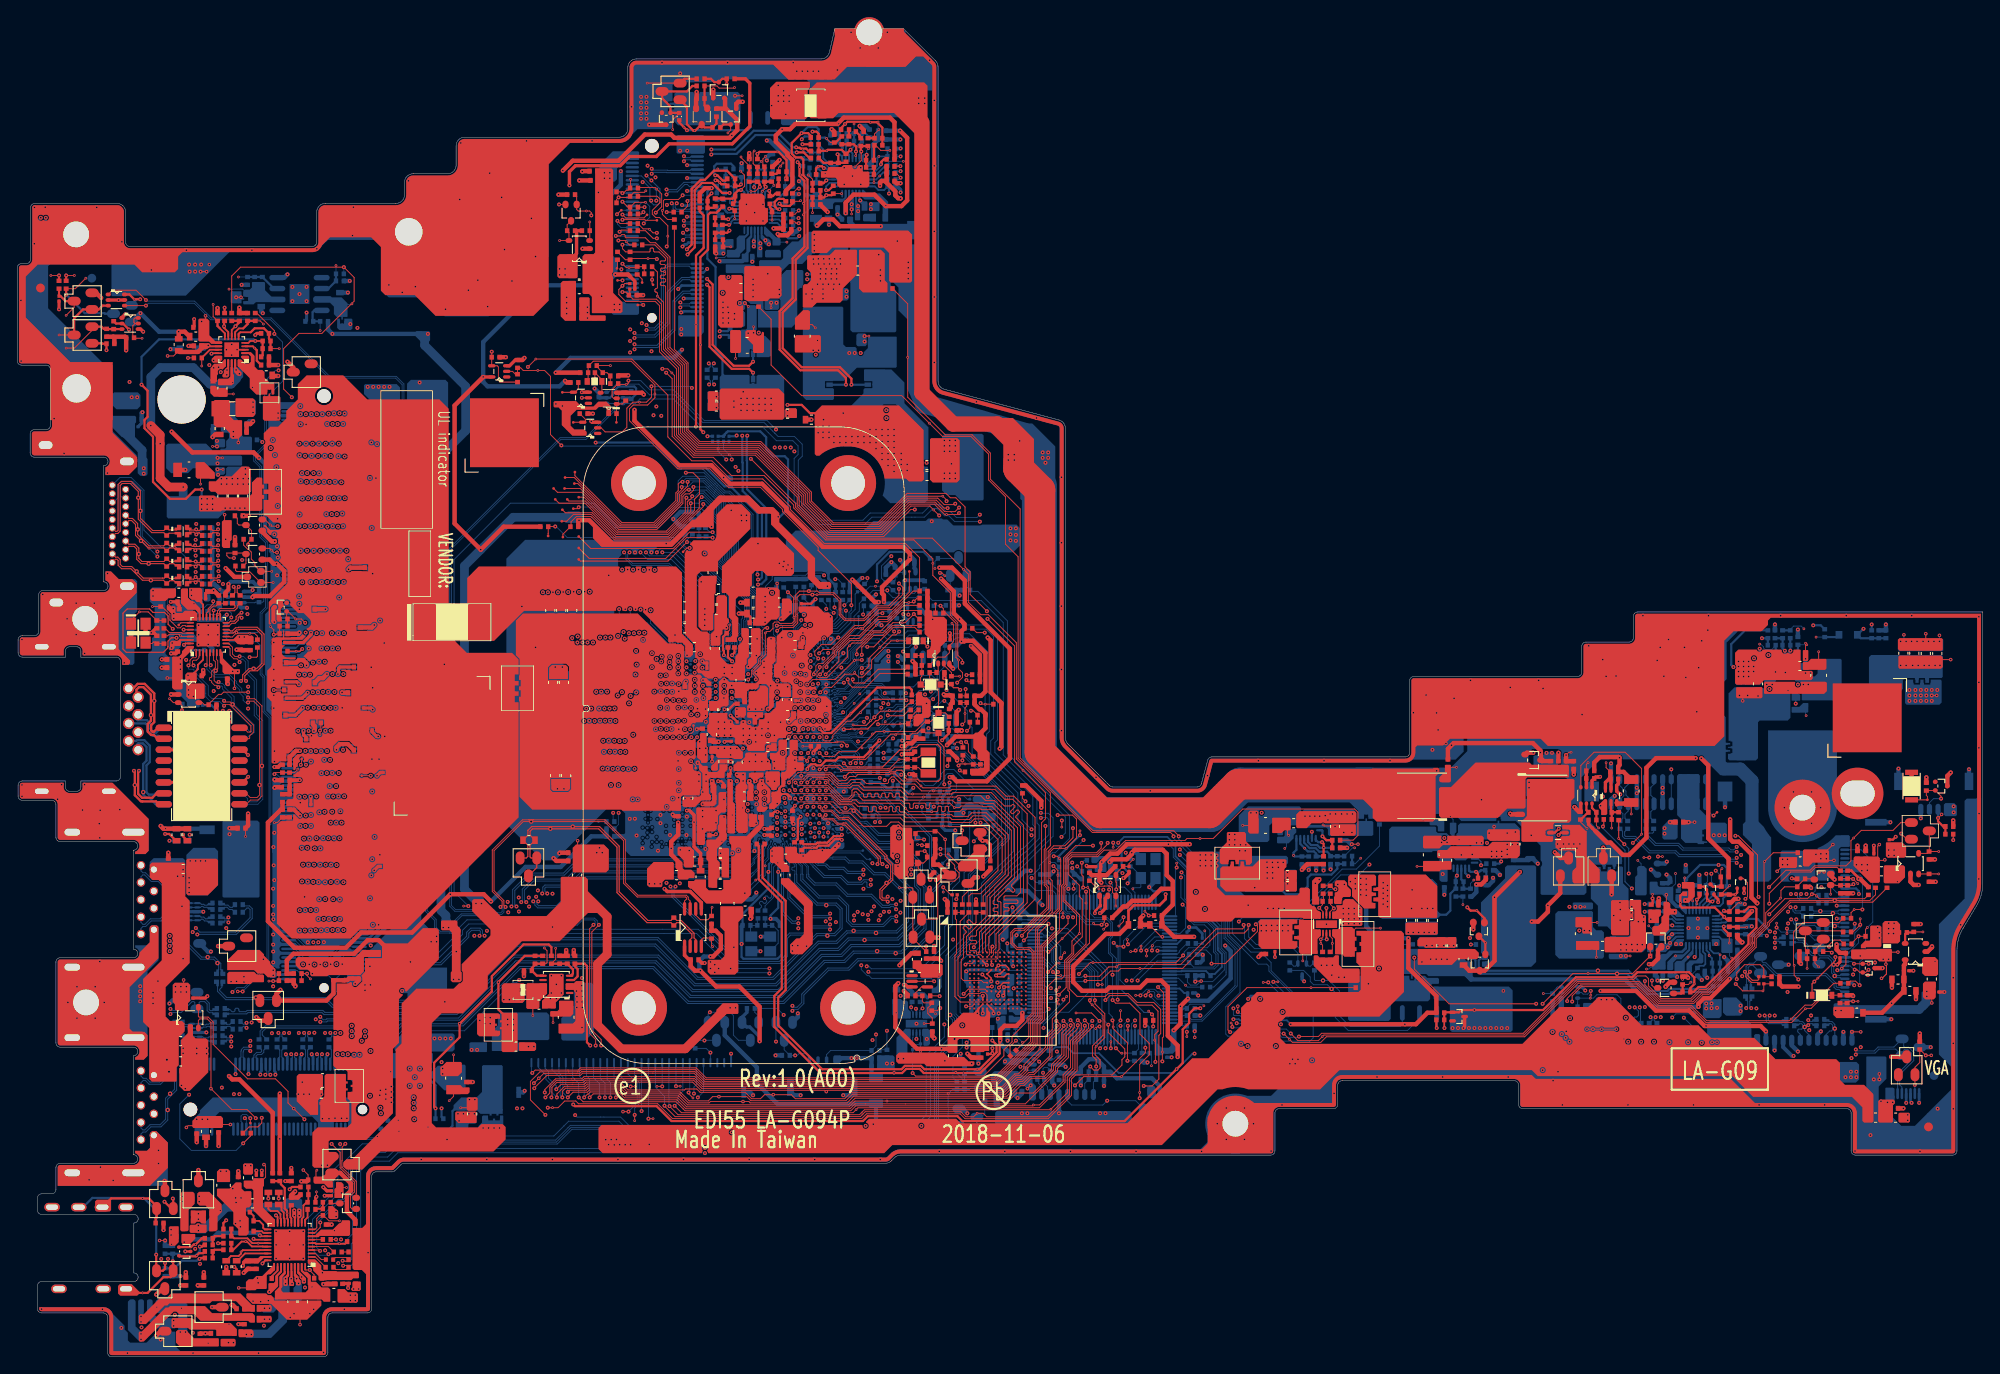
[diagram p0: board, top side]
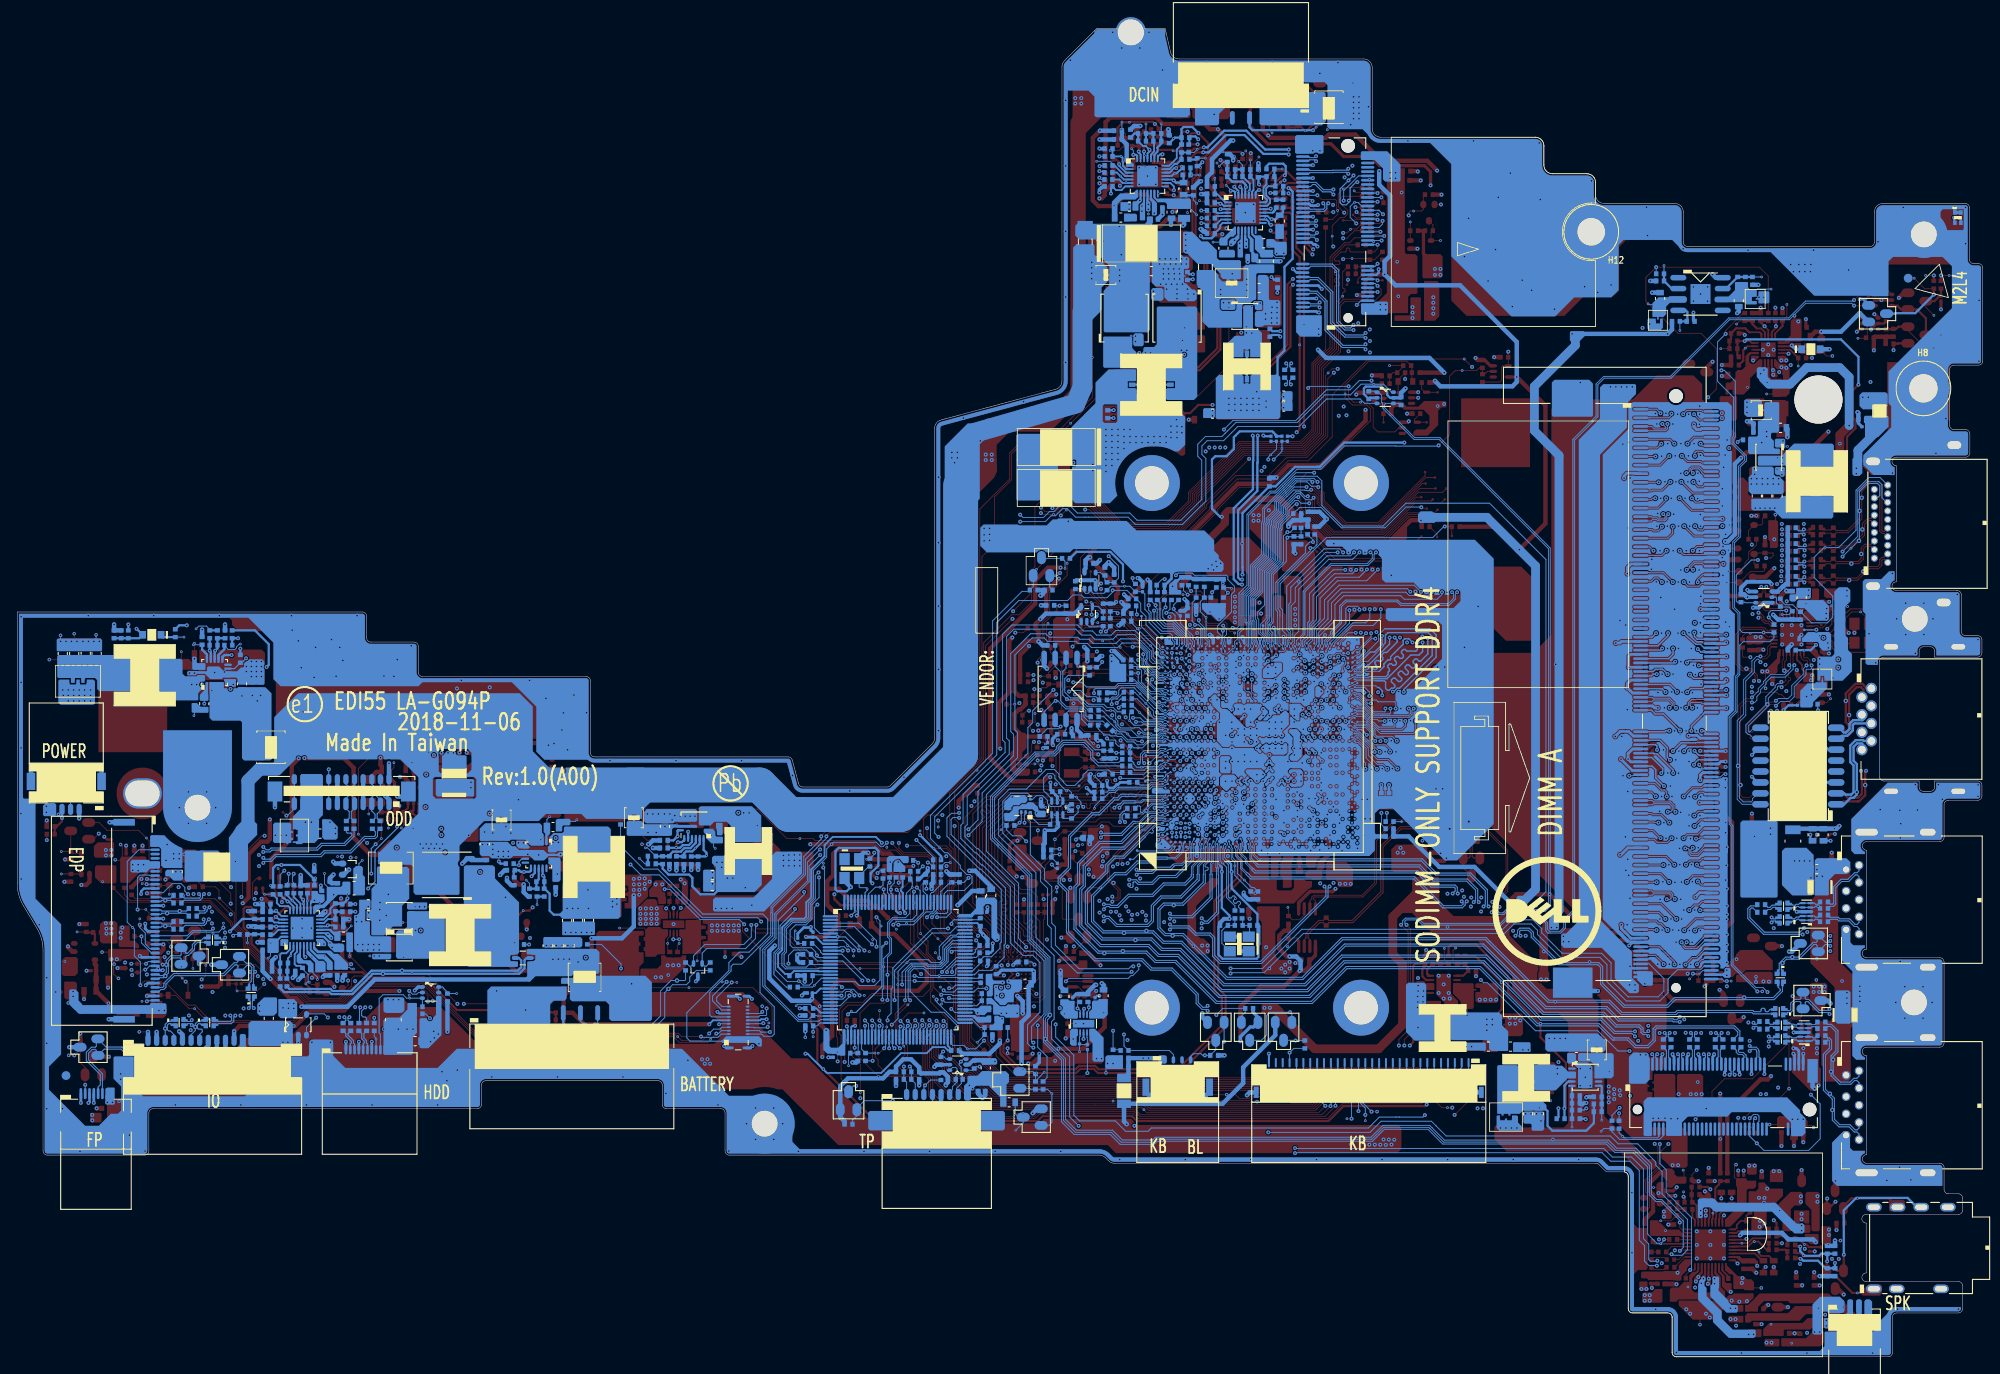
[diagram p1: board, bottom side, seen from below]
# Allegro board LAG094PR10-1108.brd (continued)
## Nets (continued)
+1.8VS: QA2.3 RA35.1 RA36.1 RA65.1
+1.24VALW: CC39.2 CC40.2 CC41.2 PJP1202.2 RC125.1 UC1.AC18 UC1.AC20
+1.24VALW_PG: PR1201.2 PU1201.4 RE8.1
+1.24VALWP: PC1201.1 PC1202.1 PC1203.1 PC1206.1 PJP1202.1 PL1201.2 PR1204.1
+2.5V_MEM: CD1.1 CD2.1 CD3.1 CD4.1 DD2.2 JDIMM1.257 JDIMM1.259 PJP2502.2
+2.5VP: PC2502.1 PC2505.1 PJP2502.1 PR2502.1 PU2501.6
+3.3V_WLAN: CW6.1 CW7.1 CW8.1 CW9.1 JWLAN1.2 JWLAN1.4 JWLAN1.72 JWLAN1.74 RW1.2 RW2.1 RW27.2 RW28.2 UW1.1
+3V_DVDD: CA44.1 CA48.1 CA483.1 CA485.1 RA8.1 RA33.2 RA40.2 UA1.1
+3V_EMMC: CM1.1 CM2.1 CM7.1 CM9.1 RM1.2 RM29.2 RM32.1 UM1.E6 UM1.F5 UM1.J10 UM1.K9 UM2.5
+3VALW: C235.1 CC5.1 CL9.1 JDB1.11 JP11.2 JPWR1.4 PJP302.2 PJP1201.1 PJP1801.1 PJP2501.1 PL1211.1 PL1811.1 PR5.2 PR33.1 PR41.2 PR1201.1 PR1803.1 PRB42.1 PRG34.2 PRH03.1 PRH05.1 PRM06.1 PRZ34.2 Q17.2 Q17.5 R35.1 RA41.2 RC55.2 RC120.2 RC122.1 RC138.2 RC165.1 RC166.1 RC167.1 RC168.1 RC169.1 RC170.1 RC175.1 RC176.1 RC213.2 RE4.2 RE30.1 RL7.1 RM1.1 RM30.1 RW1.1 RW5.1 RW6.1 U11.6 U11.7 UC3.5 UL2.5 UM3.1 UM3.2 UW1.5
+3VALW_1.8V: PC1801.1 PJP1801.2 PL1811.2 PU1801.8 PU1801.9 PU1801.10
+3VALW_1.24V: PC1204.1 PJP1201.2 PL1211.2 PU1201.8 PU1201.9 PU1201.10
+3VALW_2.5V: PC2501.1 PJP2501.2 PU2501.3
+3VALW_EC: CE10.1 CE11.1 CE12.1 CE13.1 LE1.1 PR9.1 RE1.2 RE4.1 RE12.1 RE14.2 RE25.2 RE28.2 RE32.2 RE34.2 RE36.1 RE37.1 RE41.2 RE43.1 UE1.9 UE1.22 UE1.33 UE1.96 YE1.4
+3VALW_SOC: CC81.2 CC82.2 CC83.2 CC84.2 CC85.2 CC86.1 RC43.2 RC45.2 RC46.2 RC89.2 RC90.2 RC122.2 RC142.1 RC145.1 UC1.AG21 UC1.AJ21 UC1.T18 UC1.T20 UC1.U17 UC1.V18 UC1.V20 UC1.Y18 UC1.Y20 UC5.5 UC6.5 UC7.5
+3VALWP: PC310.1 PC311.1 PC312.1 PC313.1 PC314.1 PC316.1 PJP302.1 PL301.2 PR304.1 PR306.2 PR307.1 PR504.1 PU301.14
+3VLP: CE35.2 DC1.2 PC308.1 PU301.16 PU301.17 RE40.1 RE43.2 RE53.1 RE54.2 RE55.2 U15.5
+3VS: C17.1 C21.1 C232.1 C233.1 CC4.1 CD9.1 CD10.1 CS114.1 CS115.1 CW4.1 CW5.1 CW10.1 F5.1 JDIMM1.255 JIOB1.12 JP10.2 JP33.2 Q6.2 Q10.2 Q10.5 Q11.2 Q11.5 Q57.2 Q58.2 QA2.2 QC2.2 QC2.5 QG1.5 R5.1 R7.1 R24.1 R28.1 R29.1 R33.1 R34.1 R36.1 R48.1 R49.1 R57.1 R79.1 R80.1 R86.1 R87.1 R100.1 R5216.1 R5220.1 R5221.1 RA33.1 RC2.2 RC3.2 RC4.2 RC83.1 RC84.1 RC117.1 RC119.2 RC121.2 RC203.1 RC1146.1 RC1148.1 RC1151.2 RD1.1 RD2.1 RD3.1 RE38.1 RE39.1 RG47.1 RL3.1 RM29.1 RS62.1 RT31.2 RW2.2 U1.5 U2.1 UC2.5 US2.2 US2.3 US2.9 US2.10
+3VS_CAM: C14.1 C15.1 C49.1 F5.2 JEDP1.29 R83.1
+3VS_OUT: C981.1 JP33.1 U11.8 U11.9
+3VS_SSD: CS38.1 CS39.1 CS40.1 CS41.1 CS42.1 CS43.1 CS44.1 JP10.1 JSSD1.2 JSSD1.4 JSSD1.12 JSSD1.14 JSSD1.16 JSSD1.18 JSSD1.70 JSSD1.72 JSSD1.74
+5V_AVDD: CA45.1 CA49.1 CA475.1 CA481.1 RA34.2 UA1.20
+5V_HDD: CS12.1 CS13.1 CS14.1 JHDD1.10 JHDD1.11 JHDD1.12 RB9.2 RS32.2 RS63.1
+5V_HDMI: CG46.1 CG47.1 DI1.1 FI1.1 JHDMI1.18
+5V_KB_BL: C34.1 EC3002.1 F3.1 JKBBL1.1
+5V_PVDD: CA2.1 CA3.1 CA43.1 CA47.1 CA474.1 CA494.1 RA1.2 UA1.34 UA1.39
+5VALW: C234.1 CU21.1 CU31.1 PCG01.1 PCZ14.1 PD2.3 PD3.3 PJP502.2 PR4.1 PR2504.1 PRG33.2 PRH11.1 PRM04.1 PRM05.2 PRZ33.2 PUG1.12 PUZ1.12 Q19.3 Q5029.3 U11.1 U11.2 U11.4 UM3.4 UU2.5 UU3.5
+5VALW_VDD: PC2504.1 PR2504.2 PU2501.4
+5VALWP: PC510.1 PC511.1 PC512.1 PC513.1 PC514.1 PC518.1 PC519.1 PC520.1 PJP502.1 PL501.2 PR509.2 PR510.1 PU501.14
+5VS: C225.1 C231.1 F3.2 FI1.2 JP5.1 JP50.2 Q7.3 R4.1 R5222.1 RA1.1 RA34.1 RB8.2 RS32.1
+5VS_ODD: CS26.1 CS109.1 CS112.1 JODD1.17 JODD1.18 JODD1.19 JODD1.20 JODD1.21 JODD1.22 JP5.2
+5VS_OUT: C982.1 JP50.1 U11.13 U11.14
+17.4V_BATT: PCB28.2 PD14.2 PLB01.2 PQB13.1 PQB13.2 PQB13.3 PRB01.1 RB6.1
+17.4V_BATT+: PC11.1 PCB30.1 PCB31.1 PCB32.1 PCB33.1 PCB34.1 PCB35.1 PJP3.1 PL4.1 PQB28.3 PRB01.4 PRB35.1 PRB41.1 RB5.1
+17.4V_BATT++: PBATT1.8 PBATT1.9 PBATT1.10 PC12.1 PJP3.2 PL4.2
+19V_ADPIN: PC1.1 PC2.1 PC15.1 PJP1.1 PJPDC1.5 PJPDC1.6 PL1.1
+19V_VIN: PC3.1 PC4.1 PDB01.2 PJP1.2 PL1.2 PQB11.5 PR32.1 PR34.1 PR36.1 PRB09.1
+19VB: F1.1 PD14.3 PDB13.2 PJP301.1 PJP501.1 PJPB01.1 PJPG1.1 PJPH01.1 PJPM01.1 PJPZ1.1 PL311.1 PL511.1 PLB02.1 PLG11.1 PLH11.1 PLM11.1 PLZ11.1 PQB13.5 PR302.2 PRB02.4 PRG46.1 PRG46.2 PRM12.1 PRM12.2 PRZ45.1 PRZ45.2 RB12.2
+19VB_1.2V: PCM01.1 PCM02.1 PCM03.1 PCM04.1 PCM22.1 PCM23.1 PJPM01.2 PLM11.2 PQM01.2 PQM01.3 PQM01.4 PQM01.10 PRM07.1 PRM12.3 PRM12.4 RB10.2
+19VB_1.05V: PCH01.1 PCH02.1 PCH03.1 PCH04.1 PCH15.1 PCH16.1 PJPH01.2 PLH11.2 PUH01.5
+19VB_3V: PC301.1 PC302.1 PC303.1 PC304.1 PC305.1 PC306.1 PJP301.2 PL311.2 PU301.2 PU301.3 PU301.4 PU301.5
+19VB_5V: PC501.1 PC502.1 PC503.1 PC504.1 PC505.1 PC506.1 PJP501.2 PL511.2 PU501.2 PU501.3 PU501.4 PU501.5
+19VB_CHG: PCB20.1 PCB21.1 PCB22.1 PCB23.1 PCB24.1 PCB25.1 PCB26.1 PCB27.1 PDB13.3 PJPB01.2 PLB02.2 PQB26.5
+19VB_DB: JDB1.1 JDB1.2 JDB1.15 JDB1.16 RB12.1
+19VB_VCCGI: PCG15.1 PCG16.1 PCG18.1 PCG19.1 PCG20.1 PCG124.1 PCG125.1 PJPG1.2 PLG11.2 PQG1.5 PRG31.1 PRG46.3 PRG46.4 RB4.1
+19VB_VNN: PCG126.1 PCG127.1 PCZ01.1 PCZ02.1 PCZ06.1 PCZ07.1 PJPZ1.2 PLZ11.2 PQZ1.2 PQZ1.3 PQZ1.4 PQZ1.10 PRZ25.1 PRZ45.3 PRZ45.4 RB7.2
+VCC0: CE36.1 RE40.2 U15.1 UE1.111
+VCC_IO2: RE12.2 RE13.2 UE1.124
+VCC_SPI: CC91.1 RC34.2 UC11.8
+VCC_VCCGI: PCG06.1 PRG33.1 PUG1.1
+VCC_VCGI: PCG100.1 PCG101.1 PCG102.1 PCG103.1 PCG104.1 PCG105.1 PCG106.1 PCG107.1 PCG108.1 PCG109.1 PCG110.1 PCG111.1 PCG112.1 PCG113.1 PCG114.1 PCG115.1 PCG116.1 PCG117.1 PCG118.1 PCG119.1 PCG120.1 PCG121.1 PCG122.1 PCG123.1 PLG1.4 PRG19.2 UC1.AA28 UC1.AA29 UC1.AA31 UC1.AA33 UC1.AC28 UC1.AC31 UC1.AE28 UC1.AE29 UC1.AE31 UC1.AF31 UC1.AF33 UC1.AG31 UC1.AG33 UC1.AJ31 UC1.AJ33 UC1.AJ35 UC1.AL31 UC1.AL33 UC1.AL35 UC1.AM33 UC1.AM35 UC1.AM36 UC1.D31 UC1.D33 UC1.D37 UC1.D39 UC1.P39 UC1.P41 UC1.T28 UC1.T29 UC1.T31 UC1.T33 UC1.T35 UC1.T36 UC1.V28 UC1.V29 UC1.V31 UC1.V33 UC1.V35 UC1.V36 UC1.Y28 UC1.Y29 UC1.Y33 UC1.Y35
+VCCIOA: CC29.2 CC30.2 CC31.2 CC32.2 CC33.2 CC34.1 RC124.2 RC133.2 UC1.AP25 UC1.AP31 UC1.AT25 UC1.AT27 UC1.AT28 UC1.AT29 UC1.AT31
+VDD10: CL5.1 CL6.1 CL16.1 CL18.1 CL28.1 CL30.1 CL31.1 RL21.2 UL1.3 UL1.8 UL1.22 UL1.30
GND: C2.2 C3.2 C4.2 C5.2 C12.2 C14.2 C15.2 C16.2 C17.2 C19.2 C21.2 C26.2 C27.2 C34.2 C35.2 C37.2 C39.2 C41.2 C49.2 C225.2 C231.2 C232.2 C233.2 C234.2 C235.2 C967.1 C976.1 C979.1 C980.1 C981.2 C982.2 C983.1 CA2.2 CA3.2 CA25.2 CA27.2 CA28.2 CA43.2 CA44.2 CA45.2 CA46.2 CA47.2 CA48.2 CA49.2 CA50.2 CA51.2 CA52.2 CA53.2 CA474.2 CA476.2 CA477.2 CA480.2 CA483.2 CA484.1 CA485.2 CA486.2 CA487.1 CA490.2 CA491.2 CA492.2 CA493.1 CA494.2 CC1.1 CC2.2 CC3.2 CC4.2 CC5.2 CC6.2 CC7.2 CC8.2 CC9.2 CC10.2 CC11.1 CC12.1 CC13.2 CC14.2 CC15.2 CC16.1 CC17.1 CC22.2 CC23.1 CC24.1 CC25.1 CC26.1 CC27.1 CC28.1 CC29.1 CC30.1 CC31.1 CC32.1 CC33.1 CC34.2 CC35.1 CC36.1 CC37.1 CC38.2 CC39.1 CC40.1 CC41.1 CC42.1 CC43.1 CC44.1 CC45.1 CC46.2 CC47.1 CC48.1 CC49.1 CC50.2 CC51.2 CC52.2 CC53.1 CC54.1 CC55.1 CC56.1 CC57.1 CC58.2 CC59.1 CC60.1 CC61.1 CC62.1 CC63.1 CC64.1 CC65.1 CC66.1 CC67.1 CC68.1 CC69.1 CC70.1 CC71.1 CC73.1 CC74.1 CC75.1 CC76.1 CC77.1 CC78.1 CC79.1 CC80.1 CC81.1 CC82.1 CC83.1 CC84.1 CC85.1 CC86.2 CC88.2 CC89.1 CC90.1 CC91.2 CC92.1 CC93.1 CC95.2 CC96.1 CC272.1 CD1.2 CD2.2 CD3.2 CD4.2 CD5.2 CD6.2 CD7.2 CD8.2 CD9.2 CD10.2 CD11.2 CD12.2 CD13.2 CD14.2 CD15.2 CD16.2 CD17.2 CD18.2 CD19.2 CD20.2 CD21.2 CD22.2 CD23.2 CD24.2 CD25.2 CD26.2 CD27.2 CD28.2 CD29.2 CD31.2 CD32.2 CD33.2 CE1.2 CE2.2 CE3.2 CE4.2 CE5.2 CE6.2 CE7.2 CE8.2 CE9.2 CE10.2 CE11.2 CE12.2 CE13.2 CE18.2 CE19.2 CE20.1 CE21.1 CE23.1 CE35.1 CE36.2 CE37.1 CG46.2 CG47.2 CL5.2 CL6.2 CL7.2 CL8.2 CL9.2 CL10.1 CL11.1 CL12.2 CL13.2 CL16.2 CL18.2 CL24.2 CL25.2 CL28.2 CL29.2 CL30.2 CL31.2 CL32.2 CLRP1.1 CLRP2.1 CM1.2 CM2.2 CM3.2 CM4.2 CM5.2 CM6.2 CM7.2 CM8.1 CM9.2 CM10.2 CM11.2 CM17.2 CM26.2 CM27.2 CM28.2 CM29.2 CM30.2 CS12.2 CS13.2 CS14.2 CS26.2 CS38.2 CS39.2 CS40.2 CS41.2 CS42.2 CS43.2 CS44.2 CS109.2 CS112.2 CS114.2 CS115.2 CT14.2 CU17.2 CU18.2 CU19.2 CU20.2 CU21.2 CU22.2 CU25.2 CU26.2 CU28.2 CU31.2 CU32.2 CW1.2 CW4.2 CW5.2 CW6.2 CW7.2 CW8.2 CW9.2 CW10.2 D11.1 D12.1 D14.1 DA1.1 DA2.1 DA5.1 DA6.1 DA8.1 DA9.1 DC6.1 DD1.1 DD2.1 DE1.1 EC2901.2 EC2902.2 EC3001.2 EC3002.2 ED2901.1 EU2605.3 EU2606.3 EU2607.1 EU2608.1 EU2701.1 EU4012.1 H1.1(TP-1) H2.1(TP-1) H4.1(TP-1) H5.1(TP-1) H6.1(TP-1) H7.1(TP-1) H8.1(TP-1) H12.1(TP-1) H13.1(TP-1) HCPU1.1(TP-1) HCPU2.1(TP-1) HCPU3.1(TP-1) HCPU4.1(TP-1) JDB1.12 JDB1.21 JDB1.22 JDB1.23 JDB1.24 JDIMM1.1 JDIMM1.2 JDIMM1.5 JDIMM1.6 JDIMM1.9 JDIMM1.10 JDIMM1.14 JDIMM1.15 JDIMM1.18 JDIMM1.19 JDIMM1.22 JDIMM1.23 JDIMM1.26 JDIMM1.27 JDIMM1.30 JDIMM1.31 JDIMM1.35 JDIMM1.36 JDIMM1.39 JDIMM1.40 JDIMM1.43 JDIMM1.44 JDIMM1.47 JDIMM1.48 JDIMM1.51 JDIMM1.52 JDIMM1.56 JDIMM1.57 JDIMM1.60 JDIMM1.61 JDIMM1.64 JDIMM1.65 JDIMM1.68 JDIMM1.69 JDIMM1.72 JDIMM1.73 JDIMM1.77 JDIMM1.78 JDIMM1.81 JDIMM1.82 JDIMM1.85 JDIMM1.86 JDIMM1.89 JDIMM1.90 JDIMM1.93 JDIMM1.94 JDIMM1.98 JDIMM1.99 JDIMM1.102 JDIMM1.103 JDIMM1.106 JDIMM1.107 JDIMM1.167 JDIMM1.168 JDIMM1.171 JDIMM1.172 JDIMM1.175 JDIMM1.176 JDIMM1.180 JDIMM1.181 JDIMM1.184 JDIMM1.185 JDIMM1.188 JDIMM1.189 JDIMM1.192 JDIMM1.193 JDIMM1.196 JDIMM1.197 JDIMM1.201 JDIMM1.202 JDIMM1.205 JDIMM1.206 JDIMM1.209 JDIMM1.210 JDIMM1.213 JDIMM1.214 JDIMM1.217 JDIMM1.218 JDIMM1.222 JDIMM1.223 JDIMM1.226 JDIMM1.227 JDIMM1.230 JDIMM1.231 JDIMM1.234 JDIMM1.235 JDIMM1.238 JDIMM1.239 JDIMM1.243 JDIMM1.244 JDIMM1.247 JDIMM1.248 JDIMM1.251 JDIMM1.252 JDIMM1.261 JDIMM1.262 JEDP1.13 JEDP1.17 JEDP1.20 JEDP1.23 JEDP1.32 JEDP1.35 JEDP1.38 JEDP1.41 JEDP1.42 JFP1.1 JFP1.3 JFP1.4 JFP1.9 JFP1.10 JHDD1.1 JHDD1.4 JHDD1.7 JHDD1.13 JHDD1.14 JHDMI1.2 JHDMI1.5 JHDMI1.8 JHDMI1.11 JHDMI1.17 JHDMI1.20 JHDMI1.21 JHDMI1.22 JHDMI1.23 JIOB1.1 JIOB1.2 JIOB1.5 JIOB1.8 JIOB1.9 JIOB1.10 JIOB1.17 JIOB1.18 JKB1.30 JKB1.31 JKB1.32 JKBBL1.5 JKBBL1.6 JODD1.1 JODD1.2 JODD1.7 JODD1.8 JODD1.13 JODD1.14 JODD1.25 JODD1.26 JPWR1.1 JPWR1.5 JPWR1.6 JRJ45.9 JRJ45.10 JRJ45.11 JRJ45.12 JSPK1.5 JSPK1.6 JSSD1.1 JSSD1.3 JSSD1.9 JSSD1.15 JSSD1.21 JSSD1.27 JSSD1.33 JSSD1.39 JSSD1.45 JSSD1.51 JSSD1.57 JSSD1.71 JSSD1.73 JSSD1.75 JSSD1.76 JSSD1.77 JTP1.5 JTP1.9 JTP1.10 JUSB1.4 JUSB1.7 JUSB1.10 JUSB1.11 JUSB1.12 JUSB1.13 JUSB2.4 JUSB2.7 JUSB2.10 JUSB2.11 JUSB2.12 JUSB2.13 JWLAN1.1 JWLAN1.7 JWLAN1.13 JWLAN1.18 JWLAN1.19 JWLAN1.33 JWLAN1.39 JWLAN1.45 JWLAN1.51 JWLAN1.57 JWLAN1.63 JWLAN1.69 JWLAN1.75 JWLAN1.76 JWLAN1.77 LE2.2 LED1.1 LED1.3 PBATT1.1 PBATT1.2 PBATT1.3 PBATT1.4 PBATT1.11 PBATT1.12 PC1.2 PC2.2 PC3.2 PC4.2 PC11.2 PC12.2 PC15.2 PC301.2 PC302.2 PC303.2 PC304.2 PC305.2 PC306.2 PC308.2 PC309.2 PC310.2 PC311.2 PC312.2 PC313.2 PC314.2 PC316.2 PC317.2 PC501.2 PC502.2 PC503.2 PC504.2 PC505.2 PC506.2 PC508.2 PC509.2 PC510.2 PC511.2 PC512.2 PC513.2 PC514.2 PC515.2 PC516.1 PC518.2 PC519.2 PC520.2 PC1201.2 PC1202.2 PC1203.2 PC1204.2 PC1205.2 PC1207.2 PC1801.2 PC1802.2 PC1803.2 PC1804.2 PC1805.2 PC1806.2 PC2501.2 PC2502.2 PC2503.2 PC2504.2 PCB02.2 PCB04.2 PCB05.2 PCB07.1 PCB08.1 PCB09.2 PCB10.2 PCB11.2 PCB12.2 PCB13.2 PCB14.2 PCB16.2 PCB17.2 PCB19.2 PCB20.2 PCB21.2 PCB22.2 PCB23.2 PCB24.2 PCB25.2 PCB26.2 PCB27.2 PCB29.2 PCB30.2 PCB31.2 PCB32.2 PCB33.2 PCB34.2 PCB35.2 PCB36.2 PCB37.1 PCB70.2 PCG01.2 PCG02.1 PCG03.2 PCG05.2 PCG06.2 PCG07.1 PCG08.2 PCG09.2 PCG10.1 PCG15.2 PCG16.2 PCG17.2 PCG18.2 PCG19.2 PCG20.2 PCG100.2 PCG101.2 PCG102.2 PCG103.2 PCG104.2 PCG105.2 PCG106.2 PCG107.2 PCG108.2 PCG109.2 PCG110.2 PCG111.2 PCG112.2 PCG113.2 PCG114.2 PCG115.2 PCG116.2 PCG117.2 PCG118.2 PCG119.2 PCG120.2 PCG121.2 PCG122.2 PCG123.2 PCG124.2 PCG125.2 PCG126.2 PCG127.2 PCH01.2 PCH02.2 PCH03.2 PCH04.2 PCH05.2 PCH06.2 PCH07.2 PCH08.2 PCH09.2 PCH10.2 PCH11.2 PCH13.2 PCH15.2 PCH16.2 PCM01.2 PCM02.2 PCM03.2 PCM04.2 PCM05.2 PCM06.2 PCM07.2 PCM08.2 PCM09.2 PCM10.2 PCM11.2 PCM13.2 PCM14.2 PCM15.2 PCM16.2 PCM18.2 PCM19.2 PCM20.2 PCM22.2 PCM23.2 PCZ01.2 PCZ02.2 PCZ03.2 PCZ06.2 PCZ07.2 PCZ08.1 PCZ10.1 PCZ12.2 PCZ13.1 PCZ14.2 PCZ15.2 PCZ16.2 PCZ17.2 PCZ19.2 PCZ100.2 PCZ101.2 PCZ102.2 PCZ103.2 PCZ104.2 PCZ105.2 PCZ106.2 PCZ107.2 PCZ108.2 PCZ109.2 PCZ110.2 PCZ111.2 PCZ112.2 PCZ113.2 PCZ114.2 PCZ115.2 PCZ116.2 PCZ117.2 PCZ118.2 PCZ119.2 PD1.1 PD2.2 PD3.2 PD5.1 PD6.1 PD14.1 PD502.2 PDB13.1 PJP2.2 PJPDC1.7 PJPDC1.8 PL2.2 PQ2.3 PQ11.3 PQ12.1 PQ12.4 PQ13.1 PQ13.4 PQB25.1 PQB25.2 PQB25.3 PQB29.3 PQB31.3 PQB32.3 PQB33.3 PQG2.1 PQG2.2 PQG2.3 PQM01.5 PQM01.6 PQM01.7 PQZ1.5 PQZ1.6 PQZ1.7 PR6.2 PR38.2 PR40.2 PR43.2 PR44.1 PR45.2 PR303.2 PR308.2 PR508.2 PR511.2 PR1202.2 PR1206.2 PR1802.2 PR1805.2 PR2503.2 PRB04.2 PRB10.2 PRB13.1 PRB16.2 PRB17.1 PRB23.2 PRB26.2 PRB28.1 PRB38.2 PRB45.2 PRG16.2 PRG32.2 PRG35.2 PRG36.2 PRG37.2 PRG38.2 PRH02.2 PRH04.2 PRH09.2 PRM11.2 PRZ18.2 PRZ32.2 PRZ35.2 PRZ36.2 PRZ37.2 PRZ38.2 PU301.7 PU301.8 PU301.18 PU301.21 PU501.7 PU501.8 PU501.18 PU501.21 PU1201.11 PU1801.11 PU2501.8 PU2501.9 PUB01.33 PUG1.29 PUH01.4 PUH01.8 PUM01.1 PUM01.3 PUM01.14 PUM01.21 PUZ1.29 Q8.3 Q13.3 Q25.1 Q25.4 Q5027.3 QC1.3 QC9.3 QC10.3 QG1.1 QG1.4 QS1.1 QS1.4 R10.2 R27.2 R40.2 R72.2 R5217.1 R5218.1 RA32.1 RA38.2 RA39.2 RA48.2 RA63.2 RC10.2 RC11.2 RC12.2 RC17.1 RC18.1 RC25.2 RC33.1 RC38.1 RC39.2 RC50.2 RC51.2 RC56.1 RC57.2 RC58.2 RC62.2 RC64.2 RC75.2 RC76.2 RC77.2 RC78.1 RC82.2 RC85.2 RC86.2 RC91.1 RC92.2 RC94.2 RC96.2 RC98.2 RC100.2 RC102.2 RC103.2 RC105.2 RC107.1 RC108.1 RC115.2 RC116.2 RC158.1 RC159.1 RC160.1 RC172.2 RC174.2 RC1152.2 RD4.2 RD5.2 RD6.2 RD11.2 RD12.2 RD36.2 RE15.1 RE27.1 RE29.2 RE35.2 RG56.2 RL2.1 RL4.2 RL6.1 RM12.1 RM13.1 RT29.2 RW11.2 RW26.2 SW1.2 U1.2 U2.5 U11.11 U11.15 U14.2 U15.2 UA1.41 UC1.A3 UC1.A6 UC1.A12 UC1.A16 UC1.A20 UC1.A24 UC1.A28 UC1.A32 UC1.A36 UC1.A40 UC1.A44 UC1.A48 UC1.A51 UC1.AA12 UC1.AA13 UC1.AA15 UC1.AA17 UC1.AA21 UC1.AA23 UC1.AA25 UC1.AA27 UC1.AA35 UC1.AA43 UC1.AA48 UC1.AB1 UC1.AB3 UC1.AB55 UC1.AC8 UC1.AC13 UC1.AC23 UC1.AC25 UC1.AC27 UC1.AC29 UC1.AE18 UC1.AE23 UC1.AE25 UC1.AE27 UC1.AE43 UC1.AE48 UC1.AF1 UC1.AF3 UC1.AF4 UC1.AF6 UC1.AF8 UC1.AF9 UC1.AF11 UC1.AF12 UC1.AF14 UC1.AF16 UC1.AF18 UC1.AF23 UC1.AF25 UC1.AF29 UC1.AF40 UC1.AF42 UC1.AF44 UC1.AF45 UC1.AF47 UC1.AF48 UC1.AF50 UC1.AF52 UC1.AF53 UC1.AF55 UC1.AG20 UC1.AG25 UC1.AG29 UC1.AG35 UC1.AG38 UC1.AJ8 UC1.AJ13 UC1.AJ18 UC1.AJ25 UC1.AJ29 UC1.AJ36 UC1.AJ38 UC1.AJ39 UC1.AJ44 UC1.AK1 UC1.AK3 UC1.AK55 UC1.AL3 UC1.AL7 UC1.AL8 UC1.AL10 UC1.AL12 UC1.AL13 UC1.AL15 UC1.AL17 UC1.AL20 UC1.AL21 UC1.AL23 UC1.AL25 UC1.AL29 UC1.AL39 UC1.AL41 UC1.AL43 UC1.AL44 UC1.AL46 UC1.AL51 UC1.AM1 UC1.AM21 UC1.AM23 UC1.AM25 UC1.AM29 UC1.AM31 UC1.AM38 UC1.AM55 UC1.AN3 UC1.AN8 UC1.AN10 UC1.AN46 UC1.AN48 UC1.AN49 UC1.AN51 UC1.AN53 UC1.AP23 UC1.AP27 UC1.AP28 UC1.AP29 UC1.AP33 UC1.AP35 UC1.AR2 UC1.AR7 UC1.AR10 UC1.AR12 UC1.AR17 UC1.AR39 UC1.AR44 UC1.AR46 UC1.AR49 UC1.AR54 UC1.AT23 UC1.AT33 UC1.AU3 UC1.AU10 UC1.AU28 UC1.AU46 UC1.AU53 UC1.AV15 UC1.AV17 UC1.AV23 UC1.AV25 UC1.AV31 UC1.AV33 UC1.AV39 UC1.AV41 UC1.AW2 UC1.AW5 UC1.AW10 UC1.AW28 UC1.AW46 UC1.AW51 UC1.AW54 UC1.AY13 UC1.AY15 UC1.AY28 UC1.AY41 UC1.AY43 UC1.B2 UC1.B55 UC1.BA27 UC1.BA29 UC1.BB1 UC1.BB28 UC1.BB55 UC1.BC5 UC1.BC11 UC1.BC17 UC1.BC19 UC1.BC21 UC1.BC23 UC1.BC25 UC1.BC31 UC1.BC33 UC1.BC35 UC1.BC37 UC1.BC39 UC1.BC41 UC1.BC45 UC1.BC51 UC1.BD9 UC1.BD15 UC1.BD19 UC1.BD21 UC1.BD28 UC1.BD35 UC1.BD37 UC1.BD47 UC1.BE3 UC1.BE28 UC1.BE53 UC1.BF9 UC1.BF19 UC1.BF37 UC1.BF47 UC1.BG1 UC1.BG6 UC1.BG28 UC1.BG50 UC1.BG55 UC1.BH11 UC1.BH13 UC1.BH17 UC1.BH19 UC1.BH23 UC1.BH25 UC1.BH28 UC1.BH31 UC1.BH33 UC1.BH37 UC1.BH39 UC1.BH41 UC1.BH45 UC1.BJ2 UC1.BJ15 UC1.BJ19 UC1.BJ25 UC1.BJ28 UC1.BJ31 UC1.BJ37 UC1.BJ41 UC1.BJ54 UC1.BK1 UC1.BK17 UC1.BK21 UC1.BK35 UC1.BK39 UC1.BK55 UC1.BL5 UC1.BL8 UC1.BL10 UC1.BL14 UC1.BL24 UC1.BL28 UC1.BL32 UC1.BL42 UC1.BL46 UC1.BL48 UC1.BL51 UC1.C1 UC1.C12 UC1.C16 UC1.C28 UC1.C36 UC1.D6 UC1.D9 UC1.D21 UC1.D28 UC1.D41 UC1.D45 UC1.D55 UC1.E28 UC1.E50 UC1.E55 UC1.F1 UC1.F4 UC1.F21 UC1.F31 UC1.G28 UC1.H13 UC1.H15 UC1.H21 UC1.H23 UC1.H28 UC1.H33 UC1.H39 UC1.J8 UC1.J27 UC1.J33 UC1.J41 UC1.J45 UC1.J51 UC1.K1 UC1.K3 UC1.K28 UC1.K55 UC1.L5 UC1.L7 UC1.L8 UC1.L19 UC1.L33 UC1.M15 UC1.M25 UC1.M28 UC1.M35 UC1.M41 UC1.N12 UC1.N28 UC1.N46 UC1.N51 UC1.P21 UC1.P55 UC1.R8 UC1.R28 UC1.T3 UC1.T27 UC1.T38 UC1.U3 UC1.U13 UC1.V27 UC1.V38 UC1.V55 UC1.W2 UC1.W3 UC1.W5 UC1.W7 UC1.W8 UC1.W10 UC1.W39 UC1.W41 UC1.W43 UC1.W44 UC1.W46 UC1.W48 UC1.W49 UC1.W51 UC1.Y21 UC1.Y23 UC1.Y25 UC1.Y27 UC1.Y31 UC2.3 UC3.3 UC5.3 UC6.3 UC7.3 UC8.3 UC11.4 UC12.3 UE1.11 UE1.24 UE1.35 UE1.94 UE1.113 UL1.33 UL2.2 UM1.A6 UM1.C4 UM1.E7 UM1.E9 UM1.E10 UM1.F10 UM1.G5 UM1.H10 UM1.J5 UM1.K8 UM1.N2 UM1.N5 UM1.P4 UM1.P6 UM2.3 UM3.11 UM3.15 US2.5 US2.6 US2.7 US2.8 UU2.2 UU3.2 UW1.2 YC1.2 YC1.4 YE1.2 YL2.2 YL2.4
GNDA: CA26.2 CA51.1 CA52.1 CA53.1 CA475.2 CA479.1 CA481.2 CA482.1 CA488.2 CA489.2 CA495.1 CA497.2 CA498.2 CA499.2 CA501.2 CA502.2 CA504.2 JHP1.7 RA38.1 RA39.1 RA47.1 RA54.2 RA57.2 RA62.1 RA63.1 UA1.19 UA1.31
V3D3_STB: RA37.1 RA41.1 UA1.16
VBAT: PCB14.1 PRB35.2 PUB01.31
VCC_RTC_EXTPAD: CC88.1 UC1.J23
VCC_VCGI_SENSE_N: PRG42.1 UC1.AG39
VCC_VCGI_SENSE_P: PRG43.2 UC1.AG41
VCC_VGATE: CE7.1 PRG34.1 PUG1.7 UE1.17
VCCGI_EN: PRG41.2 UE1.68
VCCGI_N01: PRG15.2 PRG36.1
VCCGI_N02: PRG13.2 PRG37.1
VCCGI_N03: PRG14.2 PRG38.1
VCCGI_N04: PRG28.2 PRG39.1
VCCGI_N05: PHG1.2 PRG40.1
VCCGI_N06: PRG30.2 PRG35.1
VCCGI_N07: PCG10.2 PRG41.1 PUG1.2
VCCGI_N08: PRG01.2 PRG06.1
VCCGI_N09: PRG03.2 PRG08.1
VCCGI_N12: PHG1.1 PRG22.2 PRG23.1
VCCGI_N13: PRG02.2 PRG07.1
VCCGI_N14: PHZ2.2 PRG26.2 PRG27.2 PRG30.1
VCCGI_N16: PRG24.2 PRG26.1
VCCGI_N17: PLG1.2 PRG21.1
VCCGI_N18: PCG02.2 PRG31.2 PUG1.13
VCCGI_N19: PCG07.2 PRG29.1
VDD_1.2V: PCM14.1 PRM03.2 PRM04.2 PUM01.11
VDD_CHG: PCB08.2 PRB18.2 PRB25.1 PRB27.1 PRB39.2 PRB44.1 PUB01.18
VDDP_1.2V: PCM13.1 PD502.1 PRM05.1 PUM01.12
VDDP_CHG: PCB19.1 PRB39.1 PUB01.8
VDDREG: CL8.1 RL5.2 UL1.23
+DCBAT_LCD: C4.1 C5.1 JEDP1.1 JEDP1.2 JEDP1.3 R301.2 RB1.1
+EC_VCCA: CE16.1 LE1.2 UE1.67
+EMMC_VDDI: CM5.1 UM1.C2
+FP_VCC: C37.1 JFP1.7 JFP1.8 R4.2 R7.2
+LAN_VDD33: CL7.1 CL24.1 CL25.1 CL29.1 JP11.1 RL5.1 RL17.2 UL1.11 UL1.32 UL2.1
+LCDVDD: R3.2 RB2.1 U1.1
+LCDVDD_LCD: C2.1 C3.1 C12.1 JEDP1.7 JEDP1.8 R3.1 RB3.1
+LINE1_VREFO_L: DA10.1 UA1.24
+MIC2-VREFO: RA56.1 RA60.1 UA1.23
+MIC_VCC: C39.1 JEDP1.26 R83.2
+RTC_CELL: CC10.1 DC1.1 RA37.2 RC65.1 RC66.1 RC73.1 UC1.P15
+RTC_VCC: JIOB1.11 RC63.2
+TP_VDD: C19.1 JTP1.8 Q9.2 Q12.1 R31.1 R32.1 R36.2 R37.2 R39.1 R40.1 R41.1 R46.1 R47.1
+TPAN_VDD: C35.1 JEDP1.40 R13.2 R74.2
+TPAN_VDD_OUT: R74.1 U14.1
+TS_VDD_IN: C983.2 R13.1 R5221.2 R5222.2 U14.5
+V_DDR_REFA: CD28.1 JDIMM1.164 RD9.2 RD10.2 RD12.1
+V_DDR_REFA_R: CC95.1 CD30.1 RC157.2 RD9.1
+VNN: CC80.2 PCZ100.1 PCZ101.1 PCZ102.1 PCZ103.1 PCZ104.1 PCZ105.1 PCZ106.1 PCZ107.1 PCZ108.1 PCZ109.1 PCZ110.1 PCZ111.1 PCZ112.1 PCZ113.1 PCZ114.1 PCZ115.1 PCZ116.1 PCZ117.1 PCZ118.1 PCZ119.1 PLZ1.4 PRZ12.2 RC124.1 UC1.AF35 UC1.AG27 UC1.AG28 UC1.AG36 UC1.AG46 UC1.AG48 UC1.AJ27 UC1.AJ28 UC1.AJ46 UC1.AJ48 UC1.AL27 UC1.AL28 UC1.AL48 UC1.AL49 UC1.AM27 UC1.AM28
AC_OFF#: PQB31.2 PRB45.1 UE1.27
ACIN_CHG: PCB02.1 PQB31.1 PRB09.2 PRB10.1 PUB01.16
ACLIN: PRB16.1 PRB18.1 PUB01.20
ACOK_CHG: PRB22.1 PUB01.24
AD_BID: RE14.1 RE15.2 UE1.66
ADJ_2.5V: PC2505.2 PR2502.2 PR2503.1 PU2501.7
ADP_I: PRB32.2 UE1.65
AISP1: PCG14.1 PRG22.1 PRG45.2 PUG1.20
AISP2: PCZ11.1 PRZ26.1 PRZ44.2 PUZ1.20
ALERT#: R28.2 U2.6
ALERT#_VCCGI: PRG11.1 PUG1.5
ALERT#_VNN: PRZ13.1 PUZ1.5
ALW_PWRGD_3V_5V_R: RC53.2 UC3.2
AMBER_LED_BAT: Q5029.1 R68.2
ASGATE: PRB07.2 PUB01.7
AUD_HP1_JACK_L: RA58.1 RA59.2 UA1.25
AUD_HP1_JACK_L1: LA2.1 RA52.2 RA58.2
AUD_HP1_JACK_R: RA55.2 RA61.1 UA1.26
AUD_HP1_JACK_R1: LA3.1 RA53.2 RA61.2
AUD_PC_BEEP: CA478.2 UA1.11
AUD_PC_BEEP_C: DA7.1 RA31.1
AUD_SENSE_A: CA488.1 RA40.1 RA51.2 UA1.12
AUD_SPK_L+: RA42.1 UA1.35
AUD_SPK_L+_C: CA28.1 DA1.2 JSPK1.3 RA42.2
AUD_SPK_L-: RA45.1 UA1.36
AUD_SPK_L-_C: CA27.1 DA1.3 JSPK1.4 RA45.2
AUD_SPK_R+: RA43.1 UA1.38
AUD_SPK_R+_C: CA476.1 DA2.2 JSPK1.1 RA43.2
AUD_SPK_R-: RA49.1 UA1.37
AUD_SPK_R-_C: CA480.1 DA2.3 JSPK1.2 RA49.2
AUD_VREF: CA489.1 UA1.22
AVCORE1: PCG03.1 PCG14.2 PLG1.3 PRG23.2 PRG40.2 PUG1.21
AVCORE2: PCZ11.2 PCZ16.1 PLZ1.3 PRZ27.2 PRZ39.2 PUZ1.21
AVCORE2_NTC: PHZ1.1 PRZ26.2 PRZ27.1
BA: PDB01.3 PQB28.1 PRB41.2
BATGONE: PCB09.1 PRB23.1 PRB24.1 PUB01.25
BATT_CHG_LED#: Q17.4 UE1.21
BATT_I: PCB10.1 PRB29.1 UE1.75
BATT_LOW_LED#: Q17.1 UE1.93
BATT_WHITE_LED_R#: Q17.3 Q19.2 Q22.1
BEEP#: DA7.3 UE1.23
BGATE: PCB28.1 PQB13.4 PUB01.32
BKLT_CTRL: D3.1 R9.1 R303.2 R5217.2
BKOFF#: R302.2 UE1.105
BLON_OUT_C: JEDP1.28 R302.1 R5218.2
BMON: PRB29.2 PUB01.27
BST_1.2V: PRM02.1 PUM01.18
BST_1.2V_R: PCM12.1 PRM02.2
BST_1.05V: PRH06.1 PUH01.1
BST_1.05V_R: PCH12.1 PRH06.2
BST_3V: PR301.1 PU301.1
BST_3V_R: PC307.1 PR301.2
BST_5V: PR501.1 PU501.1
BST_5V_R: PC507.1 PR501.2
BST_CHG: PCB06.1 PRB14.2
BST_CHG_R: PRB14.1 PUB01.12
BST_VCCGI: PRG10.1 PUG1.8
BST_VCCGI_R: PCG13.1 PRG10.2
BST_VNN: PRZ19.1 PUZ1.8
BST_VNN_R: PCZ09.1 PRZ19.2
BT_RADIO_DIS#: RW4.2 UC1.H37
BT_RADIO_DIS#_R: JWLAN1.54 RW4.1 RW28.1
CAM_DET#: R131.2 RC1148.2 UC1.M27
CAM_DET#_R: JEDP1.4 R131.1
CAP_LED: JKB1.27 R25.2
CAP_LED_Q: Q7.1 R25.1
CAPS_LED#: Q6.3 R24.2 UE1.91
CAPS_LED#_R: Q6.1 Q7.2
CBN: CA496.2 UA1.28
CBP: CA496.1 UA1.30
CCLIM: PRB27.2 PRB28.2 PUB01.26
CHG_AMBER_LED_R#: Q17.6 Q5029.2
CLK_PCIE_N0: JSSD1.53 UC1.R10
CLK_PCIE_N1: JWLAN1.49 UC1.N5
CLK_PCIE_N2: UC1.R5 UL1.16
CLK_PCIE_P0: JSSD1.55 UC1.R12
CLK_PCIE_P1: JWLAN1.47 UC1.N7
CLK_PCIE_P2: UC1.R7 UL1.15
CLK_SMB: PBATT1.7 PR42.1
CLKREQ_CNV#: JWLAN1.14 RC86.1 RW22.1 UC1.F19
CLKREQ_PCIE#0: JSSD1.52 RC167.2 UC1.A46
CLKREQ_PCIE#1: RC166.2 RW25.1 UC1.C45
CLKREQ_PCIE#2: RC165.2 RL13.1 UC1.B45
CLKREQ_PCIE#2_R: RL13.2 UL1.12
CLKREQ_PCIE#3: RC176.2 UC1.C44
CLKREQ_PCIE#15_R: JWLAN1.53 RW25.2
CLKRUN#: RE5.1 UC1.C33
CMSRC: PRB08.2 PUB01.5
CNV_BRI_PRX_DTX: RW8.1 RW19.1 UC1.J17
CNV_BRI_PRX_R_DTX: JWLAN1.22 RW10.1 RW18.1 RW19.2
CNV_BRI_PTX_DRX: RC87.2 RW15.1 UC1.H17
CNV_BRI_PTX_R_DRX: JWLAN1.36 RW15.2
CNV_RF_RESET#: JWLAN1.10 RW11.1 RW23.1 UC1.F17
CNV_RGI_PRX_DTX: RC88.2 RW16.1 UC1.D17
CNV_RGI_PRX_R_DTX: JWLAN1.34 RW16.2
CNV_RGI_PTX_DRX: RW17.1 UC1.D19
CNV_RGI_PTX_R_DRX: JWLAN1.32 RW7.1 RW9.1 RW17.2
CNVI_EN#: QW1.2 RW26.1 UC1.L41
CNVI_WGR_CLK_DN: JWLAN1.21 UC1.H31
CNVI_WGR_CLK_DP: JWLAN1.23 UC1.H29
CNVI_WGR_DATA0_DN: JWLAN1.15 UC1.P31
CNVI_WGR_DATA0_DP: JWLAN1.17 UC1.M31
CNVI_WGR_DATA1_DN: JWLAN1.9 UC1.F29
CNVI_WGR_DATA1_DP: JWLAN1.11 UC1.D29
CNVI_WT_CLK_DN: JWLAN1.71 UC1.D35
CNVI_WT_CLK_DP: JWLAN1.73 UC1.F35
CNVI_WT_DATA0_DN: JWLAN1.65 UC1.H35
CNVI_WT_DATA0_DP: JWLAN1.67 UC1.J35
CNVI_WT_DATA1_DN: JWLAN1.59 UC1.J31
CNVI_WT_DATA1_DP: JWLAN1.61 UC1.L31
CNVI_WT_RCOMP: RC82.1 UC1.F33
COMP: PCB12.1 PRB30.1 PUB01.28
COMP_VCCGI: PCG12.1 PRG17.1 PUG1.23
COMP_VNN: PCZ04.1 PRZ09.1 PUZ1.23
CPVEE: CA25.1 UA1.27
CS_1.2V: PRM03.1 PUM01.13
CSIN_CHG: PCB03.2 PCB05.1 PRB12.2 PUB01.14
CSIP_CHG: PCB03.1 PCB04.1 PRB11.2 PUB01.15
CSON: PCB15.2 PCB16.1 PRB37.1 PUB01.1
CSON_R: PRB01.3 PRB37.2
CSOP: PCB15.1 PCB17.1 PRB36.1 PUB01.2
CSOP_R: PRB01.2 PRB36.2
DAT_SMB: PBATT1.6 PR37.1
DBC_EN: R6.2 UE1.89
DBC_PANEL_EN_R: JEDP1.11 R5.2 R6.1
DBG_PTI_CLK_0: T55.1(TP-1) UC1.AG53
DBG_PTI_DATA_0: T56.1(TP-1) UC1.AG54
DBG_PTI_DATA_1: T57.1(TP-1) UC1.AE54
DBG_PTI_DATA_2: T58.1(TP-1) UC1.AE53
DBG_PTI_DATA_3: T59.1(TP-1) UC1.AD55
DBG_PTI_DATA_4: T60.1(TP-1) UC1.AD53
DBG_PTI_DATA_5: T61.1(TP-1) UC1.AC54
DBG_PTI_DATA_6: T62.1(TP-1) UC1.AC53
DBG_PTI_DATA_7: T63.1(TP-1) UC1.AB53
DCIN_CHG: PCB07.2 PCB37.2 PRB15.2 PUB01.17
DDR_M0_ACT#: JDIMM1.114 UC1.BF41
DDR_M0_ALERT#: JDIMM1.116 RD37.2
DDR_M0_BA0: JDIMM1.150 UC1.BD43
DDR_M0_BA1: JDIMM1.145 UC1.BH51
DDR_M0_BG0: JDIMM1.115 UC1.BL50
DDR_M0_BG1: JDIMM1.113 UC1.BF43
DDR_M0_CKE0: JDIMM1.109 UC1.BF55
DDR_M0_CKE1: JDIMM1.110 UC1.BF54
DDR_M0_CLK0: JDIMM1.137 UC1.BE49
DDR_M0_CLK1: JDIMM1.138 UC1.BC49
DDR_M0_CLK#0: JDIMM1.139 UC1.BE51
DDR_M0_CLK#1: JDIMM1.140 UC1.BC48
DDR_M0_CS#0: JDIMM1.149 UC1.BJ43
DDR_M0_CS#1: JDIMM1.157 UC1.BK43
DDR_M0_D0: JDIMM1.7 UC1.AR53
DDR_M0_D1: JDIMM1.3 UC1.AP55
DDR_M0_D2: JDIMM1.8 UC1.AP53
DDR_M0_D3: JDIMM1.4 UC1.AN54
DDR_M0_D4: JDIMM1.16 UC1.AU54
DDR_M0_D5: JDIMM1.20 UC1.AV53
DDR_M0_D6: JDIMM1.21 UC1.AV55
DDR_M0_D7: JDIMM1.17 UC1.AW53
DDR_M0_D8: JDIMM1.70 UC1.AU51
DDR_M0_D9: JDIMM1.67 UC1.AU48
DDR_M0_D10: JDIMM1.71 UC1.AU49
DDR_M0_D11: JDIMM1.79 UC1.BA46
DDR_M0_D12: JDIMM1.83 UC1.BA48
DDR_M0_D13: JDIMM1.84 UC1.BA49
DDR_M0_D14: JDIMM1.80 UC1.BA51
DDR_M0_D15: JDIMM1.66 UC1.AR51
DDR_M0_D16: JDIMM1.50 UC1.AY55
DDR_M0_D17: JDIMM1.45 UC1.BA54
DDR_M0_D18: JDIMM1.49 UC1.BA53
DDR_M0_D19: JDIMM1.46 UC1.AY53
DDR_M0_D20: JDIMM1.63 UC1.BC53
DDR_M0_D21: JDIMM1.58 UC1.BD55
DDR_M0_D22: JDIMM1.59 UC1.BE54
DDR_M0_D23: JDIMM1.62 UC1.BD53
DDR_M0_D24: JDIMM1.28 UC1.AN43
DDR_M0_D25: JDIMM1.25 UC1.AN44
DDR_M0_D26: JDIMM1.42 UC1.AR48
DDR_M0_D27: JDIMM1.38 UC1.AU41
DDR_M0_D28: JDIMM1.41 UC1.AU43
DDR_M0_D29: JDIMM1.29 UC1.AN41
DDR_M0_D30: JDIMM1.24 UC1.AN39
DDR_M0_D31: JDIMM1.37 UC1.AU44
DDR_M0_D32: JDIMM1.228 UC1.BA35
DDR_M0_D33: JDIMM1.225 UC1.AY33
DDR_M0_D34: JDIMM1.229 UC1.BA33
DDR_M0_D35: JDIMM1.224 UC1.AY35
DDR_M0_D36: JDIMM1.212 UC1.BA37
DDR_M0_D37: JDIMM1.216 UC1.AY37
DDR_M0_D38: JDIMM1.215 UC1.AY39
DDR_M0_D39: JDIMM1.211 UC1.BA39
DDR_M0_D40: JDIMM1.207 UC1.BJ36
DDR_M0_D41: JDIMM1.203 UC1.BK37
DDR_M0_D42: JDIMM1.204 UC1.BJ35
DDR_M0_D43: JDIMM1.208 UC1.BL36
DDR_M0_D44: JDIMM1.195 UC1.BJ39
DDR_M0_D45: JDIMM1.191 UC1.BL40
DDR_M0_D46: JDIMM1.190 UC1.BJ40
DDR_M0_D47: JDIMM1.194 UC1.BK41
DDR_M0_D48: JDIMM1.246 UC1.BD29
DDR_M0_D49: JDIMM1.245 UC1.BF29
DDR_M0_D50: JDIMM1.249 UC1.BH29
DDR_M0_D51: JDIMM1.233 UC1.BF33
DDR_M0_D52: JDIMM1.250 UC1.BC29
DDR_M0_D53: JDIMM1.237 UC1.BD33
DDR_M0_D54: JDIMM1.236 UC1.BF35
DDR_M0_D55: JDIMM1.232 UC1.BH35
DDR_M0_D56: JDIMM1.173 UC1.BL34
DDR_M0_D57: JDIMM1.183 UC1.BL30
DDR_M0_D58: JDIMM1.182 UC1.BJ29
DDR_M0_D59: JDIMM1.186 UC1.BK29
DDR_M0_D60: JDIMM1.174 UC1.BJ33
DDR_M0_D61: JDIMM1.170 UC1.BK33
DDR_M0_D62: JDIMM1.169 UC1.BJ34
DDR_M0_D63: JDIMM1.187 UC1.BJ30
DDR_M0_DQS0: JDIMM1.13 UC1.AT53
DDR_M0_DQS1: JDIMM1.76 UC1.AW49
DDR_M0_DQS2: JDIMM1.55 UC1.BC54
DDR_M0_DQS3: JDIMM1.34 UC1.AR41
DDR_M0_DQS4: JDIMM1.221 UC1.AV37
DDR_M0_DQS5: JDIMM1.200 UC1.BL38
DDR_M0_DQS6: JDIMM1.242 UC1.BF31
DDR_M0_DQS7: JDIMM1.179 UC1.BJ32
DDR_M0_DQS#0: JDIMM1.11 UC1.AT55
DDR_M0_DQS#1: JDIMM1.74 UC1.AW48
DDR_M0_DQS#2: JDIMM1.53 UC1.BB53
DDR_M0_DQS#3: JDIMM1.32 UC1.AR43
DDR_M0_DQS#4: JDIMM1.219 UC1.AV35
DDR_M0_DQS#5: JDIMM1.198 UC1.BJ38
DDR_M0_DQS#6: JDIMM1.240 UC1.BD31
DDR_M0_DQS#7: JDIMM1.177 UC1.BK31
DDR_M0_DRAMRST#: D14.2 RC41.2 RC42.1 UC1.BC43
DDR_M0_DRAMRST#_R: CD29.1 JDIMM1.108 RC42.2
DDR_M0_MA0: JDIMM1.144 UC1.BD45
DDR_M0_MA1: JDIMM1.133 UC1.BH50
DDR_M0_MA2: JDIMM1.132 UC1.BH47
DDR_M0_MA3: JDIMM1.131 UC1.BG52
DDR_M0_MA4: JDIMM1.128 UC1.BK45
DDR_M0_MA5: JDIMM1.126 UC1.BJ46
DDR_M0_MA6: JDIMM1.127 UC1.BJ44
DDR_M0_MA7: JDIMM1.122 UC1.BJ47
DDR_M0_MA8: JDIMM1.125 UC1.BJ45
DDR_M0_MA9: JDIMM1.121 UC1.BK47
DDR_M0_MA10: JDIMM1.146 UC1.BF45
DDR_M0_MA11: JDIMM1.120 UC1.BJ51
DDR_M0_MA12: JDIMM1.119 UC1.BJ52
DDR_M0_MA13: JDIMM1.158 UC1.BH43
DDR_M0_MA14_WE#: JDIMM1.151 UC1.BJ48
DDR_M0_MA15_CAS#: JDIMM1.156 UC1.BJ50
DDR_M0_MA16_RAS#: JDIMM1.152 UC1.BD41
DDR_M0_ODT0: JDIMM1.155 UC1.BD39
DDR_M0_ODT1: JDIMM1.161 UC1.BF39
DDR_M0_PAR: JDIMM1.143 RD36.1
DDR_M0_RCOMP: RC38.2 UC1.AY29
DDR_M1_RCOMP: RC39.1 UC1.AY27
DEVSLP0_HDD: RS61.1 UC1.J43
DIMM_CHA_SA0: JDIMM1.256 RD1.2 RD4.1
DIMM_CHA_SA1: JDIMM1.260 RD2.2 RD5.1
DIMM_CHA_SA2: JDIMM1.166 RD3.2 RD6.1
DMIC_CLK: L5.2 UA1.3
DMIC_CLK_EDP: CA486.1 D12.3 JEDP1.31 L5.1
DMIC_DATA: RA46.2 UA1.2
DMIC_DATA_EDP: CA491.1 D12.2 JEDP1.30 RA46.1
EC_CLR_CMOS: QC1.2 QC10.2 RC64.1 UE1.74
EC_ENVDD: D4.3 UE1.71
EC_GPIO65: RE41.1 UE1.102
EC_MUTE#: RA8.2 UA1.40 UE1.83
EC_ON: PQB29.2 PR506.1 UE1.112
EC_RSMRST#: CC89.2 CE19.1 RC52.1 RE35.1 UC3.1 UE1.100
EC_RST#: CE1.1 RE1.1 UE1.37
EC_RX: RW13.1 UE1.31
EC_RX_R: JWLAN1.40 RW13.2
EC_SCI#: RC1143.2 UE1.20
EC_SCI#_SOC: RC121.1 RC1143.1 UC1.H45
EC_SMB_CK1: PD5.3 PR42.2 PRB20.1 RE36.2 UE1.77
EC_SMB_CK2: Q11.3 RE38.2 UE1.79
EC_SMB_DA1: PD5.2 PR37.2 PRB19.1 RE37.2 UE1.78
EC_SMB_DA2: Q11.6 RE39.2 UE1.80
EC_TP_INT#: DC4.1 Q9.1 RE32.1 UE1.106
EC_TX: RE29.1 RW14.1 UE1.30
EC_TX_R: JWLAN1.38 RW14.2
ECAGND: CE16.2 CE17.1 LE2.1 PH1.2 UE1.69
EDP_AUXN: C10.1 UC1.W15
EDP_AUXN_C: C10.2 JEDP1.16
EDP_AUXP: C11.1 UC1.W17
EDP_AUXP_C: C11.2 JEDP1.15
EDP_BKLT_CTRL: D3.2 R8.2 R9.2
EDP_HPD: CT14.1 JEDP1.12 Q5027.2 RT29.1
EDP_HPD#: Q5027.1 RT28.1 RT31.1 UC1.B39
EDP_RCOMP_N: RC1.2 UC1.AA7
EDP_RCOMP_P: RC1.1 UC1.AA5
EDP_TXN0: C6.1 UC1.AE13
EDP_TXN0_C: C6.2 JEDP1.18
EDP_TXN1: C8.1 UC1.AC17
EDP_TXN1_C: C8.2 JEDP1.21
EDP_TXP0: C7.1 UC1.AE12
EDP_TXP0_C: C7.2 JEDP1.19
EDP_TXP1: C9.1 UC1.AC15
EDP_TXP1_C: C9.2 JEDP1.22
EDP_VDD_EN: D4.2 RC158.2 UC1.C41
EMMC_0_CLK: RM14.1 UC1.J13
EMMC_0_CLK_R: CM8.2 RM13.2 RM14.2 UM1.M6
EMMC_0_CMD: RM15.1 UC1.M13
EMMC_0_CMD_R: RM15.2 UM1.M5
EMMC_0_DATA0: UC1.M19 UM1.A3
EMMC_0_DATA1: UC1.H19 UM1.A4
EMMC_0_DATA2: UC1.J19 UM1.A5
EMMC_0_DATA3: UC1.P17 UM1.B2
EMMC_0_DATA4: UC1.P19 UM1.B3
EMMC_0_DATA5: UC1.J15 UM1.B4
EMMC_0_DATA6: UC1.L17 UM1.B5
EMMC_0_DATA7: UC1.M17 UM1.B6
EMMC_0_RCLK: RM24.1 UC1.L15
EMMC_0_RCLK_R: RM12.2 RM24.2 UM1.H5
EMMC_0_RST: CM6.1 RM25.1 RM27.2 RM28.2 UM2.4
EMMC_0_RST_R: RM25.2 UM1.K5
EMMC_DET: RC171.2 RC172.1 UC1.U41
EN_0.6VSP: PCM16.1 PRM09.2 PUM01.7
EN_1.2V: PCM15.1 PRM08.2 PUM01.8
EN_1.05V: PCH09.1 PRH01.2 PRH02.1 PUH01.6
EN_1.05VS: PRH01.1 UE1.73
EN_1.8V: PC1805.1 PR1801.2 PR1802.1 PR1808.2 PU1801.5
EN_1.24V: PC1205.1 PR1205.2 PR1206.1 PU1201.5
EN_2.5V: PC2503.1 PR2501.2 PU2501.2
EN_3V: PR502.1 PU301.12
EN_5V: PR503.1 PU501.12
ENBKL: RC160.2 UC1.C40 UE1.97
ENLDO_3V5V: PC317.1 PR302.1 PR303.1 PU301.11 PU501.11
FB_1.2V: PCM17.1 PRM10.1 PRM11.1 PUM01.6
FB_1.05V: PRH08.1 PRH09.1 PRH12.2 PUH01.10
FB_1.8V: PC1807.2 PR1805.1 PR1807.2 PU1801.6
FB_1.24V: PC1206.2 PR1202.1 PR1204.2 PU1201.6
FB_3V: PC315.1 PR307.2 PR308.1 PU301.13
FB_3V_R: PC315.2 PR306.1
FB_5V: PC517.1 PR510.2 PR511.1 PU501.13
FB_5V_R: PC517.2 PR509.1
FB_VCCGI: PCG11.1 PCG12.2 PRG17.2 PRG18.1 PUG1.24
FB_VNN: PCZ04.2 PCZ05.1 PRZ09.2 PRZ10.1 PUZ1.24
FFS_INT1: UC1.L46 US2.12
FFS_INT2: QS1.2 RS64.2 UC1.M43 US2.11
FFS_INT2_Q: JHDD1.9 QS1.3 RS63.2
FPR_SCAN#: EU4012.3 JFP1.2 RC213.1 UE1.76
FSET: PRB38.1 PUB01.3
GPIO_27: RC97.1 RC98.1 UC1.AE39
GPIO_28: RC99.1 RC100.1 UC1.AE46
GPIO_172: RC8.1 UC1.C20
GPIO_174: RC110.2 UC1.C18
GPIO_175: RC9.1 RC12.1 UC1.A18
H_PROCHOT#: CC15.1 PQ11.1 PQ12.3 PQB32.1 PRB21.1 RC69.1 RE19.2 RE20.2 UC1.J54
H_THERMTRIP#: RC70.1 RE11.2 UC1.J53
HDA_BIT_CLK: RC13.2 UC1.A22
HDA_BIT_CLK_R: CC1.2 RA50.2 RC13.1 UA1.5
HDA_CODEC_SDIN0: RA30.2 UA1.7
HDA_RST#: T2.1(TP-1) UC1.C21
HDA_SDIN0: RA30.1 RC7.2 RC11.1 RC16.2 RC17.2 UC1.B21
HDA_SDOUT: RC14.2 UC1.C22
HDA_SDOUT_R: RC14.1 UA1.4
HDA_SYNC: RC15.2 RC16.1 UC1.C23
HDA_SYNC_R: RC15.1 UA1.9
HDMI_CLKN: CG34.2 LI1.2 RG59.1 RG105.1
HDMI_CLKP: CG33.2 LI1.3 RG60.1 RG104.1
HDMI_DETECT: QG1.2 RG48.1 RG56.1
HDMI_L_CLKN: JHDMI1.12 LI1.1 RG59.2 RG67.2
HDMI_L_CLKP: JHDMI1.10 LI1.4 RG60.2 RG67.1
HDMI_L_TX_N0: JHDMI1.9 LI2.1 RG63.2 RG68.1
HDMI_L_TX_N1: JHDMI1.6 LI3.1 RG65.2 RG69.1
HDMI_L_TX_N2: JHDMI1.3 LI4.1 RG70.2 RG71.1
HDMI_L_TX_P0: JHDMI1.7 LI2.4 RG61.2 RG68.2
HDMI_L_TX_P1: JHDMI1.4 LI3.4 RG64.2 RG69.2
HDMI_L_TX_P2: JHDMI1.1 LI4.4 RG66.2 RG71.2
HDMI_SCLK: CM26.1 JHDMI1.15 Q57.1 RI13.1
HDMI_SDATA: CM27.1 JHDMI1.16 Q58.1 RI14.1
HDMI_TX_N0: CG32.2 LI2.2 RG63.1 RG109.1
HDMI_TX_N1: CG30.2 LI3.2 RG65.1 RG103.1
HDMI_TX_N2: CG28.2 LI4.2 RG70.1 RG107.1
HDMI_TX_P0: CG31.2 LI2.3 RG61.1 RG108.1
HDMI_TX_P1: CG29.2 LI3.3 RG64.1 RG102.1
HDMI_TX_P2: CG27.2 LI4.3 RG66.1 RG106.1
HP_DETECT: CM17.1 JHDMI1.19 RG48.2
HPOUT_L: CA498.1 DA8.2 JHP1.1 LA2.2 RA54.1
HPOUT_R: CA504.1 DA8.3 JHP1.2 LA3.2 RA57.1
HW_ACAV_IN: PR31.1 PRB22.2 PRB25.2 PRB26.1 RE21.2
I2C_5_SCL: JDB1.10 Q10.1 R34.2 UC1.C50
I2C_5_SDA: JDB1.9 Q10.4 R33.2 UC1.A50
I2C_6_SCL: R85.1 R87.2 UC1.C48
I2C_6_SDA: R84.1 R86.2 UC1.C47
I2C_SCL_TP: JTP1.6 Q10.6 R46.2
I2C_SDA_TP: JTP1.7 Q10.3 R47.2
ILMT_1.05V: PRH03.2 PRH04.1 PUH01.12
IMON_VCCGI: PRG39.2 PUG1.18
IMON_VNN: PRZ24.2 PUZ1.18
INT_TP#: JTP1.4 Q9.3 R39.2
INTRUDE: RC73.2 UC1.H25
ISOLATE#: RL3.2 RL4.1 UL1.20
JACK_PLUG: DA9.3 JHP1.5 RA51.1
JACK_PLUG_DET: DA9.2 JHP1.6 RA62.2
JHDD_P10: JHDD1.8 RS61.2
KB_BL_CTRL#: EC3001.1 JKBBL1.4 Q8.1
KB_DET#: JKB1.1 UC1.H47
KB_LED_BL_DET: R26.1 R27.1 UC1.M29
KB_LED_DET_C: JKBBL1.2 R26.2
KB_LED_PWM: Q8.2 UE1.25
KSI0: JKB1.9 UE1.55
KSI1: JKB1.7 UE1.56
KSI2: JKB1.5 UE1.57
KSI3: JKB1.8 UE1.58
KSI4: JKB1.4 UE1.59
KSI5: JKB1.6 UE1.60
KSI6: JKB1.3 UE1.61
KSI7: JKB1.2 UE1.62
KSO0: JKB1.18 UE1.39
KSO1: JKB1.16 UE1.40
KSO2: JKB1.17 UE1.41
KSO3: JKB1.15 UE1.42
KSO4: JKB1.11 UE1.43
KSO5: JKB1.10 UE1.44
KSO6: JKB1.13 UE1.45
KSO7: JKB1.12 UE1.46
KSO8: JKB1.14 UE1.47
KSO9: JKB1.24 UE1.48
KSO10: JKB1.26 UE1.49
KSO11: JKB1.25 UE1.50
KSO12: JKB1.19 UE1.51
KSO13: JKB1.22 UE1.52
KSO14: JKB1.23 UE1.53
KSO15: JKB1.21 UE1.54
KSO16: JKB1.20 UE1.81
L_BKLT_CTRL: R8.1 RC4.1 RC5.1 UC8.4
LAN_MDIN0: TL1.15 UL1.2
LAN_MDIN1: TL1.9 UL1.5
LAN_MDIN2: TL2.10 UL1.7
LAN_MDIN3: TL2.16 UL1.10
LAN_MDIP0: TL1.16 UL1.1
LAN_MDIP1: TL1.10 UL1.4
LAN_MDIP2: TL2.9 UL1.6
LAN_MDIP3: TL2.15 UL1.9
LANXIN: RL8.2 UL1.28
LANXIN_R: CL10.2 RL8.1 YL2.1
LANXOUT: RL9.2 UL1.29
LANXOUT_R: CL11.2 RL9.1 YL2.3
LCD_BRIGHTNESS: JEDP1.27 R303.1
LCD_CBL_DET#: JEDP1.14 R100.2 RC1149.2
LCD_CBL_DET#_R: RC1149.1 UC1.P27
LCD_TEST: D3.3 R304.2 UE1.72
LCD_TST_C: JEDP1.10 R304.1
LCDVDD_EN: D4.1 R10.1 U1.4
LDO1_CAP: CA479.2 RA47.2 UA1.21
LDO2_CAP: CA482.2 UA1.32
LDO3_CAP: CA493.2 UA1.6
LED0: T18.1(TP-1) UL1.27
LED1: T19.1(TP-1) UL1.25
LG_1.2V: PQM01.8 PUM01.15
LG_CHG: PQB25.4 PUB01.9
LG_VCCGI: PQG2.4 PUG1.11
LG_VNN: PQZ1.8 PUZ1.11
LID_CLOSE#: EC2902.1 JPWR1.3 R22.2
LID_SW#: D5.1 R22.1 RE34.1 UE1.115
LINE1-L_C: CA500.2 RA59.1
LINE1-L_R: CA503.2 RA55.1
LINE1_L: CA500.1 UA1.18
LINE1_R: CA503.1 UA1.17
LOM_TCT: CL12.1 TL1.11 TL1.14 TL2.11 TL2.14
LPC_AD0: RC23.2 UE1.10
LPC_AD0_R: RC23.1 UC1.A34
LPC_AD1: RC22.2 UE1.8
LPC_AD1_R: RC22.1 UC1.C34
LPC_AD2: RC21.2 UE1.7
LPC_AD2_R: RC21.1 UC1.B35
LPC_AD3: RC20.2 UE1.5
LPC_AD3_R: RC20.1 UC1.C35
LPC_CLK0: RC24.1 UC1.C37
LPC_CLK_EC: CC2.1 RC24.2 RE26.2 UE1.12
LPC_FRAME#: RC19.2 UE1.4
LPC_FRAME#_R: RC19.1 UC1.B33
LX_1.2V: PCM12.2 PLM01.2 PQM01.9 PRM01.1 PUM01.16
LX_1.05V: PCH12.2 PLH01.1 PRH07.1 PUH01.2 PUH01.3
LX_1.8V: PL1801.1 PR1804.1 PU1801.2 PU1801.3
LX_1.24V: PL1201.1 PR1203.1 PU1201.2 PU1201.3
LX_3V: PC307.2 PL301.1 PR305.1 PU301.6 PU301.19 PU301.20
LX_5V: PC507.2 PL501.1 PR505.1 PU501.6 PU501.19 PU501.20
LX_CHG: PCB06.2 PLB01.1 PQB25.5 PQB26.1 PQB26.2 PQB26.3 PRB40.1 PUB01.10
LX_VCCGI: PCG13.2 PLG1.1 PQG1.1 PQG1.2 PQG1.3 PQG2.5 PRG20.1 PUG1.10
LX_VNN: PCZ09.2 PLZ1.1 PQZ1.9 PRZ23.1 PUZ1.10
MASK_SATA_LED#: Q22.2 R5216.2 UE1.108
MCT: CL13.1 RL19.1 RL20.1 RL22.1 RL23.1
MCT0: RL19.2 TL1.3
MCT1: RL20.2 TL1.6
MCT2: RL22.2 TL2.6
MCT3: RL23.2 TL2.3
MDSI_C_TE_GPIO_43: T54.1(TP-1) UC1.T53
ME_EN: QC3.2 RC92.1 UE1.99
ME_FWP_SOC_Q: QC3.3 RC94.1 UC1.T55
MIC_CAP: CA26.1 UA1.15
NCT7718_DXN: C22.2 C23.2 Q14.3 U2.3
NCT7718_DXP: C22.1 C23.1 Q14.1 Q14.2 U2.2
NTC_CHG: PRB13.2 PUB01.13
ODD_DA#: JODD1.23 JODD1.24 T28.1(TP-1)
ON/OFF#: EC2901.1 ED2901.3 JPWR1.2 RE55.1 SW1.1 T29.1(TP-1) UE1.114
OSCIN: RC71.1 UC1.U2
OSCOUT: RC72.1 UC1.T1
PBTN_OUT#: CE5.1 RC143.1 UC5.2 UE1.15
PBTN_OUT#_R: DC5.1 RC139.2 UC5.4
PBTN_OUT#_SOC: DC5.2 RC144.2 RC145.2 UC1.E54
PCH_PLTRST#: RM28.1 UC1.U44
PCH_RSMRST#_AND: CC6.1 DC2.1 DC3.2 RC47.1 RC52.2 RC54.2 RC55.1 RC56.2 UC1.F27
PCH_SMB_CLK: JDIMM1.253 QC2.1 RC84.2 US2.1
PCH_SMB_DATA: JDIMM1.254 QC2.4 RC83.2 US2.4
PCIE_CRX_C_DTX_N5: CL27.2 UL1.18
PCIE_CRX_C_DTX_P5: CL26.2 UL1.17
PCIE_CRX_DTX_N0: JSSD1.5 UC1.H6
PCIE_CRX_DTX_N1: JSSD1.17 UC1.E5
PCIE_CRX_DTX_N2: JSSD1.29 UC1.F6
PCIE_CRX_DTX_N3: JSSD1.41 UC1.F9
PCIE_CRX_DTX_N4: JWLAN1.43 UC1.F11
PCIE_CRX_DTX_N5: CL27.1 UC1.D13
PCIE_CRX_DTX_P0: JSSD1.7 UC1.G7
PCIE_CRX_DTX_P1: JSSD1.19 UC1.D4
PCIE_CRX_DTX_P2: JSSD1.31 UC1.E7
PCIE_CRX_DTX_P3: JSSD1.43 UC1.H9
PCIE_CRX_DTX_P4: JWLAN1.41 UC1.D11
PCIE_CRX_DTX_P5: CL26.1 UC1.F13
PCIE_CTX_C_DRX_N0: CS16.2 JSSD1.11
PCIE_CTX_C_DRX_N1: CS31.2 JSSD1.23
PCIE_CTX_C_DRX_N2: CS33.2 JSSD1.35
PCIE_CTX_C_DRX_N3: CS36.2 JSSD1.47
PCIE_CTX_C_DRX_N4: CC20.1 JWLAN1.37
PCIE_CTX_C_DRX_N5: CC18.1 UL1.14
PCIE_CTX_C_DRX_P0: CS30.2 JSSD1.13
PCIE_CTX_C_DRX_P1: CS32.2 JSSD1.25
PCIE_CTX_C_DRX_P2: CS34.2 JSSD1.37
PCIE_CTX_C_DRX_P3: CS35.2 JSSD1.49
PCIE_CTX_C_DRX_P4: CC21.1 JWLAN1.35
PCIE_CTX_C_DRX_P5: CC19.1 UL1.13
PCIE_CTX_DRX_N0: CS16.1 UC1.F2
PCIE_CTX_DRX_N1: CS31.1 UC1.C7
PCIE_CTX_DRX_N2: CS33.1 UC1.B9
PCIE_CTX_DRX_N3: CS36.1 UC1.A10
PCIE_CTX_DRX_N4: CC20.2 UC1.B11
PCIE_CTX_DRX_N5: CC18.2 UC1.C13
PCIE_CTX_DRX_P0: CS30.1 UC1.E2
PCIE_CTX_DRX_P1: CS32.1 UC1.A7
PCIE_CTX_DRX_P2: CS34.1 UC1.C9
PCIE_CTX_DRX_P3: CS35.1 UC1.C10
PCIE_CTX_DRX_P4: CC21.2 UC1.C11
PCIE_CTX_DRX_P5: CC19.2 UC1.B13
PCIE_RCOMPN: RC81.2 UC1.C5
PCIE_RCOMPP: RC81.1 UC1.C6
PCIE_REF_CLK_RCOMP: RC78.2 UC1.L10
PCIE_RST#: RC1150.2 RC1152.1 UC1.AE41 UC12.2
PCIE_RST_B#: R182.2 RC1150.1 RC1151.1 RL24.2 RW30.2 UC12.4
PCIE_WAKE0#: RC170.2 UC1.F47
PCIE_WAKE1#: RC169.2 UC1.D47
PCIE_WAKE2#: RC168.2 RE42.2 UC1.F45 UL1.21
PCIE_WAKE3#: RC175.2 RW29.1 UC1.D50
PCIE_WAKE#_R: JWLAN1.55 RW29.2
PG_1V24ALW: RE8.2 UE1.29
PLT_RST#: CC90.2 JSSD1.50 R182.1 RC49.2 RC51.1 RL24.1 RW20.1 UC2.4 UE1.13 UL1.19 UM2.2
PLT_RST#_WLAN: JWLAN1.52 RW20.2 RW30.1
PM_BATLOW#: RC45.1 UC1.J48
PM_RST_BTN#: CC7.1 RC43.1 UC1.C51
PM_SLP_S3#: UC1.D51 UE1.6
PM_SLP_S4#: CE6.1 UC1.J49 UE1.18
PMC_SUSPWRDNACK_R: RE7.2 UE1.19
POK: CE9.1 DC3.1 PR35.1 PR304.2 PR504.2 PR1801.1 PU301.9 PU501.9 RC53.1 UE1.34
PRIM_PWRGD: PR1205.1 PR1803.2 PU1801.4
PROG: PRB17.2 PUB01.19
PROH: PQB33.2 PRB21.2 PRB44.2 PUB01.23
PROJECT_ID: RC173.2 RC174.1 UC1.U39
PS_ID: PD2.1 PR1.2 PR5.1 UE1.16
PSID: PJPDC1.3 PL3.1
PSID-1: PQ2.2 PR3.2 PR6.1
PSID-2: PD1.2 PL3.2 PQ1.1 PR3.1
PSID-3: PQ1.3 PR1.1
PSID-4: PQ1.2 PQ2.1 PR4.2 PR7.1
PSID-5: PD3.1 PR7.2
PSYS_VCCGI: PRG16.1 PUG1.19
PSYS_VNN: PRZ18.1 PUZ1.19
PTP_DIS#: JTP1.3 R41.2 UE1.36
QPCN_CHG: PCB18.2 PUB01.6
QPCP_CHG: PCB18.1 PUB01.4
REFCLK_CNV: CW1.1 RC85.1 RW12.2 UC1.J29
REFCLK_CNV_R: JWLAN1.64 RW12.1
REGOUT: CL32.1 RL21.1 UL1.24
RGND_VCCGI: PCG04.2 PCG05.1 PRG32.1 PRG42.2 PUG1.22
RGND_VNN: PCZ18.2 PCZ19.1 PRZ01.2 PRZ32.1 PUZ1.22
RING2: LA1.1 RA60.2 UA1.13
RING2_R: CA497.1 CA501.1 DA5.3 JHP1.4 LA1.2
RJ45_MDIN0: JRJ45.2 TL1.2
RJ45_MDIN1: JRJ45.6 TL1.8
RJ45_MDIN2: JRJ45.5 TL2.7
RJ45_MDIN3: JRJ45.8 TL2.1
RJ45_MDIP0: JRJ45.1 TL1.1
RJ45_MDIP1: JRJ45.3 TL1.7
RJ45_MDIP2: JRJ45.4 TL2.8
RJ45_MDIP3: JRJ45.7 TL2.2
RSET: RL2.2 UL1.31
RTC_DET#: QC9.1 RC138.1 UC1.L43
RTC_PWR: DC1.3 QC9.2 RC62.1 RC63.1
SATA_CRX_C_DTX_N0: CS6.2 JHDD1.5
SATA_CRX_C_DTX_N1: CS110.2 JODD1.9 JODD1.10
SATA_CRX_C_DTX_P0: CS5.2 JHDD1.6
SATA_CRX_C_DTX_P1: CS111.2 JODD1.11 JODD1.12
SATA_CRX_DTX_N0: CS6.1 UC1.J5
SATA_CRX_DTX_N1: CS110.1 UC1.G5
SATA_CRX_DTX_P0: CS5.1 UC1.J7
SATA_CRX_DTX_P1: CS111.1 UC1.H4
SATA_CTX_C_DRX_N0: CS4.2 JHDD1.3
SATA_CTX_C_DRX_N1: CS113.2 JODD1.5 JODD1.6
SATA_CTX_C_DRX_P0: CS3.2 JHDD1.2
SATA_CTX_C_DRX_P1: CS18.2 JODD1.3 JODD1.4
SATA_CTX_DRX_N0: CS4.1 UC1.J2
SATA_CTX_DRX_N1: CS113.1 UC1.H2
SATA_CTX_DRX_P0: CS3.1 UC1.J3
SATA_CTX_DRX_P1: CS18.1 UC1.H1
SATA_LED#: Q25.2 R77.2 R78.1 RC119.1 UC1.F43
SATA_LED#_R: Q22.3 Q25.3 R78.2 R80.2
SATA_ODD_PRSNT: JODD1.15 JODD1.16 RC120.1 UC1.P29 UE1.101
SCL_CHG: PRB20.2 PUB01.22
SDA_CHG: PRB19.2 PUB01.21
SDIO_VCCGI: PRG12.1 PUG1.4
SDIO_VNN: PRZ14.1 PUZ1.4
SERIRQ: UC1.B37 UE1.3
SET1_VCCGI: PRG06.2 PRG13.1 PUG1.28
SET1_VNN: PRZ15.1 PRZ41.2 PUZ1.28
SET2_VCCGI: PRG07.2 PRG14.1 PUG1.27
SET2_VNN: PRZ07.2 PRZ16.1 PUZ1.27
SET3_VCCGI: PRG08.2 PRG15.1 PUG1.26
SET3_VNN: PRZ08.2 PRZ17.1 PUZ1.26
SLEEVE: LA13.1 RA56.2 UA1.14
SLEEVE_R: CA499.1 CA502.1 DA5.2 JHP1.3 LA13.2
SMB_1.8V_3.3V: RC6.2 RC10.1 UC1.J21
SN_1.2V: PCM11.1 PRM01.2
SN_1.05V: PCH13.1 PRH07.2
SN_1.8V: PC1806.1 PR1804.2
SN_1.24V: PC1207.1 PR1203.2
SN_3V: PC309.1 PR305.2
SN_5V: PC509.1 PR505.2
SN_CHG: PCB29.1 PRB40.2
SN_VCCGI: PCG17.1 PRG20.2
SN_VNN: PCZ12.1 PRZ23.2
SOC_BKLTCTL: RC5.2 RC159.2 UC1.B41 UC8.2
SOC_DP1_CTRL_CLK: Q57.3 RC3.1 UC1.C42
SOC_DP1_CTRL_DATA: Q58.3 RC2.1 UC1.A42
SOC_DP1_HPD#: QG1.6 RG47.2 UC1.C38
SOC_DP1_N0: CG28.1 UC1.AA3
SOC_DP1_N1: CG30.1 UC1.Y1
SOC_DP1_N2: CG32.1 UC1.AD3
SOC_DP1_N3: CG34.1 UC1.AC3
SOC_DP1_P0: CG27.1 UC1.AA2
SOC_DP1_P1: CG29.1 UC1.Y3
SOC_DP1_P2: CG31.1 UC1.AD1
SOC_DP1_P3: CG33.1 UC1.AC2
SOC_EMMC_PWR_EN#: RM31.1 UC1.G51
SOC_EMMC_PWR_EN#_R: RM30.2 RM31.2 UM3.3 UM3.5
SOC_PLTRST#: CC8.1 RC48.1 RC49.1 RC50.1 UC1.D54 UC2.1 UC2.2
SOC_PWROK: CC9.1 CE2.1 DC2.2 RC57.1 UC1.D25 UE1.32
SOC_RTCTEST#: CC11.2 CLRP2.2 QC10.1 RC65.2 UC1.F25
SOC_RTCX1: CC13.1 RC67.1 UC1.D23 YC2.1
SOC_RTCX2: CC14.1 RC67.2 UC1.F23 YC2.2
SOC_SMBALERT#: T8.1(TP-1) UC1.A26
SOC_SMBCLK: QC2.6 RC89.1 UC1.B27
SOC_SMBDATA: QC2.3 RC90.1 UC1.C27
SOC_SPI_CLK: RC36.1 UC1.B29
SOC_SPI_CLK_R: RC36.2 RC37.1 UC11.6
SOC_SPI_CS#0: RC35.1 UC1.C31
SOC_SPI_CS#0_R: RC30.1 RC35.2 UC11.1
SOC_SPI_IO2: RC163.1 UC1.A30
SOC_SPI_IO2_0_R: RC32.1 RC163.2 UC11.3
SOC_SPI_IO3: RC161.1 UC1.C29
SOC_SPI_IO3_0_R: RC31.1 RC161.2 UC11.7
SOC_SPI_SI: RC162.1 UC1.B31
SOC_SPI_SI_0_R: RC162.2 UC11.5
SOC_SPI_SO: RC164.1 UC1.C30
SOC_SPI_SO_0_R: RC164.2 UC11.2
SOC_SPKR: DA7.2 UC1.AA54
SOC_SRTCRST#: CC12.2 CLRP1.2 QC1.1 RC66.2 UC1.D27
SOC_SVID_ALERT#: RC60.1 UC1.G54
SOC_SVID_ALERT#_R: PRG11.2 PRZ13.2 RC60.2 RC61.2
SOC_SVID_CLK: PRG04.2 PRG09.2 PRZ05.2 PRZ11.2 UC1.F55
SOC_SVID_DAT: PRG05.2 PRG12.2 PRZ06.2 PRZ14.2 RC59.2 UC1.G53
SOC_THERMTRIP#: RE11.1 UE1.121
SOC_XTAL19_IN: CC16.2 RC68.1 RC71.2 YC1.1
SOC_XTAL19_OUT: CC17.2 RC68.2 RC72.2 YC1.3
SPI_0_FS0_GPIO_80: RC107.2 UC1.L37
SPI_0_FS1_GPIO_81: RC101.1 RC102.1 RC151.2 UC1.J39
SPI_0_FS1_GPIO_81_R: RC151.1 T52.1(TP-1)
SPI_0_TX_GPIO_83: RC105.1 RC106.1 UC1.J37
SPI_2_CLK_GPIO_84: RC103.1 RC104.1 UC1.M37
SSD_SCP#: R300.2 RS64.1 UE1.107
SUS_STAT#: T5.1(TP-1) UC1.E52
SUSCLK: JWLAN1.50 RC58.1 RE31.1 UC1.G49
SUSP#: DE1.2 PRM09.1 R926.1 R927.2 UE1.14
SUSPWRDNACK#: RC46.1 RE7.1 UC1.F54
SWTRAP: RE27.2 RE28.1 UE1.70
SYSON: CE18.1 PR2501.1 PRM08.1 UE1.95
T_CRIT#: R29.2 U2.4
THM_SML1_CLK: Q11.4 R49.2 U2.8
THM_SML1_DATA: Q11.1 R48.2 U2.7
TON_1.2V: PRM07.2 PUM01.9
TOUCH_PANEL_PD#: RC1146.2 RC1147.1 UC1.L27
TOUCH_SCREEN_INT#: JEDP1.24 RC203.2 UC1.H41
TOUCH_SCREEN_PD#: D5.2 R19.2 RC1147.2
TOUCH_SCREEN_RST: JEDP1.25 RC117.2 UC1.F39
TP_CLK: C27.1 JTP1.1 R32.2 UE1.87
TP_DAT: C26.1 JTP1.2 R31.2 UE1.88
TP_EN#: R38.1 UE1.82
TS_EN: C16.1 JEDP1.39 R19.1
TSEN_VCCGI: PHZ2.1 PRG27.1 PUG1.16
TSEN_VNN: PHG2.1 PRZ30.1 PUZ1.16
UART_1_CTXD_GPIO_61: RC95.1 RC96.1 UC1.N54
UART_2_CRTS#_GPIO_66: RC91.2 UC1.K53
UART_2_CRXD_GPIO_64: RW10.2 T41.1(TP-1) UC1.M53
UART_2_CTXD_GPIO_65: RC108.2 RC109.2 RC148.2 RW9.2 UC1.L54
UART_2_CTXD_GPIO_65_R: RC148.1 T40.1(TP-1)
UG_1.2V: PQM01.1 PUM01.17
UG_CHG: PQB26.4 PUB01.11
UG_VCCGI: PRG44.1 PUG1.9
UG_VCCGI_R: PQG1.4 PRG44.2
UG_VNN: PQZ1.1 PUZ1.9
USB2_ID: RC76.1 UC1.V1
USB2_RCOMP: RC77.1 UC1.U12
USB2_VBUSSENSE: RC75.1 UC1.V3
USB3_CRX_DTX_N0: LU12.2 RU14.2 UC1.D15
USB3_CRX_DTX_N1: LU8.2 RU23.2 UC1.H11
USB3_CRX_DTX_P0: LU12.3 RU22.2 UC1.F15
USB3_CRX_DTX_P1: LU8.3 RU16.2 UC1.J11
USB3_CRX_L_DTX_N0: EU2605.1 EU2605.9 LU12.1 RU14.1 RU33.2
USB3_CRX_L_DTX_N0_R: JUSB1.5 RU33.1
USB3_CRX_L_DTX_N1: EU2606.1 EU2606.9 LU8.1 RU23.1 RU29.2
USB3_CRX_L_DTX_N1_R: JUSB2.5 RU29.1
USB3_CRX_L_DTX_P0: EU2605.2 EU2605.8 LU12.4 RU22.1 RU34.2
USB3_CRX_L_DTX_P0_R: JUSB1.6 RU34.1
USB3_CRX_L_DTX_P1: EU2606.2 EU2606.8 LU8.4 RU16.1 RU30.2
USB3_CRX_L_DTX_P1_R: JUSB2.6 RU30.1
USB3_CTX_C_DRX_N0: CU24.2 LU7.2 RU15.2
USB3_CTX_C_DRX_N1: CU16.2 LU11.2 RU13.2
USB3_CTX_C_DRX_P0: CU30.2 LU7.3 RU17.2
USB3_CTX_C_DRX_P1: CU29.2 LU11.3 RU20.2
USB3_CTX_DRX_N0: CU24.1 UC1.C15
USB3_CTX_DRX_N1: CU16.1 UC1.A14
USB3_CTX_DRX_P0: CU30.1 UC1.B15
USB3_CTX_DRX_P1: CU29.1 UC1.C14
USB3_CTX_L_DRX_N0: EU2605.4 EU2605.7 LU7.1 RU15.1 RU36.2
USB3_CTX_L_DRX_N0_R: JUSB1.8 RU36.1
USB3_CTX_L_DRX_N1: EU2606.4 EU2606.7 LU11.1 RU13.1 RU31.2
USB3_CTX_L_DRX_N1_R: JUSB2.8 RU31.1
USB3_CTX_L_DRX_P0: EU2605.5 EU2605.6 LU7.4 RU17.1 RU35.2
USB3_CTX_L_DRX_P0_R: JUSB1.9 RU35.1
USB3_CTX_L_DRX_P1: EU2606.5 EU2606.6 LU11.4 RU20.1 RU32.2
USB3_CTX_L_DRX_P1_R: JUSB2.9 RU32.1
USB20_N0: LU9.3 RU18.1 UC1.U5
USB20_N0_R: EU2608.3 JUSB1.2 LU9.4 RU18.2
USB20_N1: LU10.2 RU19.1 UC1.N3
USB20_N1_R: EU2607.3 JUSB2.2 LU10.1 RU19.2
USB20_N2: LU14.3 RU28.1 UC1.L3
USB20_N2_R: JIOB1.7 LU14.4 RU28.2
USB20_N3: JWLAN1.5 UC1.R15
USB20_N4: L3.4 R18.2 UC1.M3
USB20_N4_R: D11.2 JEDP1.33 L3.3 R18.1
USB20_N5: L4.4 R21.2 UC1.R3
USB20_N5_R: DA6.3 JEDP1.36 L4.3 R21.1 R84.2
USB20_N6: LU13.3 RU25.1 UC1.P3
USB20_N6_R: JIOB1.4 LU13.4 RU25.2
USB20_N7: EU2701.2 JFP1.6 UC1.U10
USB20_P0: LU9.2 RU21.1 UC1.U7
USB20_P0_R: EU2608.2 JUSB1.3 LU9.1 RU21.2
USB20_P1: LU10.3 RU24.1 UC1.N2
USB20_P1_R: EU2607.2 JUSB2.3 LU10.4 RU24.2
USB20_P2: LU14.2 RU27.1 UC1.L2
USB20_P2_R: JIOB1.6 LU14.1 RU27.2
USB20_P3: JWLAN1.3 UC1.R13
USB20_P4: L3.1 R17.2 UC1.M1
USB20_P4_R: D11.3 JEDP1.34 L3.2 R17.1
USB20_P5: L4.1 R20.2 UC1.R2
USB20_P5_R: DA6.2 JEDP1.37 L4.2 R20.1 R85.2
USB20_P6: LU13.2 RU26.1 UC1.P1
USB20_P6_R: JIOB1.3 LU13.1 RU26.2
USB20_P7: EU2701.3 JFP1.5 UC1.U8
USB20_VCC: CU32.1 JIOB1.13 JIOB1.14 JIOB1.15 JIOB1.16 UU3.1
USB30_VCCA: CU17.1 CU18.1 CU19.1 CU20.1 CU22.1 CU25.1 CU26.1 CU28.1 JUSB1.1 JUSB2.1 UU2.1
USB_EN#: RE30.2 UE1.84 UU2.4 UU3.4
USB_OC0#: RC80.2 UC1.U54 UU2.3
USB_OC1#: RC79.2 UC1.U53 UU3.3
VCIN0_PH1: PH1.1 PR9.2 UE1.109
VCIN1_AC_IN: CE20.2 RE21.1 UE1.110
VCIN1_BATT_TEMP: CE17.2 PC14.1 PD6.2 PR39.2 PR41.1 PRB24.2 UE1.63
VCIN1_BATT_TEMP_R: PBATT1.5 PR39.1
VCLK_VCCGI: PRG09.1 PUG1.6
VCLK_VNN: PRZ11.1 PUZ1.6
VCOUT0_MAIN_PWR_ON: CE4.1 PR507.1 UE1.104
VCOUT1_PROCHOT#: CE3.1 CE21.2 RE19.1 UE1.103
VL: PC515.1 PU501.15
VLP_DIS: CE37.2 RE54.1 U15.4 UE1.116
VNN_EN: PRZ40.2 UE1.86
VNN_N01: PRZ16.2 PRZ35.1
VNN_N02: PLZ1.2 PRZ42.1
VNN_N03: PRZ15.2 PRZ36.1
VNN_N04: PRZ17.2 PRZ37.1
VNN_N05: PRZ03.2 PRZ07.1
VNN_N06: PRZ31.2 PRZ38.1
VNN_N07: PHZ1.2 PRZ39.1
VNN_N08: PRZ21.2 PRZ24.1
VNN_N09: PCZ08.2 PRZ40.1 PUZ1.2
VNN_N10: PRZ04.2 PRZ08.1
VNN_N11: PRZ02.2 PRZ41.1
VNN_N13: PHG2.2 PRZ29.2 PRZ30.2 PRZ31.1
VNN_N14: PRZ28.2 PRZ29.1
VNN_N15: PCZ13.2 PRZ25.2 PUZ1.13
VNN_N16: PCZ10.2 PRZ22.1
VNN_SENSE: PRZ43.2 UC1.AJ41
VNN_SENSE_N: PRZ01.1 UC1.AJ43
VNN_VGATE: CE8.1 PRZ34.1 PUZ1.7 UE1.85
VR_HOT#: PRG25.2 PRZ20.2 PUG1.3 PUZ1.3 RE20.1
VREF_VCCGI: PRG01.1 PRG02.1 PRG03.1 PRG24.1 PRG28.1 PRG29.2 PUG1.17
VREF_VNN: PRZ02.1 PRZ03.1 PRZ04.1 PRZ21.1 PRZ22.2 PRZ28.1 PUZ1.17
VSEN_VCCGI: PCG04.1 PCG08.1 PCG11.2 PRG18.2 PRG19.1 PRG43.1 PUG1.25
VSEN_VNN: PCZ05.2 PCZ17.1 PCZ18.1 PRZ10.2 PRZ12.1 PRZ43.1 PUZ1.25
VTTREF_1.2V: PCM19.1 PUM01.4
WHITE_LED_BAT: C41.1 Q19.1 R69.2
WLAN_PWR_EN: QW1.3 UE1.1
WLAN_RADIO_DIS#: RW3.2 UC1.H43
WLAN_RADIO_DIS#_R: JWLAN1.56 RW3.1 RW27.1
WOL_EN: RL6.2 UE1.98 UL2.4
XCLKI: RE31.2 UE1.122 YE1.3
XDP_PBTN_OUT#: CC92.2 RC142.2 T53.1(TP-1) UC5.1
XDP_PLTRST#_B_R: RC48.2 UC6.2
XDP_PLTRST#_R: RC140.2 T38.1(TP-1) UC6.4
XDP_PRDY#: RC155.1 T46.1(TP-1) UC1.AH55
XDP_PREQ#: RC114.2 T51.1(TP-1) UC1.AJ53
XDP_RSMRST#_B_R: RC47.2 UC7.2
XDP_RSMRST#_R: RC141.2 T36.1(TP-1) UC7.4
XDP_TCK0: RC115.1 T42.1(TP-1) UC1.AM53
XDP_TDI: RC111.1 T43.1(TP-1) UC1.AJ54
XDP_TDO: RC156.2 T48.1(TP-1) UC1.AL53
XDP_TMS: RC112.1 T47.1(TP-1) UC1.AL54
XDP_TRST#: CC22.1 RC113.1 RC116.1 T45.1(TP-1) UC1.AK53
N72123: PCZ15.1 PRZ33.1 PUZ1.1
N17003752: JDIMM1.134 RD23.2
N17389450: PC516.2 PD501.2 PR502.2 PR503.2 PR506.2 PR508.1
N17415515: PJP2.1 PJPDC1.1 PJPDC1.2 PL2.1
N18009640: QG1.3 RG102.2 RG103.2 RG104.2 RG105.2 RG106.2 RG107.2 RG108.2 RG109.2
N18855880: R57.2 U1.3
N21380741: PC508.1 PU501.16 PU501.17
N21599913: RL7.2 UL2.3
N22038366: C967.2 U11.12
N22038385: C976.2 U11.10
N23005873: RL17.1 UL1.26
N23133643: PDB01.1 PRB15.1
N28483977: PQ13.2 PR31.2 PR35.2 PR45.1
N28484391: PC13.1 PQ12.6 PR33.2
N28484416: PQ12.2 PR36.2 PR44.2
N28484439: PC14.2 PQ11.2 PR43.1
N28484451: PQ13.5 PQ13.6 PR34.2 PR38.1
N28484500: PC13.2 PQ12.5 PR40.1
N28866422: PRB02.3 PRB12.1
N28866508: PCB13.1 PRB31.1 PRB32.1
N28866577: PCB11.1 PRB30.2
N28866613: PRB02.2 PRB11.1
N29056076: PQB28.2 PQB29.1
N29179188: PCB01.1 PQB03.3 PQB11.1 PQB11.2 PQB11.3 PQB12.1 PQB12.2 PQB12.3 PRB03.1 PRB08.1
N29179461: PCB70.1 PQB12.5 PRB02.1
N29179506: PQB11.4 PRB06.1
N29179534: PCB01.2 PQB03.1 PQB12.4 PRB06.2 PRB07.1
N35174703: PQB33.1 PRB42.2 PRB43.1
N35174707: PCB36.1 PQB32.2 PRB43.2
N36068621: QC3.1 RC93.2
N36974075: T9.1(TP-1) UC1.AH53
N36975833: T32.1(TP-1) UC1.C52
N37347070: T6.1(TP-1) UC1.D1
N37347073: T7.1(TP-1) UC1.D2
N37348861: RC54.1 UC3.4
N37471844: RC25.1 UC1.J25
N37471848: RC18.2 UC1.L13
N38547614: DI1.3 RI13.2
N38547616: DI1.2 RI14.2
N38557843: JWLAN1.6 T12.1(TP-1)
N38557881: JWLAN1.16 T13.1(TP-1)
N38557883: JWLAN1.44 T15.1(TP-1)
N38557885: JWLAN1.46 T16.1(TP-1)
N38557887: JWLAN1.48 T17.1(TP-1)
N38557915: RW18.2 T14.1(TP-1)
N38572293: RW6.2 UW1.3
N38572305: QW1.1 RW5.2 UW1.4
N38577962: JSSD1.54 T34.1(TP-1)
N38577990: JSSD1.10 R77.1
N38604520: RA32.2 UA1.10
N38605656: CA487.2 RA50.1
N38607202: CA478.1 RA31.2 RA48.1
N38607812: DA10.2 RA52.1
N38607828: DA10.3 RA53.1
N38612980: QS1.5 QS1.6 RS62.2
N38638766: LED1.4 R68.1
N38638768: LED1.2 R69.1
N38639135: Q25.5 Q25.6 R79.2
N38653708: PRH05.2 PUH01.7
N38657718: C18.1 Q12.3 R35.2
N38657720: C18.2 Q12.2 Q13.2 R38.2
N38657736: Q13.1 R37.1
N38658993: DC4.2 UC1.F41
N38736705: RC33.2 UC1.AL5
N38858837: RC40.2 T30.1(TP-1)
N38886483: RE5.2 UE1.38
N38915222: RE25.1 UE1.125
N38916474: CE23.2 RE26.1
N38916969: CC3.1 RC37.2
N38993155: PRG21.2 PRG45.1
N38993903: PRZ42.2 PRZ44.1
N39173777: PCH10.1 PUH01.9
N39173785: PCH11.1 PRH11.2 PUH01.11
N39200796: PRM06.2 PUM01.10
N39291721: PQ13.3 PR32.2
N39387882: JSSD1.8 R300.1
N39393826: PQB03.2 PRB03.2 PRB04.1
N39399976: F1.2 R301.1
N39406703: PRB31.2 PUB01.29
N39614986: RC157.1 UC1.AV29
N39655859: PD501.1 PR507.2
N39906676: JDB1.3 RB1.2
N39906689: JDB1.5 RB2.2
N39906706: JDB1.7 RB3.2
N39906735: JDB1.17 RB5.2
N39906737: JDB1.13 RB4.2
N39906754: JDB1.19 RB6.2
N39906812: JDB1.4 RB7.1
N39906827: JDB1.6 RB8.1
N39906848: JDB1.8 RB9.1
N39906878: JDB1.14 RB10.1
N39956795: CC93.2 RC139.1 RC143.2 RC144.1
N40664383: JDIMM1.165 T10.1(TP-1)
N40775614: CM28.1 RM32.2 UM3.13 UM3.14
N40775618: CM29.1 UM3.12
N40775624: CM11.1 RM33.1 UM3.8 UM3.9
N40775687: CM30.1 UM3.10
N40892116: RE42.1 UE1.64
N40978125: RE53.2 U15.3
N41027888: RC40.1 UC1.AV27
N41527020: JDIMM1.162 T11.1(TP-1)
N48572179: PCH14.2 PRH12.1
N124752685: CD30.2 RD11.1
N392641980: T1.1(TP-1) UC1.C32
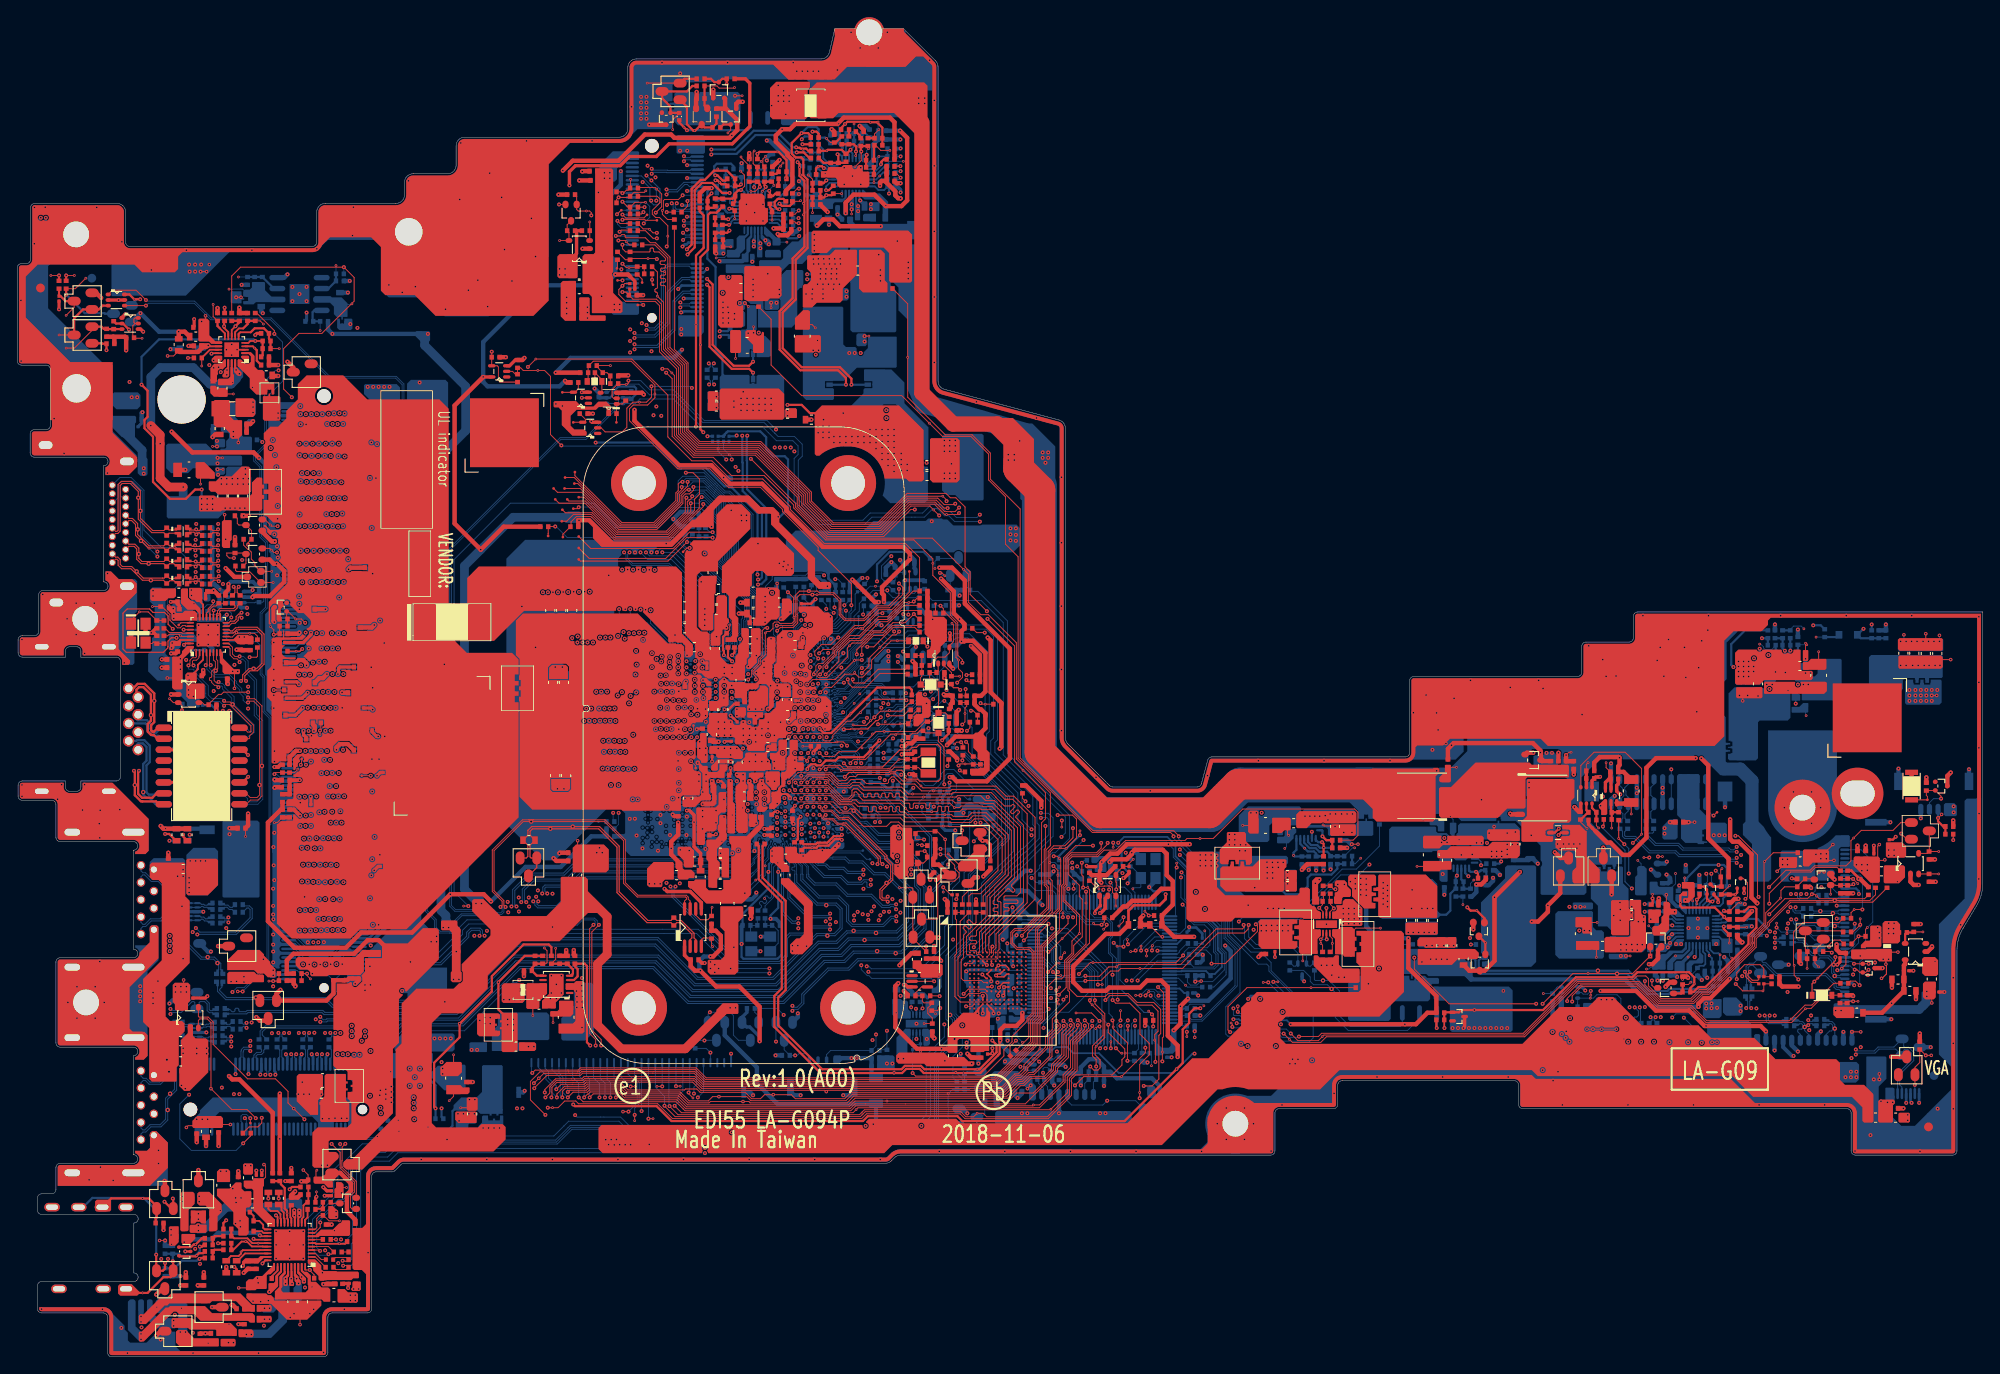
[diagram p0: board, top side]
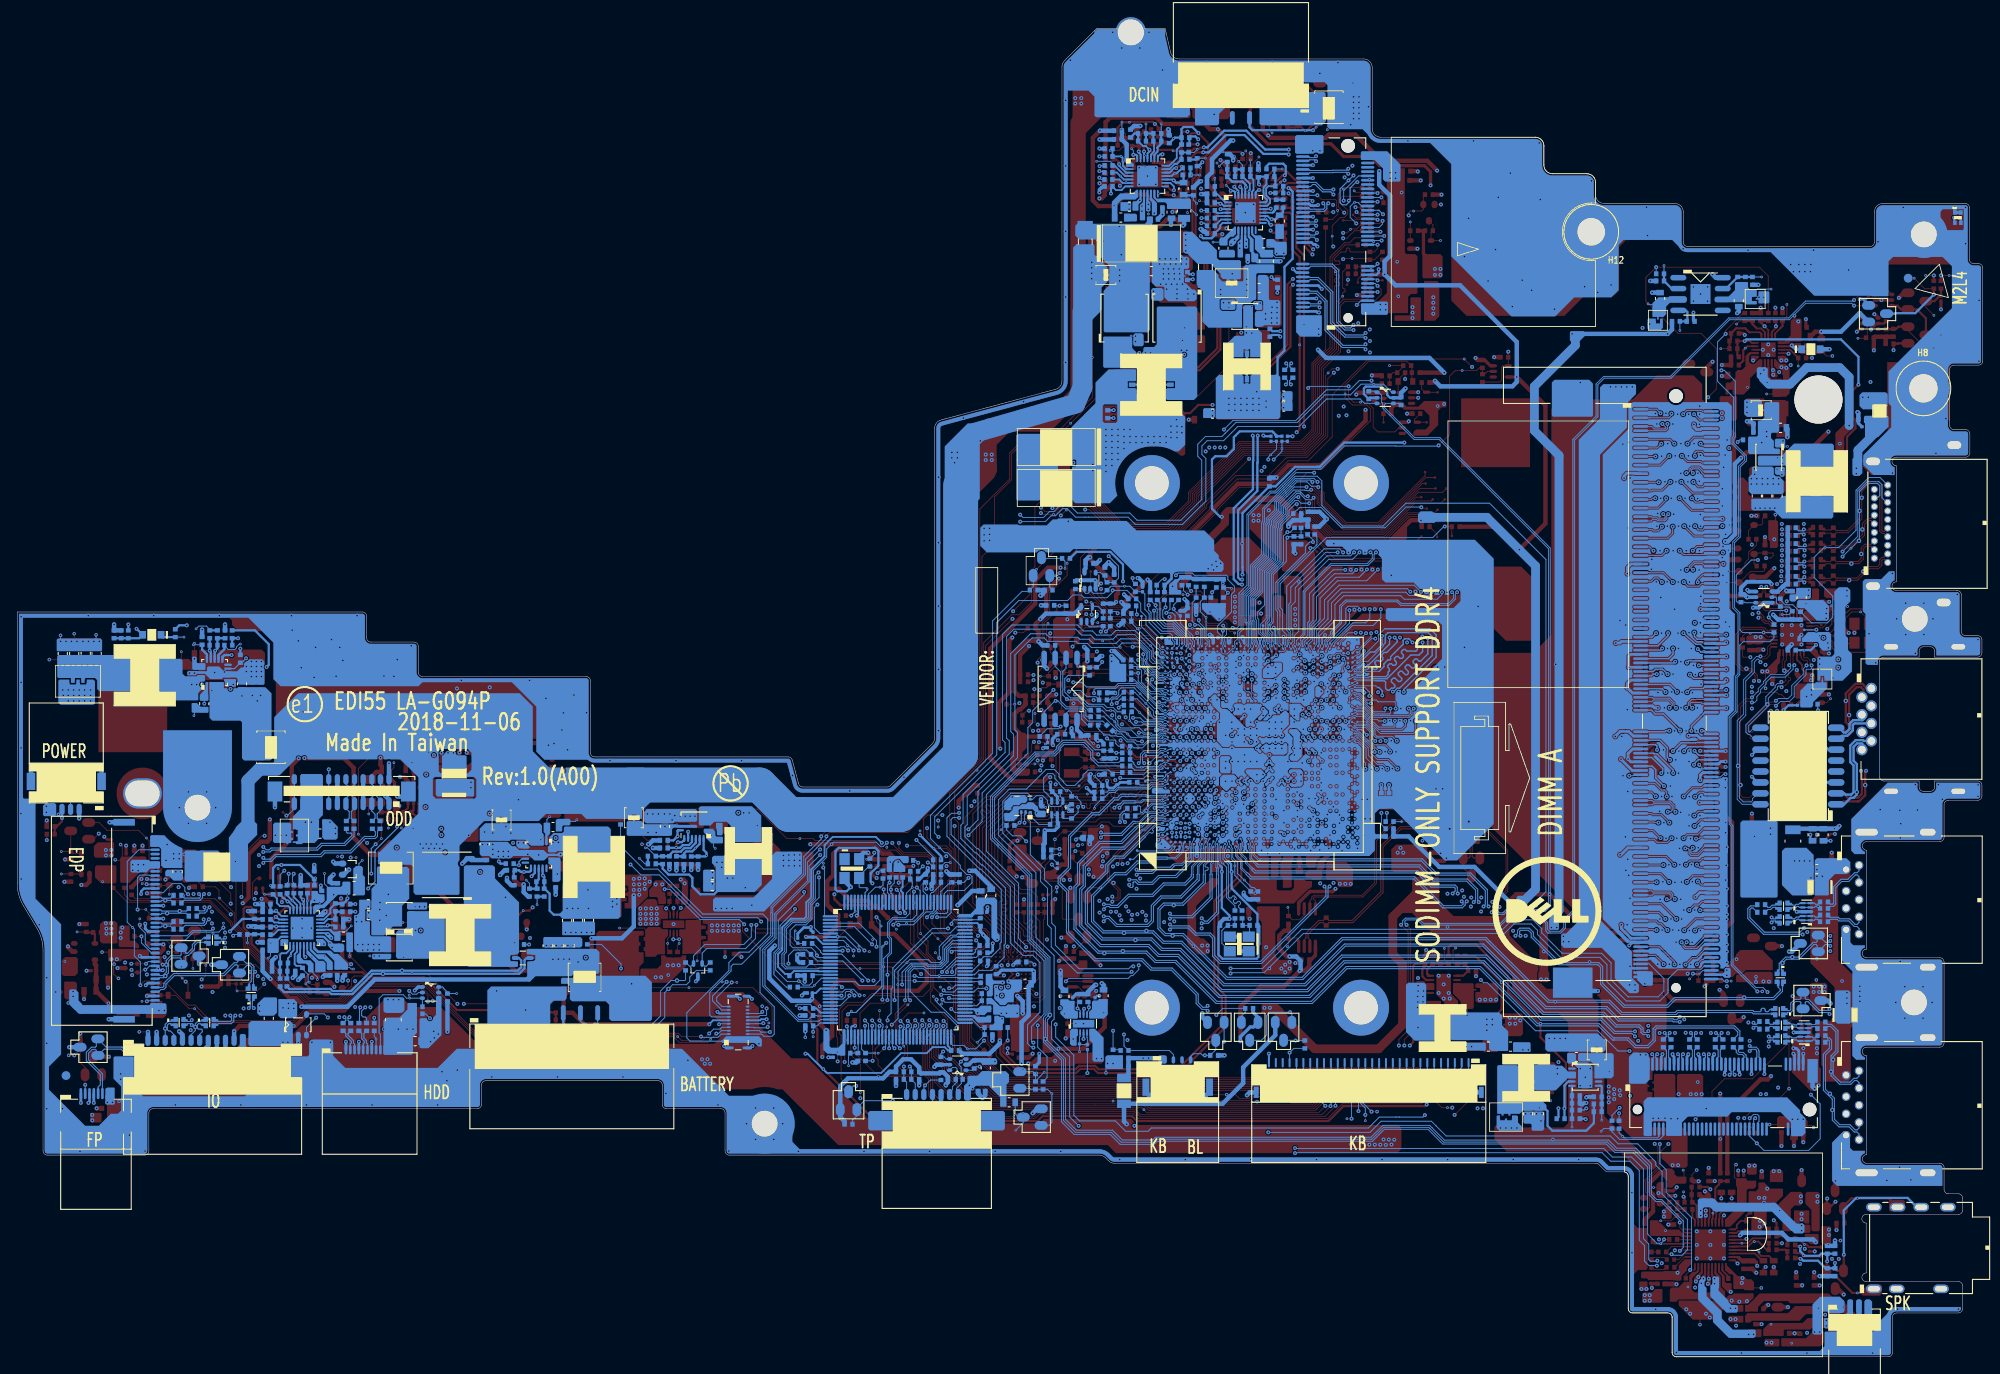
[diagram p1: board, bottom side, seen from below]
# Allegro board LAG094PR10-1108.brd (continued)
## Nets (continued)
Pads without a net: D14 3; DC6 3; DD1 3; DD2 3; ED2901 2; EU4012 2; FD1 1; FD2 1; FD3 1; FD4 1; JDB1 18 20; JDIMM1 87 88 91 92 95 97 100 101 104 105; JEDP1 5 6 9; JHDMI1 13 14; JKB1 28 29; JKBBL1 3; JSSD1 6 20 22 24 26 28 30 32 34 36 38 40 42 44 46 48 56 58 67 68 69; JWLAN1 8 12 20 42 58 60 62 66 68 70; PD1 3; PD6 3; PJPDC1 4; PU301 10 15; PU501 10; PU1201 1 7; PU1801 1 7; PU2501 1 5; PUB01 30; PUG1 14 15; PUZ1 14 15; TL1 4 5 12 13; TL2 4 5 12 13; U14 3; UC1 A4 A38 A53 A54 AA8 AA10 AA39 AA41 AA44 AA46 AA49 AA51 AA53 AC5 AC7 AC10 AC12 AC39 AC41 AC43 AC44 AC46 AC48 AC49 AC51 AE2 AE3 AE5 AE7 AE8 AE10 AE15 AE17 AE44 AE49 AE51 AG2 AG3 AG5 AG7 AG8 AG10 AG12 AG13 AG15 AG17 AG43 AG44 AH1 AH3 AJ2 AJ3 AJ5 AJ7 AJ10 AJ12 AJ15 AJ17 AJ49 AL2 AM3 AN2 AN5 AN7 AN12 AN13 AN15 AN17 AP1 AP3 AR3 AR5 AR8 AR13 AR15 AT1 AT3 AU2 AU5 AU7 AU8 AU12 AU13 AU15 AV1 AV3 AV19 AV21 AW3 AW7 AW8 AW44 AY1 AY3 AY17 AY19 AY21 AY23 B17 B19 B23 B25 B43 B47 BA2 BA3 BA5 BA7 BA8 BA10 BA17 BA19 BA21 BA23 BB3 BC2 BC3 BC7 BC8 BC13 BC15 BC27 BD1 BD3 BD11 BD13 BD17 BD23 BD25 BD27 BE2 BE5 BE7 BF1 BF2 BF11 BF13 BF15 BF17 BF21 BF23 BF25 BF27 BG2 BG4 BG54 BH1 BH2 BH5 BH6 BH9 BH15 BH21 BH27 BH54 BH55 BJ4 BJ5 BJ6 BJ8 BJ9 BJ10 BJ11 BJ12 BJ13 BJ14 BJ16 BJ17 BJ18 BJ20 BJ21 BJ22 BJ23 BJ24 BJ26 BJ27 BJ42 BK9 BK11 BK13 BK15 BK19 BK23 BK25 BK27 BL2 BL3 BL6 BL12 BL16 BL18 BL20 BL22 BL26 BL44 BL53 BL54 C2 C3 C17 C19 C24 C25 C26 C39 C43 C46 C54 D43 F37 H27 H53 H55 L21 L23 L25 L29 L35 L39 L48 L49 L51 L53 M21 M23 M33 M39 M55 N8 N10 N44 N48 N49 N53 P23 P25 P33 P35 P37 P53 R41 R43 R44 R46 R48 R49 R51 R53 R54 U15 U43 U46 U48 U49 U51 V53 W12 W13 W53 W54 Y53 Y55; UC6 1; UC7 1; UC8 1; UC12 1; UE1 2 26 28 92 117 118 119 120 123 126 127 128; UM1 A1 A2 A7 A8 A9 A10 A11 A12 A13 A14 B1 B7 B8 B9 B10 B11 B12 B13 B14 C1 C3 C5 C7 C8 C9 C10 C11 C12 C13 C14 D1 D2 D3 D4 D12 D13 D14 E1 E2 E3 E5 E8 E12 E13 E14 F1 F2 F3 F12 F13 F14 G1 G2 G3 G10 G12 G13 G14 H1 H2 H3 H12 H13 H14 J1 J2 J3 J12 J13 J14 K1 K2 K3 K6 K7 K10 K12 K13 K14 L1 L2 L3 L12 L13 L14 M1 M2 M3 M7 M8 M9 M10 M11 M12 M13 M14 N1 N3 N6 N7 N8 N9 N10 N11 N12 N13 N14 P1 P2 P7 P8 P9 P10 P11 P12 P13 P14; UM2 1; YE1 1

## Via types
v1: diameter 0.305, hole 0.152, TOP to BOTTOM, 457 vias
v2: diameter 0.457, hole 0.203, TOP to BOTTOM, 3545 vias
v3: diameter 0.406, hole 0.203, TOP to BOTTOM, 156 vias
v4: diameter 0.508, hole 0.254, TOP to BOTTOM, 50 vias

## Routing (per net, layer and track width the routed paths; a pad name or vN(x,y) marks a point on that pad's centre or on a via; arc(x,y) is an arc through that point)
1.8V_PRIM_EN: length 112.2
  TOP w0.102: v2(61.65,28.96) v1(62.2,28.96) 62.85,28.96 63.62,29.74 64.91,29.74 65.22,29.42 74.41,29.42 76.14,27.69 98.12,27.69 98.68,28.25 109.56,28.25 110.13,27.68 119.8,27.68 122.5,30.38 122.5,32.29 122.99,32.77 127.22,32.77 128.37,33.92 128.37,34.54 128.7,34.87 128.7,35.79 126.78,37.7 v2(126.78,38.61)
  IN1 w0.127: v2(61.65,28.96) 60.73,28.96 59.84,28.08 53.9,28.08 53.15,28.82 50.9,28.82 50.15,28.08 48.18,28.08 47.72,27.62 v2(46.14,27.62)
  BOTTOM w0.102: v2(126.78,38.61) 126.04,39.35 126.04,44.82 124.69,46.17 122.52,46.17 122.19,45.84 121.19,45.84 120.84,46.2 120.84,47.68 119.7,48.82 UE1.90
  BOTTOM w0.254: v2(46.14,27.62) 46.2,27.68 PR1808.1
3.3V_TS_EN: length 3.3
  TOP w0.102: R72.1 v1(221.45,49.4)
  TOP w0.254: U14.4 219.38,49.13 R5220.2 220.32,49.33 R72.1
3VS_ON: length 2.9
  TOP w0.102: R927.1 151.79,53.81 151.79,53.16 151.68,53.06 C980.2 151.68,52.59 v2(151.29,52.19) 151.73,51.75 U11.5
5VS_ON: length 3
  TOP w0.102: U11.3 152.53,51.72 152.94,52.13 v2(152.99,52.13) 152.99,52.21 152.61,52.59 C979.2 152.61,53.02 152.47,53.16 152.47,53.74 R926.2
+0.6V_DDR_VTT: length 64.2
  IN1 w0.762: 30.82,108.33 31.27,107.88 31.27,88.13 28.93,85.79 28.93,62.17 28.67,61.92 28.67,45.33
  vias: v2(29.74,44.95) v2(29.74,44.36) v2(30.32,109.72) v2(30.32,109.15) v3(28.61,46.22)
+0.6V_M0_VREFDQ: length 2.5
  TOP w0.089: v2(77.64,72.04) 78.05,72.45 78.32,72.45 78.56,72.7 78.56,73.38 T3.1
  BOTTOM w0.254: UC1.AY31 77.95,72.35 v2(77.64,72.04)
+0.6V_M1_VREFDQ: length 1.6
  TOP w0.089: T4.1 78.84,68.71 v2(78.3,69.25)
  BOTTOM w0.089: UC1.AY25 v2(78.3,69.25)
+0.6VSP:
  vias: v1(27.34,112.71)
+1.2V_DDR: length 59.9
  TOP w0.508: CD14.1 v2(29.82,83.05)
  BOTTOM w0.305: JDIMM1.141 38.37,75.68 38.14,75.45 v2(37.76,75.45) ; JDIMM1.123 v2(41.14,80.18) 41.14,80.18 41.14,81.46 40.93,81.68 JDIMM1.117 ; JDIMM1.54 v2(30.26,97.43) ; v2(34.19,72.21) 34.14,72.26 33.2,72.26 32.87,71.93 JDIMM1.148 ; v2(29.82,76.93) JDIMM1.136 ; JDIMM1.154 v2(29.89,70.43) ; v2(33.39,53.47) 32.89,53.97 32.16,53.97 32.11,53.93 JDIMM1.220 ; JDIMM1.111 41.98,83.18 42.16,82.99 v2(42.64,82.99) ; JDIMM1.178 v2(32.89,64.43) ; JDIMM1.129 40.9,78.68 41.31,78.27 v2(41.31,77.78) 40.97,77.44 40.95,77.44 40.69,77.18 JDIMM1.135 ; JDIMM1.147 40.61,72.18 41.14,72.71 42.13,72.71 v2(42.71,72.13) ; JDIMM1.160 30.74,68.93 30.67,68.99 30.65,68.99 30.43,69.21 30.13,69.21 30.13,69.21 v2(29.89,69.21) ; JDIMM1.124 v2(29.82,79.93) ; v2(29.82,83.05) 29.94,82.93 JDIMM1.112 ; JDIMM1.159 40.9,69.18 v2(41.22,69.5) 41.22,70.13 40.67,70.68 JDIMM1.153 ; v2(42.14,58.36) 42.05,58.36 41.24,59.18 JDIMM1.199 ; v2(42.04,69.49) 40.73,68.18 JDIMM1.163 ; JDIMM1.33 40.25,102.68 40.31,102.74 41.36,102.74 41.68,102.42 v2(41.68,102.17) ; JDIMM1.75 40.89,92.18 41.3,91.76 v2(41.3,91.05) ; JDIMM1.241 40.9,48.68 42,49.78 v2(42,50.22) ; JDIMM1.142 v2(29.82,75.43) ; JDIMM1.130 30.06,78.43 v2(29.82,78.67) ; JDIMM1.118 v2(29.82,81.43) ; JDIMM1.96 v2(32.79,86.93) ; JDIMM1.12 32.68,107.93 32.79,107.82 33.26,107.82 33.56,108.12 v2(33.56,108.4)
  vias: v3(49.63,80.51)
+1.2V_DDR_SOC: length 2.5
  BOTTOM w0.254: v2(76.79,69.28) UC1.BA25 ; v2(76.86,65.01) UC1.BA15 ; UC1.BA31 v2(76.88,72.97)
  BOTTOM w0.305: v2(76.86,65.01) 76.86,64.8 UC1.BA13
  vias: v2(76.88,77.38) v2(79.05,75.35) v2(79.22,67.69) v2(79.22,66.92) v2(80,75.31) v2(80,74.55) v3(60.23,82.48)
+1.2V_DSI: length 8.4
  TOP w0.381: v2(77.81,63.51) 78.13,63.51 78.65,62.99 v3(78.65,62.16) 78.65,59.3 79.41,58.54 CC28.2 RC131.2
  BOTTOM w0.254: UC1.AW12 v2(77.81,63.51)
+1.2V_GLML: length 13.7
  TOP w0.254: v2(82.19,75.28) 82.68,75.28 83.33,75.93 CC44.2
  TOP w0.508: 76.87,57.53 75.99,58.41 v3(75.99,59.11) 75.99,59.89 76.81,60.7 v2(76.81,62.1)
  IN2 w0.508: v2(76.81,62.1) 78.27,62.1 78.77,62.61 78.77,63.94 79.09,64.26 v2(79.66,64.26)
  BOTTOM w0.254: UC1.AL38 v2(82.19,75.28) UC1.AL36 ; UC1.AP20 v2(80.73,66.93) UC1.AM20
+1.2V_MPHY:
  vias: v1(84.3,63.81) v2(83.63,67.7) v2(84.35,67.68) v2(84.35,66.95)
+1.2V_PLL: length 6.6
  TOP w0.254: v2(81.45,66.93) 81.82,66.93 82.08,66.67 CC48.2
  IN1 w0.508: v2(82.14,62.77) 82.14,63.68 81.45,64.37 v2(81.45,66.93)
  BOTTOM w0.254: UC1.AM18 v2(81.45,66.93) UC1.AL18
  vias: v1(81.89,59.94)
+1.2V_SOC:
  vias: v3(84.55,53.91)
+1.2V_USB2: length 1.1
  BOTTOM w0.254: UC1.AJ20 v2(82.9,66.93) 83.08,66.74 83.27,66.55 UC1.AG18
  vias: v1(83.09,62.99)
+1.2V_VNNAON: length 1
  BOTTOM w0.229: UC1.AA20 v2(86.52,66.93) 86.29,66.69 86.16,66.56 UC1.AA18
  vias: v1(86.58,66.42)
+1.2VP: length 71.6
  TOP w0.203: v2(25.43,114.74) 25.33,114.85 PUM01.19 ; PRM10.2 v2(27.66,118.11) 27.09,118.11 26.87,117.89 PUM01.5
  TOP w0.254: v2(14.45,113.03) 15.15,112.33 15.15,109.28 14.79,108.92 14.79,107.96 15.78,106.97 15.78,101.72 17.75,99.75 19.59,99.75 20.67,100.83 v2(21.43,100.83) ; PCM18.1 28.52,116.44 PCM17.2 PRM10.2
  TOP w1.016: v2(19.29,101.13) 17.62,101.13 16.61,102.14 v3(16.61,106.17) 16.61,107.19 v2(15.53,108.27)
  BOTTOM w0.254: v2(14.45,113.03) 14.45,116.26 16.48,118.3 27.47,118.3 v2(27.66,118.11) ; v2(21.43,99.75) v2(21.43,100.83)
  BOTTOM w1.016: 25.5,113.72 24.86,113.09 22.39,113.09 20.46,115.01 16.63,115.01 15.53,113.92 v2(15.53,108.27) ; v2(19.29,101.13) 19.29,98.78 PLM01.1
  vias: v2(21.43,99.12) v2(21.43,98.55) v2(22.07,99.75) v2(22.07,99.12) v2(22.07,98.55) v2(22.7,99.75) v2(22.7,99.12) v2(22.7,98.55) v2(24.16,98.67) v2(24.74,98.67) v2(25.31,98.67) v2(25.82,114.3) v2(25.88,98.67) v2(26.45,98.67)
+1.05VS: length 134.5
  TOP w0.508: v2(102.65,134.68) 102.62,134.7 102.37,134.7 102.04,135.03 102.04,135.5 101.02,136.51 PCG09.1 ; PCG09.1 101,136.71 100.44,136.71 100.26,136.53 v2(100.26,136.15) ; PCG09.1 PRG04.1 PRG05.1 ; PRZ06.1 PRZ05.1 PCZ03.1 88.91,131.2 v2(87.89,131.2)
  IN1 w0.508: v2(87.89,131.2) 87.71,131.38 87.71,134.63 88.62,135.53 88.62,137.69 87.94,138.36 87.94,140.76 93.29,146.11 99.04,146.11 100.97,144.18 100.97,138.26 100.26,137.55 v2(100.26,136.15) ; v2(106.27,97.15) 106.4,97.28 106.4,107.9 102.65,111.65 v2(102.65,134.68)
  IN2 w3.048: 119.1,95.31 119.1,70.52 119.49,70.13 119.49,70.03 126.02,63.5 140.54,63.5
  BOTTOM w0.305: RC59.1 95.09,89.34 95.08,89.35 RC61.1 95.03,89.72 94.27,90.48 94.27,91.07 94.14,91.2 94.14,91.24
  vias: v2(88.55,92.26) v2(89,91.88) v2(89.1,92.48) v2(89.39,91.48) v2(89.57,92.07) v2(90.01,91.63) v2(115.41,96.32) v2(115.41,95.63) v2(115.41,94.93) v2(116.05,96.32) v2(116.05,95.56) v2(116.05,94.86) v2(140.84,59.52) v2(140.85,60.74) v2(140.85,60.1) v2(141.49,60.74) v2(141.49,60.1) v2(141.47,59.52) v2(142.13,59.52) v2(142.06,58.83) v2(142.69,58.83) v2(142.77,59.52) v3(86.08,94.55)
+1.05VS_SOC_FHV0: length 1.5
  TOP w0.254: v2(83.07,81.58) 83.35,81.85 RC134.2
  BOTTOM w0.254: UC1.AG51 v2(83.07,81.58)
+1.05VS_SOC_FHV1: length 2.6
  TOP w0.254: RC136.2 82.59,82.59 82.59,81.34 v2(83.07,80.87)
  BOTTOM w0.254: v2(83.07,80.87) UC1.AG49
+1.05VS_SOC_FUSE: length 4.5
  TOP w0.102: v1(82.8,85.09) 82.8,84.53 82.44,84.17 RC135.2
  TOP w0.254: RC135.2 82.01,83.7 82.01,82.16 82.12,82.06 v2(82.12,81.58)
  BOTTOM w0.254: UC1.AJ51 v2(82.12,81.58)
+1.05VS_SOC_SRAM: length 1.6
  TOP w0.102: 88.3,89.34 v3(88.3,89.91)
  BOTTOM w0.305: UC1.AF27 84.35,70.71 v2(84.35,70.74) 84.35,70.76 UC1.AF28
  vias: v2(85.07,75.31) v2(85.07,73.79) v2(85.79,75.31) v2(86.52,75.31) v2(86.9,88.39) v2(86.9,87.79) v2(86.9,87.18) v2(86.9,86.58) v2(86.9,85.97) v2(86.9,85.4)
+1.05VSP: length 9.8
  BOTTOM w0.254: PCH14.1 154.17,57.3 153.41,57.3 PRH08.2 153.4,56.75 152.71,56.07 150.33,56.07 149.94,55.68 149.94,54.69 149.03,53.78 147.42,53.78 146.97,54.22
  vias: v2(145.22,57.51) v2(145.25,56.9) v2(145.25,56.27) v2(145.25,55.66) v2(145.86,57.49) v2(145.88,56.9) v2(145.88,56.27) v2(145.88,55.66) v2(146.49,57.49) v2(146.54,56.9) v2(147.1,57.49) v3(143.8,54.54)
+1.8V_AVDD: length 27.4
  TOP w0.102: RA35.2 33.8,21.15 v3(33.24,21.71)
  TOP w0.508: v2(33.01,20.4) 33.64,20.4 RA35.2
  IN2 w0.508: v2(33.01,20.4) 33.01,18.47 32.5,17.97 31.78,17.97 31.15,17.33 31.15,16.06 30.77,15.68 28.36,15.68 26.2,13.52 24.61,13.52 22.96,11.87 22.96,9.14 23.78,8.31 27.21,8.31 27.58,7.95 28.9,7.95 v2(29.29,7.55)
+1.8V_CPVDD: length 17.6
  TOP w0.102: 37.75,19.68 v1(38.26,19.68)
  IN2 w0.508: v2(26.22,10.57) 26.22,10.82 27.53,12.12 34.14,12.12 37.69,15.67 v2(37.69,19.05)
+1.8V_DVDDIO:
  vias: v1(36.86,14.66)
+1.8V_EMMC: length 21.9
  TOP w0.152: UM1.C6 113.2,45.64 v2(113.28,45.56) ; UM1.M4 v2(112.2,41.97) ; UM1.P3 UM1.N4
  TOP w0.508: RM2.2 108.62,35.81 v3(107.41,35.81) 104.56,35.81 102.04,38.32 102.04,43.1 v2(102.37,43.43)
  IN2 w0.508: v2(112.2,41.97) 112.2,43.64 112.94,44.38 112.94,44.4 113.28,44.75 v2(113.28,45.56)
  BOTTOM w0.508: RM33.2 102.17,43.23 v2(102.37,43.43) ; v2(111.57,39.94) 111.57,41.33 v2(112.2,41.97)
+1.8V_PRIM: length 516.7
  TOP w0.254: 67.87,94.41 67.94,94.48
  TOP w0.305: v2(206.21,55.63) 206.27,55.57 RT28.2 ; RE13.1 129.13,51.87 129.76,52.51 132.75,52.51 133.45,53.21 v2(133.45,53.78)
  TOP w0.381: RW23.2 RW22.2 71.76,125.05 71.22,125.6 ; v2(54.15,113.93) UC12.5
  TOP w0.457: RC140.1 v2(66.9,109.66)
  TOP w0.508: v2(106.57,37.02) 106.57,37.05 106.33,37.28 RM27.1 ; v2(54.15,113.93) 50.83,110.6 50.83,96.88 v2(53.86,93.85) 56.53,96.52 RC156.1 ; v2(108.04,71.12) 109.03,72.11 111.53,72.11 112.51,73.08 RW7.2 112.51,74.77 112,75.27 111.82,75.27 111.25,75.84 RC104.2 RC106.2 112,76.84 112.51,77.35 112.51,81.83 111.08,83.25 110.12,83.25 110.04,83.18 v2(109.72,83.18) 109.72,84.36 RW8.2 110.07,85.21 v2(109.51,85.77) 108.83,86.44 108.83,88.99 v2(107.35,90.47) ; v2(65.28,97.25) 65.2,97.16 RC155.2 ; RC141.1 63.85,113.28 v2(63.66,113.47) ; RC6.1 109.17,74.98 v2(109.41,75.22) ; 67.94,94.48 75.98,94.48 78.27,96.77 ; 71.22,125.6 70.98,125.84 v2(69.5,125.84) ; PRG25.1 101.94,143.54 101.41,144.08 96.05,144.08 95.31,143.34 90.41,143.34 89.8,142.73 v2(88.88,142.73) 88.15,142 88.15,141.28 89.52,139.91 89.52,139.7 90.08,139.14 90.08,136.34 89.32,135.57 PRZ20.1 ; RE13.1 128.08,49.17 126.49,49.17 122.7,45.39 122.7,43.58 123.73,42.55 126.51,42.55 126.89,42.93 130.47,42.93 131.29,43.75 132.94,43.75 133.7,42.98 133.7,37.33 134.84,36.19 v2(134.84,34.86)
  TOP w0.762: 80.48,98.53 81.7,99.75 84.87,99.75 86.2,98.42 87.66,98.42
  TOP w1.016: 65.88,53.84 68.55,51.18 68.55,46.79 67.43,45.68 67.43,38.58 70.2,35.81 77.63,35.81 82,40.18
  IN1 w0.305: v2(133.45,53.78) 133.77,54.1 134.78,54.1 135.49,54.1 136.05,54.1 136.75,53.4 147.91,53.4 151.52,49.79 152.67,49.79 153.51,48.95 159.04,48.95 160.82,50.73 165.17,50.73 168.48,54.03 171.38,54.03 173.16,55.81 177.88,55.81 178.03,55.96 178.13,56.07 181.27,56.07 181.71,56.07 183.26,57.62 187.71,57.62 189.44,55.89 190.53,55.89 191.3,56.65 192.06,56.65 192.69,57.28 194.22,58.81 198.04,58.81 199.28,60.05 201.22,60.05 205.63,55.63 v2(206.21,55.63)
  IN1 w0.508: v2(109.72,83.18) 109.65,83.26 105.59,83.26 105.08,82.75 105.08,82.29 104.57,81.78 103.6,81.78 103.22,81.4 103.2,81.4 103.19,81.4 102.69,81.4 102.68,81.4 102.41,81.4 v2(102.33,81.48) ; v2(104.12,66.15) 103.49,66.15 102.84,66.8 101.93,66.8 v2(101.75,66.98) 101.75,68.05 102.08,68.38 102.08,71.24 102.48,71.65 v2(102.84,71.65) 103.07,71.65 103.16,71.56 106.74,71.56 107.22,71.08 108,71.08 v2(108.04,71.12) ; v2(107.35,90.47) 106.89,90.47 106.47,90.9 102.2,90.9 101.66,90.36 100.1,90.36 v2(99.91,90.17) 98.89,89.15 98.84,89.15 98.78,89.09 94.65,89.09 v2(94.14,89.59) ; v2(66.9,109.66) 64.8,109.66 63.66,110.8 v2(63.66,113.47)
  IN2 w0.508: v2(110.91,34.09) 110.91,33.52 111.41,33.02 117.7,33.02 118.31,33.63 120.14,33.63 120.75,33.02 133.32,33.02 134.84,34.54 v2(134.84,34.86) ; v2(88.88,142.73) 87.28,144.33 77.19,144.33 74.96,142.11 73.19,142.11 70.14,139.06 v2(70.14,137.85) ; v2(106.57,37.02) 106.57,35.64 v2(107.79,34.41) ; v2(108.04,71.12) 108.09,71.16 108.09,71.85 108.79,72.56 108.79,74.57 108.81,74.59 108.81,74.62 v2(109.41,75.22)
  BOTTOM w0.254: v2(99.91,90.17) 99.91,92.12 101.38,93.59 105.3,93.59 RC93.1 ; RC173.1 RC171.1 82.2,107.16 82.2,107.25 82.43,107.48 82.43,107.48 82.56,107.6 86.34,107.6 86.88,107.07 87.03,106.91 87.03,105.53 87.85,104.71 89.19,104.71 89.57,104.33 89.57,98.61 88.62,97.66 v2(88.43,97.66)
  BOTTOM w0.305: v2(104.12,66.15) 103.63,65.65 RC9.2 RC110.1 ; v2(101.75,66.98) 101.75,66.34 101.53,66.12 101.04,66.12 100.63,66.53 100.49,66.53 100.22,66.8 RC8.2
  BOTTOM w0.381: RC7.1 102.19,71.26 102.19,71.41 102.43,71.65 v2(102.84,71.65) ; v2(108.04,71.12) 108.1,71.18 108.1,71.72 108.1,71.72 108.1,71.84 RC31.2
  BOTTOM w0.508: v2(63.66,113.47) 63.03,112.83 54.66,112.83 54.15,113.34 v2(54.15,113.93) 54.15,117.99 60.74,124.58 68.23,124.58 69.49,125.84 v2(69.5,125.84) 69.5,127.38 68.87,128.01 68.87,135 70.14,136.27 v2(70.14,137.85) ; RC34.1 103.02,71.83 v2(102.84,71.65) ; RC32.2 109.27,82.72 v2(109.72,83.18) ; RC30.2 102.89,81.1 102.51,81.48 v2(102.33,81.48) ; RC114.1 79.21,97.91 79.22,97.9 RC113.2 ; v2(109.51,85.77) 108.87,86.41 RC101.2 105.52,86.41 104.76,87.17 UC8.5 ; RC113.2 79.24,97.27 79.96,97.27 RC111.2 79.99,97.28 80.15,97.28 80.64,96.79 80.64,96.74 80.68,96.7 v2(80.68,96.52) ; RC113.2 78.89,97.29 78.85,97.33 CC96.2 78.39,97.26 78.46,97.2 RC112.2
  BOTTOM w1.016: 63.85,97.61 57.62,97.61 v2(53.86,93.85) 51.97,91.95 51.97,54.36 53.37,52.95
  vias: v2(53.31,52.7) v2(53.95,52.7) v2(54.14,26.6) v2(54.77,26.6) v2(55.41,26.6) v2(56.04,26.6) v2(82.84,40.57) v2(83.47,40.57) v2(102.4,34.67) v2(102.98,34.67) v3(49.69,41.27) v3(49.95,25.27) v3(62.2,49.97)
+1.8VALW_SOC: length 1.6
  TOP w0.102: 65.12,59.43 v3(65.12,60)
  BOTTOM w0.254: UC1.AJ23 82.54,68.85 v2(82.91,69.22) 83.27,68.86 UC1.AG23
  vias: v2(67.34,58.61) v2(67.66,59.18) v2(67.98,58.61) v2(87.96,69.22) v2(88.01,68.46)
+1.8VALWP: length 12.4
  TOP w0.102: PC1804.1 v1(51.53,28.95)
  BOTTOM w0.254: PC1802.1 50.96,28.95 50.58,28.57 50.58,26.86 50.01,26.28 46.07,26.28 45.2,27.16 PC1807.1 PR1807.1
  vias: v2(52.55,29.9) v2(53.18,29.9)
+1.8VS: length 9.1
  TOP w0.102: RA35.1 34.72,21.6 v1(34.82,21.7)
  TOP w0.508: RA65.1 39.29,15.92 38.31,16.9 38.31,18.86 38.79,19.34 38.79,20.13 37.54,21.38 QA2.3
+1.24VALW: length 23.3
  IN1 w0.508: v2(85.79,66.93) 85.79,66.72 82.84,63.76 82.84,60.96 81,59.11 81,58.03 82.84,56.19 82.84,48.06 v2(83.28,47.62)
  BOTTOM w0.229: UC1.AC20 v2(85.79,66.93) 85.79,66.92 85.59,66.7 UC1.AC18
  vias: v2(53.76,39.11) v2(54.33,39.43) v2(54.33,38.73) v2(54.96,39.43) v2(54.96,38.73) v2(80.55,45.91) v2(80.55,45.14) v2(81.06,45.59) v2(81.06,44.7) v2(81.5,45.14) v3(82.9,45.14)
+1.24VALW_PG: length 104.4
  TOP w0.254: v2(64.61,29.33) 64.8,29.14 74.3,29.14 76.03,27.41 98.28,27.41 98.84,27.97 109.25,27.97 109.83,27.4 128.67,27.4 v3(134.72,33.45) 135.43,34.16 135.43,38.07 136.18,38.82 136.18,39.89 136.81,40.52 v2(137.47,40.52) ; PU1201.4 64.69,43.8 65.12,44.23 65.12,45.08 64.8,45.4 PR1201.2 65.95,45.7 66.2,45.45 66.2,36.57 v2(66.58,36.19)
  IN1 w0.254: v2(66.58,36.19) 66.58,32.52 64.61,30.55 v2(64.61,29.33)
  BOTTOM w0.254: RE8.1 137.46,40.51 v2(137.47,40.52)
+1.24VALWP: length 10.4
  TOP w0.254: PC1206.1 PR1204.1 58.97,46.62 v3(55.91,43.56) 55.91,40.38 56.49,39.81
  vias: v2(56.99,39.24) v2(56.99,38.6) v2(57.63,39.24) v2(57.63,38.6) v2(57.63,37.97)
+2.5V_MEM: length 105
  TOP w0.102: v2(25.43,123.19) v3(26.01,123.19)
  TOP w0.508: v2(39.27,43.36) 39.71,43.81 CD4.1 CD3.1 38.56,43.99 38.38,43.81 38.03,43.81 CD2.1 CD1.1 36.75,42.25 35.93,41.42 DD2.2 30.13,42.21 v2(30.58,42.67)
  IN1 w0.508: v2(29.46,105.66) 29.34,105.53 29.34,101.82 29.18,101.66 29.18,90.86 30.01,90.04 30.01,88.2 28.16,86.36 28.16,62.67 27.71,62.22 27.71,43.81 29.17,42.35 30.26,42.35 v2(30.58,42.67)
  IN2 w0.508: v2(25.43,123.19) 28.86,123.19 32.17,119.88 32.17,114.42 29.09,111.35 29.09,106.03 v2(29.46,105.66)
+2.5VP: length 2
  BOTTOM w0.102: v1(24.61,124.14) 26.2,124.14 26.39,123.95 26.58,123.95
+3.3V_WLAN:
  vias: v2(68.23,137.66) v2(68.23,137.03) v2(68.87,137.66) v2(68.87,137.03) v2(69.38,122.36) v2(69.38,121.72) v2(70.01,122.36) v2(70.01,121.72) v3(67.53,135.38) v3(67.92,123.31) v3(68.04,127.31)
+3V_DVDD: length 10.4
  TOP w0.102: v2(34.77,18.6) v1(34.77,19.17)
  TOP w0.305: RA40.2 34.65,18.49 v2(34.77,18.6)
  IN1 w0.305: v2(35.47,9.77) 34.69,10.55 34.69,18.52 v2(34.77,18.6)
+3V_EMMC: length 12.1
  TOP w0.152: UM1.J10 114.68,43 v2(114.66,42.98) ; v2(114.57,42) 114.7,42.13 UM1.K9 ; v2(113.17,43.67) 113.17,44.03 UM1.F5 UM1.E6
  IN1 w0.508: v2(113.17,43.67) 112.6,43.67 112.35,43.42 108.51,43.42 107.16,44.76 v2(107.16,44.89)
  BOTTOM w0.508: v2(107.16,44.89) 107.16,43.05 RM32.1
  vias: v1(107.1,44.25)
+3VALW: length 342.1
  TOP w0.381: 183.42,61.08 183.36,61.15 183.35,61.15 183.03,61.47 183.03,61.48 182.58,61.92 PR33.1 ; Q17.2 v2(11.78,122.87) Q17.5 ; UW1.5 64.61,127.89 64.99,128.27 64.99,130.75 RW5.1 RW6.1 ; PR5.2 84.62,148.59 85.12,148.08 85.12,143.06 83.09,141.03 75.74,141.03 74.27,139.56 71.14,139.56 70.07,138.49 64.87,138.49 64.17,137.79 v2(64.17,136.2)
  TOP w0.508: PRB42.1 198.87,57.92 196.5,60.28 196.5,68.77 v2(195.69,69.58) ; v2(64.68,47.29) 64.68,46.74 PR1201.1 ; RA41.2 29.69,28.38 25.82,32.25 24.99,32.25 v2(24.61,32.63) ; RC213.2 v2(221.08,37.59) ; v2(114.17,70.71) 114.35,70.89 RC120.2 114.35,76.04 113.11,77.27 113.11,83.28 v2(112.77,83.62) ; v2(119,63.85) 119,64.63 117.2,66.43 RC138.2 ; v2(149.28,56.62) 149.46,56.8 149.46,56.85 149.82,57.21 149.87,57.21 149.94,57.29 PRH05.1 ; v2(195.03,69.6) 190.43,69.6 189.31,68.49 189.31,60.37 187.29,58.35 186.57,58.35 185.14,59.79 184.72,59.79 183.42,61.08 ; RM1.1 103.92,46.92 v2(102.52,45.52) ; RC168.1 RC175.1 RC169.1 RC170.1 ; v2(161.65,48.66) 161.65,45.19 164.91,41.94 PR41.2 163.86,40 162.53,38.67 v3(161.25,38.67) v2(147.99,38.67) ; PRM06.1 v2(23.28,121.94)
  TOP w1.016: 91.92,48.67 91.92,52.64 90.06,54.5
  IN1 w0.508: v2(11.78,122.87) 13.24,124.33 22.39,124.33 23.28,123.44 v2(23.28,121.94) 23.28,121.22 23.78,120.71 38.07,120.71 v2(38.71,120.07) ; v2(48.48,37.02) 45.37,37.02 44.23,35.87 44.23,28.95 44.94,28.24 46.88,28.24 48.24,29.6 48.76,29.6 49.31,29.05 v2(49.31,28.89) ; v2(225.01,63.3) 225.65,62.67 225.65,51.94 223.11,49.4 223.11,39.62 v2(221.08,37.59) ; v2(112.77,83.62) 112.72,83.62 112.68,83.59 112.18,83.59 112.14,83.62 111.08,83.62 109.93,84.77 109.65,84.77 108.67,85.75 v2(106.37,85.75) 105.22,85.75 101.53,82.06 v2(101.23,82.06)
  IN1 w1.016: 196.53,69.83 221.4,69.83 224.9,66.33 224.9,64.93
  IN2 w1.016: 194.06,69.58 189.8,69.58 188.51,68.3 185.72,68.3 185.56,68.13 184.84,68.13 184.68,68.3 183.46,68.3 181.52,66.35 177.77,66.35 176.4,64.98 158.12,64.98 156.27,63.13 156.27,59.72
  BOTTOM w0.203: v2(147.99,38.67) 147.53,39.12 145.71,39.12 JDB1.11
  BOTTOM w0.254: v2(49.31,28.89) 49.31,27.88 PR1803.1 ; 115.05,47.24 115.31,46.97 RE30.1
  BOTTOM w0.305: 115.05,47.24 v2(115.05,48.06)
  BOTTOM w0.381: v2(102.65,135.38) 102.65,135.69 102.44,135.9 102.4,135.9 102.22,136.08 PRG34.2 ; R35.1 109.64,34.23 v2(109.64,35.24)
  BOTTOM w0.508: RC176.1 100.91,82.06 v2(101.23,82.06) ; v2(119.14,52.52) 119.09,52.52 117.45,54.16 RE4.2 ; v2(149.28,56.62) PRH03.1 ; v2(161.65,48.66) 158.14,48.66 156.75,50.05 v2(156.75,53.65) ; PRZ34.2 90.38,130.84 90.57,130.84 90.79,131.07 90.79,131.07 90.84,131.12 v2(90.89,131.12)
  vias: v2(19.91,77.53) v2(19.91,76.96) v2(20.48,76.77) v2(23.91,75.12) v2(23.91,74.48) v2(23.91,73.85) v2(24.63,75.1) v2(24.63,74.47) v2(24.63,73.83) v2(49.12,37.02) v2(49.75,37.02) v2(50.39,37.02) v2(56.55,41.52) v2(57.18,41.52) v2(57.82,41.52) v2(58.45,41.52) v2(63.03,126.49) v2(63.03,125.79) v2(63.66,126.49) v2(63.66,125.79) v2(90.08,47.81) v2(90.08,47.18) v2(90.71,47.81) v2(105.7,36.95) v2(137.46,58.35) v2(137.46,57.72) v2(137.46,57.08) v2(138.1,58.35) v2(138.1,57.72) v2(138.1,57.08) v2(138.73,58.35) v2(138.73,57.72) v2(138.73,57.08) v2(139.37,58.29) v2(139.37,57.72) v2(139.37,57.08) v2(145.32,52.13) v2(145.96,52.13) v2(146.59,52.13) v2(147.23,52.13) v2(154.91,55.24) v2(155.48,55.62) v2(155.48,54.99) v2(155.48,54.41) v2(156.12,55.62) v2(156.12,54.92) v2(156.12,54.29) v2(156.12,53.72) v2(156.75,55.56) v2(156.75,54.92) v2(156.75,54.29) v2(225.01,64) v3(91.73,47.75) v3(143.04,52.51)
+3VALW_1.8V:
  vias: v1(43.4,33.14)
+3VALW_1.24V: length 1.3
  TOP w0.102: PC1204.1 v1(59.91,39.68)
+3VALW_2.5V: length 1.4
  BOTTOM w0.102: v1(38.9,122.42) 38.81,122.33 PC2501.1
+3VALW_EC: length 88.1
  TOP w0.508: v2(136.75,48.83) 134.43,48.83 133.02,50.24 ; 133.02,50.24 RE12.1 ; 133.02,50.24 RE25.2 134.27,52.56 134.27,54.41 ; 134.27,54.41 134.27,55.3 133.57,56 133.57,58.48 133.13,58.92 133.12,58.92 133.09,58.94 129.87,58.94 129.85,58.92 129.83,58.92 v2(129.51,58.61) 129.51,58.44 128.91,57.84 127.26,57.84 v2(126.95,57.53) ; 134.27,54.41 132.94,54.41 131.54,53.02 129.55,53.02 128.89,52.36 128.55,52.36 RE41.2 ; v2(134.4,37.97) 135.16,38.73 v3(135.16,40.75) v2(136.04,41.63)
  IN1 w0.508: v2(113.91,43.51) 113.91,43.51 114.72,44.31 114.72,46.99 114.31,47.39 114.31,48.29 v2(114.52,48.51) ; v2(136.75,48.83) 139.35,48.83 v2(140.37,47.81)
  IN2 w0.381: 115.22,40.83 115.22,43.3 114.84,43.68 114.08,43.68 113.91,43.51 v2(113.91,43.51)
  IN2 w0.508: v2(134.4,37.97) 133.19,39.17 131.51,39.17 130.93,39.75 119.03,39.75 117.95,40.83 115.22,40.83 115.22,39.78 114.74,39.3 v2(113.95,39.3)
  BOTTOM w0.203: UE1.9 134.8,48.02 135.57,48.79 CE13.1 ; CE11.1 135.59,42.3 135.08,42.82 UE1.22
  BOTTOM w0.305: v2(136.75,48.83) 136.71,48.79 CE13.1
  BOTTOM w0.381: v2(136.04,41.63) 136,41.67 CE11.1
  BOTTOM w0.457: v2(129.51,58.61) 130.08,58.61 130.57,58.12 YE1.4
  BOTTOM w0.508: v2(140.37,47.81) 141,47.18 141,44 138.4,41.4 136.28,41.4 v2(136.04,41.63)
+3VALW_SOC: length 157.5
  TOP w0.254: CC84.2 82.9,67.8 v2(82.9,68.45)
  TOP w0.508: v2(107.16,91.75) 108.62,91.75 110.12,90.25 110.12,87.57 115.35,82.33 115.35,69.59 112.67,66.91 109.16,66.91 108.68,67.39 v2(108.37,67.39) ; v2(97.05,90.36) 99.65,87.75 v2(100.1,87.75) ; RC145.1 v2(62.58,114.42)
  IN1 w0.508: v2(77.25,117.09) 78.52,115.82 78.52,114.1 79.03,113.6 79.03,111.32 82.36,107.98 86.67,107.98 87.73,106.93 89.11,106.93 89.36,107.18 90.42,107.18 91.79,105.82 91.79,105.67 91.79,105.67 91.79,105.3 91.79,104.88 91.79,104.81 91.18,104.2 91.18,99.21 93.01,97.38 93.01,94.5 97.05,90.46 v2(97.05,90.36) 97.94,91.24 101.29,91.24 101.84,91.79 106.8,91.79 106.83,91.75 v2(107.16,91.75) ; v2(62.58,114.42) 62.6,114.41 v2(62.6,110.79) ; v2(108.37,67.39) 107.69,67.39 107.03,66.73 107.03,64.49 v2(106.51,63.97) 105.2,65.27 103.16,65.27 102.33,66.1 100.43,66.1 99.6,66.92 99.6,70.42 99.09,70.92 97.47,70.92 97.41,70.99 97.38,70.99 96.49,71.88 95.35,71.88 94.59,71.12 88.8,71.12 88.36,70.67 88.36,69.85 88.87,69.34 88.87,68.51
  IN2 w0.508: v2(87.24,66.93) 87.24,66.69 86.84,66.29 82.65,66.29 82.23,66.7 82.23,67.78 82.9,68.44 v2(82.9,68.45)
  BOTTOM w0.254: UC1.AG21 83.27,68.08 v2(82.9,68.45) UC1.AJ21
  BOTTOM w0.305: RC90.2 106.04,63.51 106.3,63.76 106.31,63.76 v2(106.51,63.97) 106.32,63.97 106.27,64.02 106.26,64.02 106.02,64.26 105.9,64.26 RC89.2
  BOTTOM w0.457: RC46.2 96.74,90.05 v2(97.05,90.36)
  BOTTOM w0.508: v2(100.1,87.75) 99.66,87.31 RC45.2 99.86,86.75 RC43.2 ; v2(77.25,117.09) 76.3,116.14 64.3,116.14 v2(62.58,114.42)
  vias: v2(87.71,58.81) v2(87.71,58.22) v2(87.99,66.91) v3(63.34,110.55)
+3VALWP: length 64.3
  IN2 w0.254: v2(167.29,55.94) 167.84,55.39 168.83,55.39 168.86,55.43 168.88,55.43 169.2,55.75 169.2,56.02 169.03,56.18 169.03,57.31 169.74,58.02 170.72,58.02 171.15,57.59 v2(172.44,57.59) 173.06,57.59 175,59.54 175,60.41 179.04,64.45 183.69,64.45 183.79,64.55 184.64,64.55 184.79,64.7 185.11,64.7 185.74,64.7 185.74,64.7 188.06,64.7 190.47,67.11 195.05,67.11 198.18,70.25 198.18,81.42 199.09,82.33 v2(202.47,82.33)
  BOTTOM w0.254: PC316.1 164.53,51.4 166.05,51.4 166.53,51.87 166.53,53.84 167.12,54.43 PR306.2 167.15,54.44 PR307.1 167.15,55.8 v2(167.29,55.94) 167.35,56 PU301.14 ; PR504.1 v2(202.47,82.33) ; PR304.1 172.24,57.34 172.44,57.53 v2(172.44,57.59)
  vias: v2(158.72,55.11) v2(158.72,54.48) v2(158.72,53.91) v2(158.72,53.27) v2(158.72,52.64) v2(159.23,54.8) v2(159.23,54.22) v2(159.23,53.59) v2(159.23,52.95) v2(159.23,52.32) v2(162.02,52.13) v2(163.23,52.13) v2(163.86,52.13) v2(164.5,52.13) v3(162.09,54.29)
+3VLP: length 78.5
  TOP w0.381: v2(126.03,57.53) 125.89,57.39 CE35.2 125.89,56.64 125.77,56.51 U15.5
  TOP w0.508: v2(111.63,55.75) 111.24,55.75 110.59,55.1 110.55,55.1 DC1.2 ; v2(126.03,57.53) 127.01,58.5 127.85,58.5 128.94,59.6 v3(133.77,59.6) v2(136.24,59.6) ; RE53.1 124.87,56 U15.5 ; v2(125.97,55.13) 125.77,55.33 U15.5 ; RE54.2 126.57,56 U15.5
  IN1 w0.508: v2(165.64,56.13) 166.44,55.33 166.44,53.11 164.85,51.52 160.5,51.52 158.72,49.74 153.83,49.74 153.39,50.19 153.39,50.34 152.3,51.43 151.1,51.43 148.15,54.38 139.07,54.38 136.05,57.4 136.05,59.41 v2(136.24,59.6)
  IN2 w0.508: v2(125.97,55.13) 124.87,55.13 124.83,55.17 121.04,55.17 120.53,55.68 118.94,55.68 118.12,56.51 v2(117.76,56.51) 116.59,56.51 116.45,56.65 112.17,56.65 111.66,56.14 111.66,55.78 v2(111.63,55.75)
  BOTTOM w0.508: RE43.2 115.22,54.64 117.09,56.51 v2(117.76,56.51)
+3VS: length 394.1
  TOP w0.305: v2(213.97,55.56) 213.97,55.68 213.13,56.52 R5.1
  TOP w0.406: C21.1 78.08,46.16 77.54,46.69 U2.1
  TOP w0.457: v2(29.89,68.58) 30.32,68.58 30.58,68.84 RD3.1 ; RL3.1 24.19,88.86 24.55,89.21 v2(24.55,89.85)
  TOP w0.508: R5216.1 11.29,118.47 11.16,118.6 ; R80.1 11.16,118.6 ; 11.16,118.6 12.54,118.6 R79.1 v2(12.66,117.03) ; v2(100.71,87.76) 100.71,88.55 100.49,88.77 100.49,89.49 103.73,92.73 v2(103.73,92.96) 103.73,93.4 102.97,94.17 93.61,94.17 89.38,98.4 89.38,98.67 86.55,101.51 82.81,101.51 v2(82.09,102.23) 80.66,103.65 76.91,103.65 71.73,108.83 v2(71.73,110.1) ; RC1151.2 v2(56.78,116.23) ; v2(110.83,82.64) 111.87,81.6 RC203.1 RC117.1 ; v2(29.93,94.8) 29.94,94.8 29.94,94.81 29.57,94.81 28.48,95.9 Q57.2 ; RC3.2 RC2.2 104.38,80.55 v2(104.05,80.88) ; C21.1 78.25,45.4 78.76,44.89 v2(79.38,44.89) 81.22,43.05 83.92,43.05 86.27,40.7 v2(86.27,36.7) ; R100.1 215.1,54.62 214.16,55.56 v2(213.97,55.56) ; v2(208.44,54.52) 208.31,54.64 RT31.2 ; R28.1 R29.1 81.17,49.54 81.76,48.95 81.76,47.43 80.87,46.54 v2(80.55,46.54) ; v2(206.98,43.05) 205.09,43.05 R86.1 R87.1 ; v2(27.34,88.32) 27.47,88.45 29.37,88.45 31.02,90.1 31.02,91.37 30.2,92.2 v2(30.13,92.2) 29.82,92.2 29.32,92.69 Q58.2 ; R57.1 v2(222.92,55.23) ; R5221.1 v2(217.84,42.92) ; 42.71,47.75 42.01,48.45 40.73,48.45 39.14,46.86 32.09,46.86 31.33,46.09 RD2.1 RD1.1 ; v2(28.1,104.52) 27.47,105.15 20.35,105.15 v2(17.94,107.56)
  IN1 w0.305: v2(40.41,42.6) 39.36,41.55 34.86,41.55 30.77,45.64 30.77,67.93 30.64,68.07 30.13,68.58 v2(29.89,68.58)
  IN1 w0.508: v2(110.83,82.64) 110.83,82.98 109.67,84.13 109.39,84.13 108.78,84.74 105.36,84.74 104.43,83.82 v2(104.43,82.54) ; v2(110.27,44.81) 110.02,44.81 109.51,45.32 109.51,46.54 109.76,46.79 109.76,59.18 109,59.94 v2(109,61.21) 109,61.27 109.96,62.23 v2(109.96,63.24) 109.38,63.24 108.34,64.28 v2(108.34,66.76) ; v2(213.08,33.14) 211.93,34.29 180.69,34.29 178.41,36.57 v2(178.41,37.78) ; v2(121.83,33.71) 121.74,33.63 117.98,33.63 117.26,34.35 v2(114.78,34.35) ; v2(217.84,42.92) 217.51,42.59 209.07,42.59 208.61,43.05 v2(206.98,43.05) ; v2(28.1,104.52) 27.47,105.15 27.47,106.61 29.37,108.52 29.37,110.92 29.56,111.11 29.56,111.12 32.23,113.79 39.71,113.79 v2(40.73,112.77)
  IN2 w0.457: v2(30.13,92.2) 30.62,92.2 31.08,92.65 31.08,94.36 30.62,94.81 29.94,94.81 29.94,94.8 v2(29.93,94.8)
  IN2 w0.508: v2(17.94,107.56) 15.15,110.36 15.15,114.54 v2(12.66,117.03) ; v2(115.73,45.41) 114.79,46.35 111.82,46.35 110.28,44.81 v2(110.27,44.81) ; v2(104.43,82.54) 104.43,83.82 105.13,84.51 105.13,91.56 v2(103.73,92.96)
  IN2 w1.016: 39.34,8.69 39.34,19.11 36.8,21.65
  BOTTOM w0.254: v2(40.98,45.4) 40.76,45.18 JDIMM1.255 ; Q11.5 68.87,111.5 69.22,111.85 69.22,112.17 69.86,112.81 71.7,112.81 71.92,112.6 71.92,111.93 R48.1
  BOTTOM w0.305: v2(108.34,66.76) 108.32,66.76 108.32,65.92 RC83.1 107.74,65.34 107.74,65.32 107.58,65.16 107.56,65.16 107.54,65.13 QC2.5 ; R48.1 71.2,111.5 Q11.2
  BOTTOM w0.356: QC2.2 107.54,62.24 107.46,62.16 RC84.1
  BOTTOM w0.381: v2(109,61.21) 107.84,61.21 107.46,61.59 RC84.1 ; RE38.1 114.47,44.5 114.02,44.95 112.35,44.95 112.31,45 110.45,45 v2(110.27,44.81) ; RE39.1 115.59,45.55 v2(115.73,45.41) ; Q11.5 67.67,111.5 R49.1 ; R24.1 84.79,40.05 84.22,39.48 Q6.2 84.76,38.35 85.12,38.35 86.27,37.21 v2(86.27,36.7) ; v2(100.71,87.76) 100.72,87.75 100.75,87.75 100.92,87.57 RC121.2 RC4.2 ; R33.1 121.05,33.97 Q10.5
  BOTTOM w0.432: v2(27.34,88.32) QG1.5
  BOTTOM w0.457: UC2.5 104.38,91.55 104.25,91.68 CC4.1 ; v2(24.55,89.85) 24.81,90.11 27.39,90.11 28.1,89.4
  BOTTOM w0.508: v2(111.69,34.09) 111.69,38.9 110.88,39.71 110.88,43.07 RM29.1 110.27,43.68 v2(110.27,44.81) ; RC119.2 82.79,102.23 v2(82.09,102.23) ; v2(121.83,33.71) 121.59,33.96 R33.1 ; v2(79.38,44.89) 79.27,45 79.27,46.03 79.78,46.54 v2(80.55,46.54) ; v2(29.93,94.8) 29.93,94.8 29.91,94.81 29.61,94.81 28.8,95.63 28.8,103.82 v2(28.1,104.52) ; 28.1,89.4 RG47.1 27.73,88.65 27.4,88.32 v2(27.34,88.32) ; v2(103.73,92.96) 103.92,92.96 104.25,92.63 CC4.1 ; v2(109,61.21) 109,60.63 109,60.62 109,59.71 109.15,59.56 RC1148.1 RC1146.1 ; v2(104.43,82.54) 104.05,82.16 v2(104.05,80.88) ; R49.1 67.6,112.07 v2(67.09,112.58) ; RS62.1 v2(178.41,37.78)
  vias: v2(35.4,22.27) v2(36.04,22.27) v2(39.09,7.88) v2(39.67,7.88) v2(40.41,43.24) v2(41.05,43.24) v2(41.36,112.77) v2(42,112.77) v2(42.13,30.41) v2(42.2,30.98) v2(42.63,112.77) v2(42.83,31.11) v2(42.83,30.54) v2(42.83,29.97) v2(43.27,112.77) v2(43.47,31.43) v2(43.47,30.79) v2(43.47,30.16) v2(43.47,29.59) v2(48.1,48.25) v2(48.73,48.89) v2(48.73,48.25) v2(63.85,123.19) v2(63.85,122.55) v2(63.85,121.92) v2(63.85,121.28) v2(144.56,50.16) v2(144.56,49.53) v2(145.13,50.16) v2(145.13,49.53) v2(145.77,50.16) v2(145.77,49.53) v2(146.4,50.16) v2(146.4,49.53) v2(147.04,50.16) v2(147.04,49.53) v2(147.67,50.16) v2(147.67,49.53) v2(212.44,32.51) v2(213.08,32.51) v2(213.71,33.14) v2(213.71,32.51) v2(217.46,58.92) v2(217.46,58.29) v2(217.47,50.41) v2(217.46,49.78) v2(217.46,49.21) v2(218.03,49.78) v2(218.03,49.21) v2(218.09,58.92) v2(218.09,58.29) v2(218.09,50.41) v2(219.68,28.13) v2(219.68,27.49) v3(45.69,45.91)
+3VS_CAM: length 5.5
  TOP w0.102: F5.2 217.34,47.05 v3(218.54,47.05)
  TOP w0.127: 217.14,46.1 v3(217.14,45.65) 217.2,45.59 217.2,44.51 216.7,44 v3(216.63,44)
  BOTTOM w0.305: JEDP1.29 213.94,46.45 214.09,46.6 v2(214.16,46.6)
  vias: v2(216.82,46.22) v2(217.46,46.22)
+3VS_OUT: length 1.1
  TOP w0.102: 149.39,47.18 v1(149.39,46.03)
+3VS_SSD: length 2.7
  TOP w0.102: CS42.1 v3(24.77,27.01) ; v3(19.66,26.67) 19.86,26.87 CS44.1
  vias: v2(20.86,27.62) v2(21.5,27.62) v2(22.13,27.62) v2(35.47,27.68) v2(36.23,27.68) v2(37.68,27.73) v2(38.31,27.73) v3(36.93,27.74)
+5V_AVDD: length 2.1
  TOP w0.102: v3(28.67,22.35) 28.86,22.16 28.86,20.89 28.51,20.53 CA49.1
+5V_HDD: length 3.4
  TOP w0.102: v3(182.41,38.1) v2(183.1,38.1) v3(184.12,38.1) v3(185.84,38.1)
+5V_HDMI: length 39.7
  TOP w0.102: 24.1,97.09 v3(24.1,97.91)
  TOP w0.508: DI1.1 25.24,90.67 v2(24.23,91.69)
  IN1 w0.508: v2(14.7,102.67) 14.77,102.61 14.77,97.28 19.53,92.51 19.53,87.94 20.25,87.22 20.97,87.22 22.19,88.45 25.94,88.45 26.45,88.96 26.45,90.1 25.94,90.61 25.31,90.61 v2(24.23,91.69) v2(24.23,95.05)
  BOTTOM w1.016: 14.51,104.2 14.51,105.41 12.61,107.31
  vias: v2(14.7,103.31)
+5V_KB_BL: length 6.9
  TOP w0.127: v2(96.94,34.73) v3(97.57,34.73)
  BOTTOM w0.508: 95.54,34.73 v2(96.94,34.73) EC3002.1 C34.1 99.27,32.94 F3.1
+5V_PVDD:
  vias: v1(34.26,8.12)
+5VALW: length 290.7
  TOP w0.102: 19.34,43.37 v3(19.34,43.81) ; v2(222.47,76.89) v3(223.05,76.89)
  TOP w0.203: U11.4 v2(152.13,52.18)
  TOP w0.508: v2(63.41,137.92) 64.55,139.06 69.87,139.06 72.92,142.11 75.98,142.11 76.36,141.73 82.77,141.73 83.04,141.99 v2(83.04,142.01) 83.66,142.63 83.66,143.82 82.36,145.13 PD3.3 ; v2(9.75,123.12) 9.17,123.71 Q19.3 ; PD2.3 82.25,146.28 PD3.3 ; v2(96.27,132.98) 96.27,134.21 97.19,135.12 99.6,135.12 100.94,133.79 102.75,133.79 103.41,134.45 103.41,141.73 v2(102.59,142.55) ; PD3.3 81.27,145.13 PR4.1 ; PRM05.2 v2(18.77,119.18) 19.47,119.18 PRM04.1
  TOP w1.016: 50.58,49.97 51.02,49.53 v3(51.02,47.11) 51.02,44.76
  IN1 w0.508: v2(47.72,118.93) 47.72,122.23 v2(63.41,137.92) ; v2(18.77,119.18) 26.01,119.18 26.77,119.95 35.61,119.95 v2(36.62,118.93) ; v2(104.49,36.95) 104.36,36.83 v2(99.39,36.83) ; v2(151.8,56.55) 151.9,56.45 151.9,52.41 v2(152.13,52.18) 152.72,52.77 153.44,52.77 v2(154.09,52.13) ; v2(83.04,142.01) 85.44,142.01 86.03,141.42 v2(87.1,141.42) 88.07,142.38 88.07,142.93 91.96,146.82 99.46,146.82 102.59,143.69 v2(102.59,142.55)
  IN1 w1.016: 50.95,42.92 50.95,39.18 53.18,36.95 55.72,36.95 58.01,34.67 58.01,29.78
  IN2 w0.508: v2(81.61,127.39) 80.48,127.39 80.3,127.57 79.79,128.07 79.79,137.78 83.04,141.03 v2(83.04,142.01) ; v2(98.59,26.86) 98.59,27.55 99.39,28.35 v2(99.39,36.83) ; v2(9.75,123.12) 10.64,122.23 13.43,122.23 v2(14.32,121.34)
  BOTTOM w0.203: UM3.4 v2(104.49,36.95)
  BOTTOM w0.508: v2(81.61,127.39) 81.77,127.39 81.77,127.39 84.26,127.39 ; v2(87.1,141.42) 87.4,141.42 89.57,139.25 89.57,137.73 90.15,137.14 PRZ33.2 ; PR2504.1 36.11,119.44 v2(36.62,118.93) 47.02,118.93 ; v2(18.77,119.18) 16.48,119.18 v2(14.32,121.34) 14.3,121.34 Q5029.3 ; PRH11.1 v2(151.8,56.55) ; v2(102.59,142.55) PRG33.2
  BOTTOM w1.016: 49.82,50.8 49.82,51.3 49.24,51.88 49.24,104.81 52.1,107.67 52.1,112.83 47.34,117.6 47.34,118.23
  vias: v2(18.39,43.05) v2(18.39,42.41) v2(19.02,43.05) v2(19.02,42.41) v2(19.66,43.05) v2(19.66,42.41) v2(49.5,49.91) v2(50.14,49.91) v2(50.7,43.87) v2(51.33,43.87) v2(58.07,28.89) v2(58.71,28.89) v2(154.09,51.49) v2(154.09,50.92) v2(154.09,50.35) v2(154.72,52.13) v2(154.72,51.49) v2(154.72,50.92) v2(154.72,50.35) v2(155.36,52.13) v2(155.36,51.49) v2(155.36,50.92) v2(155.36,50.35) v2(155.99,52.13) v2(155.99,51.49) v2(155.99,50.92) v2(155.99,50.35) v2(196.26,41.08) v2(196.26,40.51) v2(196.88,41.09) v2(196.88,40.53) v2(197.52,40.57) v2(219.87,77.53) v2(219.87,76.89) v2(219.87,76.26) v2(220.57,77.53) v2(220.57,76.89) v2(220.57,76.26) v2(221.2,77.53) v2(221.2,76.89) v2(221.2,76.26) v2(221.84,77.53) v2(221.84,76.89) v2(221.84,76.26) v2(222.47,77.53) v2(222.47,76.26) v2(223.11,77.53)
+5VALW_VDD: length 4.1
  BOTTOM w0.102: v1(35.2,119.32) PR2504.2
  BOTTOM w0.254: PR2504.2 PC2504.1 34.32,120.47 34.32,121.47 34.51,121.66 PU2501.4
+5VALWP: length 27.8
  TOP w0.102: PC512.1 v3(224.67,81.06)
  IN2 w0.254: v2(223.43,80.39) 223.44,80.4 224.06,80.4 224.32,80.65 224.32,83.62 223.88,84.06 210.09,84.06 209.2,83.17 206.27,83.17 206.04,82.94 v2(206.04,82.1)
  BOTTOM w0.254: PR509.2 206.03,82.75 PR510.1 v2(206.04,82.1) 205.91,81.97 PU501.14
  vias: v2(218.86,80.39) v2(219.49,80.39) v2(220.25,80.39) v2(220.89,80.39) v2(221.59,80.39) v2(222.16,80.39) v2(222.86,80.39)
+5VS: length 131.8
  TOP w0.508: R5222.1 v2(220.63,41.59)
  IN1 w0.508: v2(205.71,42.41) 207.68,42.41 210.57,39.52 214.7,39.52 216.76,41.59 v2(220.63,41.59)
  IN1 w1.016: 21.31,74.42 24.48,71.24 24.48,63.62 23.02,62.16 23.02,55.05 19.08,51.11 19.08,46.35 16.8,44.06 16.8,40.64 16.84,40.59 16.84,33.99 17.75,33.08 17.75,27.58 19.11,26.22 23.28,26.22 25.62,23.87
  IN2 w1.016: 16.67,86.91 16.67,88.9 18.7,90.93 18.7,99.18 15.72,102.16 15.72,106.23 13.69,108.26 13.69,110.74
  BOTTOM w0.508: Q7.3 82.22,37.38 85.95,33.65 85.95,31.81 88.34,29.42 F3.2 99.79,27.36 v2(99.48,27.05)
  vias: v2(13.31,111.56) v2(13.94,111.56) v2(21.12,74.73) v2(21.12,74.1) v2(26.51,22.22) v2(27.15,22.22) v2(38.71,7.17) v2(38.71,6.54) v2(39.28,7.17) v2(39.29,6.52) v2(68.39,25.24) v2(68.72,24.67) v2(69.02,25.26) v2(69.38,24.63) v2(69.63,25.27) v2(70.01,24.66) v2(70.65,24.66) v2(71.28,24.66) v2(147.89,34.07) v2(148.19,34.6) v2(148.5,34.07) v2(148.83,34.58) v2(184.06,41.52) v2(184.69,41.52) v2(185.33,41.52) v2(197.14,60.64) v2(197.77,60.64) v2(198.41,60.64) v3(73.44,24.7)
+5VS_ODD: length 1.3
  TOP w0.102: v2(194.22,62.16) v3(194.92,62.16)
  TOP w0.508: CS109.1 v2(194.22,62.16)
+5VS_OUT: length 3.4
  TOP w0.102: 155.1,49.65 155.36,49.65 155.55,49.84 v1(158.4,49.84)
+17.4V_BATT: length 7.1
  TOP w0.508: v2(175.99,50.6) 176.73,50.6 177.87,51.74 v3(177.87,52.48) 179.29,53.91 179.29,55.9 PD14.2
+17.4V_BATT+: length 37.6
  TOP w0.508: v2(198.98,43.94) 196.73,41.7 196,41.7 195.36,41.06 v2(195.36,40.7)
  BOTTOM w0.508: v2(198.98,43.94) 199.88,44.85 PRB35.1 ; 168.28,44.51 168.92,43.87 186.85,43.87 190.03,40.7 v2(195.36,40.7)
  vias: v2(164.25,46.24) v2(164.88,46.24) v2(165.52,46.24) v2(166.15,46.21) v3(163.23,45.91)
+17.4V_BATT++:
  vias: v3(157.01,43.37)
+19V_ADPIN:
  vias: v2(88.43,146.62) v2(88.43,145.98) v2(89.06,147.19) v2(89.06,146.62) v2(89.06,145.98) v2(89.7,146.62) v2(89.7,145.98) v3(87.66,145.47) v3(88.43,147.82) v3(89.32,144.46)
+19V_VIN: length 220.7
  TOP w0.508: PR32.1 186.66,68 PR34.1 186.04,68.65 186.19,68.8 v2(186.19,69.65) 186.11,69.73 183.89,69.73 183.24,69.08 PR36.1 ; v2(190.76,53.3) 190.76,52.99 190.71,52.94 PRB09.1
  TOP w1.778: 105.13,143.51 105.13,112.07 108.75,108.45 113.89,108.45 114.84,107.5
  TOP w3.556: 157.87,66.58 142.03,66.58 142,66.54 141.83,66.54 138.53,63.24 125.89,63.24 118.84,70.29 118.84,100.77 116.37,103.25 116.37,104.07
  IN1 w0.508: v2(186.19,69.65) 192.19,69.65 193.46,68.38 193.46,59.87 191.68,58.1 v2(191.68,57.56)
  IN2 w0.508: v2(186.19,69.65) 185.68,70.16 183.24,70.16 181.63,68.55 180.67,68.55 180.25,68.13 v2(164.94,68.13) ; v2(190.76,53.3) 190.76,56.55 191.68,57.47 v2(191.68,57.56)
  IN2 w1.778: 114.98,108.29 106.31,110.57 104.91,111.97 104.91,144.51
  BOTTOM w0.508: v2(191.68,57.56) 191.47,57.35 PDB01.2
  vias: v2(104.76,146.35) v2(104.76,145.72) v2(105.46,146.35) v2(105.46,145.72) v2(115.16,104.9) v2(115.16,104.26) v2(115.86,104.9) v2(115.86,104.26) v3(116.49,106.48)
+19VB: length 252.1
  IN1 w0.508: v2(178.98,59.62) 178.93,59.57 178.39,59.57 177.3,58.48 174.41,58.48 172.75,56.83 172.06,56.83 171.49,56.26 v2(171.49,55.68)
  IN1 w1.524: 75.09,142.74 76.87,144.52 84.66,144.52 85.76,145.62 85.76,147.68 86.65,148.57 89.62,148.57 90.08,148.12 99.96,148.12 104.99,143.09 104.99,128.3 105.06,128.23 ; 69.06,139.82 61.12,139.82 48.29,127 43.53,127 41.06,124.52 41.06,118.61 39.47,117.03 29.71,117.03 28.36,115.67 28.36,113.66 27.66,112.96
  IN1 w2.286: 104.62,123.9 104.75,123.77 104.75,112.01 106.5,110.25 107.07,110.25 118.84,106.8
  BOTTOM w0.508: v2(171.49,55.68) 171.49,55.34 170.98,54.83 PR302.2
  BOTTOM w1.524: 201.58,61.63 201.58,66.96 200.21,68.33 198.33,68.33
  BOTTOM w2.286: 104.62,121.53 104.62,112.71 105.44,110.8 117.13,107.44
  BOTTOM w4.064: 118.78,101.28 118.78,70.05 125.78,63.05 137.48,63.05 137.49,63.05 138.72,63.05 142.15,66.48 157.2,66.48
  vias: v2(27.4,110.99) v2(27.4,110.42) v2(27.4,109.79) v2(92.62,130.49) v2(92.62,129.85) v2(92.62,129.22) v2(92.62,128.58) v2(103.54,127.25) v2(103.54,126.61) v2(103.54,125.98) v2(103.54,125.34) v2(119.16,105.15) v2(119.16,104.52) v2(119.48,103.94) v2(119.8,105.15) v2(119.8,104.52) v2(179.29,59.11) v2(179.68,59.62) v2(179.93,59.11) v2(180.31,59.62) v2(180.56,59.11) v2(180.88,59.62) v2(181.24,59.14) v2(181.58,59.62) v3(102.27,129.73)
+19VB_1.2V: length 23.7
  TOP w0.102: 25.69,106.99 v3(25.69,106.29)
  TOP w0.254: PRM07.1 v2(24.1,121.98)
  IN2 w0.254: v2(24.1,121.98) 25.22,120.86 28.71,120.86 30.45,119.12 30.45,116.2 28.04,113.79 28.04,108.58 27.02,107.56 v2(25.12,107.56)
  vias: v2(25.12,106.99)
+19VB_1.05V: length 1.1
  TOP w0.102: v1(151.74,61.84) 151.86,61.72 152.75,61.72
  vias: v2(153.13,61.65) v2(154.15,60.96) v2(155.1,60.96)
+19VB_3V: length 0.4
  TOP w0.102: 171.61,61.21 v3(171.61,61.65)
  vias: v2(171.04,60.89) v2(173.14,60.89) v2(174.09,61.02)
+19VB_5V: length 0.4
  TOP w0.102: 200.5,76.7 v3(200.5,76.26)
  vias: v2(200.12,76.89) v2(201.08,76.89) v2(202.28,76.83)
+19VB_CHG: length 2.2
  TOP w0.508: PDB13.3 v2(185.27,53.76)
  vias: v2(186.24,52.81) v2(186.28,52) v2(186.27,50.76) v2(187.55,51.62) v2(187.55,50.99) v3(185.52,51.3)
+19VB_DB: length 61
  TOP w0.102: v2(141.83,40.1) v3(141.83,40.76)
  IN2 w0.127: v2(147.04,40.1) v2(141.83,40.1) 141.82,40.09 141.54,40.09 140.31,38.86 140.31,37.46 141.39,36.38 142.08,36.38 142.08,36.39 v2(142.21,36.39)
  BOTTOM w0.102: RB12.1 158.29,59.38 155.61,56.7 153.96,56.7 148.73,51.47 141.75,51.47 141.19,50.92 141.19,49.21 143.35,47.05 144.5,47.05 145.7,45.84 145.7,44.89 150.59,40 150.59,37.08 150.21,36.7 146.15,36.7 ; JDB1.16 142.01,39.92 v2(141.83,40.1)
  BOTTOM w0.203: JDB1.15 146.86,39.92 v2(147.04,40.1)
+19VB_VCCGI: length 8.9
  TOP w0.508: v2(92.92,131.53) 92.97,131.53 93.68,132.24 94.8,132.24 95.59,131.45 v2(100.34,131.45)
  BOTTOM w0.508: PRG31.1 92.81,131.64 v2(92.92,131.53)
  vias: v2(100.3,126.36) v2(100.3,125.73) v2(100.3,125.09) v3(100.11,128.14)
+19VB_VNN:
  vias: v2(85.51,125.28) v2(85.51,124.65) v2(85.51,124.01) v2(85.51,123.25) v2(88.55,124.09) v2(88.57,123.52) v3(87.22,125.92)
+VCC0: length 6.7
  TOP w0.254: U15.1 125.85,53.51 CE36.1 125.23,51.82 v2(125.23,51.58)
  BOTTOM w0.203: v2(125.23,51.58) 125.23,51.71 125.48,51.97 UE1.111 125.48,53.94 125.7,54.16 v1(125.7,54.4) 125.7,54.41 125.51,54.6 RE40.2
+VCC_IO2: length 6
  TOP w0.102: v3(133.07,48.83) 132.94,48.83 131.61,50.16 RE12.2
  TOP w0.508: RE12.2 RE13.2 130.53,50.99 v2(130.84,51.3)
  BOTTOM w0.203: v2(130.84,51.3) 130.68,51.47 UE1.124
+VCC_SPI: length 4.2
  BOTTOM w0.102: RC34.2 103.93,71.83 103.41,71.31 v1(103.33,71.31)
  BOTTOM w0.457: RC34.2 104.25,72.26 104.31,72.2 CC91.1 104.81,72.45 105.25,72.9 UC11.8
+VCC_VCCGI: length 4.7
  BOTTOM w0.102: PRG33.1 v1(100.03,143.57)
  BOTTOM w0.508: 99.48,139.12 99.48,140.97 PCG06.1 100.03,141.55 PRG33.1
+VCC_VCGI: length 39.4
  TOP w0.254: v2(89.51,110.68) 91.16,110.68 92.11,109.72 93.13,109.72 ; PRG19.2 v2(91.25,140.98)
  IN1 w0.254: v2(91.25,140.98) 90.84,140.98 90.71,141.11 90.31,141.11 89.98,140.77 89.98,114.77 89.51,114.3 v2(89.51,110.68)
  BOTTOM w0.229: v2(94.08,75.63) 94.08,75.68 93.85,75.91 UC1.D39
  BOTTOM w0.254: UC1.D37 93.68,75.03 94.08,75.43 94.08,75.62 v2(94.08,75.63) ; UC1.D31 93.86,72.79 v2(93.86,73) 93.59,73.28 UC1.D33
  vias: v2(81.46,73.81) v2(81.48,73.02) v2(81.46,72.26) v2(82.2,73.79) v2(82.19,73.03) v2(82.19,72.28) v2(82.91,73.8) v2(82.92,73.03) v2(82.91,72.28) v2(84.35,73.79) v2(84.35,73.03) v2(84.37,72.26) v2(84.37,71.5) v2(85.09,73.02) v2(85.09,72.26) v2(85.8,72.99) v2(85.79,72.27) v2(85.82,71.49) v2(86.54,73.03) v2(86.53,72.25) v2(87.25,73.03) v2(87.24,71.49) v2(87.27,73.79) v2(87.98,72.26) v2(88.7,73.78) v2(88.85,83.62) v2(88.98,76.38) v2(89.17,80.21) v2(89.69,76.38) v2(91.3,84.16) v2(93.06,108.14) v2(93.06,107.44) v2(93.63,108.2) v2(93.63,107.5) v2(93.63,106.87) v2(93.7,108.96) v2(94.33,108.2) v2(94.33,107.5) v2(94.33,106.87) v2(94.5,86.04) v2(94.9,106.99) v2(94.9,106.29) v2(95.6,106.99) v2(95.6,106.29) v2(96.3,106.99) v2(96.3,106.29) v2(97,106.99) v2(97,106.29) v2(97.7,106.99) v2(97.7,106.29) v2(98.4,106.99) v2(98.4,106.29) v2(99.09,107.82) v2(99.09,106.99) v2(99.09,106.29) v2(99.79,107.82) v2(99.79,106.99) v2(99.79,106.29) v2(99.79,105.6) v2(100.49,107.82) v2(100.49,107.12) v2(100.49,106.42) v2(100.49,105.72) v2(100.49,105.02) v2(100.49,104.33) v2(101.19,107.82) v2(101.19,107.12) v2(101.19,106.42) v2(101.19,105.72) v2(101.19,105.02) v2(101.19,104.33) v2(101.19,103.63) v2(101.89,107.82) v2(101.89,107.12) v2(101.89,106.42) v2(101.89,105.72) v2(101.89,105.02) v2(101.89,104.33) v2(101.89,103.63) v2(101.89,102.93) v2(102.71,105.02) v2(102.71,104.33) v2(102.71,103.75) v2(102.71,103.06) v2(103.41,103.75) v2(103.41,103.06) v3(95.98,109.72)
+VCCIOA:
  vias: v2(79.31,71.51) v2(79.31,70.73) v2(79.9,86.96) v2(79.9,86.32) v2(79.89,85.69) v2(79.89,85.05) v2(80.02,70.76) v2(80,69.98) v3(79.47,90.1)
+VDD10: length 8.9
  TOP w0.102: 25.24,79.5 v3(25.24,77.72)
  TOP w0.203: CL31.1 20.53,79.48 20.99,79.94 20.99,80.44 21.6,81.05 UL1.3 ; 21.17,88.07 21.17,87.89 21.6,87.46 UL1.22 ; CL6.1 18.64,83.07 18.92,83.34 UL1.30
  vias: v2(17.94,82.42) v2(18,82.99) v2(19.85,79.24) v2(19.97,78.67) v2(20.23,89.15) v2(20.25,88.51) v2(25.04,79.7) v2(25.62,79.69)
GND: length 1672.2
  TOP w0.089: UM1.N2 110.95,40.75 v2(110.26,40.75)
  TOP w0.102: v2(136.89,43.62) 136.95,43.68 v3(137.58,43.68) ; v3(32.86,3.74) 32.86,4.5 ; v3(214.22,37.78) v2(213.2,37.78) ; v2(21.31,126.17) v3(22.01,126.17) ; v3(155.8,59.6) v2(155.08,59.6) ; v3(221.78,84.07) 221.78,83.5 v2(222.09,83.18) ; v3(216.38,32.89) v2(216.38,32.25)
  TOP w0.127: v2(100.35,74.36) 100.35,74.31 100,73.97 99.8,73.97 98.83,73 96.85,73 96.81,72.96 v2(96.05,72.96) ; v2(96.17,67.43) 96.68,67.94 101.33,67.94 101.39,68 102.02,68 102.21,68.19 102.76,68.19 103.12,67.84 103.12,67.41 103.36,67.17 104.63,67.17 104.87,66.92 107.03,66.92 107.29,67.18 107.29,70.86 106.97,71.18 104.81,71.18 104.49,70.86 104,70.86 103.69,70.54 102.52,70.54 100.55,68.58 96.49,68.58 v2(96.06,69.01) ; v2(18.07,84.63) 17.53,85.17 17.53,86.13 17.12,86.55 15.78,86.55 15.38,86.95 12.78,86.95 12.29,86.46 12.29,82.29 12.67,81.91 16.99,81.91 17.5,82.42 17.5,82.56 17.52,82.59 17.52,83.21 17.92,83.6 v2(18.51,83.6)
  TOP w0.152: UM1.E9 114.23,44.52 113.91,44.52 v2(113.74,44.34) 113.9,44.18 114.66,44.18 114.98,44.5 UM1.F10 ; UM1.E10 115.2,45.16 114.87,45.5 v2(114.02,45.5) 113.7,45.19 UM1.E7 ; v2(113.99,42) 113.99,42.28 UM1.K8 ; UM1.G5 112.6,44 v2(112.14,44.45) ; v2(113.26,43.05) 113.2,43 UM1.J5 ; v2(113.45,39.94) 113.45,40.25 UM1.P6 UM1.N5 ; UM1.P4 v2(112.2,39.94) ; v2(113.32,47.7) 113.2,47.58 UM1.A6 ; UM1.C4 112.65,45.55 v2(112.67,45.55) ; v2(114.08,42.92) 114.08,42.98 114.59,43.5 UM1.H10
  TOP w0.203: v2(152.17,48.54) 152.13,48.58 U11.11 ; PUM01.14 22.63,116.69 v2(22.58,116.63) ; PUM01.3 v2(25.55,117.09)
  TOP w0.254: CM10.2 113.09,35.2 113.32,35.43 v2(113.32,35.87) ; PCG115.2 82.25,71.56 v2(82.19,71.49) ; CC33.1 79.03,73.03 v2(78.97,72.97) ; v2(218.28,60.46) 217.95,60.13 C17.2 ; PCG118.2 83.22,74.26 83.19,74.26 v2(82.9,74.55) ; PCM14.2 20.56,119.78 ; CC79.1 85.19,86.04 85.19,85.42 CC76.1 ; v2(91.03,76.32) 90.99,76.28 PCG122.2 ; v2(92.77,88.09) 92.24,87.56 PCG121.2 ; C232.2 v2(146.15,46.48) ; v2(80.74,69.2) 80.74,69.21 PCZ106.2
  TOP w0.305: PCZ107.2 PCZ109.2 79.81,80.67 v2(79.61,80.87) ; v2(197.65,52.87) 197.65,53.2 197.16,53.68 PQB33.3 ; PQB32.3 v2(200.66,53.92)
  TOP w0.356: CU21.2 21.88,41.71 v2(22.09,41.93) ; v2(211.49,45.59) 211.81,45.91 C39.2 ; CD16.2 34.13,65.1 v2(34.1,65.13) ; CA45.2 v2(27.78,21.65) ; CA48.2 38.45,8.4 v2(38.45,8) ; v2(108.36,84.13) 108.4,84.09 CC5.2 ; C35.2 v2(223.94,42.41) ; v2(27.66,118.8) 27.85,118.99 PRM11.2 ; CL18.2 21.89,88.77 CL16.2 ; 20.56,119.78 v2(20.56,120.65) ; UM2.3 103.46,43.01 103.22,43.25 v2(103.03,43.25) ; C41.2 v2(4.86,121.79) ; C983.1 v2(220.34,44.89) ; C3.2 v2(215.74,59.43) ; CA49.2 v2(28.42,21.65)
  TOP w0.381: v2(37.26,79.38) 37.34,79.45 37.34,80.03 37.5,80.19 CD25.2 ; UC6.3 66.81,108.66 v2(66.7,108.77) ; v2(34.14,84.19) 34.14,83.95 33.24,83.05 CD14.2 ; v2(41.31,75.24) 41.12,75.43 CD12.2 ; CA483.2 37.87,8.53 CA48.2 ; RC1152.2 57.88,115.9 57.21,115.23 UC12.3 ; CD18.2 41.94,57.02 v2(41.48,56.56) ; CD23.2 32.33,74.61 v2(33.17,75.45) ; v2(92.52,70.2) 92.52,70.32 93.14,70.94 RC25.2 ; CD17.2 32.47,78.48 v2(32.74,78.21) ; CA46.2 35.98,19.3 v2(35.56,19.71) ; 88.33,64.89 88.33,64.34 v2(88.31,64.32) ; CE35.1 124.35,56.99 v2(124.27,57.08) ; CA50.2 v2(35.72,18.73) ; v2(77.7,78.52) 77.58,78.4 CC272.1 ; v2(125.81,51.59) 125.89,51.59 126.44,52.14 CE36.2 126.44,53.32 U15.2 ; v2(33.27,72.78) 33.27,72.31 33.58,72 CD20.2 ; v2(41.81,67.56) 42.19,67.94 CD13.2 ; CD15.2 33.11,76.58 v2(33.74,77.21) ; Q25.4 14.34,119.49 v2(14.64,119.18) ; CL11.1 15.91,84.15 15.81,84.15 15.79,84.17 v2(15.58,84.17) 16.1,84.69 CL10.1 ; RC62.2 113.08,59.55 112.62,60 v2(112.18,60) ; CL32.2 18.83,87.31 18.63,87.51 CL8.2 18.6,87.78 18.6,87.78 v2(17.85,87.78) ; v2(186.28,65.4) 186.23,65.4 185.85,65.78 PQ13.4 185.85,66.43 186.04,66.62 PR38.2 ; PR40.2 181.69,63.43 PQ12.4 ; UC7.3 v2(65.61,112.15) ; CD11.2 41.24,72.66 41.77,72.13 v2(41.94,72.13) ; Q25.1 12.17,120.84 12.55,121.22 v2(12.61,121.22) ; v2(128.53,55.67) 128.63,55.67 129.19,56.23 CE37.1 ; v2(168.06,38.22) 168.18,38.35 PD6.1 ; RC18.1 90.08,62.1 v2(90.21,61.97) ; v2(183.93,67.43) 183.71,67.43 183.68,67.41 183.41,67.41 PR44.1 182.99,66.99 PQ12.1
  TOP w0.406: C21.2 79.55,45.78 v2(79.88,45.78) ; v2(75.22,54.41) 75.54,54.1 78.2,54.1 79.49,52.81 U2.5
  TOP w0.457: UC3.3 108.32,80.43 v2(108.75,80) ; v2(29.88,85.43) 29.76,85.54 29.76,87.02 D14.1 ; CC60.1 76.36,62.85 v2(76.17,63.04) ; CA27.2 v2(25.7,3.79) ; CC13.2 104.15,67.75 v2(103.67,67.75) ; RM12.1 v2(111.41,53.18) ; v2(131.03,38.48) 131.09,38.53 CE9.2 ; v2(102.78,70.04) 102.84,70.1 104.02,70.1 CC14.2 ; v2(17.88,81.78) 18.42,81.78 CL6.2 ; v2(31.85,21.97) CA52.2 ; RD11.2 32.14,63.63 v2(32.86,62.91) ; RC105.2 RC103.2 ; CA476.2 21.29,2.73 v2(21.87,2.73) CA480.2 ; CL25.2 v2(16.8,81.08) ; RM13.1 CM8.1 ; CC62.1 79.97,78.67 v2(79.69,78.67)
  TOP w0.508: U14.2 221.99,47.11 222.5,47.62 v2(222.5,47.72) ; v2(107.67,77.02) 107.78,76.91 108.42,76.91 108.48,76.84 RC105.2 ; v2(213.33,53.89) CT14.2 RT29.2 ; v2(32.32,43.07) 32.32,43.15 32.13,43.34 RD4.2 RD5.2 ; v2(169.55,54.92) 170.13,54.92 170.66,55.46 PC317.2 ; CM26.2 v2(26.89,97.79) ; v2(58.94,116.14) 58.7,115.9 RC1152.2 ; v2(213.33,41.95) 213.24,42.05 C16.2 ; v2(200,53.25) 199.58,53.25 199.16,52.83 PCB36.2 ; CD24.2 32.43,80.7 32.73,81 33.23,81 33.59,80.64 33.59,80.42 v2(33.62,80.39) ; v2(107.79,53.22) 108.1,52.9 RM13.1 ; v2(27.4,108.77) 27.09,108.45 PCM23.2 PCM22.2 ; v2(70.99,114.1) 69.9,114.1 CC93.1 ; v2(191.55,43.01) 191.55,43.06 192.06,43.57 192.42,43.57 192.45,43.55 PQ11.3 ; PD2.2 v2(80.88,147.33) ; EC2902.2 v2(224.96,62.37) ; v2(24.48,78.23) 24.42,78.29 CL5.2 ; v2(194.15,44.06) 194.01,44.2 PR43.2 ; SW1.2 v2(220.13,67.24) ; CA25.2 v2(24.29,10.45) ; PRZ37.2 v2(85.06,139.95) ; v2(78.95,147.06) PR6.2 78.89,146.23 PQ2.3 ; CW6.2 v2(65.31,136.77) ; DD2.1 28.91,39.09 28.19,39.09 v2(27.78,39.49) ; v2(109.75,72.8) 109.72,72.83 109.71,72.83 109.71,72.83 RC10.2 ; v2(107.07,48.74) 106.1,48.74 QC1.3 ; v2(16.16,7.23) 16.84,7.91 17.1,7.91 17.12,7.92 DA8.1 ; PCM13.2 v2(19.91,117.53) ; v2(73.44,143.25) PD1.1 ; v2(30.32,114.04) 29.69,114.04 PCM20.2 ; RW26.2 v2(62.9,135.12) ; PCZ03.2 89.95,130.84 89.51,130.4 88.51,130.4 v2(88.38,130.54) ; PDB13.1 v2(184.3,59.2) ; v2(32.84,70.45) 32.4,70.45 CD32.2 31.66,68.85 RD6.2 ; PR1206.2 PC1205.2 63.79,46.74 v2(63.79,47.29) ; RL6.1 23.16,75.69 23.15,75.67 v2(23.15,75.18) ; EU4012.1 v2(217.75,34.88) ; UL2.2 17.89,77.01 v2(17.88,77.02) ; v2(37.1,70.57) 37.1,70.85 37.49,71.24 38.42,71.24 CD21.2 ; RC57.2 104.58,71.86 CC9.2 104.44,71.83 103.94,71.33 103.44,71.33 103.09,70.99 v2(102.79,70.99) ; CS44.2 v2(20.86,24.95) ; RC56.1 108.48,75.5 108.48,75.87 RC103.2 ; CD29.2 32.67,84.07 v2(32.79,84.2) ; v2(169.2,49.69) PQB29.3 ; PRG35.2 93.33,133.94 v2(94.17,133.1) ; CW8.2 65.7,137.85 v2(65.66,137.82) ; CC79.1 v2(83.85,86.42) ; v2(103.03,42.54) 103.46,42.11 CM6.2 ; CD19.2 v2(35.81,86.93) ; YL2.4 v2(14.92,84.17) ; CM27.2 v2(25.31,95.31) ; CC78.1 v2(84.04,87.69) ; v2(23.4,24.51) CS42.2 ; CM3.2 CM4.2 110.87,34.78 v2(110.41,35.24) ; v2(200.47,48.19) 200.39,48.19 199.88,48.7 PCB11.2 ; v2(207.27,45.69) 207.09,45.87 R5217.1 ; PR40.2 181.47,63.38 180.96,63.89 v2(180.96,63.91) ; CS40.2 v2(21.94,24.51) ; v2(81.5,71.5) 80.87,71.5 PCG101.2 ; CA28.2 25.04,6.03 v2(24.93,6.03) ; v2(20.99,8.31) 21,8.3 RA38.2 ; v2(88.58,139.15) 87.79,138.36 PRZ35.2 ; R72.2 v2(221.18,50.31) ; RC86.2 108.4,70.37 109.22,69.55 v2(109.22,69.34) ; RD12.2 29.97,66.22 v2(29.9,66.16) ; v2(35.99,79.38) 35.53,78.91 35.1,78.91 34.6,78.4 CD26.2 ; PCG107.2 v2(92.27,108.96) ; v2(89.69,73.84) 90.2,74.36 PCG103.2 ; PRH02.2 v2(154.53,59.18) ; v2(25.82,121.98) PCM15.2 PCM16.2 ; PRZ38.2 81.1,128.42 v2(81.21,128.3) ; RD36.2 34.37,73.53 34.57,73.32 34.57,72.87 v2(34.48,72.77) ; v2(106.02,54.53) 106.02,54.35 106,54.33 QC10.3 ; PRG36.2 94.94,142.44 v2(94.65,142.73) ; v2(62.33,57.97) 62.64,57.65 CC59.1 ; v2(63,58.54) 63.07,58.61 CC58.2 ; PD14.1 179.33,58 v2(178.67,58.66) ; v2(22.7,106.93) 23.01,107.24 PCM04.2 ; v2(26.32,9.77) 26.77,10.22 CA484.1 CA492.2 ; CC10.2 106.08,55.88 v2(106.08,55.47) ; v2(41.49,85.08) 41.2,84.79 CD22.2 ; CA490.2 v2(36.53,15.38) ; v2(29.9,67.1) 29.96,67.05 CD28.2 ; v2(38.51,91.56) 38.7,91.75 CD31.2 ; v2(107.73,78.93) 107.74,78.94 CC89.1 ; DA2.1 16.67,2.98 v2(16.16,2.47) ; v2(224.67,67.93) 224.28,67.54 ED2901.1 ; C37.2 v2(219.17,28.89) ; CD33.2 37.78,77.21 v2(37.75,77.24) ; RC64.2 v2(106.54,47.76) ; CL29.2 v2(16.8,80.13) ; U1.2 220,55.24 220.38,54.86 v2(220.95,54.86) ; CL31.2 21.61,79.34 v2(21.61,79.84) ; C2.2 v2(213.84,59.43) ; v2(25.5,82.22) 26.08,82.22 CL7.2 CL24.2 ; R10.2 v2(222.84,57.83) ; DC6.1 32.08,115.02 v2(31.4,115.69) ; CA53.2 v2(18.96,8.3) ; UC5.3 70.33,112.09 CC92.1 72.6,112.09 v2(72.81,111.88) ; PRB28.1 200.62,50.86 v2(201.58,51.82) ; PRB04.2 v2(180.87,67.7) ; QC9.3 111.88,60.3 v2(112.18,60) ; RL4.2 23.4,88.53 22.86,89.07 v2(22.82,89.07) 22.71,88.96 CL18.2 ; v2(17.12,20.44) 17.17,20.39 DA9.1 ; PD3.2 83.55,145.68 83.79,145.92 v2(84.3,145.92) ; DA1.1 v2(22.64,5.77) ; UW1.2 v2(65.69,128.84) ; v2(211.17,55.49) 210.72,55.94 Q5027.3 ; CM7.2 CM2.2 107.08,46.3 v2(107.35,46.03) ; v2(58.89,44.25) PR1202.2 ; v2(97.9,143.11) 98.37,142.64 PRG38.2 ; v2(30.32,115.31) PCM19.2 PCM18.2 ; CS109.2 v2(192.06,62.16) ; C233.2 144.58,46.83 v2(144.24,46.49) ; DA5.1 v2(21.05,21.71) ; D12.1 v2(216.75,45.19) ; CU25.2 v2(17.56,58.61) ; PC1806.2 v2(52.93,31.95) ; v2(24.67,61.46) CL12.2 ; PCG09.2 102.18,136.45 v2(102.64,136.45) ; v2(189.61,45.65) 190.03,45.65 190.66,46.29 PRB45.2 190.66,47.28 PQB31.3 ; YL2.2 v2(13.22,84.07) ; CC41.1 85.29,51.02 v2(85.19,50.92) ; EC2901.2 v2(221.84,67.37) ; v2(23.34,47.75) DD1.1 ; PCG100.2 91.28,82.95 v2(91.28,83.56) ; CA51.2 v2(25.69,21.59) ; C12.2 v2(214.79,59.43) ; v2(72.73,123.44) RW11.2
  VCC w0.203: H5.1 9.4,39.8 ; H5.1 6.09,41.2 ; H5.1 6.6,42.6 ; H5.1 9.91,41.2 ; H5.1 9.4,42.6 ; H5.1 6.6,39.8 ; H5.1 8,39.29 ; H5.1 8,43.11 ; 5.05,20.55 JUSB2.11 ; JUSB2.11 7.75,21.4 ; JUSB2.11 7.75,20.55 ; JUSB2.11 6.4,20.55 ; JUSB2.11 5.05,21.4 ; JRJ45.12 10.65,66.4 ; JRJ45.12 9.49,65.1 ; JRJ45.12 11.81,65.1 ; JRJ45.12 10.65,65.1 ; JRJ45.12 11.81,65.75 ; JRJ45.12 9.49,65.75 ; JRJ45.12 9.49,66.4 ; JHDMI1.20 12.75,105 ; JHDMI1.20 11.49,105 ; JHDMI1.20 14.01,104.1 ; JHDMI1.20 11.49,103.2 ; JHDMI1.20 14.01,105 ; JHDMI1.20 12.75,103.2 ; JHDMI1.20 14.01,103.2 ; JHDMI1.20 11.49,104.1 ; JHDMI1.23 12.75,90.5 ; JHDMI1.23 11.49,90.5 ; JHDMI1.23 12.75,88.7 ; JHDMI1.23 14.01,88.7 ; JHDMI1.23 11.49,88.7 ; JHDMI1.23 11.49,89.6 ; JHDMI1.23 14.01,90.5 ; JHDMI1.23 14.01,89.6 ; 5.05,61.85 JUSB1.13 ; JUSB1.13 7.75,61.85 ; JUSB1.13 5.05,61 ; JUSB1.13 7.75,61 ; JUSB1.13 6.4,61.85 ; 5.05,37.95 JUSB2.13 ; JUSB2.13 6.4,37.95 ; JUSB2.13 7.75,37.95 ; JUSB2.13 7.75,37.1 ; JUSB2.13 5.05,37.1 ; 2.04,106 JHDMI1.21 ; JHDMI1.21 2.04,105.1 ; JHDMI1.21 2.04,106.9 ; JHDMI1.21 4.56,106.9 ; JHDMI1.21 3.3,105.1 ; JHDMI1.21 4.56,106 ; JHDMI1.21 3.3,106.9 ; JHDMI1.21 4.56,105.1 ; 10.6,97.8 JHDMI1.11 ; JHDMI1.11 11.5,96.9 ; JHDMI1.11 11.61,97.35 ; JHDMI1.11 11.5,97.8 ; JHDMI1.11 10.6,96.9 ; JHDMI1.11 10.49,97.35 ; JUSB2.10 15.25,20.55 ; JUSB2.10 15.25,22.25 ; JUSB2.10 11.75,20.55 ; JUSB2.10 13.5,20.55 ; JUSB2.10 11.75,21.4 ; JUSB2.10 15.25,21.4 ; JUSB2.4 16.39,25.24 ; JUSB2.4 15.88,26.4 ; JUSB2.4 16.53,25.75 ; JUSB2.4 15.88,25.1 ; JUSB2.4 15.37,26.26 ; JUSB2.4 16.39,26.26 ; JUSB2.4 15.23,25.75 ; JUSB2.4 15.37,25.24 ; 10.6,93.9 JHDMI1.5 ; JHDMI1.5 11.5,93.9 ; JHDMI1.5 11.61,94.35 ; JHDMI1.5 10.6,94.8 ; JHDMI1.5 11.5,94.8 ; JHDMI1.5 10.49,94.35 ; JUSB1.4 16.39,50.16 ; JUSB1.4 15.37,50.16 ; JUSB1.4 15.88,50.3 ; JUSB1.4 15.37,49.14 ; JUSB1.4 15.23,49.65 ; JUSB1.4 16.39,49.14 ; JUSB1.4 16.53,49.65 ; JUSB1.4 15.88,49 ; 9.49,82.55 JRJ45.9 ; JRJ45.9 11.81,82.55 ; JRJ45.9 10.65,81.9 ; JRJ45.9 11.81,81.9 ; JRJ45.9 11.81,83.2 ; JRJ45.9 9.49,83.2 ; JRJ45.9 9.49,81.9 ; JRJ45.9 10.65,83.2 ; 6.5,87.2 H4.1 ; H4.1 9.81,85.8 ; H4.1 9.3,84.4 ; H4.1 6.5,84.4 ; H4.1 7.9,83.89 ; H4.1 9.3,87.2 ; H4.1 7.9,87.71 ; H4.1 5.99,85.8 ; JHDMI1.2 13.05,93.3 ; JHDMI1.2 13.05,92.4 ; JHDMI1.2 12.15,92.4 ; JHDMI1.2 12.6,92.29 ; JHDMI1.2 12.04,92.85 ; JHDMI1.2 13.16,92.85 ; JHDMI1.2 12.15,93.3 ; JHDMI1.22 5.81,87.7 ; JHDMI1.22 3.29,87.7 ; JHDMI1.22 4.55,88.6 ; JHDMI1.22 5.81,86.8 ; JHDMI1.22 4.55,86.8 ; JHDMI1.22 5.81,88.6 ; JHDMI1.22 3.29,86.8 ; JHDMI1.22 3.29,88.6 ; 13.87,52.64 JUSB1.7 ; JUSB1.7 14.38,53.8 ; JUSB1.7 15.03,53.15 ; JUSB1.7 14.89,52.64 ; JUSB1.7 14.38,52.5 ; JUSB1.7 13.87,53.66 ; JUSB1.7 14.89,53.66 ; 11.75,37.1 JUSB2.12 ; JUSB2.12 13.5,37.95 ; JUSB2.12 15.25,36.25 ; JUSB2.12 11.75,37.95 ; JUSB2.12 15.25,37.95 ; JUSB2.12 15.25,37.1 ; 5.05,44.45 JUSB1.11 ; JUSB1.11 5.05,45.3 ; JUSB1.11 7.75,44.45 ; JUSB1.11 6.4,44.45 ; JUSB1.11 7.75,45.3 ; JUSB2.7 14.89,29.76 ; JUSB2.7 13.87,28.74 ; JUSB2.7 14.38,28.6 ; JUSB2.7 14.38,29.9 ; JUSB2.7 14.89,28.74 ; JUSB2.7 15.03,29.25 ; JUSB2.7 13.87,29.76 ; 10.6,99.9 JHDMI1.17 ; JHDMI1.17 11.5,100.8 ; JHDMI1.17 10.49,100.35 ; JHDMI1.17 10.6,100.8 ; JHDMI1.17 11.61,100.35 ; JHDMI1.17 11.5,99.9 ; 2.85,65.1 JRJ45.11 ; JRJ45.11 1.69,65.1 ; JRJ45.11 4.01,65.75 ; JRJ45.11 4.01,65.1 ; JRJ45.11 2.85,66.4 ; JRJ45.11 4.01,66.4 ; JRJ45.11 1.69,65.75 ; JRJ45.11 1.69,66.4 ; 1.69,82.55 JRJ45.10 ; JRJ45.10 1.69,83.2 ; JRJ45.10 2.85,83.2 ; JRJ45.10 1.69,81.9 ; JRJ45.10 4.01,82.55 ; JRJ45.10 2.85,81.9 ; JRJ45.10 4.01,81.9 ; JRJ45.10 4.01,83.2 ; 12.15,95.4 JHDMI1.8 ; JHDMI1.8 13.05,95.4 ; JHDMI1.8 12.15,96.3 ; JHDMI1.8 12.04,95.85 ; JHDMI1.8 13.05,96.3 ; JHDMI1.8 13.16,95.85 ; 45.5,128.79 H12.1 ; H12.1 47.51,130.8 ; H12.1 45.5,132.81 ; H12.1 46.97,132.27 ; H12.1 44.03,129.33 ; H12.1 43.49,130.8 ; H12.1 44.03,132.27 ; H12.1 46.97,129.33 ; H8.1 8.41,114.11 ; H8.1 5.39,111.09 ; H8.1 5.39,114.11 ; H8.1 8.96,112.6 ; H8.1 6.9,114.66 ; H8.1 6.9,110.54 ; H8.1 4.84,112.6 ; H8.1 8.41,111.09 ; JUSB1.12 13.5,61.85 ; JUSB1.12 15.25,60.15 ; JUSB1.12 15.25,61.85 ; JUSB1.12 15.25,61 ; JUSB1.12 11.75,61 ; JUSB1.12 11.75,61.85 ; 13.5,44.45 JUSB1.10 ; JUSB1.10 15.25,46.15 ; JUSB1.10 15.25,45.3 ; JUSB1.10 11.75,45.3 ; JUSB1.10 11.75,44.45 ; JUSB1.10 15.25,44.45 ; H1.1 6.85,132.41 ; H1.1 8.25,131.9 ; H1.1 8.76,130.5 ; H1.1 4.94,130.5 ; H1.1 8.25,129.1 ; H1.1 5.45,129.1 ; H1.1 6.85,128.59 ; H1.1 5.45,131.9
  IN2 w0.127: v2(75.5,133.93) 74.47,133.93 73.78,133.24 73.78,131.44 73.57,131.23 73.57,126.11 73.31,125.85 73.31,124.85 73.94,124.23 73.94,123.2 75.26,121.87 75.26,121.45 75.44,121.27 75.44,117.69 73,115.25 73,112.07 v2(72.81,111.88) 72.81,110.99 73.38,110.42 74.2,110.42 v2(74.27,110.49) 75.07,110.49 75.76,109.79 75.76,107.78 75.78,107.77 75.78,107.41 79.74,103.45 79.74,103.18 82.23,100.69 83.29,99.63 89.04,99.63 94.49,94.18 95.24,94.18 95.88,94.18 98.16,94.18 98.41,93.94 100.02,93.94 v2(101.57,92.39) 101.57,92.13 102.27,91.44 103.33,91.44 103.83,90.93 103.83,88.7 103.35,88.22 103.35,87.1 102.97,86.72 v2(102.97,86.36) 102.97,85.66 103.98,84.64 103.98,81.74 103.6,81.35 103.6,79.62 102.29,78.31 102.29,75.07 101.38,74.16 100.55,74.16 v2(100.35,74.36) 100.35,74.44 101.02,75.12 101.25,75.12 101.78,75.64 101.78,76.77 101.78,76.98 101.78,78.56 103.09,79.88 103.09,81.57 103.41,81.88 103.41,84.35 102.17,85.59 102.17,86.99 102.59,87.41 102.59,88.51 103.16,89.09 v2(103.16,90.29) 103.16,90.8 103.03,90.93 102.04,90.93 99.53,93.43 98.2,93.43 97.95,93.67 95.67,93.67 95.03,93.67 94.28,93.67 88.83,99.12 83.08,99.12 81.73,100.48 79.23,102.97 79.23,103.24 75.27,107.2 75.27,107.45 75.26,107.46 75.26,109.58 75.01,109.83 74.62,109.83 74.27,109.47 v2(73.94,109.47) 73.5,109.47 72.07,110.9 72.07,112.17 72.49,112.58 72.49,113.26 72.49,115.46 73.71,116.68 v2(73.71,116.91) 73.94,116.91 74.9,117.88 74.9,120.85 74.9,120.85 74.9,120.95 74.74,121.33 74.65,121.47 74.65,121.77 73.57,122.85 73.57,122.85 73.43,122.99 73.43,124.02 72.8,124.64 72.8,124.85 72.8,125.06 72.81,125.64 72.8,125.85 72.8,126.06 73.06,126.32 73.06,131.17 73.06,131.17 73.06,131.44 73.27,131.66 73.27,133.45 73.67,133.85 v2(73.67,134.42)
  IN2 w0.203: v2(41.09,47.82) 40.93,47.67 33.16,47.67 32.24,48.58 32.24,61.06 v2(32.89,61.72) 32.89,62.88 v2(32.86,62.91) 32.86,63.21 32.42,63.66 32.42,64.74 v2(32.79,65.11) ; v2(32.83,85.34) 32.83,86.14 32.23,86.74 32.23,87.9 v2(32.76,88.43)
  GND w0.203: JHDMI1.8 13.05,95.4 ; JHDMI1.8 13.16,95.85 ; JHDMI1.8 12.04,95.85 ; JHDMI1.8 12.15,95.4 ; JHDMI1.8 12.15,96.3 ; JHDMI1.8 13.05,96.3 ; 2.04,106.9 JHDMI1.21 ; JHDMI1.21 4.56,106.9 ; JHDMI1.21 2.04,105.1 ; JHDMI1.21 3.3,106.9 ; JHDMI1.21 2.04,106 ; JHDMI1.21 4.56,106 ; JHDMI1.21 4.56,105.1 ; JHDMI1.21 3.3,105.1 ; 13.87,28.74 JUSB2.7 ; JUSB2.7 14.38,28.6 ; JUSB2.7 14.89,29.76 ; JUSB2.7 13.87,29.76 ; JUSB2.7 14.38,29.9 ; JUSB2.7 15.03,29.25 ; JUSB2.7 14.89,28.74 ; 15.88,49 JUSB1.4 ; JUSB1.4 15.37,50.16 ; JUSB1.4 15.23,49.65 ; JUSB1.4 15.88,50.3 ; JUSB1.4 16.39,50.16 ; JUSB1.4 15.37,49.14 ; JUSB1.4 16.39,49.14 ; JUSB1.4 16.53,49.65 ; 1.69,83.2 JRJ45.10 ; JRJ45.10 4.01,83.2 ; JRJ45.10 4.01,82.55 ; JRJ45.10 1.69,82.55 ; JRJ45.10 2.85,83.2 ; JRJ45.10 2.85,81.9 ; JRJ45.10 4.01,81.9 ; JRJ45.10 1.69,81.9 ; JHDMI1.17 11.61,100.35 ; JHDMI1.17 11.5,100.8 ; JHDMI1.17 10.6,100.8 ; JHDMI1.17 11.5,99.9 ; JHDMI1.17 10.6,99.9 ; JHDMI1.17 10.49,100.35 ; 11.49,89.6 JHDMI1.23 ; JHDMI1.23 11.49,90.5 ; JHDMI1.23 12.75,90.5 ; JHDMI1.23 14.01,90.5 ; JHDMI1.23 11.49,88.7 ; JHDMI1.23 12.75,88.7 ; JHDMI1.23 14.01,88.7 ; JHDMI1.23 14.01,89.6 ; H1.1 8.25,129.1 ; H1.1 8.76,130.5 ; H1.1 6.85,132.41 ; H1.1 8.25,131.9 ; H1.1 5.45,131.9 ; H1.1 6.85,128.59 ; H1.1 5.45,129.1 ; H1.1 4.94,130.5 ; JUSB1.12 15.25,60.15 ; JUSB1.12 11.75,61 ; JUSB1.12 15.25,61.85 ; JUSB1.12 15.25,61 ; JUSB1.12 11.75,61.85 ; JUSB1.12 13.5,61.85 ; HCPU1.1 74.61,101.59 ; HCPU1.1 72.25,103.95 ; HCPU1.1 70.53,103.31 ; HCPU1.1 72.25,99.23 ; HCPU1.1 73.97,103.31 ; HCPU1.1 69.89,101.59 ; HCPU1.1 70.53,99.87 ; HCPU1.1 73.97,99.87 ; 13.5,20.55 JUSB2.10 ; JUSB2.10 15.25,21.4 ; JUSB2.10 15.25,20.55 ; JUSB2.10 11.75,20.55 ; JUSB2.10 11.75,21.4 ; JUSB2.10 15.25,22.25 ; 5.05,45.3 JUSB1.11 ; JUSB1.11 6.4,44.45 ; JUSB1.11 7.75,45.3 ; JUSB1.11 5.05,44.45 ; JUSB1.11 7.75,44.45 ; 12.75,103.2 JHDMI1.20 ; JHDMI1.20 14.01,104.1 ; JHDMI1.20 14.01,103.2 ; JHDMI1.20 11.49,104.1 ; JHDMI1.20 11.49,105 ; JHDMI1.20 11.49,103.2 ; JHDMI1.20 14.01,105 ; JHDMI1.20 12.75,105 ; 4.55,86.8 JHDMI1.22 ; JHDMI1.22 5.81,87.7 ; JHDMI1.22 3.29,86.8 ; JHDMI1.22 3.29,88.6 ; JHDMI1.22 3.29,87.7 ; JHDMI1.22 4.55,88.6 ; JHDMI1.22 5.81,88.6 ; JHDMI1.22 5.81,86.8 ; JRJ45.12 11.81,65.75 ; JRJ45.12 10.65,65.1 ; JRJ45.12 11.81,65.1 ; JRJ45.12 10.65,66.4 ; JRJ45.12 9.49,66.4 ; JRJ45.12 9.49,65.1 ; JRJ45.12 9.49,65.75 ; H8.1 8.41,111.09 ; H8.1 4.84,112.6 ; H8.1 8.41,114.11 ; H8.1 8.96,112.6 ; H8.1 6.9,114.66 ; H8.1 5.39,114.11 ; H8.1 5.39,111.09 ; H8.1 6.9,110.54 ; 11.75,37.95 JUSB2.12 ; JUSB2.12 13.5,37.95 ; JUSB2.12 11.75,37.1 ; JUSB2.12 15.25,37.95 ; JUSB2.12 15.25,37.1 ; JUSB2.12 15.25,36.25 ; HCPU2.1 96.55,103.95 ; HCPU2.1 98.91,101.59 ; HCPU2.1 98.27,99.87 ; HCPU2.1 94.19,101.59 ; HCPU2.1 96.55,99.23 ; HCPU2.1 94.83,99.87 ; HCPU2.1 98.27,103.31 ; HCPU2.1 94.83,103.31 ; JHDMI1.5 11.5,94.8 ; JHDMI1.5 10.6,94.8 ; JHDMI1.5 10.49,94.35 ; JHDMI1.5 11.61,94.35 ; JHDMI1.5 10.6,93.9 ; JHDMI1.5 11.5,93.9 ; HCPU3.1 72.25,42.95 ; HCPU3.1 73.97,38.87 ; HCPU3.1 74.61,40.59 ; HCPU3.1 73.97,42.31 ; HCPU3.1 72.25,38.23 ; HCPU3.1 69.89,40.59 ; HCPU3.1 70.53,42.31 ; HCPU3.1 70.53,38.87 ; 6.5,84.4 H4.1 ; H4.1 5.99,85.8 ; H4.1 9.81,85.8 ; H4.1 9.3,84.4 ; H4.1 7.9,87.71 ; H4.1 6.5,87.2 ; H4.1 7.9,83.89 ; H4.1 9.3,87.2 ; 9.49,82.55 JRJ45.9 ; JRJ45.9 11.81,82.55 ; JRJ45.9 10.65,83.2 ; JRJ45.9 11.81,81.9 ; JRJ45.9 10.65,81.9 ; JRJ45.9 9.49,81.9 ; JRJ45.9 11.81,83.2 ; JRJ45.9 9.49,83.2 ; JUSB1.7 14.89,52.64 ; JUSB1.7 13.87,52.64 ; JUSB1.7 13.87,53.66 ; JUSB1.7 14.38,52.5 ; JUSB1.7 15.03,53.15 ; JUSB1.7 14.38,53.8 ; JUSB1.7 14.89,53.66 ; 141.55,25.19 H7.1 ; H7.1 139.64,27.1 ; H7.1 142.95,25.7 ; H7.1 142.95,28.5 ; H7.1 141.55,29.01 ; H7.1 140.15,28.5 ; H7.1 143.46,27.1 ; H7.1 140.15,25.7 ; 11.75,45.3 JUSB1.10 ; JUSB1.10 15.25,44.45 ; JUSB1.10 11.75,44.45 ; JUSB1.10 15.25,45.3 ; JUSB1.10 15.25,46.15 ; JUSB1.10 13.5,44.45 ; JRJ45.11 4.01,65.1 ; JRJ45.11 1.69,65.1 ; JRJ45.11 2.85,66.4 ; JRJ45.11 4.01,65.75 ; JRJ45.11 1.69,65.75 ; JRJ45.11 1.69,66.4 ; JRJ45.11 4.01,66.4 ; JRJ45.11 2.85,65.1 ; HCPU4.1 98.27,38.87 ; HCPU4.1 94.83,38.87 ; HCPU4.1 94.83,42.31 ; HCPU4.1 98.91,40.59 ; HCPU4.1 98.27,42.31 ; HCPU4.1 96.55,42.95 ; HCPU4.1 96.55,38.23 ; HCPU4.1 94.19,40.59 ; 5.05,61.85 JUSB1.13 ; JUSB1.13 7.75,61 ; JUSB1.13 6.4,61.85 ; JUSB1.13 5.05,61 ; JUSB1.13 7.75,61.85 ; 15.37,25.24 JUSB2.4 ; JUSB2.4 16.39,26.26 ; JUSB2.4 16.39,25.24 ; JUSB2.4 15.23,25.75 ; JUSB2.4 15.37,26.26 ; JUSB2.4 16.53,25.75 ; JUSB2.4 15.88,26.4 ; JUSB2.4 15.88,25.1 ; JHDMI1.11 11.5,97.8 ; JHDMI1.11 10.49,97.35 ; JHDMI1.11 10.6,97.8 ; JHDMI1.11 11.61,97.35 ; JHDMI1.11 11.5,96.9 ; JHDMI1.11 10.6,96.9 ; H13.1 216.25,65.5 ; H13.1 211.45,63.59 ; H13.1 211.45,67.41 ; H13.1 213.85,63.59 ; H13.1 216.25,63.59 ; H13.1 211.45,65.5 ; H13.1 216.25,67.41 ; H13.1 213.85,67.41 ; H6.1 208.85,62.45 ; H6.1 206.05,62.45 ; H6.1 209.36,63.85 ; H6.1 206.05,65.25 ; H6.1 207.45,65.76 ; H6.1 207.45,61.94 ; H6.1 208.85,65.25 ; H6.1 205.54,63.85 ; H5.1 9.4,42.6 ; H5.1 6.6,42.6 ; H5.1 6.09,41.2 ; H5.1 9.91,41.2 ; H5.1 8,39.29 ; H5.1 8,43.11 ; H5.1 9.4,39.8 ; H5.1 6.6,39.8 ; H12.1 46.97,129.33 ; H12.1 46.97,132.27 ; H12.1 44.03,132.27 ; H12.1 44.03,129.33 ; H12.1 45.5,128.79 ; H12.1 47.51,130.8 ; H12.1 43.49,130.8 ; H12.1 45.5,132.81 ; JHDMI1.2 13.16,92.85 ; JHDMI1.2 12.15,93.3 ; JHDMI1.2 12.15,92.4 ; JHDMI1.2 13.05,93.3 ; JHDMI1.2 12.04,92.85 ; JHDMI1.2 13.05,92.4 ; JHDMI1.2 12.6,92.29 ; 5.05,20.55 JUSB2.11 ; JUSB2.11 5.05,21.4 ; JUSB2.11 6.4,20.55 ; JUSB2.11 7.75,21.4 ; JUSB2.11 7.75,20.55 ; JUSB2.13 6.4,37.95 ; JUSB2.13 5.05,37.95 ; JUSB2.13 7.75,37.95 ; JUSB2.13 5.05,37.1 ; JUSB2.13 7.75,37.1
  BOTTOM w0.089: UC1.A36 UC1.C36 ; UC1.AR54 79.75,82.37 79.75,82.19 79.66,82.1 79.66,81.91 79.67,81.9 79.67,81.89 79.85,81.72 ; UC1.A48 v2(95.76,80.14) ; UC1.AW54 77.82,81.97 ; 87.76,57.69 88.1,58.02 88.1,59.01 87.99,59.11 87.99,59.29 87.77,59.52 87.77,59.72 87.92,59.88 87.92,59.98 ; UC1.AF55 UC1.AF53 ; 74.02,73.38 73.67,73.73 73.67,73.85 73.28,74.24 73.21,74.28 UC1.BK35 ; UC1.BK39 73.24,76.08 73.66,75.66 ; 73.62,77.53 73.39,77.71 73.23,77.71 72.71,77.42 UC1.BL42 ; v2(77.83,81.57) 77.25,81.59 76.87,81.97 ; 88.64,57.12 88.76,57.24 88.76,59.41 UC1.T3
  BOTTOM w0.102: v2(26.89,97.79) v3(26.32,97.79) ; UC1.A40 95.22,76.45 94.98,76.45 94.8,76.26 94.57,76.26 94.39,76.44 ; v3(26.35,44.19) v2(26.35,43.57) ; v2(136.83,37.85) v3(136.83,37.14) ; v3(219.24,83.94) 219.24,83.43 v2(219.49,83.18) ; v2(113.32,35.87) v3(113.32,35.3) ; v2(101.7,34.09) 101.89,33.9 v3(101.89,33.02) ; v3(151.48,48.54) v2(152.17,48.54) ; UC1.A12 UC1.C12 ; v3(223.36,83.88) v2(223.36,83.18) ; 87.76,57.69 87.73,57.65
  BOTTOM w0.127: v2(73.12,137.35) v2(73.69,136.77) 74.68,135.78 74.68,134.2 74.43,133.94 73.95,133.94 73.67,134.22 v2(73.67,134.42) 73.52,134.58 73.52,135.9 72.83,136.58 v2(72.68,136.58)
  BOTTOM w0.152: UC1.BL32 72.18,72.92 v2(71.58,72.32) ; v2(76.43,83.92) 76.78,83.57 UC1.BB55
  BOTTOM w0.203: CE18.2 116.83,50.42 UE1.94 ; v2(72.11,64.81) UC1.BL14 ; UC1.AM55 81.28,83.7 v2(81.26,83.73) ; v2(125.81,51.59) 126.05,51.59 126.28,51.82 UE1.113 ; UC1.A24 95.75,69.32 v2(96.06,69.01) ; UC1.AK55 82.2,82.95 82.2,84.44 82.39,84.63 v2(82.39,84.77) ; v2(96.24,63.81) 96.19,63.81 96.1,63.91 UC1.A12 ; v2(132.5,47.22) UE1.11 ; JDB1.12 143.53,39.12 142.07,39.12 141.95,39.25 v2(141.32,39.25) ; UC1.BC25 v2(76.88,70.23) ; UE1.35 131.48,38.35 131.35,38.48 v2(131.03,38.48) ; v2(95.97,74.94) 95.76,74.73 UC1.A36 ; UC1.W2 UC1.W3 ; UC1.F4 v2(93.19,60.96) ; UM3.11 104.49,40.4 v2(104.43,40.46) ; UC1.K55 91.2,83.48 v2(91.28,83.56) ; v2(132.62,41.99) 132.62,42.02 UE1.24 ; v2(96.06,78.38) 96.02,78.33 UC1.A44 ; UC1.BL51 72.49,81.31 71.91,81.89 v2(71.91,82.06) ; v2(93.56,58.86) 93.33,59.09 UC1.F1 ; UC1.A20 96.09,67.51 v2(96.17,67.43)
  BOTTOM w0.229: UC1.BB28 UC1.BD28 UC1.BE28 UC1.BG28 UC1.BH28 UC1.BJ28 UC1.BL28 ; UC1.BB28 UC1.AY28 UC1.AW28 UC1.AU28 ; UC1.BB28 UC1.BA27 ; v2(85.07,71.5) 85.44,71.87 UC1.AC29 ; UC1.Y31 v2(87.24,72.26) ; v2(71.97,80.48) 72.13,80.48 72.31,80.3 72.48,80.14 UC1.BL48 ; v2(83.99,83.45) UC1.AF55 ; JKB1.30 v2(82.95,35.24)
  BOTTOM w0.254: v2(80.17,126.49) 79.73,126.05 JWLAN1.19 ; JDIMM1.103 41.4,85.18 v2(41.49,85.08) ; UC1.AN8 v2(81.2,62.09) UC1.AL8 ; UC1.E55 93.64,83.43 v2(93.76,83.55) ; UC1.AR12 v2(79.64,63.51) ; v2(37.22,35.19) 37.22,35.03 37.38,34.88 JSSD1.9 ; UC1.BG6 v2(74.74,62.05) UC1.BF9 ; CM11.2 102.94,41.97 v2(102.65,41.97) ; UC1.BC19 v2(76.88,66.73) ; UC1.AR7 v2(79.64,61.37) ; v2(93.68,81.18) 93.59,81.09 UC1.E50 ; v2(23.15,75.18) 22.58,75.75 CL9.2 ; v2(80.2,107.02) 80.21,107.02 80.21,107.03 RC174.2 ; v2(129.03,55.05) 129.23,55.25 129.23,56.2 128.33,57.1 128.33,58.82 128.69,59.18 132.94,59.18 133.32,58.8 133.32,54.35 133.1,54.13 132.02,54.13 v2(131.54,54.61) ; RC172.2 83.51,107.03 v2(83.6,107.12) ; v2(41.25,57.86) 41.07,57.68 JDIMM1.205 ; UC1.AY15 v2(77.59,64.9) ; UC1.AV15 v2(78.3,64.9) UC1.AY13 ; UC1.BD9 v2(76.17,63.04) UC1.BC11 ; UC1.AR39 v2(79.74,76.58) ; v2(214,53.81) 214,54.12 213.68,54.45 JEDP1.13 ; CC16.1 84.29,51.47 87.28,54.47 v2(87.28,56.38) 87.35,56.45 87.35,57.27 87.73,57.65 ; UC1.AU10 v2(79.64,62.8) UC1.AR10 ; v2(87.54,50.92) 87.54,51.3 88.43,52.19 v2(88.43,56.38) 88.43,56.9 88.64,57.12 ; UC1.AW10 v2(77.81,62.8) ; UC1.AN10 v2(81.2,63.51) UC1.AL10 ; CC17.1 88.81,49.98 88.81,46.73 88.36,46.29 84.36,46.29 84.17,46.48 v2(84.17,48) ; UC1.BC17 v2(76.88,65.86) ; JWLAN1.18 70.44,125.8 70.2,126.04 v2(70.2,126.45) ; UC1.AV23 v2(79.08,69.04) ; UC1.AA35 v2(85.79,74.55) ; UC1.BD15 v2(76.17,64.9) ; PUH01.8 v2(150.44,61.04)
  BOTTOM w0.305: v2(37.77,98.05) 38.25,98.05 38.38,98.18 JDIMM1.51 ; JSSD1.71 21.87,35.11 v2(22.01,35.24) ; 41.3,60.68 JDIMM1.193 ; v2(36.05,35.18) 36.05,35.03 35.87,34.86 JSSD1.15 ; JDIMM1.226 v2(29.74,52.43) ; JWLAN1.33 78,129.55 77.79,129.34 77.57,129.34 v2(77.31,129.09) ; v2(22.01,35.87) 21.68,35.87 21.38,35.57 JSSD1.73 ; JSSD1.33 31.38,34.88 31.22,35.03 v2(31.22,35.18) ; JDIMM1.102 v2(29.88,85.43) ; JDIMM1.218 v2(29.74,54.43) ; v2(32.89,61.72) 32.68,61.93 JDIMM1.188 ; 30.35,65.92 30.11,66.16 v2(29.9,66.16) ; JDIMM1.52 v2(32.82,97.93) ; v2(41.15,55.98) 40.85,55.68 JDIMM1.213 ; JDIMM1.90 v2(32.76,88.43) ; JSSD1.45 28.38,33.25 28.25,33.12 v2(28.25,32.81) ; JDIMM1.223 v2(37.49,53.18) ; v2(29.74,47.12) 30.22,47.12 30.41,46.92 ; JWLAN1.7 v2(77.44,123.05) ; v2(32.89,110.53) 32.78,110.43 JDIMM1.2 ; JHDD1.7 v2(187.2,36.63) ; JDB1.24 143.34,41.93 143.03,41.63 v2(143.03,41.61) ; JDIMM1.234 30.21,50.43 v2(29.77,50.87) ; JWLAN1.13 77.2,124.55 v2(76.81,124.15) ; JDIMM1.5 v2(38.04,109.68) ; JDIMM1.197 40.76,59.68 v2(41.53,60.45) 41.53,60.48 41.32,60.69 ; v2(32.93,108.43) JDIMM1.10 ; JDIMM1.23 40.88,105.18 v2(41.82,106.11) ; 37.3,110.68 36.82,110.2 v2(36.82,109.7) ; JDIMM1.57 40.89,96.68 v2(41.2,96.36) ; 38.48,100.18 JDIMM1.43 ; JDIMM1.206 30.09,57.43 v2(29.81,57.14) ; v2(32.91,109.6) 32.74,109.43 JDIMM1.6 ; JHDD1.4 v2(188.7,36.63) ; v2(142.97,36.13) 143.19,35.91 JDB1.22 ; JSSD1.57 v2(25.38,32.88) ; JDIMM1.181 38.28,63.68 ; v2(32.97,91.48) 32.92,91.43 JDIMM1.78 ; 38.07,101.12 37.41,101.12 36.93,101.59 v2(36.93,101.73) 36.93,102.49 37.61,103.17 ; v2(32.79,65.11) 32.6,64.93 JDIMM1.176 ; JDIMM1.93 38.02,87.68 v2(37.41,88.28) 37.81,88.68 JDIMM1.89 ; v2(30,32.8) 30,33.11 29.87,33.24 JSSD1.39 ; JDIMM1.18 29.87,106.43 v2(29.7,106.59) 29.7,107.12 30.01,107.43 ; v2(32.79,87.55) 32.66,87.43 JDIMM1.94 ; JDIMM1.184 32.85,62.93 v2(32.86,62.91) ; 29.77,59.27 v2(29.77,59.27) 29.77,58.73 30.07,58.42 ; JEDP1.17 v2(211.43,52.45) ; JFP1.1 v2(221,29.52) ; v2(29.74,45.86) 30.23,45.86 30.29,45.93 JDIMM1.252 ; CL28.2 21.34,83.68 v2(21.08,83.94) ; CE13.2 136.11,49.56 136.18,49.56 v2(136.18,49.97) 136.24,49.91 137,49.91 137.7,49.21 CE23.1 ; 40.47,84.18 JDIMM1.107 ; 38.28,63.68 38.03,63.43 v2(37.55,63.43) ; JFP1.3 220,29.65 v2(220.13,29.52) ; v2(213.52,50.35) 213.52,49.78 213.19,49.45 JEDP1.23 ; v2(38.51,91.56) 38.62,91.68 JDIMM1.77 ; JDIMM1.243 40.73,48.18 v2(41.09,47.82) ; JSSD1.51 v2(26.87,32.88) ; JHDD1.1 v2(190.2,36.63) ; v2(37.52,50.9) 37.79,51.18 JDIMM1.231 ; 30.42,46.93 JDIMM1.248 ; v2(29.74,51.43) JDIMM1.230 ; v2(29.74,49.09) 30.08,49.43 JDIMM1.238 ; JDIMM1.35 v2(40.98,102.18) ; 40.82,107.18 41.15,106.84 v2(41.15,106.31) 41.01,106.18 JDIMM1.19 ; JDIMM1.56 32.44,96.93 v2(32.79,96.57) ; v2(77.83,132.55) JWLAN1.45 ; JDIMM1.172 30.36,65.93 ; v2(37.95,90.1) 38.37,89.68 JDIMM1.85 ; v2(33.05,35.18) 33.05,35.03 32.87,34.86 JSSD1.27 ; JDIMM1.40 v2(30.27,100.93) ; JFP1.4 v2(219.5,29.52) ; JDIMM1.192 v2(29.87,60.93) ; v2(29.87,55.43) JDIMM1.214 ; JDIMM1.26 30.37,104.43 v2(29.95,104.85) 30.53,105.43 JDIMM1.22 ; JSSD1.21 34.38,34.88 34.22,35.03 v2(34.22,35.18) ; JEDP1.38 v2(213.33,41.95) ; 38.53,99.18 JDIMM1.47 ; v2(42.16,85.6) 41.59,86.18 JDIMM1.99 ; v2(144.43,41.62) 144.43,41.63 144.74,41.93 JDB1.23 ; JWLAN1.51 78.27,134.05 78.08,133.85 77.31,133.85 v2(77.25,133.92) ; JDIMM1.14 30.01,107.43 ; JWLAN1.69 v2(77.84,138.55) ; JEDP1.20 v2(211.43,50.95) ; JDB1.21 146.04,35.91 v2(146.25,36.13) ; JEDP1.32 v2(211.49,44.95) ; JSSD1.75 20.87,35.22 v2(20.86,35.24) ; 40.72,56.68 JDIMM1.209 ; JWLAN1.63 v2(77.84,137.05) ; JDIMM1.44 32.99,99.93 v2(33.14,99.78) ; JDIMM1.36 32.83,101.93 v2(32.95,101.81) ; v2(77.84,135.55) JWLAN1.57 ; JWLAN1.39 v2(77.83,131.05) ; JDIMM1.1 37.3,110.68 ; JDIMM1.72 v2(30.28,92.93) ; JDIMM1.30 v2(30.11,103.43) ; JEDP1.35 213.21,43.45 v2(213.46,43.2) ; JDIMM1.48 v2(30.27,98.93) ; 37.61,103.18 JDIMM1.31 ; JDIMM1.68 30.49,93.93 v2(30.19,94.23) ; 41.33,49.75 v2(41.33,50.23) ; JDIMM1.244 v2(29.74,47.93) ; JDIMM1.15 40.81,107.18 ; JWLAN1.1 77.44,121.55 77.32,121.43 v2(77.14,121.43) ; 30.08,58.43 JDIMM1.202
  BOTTOM w0.356: v2(33.63,121.41) 33.63,120.53 PC2504.2 ; CG47.2 14.46,108.56 CG46.2 ; CC3.2 109.13,70.82 v2(109.2,70.75)
  BOTTOM w0.381: UC8.3 103.48,85.5 103.48,85.59 102.97,86.1 v2(102.97,86.36) ; PCB08.1 193.12,54.29 v2(193.12,54.8) ; PD5.1 149.31,43.89 v2(149.54,43.66) ; CM29.2 105.34,42.17 CM28.2 ; CE12.2 v2(134.15,34.82) ; v2(137.23,42.01) 137.23,42 136.93,42.3 CE11.2 ; v2(116.11,49.02) 116.2,49.11 116.2,49.18 116.49,49.47 CE18.2 ; CE10.2 115.65,51.79 v2(115.65,52.26) ; v2(3.25,133.66) LED1.1 LED1.3 ; v2(112.67,45.55) 112.32,45.91 CM5.2 ; PJPDC1.8 94.92,149.22 v2(95.31,149.61) ; PCG10.1 102.61,140.46 v2(102.65,140.5) ; EU2606.3 v2(21.98,37.71) ; v2(182.21,42.59) 182.21,42.6 181.81,43 QS1.1 ; EU2605.3 v2(21.62,51.75) ; PJPDC1.7 v2(77.03,149.22) ; CE4.2 123.01,56.08 123.53,55.56 CE20.1
  BOTTOM w0.432: v2(27.36,89.15) 27.18,88.97 QG1.4 ; QG1.1 25.45,87.67 26.01,87.12 26.06,87.12 26.06,87.12 26.67,87.12 v2(26.7,87.08)
  BOTTOM w0.457: v2(100.81,77.16) 100.86,77.21 101.74,77.21 CC2.2 ; v2(46.07,30.16) 46.01,30.22 PR1805.2 ; CC16.1 84.17,50.05 v2(84.17,48) ; CC1.1 102.22,67.75 102.29,67.67 v2(102.73,67.67) ; CE5.2 137.51,45.84 137.77,46.1 v2(137.77,46.73) 137.7,46.79 DE1.1 ; CC17.1 88.63,50.47 88.17,50.92 v2(87.54,50.92) ; v2(116.11,49.02) 115.65,48.56 CE8.2 ; CC8.2 97.63,90.09 98.09,90.55 v2(98.21,90.55) ; RC12.2 103.78,66.96 103.78,67.64 v2(103.67,67.75) ; CE7.2 CE6.2 v2(136.89,43.62) ; UC2.3 103.08,90.21 v2(103.16,90.29) 105.33,90.29 RC50.2 ; PC1805.2 PR1802.2 46.69,29.36 46.49,29.36 46.33,29.52 v2(46.07,29.52) ; v2(99.79,88.64) 99.3,88.15 RC58.2 ; v2(85.89,53.97) 85.89,53.72 85.37,53.2 RC76.2 ; YC1.4 v2(86.37,47.15) ; CE4.2 122.84,56.19 122.6,56.43 v2(122.6,56.83) ; CC22.2 RC116.2 ; CC15.2 92.76,86.74 RC91.1 92.43,87.75 v2(92.77,88.09) ; v2(105.89,73.08) 105.89,72.5 105.72,72.33 CC91.2 ; v2(206.41,34.98) 206.22,34.98 205.2,36 JIOB1.9 ; YC1.2 v2(86.39,48.85) ; v2(100.68,69.59) 101.29,69.59 RC17.1 RC11.2
  BOTTOM w0.508: CC7.2 100.33,85.06 v2(100.43,85.06) ; CC4.2 102.97,92.26 v2(102.59,92.64) ; PCM03.2 22.7,107.89 v2(22.7,106.93) ; Q13.3 109.88,28.84 v2(110.4,28.32) ; v2(155.08,59.6) 154.97,59.6 154.53,60.04 PCH09.2 ; JHDD1.14 v2(178.47,32.1) ; v2(189.82,50.88) PCB05.2 190.52,49.98 PRB13.1 ; PCZ08.1 PCZ15.2 v2(90.84,135.19) ; PCG02.1 94.33,132.32 v2(94.33,131.62) ; CG47.2 14.46,109.74 14.54,109.82 v2(14.55,109.82) ; CC95.2 70.96,60.51 ; JODD1.1 185.2,64.78 v2(185.63,65.21) ; JPWR1.6 v2(226.8,68.31) ; RC92.2 RC94.2 109.01,89.01 109.2,88.82 109.2,88.72 109.41,88.51 v2(109.51,88.51) ; PR508.2 PC516.1 v2(217.14,85.15) ; PCH11.2 v2(150.94,56.55) ; PCB10.2 v2(201.58,51.82) ; PCZ17.2 87.49,139.84 87.11,139.45 v2(87.11,139.1) ; PC2502.2 28.36,121.53 v2(28.55,121.34) ; D11.1 v2(207.27,45.69) ; PCG01.2 95.32,133.59 v2(95.32,132.81) 95.84,132.29 PCG19.2 ; v2(120.43,56.45) 120.06,56.08 CE19.2 RE35.2 ; JODD1.7 v2(188.2,65.53) v2(188.2,66.16) JODD1.8 ; v2(17.69,41.08) 18.04,41.42 EU2607.1 ; RL2.1 22.65,82.37 v2(22.2,82.82) ; DA6.1 v2(205.84,45.59) ; R40.2 115.92,30.41 v2(116.24,30.09) 116.75,30.6 C19.2 ; CC90.1 102.02,91.94 v2(101.57,92.39) 100.94,91.75 RC51.2 ; v2(109.44,64.83) 109.44,64.14 CS114.2 ; v2(103.03,43.25) 103.15,43.25 103.98,42.41 CM30.2 CM29.2 ; PCB19.2 190.56,44.15 190.56,43.8 v2(190.61,43.75) ; v2(154.53,59.18) 154.5,59.15 PCH10.2 ; v2(31.4,125.85) 31.02,125.47 PU2501.8 ; v2(206.92,35.49) 206.2,36.21 JIOB1.8 ; JKBBL1.5 97.25,30.79 96.87,30.41 v2(95.98,30.41) ; PC515.2 v2(206.92,84.55) ; v2(85.51,30.41) 85.17,30.75 JKB1.32 ; CL30.2 22.78,89.04 v2(22.82,89.07) ; v2(122.14,54.41) 122.14,55 CE3.2 CE21.1 ; v2(22.51,47.11) 22.16,47.11 EU2608.1 ; EU2701.1 v2(222.35,36) ; PRH09.2 v2(152.61,56.68) ; JSPK1.6 v2(16.67,2) ; PR511.2 v2(204.25,85.15) ; PCB14.2 v2(200.47,48.19) ; PC308.2 v2(165.83,53.72) ; JODD1.26 183.53,65.15 v2(184.25,65.15) ; RC108.1 v2(91.41,86.27) ; v2(195.46,56.02) PRB16.2 PRB17.1 ; RC115.2 77.11,96.53 v2(76.23,97.4) 77.07,98.24 CC96.1 ; JODD1.14 v2(191.2,66.16) v2(191.2,65.53) JODD1.13 ; PD502.2 v2(17.81,117.15) ; JEDP1.42 v2(217.66,62.15) ; CM17.2 22.07,85.71 RG56.2 22.18,85.72 23.8,85.72 v2(24.35,86.28) ; PRH04.2 v2(150.07,56.6) ; JHDD1.13 v2(192,36.57) ; v2(137.47,39.68) RE29.2 ; PR2503.2 v2(26.08,124.63) ; JIOB1.5 209.2,37.46 v2(209.58,37.84) ; JODD1.2 v2(185.2,68.99) ; PCG08.2 98.61,143.11 v2(97.9,143.11) ; v2(103.78,59.61) 103.78,60.17 CLRP1.1 ; PCG03.2 94.59,142.08 94.59,142.67 v2(94.65,142.73) ; PCB37.1 191.87,55.06 PCB07.1 192.06,55.66 v2(191.65,56.07) ; PRB38.2 195.26,44.31 v2(195.75,43.81) ; Q8.3 90.71,39.51 v2(90.71,39.94) ; v2(27.4,108.77) 26.97,108.77 PCM23.2 PCM22.2 ; v2(131.34,34.22) 130.89,34.22 CE1.2 ; EC3001.2 v2(88.12,35.05) ; v2(102.62,141.54) PCG06.2 ; v2(172.29,56.02) 172.29,56.04 171.76,56.57 PR303.2 ; v2(79.88,93.41) 80.04,93.57 CC22.2 ; RE15.1 v2(115.08,36.76) ; PR308.2 169.04,53.51 169.55,54.02 v2(169.55,54.92) ; JKB1.31 58.79,30.75 v2(58.96,30.92) ; JEDP1.41 v2(217.76,39.25) ; JPWR1.1 v2(221.2,62.61) ; PCB12.2 200.74,49.97 PCB13.2 v2(201.56,50.05) ; PCB16.2 198.79,46.03 v2(198.34,46.48) ; UU3.2 v2(195.74,36.51) ; CE2.2 v2(136.83,37.85) ; PCG07.1 91,136.69 v2(90.84,136.69) ; PCZ16.2 v2(84.17,138.78) ; YE1.2 132.27,55.33 v2(131.54,54.61) ; v2(85.42,127.33) PCZ14.2 ; C27.2 v2(126.28,31.49) ; v2(91.03,30.41) 90.27,30.41 89.85,30.83 JKBBL1.6 ; JDIMM1.261 46.69,42.54 v2(44.73,42.54) ; PCB09.2 PRB23.2 v2(200.74,52.64) ; v2(196.38,44.06) 196.1,44.34 PCB17.2 ; JSSD1.76 19.78,31.42 v2(19.53,31.17) ; JTP1.5 v2(121.05,28.32) ; C26.2 v2(123.59,31.55) ; JFP1.10 v2(223.15,28.85) ; v2(215.35,25.78) JFP1.9 ; PRB26.2 v2(193.89,57.18) ; JODD1.25 v2(198.45,63.9) ; JIOB1.2 v2(212.2,37.78) ; JPWR1.5 v2(218.6,68.39) ; JIOB1.1 v2(213.2,37.78) ; v2(108.75,80) 109.06,80.32 UC11.4 ; v2(109.44,87.37) RC102.2 ; JSPK1.5 v2(12.1,3.36) ; PC2503.2 v2(38.64,125.09) ; PC2501.2 v2(38.43,123.73) ; v2(204.2,35.62) JIOB1.10 ; RC76.2 RC75.2
  vias: v2(0.43,122.83) v2(0.45,115.77) v2(0.55,83.4) v2(0.55,66.49) v2(0.55,65.16) v2(2,133.64) v2(1.99,129.41) v2(2.83,5.55) v2(2.97,88.64) v2(4.29,109.09) v2(4.69,64.83) v2(5.16,66.52) v2(5.44,105.04) v2(5.79,85.8) v2(5.89,41.2) v2(6.85,87.63) v2(6.85,83.97) v2(6.95,43.03) v2(6.95,39.37) v2(7.59,63.57) v2(7.83,81.78) v2(7.83,66.52) v2(8.35,20.57) v2(8.95,87.63) v2(8.95,83.97) v2(9.05,43.03) v2(9.05,39.37) v2(9.24,133.64) v2(9.53,61.98) v2(9.64,63.55) v2(9.6,60.33) v2(9.6,45.96) v2(9.67,22.06) v2(9.9,5.53) v2(10.01,85.8) v2(10.11,41.2) v2(10.49,102.75) v2(10.5,91.08) v2(11.15,20.51) v2(11.92,63.62) v2(12.17,129.64) v2(12.43,80.68) v2(12.81,0.43) v2(13.05,113.34) v2(14.28,43.09) v2(14.28,42.5) v2(14.28,41.92) v2(14.28,41.33) v2(14.45,3.42) v2(16.42,24) v2(16.42,22.47) v2(17.72,48.94) v2(17.72,47.18) v2(18.32,4.88) v2(19.08,31.55) v2(19.27,35.87) v2(19.27,35.29) v2(19.63,81.02) v2(19.66,128.67) v2(19.97,127) v2(20.04,126.17) v2(19.97,55.68) v2(19.97,55.11) v2(19.97,54.54) v2(19.97,53.97) v2(20.1,57.65) v2(20.39,49.39) v2(20.42,2.79) v2(20.43,0.43) v2(20.67,127) v2(20.67,126.17) v2(20.74,94.99) v2(20.74,93.15) v2(20.74,91.24) v2(20.74,57.65) v2(20.8,96.83) v2(20.86,35.87) v2(21.08,85.06) v2(21.08,82.82) v2(21.31,57.65) v2(21.37,127) v2(21.88,57.65) v2(22.2,85.06) v2(22.2,83.94) v2(22.32,115.31) v2(22.83,77.4) v2(23.33,93.18) v2(23.31,85.06) v2(23.31,83.94) v2(23.31,82.82) v2(23.35,96.83) v2(23.35,94.97) v2(23.39,91.35) v2(23.66,114.49) v2(23.72,102.1) v2(23.72,101.47) v2(23.66,21.59) v2(23.91,89.85) v2(24.3,117.09) v2(24.29,49.84) v2(24.29,21.59) v2(24.35,102.1) v2(24.35,101.47) v2(24.67,60.76) v2(24.85,43.62) v2(24.93,117.71) v2(24.93,116.47) v2(24.88,36.08) v2(24.99,102.1) v2(24.99,101.47) v2(25.24,80.45) v2(25.48,43.65) v2(25.62,102.1) v2(25.62,101.47) v2(26.26,102.1) v2(26.26,101.47) v2(26.51,103.25) v2(26.51,102.61) v2(26.69,115.84) v2(26.75,86.36) v2(26.83,77.91) v2(26.83,75.37) v2(26.89,102.1) v2(26.89,101.47) v2(27.09,36.74) v2(27.24,38.87) v2(27.28,128.67) v2(27.4,6.47) v2(28.05,0.43) v2(28.29,6.41) v2(28.67,3.61) v2(29.18,6.54) v2(29.6,37.63) v2(29.74,43.07) v2(29.88,95.63) v2(30.08,14.59) v2(30.08,13.01) v2(30.08,11.44) v2(30.2,90.86) v2(31.59,37.65) v2(31.66,14.59) v2(31.66,13.01) v2(31.66,11.44) v2(31.72,4.57) v2(31.97,124.39) v2(31.97,122.74) v2(32.17,5.01) v2(32.72,37.65) v2(32.67,30.54) v2(32.8,123.57) v2(32.81,104.81) v2(32.82,49.56) v2(32.93,93.72) v2(33.1,102.74) v2(33.07,59.18) v2(33.23,14.59) v2(33.23,13.01) v2(33.23,11.44) v2(33.31,30.54) v2(33.4,79.31) v2(33.44,8.06) v2(33.47,51.94) v2(33.63,124.39) v2(33.63,122.74) v2(33.55,106.17) v2(33.75,55.25) v2(33.77,48.2) v2(33.87,82.35) v2(33.86,57.22) v2(33.93,45.62) v2(33.94,30.54) v2(33.95,60.25) v2(34.01,5.01) v2(34.06,96.57) v2(34.08,90.08) v2(34.12,70.43) v2(34.13,69.21) v2(34.13,63) v2(34.13,61.72) v2(34.09,49.56) v2(34.18,109.6) v2(34.21,104.75) v2(34.26,101.73) v2(34.29,44.55) v2(34.46,93.72) v2(34.53,37.68) v2(34.45,5.52) v2(34.59,99.83) v2(34.74,51.94) v2(34.69,39.24) v2(34.82,128.82) v2(34.95,77.27) v2(35.01,55.2) v2(35,50.9) v2(35.08,106.17) v2(35.09,102.72) v2(35.08,91.48) v2(35.08,80.82) v2(35.07,75.46) v2(35.1,63.31) v2(35.1,53.2) v2(35.23,59.12) v2(35.2,57.21) v2(35.2,45.62) v2(35.31,70.42) v2(35.32,49.59) v2(35.34,30.54) v2(35.35,96.59) v2(35.38,90.08) v2(35.42,84.14) v2(35.36,82.36) v2(35.35,67.86) v2(35.45,109.6) v2(35.55,60.29) v2(35.64,48.21) v2(35.59,8.44) v2(35.59,0.5) v2(35.74,104.75) v2(35.66,101.73) v2(35.68,69.41) v2(35.8,72.78) v2(35.77,55.17) v2(35.77,37.65) v2(35.78,12.38) v2(35.92,97.97) v2(36.01,108.46) v2(35.98,93.72) v2(36.01,49.62) v2(36.14,77.3) v2(36.12,65.15) v2(36.2,99.82) v2(36.23,50.91) v2(36.31,66.36) v2(36.43,45.65) v2(36.47,57.21) v2(36.6,106.17) v2(36.63,82.36) v2(36.6,67.88) v2(36.66,96.57) v2(36.68,90.1) v2(36.81,60.28) v2(37,75.45) v2(37.06,62.1) v2(37.05,16.89) v2(37.05,16.3) v2(37.17,55.23) v2(37.32,104.71) v2(37.33,84.14) v2(37.33,65.15) v2(37.25,49.62) v2(37.3,10.88) v2(37.41,99.83) v2(37.5,93.72) v2(37.55,37.65) v2(37.63,13.65) v2(37.77,45.66) v2(37.87,108.46) v2(37.87,96.57) v2(38.01,5.53) v2(38.46,92.73) v2(38.87,38.49) v2(39.07,133.67) v2(39.15,35.11) v2(39.79,35.11) v2(40.04,36.74) v2(40.77,19.08) v2(40.77,12.1) v2(41,53.31) v2(41.25,65.73) v2(43.19,124.62) v2(44.74,123.76) v2(45.46,136.72) v2(45.61,33.51) v2(45.61,31.5) v2(46.2,32.51) v2(46.26,124.42) v2(46.76,113.28) v2(46.78,33.51) v2(46.78,31.5) v2(46.95,22.93) v2(49.31,34.26) v2(49.77,121.8) v2(51.22,28.25) v2(51.42,134.55) v2(51.55,141.13) v2(51.85,28.25) v2(52.49,28.25) v2(52.8,35.68) v2(53.12,48.95) v2(53.12,28.25) v2(53.44,35.68) v2(53.53,125.18) v2(54.58,49.53) v2(54.57,22.93) v2(54.67,122.11) v2(54.9,137.63) v2(56.63,128.74) v2(56.99,52.89) v2(57.06,51.68) v2(57.49,125.08) v2(58.28,53.4) v2(58.3,51.77) v2(59.18,141.37) v2(59.44,53.4) v2(59.41,36.06) v2(59.48,52.34) v2(59.75,132.37) v2(60.04,36.06) v2(60.23,127.92) v2(60.3,53.49) v2(60.5,54.22) v2(61.95,41.65) v2(62.06,44.31) v2(62.06,42.3) v2(62.2,53.84) v2(62.19,22.93) v2(62.25,88.9) v2(62.52,80.2) v2(62.65,43.3) v2(62.65,41.65) v2(62.77,66.04) v2(63.23,44.31) v2(63.23,42.3) v2(63.34,80.2) v2(63.44,88.92) v2(63.53,66.04) v2(64.67,88.95) v2(65.12,83.75) v2(65.63,44.04) v2(65.93,88.96) v2(66.26,122.04) v2(66.26,121.41) v2(66.26,120.77) v2(66.48,73.95) v2(66.8,141.37) v2(66.9,83.05) v2(67.62,75.37) v2(67.73,83.62) v2(67.73,73.95) v2(67.87,77.34) v2(68.18,70.33) v2(68.6,68.38) v2(68.74,71.62) v2(68.9,73.95) v2(69.45,70.35) v2(69.78,68.38) v2(69.81,22.93) v2(70,71.59) v2(70.27,77.27) v2(70.46,84.26) v2(70.65,86.93) v2(70.93,91.53) v2(71.03,68.32) v2(71.23,119.45) v2(71.22,118.11) v2(71.22,116.77) v2(71.18,62.54) v2(71.38,145.33) v2(71.52,64.81) v2(71.79,93.53) v2(71.85,79.32) v2(71.78,62.56) v2(71.85,86.93) v2(71.92,77.25) v2(71.97,60.61) v2(72.2,91.53) v2(72.27,84.2) v2(72.49,146.49) v2(72.49,145.85) v2(72.49,145.22) v2(72.49,144.58) v2(72.49,143.95) v2(72.58,120.18) v2(72.72,83.35) v2(72.65,59.11) v2(73.02,86.86) v2(73.12,146.49) v2(73.12,145.85) v2(73.12,145.22) v2(73.12,144.58) v2(73.12,143.95) v2(73.25,138.49) v2(73.44,91.5) v2(73.44,54.99) v2(73.69,93.53) v2(74.08,54.99) v2(74.16,137.13) v2(74.2,72.96) v2(74.46,58.84) v2(74.74,63) v2(74.71,54.99) v2(74.78,77.38) v2(74.93,150.47) v2(75.45,55.1) v2(75.54,75.43) v2(75.47,63.94) v2(75.86,60.66) v2(76.11,78.29) v2(76.12,77.31) v2(76.05,73) v2(76.82,80.87) v2(76.87,68.33) v2(77.02,140.22) v2(77.05,58.94) v2(77,55.05) v2(77.16,119.5) v2(77.16,118.87) v2(77.43,22.93) v2(77.57,75.5) v2(77.77,60.66) v2(77.85,140.22) v2(78.09,58.86) v2(78.92,76.37) v2(79.67,65.67) v2(80.02,73.82) v2(80.04,67.69) v2(80.04,66.92) v2(79.97,59.04) v2(81.25,111.63) v2(81.25,110.99) v2(81.25,110.36) v2(81.45,75.31) v2(81.72,58.54) v2(82.01,122.61) v2(82.01,121.98) v2(82.01,121.41) v2(82.01,120.77) v2(82.01,120.2) v2(82.05,128.28) v2(82.12,76.6) v2(82.13,64.8) v2(82.16,78.73) v2(82.55,150.47) v2(82.58,122.04) v2(82.65,121.41) v2(82.65,120.77) v2(82.65,120.2) v2(83.03,78.04) v2(83.09,58.54) v2(83.35,121.28) v2(83.35,120.65) v2(83.62,66.93) v2(83.8,58.89) v2(84.35,69.22) v2(84.73,133.99) v2(84.73,132.06) v2(84.95,80.24) v2(85.05,22.93) v2(85.08,69.22) v2(85.07,66.93) v2(85.7,133.03) v2(85.66,58.81) v2(85.79,69.98) v2(85.79,69.22) v2(85.89,81.53) v2(85.89,79.56) v2(85.88,64.24) v2(85.86,62.03) v2(85.97,83.47) v2(86.17,119.08) v2(86.53,69.2) v2(86.66,133.99) v2(86.66,132.06) v2(86.78,80.87) v2(86.78,80.15) v2(86.78,79.44) v2(86.84,64.26) v2(87.24,75.31) v2(87.25,70.74) v2(87.22,69.21) v2(87.54,78.02) v2(87.6,83.48) v2(88.02,105.72) v2(88.3,78.03) v2(88.74,85.78) v2(89.17,79.5) v2(89.26,62.2) v2(89.51,110.04) v2(89.51,109.41) v2(89.52,77.91) v2(89.8,86.6) v2(89.82,83.94) v2(89.8,64.96) v2(90.14,81.53) v2(90.17,150.47) v2(90.31,105.27) v2(90.33,79.43) v2(90.36,69.37) v2(90.39,68.38) v2(90.59,149.47) v2(90.76,49.82) v2(91.03,73.91) v2(91.1,67.55) v2(91.22,149.47) v2(91.16,62.01) v2(91.32,58.22) v2(91.6,79.31) v2(91.81,64.9) v2(91.86,149.47) v2(91.9,77.26) v2(92.43,124.14) v2(92.36,123.58) v2(92.36,122.99) v2(92.49,149.47) v2(92.5,127.63) v2(92.48,76.34) v2(92.52,72.99) v2(92.52,68.44) v2(92.52,64.9) v2(92.55,127.06) v2(92.67,22.93) v2(92.79,116.52) v2(93,124.71) v2(93.13,149.47) v2(93.09,127.66) v2(93.13,127.06) v2(93.32,125.92) v2(93.32,125.32) v2(93.38,126.49) v2(93.63,124.71) v2(93.63,124.14) v2(93.63,123.58) v2(93.63,123.02) v2(93.72,127.66) v2(93.76,127.06) v2(93.95,77.26) v2(94.01,126.49) v2(93.95,125.92) v2(93.95,125.32) v2(94.01,78.18) v2(93.98,74.65) v2(93.95,50.63) v2(94.22,62.03) v2(94.27,124.71) v2(94.36,127.66) v2(94.4,127.06) v2(94.55,83.47) v2(94.65,126.49) v2(94.59,125.92) v2(94.59,125.32) v2(94.84,124.14) v2(94.9,124.71) v2(94.99,127.66) v2(95.03,127.06) v2(95.03,59.22) v2(95.13,50.54) v2(95.22,126.49) v2(95.22,125.92) v2(95.22,125.32) v2(95.54,124.71) v2(95.46,59.62) v2(95.63,127.66) v2(95.67,127.06) v2(95.79,71.05) v2(95.79,61.4) v2(96,81.82) v2(96.05,65.72) v2(96.1,138.25) v2(96.1,136.32) v2(96.89,154) v2(97.06,137.28) v2(97.24,50.73) v2(97.95,152.17) v2(97.91,55.61) v2(98.03,138.25) v2(98.03,136.32) v2(98.01,116.71) v2(98.24,51.46) v2(98.33,54.41) v2(98.9,50.8) v2(99.37,57.39) v2(99.55,52.36) v2(100.05,152.17) v2(100.11,50.76) v2(100.29,22.93) v2(100.81,67.05) v2(101.11,154) v2(101.08,57.01) v2(101.06,34.09) v2(101.23,81.45) v2(101.23,80.86) v2(101.32,51.75) v2(101.7,53.21) v2(101.76,58.56) v2(102.35,57.03) v2(102.36,61.67) v2(102.65,53.02) v2(102.62,51.65) v2(103.34,55.81) v2(104.49,38.73) v2(105.67,75.97) v2(106.03,150.76) v2(106.56,146.08) v2(106.56,138.46) v2(106.56,130.84) v2(106.56,123.22) v2(106.56,115.6) v2(107.15,23.88) v2(107.73,106.55) v2(107.73,105.91) v2(107.73,105.28) v2(107.73,102.74) v2(107.73,102.1) v2(108.37,106.55) v2(108.37,105.91) v2(108.37,105.28) v2(108.37,102.74) v2(108.37,102.1) v2(109,106.55) v2(109,105.91) v2(109,105.28) v2(109,102.74) v2(109,102.1) v2(111.46,111.03) v2(112.79,65.09) v2(114.05,39.94) v2(114.77,23.88) v2(116.75,28.32) v2(117.38,28.32) v2(118.45,109.15) v2(121.34,102.27) v2(121.34,94.65) v2(121.34,87.28) v2(121.34,79.92) v2(121.34,72.8) v2(122.39,23.88) v2(125.36,67.38) v2(125.83,28.32) v2(126.46,28.32) v2(128.9,43.75) v2(130.01,23.88) v2(131.66,65.79) v2(137.63,23.88) v2(138.31,67.57) v2(139.44,27.1) v2(140.5,28.93) v2(140.5,25.27) v2(142.6,28.93) v2(142.6,25.27) v2(143.67,49.65) v2(143.66,27.1) v2(144.23,69.3) v2(144.6,63.26) v2(145.7,23.92) v2(146.97,29.28) v2(147.61,56.32) v2(147.61,55.68) v2(147.61,54.99) v2(149.64,62.86) v2(150.21,62.86) v2(150.47,34.48) v2(150.78,62.86) v2(150.85,55.05) v2(151.29,55.49) v2(151.35,62.86) v2(151.55,45.52) v2(151.85,69.3) v2(151.99,62.92) v2(152.13,50.3) v2(152.18,45.52) v2(152.31,62.42) v2(152.56,63.11) v2(152.82,45.52) v2(153.02,30.63) v2(153.2,63.11) v2(153.45,54.92) v2(153.58,44.13) v2(153.89,63.11) v2(154.21,54.92) v2(154.21,44.13) v2(154.53,63.11) v2(155.16,63.11) v2(158.01,32.53) v2(159.52,69.3) v2(161.64,49.33) v2(162.24,74.89) v2(162.21,49.33) v2(162.85,49.33) v2(163.48,49.33) v2(163.71,76.94) v2(163.78,47.81) v2(164.05,49.33) v2(164.45,70.57) v2(164.41,47.81) v2(164.69,49.33) v2(164.93,74.86) v2(165.11,72.88) v2(165.07,47.82) v2(165.26,58.42) v2(165.63,32.53) v2(165.83,60.32) v2(165.77,47.81) v2(166.34,47.81) v2(166.79,38.22) v2(166.91,47.81) v2(166.96,76.56) v2(167.42,38.22) v2(167.8,58.35) v2(168.69,38.22) v2(168.87,78.65) v2(169.33,38.22) v2(169.96,38.22) v2(170.6,38.22) v2(170.79,59.75) v2(171.23,38.22) v2(171.33,58.76) v2(171.33,58.17) v2(171.92,58.76) v2(171.92,58.17) v2(171.87,38.22) v2(172.5,58.76) v2(172.5,58.17) v2(172.5,38.22) v2(173.14,59.58) v2(173.14,59) v2(173.14,58.42) v2(173.14,38.22) v2(173.25,32.53) v2(173.49,77.83) v2(173.72,59.57) v2(174.35,59.57) v2(176.79,78.65) v2(177.3,77.71) v2(177.26,33.33) v2(177.71,70.21) v2(178.34,70.21) v2(179.49,37.52) v2(179.55,29.28) v2(179.93,37.08) v2(180.37,52.32) v2(180.37,36.63) v2(181.52,49.56) v2(182.61,82.66) v2(183.99,64.07) v2(184.23,81.06) v2(185.78,79.15) v2(186.34,47.94) v2(186.34,47.3) v2(186.98,47.94) v2(186.98,47.3) v2(187.17,29.28) v2(187.36,40.64) v2(187.61,52.32) v2(187.61,47.94) v2(187.66,47.3) v2(188.25,47.94) v2(188.25,47.28) v2(188.38,50.59) v2(188.83,47.91) v2(188.91,86.16) v2(189.01,51.14) v2(188.98,50.58) v2(189.14,40.67) v2(190.56,80.96) v2(190.98,39.49) v2(191.35,79.13) v2(191.42,61.46) v2(191.42,60.83) v2(191.88,83.4) v2(193.73,82.48) v2(194.2,49.84) v2(194.15,36.57) v2(194.79,29.28) v2(195.3,50.94) v2(195.3,49.84) v2(195.3,48.75) v2(195.39,80.12) v2(196.39,49.84) v2(196.53,86.16) v2(196.45,84.49) v2(200.02,80.84) v2(200.02,80.26) v2(200.02,79.68) v2(200.02,79.09) v2(200.25,40.83) v2(200.25,40.19) v2(200.31,58.35) v2(200.3,57.06) v2(200.44,44.25) v2(200.61,80.84) v2(200.61,80.26) v2(200.61,79.68) v2(200.61,79.09) v2(201.19,80.84) v2(201.19,80.26) v2(201.19,79.68) v2(201.19,79.09) v2(201.77,80.26) v2(201.77,79.68) v2(202.09,40.51) v2(202.41,29.28) v2(202.47,39.68) v2(203.62,77.66) v2(204.25,49.33) v2(204.25,47.56) v2(204.22,39.68) v2(204.91,86.16) v2(205.34,63.85) v2(205.46,79.56) v2(205.77,51.75) v2(205.77,50.39) v2(206.1,53.81) v2(206.4,65.68) v2(206.4,62.02) v2(206.92,78.16) v2(207.81,79.5) v2(207.91,53.81) v2(208.24,37.98) v2(208.38,79.5) v2(208.44,39.68) v2(208.5,65.68) v2(208.5,62.02) v2(209.37,56.4) v2(209.56,63.85) v2(209.97,56.4) v2(210.03,29.28) v2(212.53,86.16) v2(213.14,34.73) v2(213.33,44.45) v2(213.55,23.92) v2(214.22,36) v2(215.05,44.38) v2(215.74,32.25) v2(215.87,45.84) v2(216.19,49.91) v2(216.38,49.33) v2(216.38,48.7) v2(218.86,83.18) v2(220.13,83.18) v2(220.15,86.16) v2(220.76,83.18) v2(221.1,23.88) v2(221.46,83.18) v2(222.73,83.18) v2(224.96,44.07) v2(224.96,36.45) v2(224.96,28.83) v2(225.84,50.22) v2(227.95,86.04) v2(227.95,78.42) v2(227.95,70.8) v2(227.94,55.56) v2(227.97,63.17) v3(15.59,126.36) v3(22.32,127) v3(33.12,31.94) v3(38.96,130.36) v3(51.34,27.43) v3(52.42,124.01) v3(56.3,134.81) v3(58.64,87.24) v3(68.74,90.86) v3(75.41,94.55) v3(91.66,123.57) v3(108.56,103.82) v3(152.75,44.38) v3(166.02,71.31) v3(169.07,58.42) v3(172.69,42.54) v3(179.04,33.14) v3(179.99,37.84) v3(181.83,74.67) v3(184.63,79.12) v3(190.92,82.48) v3(193.9,78.99) v3(195.17,74.99) v3(195.74,83.24) v3(204.31,79.62)
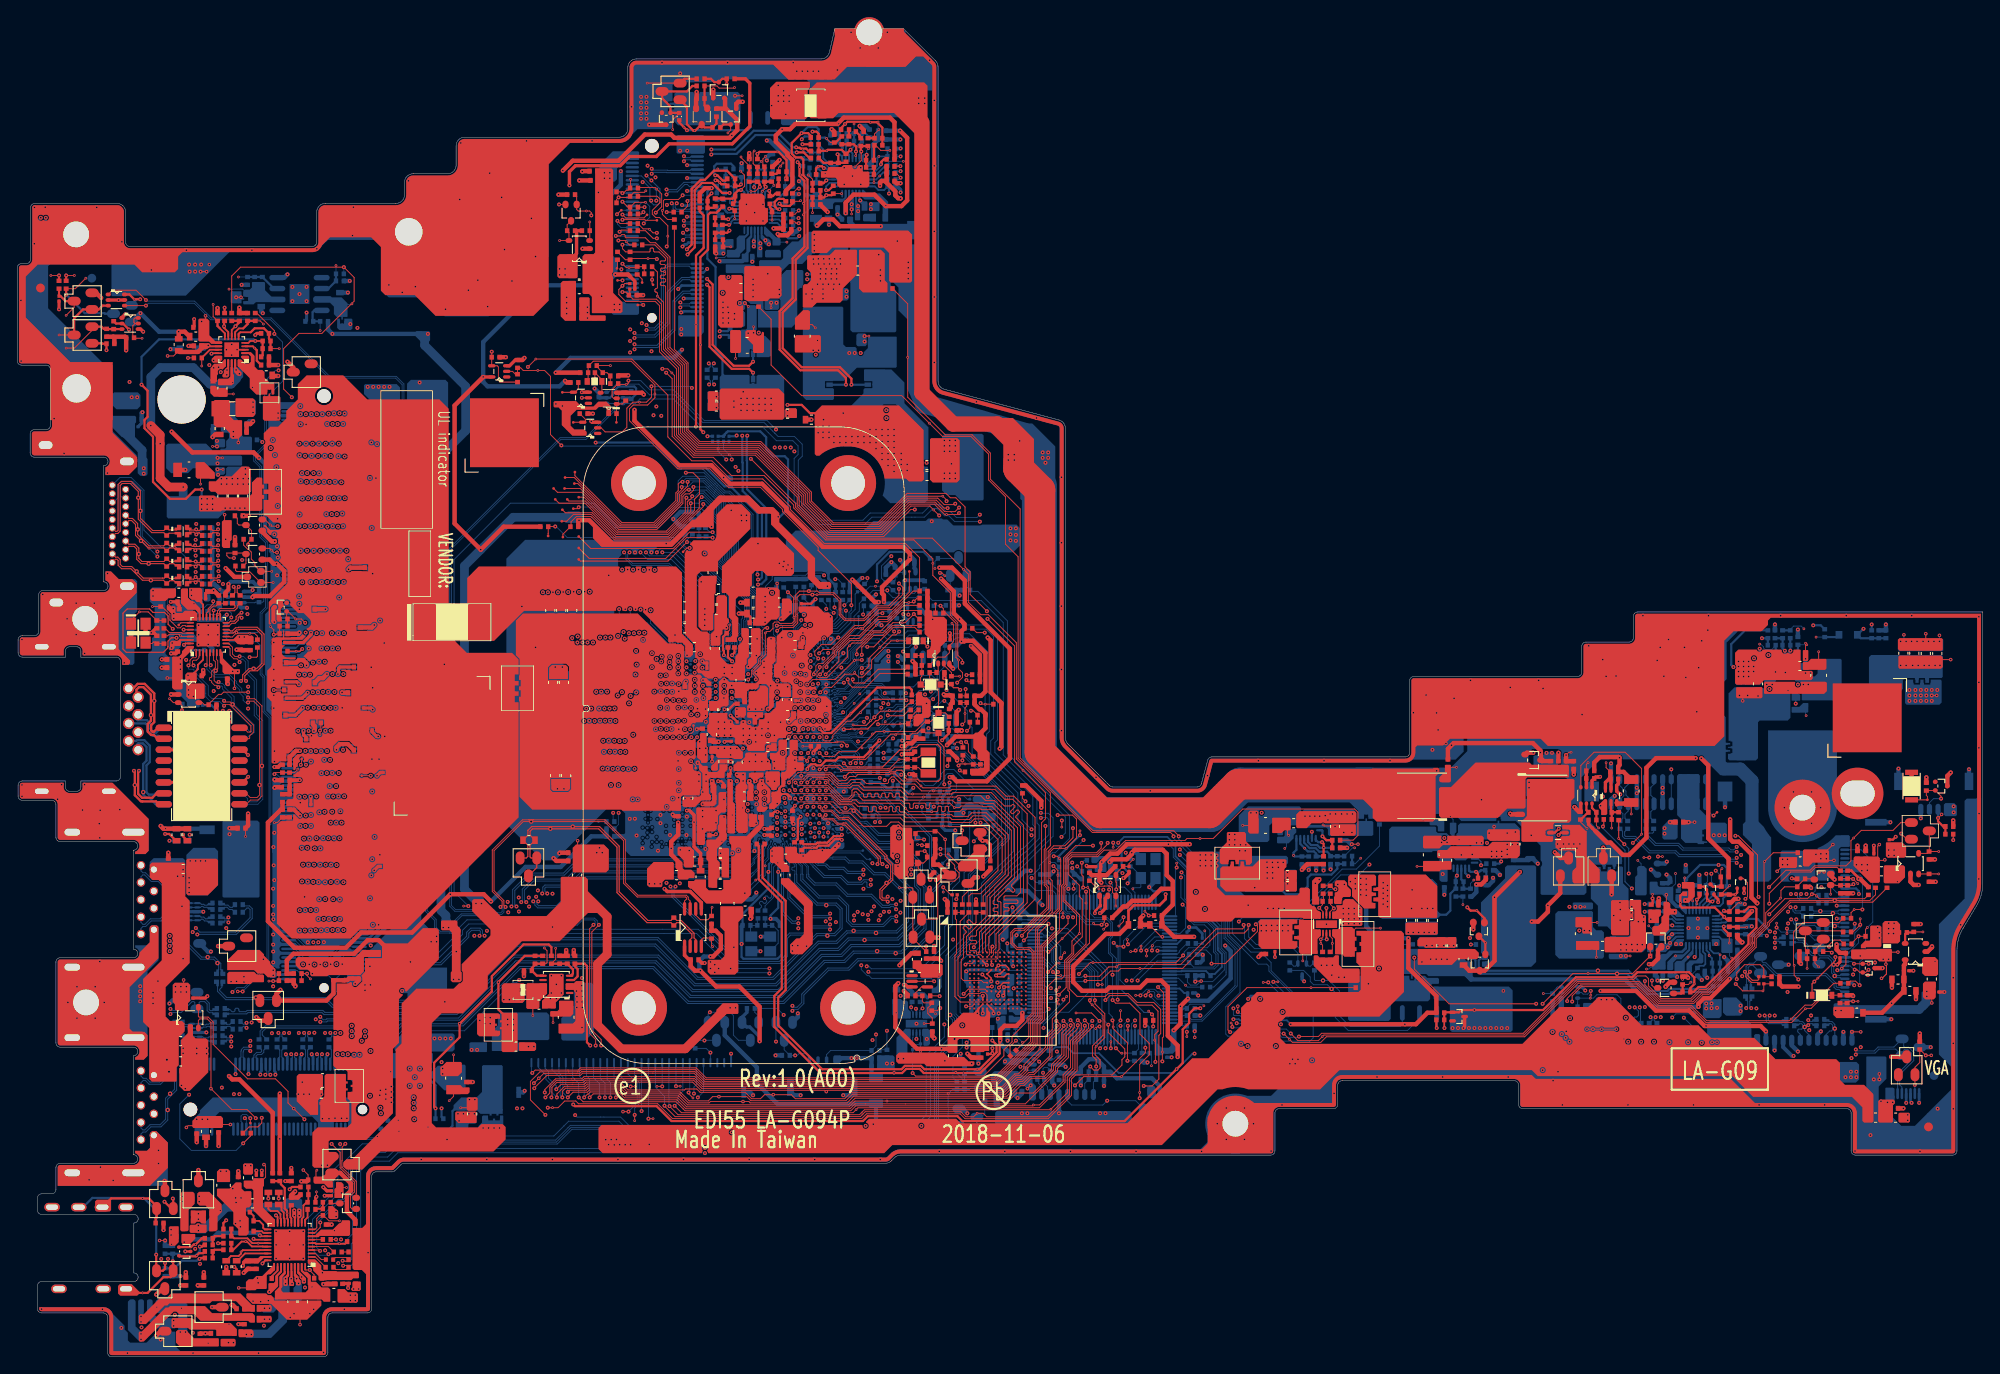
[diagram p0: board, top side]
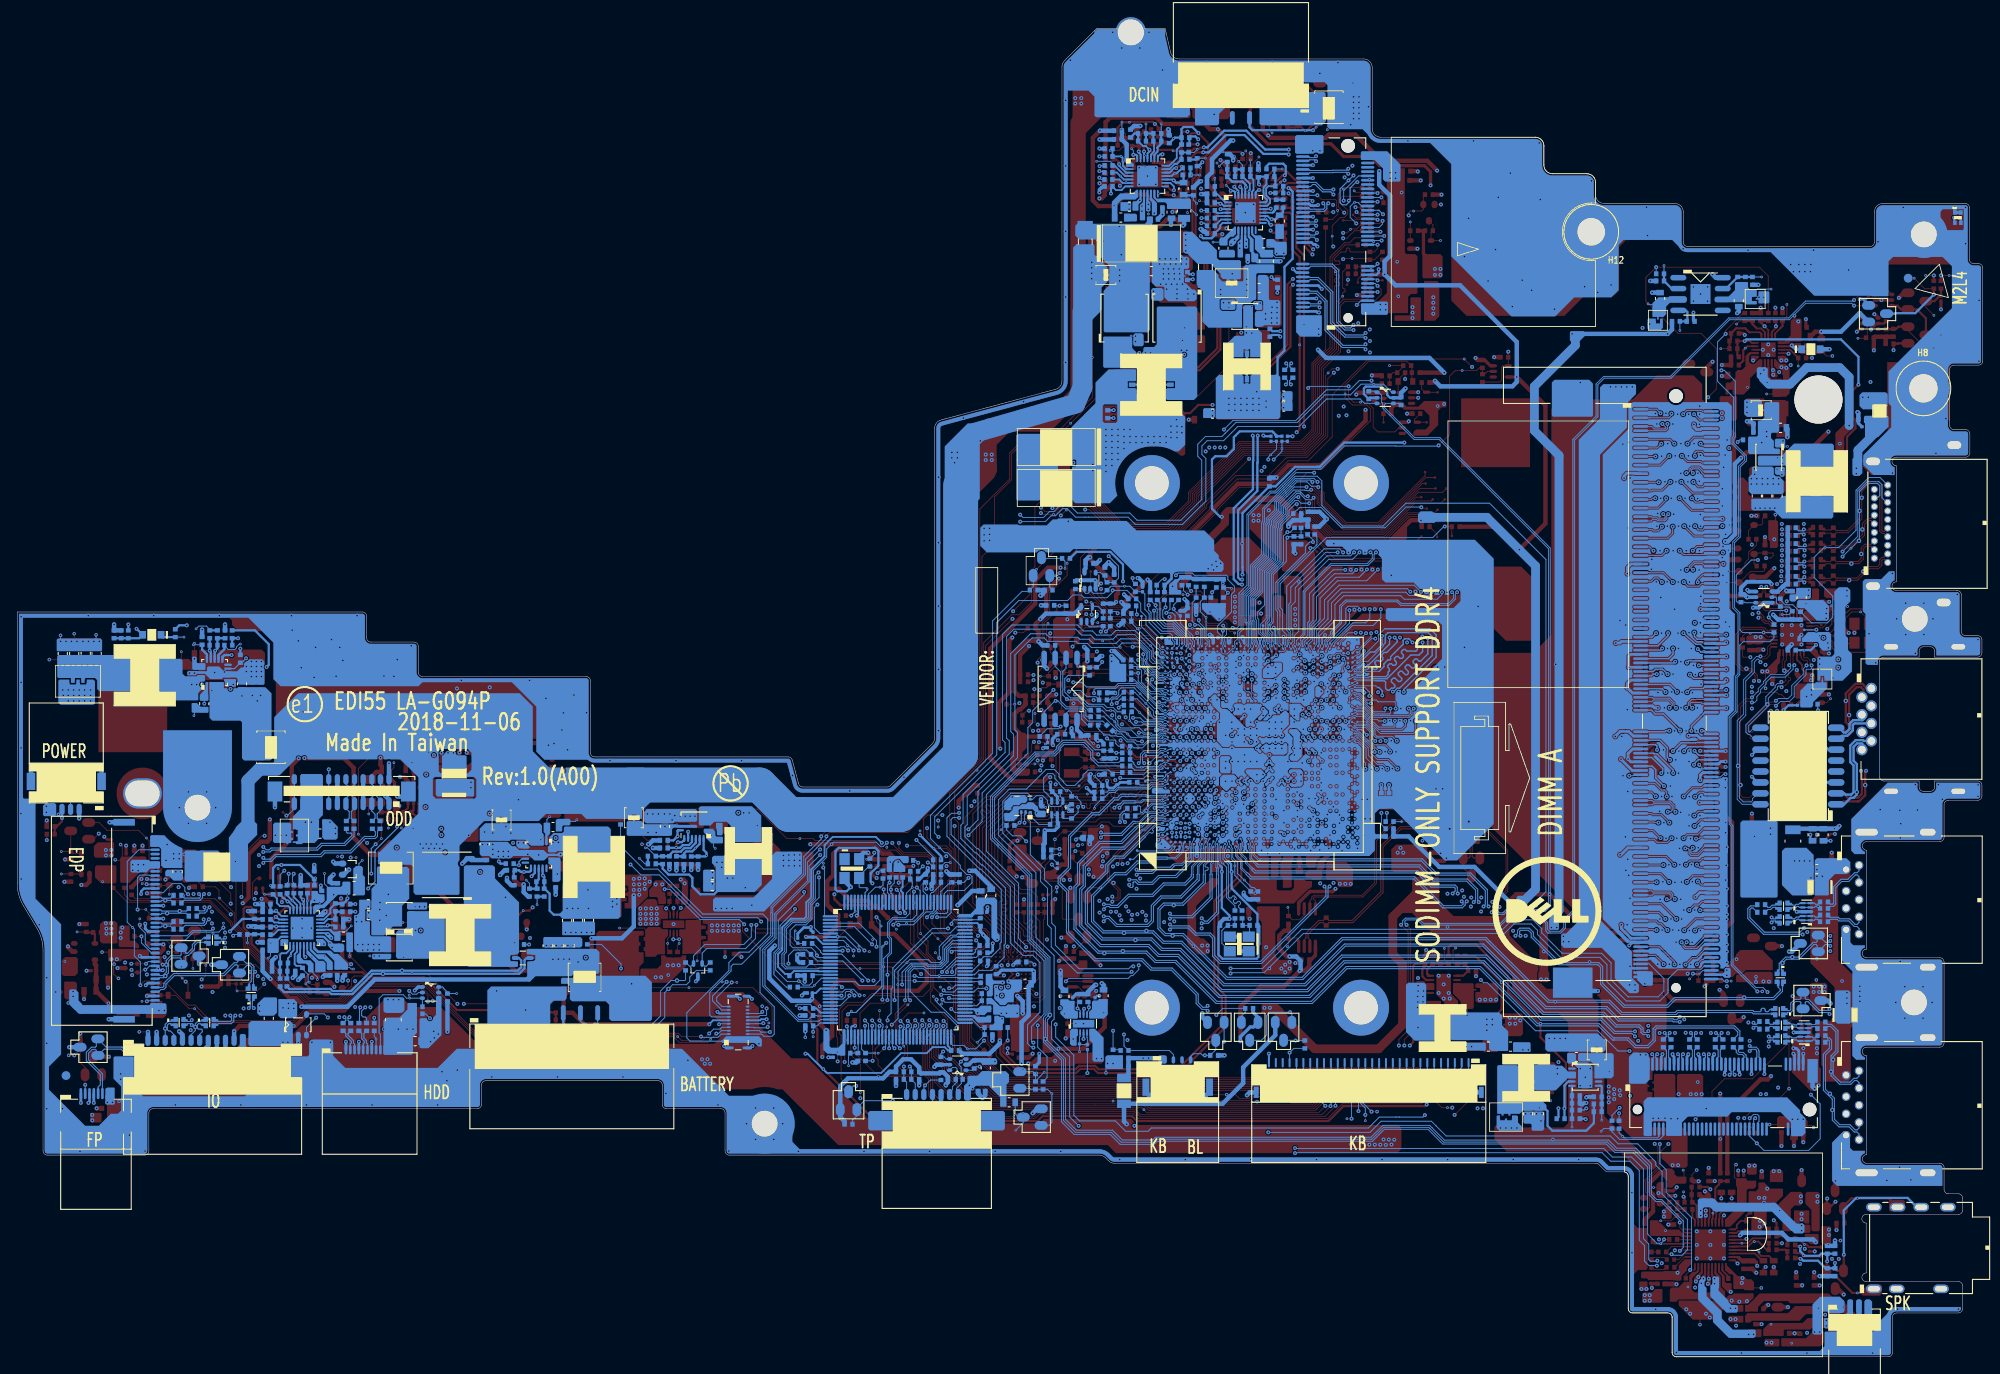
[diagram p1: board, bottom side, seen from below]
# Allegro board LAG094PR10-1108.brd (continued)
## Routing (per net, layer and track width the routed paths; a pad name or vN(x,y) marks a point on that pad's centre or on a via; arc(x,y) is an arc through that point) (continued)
GNDA: length 21.4
  TOP w0.102: RA39.1 v3(25.74,8.01) ; v2(17.18,13.52) v3(16.54,13.52)
  TOP w0.203: v2(30.07,16.44) 30.26,16.25 UA1.19
  TOP w0.457: CA52.1 v2(31.15,20.43) ; RA62.1 v2(17,14.73)
  TOP w0.508: CA53.1 v2(19.59,9.84) ; CA488.2 32.58,18.52 CA26.2 31.85,18.79 v2(32.29,19.24) ; RA38.1 v2(21.69,9.84)
  VCC w0.203: 8.95,7.25 JHP1.7 ; JHP1.7 10,7.25 ; JHP1.7 8.95,7.9 ; JHP1.7 11.06,7.9 ; JHP1.7 11.06,7.25
  GND w0.203: JHP1.7 11.06,7.9 ; JHP1.7 11.06,7.25 ; JHP1.7 8.95,7.9 ; JHP1.7 10,7.25 ; JHP1.7 8.95,7.25
  BOTTOM w0.508: CA498.2 RA54.2 v2(17.18,13.52) ; CA504.2 RA57.2 v2(18.97,9.38)
  vias: v2(16.73,11.37) v2(17.52,11.38) v2(20.68,12.55) v2(21.05,16.63) v2(21.05,16) v2(21.24,10.8) v2(25.05,19.55) v2(25.37,18.47) v2(25.37,15.49) v2(25.89,15.81) v2(25.94,15.11) v2(26.01,18.47) v2(27.92,9.15) v2(28,8.59) v3(25.43,17.94)
V3D3_STB: length 6.1
  TOP w0.203: UA1.16 31.46,15.98 31.38,16.06 31.38,16.44 31.35,16.47
  TOP w0.254: 31.35,16.47 v1(31.35,16.7) 31.35,16.98 31.09,17.24 31.09,19.62 30.64,20.06 30.64,20.3 RA37.1 RA41.1
VBAT: length 1.1
  BOTTOM w0.102: PRB35.2 198.97,46.62 v1(199.23,46.35)
VCC_RTC_EXTPAD: length 2
  TOP w0.089: v2(91.79,69.27) 91.79,69.48 v1(92.02,69.7)
  TOP w0.102: v2(91.79,69.27) 91.49,69.58 CC88.1
  BOTTOM w0.102: v2(91.79,69.27) 91.8,69.26 91.8,69.12 UC1.J23
VCC_VCGI_SENSE_N: length 86.6
  TOP w0.254: PRG42.1 92.05,139.38 91.39,140.04 v2(90.59,140.04)
  IN2 w0.254: v2(80.65,139.78) 80.6,139.84 79.77,139.84 79.03,139.09 79.03,124.83 80.4,123.46 80.4,118.76 82.39,116.77 82.39,110.12 84.81,107.71 84.81,107.12 v2(84.83,107.1)
  IN2 w0.381: v2(86.08,89.78) 86.03,89.73 83.74,89.73 83.16,89.15 83.16,85.68 83.64,85.19 83.64,84.11 83.41,83.88 83.41,82.91 84.36,81.95 84.36,77.65 83.31,76.6 v2(83.03,76.6)
  BOTTOM w0.203: UC1.AG39 v2(83.03,76.6)
  BOTTOM w0.254: v2(90.59,140.04) 89.96,140.04 87.95,142.05 85.79,142.05 83.6,139.86 80.73,139.86 v2(80.65,139.78) ; v2(86.08,89.78) 86.15,89.85 86.48,89.85 87.04,90.41 87.04,98.64 84.81,100.88 84.81,104.16 84.77,104.2 84.77,107.03 v2(84.83,107.1)
VCC_VCGI_SENSE_P: length 86.3
  TOP w0.254: v2(90.51,140.62) 90.56,140.57 90.93,140.57 91.03,140.47 91.68,140.47 91.96,140.19 PRG43.2
  IN2 w0.254: v2(84.25,107.1) 84.3,107.15 84.3,107.5 81.89,109.91 81.89,116.56 79.9,118.55 79.9,123.25 78.52,124.62 78.52,139.3 79.56,140.34 80.63,140.34 v2(80.65,140.37)
  IN2 w0.381: v2(83.03,77.31) 83.13,77.31 83.73,77.91 83.73,81.69 82.77,82.64 82.77,84.14 83.01,84.38 83.01,84.92 82.52,85.41 82.52,89.41 83.48,90.37 v2(86.08,90.37)
  BOTTOM w0.203: UC1.AG41 v2(83.03,77.31)
  BOTTOM w0.254: v2(90.51,140.62) 90.09,140.62 88.16,142.56 85.58,142.56 83.39,140.37 v2(80.65,140.37) ; v2(86.08,90.37) 86.09,90.36 86.27,90.36 86.53,90.62 86.53,98.43 84.3,100.67 84.3,103.95 84.26,103.99 84.26,107.08 v2(84.25,107.1)
VCC_VGATE: length 126.5
  IN1 w0.254: v2(105.67,103.94) 105.63,103.94 105,104.58 105,108.58 102.14,111.44 102.14,134.49 101.38,135.25 v2(101.3,135.25)
  IN2 w0.127: v2(127.94,59.76) 127.93,59.76 127.18,59.01 124.39,59.01 122.26,61.14 122.26,62.64 115.86,69.04 115.86,91.05 113.19,93.72 113.19,100.1 110.05,103.25 106.37,103.25 v2(105.67,103.94)
  BOTTOM w0.203: PUG1.7 99.65,136.08 100.08,135.65 100.73,135.65 101.13,136.05 PRG34.1 ; UE1.17 135.28,44.82 135.31,44.85 138.13,44.85 CE7.1 138.86,44.51 139.16,44.51 139.99,45.33 139.99,46.82 139.51,47.3 139.51,47.51 139.51,49.93 138.5,50.94 136.97,50.94 136.71,51.2 136.71,52.85 136.13,53.43 136.13,56.65 134.59,58.19 134.59,59.49 133.64,60.45 128.62,60.45 v2(127.94,59.76)
  BOTTOM w0.254: v2(101.3,135.25) 101.3,135.9 PRG34.1
VCCGI_EN: length 122
  TOP w0.102: v2(126.72,59.75) 126.72,59.62 125.45,58.35 122.49,58.35 121.98,57.84 121.98,54.82 121.74,54.57 121.74,53.08 123.43,51.39 v1(123.43,49.21) 122.56,48.34 122.56,46.93 121.69,46.05 121.69,44.28 121.34,43.94 120.62,43.94 119.59,42.91 119.59,40.71 v2(119.86,40.44)
  IN2 w0.127: v2(126.72,59.75) 126.3,59.33 125.74,59.33 124.88,60.19 124.88,61.1 116.81,69.17 116.81,91.56 114.21,94.17 114.21,100.43 110.69,103.94 110.6,103.94 110.54,104.01 106.99,104.01 103.6,107.39 103.6,108.8 103.08,109.32 103.08,122.1 102.48,122.7 102.48,128.45 103.16,129.12 103.16,139.06 v2(102.65,139.57)
  BOTTOM w0.102: v2(102.65,139.57) PRG41.2 ; v2(119.86,40.44) 119.43,40.02 UE1.68
VCCGI_N01: length 2.3
  TOP w0.102: v1(94.04,141.66) 94.52,141.18 PRG36.1
  TOP w0.254: PRG36.1 95.11,141.18 PRG15.2
VCCGI_N02: length 1.8
  TOP w0.102: v1(99.55,136.53) PRG37.1
  TOP w0.254: PRG37.1 PRG13.2
VCCGI_N03: length 1
  TOP w0.254: PRG38.1 97.87,142.03 97.87,141.84 PRG14.2
VCCGI_N04: length 1.9
  BOTTOM w0.102: PRG28.2 v1(91.03,137.41)
  BOTTOM w0.254: PRG39.1 PRG28.2
VCCGI_N05: length 42.6
  TOP w0.254: v2(92.41,142.45) 92.87,142.45 93.13,142.2 PRG40.1
  IN1 w0.254: v2(92.41,142.45) 92.82,142.04 98.54,142.04 99.65,140.93 99.65,135.87 101.25,134.27 101.25,110.66 101.47,110.44 101.47,109.85 101,109.38 v2(101,109.14)
  BOTTOM w0.254: PHG1.2 v2(101,109.14)
VCCGI_N06: length 1.8
  TOP w0.102: v1(92.41,133.03) PRG35.1
  TOP w0.254: PRG35.1 PRG30.2
VCCGI_N07: length 4
  BOTTOM w0.203: PCG10.2 PRG41.1 v1(100.12,139.57) 99.96,139.4 99.96,138.93 99.91,138.88 99.91,138.47 99.52,138.08 PUG1.2
VCCGI_N08: length 3.8
  TOP w0.102: v1(101.41,140.27) 100.34,140.27 99.74,140.86 PRG01.2
  TOP w0.254: PRG06.1 99.55,140.8 PRG01.2
VCCGI_N09: length 0.8
  TOP w0.254: PRG08.1 96.64,142.67 PRG03.2
VCCGI_N12: length 42.6
  IN1 w0.254: v2(100.99,110.06) 101,110.06 100.87,110.19 100.87,134.11 99.27,135.71 99.27,140.77 98.48,141.56 v2(91.17,141.56)
  BOTTOM w0.254: v2(91.17,141.56) 91.5,141.89 92.06,141.89 PRG23.1 92.2,141.02 PRG22.2 ; PHG1.1 101,110.05 101,110.06 101,110.06 v2(100.99,110.06)
VCCGI_N13: length 2
  TOP w0.102: v1(100.12,142.68) 99.61,142.17 PRG02.2
  TOP w0.254: PRG07.1 PRG02.2
VCCGI_N14: length 14.6
  TOP w0.102: v1(95.79,135.24) PRG27.2
  TOP w0.254: PRG27.2 94.65,135.06 v2(94.01,135.06) 93.75,134.79 PRG30.1 PRG26.2
  IN1 w0.254: v2(91.79,125.87) 91.5,126.16 91.5,128.37 91.93,128.8 91.93,131.63 93.51,133.2 93.51,134.62 93.94,135.06 v2(94.01,135.06)
  BOTTOM w0.254: PHZ2.2 92.17,125.87 v2(91.79,125.87)
VCCGI_N16: length 2
  TOP w0.102: PRG24.2 92.41,136.91 v1(91.92,137.41)
  TOP w0.254: PRG24.2 PRG26.1
VCCGI_N17: length 35.9
  TOP w0.254: v2(96.3,113.03) 96.3,113.79 95.39,114.7 91,114.7 88.59,117.11 88.59,121.57 88.8,121.78 90.1,123.08 90.1,127.69 91.47,129.07 91.47,136.73 90.9,137.3 v1(90.9,138.3) 90.9,138.68 v2(90.69,138.9)
  BOTTOM w0.254: v2(96.3,113.03) PLG1.2 ; PRG21.1 91.14,138.44 v2(90.69,138.9)
VCCGI_N18: length 2
  BOTTOM w0.102: v1(91.35,132.77) 92.64,134.07 PRG31.2
VCCGI_N19: length 2.3
  BOTTOM w0.102: v1(91.35,134.11) 91.73,134.49 PCG07.2
  BOTTOM w0.254: PRG29.1 92.79,135.05 PCG07.2
VDD_1.2V: length 6
  TOP w0.102: 21.88,120.65 v3(21.88,121.03) ; v2(19.85,116.14) PRM03.2
  IN2 w0.508: v2(21.43,120.38) 21.43,117.72 v2(19.85,116.14)
VDD_CHG: length 23.1
  TOP w0.102: PRB27.1 v1(193.76,55.68)
  IN1 w0.127: v2(191.22,43.72) 191.22,44.12 192.88,45.78 198.92,45.78 199.12,45.98 199.12,52.37 197.84,53.65 194.45,53.65 v2(193.86,53.07)
  BOTTOM w0.508: PRB39.2 v2(191.22,43.72)
VDDP_1.2V: length 6
  TOP w0.102: v3(17.47,116.37) 18.17,116.37 PRM05.1
  TOP w0.508: PRM05.1 18.89,116.84 21,116.84 21.45,117.28 PCM13.1
  BOTTOM w0.356: PD502.1 21.75,117.15 v2(22.2,117.6)
VDDP_CHG: length 1.1
  BOTTOM w0.102: v1(189.33,45.08) 189.58,45.08 189.78,45.28 PCB19.1
VDDREG:
  vias: v1(20.54,87.56)
+DCBAT_LCD: length 1.7
  TOP w0.102: v3(210.98,59.56) 210.35,58.92 210.35,58.86 ; 210.41,57.72 v3(211.11,57.72)
  vias: v2(209.58,58.48) v2(209.58,57.91) v2(210.22,58.48) v2(210.22,57.91) v3(209.01,58.42)
+EMMC_VDDI: length 2.3
  TOP w0.089: UM1.C2 110.95,45.75 110.52,45.75
  TOP w0.102: v2(110.19,45.6) 110.34,45.75 110.52,45.75
  BOTTOM w0.102: v2(110.19,45.6) 110.5,45.91 CM5.1
+FP_VCC:
  vias: v2(217.33,29.59) v2(217.94,29.59) v3(216.57,29.71)
+LAN_VDD33: length 7.1
  TOP w0.102: 18.13,78.93 v3(17.43,78.93)
  IN2 w1.016: 19.27,81.89 19.99,81.89 20.09,81.78 23.59,81.78 25.05,83.24
  vias: v2(15.78,89.09) v2(15.78,88.45) v2(18.96,81.15) v2(18.96,80.54) v2(18.96,79.94) v2(25.82,83.69) v2(26.39,83.69)
+LCDVDD:
  vias: v1(218.47,55.24)
+LCDVDD_LCD: length 2.3
  TOP w0.102: v3(216.38,59.56) 216.19,59.37 216.19,57.97 ; v3(217.01,57.78) 216.95,57.72 216.38,57.72
  vias: v2(213.71,57.21) v2(214.35,57.21) v2(214.98,57.21) v2(214.98,56.57) v3(214.35,56.51)
+LINE1_VREFO_L: length 11.2
  TOP w0.203: v2(27.47,13.71) 27.56,13.61 UA1.24
  TOP w0.254: DA10.1 v2(19.53,12.25)
  IN1 w0.254: v2(19.53,12.25) 19.91,11.87 23.34,11.87 25.18,13.71 v2(27.47,13.71)
+MIC2-VREFO: length 10.3
  TOP w0.203: UA1.23 28.32,14.01 v2(28.2,14.13)
  BOTTOM w0.508: v2(19.4,13.33) 19.72,13.65 22.58,13.65 23.34,14.41 27.92,14.41 v2(28.2,14.13)
+MIC_VCC: length 4.8
  TOP w0.102: v3(212.01,45.14) 212.49,45.62 R83.2
  TOP w0.508: R83.2 212.45,46.96 C39.1 211.41,47.35 v2(211.41,47.95)
  BOTTOM w0.254: JEDP1.26 v2(211.41,47.95)
+RTC_CELL: length 133.4
  TOP w0.508: v2(30.51,30.6) v3(30.51,25.33) RA37.2 ; RC66.1 106.66,60.17 RC73.1 106.66,59.01 106.67,59 106.67,58.49 106.66,58.48 106.66,58.38 106.65,58.36 RC65.1 106.46,57.92 106.46,57.27 CC10.1 107.08,57.22 107.92,56.38 108.02,56.38 DC1.1 108.21,55.81 107.17,55.81 v2(106.79,55.43)
  IN1 w0.508: v2(30.51,30.6) 31.47,31.55 39.7,31.55 42.26,34.11 42.26,39.14 48.84,45.72 52.68,45.72 56.43,49.47 79.71,49.47 79.85,49.33 79.85,49.33 85.6,43.59 85.8,43.59 93.54,43.59 94.08,44.13 102.78,44.13 104.11,45.46 104.11,47.75 106.67,50.31 106.67,55.31 v2(106.79,55.43) 106.79,56.25 106.28,56.75 104.85,56.75 102.44,59.16 99.87,59.16 94.78,64.26 94.78,65.78
  BOTTOM w0.254: UC1.P15 v2(89.06,65.87)
+RTC_VCC: length 105.4
  TOP w0.508: v2(112.27,55.85) 113.08,56.66 RC63.2 ; v2(183.99,42.54) 188.12,42.54 190.41,40.25 194.28,40.25 196.07,38.46 v3(196.25,38.46) 202.58,38.46 v2(203.2,37.84)
  IN1 w0.508: v2(112.27,55.85) 112.24,55.82 112.24,52.07 113.13,51.18 115.67,51.18 116.98,51.18 119.46,48.69 121.65,48.69 124.35,45.99 125.45,45.99 126.24,45.21 131.23,45.21 131.92,45.91 137.7,45.91 139.94,43.66 142.51,43.66 142.96,43.21 144.11,43.21 145.32,42.01 173.3,42.01 174.47,43.18 180.12,43.18 181.8,41.49 182.95,41.49 v2(183.99,42.54)
  BOTTOM w0.508: JIOB1.11 v2(203.2,37.84)
+TP_VDD: length 24.4
  TOP w0.102: v2(117.76,31.55) v3(117.38,31.17)
  IN1 w0.508: v2(120.49,31.55) v2(117.76,31.55)
  BOTTOM w0.508: v2(120.49,31.55) 120.49,31.68 120.25,31.92 R46.1 120.25,32.55 120.79,33.09 R41.1 121.2,32.95 123.4,32.95 R31.1 123.59,33.65 124.54,34.6 125.45,34.6 126.28,33.76 R32.1 127.03,33.14 127.8,32.38 131.86,32.38 132.76,31.48 Q9.2 132.76,27.88 132.25,27.38 R39.1
+TPAN_VDD: length 9.7
  TOP w0.102: 222.47,41.59 v3(222.47,41.14)
  BOTTOM w1.016: 212.63,40.51 212.76,40.38 221.01,40.38 221.59,40.95
  vias: v2(211.3,40.25) v2(211.93,40.25) v2(221.9,42.48) v2(221.9,41.91)
+TPAN_VDD_OUT:
  vias: v1(222.86,45.97)
+TS_VDD_IN: length 9.5
  TOP w0.508: R13.1 216.7,40 v3(217.81,41.11) R5222.2 R5221.2 C983.2 219.24,45.51 219.38,45.65 U14.5
+V_DDR_REFA: length 5.6
  TOP w0.457: RD12.1 CD28.1 v2(32.83,67.05)
  TOP w0.508: RD12.1 31.65,66.21 RD10.2 RD9.2
  BOTTOM w0.305: JDIMM1.164 32.52,67.93 32.83,67.62 v2(32.83,67.05)
+V_DDR_REFA_R: length 62.2
  TOP w0.508: v2(55.05,52.94) 54.21,53.78 v3(50.33,53.78) 45.88,49.33 39.98,49.33 38.2,47.56 32.22,47.56 29.13,50.64 29.13,62.12 30.65,63.63 CD30.1 RD9.1
  BOTTOM w0.508: RC157.2 CC95.1 66.71,60.51 63.15,56.95 59.06,56.95 v2(55.05,52.94)
+VNN: length 27.5
  TOP w0.508: v2(80.68,135.88) 79.93,135.88 79.31,135.26 PRZ12.2
  BOTTOM w0.254: 81.95,111.82 81.95,116.2 81.15,117 81.15,126.72 80.2,127.67 80.2,135.47 80.61,135.88 v2(80.68,135.88)
  vias: v2(81.45,70.74) v2(82.16,80.15) v2(82.16,79.44) v2(82.19,70.75) v2(82.89,70.73) v2(82.9,69.98) v2(82.97,98.42) v2(83.07,80.15) v2(83.07,79.44) v2(83.28,111.12) v2(83.28,110.42) v2(83.47,103.46) v2(83.63,75.3) v2(83.63,74.55) v2(83.62,70.74) v2(83.8,103.01) v2(84.11,111.44) v2(84.11,110.74) v2(84.11,110.04) v2(84.13,97.85) v2(84.17,97.21) v2(84.74,97.85) v2(84.74,97.21) v2(84.81,111.44) v2(84.81,110.74) v2(84.81,110.04) v2(85.51,111.44) v2(85.51,110.74) v2(85.51,110.04) v2(86.2,111.44) v2(86.2,110.74) v2(86.2,110.04) v2(86.9,111.44) v2(86.9,110.74) v2(86.9,110.04) v2(87.6,111.44) v2(87.6,110.74) v2(87.6,110.04) v3(84.36,112.2)
AC_OFF#: length 66.4
  TOP w0.102: v2(177.25,41.04) 180.78,44.57 v1(182.53,44.57) 187.73,44.57 PRB45.1 189.76,46.6 PQB31.2
  IN1 w0.127: v2(177.25,41.04) 176.34,40.13 163.09,40.13 162.31,39.34 143.18,39.34 141.37,41.16 138.9,41.16 137.53,42.52 132.22,42.52 v2(131.7,42)
  BOTTOM w0.102: v2(131.7,42) 131.7,41.87 132.76,40.82 UE1.27
ACIN_CHG: length 1.2
  TOP w0.102: PRB09.2 v3(191.63,53.72)
  vias: v2(192.59,51.75)
ACLIN: length 3.4
  TOP w0.102: v2(195.18,53.14) v1(195.18,52.66)
  TOP w0.254: v2(195.18,53.14) 195.49,53.45 PRB18.1
  BOTTOM w0.203: PRB16.1 195.46,53.42 v2(195.18,53.14) 195.18,53.02 195.1,52.93 PUB01.20
ACOK_CHG: length 4.3
  BOTTOM w0.102: v1(199.68,53.78) PRB22.1
  BOTTOM w0.203: PRB22.1 198.66,53.74 198.22,53.3 198.22,52.76 197.87,52.41 196.9,52.41 196.7,52.21 PUB01.24
AD_BID: length 4.7
  BOTTOM w0.102: v1(116.81,36.57) 116.81,36.57 116,37.39 RE15.2 RE14.1 116.49,38.29 117.42,39.22 UE1.66
ADJ_2.5V: length 5.1
  BOTTOM w0.102: PR2503.1 v1(25.7,125.55)
  BOTTOM w0.254: PR2503.1 PR2502.2 PC2505.2 29.83,124.2 PU2501.7
ADP_I: length 99.7
  TOP w0.102: v1(121.95,41.91) 121.57,41.53 v2(121.57,41.53)
  IN1 w0.127: v2(203.31,48.95) 203.31,43.63 201.56,41.88 199.78,41.88 195.57,37.67 181.01,37.67 179.38,39.3 163.55,39.3 161.01,36.76 147.13,36.76 146.56,37.33 138.74,37.33 135.06,41.02 128.85,41.02 128.22,40.38 122.72,40.38 v2(121.57,41.53)
  BOTTOM w0.102: PRB32.2 203.16,49.11 v2(203.31,48.95) ; v2(121.57,41.53) 121.57,41.27 119.12,38.82 UE1.65
AISP1: length 5.2
  BOTTOM w0.102: PRG22.1 91.65,140.03 v1(91.28,140.39)
  BOTTOM w0.203: PRG22.1 PCG14.1 93.11,140.01 PRG45.2 93.63,138.69 93.9,138.69 94.51,138.08 PUG1.20
AISP2: length 7
  BOTTOM w0.102: PRZ26.1 v1(81.4,138.11)
  BOTTOM w0.203: PUZ1.20 83.16,133.83 82.81,134.17 82.81,134.6 83.27,135.06 83.27,135.85 83.02,136.1 PRZ44.2
  BOTTOM w0.254: PRZ44.2 82.2,137.1 PCZ11.1 PRZ26.1
ALERT#: length 4
  TOP w0.102: v1(80.74,52.26) 80.68,52.19 R28.2 80.25,50.82 79.38,50.82 78.84,51.36 U2.6
ALERT#_VCCGI: length 2.4
  BOTTOM w0.203: PRG11.1 100.63,137.7 v1(100.22,137.3) 99.81,136.88 PUG1.5
ALERT#_VNN: length 1.6
  BOTTOM w0.203: PRZ13.1 89,132.63 PUZ1.5
ALW_PWRGD_3V_5V_R: length 2.8
  TOP w0.102: UC3.2 107.67,80.43 108.56,79.55 RC53.2 v1(109.51,79.13)
AMBER_LED_BAT: length 9.9
  TOP w0.102: v1(7.97,125.41) 6.75,124.19 R68.2
  TOP w0.254: R68.2 v2(5.69,123.5)
  BOTTOM w0.254: Q5029.1 10.19,121.28 10.13,121.34 7.84,121.34 v2(5.69,123.5)
ASGATE:
  vias: v1(192.69,46.6)
AUD_HP1_JACK_L: length 5.4
  TOP w0.203: UA1.25 v1(28,13.21) 27.32,13.21 26.76,13.77 25.21,13.77 24.95,14.03 RA58.1
  TOP w0.254: RA58.1 RA59.2
AUD_HP1_JACK_L1: length 2.1
  TOP w0.254: RA58.2 22.97,14.03 RA52.2 LA2.1
AUD_HP1_JACK_R: length 5.6
  TOP w0.203: UA1.26 28.56,12.81 28.54,12.83 27.27,12.83 26.71,13.39 v1(26.55,13.39) 26.07,13.39 25.12,12.44 RA61.1
  TOP w0.254: RA55.2 RA61.1
AUD_HP1_JACK_R1: length 2.1
  TOP w0.254: LA3.1 RA53.2 22.91,12.44 RA61.2
AUD_PC_BEEP: length 1.7
  TOP w0.203: CA478.2 33.74,16.21 33.46,15.93 UA1.11
AUD_PC_BEEP_C: length 1.1
  TOP w0.102: DA7.1 36.56,17.84 RA31.1
AUD_SENSE_A: length 4.6
  TOP w0.203: RA51.2 CA488.1 33.83,18.05 RA40.1 33.63,17.97 33.26,17.6 33.26,16.24 33.06,16.04 UA1.12
AUD_SPK_L+:
  vias: v2(28.74,5.65) v2(29.32,5.65) v2(31.17,9.08) v2(31.17,8.49)
AUD_SPK_L+_C:
  vias: v1(16.23,5.77) v2(14.39,4.69) v2(14.39,4.06)
AUD_SPK_L-:
  vias: v2(28.74,4.38) v2(29.32,4.38) v2(31.83,9.08) v2(31.94,8.49)
AUD_SPK_L-_C:
  vias: v1(19.08,5.65) v2(14.39,2.66) v2(14.39,2.03)
AUD_SPK_R+:
  vias: v2(24.55,1.65) v2(25.13,1.65) v2(33.05,9.28) v2(33.33,8.77)
AUD_SPK_R+_C:
  vias: v1(22.2,1.58) v2(18.94,2.88) v2(19.55,2.88)
AUD_SPK_R-:
  vias: v2(26.63,2.6) v2(27.21,2.6) v2(32.47,9.08) v2(32.7,8.54)
AUD_SPK_R-_C:
  vias: v1(24.61,3.79) v2(18.18,4.22) v2(18.18,3.59)
AUD_VREF: length 1.7
  TOP w0.203: CA489.1 28.42,14.6 28.61,14.41 UA1.22
AVCORE1: length 50.6
  TOP w0.254: v2(96.94,113.03) 96.94,113.72 95.6,115.06 91.15,115.06 88.95,117.26 88.95,121.42 90.46,122.93 90.46,127.55 91.83,128.92 91.83,136.88 91.35,137.36 91.35,139.2 91.09,139.45 90.45,139.45 90,139.9 90,141.13 v2(91.14,142.27) 91.91,142.27 92.21,141.97 PRG40.2
  BOTTOM w0.203: PCG14.2 93.66,140.38 93.66,139.36 94.54,138.48 PUG1.21
  BOTTOM w0.254: v2(96.94,113.03) PLG1.3 ; PRG23.2 93.87,141.75 PCG03.1 ; PRG23.2 93.11,142.74 92.87,142.98 91.86,142.98 v2(91.14,142.27) ; PRG23.2 93.1,141.74 PCG14.2
AVCORE2: length 40.4
  TOP w0.254: v2(80.16,124.65) 80.45,124.35 80.45,117.45 83.03,114.87 85.06,114.87 v2(85.51,114.42) ; v2(77.81,128.77) 78.37,129.32 78.37,135.79 79.42,136.84 79.89,136.84 80.96,137.9 82.48,137.9 PRZ27.2 PRZ39.2 83.92,136.14 v2(84.1,136.32)
  IN1 w0.254: v2(77.81,128.77) 77.41,128.37 77.41,127.85 79.6,125.67 79.6,125.2 v2(80.16,124.65)
  BOTTOM w0.203: PCZ11.2 83.23,136.32 83.57,135.97 83.57,134.93 83.2,134.55 83.2,134.37 83.34,134.23 PUZ1.21
  BOTTOM w0.254: v2(84.1,136.32) 84.17,136.39 PCZ16.1 84.1,137.22 PCZ11.2 ; PLZ1.3 v2(85.51,114.42)
AVCORE2_NTC: length 26.8
  TOP w0.254: v2(81.11,137.37) 81.36,137.37 81.97,136.76 82.3,136.76 PRZ27.1
  IN1 w0.254: v2(81.11,137.37) 81.04,137.37 80.2,136.53 80.2,127.27 80.73,126.74 80.73,119.39 81.5,118.61 v2(81.63,118.61)
  BOTTOM w0.254: PHZ1.1 82.63,118.8 81.82,118.8 v2(81.63,118.61) ; v2(81.11,137.37) 81,137.49 81,138.43 81.29,138.72 82.94,138.72 83.23,138.43 PRZ26.2
BA: length 33.5
  TOP w0.508: PRB41.2 168.73,44.89 PQB28.1 170.52,44.89 171.66,46.03 v3(171.66,53.42) v2(174.61,56.37)
  IN1 w0.508: v2(189.84,56.64) 189.48,56.64 187.97,58.15 183.04,58.15 181.49,56.6 177.83,56.6 177.61,56.37 v2(174.61,56.37)
  BOTTOM w0.508: v2(189.84,56.64) 189.9,56.64 190.49,56.05 PDB01.3
BATGONE: length 5.2
  TOP w0.102: PRB24.1 199.97,52.78 v1(200.26,52.78)
  TOP w0.254: v2(198.32,51.86) 198.41,51.77 PRB24.1
  BOTTOM w0.203: PCB09.1 198.43,51.75 v2(198.32,51.86) 197.7,51.24 PUB01.25
  BOTTOM w0.254: PCB09.1 PRB23.1
BATT_CHG_LED#: length 229
  TOP w0.102: v2(133.07,34.35) v1(133.07,35.43) 133.07,37.08 133.19,37.21 133.19,42.35 v2(132.56,42.98) ; Q17.4 v2(14.96,122.22) ; v2(67.22,36.19) 67.22,36.89 66.52,37.59 66.52,49.78 v2(66.96,50.22)
  IN1 w0.127: v2(67.22,36.19) 67.22,30.89 66.96,30.64 66.96,29.27 68.82,27.41 71.7,27.41 72.71,26.4 80.04,26.4 81.16,26.4 82.07,27.31 82.28,27.31 82.28,27.31 96.67,27.31 97.71,28.35 108.33,28.35 108.75,28.35 110.48,26.63 127.65,26.63 129.64,28.61 129.64,32.8 129.7,32.87 129.7,32.89 130.21,33.4 130.23,33.4 132.18,33.4 133.07,34.29 v2(133.07,34.35)
  BOTTOM w0.102: v2(14.96,122.22) 15.23,122.49 20.57,122.49 22.48,120.58 29.43,120.58 36.22,113.79 43.97,113.79 44.73,113.02 44.73,109.28 47.43,106.58 47.43,51.81 48.48,50.75 48.48,49.84 49.06,49.27 50.27,49.27 50.54,49.27 50.77,49.5 50.77,50.38 51.68,51.29 54.88,51.29 55.98,50.19 65.09,50.19 65.69,50.8 67.01,50.8 67.15,50.65 67.15,50.41 v2(66.96,50.22) ; v2(132.56,42.98) 132.79,43.22 UE1.21
BATT_I: length 101.4
  TOP w0.102: v2(120.75,42.6) v1(121.13,42.98)
  IN1 w0.127: v2(120.75,42.6) 121.28,42.6 123.18,40.7 123.22,40.7 123.29,40.64 128.11,40.64 128.69,41.21 128.69,41.21 128.75,41.27 135.16,41.27 135.48,40.95 137.7,40.95 138.97,39.68 142.02,39.68 142.62,39.09 162.41,39.09 163.2,39.87 185.52,39.87 186.85,38.54 196.08,38.54 199.67,42.13 201.45,42.13 202.79,43.47 202.79,49.33 202.92,49.46 v2(203.68,49.46)
  BOTTOM w0.102: UE1.75 119.14,42.82 119.54,42.41 120.56,42.41 v2(120.75,42.6)
  BOTTOM w0.254: v2(203.68,49.46) 202.23,50.91 PCB10.1 199.93,50.91 PRB29.1
BATT_LOW_LED#: length 247.4
  TOP w0.102: v2(67.6,50.22) 66.77,49.4 66.77,37.97 67.85,36.89 v2(67.85,36.19) ; v2(14.96,122.87) 13.81,124.01 11.07,124.01 Q17.1 ; v2(132.25,34.29) 132.25,36.75 v1(132.18,36.83) 132.18,37.46 132.56,37.84 132.56,40.19 131.86,40.89 130.16,40.89 129.06,41.99 126.97,41.99 v2(126.45,41.47)
  IN1 w0.127: v2(132.25,34.29) 131.68,33.71 130.17,33.71 129.38,32.93 129.38,28.72 127.55,26.88 110.59,26.88 108.86,28.61 108.23,28.61 97.61,28.61 96.67,27.67 81.8,27.67 80.78,26.65 80.15,26.65 72.82,26.65 71.8,27.67 71.59,27.67 71.59,27.67 68.94,27.67 67.22,29.4 67.22,30.54 67.53,30.85 67.53,30.86 67.85,31.17 v2(67.85,36.19)
  BOTTOM w0.102: v2(14.96,122.87) 15.08,122.74 20.61,122.74 22.57,120.78 29.51,120.78 36.31,113.99 44.05,113.99 44.93,113.11 44.93,109.36 47.63,106.66 47.63,51.89 48.69,50.84 48.69,49.93 49.14,49.47 50.35,49.47 50.57,49.69 50.57,50.47 51.59,51.49 54.8,51.49 54.96,51.49 56.06,50.39 65,50.39 65.61,51 67.1,51 67.4,50.69 67.4,50.42 v2(67.6,50.22) ; v2(126.45,41.47) 126.45,44.9 122.08,49.27 119.99,49.27 119.24,50.02 UE1.93
BATT_WHITE_LED_R#: length 8.3
  TOP w0.102: v1(4.86,118.8) Q22.1
  TOP w0.254: Q17.3 9.93,122.22 9.48,121.78 Q19.2 7.64,121.78 6.61,120.75 Q22.1
BEEP#: length 132.9
  TOP w0.102: v2(130.52,42.02) v1(129.97,42.02) ; DA7.3 39.39,19 39.4,19.01 39.4,20.38 37.73,22.06 37.73,22.78 37.75,22.8 37.75,24.39 v2(38.12,24.76)
  IN1 w0.127: v2(130.52,42.02) 130.38,42.16 122.8,42.16 121.09,43.87 119.41,43.87 118.72,43.18 118.72,39.75 116.43,37.46 109.13,37.46 107.03,35.36 97.99,35.36 97.57,35.78 88.2,35.78 87.66,36.32 87.66,40.13 79.27,48.52 57.26,48.52 53.5,44.76 49.29,44.76 43.21,38.68 43.21,33.52 39.09,29.4 39.09,27 38.12,26.03 v2(38.12,24.76)
  BOTTOM w0.102: v2(130.52,42.02) 131.23,42.73 132.18,42.73 132.49,42.42 UE1.23
BGATE: length 36.4
  TOP w0.102: v2(189.65,58.05) v1(189.02,58.05)
  IN1 w0.508: v2(176.69,57.34) 176.75,57.34 176.91,57.49 177.54,57.49 177.91,57.49 178.28,57.49 180.93,57.49 183.8,60.36 188.31,60.36 189.69,58.98 189.69,58.09 v2(189.65,58.05)
  IN2 w0.508: v2(197.42,47.99) 197.42,49.1 197.7,49.38 197.7,51.05 197.6,51.15 196.56,52.18 196.55,52.18 196.1,52.64 196.1,54.06 194.78,55.38 194.78,57.34 193.15,58.96 190.56,58.96 v2(189.65,58.05)
  BOTTOM w0.508: v2(176.69,57.34) 176.09,57.93 PQB13.4 175.63,57.76 PCB28.1
BKLT_CTRL: length 8.9
  TOP w0.102: v1(207.98,45.16) R9.1 208.01,46.31 R5217.2 207.78,47.34 D3.1 212.05,49.53 R303.2
BKOFF#: length 106
  TOP w0.102: R302.2 212.24,48.03 211.82,48.45 211.11,48.45 210.54,47.87 v2(210.54,47.68) ; v1(126.24,49.72) 126.59,50.07 v2(126.59,50.24)
  IN1 w0.127: v2(126.59,50.24) 127.69,50.24 127.89,50.03 132.2,50.03 133.28,51.11 137.13,51.11 137.73,50.52 141.22,50.52 143.39,48.34 147.91,48.34 149.03,47.23 152.59,47.23 152.69,47.13 161.43,47.13 162.62,48.32 165.31,48.32 168.16,51.17 168.72,51.17 170.23,52.68 171.95,52.68 173.72,54.45 176.87,54.45 178,54.45 178.44,54.45 178.59,54.61 178.7,54.71 180.71,54.71 180.71,54.71 181.83,54.71 182.28,54.71 183.34,55.77 187.97,55.77 188.96,54.78 192.04,54.78 192.88,55.62 194,55.62 195.98,57.6 197.99,57.6 199.66,55.94 202.92,55.94 205.84,53.02 209.23,53.02 210.54,51.71 v2(210.54,47.68)
  BOTTOM w0.102: UE1.105 123.08,51.7 124.14,50.64 126.19,50.64 v2(126.59,50.24)
BLON_OUT_C: length 6
  TOP w0.102: v1(214.98,49.91) 214.78,49.7 R5218.2 v2(213.97,48.89) 213.15,48.08 R302.1
  BOTTOM w0.102: v2(213.97,48.89) 213.97,48.13 212.79,46.95 JEDP1.28
BMON: length 1.8
  BOTTOM w0.203: PUB01.27 197.96,50.44 198.02,50.5 198.52,50.5 198.88,50.86 PRB29.2
BST_1.2V:
  vias: v1(25.05,113.28)
BST_1.2V_R: length 1.3
  TOP w0.102: PRM02.2 v1(25.12,111.95)
BST_1.05V: length 0.9
  BOTTOM w0.102: 147.48,59.94 147.48,59.3 v1(147.29,59.11)
BST_3V: length 1.3
  BOTTOM w0.102: PR301.1 166.85,62.48 v1(166.53,62.8)
BST_3V_R: length 1.2
  BOTTOM w0.102: PC307.1 163.57,62.24 v1(163.37,62.44)
BST_5V: length 0.7
  BOTTOM w0.102: PR501.1 v2(206.66,75.94)
BST_5V_R: length 1.2
  BOTTOM w0.102: PC507.1 207.81,74.61 v1(207.87,74.54)
BST_CHG: length 1
  BOTTOM w0.102: PCB06.1 v1(189.76,46.55)
BST_CHG_R: length 2.4
  BOTTOM w0.102: v1(189.59,50.1) 190.23,49.46 191.05,49.46 191.21,49.31 PRB14.1
BST_VCCGI:
  vias: v1(100.94,133.85)
BST_VNN: length 1.2
  BOTTOM w0.102: PRZ19.1 v1(89.44,129.6)
BT_RADIO_DIS#: length 78
  TOP w0.102: RW4.2 74.37,134.93 74.68,134.62 74.68,134.18 73.8,133.29 73.8,132.86 74.19,132.47 74.63,132.47 75.6,131.5 v1(75.6,130.3) 75.6,129.22 v2(75.47,129.09)
  IN1 w0.127: v2(92.13,85.1) 92.13,86.69 91.39,87.44 91.39,92.31 90.54,93.16 90.54,96.36 88.38,98.51 88.38,104.02 88.38,104.39 86.41,106.36 86.2,106.36 84.78,106.36 84.78,106.36 82.94,106.36 77.95,111.35 77.95,115.69 76.17,117.47 76.17,125.41 76.08,125.5 76.08,125.5 75.79,125.79 75.79,128.77 v2(75.47,129.09)
  IN2 w0.127: v2(92.49,75.43) 92.05,75.88 91.73,75.88 91.47,76.13 91.47,77.53 91.66,77.72 94.2,77.72 94.62,78.14 94.62,80.39 94.31,80.7 92.87,80.7 92.62,80.96 92.62,82.65 92.13,83.13 v2(92.13,85.1)
  BOTTOM w0.089: v2(92.49,75.43) 92.49,75.35 UC1.H37
BT_RADIO_DIS#_R: length 5.8
  TOP w0.102: v1(73.05,135.57) 72.87,135.39 71.67,135.39 RW4.1 71.09,134.81 v2(69.88,134.81) 69.64,134.56 RW28.1
  BOTTOM w0.102: v2(69.88,134.81) 70.2,134.81 70.21,134.8 JWLAN1.54
CAM_DET#: length 164
  TOP w0.102: v2(180.1,41.36) 180.1,41.67 181.67,43.24 188.29,43.24 190.66,40.86 194.53,40.86 196.32,39.07 205.93,39.07 v1(206.12,39.27) 207.74,40.89 208.55,40.89 211.09,43.43 R131.2
  IN1 w0.127: v2(180.1,41.36) 179.9,41.36 178.79,42.48 175.87,42.48 174.53,41.14 145.64,41.14 144.92,40.42 143.62,40.42 141.7,42.35 140.27,42.35 137.48,45.14 132.15,45.14 131.45,44.45 128.65,44.45 127.95,43.75 126.48,43.75 126.03,44.2 125.54,44.2 124.78,44.97 124.03,44.97 121.66,47.34 120.39,47.34 119.99,47.74 119.07,47.74 116.58,50.22 112.75,50.22 111.86,49.33 111.86,45.11 110.86,44.11 108.89,44.11 108.3,44.7 108.3,53.78 109.06,54.54 109.06,58.29 108.3,59.05 v2(107.29,59.05) 107.73,58.61 107.73,58.1 107.6,57.97 105.32,57.97 104.2,59.09 104.2,60.83 102.62,62.41 101.56,62.41 100.91,61.75 99.5,61.75 98.27,62.99 98.27,63.86 97.06,65.07 97.06,65.7 96.82,65.94 96.77,65.94 94.79,67.91 91.7,67.91 90.84,68.78 90.84,69.73 v2(90.38,70.19)
  BOTTOM w0.089: v2(90.38,70.19) 90.03,70.54 UC1.M27
  BOTTOM w0.102: RC1148.2 108.11,59.05 v2(107.29,59.05)
CAM_DET#_R: length 20.5
  TOP w0.102: R131.1 213.03,43.68 213.61,43.68 v2(214.09,43.2)
  BOTTOM w0.102: JEDP1.4 214.26,58.95 215.62,57.59 215.62,50.54 214.79,49.72 214.79,46.6 214.09,45.91 v2(214.09,43.2)
CAP_LED: length 3.1
  BOTTOM w0.102: R25.2 80.05,35.86 v2(80.55,35.36) JKB1.27
CAP_LED_Q: length 2.5
  BOTTOM w0.102: R25.1 v2(79.85,36.77) 79.88,36.8 Q7.1
CAPS_LED#: length 52.1
  TOP w0.102: v2(121.25,46.36) 121.48,46.59 121.48,46.76 v1(121.71,46.99)
  IN1 w0.127: v2(121.25,46.36) 120.41,46.36 120.13,46.08 118.77,46.08 116.8,44.1 116.8,42.08 115.41,40.7 111.16,40.7 110.33,39.87 108.36,39.87 107.31,38.82 107.31,37.17 106.52,36.38 98.42,36.38 97.93,36.86 90.36,36.86 89.06,38.16 v2(89.06,39.75)
  BOTTOM w0.102: Q6.3 86.15,39.61 85.71,40.05 R24.2 88.3,40.51 v2(89.06,39.75) ; v2(121.25,46.36) 121.25,47.7 119.93,49.02 119.28,49.02 119.09,49.22 UE1.91
CAPS_LED#_R: length 8.7
  BOTTOM w0.102: Q7.2 80.29,39.86 v2(80.49,40.06) 82.84,40.06 83.22,39.68 83.22,37.4 83.82,36.8 Q6.1
CBN: length 4
  TOP w0.203: UA1.28 26.47,12.01 25.63,11.17 CA496.2
CBP: length 5.3
  TOP w0.203: UA1.30 28.84,11.21 28.61,10.98 28.61,10.96 v2(28.5,10.85)
  TOP w0.254: CA496.1 25.5,10.18 v2(25.23,10.45)
  IN1 w0.203: v2(28.5,10.85) 28.32,11.03 25.51,11.03 25.23,10.75 v2(25.23,10.45)
CCLIM: length 9.3
  TOP w0.254: PRB28.2 198.64,50.86 198.38,51.11 198.38,51.14 v2(198.36,51.14) 197.27,52.23 193.46,52.23 193.25,52.43 v1(193.25,52.83) 193.25,53.6 193.48,53.83 PRB27.2
  BOTTOM w0.203: PUB01.26 197.99,50.84 198.28,51.14 v2(198.36,51.14)
CHG_AMBER_LED_R#: length 3.5
  TOP w0.254: Q17.6 13.04,123.52 v1(13.59,122.96) v2(14.29,122.96)
  BOTTOM w0.254: Q5029.2 13.27,122.3 13.96,122.99 14.32,122.99 14.32,122.96 v2(14.29,122.96)
CLK_PCIE_N0: length 82.4
  IN2 w0.089: v2(89.25,62.8) 89.25,62.97 89.34,63.06 89.65,63.06 89.74,62.97 89.74,62.39 89.63,62.29 89.63,60.45 88.91,59.72 88.8,59.72 88.76,59.77 88.73,59.77
  IN2 w0.127: 88.73,59.77 83.25,59.77 82.38,58.9 82.38,57.42 77.03,52.07 64.11,52.07 64,51.95 63.99,51.95 56.66,44.61 53.89,44.61 51.78,42.5 46.1,42.5 43.93,40.33 34.52,40.33 33.82,39.62 28.87,39.62 26.34,37.09 26.34,36.02 26.62,35.74 26.9,35.74 v2(27.09,35.56)
  BOTTOM w0.089: UC1.R10 v2(89.25,62.8)
  BOTTOM w0.114: v2(27.09,35.56) 26.89,35.75 26.42,35.75 26.3,35.63 26.3,35.49 26.25,35.44 26.25,34.82 26.38,34.69 JSSD1.53
CLK_PCIE_N1: length 115.7
  IN2 w0.089: v2(90.21,60.66) 90.21,60.79 90.36,60.94 90.58,60.94 90.78,61.14 90.78,62.16 90.39,62.54 90.39,63.29 89.68,64 88.87,64 88.81,63.94 88.17,63.94 87.95,64.17 87.95,64.47 88.17,64.69 88.17,66.25 88.58,66.66 88.58,67.09 89.76,68.27 89.76,68.43 90.07,68.75 90.54,68.75 90.58,68.72 92.28,68.72 92.37,68.8 92.67,68.8 92.75,68.72 94.32,68.72 94.83,69.23 94.89,69.23 94.9,69.24
  IN2 w0.127: v2(76.64,134.12) 76.48,133.96 76.48,132.41 75.14,131.07 75.14,129.36 75.05,129.26 75.05,128.92 75.14,128.83 75.14,123.88 76.42,122.61 76.42,121.93 76.59,121.75 76.59,117.9 76.59,117.15 74.39,114.95 74.39,113.2 76.92,110.68 76.92,109.31 76.92,108.91 76.93,108.89 76.93,108.35 84.49,100.79 89.61,100.79 94.51,95.89 94.64,95.89 94.64,95.89 94.94,95.89 102.34,95.89 106.22,92.01 106.22,87.36 107.06,86.52 107.06,81.59 104.03,78.56 104.03,75.09 101.01,72.08 101,72.08 100.5,72.08 100.01,72.08 99.77,71.84 99.69,71.76 99.69,71.58 98.32,70.22 97.59,70.22 96.96,69.58 95.24,69.58 94.9,69.24
  BOTTOM w0.089: UC1.N5 v2(90.21,60.66)
  BOTTOM w0.114: v2(76.64,134.12) 76.46,133.94 76.46,133.59 76.63,133.42 78.15,133.42 78.28,133.55 JWLAN1.49
CLK_PCIE_N2: length 121.2
  TOP w0.114: v2(26.06,86.52) 26.04,86.52 25.88,86.36 25.73,86.36 25.44,86.06 25.44,85.75 25.21,85.53 24.8,85.53 24.8,85.53 24.77,85.53 24.59,85.34 UL1.16
  IN2 w0.089: 86.01,60.38 86.27,60.38 86.59,60.07 88.66,60.07 v2(89.25,60.66)
  IN2 w0.127: 86.01,60.38 83.15,60.38 81.95,59.18 81.31,59.18 81.19,59.06 81.19,56.94 76.94,52.69 64.02,52.69 56.46,45.13 51.33,45.13 50.13,43.93 45.42,43.93 42.36,40.87 29.46,40.87 27.88,42.45 27.88,84.43 27.04,85.27 25.64,85.27 25.36,85.55 25.36,86.13 25.59,86.36 25.91,86.36 v2(26.06,86.52)
  BOTTOM w0.089: UC1.R5 v2(89.25,60.66)
CLK_PCIE_P0: length 82.4
  IN2 w0.089: v2(89.25,63.43) 89.25,63.33 89.34,63.24 89.72,63.24 89.91,63.05 89.91,62.32 89.81,62.22 89.81,60.37 88.98,59.55 88.8,59.55 88.76,59.5 88.73,59.5
  IN2 w0.127: 88.73,59.5 83.36,59.5 82.65,58.79 82.65,57.31 77.14,51.8 64.22,51.8 64.11,51.68 64.1,51.68 56.77,44.35 54,44.35 51.89,42.23 46.21,42.23 44.04,40.06 34.63,40.06 33.93,39.36 28.98,39.36 26.6,36.98 26.6,36.13 26.73,36.01 26.95,36.01 v2(27.09,36.14)
  BOTTOM w0.089: v2(89.25,63.43) 88.79,63.78 UC1.R12
  BOTTOM w0.114: JSSD1.55 25.87,34.71 26,34.84 26,35.54 26.05,35.59 26.05,35.73 26.32,35.99 26.94,35.99 v2(27.09,36.14)
CLK_PCIE_P1: length 115.8
  IN2 w0.089: v2(90.21,61.37) 90.21,61.27 90.36,61.12 90.51,61.12 90.6,61.21 90.6,62.09 90.22,62.47 90.22,63.22 89.61,63.83 88.95,63.83 88.88,63.76 88.1,63.76 87.77,64.09 87.77,64.54 87.99,64.77 87.99,66.33 88.4,66.73 88.4,67.17 89.58,68.35 89.58,68.51 90,68.92 90.62,68.92 90.65,68.89 92.21,68.89 92.29,68.98 92.74,68.98 92.82,68.89 94.24,68.89 94.7,69.35 94.7,69.41 94.72,69.43
  IN2 w0.127: 94.72,69.43 95.13,69.85 96.85,69.85 97.48,70.48 98.21,70.48 99.42,71.69 99.42,71.87 99.9,72.35 100.12,72.35 100.12,72.34 100.89,72.34 100.9,72.35 103.76,75.2 103.76,78.67 106.79,81.7 106.79,86.41 105.95,87.25 105.95,91.9 102.23,95.63 95.05,95.63 94.4,95.63 89.5,100.53 84.38,100.53 76.67,108.24 76.67,108.78 76.65,108.8 76.65,109.42 76.65,110.16 76.65,110.57 74.13,113.09 74.13,115.06 74.28,115.21 74.28,115.21 76.33,117.26 76.33,117.37 76.33,121.64 76.15,121.82 76.15,122.5 74.88,123.78 74.88,128.72 74.79,128.81 74.79,129.37 74.88,129.47 74.88,131.18 75.03,131.34 76.22,132.52 76.22,133.96 v2(76.06,134.12)
  BOTTOM w0.089: UC1.N7 v2(90.21,61.37)
  BOTTOM w0.114: JWLAN1.47 78.31,133.05 78.18,133.18 76.52,133.18 76.22,133.48 76.22,133.96 v2(76.06,134.12)
CLK_PCIE_P2: length 121.3
  TOP w0.114: UL1.15 24.59,84.94 24.93,85.28 25.31,85.28 25.68,85.65 25.68,85.96 25.83,86.11 25.92,86.11 26.07,85.96 26.07,85.93 v2(26.07,85.93)
  IN2 w0.089: 86.01,60.65 86.04,60.65 86.12,60.56 86.34,60.56 86.66,60.24 88.58,60.24 88.89,60.55 88.89,60.81 89.1,61.03 89.29,61.03 89.38,61.11 89.38,61.45 v2(89.25,61.58)
  IN2 w0.127: v2(26.07,85.93) 26.07,85.97 25.95,86.1 25.7,86.1 25.62,86.02 25.62,85.66 25.75,85.53 27.15,85.53 28.14,84.54 28.14,42.56 29.57,41.13 42.25,41.13 45.31,44.19 50.02,44.19 51.22,45.4 56.35,45.4 63.91,52.95 76.83,52.95 80.92,57.05 80.92,59.16 81.2,59.45 81.84,59.45 83.04,60.65 86.01,60.65
  BOTTOM w0.089: UC1.R7 v2(89.25,61.58)
CLK_SMB: length 16.7
  BOTTOM w0.102: PR42.1 150.73,43.85 150.83,43.75 v4(151.74,43.75) 152.43,43.75 153.64,42.54 153.64,39.64 154.87,38.41 160.75,38.41 160.95,38.61 PBATT1.7
CLKREQ_CNV#: length 113.8
  TOP w0.102: v2(107.13,97.82) v1(106.5,98.46) 106.04,98.92 103.84,98.92 100.54,95.61 94.21,95.61 90.86,98.96 90.86,100.05 85.85,105.06 78.74,105.06 76.6,107.2 76.6,107.22 76.6,114.88 74.63,116.85 74.63,122.21 74.13,122.72 70.7,122.72 69.91,123.5 69.91,124.1 v2(70.33,124.52) 70.58,124.77 RW22.1 ; v2(108.1,68.69) 108.24,68.83 RC86.1
  IN2 w0.089: 97.13,67.37 96.74,67.37 96.43,67.05 95.37,67.05 95.08,67.34 93.81,67.34 v2(93.24,66.77)
  IN2 w0.127: 97.13,67.37 99.17,67.37 100.18,68.37 101.43,68.37 103.24,66.57 106.68,66.57 108.1,67.99 v2(108.1,68.69) 108.1,69.77 108.53,70.2 108.53,71.67 109.24,72.39 109.24,72.62 109.24,72.63 109.24,72.98 109.24,72.99 109.24,74.22 110.71,75.69 110.71,77.06 111.48,77.83 111.48,82.82 110.97,83.33 110.97,89.23 109.06,91.14 109.06,92.59 107.13,94.52 v2(107.13,97.82)
  BOTTOM w0.089: UC1.F19 v2(93.24,66.77)
  BOTTOM w0.102: JWLAN1.14 70.61,124.8 v2(70.33,124.52)
CLKREQ_PCIE#0: length 177.9
  TOP w0.102: v2(60.08,31.23) 60.08,31.23 60.08,31.25 61.55,32.72 64.26,32.72 64.93,32.72 65.44,32.72 65.69,32.98 73.86,32.98 78.64,32.98 79.8,31.82 113.8,31.82 118.39,36.41 118.39,38.81 118.96,39.39 118.96,47.79 120.7,49.53 120.7,51.56 121.13,51.99 121.13,54.83 121.26,54.95 121.26,57.78 v1(121.13,57.91) 120.84,58.2 v2(120.44,58.2) ; v2(98.78,82.55) 99.54,82.55 100.11,83.12 100.11,83.13 101.8,84.82 104.28,84.82 104.84,84.26 RC167.2
  IN1 w0.127: v2(120.44,58.2) 120.44,59.95 117.94,62.45 117.94,64.76 115.86,66.84 115.86,76.79 110.95,81.69 107.64,81.69 107.33,81.38 105.18,81.38 103.92,80.12 100.5,80.12 99.41,81.2 99.41,81.91 v2(98.78,82.55)
  IN2 w0.127: v2(26.45,27.74) 26.45,27.81 27.72,29.08 38.07,29.08 38.58,29.08 39.15,29.65 42.13,29.65 42.94,28.85 43.98,28.85 45.73,30.6 48.7,30.6 50.09,29.21 56.74,29.21 57.63,30.09 58.95,30.09 60.08,31.23 v2(60.08,31.23)
  BOTTOM w0.089: UC1.A46 95.66,79.24 96.13,79.71 96.45,79.71 97.32,80.58 97.32,81.15 97.2,81.27 97.2,81.83 97.92,82.55 98.53,82.55
  BOTTOM w0.102: 98.53,82.55 v2(98.78,82.55) ; JSSD1.52 26.63,27.57 v2(26.45,27.74)
CLKREQ_PCIE#1: length 86.5
  TOP w0.102: RW25.1 v2(75.47,133.09) ; v2(97.56,81.68) 97.56,82.22 99.53,84.18 100.59,84.18 101.76,85.35 v1(102.84,85.35) 103.18,85.35 104.18,86.35 v2(104.18,86.36) 104.75,85.78 RC166.2
  IN2 w0.127: v2(104.18,86.36) 104.59,86.77 104.59,90.53 103.43,91.69 102.71,91.69 102.14,92.26 102.14,93.47 101.17,94.44 95.98,94.44 95.34,94.44 94.59,94.44 89.15,99.88 83.4,99.88 83.39,99.89 80,103.28 80,103.56 76.03,107.52 76.03,108.15 76.02,108.16 76.02,109.69 76.02,110.31 74.91,111.41 74.02,111.41 73.27,112.16 73.27,115.17 75.7,117.59 75.7,121.37 75.52,121.55 75.52,122 74.19,123.33 74.19,125.39 73.82,125.76 73.82,131.12 74.62,131.92 74.62,132.74 74.97,133.09 v2(75.47,133.09)
  BOTTOM w0.089: v2(97.56,81.68) 97.56,81.67 97.51,81.62 97.51,80.46 96.58,79.54 96.21,79.54 95.65,78.98 95.41,78.98 95.41,78.98 95.2,78.98 95.19,78.98 95.18,78.98 95.11,79.05 94.9,79.05 94.78,78.97 UC1.C45
CLKREQ_PCIE#2: length 168.2
  TOP w0.102: v2(98.14,81.62) 98.14,82.51 99.5,83.87 100.56,83.87 101.72,85.02 RC165.2 ; RL13.1 27.91,81.44 27.81,81.34 v2(27.01,81.34) ; v2(109.83,80.7) 109.83,81.04 109.29,81.58 109.29,85.36 108.43,86.23 108.43,88.82 106.4,90.85 v1(106.4,92.26) 106.4,92.77 104.19,94.98 93.95,94.98 90.23,98.7 90.23,99.03 86.79,102.47 82.99,102.47 80.88,104.58 78.55,104.58 76.11,107.03 76.11,113.72 v2(75.41,114.42)
  IN1 w0.127: v2(75.41,114.42) 74.27,114.42 73.31,115.37 62.14,115.37 61.12,114.36 58.98,114.36 58.29,115.06 46.5,115.06 45.49,114.04 40.22,114.04 39.97,114.3 32.06,114.3 28.93,111.16 28.93,108.77 27.02,106.87 27.02,104.45 28.23,103.25 28.23,90.47 29.05,89.64 29.05,88.59 27.17,86.71 27.17,81.49 27.02,81.34 v2(27.01,81.34) ; v2(109.83,80.7) 109.6,80.93 107.96,80.93 107.65,80.62 105.49,80.62 104.23,79.35 100.18,79.35 98.56,80.97 98.56,81.2 98.14,81.61 v2(98.14,81.62)
  BOTTOM w0.089: v2(98.14,81.62) 97.7,81.17 97.7,80.4 96.65,79.36 96.28,79.36 95.72,78.8 95.01,78.8 UC1.B45
CLKREQ_PCIE#2_R: length 4.4
  TOP w0.102: RL13.2 27.91,83.79 27.58,84.12 v1(27.02,84.12) 25.42,84.12 24.99,83.69 24.74,83.69 24.68,83.74 UL1.12
CLKREQ_PCIE#3: length 5.5
  BOTTOM w0.089: 98.53,80.71 98.26,80.44 97.99,80.44 97.32,79.77 v1(97.32,79.56) 96.94,79.18 96.35,79.18 95.79,78.62 95.21,78.62 94.92,78.33 UC1.C44
  BOTTOM w0.102: RC176.2 98.84,81.02 98.53,80.71
CLKREQ_PCIE#15_R: length 2.8
  TOP w0.102: RW25.2 77.89,133.78 v2(77.89,134.38)
  BOTTOM w0.102: JWLAN1.53 78.05,134.55 v2(77.89,134.38)
CLKRUN#: length 63.6
  TOP w0.102: v2(127.27,39.11) 127.35,39.03 v1(127.35,38.35) 127.35,38.16 129,36.51 v2(129,34.41)
  IN1 w0.127: v2(120.24,49.81) 119.78,49.81 113.64,55.95 113.64,61.49 110.33,64.79 110.33,70.21 108.16,72.39 103.54,72.39 103.22,72.71 100.78,72.71 100.65,72.58 99.45,72.58 98.4,73.63 v2(98.4,73.82)
  BOTTOM w0.089: v2(98.4,73.82) 97.74,73.82 97.59,73.67 95.58,73.67 95.45,73.55 95.21,73.55 95.09,73.64 94.89,73.64 94.62,73.37 UC1.C33
  BOTTOM w0.102: RE5.1 129.82,34.41 v2(129,34.41) ; v2(120.24,49.81) 122.05,49.81 126.65,45.21 126.65,42.95 126.86,42.74 126.86,39.92 127.27,39.51 v2(127.27,39.11)
CMSRC: length 40.4
  TOP w0.102: v2(190.66,58.16) v1(191.17,58.16)
  TOP w0.508: PRB08.2 v2(179.09,70.23)
  IN1 w0.508: v2(190.66,58.16) 190.66,58.89 190.55,58.99 190.55,60.81 188.13,63.23 188.08,63.23 188,63.3 183.72,63.3 182.56,64.47 182.56,67.28 181.38,68.46 179.96,68.46 179.09,69.32 v2(179.09,70.23)
  IN2 w0.508: v2(194.92,46.48) 194.92,47.5 197.06,49.65 197.06,50.78 196.96,50.88 196.3,51.54 194.52,51.54 192.51,53.56 192.51,57.82 192,58.33 190.82,58.33 v2(190.66,58.16)
  BOTTOM w0.203: v2(194.92,46.48) 195.1,46.66 PUB01.5
CNV_BRI_PRX_DTX: length 118.8
  TOP w0.102: v2(112.43,84.2) 111.49,84.2 RW8.1 ; v2(109.44,98.74) 108.97,98.27 107.76,98.27 106.79,99.24 106.66,99.37 103.65,99.37 100.35,96.07 94.44,96.07 91.4,99.11 91.4,100.16 86.04,105.52 78.95,105.52 77.06,107.41 77.06,115.18 75.09,117.15 75.09,122.61 v1(74.39,123.32) 74.39,123.68 74.28,123.79 74.2,123.79 74.1,123.89 74.1,124.09 74.2,124.19 74.28,124.19 74.39,124.29 74.39,126.13 RW19.1
  IN2 w0.089: v2(91.81,65.86) 92.36,65.31 94.12,65.31 94.37,65.06 96.71,65.06 97.17,65.52
  IN2 w0.127: 97.17,65.52 97.24,65.59 98.4,65.59 98.53,65.72 101.21,65.72 102.46,64.47 108.45,64.47 110.08,66.1 110.08,66.72 111.99,68.62 111.99,71.24 113.2,72.45 113.2,83.94 112.94,84.2 v2(112.43,84.2) 112.24,84.39 112.24,89.82 110.34,91.72 110.34,93.12 109.89,93.56 109.89,98.29 v2(109.44,98.74)
  BOTTOM w0.089: UC1.J17 v2(91.81,65.86)
CNV_BRI_PRX_R_DTX: length 4.9
  TOP w0.102: v2(70.33,127.08) 70.79,126.63 v1(71.09,126.63) 71.87,126.63 71.99,126.75 RW18.1 72.06,126.74 RW19.2 RW10.1
  BOTTOM w0.102: JWLAN1.22 70.61,126.8 v2(70.33,127.08)
CNV_BRI_PTX_DRX: length 23.8
  TOP w0.102: RC87.2 RW15.1 111.04,68.93 v1(110.14,68.93) 109.56,68.93 v2(109.39,68.75)
  IN2 w0.089: 97.13,66.73 97.02,66.73 96.93,66.73 96.65,66.45 94.29,66.45 94.12,66.28 92.94,66.28 v2(92.52,65.86)
  IN2 w0.127: 97.13,66.73 97.23,66.73 97.41,66.56 101.45,66.56 102.77,65.24 107.94,65.24 109.11,66.4 109.11,68.49 109.38,68.77 109.38,68.75 v2(109.39,68.75)
  BOTTOM w0.089: UC1.H17 v2(92.52,65.86)
CNV_BRI_PTX_R_DRX: length 100
  TOP w0.102: RW15.2 110.52,70.37 110.52,71.23 v2(110.26,71.5) ; v2(107.99,99.49) 107.98,99.49 107.98,99.63 v1(107.55,100.06) 103.37,100.06 100.07,96.76 94.76,96.76 92.1,99.42 92.1,100.43 86.32,106.21 79.24,106.21 77.75,107.7 77.75,115.47 75.85,117.36 75.85,127.85 74.17,129.54 73.57,129.54 73,130.11 70.75,130.11 70.65,130.21 70.65,130.39 70.54,130.49 70.25,130.49 70.09,130.32 v2(69.55,130.32)
  IN2 w0.127: v2(107.99,99.49) 107.98,99.49 108.75,98.73 108.75,93.63 109.57,92.8 109.57,91.4 111.48,89.5 111.48,83.54 111.98,83.03 111.98,77.61 111.26,76.89 111.26,75.4 111.41,75.24 111.41,72.65 v2(110.26,71.5)
  BOTTOM w0.102: v2(69.55,130.32) 69.58,130.3 JWLAN1.36
CNV_RF_RESET#: length 116
  TOP w0.102: RW11.1 70.72,123.8 v2(70.33,123.8) ; RW11.1 71.55,122.97 74.28,122.97 74.86,122.39 74.86,117 76.83,115.03 76.83,107.32 78.86,105.29 85.94,105.29 91.17,100.07 91.17,98.98 94.31,95.84 100.45,95.84 103.75,99.14 106.56,99.14 107.77,97.94 v1(107.98,97.94) 109.28,97.94 v2(109.44,98.1) ; RW11.1 71.18,123.54 RW23.1
  IN2 w0.089: v2(93.25,65.85) 93.61,65.48 94.2,65.48 94.45,65.24 96.5,65.24 97.13,65.86
  IN2 w0.127: v2(109.44,98.1) 109.44,93.65 110.08,93.01 110.08,91.61 111.98,89.71 111.98,83.82 112.49,83.31 112.49,72.11 111.67,71.28 111.67,68.66 109.83,66.82 109.83,66.21 108.35,64.73 102.56,64.73 101.32,65.97 97.24,65.97 97.13,65.86
  BOTTOM w0.089: v2(93.25,65.85) 93.25,65.85 UC1.F17
  BOTTOM w0.102: JWLAN1.10 v2(70.33,123.8)
CNV_RGI_PRX_DTX: length 116.9
  TOP w0.102: v2(109,99.18) 108.9,99.08 107.72,99.08 106.97,99.83 103.46,99.83 100.16,96.53 94.63,96.53 91.86,99.3 91.86,100.35 86.23,105.98 79.14,105.98 77.52,107.6 77.52,115.37 75.6,117.29 75.6,127.78 74.1,129.28 RW16.1 ; RC88.2 109.69,68 109.51,68.18 v2(109.53,68.18)
  IN2 w0.089: v2(93.96,65.85) 94.38,66.27 96.76,66.27 97,66.5 97.02,66.48 97.13,66.48
  IN2 w0.127: 97.13,66.48 97.32,66.29 101.36,66.29 102.67,64.98 108.24,64.98 109.51,66.25 109.51,68.18 v2(109.53,68.18) 109.53,68.21 111.41,70.1 111.41,72.07 111.73,72.39 111.73,75.28 111.51,75.5 111.51,76.78 112.24,77.51 112.24,83.14 111.73,83.64 111.73,89.61 109.83,91.51 109.83,92.9 109,93.73 v2(109,99.18)
  BOTTOM w0.089: UC1.D17 93.96,65.85 v2(93.96,65.85)
CNV_RGI_PRX_R_DTX: length 3.7
  TOP w0.102: RW16.2 71.14,129.28 v1(70.77,129.66) 70.63,129.79 v2(69.86,129.79)
  BOTTOM w0.102: v2(69.86,129.79) 69.88,129.79 69.89,129.8 JWLAN1.34
CNV_RGI_PTX_DRX: length 26.6
  TOP w0.102: v2(110.36,72.78) 110.7,73.12 RW17.1
  IN2 w0.089: 97.13,67.11 97.02,67.11 96.94,67.19 96.82,67.19 96.5,66.87 95.3,66.87 95.1,67.07 94.25,67.07 v2(93.95,66.77)
  IN2 w0.127: v2(110.36,72.78) 109.71,72.13 109.35,72.13 108.78,71.57 108.78,66.45 107.82,65.49 102.88,65.49 102.21,66.16 102.21,67.24 101.33,68.12 100.28,68.12 99.28,67.11 97.13,67.11
  BOTTOM w0.089: UC1.D19 v2(93.95,66.77)
CNV_RGI_PTX_R_DRX: length 97.8
  TOP w0.102: RW17.2 111.59,73.81 RW7.1 111.08,75.12 v2(110.83,75.12) ; v2(70.33,129.3) 70.33,128.84 70.7,128.47 RW9.1 71.23,128.46 73.44,128.46 73.54,128.56 73.54,128.81 73.65,128.91 73.85,128.91 73.95,128.81 73.95,128.56 74.05,128.46 74.58,128.46 75.35,127.69 75.35,127.52 75.24,127.41 74.81,127.41 74.71,127.31 74.71,127.11 74.81,127.01 75.22,127.01 75.35,126.88 75.35,126.68 75.24,126.58 74.86,126.58 74.76,126.47 74.76,126.27 74.86,126.17 v1(75.24,126.17) 75.35,126.07 75.35,125.87 75.24,125.76 74.84,125.76 74.74,125.66 74.74,125.46 74.84,125.36 75.24,125.36 75.35,125.26 75.35,125.05 75.24,124.95 74.84,124.95 74.74,124.85 74.74,124.65 74.84,124.54 75.24,124.54 75.35,124.44 75.35,117.22 77.29,115.28 77.29,107.51 79.05,105.75 86.13,105.75 91.63,100.25 91.63,99.21 94.54,96.3 100.26,96.3 103.56,99.6 106.79,99.6 107.72,98.67 v2(108.11,98.67)
  IN2 w0.127: v2(108.11,98.67) 108.11,93.9 109.32,92.7 109.32,91.25 111.22,89.34 111.22,83.43 111.73,82.93 111.73,77.72 111.01,77 111.01,75.3 v2(110.83,75.12)
  BOTTOM w0.102: JWLAN1.32 v2(70.33,129.3)
CNVI_EN#: length 73
  TOP w0.102: v2(66.71,132.71) 66.71,133.03 66.52,133.22 v1(66.14,133.22) 65.19,133.22 65.01,133.39 QW1.2 65.01,134.93 RW26.1
  IN1 w0.127: v2(90.97,77.29) 90.97,77.29 90.97,77.27 90.39,77.27 90.01,77.66 90.01,78.01 89.59,78.44 89.59,80.76 89.34,81.02 89.34,81.91 90.33,82.9 90.33,84.32 89.19,85.47 89.19,85.93 88.9,86.22 88.9,90.17 87.85,91.21 87.85,96.52 86.81,97.56 86.81,98.05 86.81,104.17 85.89,105.09 84.65,105.09 84.44,105.09 83.43,105.09 82.73,105.09 76.68,111.14 76.68,115.14 74.77,117.05 74.77,122.17 71.22,125.73 71.22,127.31 66.71,131.82 v2(66.71,132.71)
  BOTTOM w0.089: UC1.L41 90.73,76.94 90.97,77.27 90.97,77.29 v2(90.97,77.29)
CNVI_WGR_CLK_DN: length 91.3
  IN2 w0.127: v2(91.79,72.07) 91.97,71.89 91.97,71.65 92.65,70.96 94.74,70.96 95.39,71.61 95.39,71.87 95.8,72.27 96.44,72.27 96.89,72.73 96.89,72.95 96.89,73.04 100.27,76.43 101.06,76.43 101.53,76.89 101.53,77.09 101.53,78.73 101.53,78.94 101.91,79.33 101.91,83.59 101.28,84.22 101.28,87.36 101.44,87.53 101.44,88.06 101.29,88.22 101.29,88.22 100.9,88.6 100.89,88.6 100.59,88.9 100.59,90.58 99.01,92.16 97.67,92.16 97.43,92.4 93.86,92.4 93.75,92.4 89.93,96.22 83.74,96.22 81.27,98.7 77.99,98.7 76.5,100.19 76.5,103.67 73.7,106.46 73.7,107.2 71.31,109.6 71.31,112.41 71.31,112.42 71.31,112.48 71.73,112.9 71.73,112.94 71.73,113.34 71.73,113.34 71.73,113.77 71.73,113.77 71.73,115.89 71.74,115.91 71.74,115.99 72.55,116.8 72.55,119.33 72.68,119.46 73.03,119.46 v2(73.12,119.38)
  BOTTOM w0.102: UC1.H31 v2(91.79,72.07)
  BOTTOM w0.114: v2(73.12,119.38) 74.14,119.38 75.09,120.33 75.09,126.23 75.66,126.8 78.08,126.8 78.33,126.55 JWLAN1.21
CNVI_WGR_CLK_DP: length 91.3
  IN2 w0.127: v2(92.53,72.07) 92.29,72.07 92.19,71.97 92.19,71.74 92.74,71.18 94.65,71.18 95.17,71.7 95.17,71.96 95.18,71.96 95.18,71.99 95.73,72.54 96.33,72.54 96.62,72.84 96.62,73.15 100.01,76.53 100.01,76.54 100.16,76.69 100.95,76.69 101.26,77 101.26,77.2 101.26,78.84 101.26,79.05 101.65,79.44 101.65,83.48 101.01,84.11 101.01,87.47 101.18,87.64 101.18,87.95 100.79,88.34 100.78,88.34 100.33,88.79 100.33,90.47 98.9,91.9 97.56,91.9 97.32,92.14 93.97,92.14 93.86,92.14 93.64,92.14 89.82,95.96 83.64,95.96 81.16,98.43 77.88,98.43 76.23,100.08 76.23,100.3 76.23,103.5 73.44,106.29 73.44,107.09 71.04,109.49 71.04,112.52 71.05,112.53 71.05,112.59 71.46,113.01 71.46,113.24 71.46,113.24 71.46,113.88 71.46,113.88 71.46,116 71.47,116.01 71.47,116.1 72.29,116.91 72.29,119.44 72.57,119.73 72.89,119.73 v2(73.12,119.96)
  BOTTOM w0.102: UC1.H29 92.17,71.77 92.46,72.07 v2(92.53,72.07)
  BOTTOM w0.114: JWLAN1.23 75.56,127.05 74.84,126.34 74.84,120.43 74.04,119.62 73.46,119.62 v2(73.12,119.96)
CNVI_WGR_DATA0_DN: length 92.2
  IN2 w0.089: 94.28,72.48 94.27,72.47 94.25,72.47 94.21,72.43 94.05,72.43 94.03,72.45 90.04,72.45 89.85,72.64 89.85,72.82 v2(89.68,72.99)
  IN2 w0.127: 94.28,72.48 95.81,74.01 95.98,74.01 96.05,74.08 96.12,74.08 100.18,78.14 100.18,83.36 97.87,85.67 97.87,86.49 98.28,86.89 98.28,88.18 97.25,89.21 95.49,89.21 94.58,90.12 94.42,90.28 93.64,90.28 91.94,91.98 91.94,92.42 91.78,92.58 89.47,94.89 83.32,94.89 80.86,97.35 77.37,97.35 76.42,98.29 70.38,98.29 68.73,99.95 68.73,103.2 69.88,104.36 69.88,117.37 71.05,118.54 71.65,118.54 v2(71.73,118.46)
  BOTTOM w0.089: UC1.P31 v2(89.68,72.99)
  BOTTOM w0.114: JWLAN1.15 78.34,125.05 78.15,125.24 77.31,125.24 75.77,123.7 75.77,120.17 74.16,118.56 71.83,118.56 v2(71.73,118.46)
CNVI_WGR_DATA0_DP: length 92.1
  IN2 w0.089: 94.13,72.63 90.12,72.63 90.03,72.72 90.03,72.88 90.15,73.01 v2(90.29,73.01)
  IN2 w0.127: v2(71.73,119.04) 71.39,119.04 71.34,118.99 71.34,118.87 71.28,118.8 70.94,118.8 69.62,117.47 69.62,104.47 68.46,103.31 68.46,99.84 70.28,98.03 76.32,98.03 77.26,97.09 80.75,97.09 83.21,94.63 89.36,94.63 91.67,92.31 91.67,91.87 93.53,90.01 94.32,90.01 95.38,88.95 97.14,88.95 98.02,88.07 98.02,87 97.61,86.6 97.61,85.56 99.92,83.25 99.92,78.25 95.89,74.22 95.73,74.22 94.13,72.63
  BOTTOM w0.089: v2(90.29,73.01) 90.02,72.64 UC1.M31
  BOTTOM w0.114: v2(71.73,119.04) 71.96,118.81 74.06,118.81 75.52,120.27 75.52,123.8 77.21,125.49 78.15,125.49 78.21,125.55 JWLAN1.17
CNVI_WGR_DATA1_DN: length 90.3
  IN2 w0.127: v2(93.25,72.04) 93.34,71.95 93.34,71.72 93.63,71.43 94.36,71.43 94.78,71.84 94.78,72.26 95.63,73.11 95.63,73.13 95.88,73.39 96.32,73.39 100.81,77.88 100.81,83.69 99.04,85.46 99.04,85.93 99.49,86.37 99.49,88.04 99.25,88.28 99.25,88.73 99.6,89.09 99.6,89.39 99.6,89.72 99.27,90.05 99.06,90.05 98.09,90.05 97.79,90.36 97.79,90.9 97.05,91.64 96.95,91.64 96.56,91.64 96.3,91.37 96.3,91.09 96.17,90.96 95.84,90.96 95.71,91.09 95.71,91.35 95.43,91.64 93.64,91.64 89.77,95.51 83.58,95.51 81.04,98.05 77.62,98.05 75.85,99.82 75.85,103.38 74.08,105.15 71.41,105.15 71.28,105.28 71.28,105.93 71.41,106.06 72.52,106.06 72.81,106.34 72.81,106.81 72.52,107.09 71.41,107.09 71.28,107.22 71.28,108.52 70.57,109.22 70.57,116.89 71.03,117.34 71.52,117.34 v2(71.73,117.14)
  BOTTOM w0.114: v2(71.73,117.14) 71.94,117.35 74.43,117.35 76.44,119.36 76.44,122.64 77.45,123.65 78.24,123.65 78.34,123.55 JWLAN1.9 ; UC1.F29 v2(93.25,72.04)
CNVI_WGR_DATA1_DP: length 90.4
  IN2 w0.127: v2(94.05,72.04) 93.99,72.11 93.81,72.11 93.61,71.91 93.61,71.77 93.74,71.64 94.27,71.64 94.56,71.93 94.56,72.35 95.41,73.2 95.41,73.22 95.84,73.65 96.21,73.65 100.54,77.99 100.54,83.58 98.78,85.35 98.78,86.04 99.22,86.48 99.22,87.93 98.98,88.17 98.98,88.84 99.34,89.2 99.34,89.5 99.34,89.61 99.16,89.78 97.98,89.78 97.52,90.25 97.52,90.79 96.94,91.37 96.67,91.37 96.56,91.26 96.56,91.1 96.56,90.98 96.28,90.7 95.73,90.7 95.58,90.85 95.45,90.98 95.45,91.02 95.45,91.24 95.32,91.37 93.53,91.37 89.66,95.25 83.47,95.25 80.93,97.79 77.51,97.79 75.59,99.71 75.59,103.27 73.97,104.89 71.3,104.89 71.02,105.17 71.02,106.04 71.3,106.32 72.41,106.32 72.54,106.45 72.54,106.7 72.41,106.83 71.3,106.83 71.02,107.11 71.02,108.41 70.31,109.11 70.31,117 70.92,117.61 71.61,117.61 v2(71.73,117.72)
  BOTTOM w0.114: JWLAN1.11 78.31,124.05 78.16,123.9 77.35,123.9 76.2,122.75 76.2,119.46 74.33,117.6 71.85,117.6 v2(71.73,117.72) ; UC1.D29 v2(94.05,72.04)
CNVI_WT_CLK_DN: length 99.1
  IN2 w0.089: 94.55,75.13 94.43,75.01 93.81,75.01 93.43,74.63 93.43,74.3 93.79,73.95 v2(93.95,73.95)
  IN2 w0.127: 94.55,75.13 95.28,75.86 95.28,76.65 95.72,77.09 97.31,77.09 98.82,78.6 98.82,81.9 98.08,82.65 98.08,83.11 95.65,85.54 95.65,87.44 95.26,87.83 94.15,87.83 90.7,91.29 90.7,91.91 89.88,92.72 89.06,93.55 80.99,93.55 79.1,95.44 76.92,95.44 76.08,96.27 75.01,96.27 74.38,96.9 69.85,96.9 67.15,99.59 67.15,103.63 68.64,105.12 68.64,112.66 68.64,118.44 69.01,118.81 71.34,121.14 71.34,133.8 73.64,136.09 74.09,136.09 76.87,138.87 76.87,138.87 77.17,139.17 77.31,139.17 v2(77.47,139.01)
  BOTTOM w0.089: UC1.D35 v2(93.95,73.95)
  BOTTOM w0.114: JWLAN1.71 78.34,139.05 78.21,139.18 77.64,139.18 v2(77.47,139.01)
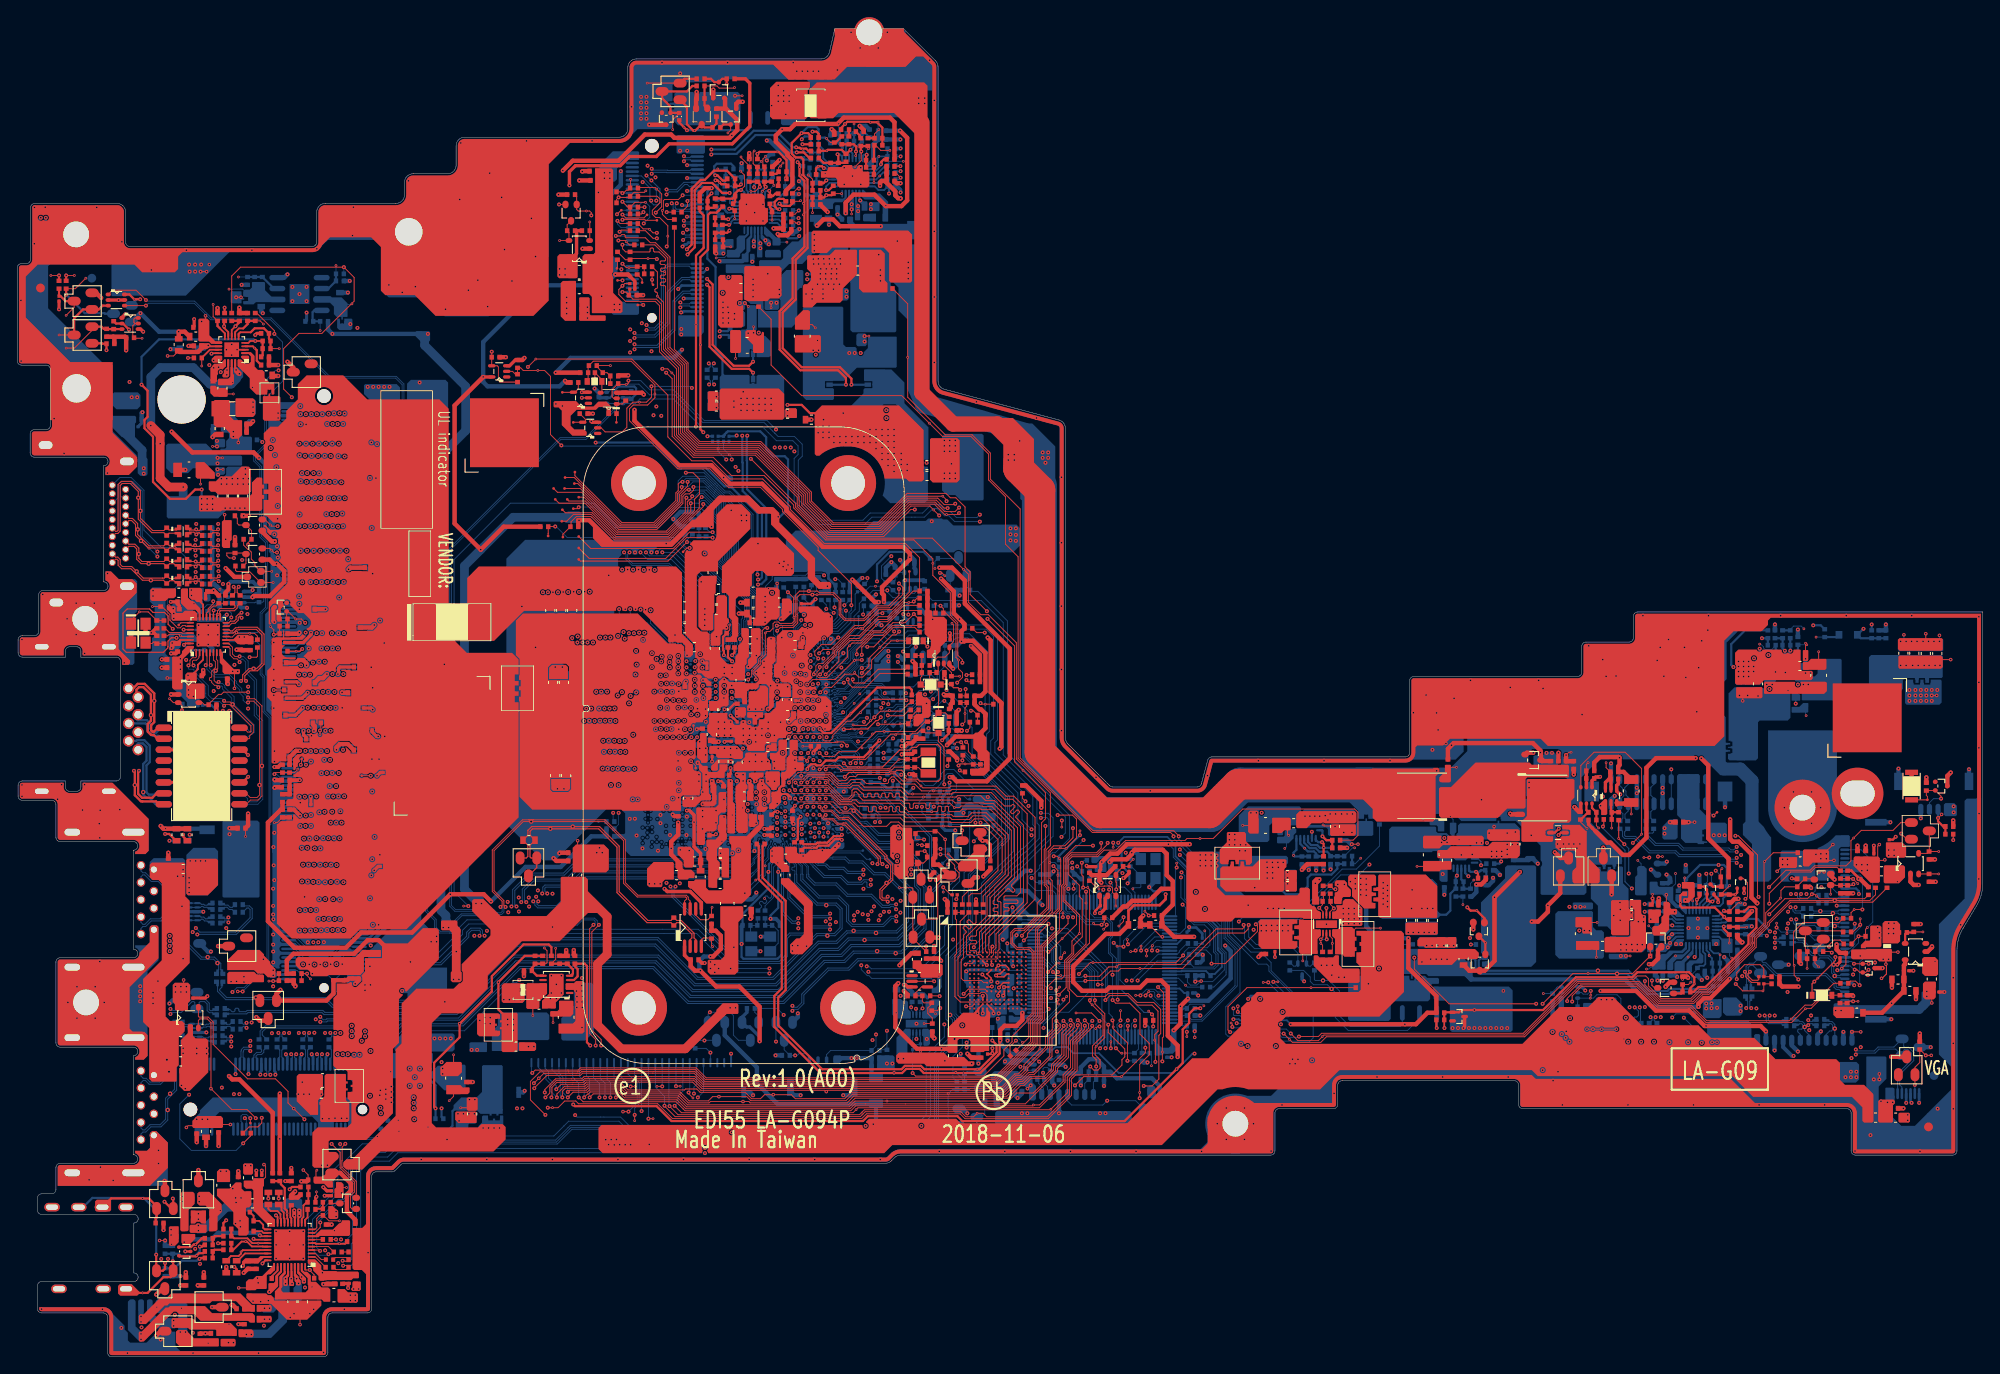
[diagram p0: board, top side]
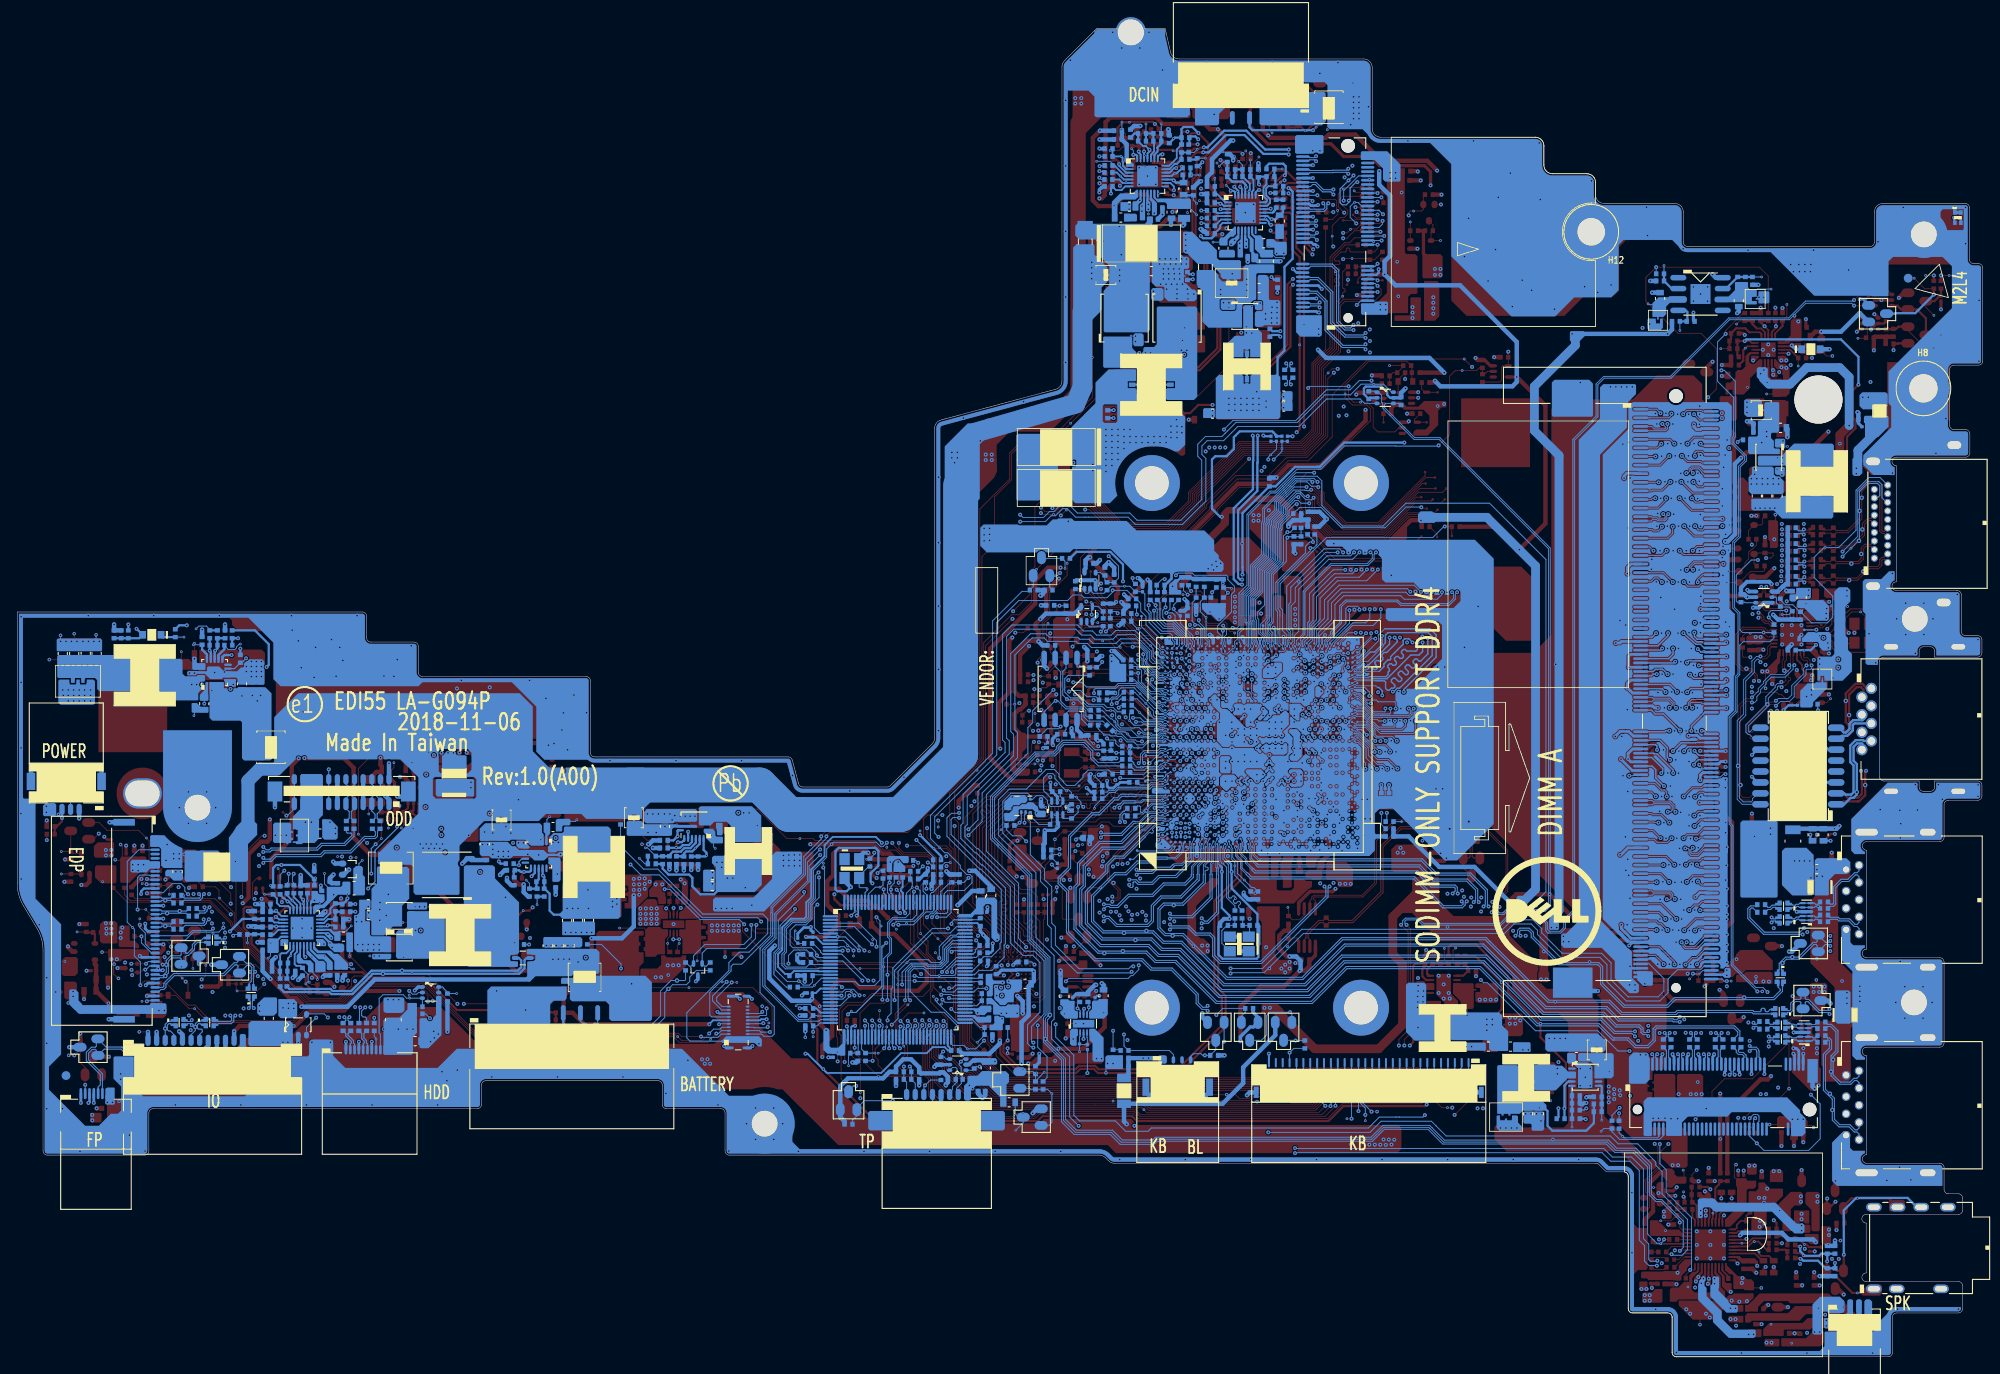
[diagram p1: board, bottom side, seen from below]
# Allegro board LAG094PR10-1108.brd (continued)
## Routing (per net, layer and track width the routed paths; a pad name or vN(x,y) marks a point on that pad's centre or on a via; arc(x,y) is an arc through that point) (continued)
CNVI_WT_CLK_DP: length 99.1
  IN2 w0.089: 94.36,75.32 94.23,75.19 93.73,75.19 93.25,74.71 93.25,73.96 v2(93.24,73.95)
  IN2 w0.127: 94.36,75.32 95.02,75.97 95.02,76.76 95.61,77.35 97.2,77.35 98.56,78.71 98.56,81.79 97.81,82.54 97.81,83 95.39,85.43 95.39,87.33 95.15,87.57 94.04,87.57 92.38,89.23 90.43,91.18 90.43,91.8 89.76,92.47 89.76,92.47 88.95,93.28 80.88,93.28 78.99,95.17 76.81,95.17 75.97,96.01 74.9,96.01 74.28,96.63 69.74,96.63 66.89,99.48 66.89,103.74 68.38,105.23 68.38,112.55 68.38,118.55 68.9,119.07 71.08,121.25 71.08,133.91 73.53,136.36 73.98,136.36 76.6,138.98 76.6,138.98 77.06,139.43 77.31,139.43 v2(77.47,139.59)
  BOTTOM w0.089: v2(93.24,73.95) UC1.F35
  BOTTOM w0.114: v2(77.47,139.59) 77.64,139.42 78.18,139.42 78.31,139.55 JWLAN1.73
CNVI_WT_DATA0_DN: length 100.4
  IN2 w0.089: 94.66,76.87 94.66,76.86 94.65,76.84 94.65,76.76 93.68,75.79 93.68,75.64 93.35,75.32 93.35,75.08 93.18,74.91 93.11,74.91 93,74.8 92.39,74.8 91.99,74.4 91.99,74.28 92.1,74.17 92.3,74.17 v2(92.52,73.95)
  IN2 w0.127: v2(73.73,137.55) 73.56,137.71 73.55,137.71 73.5,137.77 71.89,137.77 68.81,134.69 68.81,119.9 67.92,119 67.92,105.47 66.52,104.07 66.52,99.31 69.69,96.13 74.2,96.13 74.76,95.57 75.61,95.57 78.26,92.93 87.23,92.93 89.33,90.83 90.21,90.83 91.52,89.51 91.52,88.74 94.05,86.21 94.05,85.43 94.18,85.31 94.93,85.31 97.14,83.09 97.14,81.48 97.75,80.88 97.75,79.33 97.94,79.14 97.94,78.66 97,77.72 95.48,77.72 94.66,76.91 94.66,76.87
  BOTTOM w0.089: v2(92.52,73.95) UC1.H35
  BOTTOM w0.114: JWLAN1.65 78.34,137.55 78.21,137.68 75.5,137.68 75.46,137.72 73.9,137.72 v2(73.73,137.55)
CNVI_WT_DATA0_DP: length 100.4
  IN2 w0.089: 94.4,76.87 94.4,76.83 93.52,75.95 93.45,75.88 93.45,75.74 93.13,75.41 93.13,75.17 92.93,74.98 92.32,74.98 91.81,74.47 v2(91.81,73.95)
  IN2 w0.127: 94.4,76.87 94.4,77.02 95.37,77.98 96.89,77.98 97.67,78.77 97.67,79.03 97.48,79.22 97.48,80.77 96.88,81.37 96.88,82.98 94.82,85.04 94.07,85.04 93.79,85.33 93.79,86.11 91.26,88.63 91.26,89.4 90.1,90.56 89.22,90.56 87.12,92.66 78.15,92.66 75.5,95.31 74.65,95.31 74.09,95.87 69.58,95.87 66.25,99.2 66.25,104.18 67.65,105.58 67.65,119.11 68.55,120.01 68.55,134.58 68.55,134.8 71.78,138.03 73.61,138.03 73.61,138.03 73.62,138.03 v2(73.73,138.13)
  BOTTOM w0.089: UC1.J35 v2(91.81,73.95)
  BOTTOM w0.114: JWLAN1.67 78.31,138.05 78.18,137.92 75.6,137.92 75.56,137.96 73.9,137.96 v2(73.73,138.13)
CNVI_WT_DATA1_DN: length 100.9
  IN2 w0.089: 95.04,74.15 95.03,74.14 94.97,74.14 94.22,73.39 93.71,73.39 93.7,73.4 91.79,73.4 91.68,73.29 91.68,73.13 91.82,72.99 v2(91.92,72.99)
  IN2 w0.127: v2(75.45,135.14) 75.21,135.38 74.01,135.38 72.04,133.42 72.04,126.38 72.04,126.38 72.04,126.17 72.04,124.5 72.04,124.5 72.04,120.97 69.26,118.19 69.26,104.72 67.79,103.25 67.79,100.01 70.21,97.59 74.58,97.59 75.28,96.89 76.6,96.89 77.29,96.2 79.22,96.2 81.25,94.17 89.31,94.17 91.32,92.17 91.32,91.59 94.4,88.51 96.94,88.51 97.61,87.84 97.61,87.1 97.11,86.6 97.11,85.35 99.48,82.99 99.48,78.37 96.5,75.4 95.84,75.4 95.8,75.36 95.8,75.36 95.55,75.11 95.55,75.11 95.35,74.91 95.35,74.46 95.04,74.15
  BOTTOM w0.089: UC1.J31 91.62,72.52 91.92,72.82 v2(91.92,72.99)
  BOTTOM w0.114: JWLAN1.59 78.13,136.05 77.87,136.3 77.57,136.3 76.72,135.45 75.77,135.45 v2(75.45,135.14)
CNVI_WT_DATA1_DP: length 100.9
  IN2 w0.089: v2(91.34,72.99) 91.5,73.16 91.5,73.36 91.72,73.58 93.78,73.58 93.79,73.57 94.14,73.57 94.84,74.26 94.84,74.32 94.85,74.34
  IN2 w0.127: v2(75.45,135.72) 75.38,135.64 73.9,135.64 71.78,133.53 71.78,126.49 71.78,126.28 71.78,124.39 71.78,124.39 71.78,121.07 69.15,118.45 69,118.3 69,104.83 67.52,103.36 67.52,99.9 70.1,97.33 74.47,97.33 75.17,96.63 76.49,96.63 77.18,95.93 79.11,95.93 81.14,93.9 89.21,93.9 91.05,92.06 91.05,91.76 91.05,91.48 94.29,88.25 96.83,88.25 97.35,87.73 97.35,87.21 96.85,86.71 96.85,85.24 99.21,82.88 99.21,78.48 96.39,75.66 95.73,75.66 95.69,75.62 95.69,75.62 95.29,75.22 95.29,75.22 95.09,75.02 95.09,74.57 94.85,74.34
  BOTTOM w0.089: v2(91.34,72.99) UC1.L31
  BOTTOM w0.114: v2(75.45,135.72) 75.48,135.69 76.62,135.69 77.47,136.55 JWLAN1.61
CNVI_WT_RCOMP: length 14.4
  TOP w0.254: RC82.1 103.95,77.55 103.69,77.81 99.92,77.81 v1(96.87,74.76) 96.83,74.76 94.6,72.53 93.71,72.53 93.24,72.99 v2(93.24,72.99)
  BOTTOM w0.203: UC1.F33 v2(93.24,72.99)
COMP: length 3.9
  TOP w0.102: PRB30.1 v1(198.94,48.1)
  TOP w0.254: PRB30.1 198.94,49.1 198.31,49.74 v2(198.31,50.02)
  BOTTOM w0.203: v2(198.31,50.02) 198.33,50.02 ; 198.33,50.02 198.31,50.04 PUB01.28 ; 198.33,50.02 198.35,50.04 198.7,50.04 198.78,49.97 PCB12.1
COMP_VCCGI: length 4.4
  BOTTOM w0.102: PRG17.1 v1(95.46,143.37)
  BOTTOM w0.203: PUG1.23 96.26,139.74 95.89,140.11 95.89,140.52 95.94,140.56
  BOTTOM w0.254: 95.94,140.56 95.46,141.04 PCG12.1 PRG17.1
COMP_VNN: length 4.3
  BOTTOM w0.102: PRZ09.1 v1(85.11,139.16)
  BOTTOM w0.203: PUZ1.23 84.9,135.49 84.74,135.64 84.74,136.85 PCZ04.1
  BOTTOM w0.254: PCZ04.1 PRZ09.1
CPVEE: length 5.4
  TOP w0.203: UA1.27 28.2,12.41 28.18,12.39 26.21,12.39 v1(26.01,12.19) 26.01,12 25.73,11.72 24.84,11.72 CA25.1
CS_1.2V: length 3.3
  TOP w0.102: PRM03.1 v1(21.45,115.2)
  TOP w0.203: PRM03.1 21.45,116.15 22.39,117.09 PUM01.13
CSIN_CHG: length 3.7
  BOTTOM w0.203: PCB05.1 192.3,50.88 192.74,50.44 PUB01.14
  BOTTOM w0.254: PCB05.1 191.42,50.9 PCB03.2 191.37,51.75 PRB12.2
CSIP_CHG: length 6
  TOP w0.102: v2(190.03,53.3) v1(190.03,53.78)
  TOP w0.254: v2(190.03,53.3) 190.03,52.73 PCB04.1
  BOTTOM w0.203: PCB03.1 192.01,52.13 192.01,51.61 192.77,50.84 PUB01.15
  BOTTOM w0.254: v2(190.03,53.3) 190.03,53.2 190.2,53.02 190.2,52.97 190.53,52.64 PRB11.2 190.66,52.69 191.02,52.69 191.04,52.71 PCB03.1
CSON: length 4.7
  BOTTOM w0.203: PCB15.2 197.85,46.71 v1(197.88,46.73) 197.68,46.92 197.14,46.92 196.7,47.36 PUB01.1
  BOTTOM w0.254: PRB37.1 197.87,44 PCB16.1 197.87,45.75 PCB15.2
CSON_R: length 31.8
  BOTTOM w0.254: PRB37.2 197.85,42.87 197.39,42.41 192.14,42.41 191.9,42.17 189.44,42.17 187.08,44.53 v4(185.9,44.53) 170.09,44.53 169.45,45.17 169.45,46.11 169.2,46.36 PRB01.3
CSOP: length 4.1
  BOTTOM w0.203: PUB01.2 196.3,47.26 196.6,46.95 v1(196.6,46.67) 196.93,46.34 PCB15.1
  BOTTOM w0.254: PRB36.1 197.01,44.03 PCB17.1 197.01,45.7 PCB15.1
CSOP_R: length 30.2
  BOTTOM w0.254: PRB01.2 170.1,46.36 169.83,46.1 169.83,45.29 170.23,44.89 v4(183.68,44.89) 187.23,44.89 189.59,42.53 191.75,42.53 191.99,42.77 196.77,42.77 PRB36.2
DAT_SMB: length 21.4
  BOTTOM w0.102: PBATT1.6 162.95,39.02 162.72,38.79 162.4,38.79 161.54,37.93 154.67,37.93 153.16,39.44 153.16,42.34 v4(152.73,42.77) 152.23,43.26 150.63,43.26 150.25,43.65 150.25,44.15 149.47,44.93 PR37.1
DBC_EN: length 114.9
  TOP w0.102: v2(203.59,52.68) 203.59,53.88 206.08,56.37 208.43,56.37 208.94,56.88 211.5,56.88 211.86,56.52 R6.2 ; v2(125.57,43.28) v1(126.08,43.28)
  IN1 w0.127: v2(125.57,43.28) 125.87,42.98 131.54,42.98 132.3,43.75 133.38,43.75 133.96,43.18 138.1,43.18 139.43,41.84 141.49,41.84 143.41,39.91 145.13,39.91 145.85,40.64 174.74,40.64 176.08,41.97 178.46,41.97 179.74,40.69 186.6,40.69 188.24,39.05 191.23,39.05 194.47,42.29 198.94,42.29 199.29,42.64 200.48,42.64 202.03,44.19 202.03,49.29 204.12,51.39 204.12,52.15 v2(203.59,52.68)
  BOTTOM w0.102: v2(125.57,43.28) 125.57,44.72 124.53,45.77 122.69,45.77 122.49,45.56 121.18,45.56 120.64,46.11 120.64,47.42 119.64,48.42 UE1.89
DBC_PANEL_EN_R: length 3.3
  TOP w0.102: R6.1 R5.2 213.28,55.61 v2(213.33,55.56) 213.33,55.56 v1(213.88,55.02)
  BOTTOM w0.102: JEDP1.11 213.22,55.45 v2(213.33,55.56)
DBG_PTI_CLK_0: length 40.8
  TOP w0.102: T55.1 63.85,97.15 64.63,97.93 66.73,97.93 69.48,95.18 75.76,95.18 79.26,98.68 79.26,99.68 v2(79.54,99.96)
  BOTTOM w0.089: UC1.AG53 83.73,82.42 83.81,82.53 83.81,82.71 83.73,82.83 83.72,82.84 83.72,83.2 83.6,83.32 83.6,83.6 84.13,84.13 84.13,85.75 84.26,85.87 84.26,86.16
  BOTTOM w0.102: v2(79.54,99.96) 79.84,99.96 81.05,98.75 81.05,97.98 82.04,96.98 82.04,96.47 82.16,96.35 82.16,92.65 83.47,91.35 83.47,87.37 84.26,86.59 84.26,86.16
DBG_PTI_DATA_0: length 40.2
  TOP w0.102: T56.1 62.96,99.25 65.99,99.25 69.64,95.59 75.59,95.59 78.27,98.26 78.27,99.24 v2(78.27,99.24)
  BOTTOM w0.089: UC1.AG54 83.54,83.12 83.42,83.24 83.42,83.7 83.96,84.23 83.96,85.15 83.27,85.83 83.27,86.16
  BOTTOM w0.102: v2(78.27,99.24) 78.27,99.24 78.27,99.25 79.22,99.25 79.52,99.55 79.93,99.55 80.84,98.64 80.84,97.89 81.84,96.9 81.84,96.38 81.96,96.26 81.96,92.57 83.27,91.26 83.27,86.16
DBG_PTI_DATA_1: length 40.5
  TOP w0.102: v2(78.43,100.06) 78.43,100.06 78.43,99.91 78.17,99.65 78.1,99.65 77.93,99.47 77.86,99.41 77.86,99.07 77.93,99.01 77.93,98.21 75.51,95.79 69.73,95.79 66.02,99.5 64.11,99.5 T57.1
  BOTTOM w0.089: UC1.AE54 84.44,83.1 84.58,83.24 84.58,85.49 84.72,85.63 84.72,86.16
  BOTTOM w0.102: v2(78.43,100.06) 78.76,100.06 79.21,100.5 79.22,100.5 79.28,100.57 79.84,100.57 81.45,98.95 81.45,98.15 82.45,97.15 82.45,96.64 82.57,96.51 82.57,92.82 83.88,91.52 83.88,88.96 84.72,88.12 84.72,86.16
DBG_PTI_DATA_2: length 39.6
  TOP w0.102: v2(77.76,99.88) 77.76,99.75 77.63,99.63 77.63,98.2 75.42,95.99 69.81,95.99 65.86,99.94 T58.1
  BOTTOM w0.089: 84.51,86.16 84.51,85.75 84.4,85.63 84.4,83.31 84.26,83.18 84.26,82.85 84.17,82.72 84.17,82.53 84.25,82.42 84.34,82.32 UC1.AE53
  BOTTOM w0.102: 84.51,86.16 84.51,88.03 83.68,88.87 83.68,91.43 82.37,92.74 82.37,96.43 82.25,96.55 82.25,97.07 81.25,98.06 81.25,98.83 79.72,100.36 79.37,100.36 79.3,100.3 79.29,100.3 78.64,99.65 77.99,99.65 v2(77.76,99.88)
DBG_PTI_DATA_3: length 42.8
  TOP w0.102: T59.1 62.77,100.52 65.58,100.52 69.9,96.2 74.32,96.2 77.35,99.23 77.35,100.05 77.63,100.33 78.13,100.33 78.26,100.46 78.28,100.46 78.58,100.77 78.58,101.13 v2(78.58,101.13)
  BOTTOM w0.089: 85.12,86.16 85.12,85.53 84.98,85.39 84.98,83.02 UC1.AD55
  BOTTOM w0.102: 85.12,86.16 85.12,88.29 84.29,89.13 84.29,91.68 82.99,92.98 82.99,96.67 82.86,96.8 82.86,97.32 81.86,98.32 81.86,99.29 80.92,100.23 80.91,100.23 80.01,101.13 v2(78.58,101.13)
DBG_PTI_DATA_4: length 41.4
  TOP w0.102: T60.1 65.42,100.96 69.98,96.4 74.23,96.4 77.15,99.32 77.15,100.16 77.8,100.81 v2(78.05,100.81)
  BOTTOM w0.089: UC1.AD53 84.73,82.56 84.73,82.69 84.62,82.85 84.62,83.03 84.8,83.21 84.8,85.46 84.88,85.54 84.92,85.58 84.92,86.16
  BOTTOM w0.102: v2(78.05,100.81) 78.09,100.77 78.14,100.72 78.75,100.72 78.8,100.77 80.09,100.77 80.83,100.03 80.84,100.03 81.66,99.21 81.66,98.23 82.65,97.24 82.65,96.72 82.79,96.59 82.79,92.89 84.08,91.6 84.08,89.04 84.92,88.2 84.92,86.16
DBG_PTI_DATA_5: length 41.9
  TOP w0.102: T61.1 65.14,101.53 70.07,96.6 74.15,96.6 76.95,99.4 76.95,100.27 77.65,100.97 77.65,100.98 77.89,101.22 77.89,101.72 v2(77.9,101.72)
  BOTTOM w0.089: UC1.AC54 85.34,82.71 85.33,82.72 85.33,82.97 85.33,82.97 85.33,85.24 85.36,85.27 85.49,85.4 85.53,85.44 85.53,86.16
  BOTTOM w0.102: v2(77.9,101.72) 77.89,101.72 78.09,101.93 79.8,101.93 80.49,101.24 80.49,101.23 81.08,100.64 81.09,100.64 82.27,99.46 82.27,98.48 83.26,97.49 83.26,96.97 83.4,96.84 83.4,93.15 84.69,91.85 84.69,89.29 85.53,88.46 85.53,86.16
DBG_PTI_DATA_6: length 43.3
  TOP w0.102: v2(77.22,101.12) 77.22,100.83 76.74,100.36 76.74,99.49 74.06,96.81 70.15,96.81 64.73,102.23 T62.1
  BOTTOM w0.089: UC1.AC53 85.24,82.33 85.15,82.42 85.05,82.56 85.05,82.69 85.15,82.83 85.15,85.31 85.29,85.45 85.33,85.49 85.33,86.16
  BOTTOM w0.102: v2(77.22,101.12) 77.31,101.22 78.01,101.22 78.53,101.73 79.71,101.73 80.29,101.16 80.29,101.15 81,100.43 81.01,100.43 82.06,99.38 82.06,98.4 83.06,97.4 83.06,96.89 83.19,96.75 83.19,93.06 84.49,91.77 84.49,89.21 85.33,88.37 85.33,86.16
DBG_PTI_DATA_7: length 43.3
  TOP w0.102: T63.1 64.8,102.44 70.23,97.01 73.98,97.01 76.54,99.57 76.54,100.44 76.81,100.71 76.81,101.49 77.1,101.73 v2(77.31,101.73)
  BOTTOM w0.089: UC1.AB53 85.79,82.55 85.62,82.72 85.62,82.73 85.51,82.84 85.51,85.17 85.56,85.22 85.73,85.39 85.73,86.16
  BOTTOM w0.102: 85.73,86.16 85.73,88.54 84.9,89.38 84.9,91.94 83.6,93.23 83.6,96.92 83.47,97.06 83.47,98.55 81.18,100.84 81.17,100.84 80.69,101.32 80.69,101.33 79.88,102.13 77.72,102.13 77.31,101.73 v2(77.31,101.73)
DCIN_CHG: length 2.1
  BOTTOM w0.102: v1(192.69,56.19) 192.69,54.99 192.06,54.35 PCB07.2
DDR_M0_ACT#: length 59.8
  IN1 w0.089: v2(75.48,77.31) 76.28,77.91 76.49,78.11 76.49,78.42 77.2,79.29 77.2,81.72 77.1,81.82
  IN1 w0.193: v2(34.79,84.14) 34.79,84.14 35.11,84.47 40.64,89.37 41.07,89.65 41.39,89.78 42.6,89.78 42.74,89.92 58.33,89.92 58.84,90.42 67.71,90.42 70.02,88.11 73.78,88.11 75.93,85.96 75.93,82.99 77.1,81.82
  BOTTOM w0.089: UC1.BF41 v2(75.48,77.31)
  BOTTOM w0.15: JDIMM1.114 32.39,82.43 32.8,82.83 33.33,82.83 v2(34.79,84.14)
DDR_M0_ALERT#: length 3.5
  TOP w0.15: RD37.2 v1(32.42,82.04) 32.86,82.04 v2(33.12,82.3)
  BOTTOM w0.15: v2(33.12,82.3) 32.75,81.93 JDIMM1.116
DDR_M0_BA0: length 59.4
  IN1 w0.089: 70.72,77.73 71,77.73 71.15,77.89 75.05,77.89 v2(75.46,78.29)
  IN1 w0.193: v2(36.01,70.42) 36.36,70.07 38.06,70.07 38.68,70.68 43.02,70.68 44.17,69.53 45.33,69.53 45.71,69.15 46.1,69.15 46.48,69.53 49.47,69.53 49.66,69.33 49.66,68.01 49.86,67.81 50.24,67.81 50.44,68.01 50.44,69.33 50.63,69.53 51.02,69.53 51.21,69.33 51.21,68.01 51.4,67.81 51.79,67.81 51.98,68.01 51.98,69.33 52.17,69.53 52.56,69.53 52.75,69.33 52.75,68.01 52.95,67.81 53.33,67.81 53.52,68.01 53.52,69.33 53.72,69.53 54.83,69.53 55.09,69.27 55.5,69.27 62.54,76.32 68.82,76.32 69.15,76.65 69.15,77.43 69.42,77.7 70.05,77.7 70.08,77.73 70.72,77.73
  BOTTOM w0.089: UC1.BD43 75.81,77.93 v2(75.46,78.29)
  BOTTOM w0.15: v2(36.01,70.42) 35.04,71.39 33.38,71.39 33.34,71.43 JDIMM1.150
DDR_M0_BA1: length 56.2
  IN1 w0.089: v2(75.87,81.35) 76.24,80.97 76.24,79.6 75.52,78.88 75.26,78.88 75,78.61 74.67,78.61 74.24,78.19 71.01,78.19 70.97,78.22 70.72,78.22
  IN1 w0.193: v2(36.42,72.79) 36.42,72.52 36.23,72.33 35.63,72.33 35.44,72.14 35.44,71.71 35.63,71.52 36.44,71.52 37.1,72.18 41.29,72.18 41.75,72.64 43.53,72.64 44,72.18 51.14,72.18 51.33,72.37 51.33,72.45 51.52,72.64 51.91,72.64 52.1,72.45 52.1,72.37 52.3,72.18 52.59,72.18 52.78,72.37 52.78,72.45 52.98,72.64 53.36,72.64 53.56,72.45 53.56,72.37 53.75,72.18 54.14,72.18 54.33,72.37 54.33,72.45 54.52,72.64 54.91,72.64 55.1,72.45 55.1,72.37 55.29,72.18 55.68,72.18 55.87,72.37 55.87,72.45 56.07,72.64 56.75,72.64 62.04,77.93 66,77.93 66.27,78.2 66.78,78.2 67.05,77.93 67.55,77.93 67.82,78.2 68.32,78.2 68.59,77.93 68.95,77.93 69.22,78.2 69.84,78.2 69.87,78.22 70.72,78.22
  BOTTOM w0.089: v2(75.87,81.35) 75.71,81.51 75.35,81.51 75.08,81.78 74.68,81.78 74.41,81.51 74.06,81.51 UC1.BH51
  BOTTOM w0.15: JDIMM1.145 36.94,72.68 36.82,72.79 v2(36.42,72.79)
DDR_M0_BG0: length 55
  IN1 w0.193: v2(69.82,83.81) 69.52,84.11 69.52,84.34 66.46,87.39 65.63,87.39 65.63,87.4 52.32,87.4 52.32,87.39 52.3,87.39 51.08,86.17 51.08,86.15 50.57,85.65 50.55,85.65 50.24,85.34 49.82,85.34 49.71,85.45 49.71,86.03 49.52,86.23 49.13,86.23 48.94,86.03 48.94,85.07 48.81,84.94 48.19,84.94 48.12,85 48.12,86.03 47.93,86.23 47.54,86.23 47.35,86.03 47.35,85 47.28,84.94 46.64,84.94 46.58,85 46.58,86.03 46.39,86.23 46,86.23 45.81,86.03 45.81,85 45.74,84.94 45.1,84.94 45.03,85 45.03,86.03 44.84,86.23 44.45,86.23 44.26,86.03 44.26,85 44.2,84.94 43.56,84.94 43.49,85 43.49,86.03 43.3,86.23 42.91,86.23 42.72,86.03 42.72,85 42.65,84.94 42.07,84.94 41.55,84.41 41.27,84.41 41.15,84.54 40.88,84.54 40.6,84.26 40.6,83.99 40.73,83.86 40.73,83.59 40.35,83.21 39.3,83.21 38.59,82.51 37.41,82.51 v2(37.26,82.36)
  BOTTOM w0.089: 72.07,81.04 72.17,81.04 72.51,80.71 UC1.BL50
  BOTTOM w0.142: 72.07,81.04 71.16,81.95
  BOTTOM w0.15: v2(69.82,83.81) 69.82,82.93 69.82,82.93 69.82,82.78 70.65,81.95 71.16,81.95 ; JDIMM1.115 37.41,82.18 37.26,82.33 v2(37.26,82.36)
DDR_M0_BG1: length 59.3
  IN1 w0.089: 76.23,81.8 76.42,81.61 76.42,79.53 75.6,78.7 75.45,78.7 75.45,78.7 75.34,78.7 74.88,78.25 v2(74.82,78.25)
  IN1 w0.193: 76.23,81.8 75.37,82.66 75.37,85.67 73.42,87.62 69.5,87.62 67.21,89.91 59.4,89.91 58.92,89.42 42.94,89.42 42.67,89.15 41.3,89.15 41.1,88.96 41.1,88.68 41.52,88.27 41.52,88 41.24,87.72 40.97,87.72 40.56,88.14 40.23,88.14 40.04,87.94 40.04,87.67 40.4,87.31 40.4,87.04 40.13,86.76 39.86,86.76 39.49,87.13 39.09,87.13 36.57,84.6 v2(36.57,84.14)
  BOTTOM w0.089: UC1.BF43 75.1,77.97 v2(74.82,78.25)
  BOTTOM w0.15: JDIMM1.113 37.74,82.68 36.57,83.85 v2(36.57,84.14)
DDR_M0_CKE0: length 46.7
  IN1 w0.193: v2(72.87,84.18) 73.6,84.18 73.8,84.38 73.8,85.63 73.49,85.94 72.32,85.94 71.87,86.39 71.32,86.39 71.03,86.1 70.02,86.1 66.71,89.41 59.61,89.41 59.12,88.92 43.15,88.92 39.82,85.59 39.32,85.59 37.96,84.24 v2(37.96,84.14)
  BOTTOM w0.089: v2(72.87,84.18) 73.74,84.18 74.93,82.99 UC1.BF55
  BOTTOM w0.15: JDIMM1.109 38.43,83.68 v2(37.96,84.14)
DDR_M0_CKE1: length 49.4
  IN1 w0.193: v2(71.66,84.13) 71.66,84.77 71.04,85.39 70.02,85.39 66.99,88.43 43.36,88.43 41.78,86.85 40.02,85.09 39.61,85.09 38.03,83.5 34.13,83.5 33.52,84.11 v2(33.52,84.2)
  BOTTOM w0.089: v2(71.66,84.13) 72.03,83.77 73.91,83.77 74.62,83.05 74.62,82.84 74.87,82.6 UC1.BF54
  BOTTOM w0.15: v2(33.52,84.2) 33.52,83.76 33.18,83.43 JDIMM1.110
DDR_M0_CLK0: length 49.1
  IN1 w0.089: 71.52,81.07 72.22,81.07 73.49,79.79 73.94,79.79 74.3,80.16 74.74,80.16 75.26,80.68 75.26,80.81 75.17,80.89 74.9,80.89 v2(74.84,80.84)
  IN1 w0.127: v2(35.65,75.45) 35.88,75.68 35.88,75.91 36.17,76.19 56.6,76.19 61.3,80.89 70.72,80.89 71.34,80.89 71.52,81.07
  BOTTOM w0.089: UC1.BE49 75.17,80.51 v2(74.84,80.83)
  BOTTOM w0.102: JDIMM1.137 38.42,76.68 38.32,76.58 36.41,76.58 35.88,76.05 35.88,75.68 v2(35.65,75.45)
DDR_M0_CLK1: length 51.3
  IN1 w0.089: v2(75.8,80.77) 75.73,80.68 75.73,80.61 74.92,79.8 74.52,79.8 74.47,79.75 74.47,79.75 73.97,79.25 72.97,79.25 72.2,80.02 70.84,80.02 70.82,80.04 70.75,80.04 70.73,80.06 70.72,80.06
  IN1 w0.127: v2(34.46,75.46) 34.24,75.24 34.24,74.93 34.49,74.68 39.5,74.68 39.63,74.8 39.63,75.08 39.91,75.36 40.51,75.36 40.79,75.08 40.79,74.8 40.92,74.68 41.65,74.68 41.78,74.8 41.78,74.92 42.06,75.2 42.66,75.2 42.94,74.92 42.94,74.8 43.07,74.68 43.83,74.68 43.96,74.8 43.96,75.11 44.24,75.4 56.93,75.4 61.28,79.75 63.53,79.75 63.84,80.06 70.72,80.06
  BOTTOM w0.089: UC1.BC49 76.06,80.51 v2(75.8,80.77)
  BOTTOM w0.102: v2(34.46,75.46) 34.21,75.71 34.21,76.04 33.82,76.43 JDIMM1.138
DDR_M0_CLK#0: length 49
  IN1 w0.089: 70.72,80.63 71.39,80.63 71.6,80.84 72.12,80.84 73.4,79.56 74.03,79.56 74.45,79.98 74.85,79.98 75.44,80.57 75.44,80.88 74.9,81.42 v2(74.89,81.42)
  IN1 w0.127: v2(36.39,75.46) 36.15,75.7 36.15,75.8 36.27,75.93 56.71,75.93 61.41,80.63 70.72,80.63
  BOTTOM w0.089: UC1.BE51 75.09,81.22 v2(74.89,81.42)
  BOTTOM w0.102: JDIMM1.139 38.46,76.18 38.27,76.37 36.5,76.37 36.09,75.96 36.09,75.76 v2(36.39,75.46)
DDR_M0_CLK#1: length 51.3
  IN1 w0.089: 70.72,79.8 72.11,79.8 72.88,79.03 74,79.03 74.59,79.62 74.99,79.62 75.61,80.24 75.74,80.24 v2(75.83,80.16)
  IN1 w0.127: v2(33.75,75.46) 33.98,75.24 33.98,74.82 34.38,74.41 39.61,74.41 39.9,74.69 39.9,74.97 40.02,75.1 40.4,75.1 40.53,74.97 40.53,74.69 40.81,74.41 41.76,74.41 42.04,74.69 42.04,74.81 42.17,74.94 42.55,74.94 42.68,74.81 42.68,74.69 42.96,74.41 43.94,74.41 44.22,74.69 44.22,75.01 44.35,75.13 57.04,75.13 61.39,79.49 63.64,79.49 63.95,79.8 70.72,79.8
  BOTTOM w0.089: v2(75.83,80.16) 76.18,79.8 UC1.BC48
  BOTTOM w0.102: v2(33.75,75.46) 34.01,75.72 34.01,75.95 33.89,76.07 32.72,76.07 32.58,75.93 JDIMM1.140
DDR_M0_CS#0: length 52.8
  IN1 w0.193: v2(69.78,76.89) 69.65,76.77 69.65,76.18 69.29,75.82 62.75,75.82 54.14,67.21 49.1,67.21 48.97,67.34 48.97,68.13 48.78,68.32 48.39,68.32 48.2,68.13 48.2,67.34 48.07,67.21 47.56,67.21 47.43,67.34 47.43,68.13 47.24,68.32 46.85,68.32 46.66,68.13 46.66,67.34 46.53,67.21 45.79,67.21 42.81,70.18 39.1,70.18 38.32,69.41 36.36,69.41 v2(36.35,69.4)
  BOTTOM w0.089: 70.34,77.82 70.53,78.01 72.69,78.01 72.92,78.17 73.05,78.17 73.22,78.05 73.61,77.89 UC1.BJ43
  BOTTOM w0.15: JDIMM1.149 37.5,71.68 36.67,70.84 36.67,69.72 v2(36.35,69.4) ; v2(69.78,76.89) 69.78,77.42 70.18,77.82 70.34,77.82
DDR_M0_CS#1: length 49.7
  IN1 w0.193: v2(71.28,76.83) 71.22,76.83 70.65,76.26 70.65,75.22 69.84,74.42 65.69,74.42 64.26,72.98 61.32,72.98 54.04,65.7 53.29,65.7 52.77,66.21 52.35,66.21 51.83,65.7 51.08,65.7 50.89,65.89 50.89,66.02 50.69,66.21 50.23,66.21 50.04,66.02 50.04,65.89 49.85,65.7 49.33,65.7 49.14,65.89 49.14,66.02 48.95,66.21 45.38,66.21 45.07,66.52 44.8,66.52 44.53,66.25 44.18,66.25 43.99,66.44 43.99,66.72 44.25,66.98 44.25,67.34 44.01,67.58 43.69,67.58 43.37,67.26 43.09,67.26 42.9,67.46 42.9,68.35 42.71,68.54 40.32,68.54 39.67,67.89 37.37,67.89 v2(37.36,67.88)
  BOTTOM w0.089: UC1.BK43 72.94,77.83 71.81,77.83 71.28,77.31 v2(71.28,76.83)
  BOTTOM w0.15: JDIMM1.157 38.47,69.68 37.19,68.4 37.19,68.04 v2(37.36,67.88)
DDR_M0_D0: length 65
  IN1 w0.127: v2(36.18,109.66) 36.78,109.06 38.34,109.06 38.52,108.87 38.52,108.58 38.65,108.45 38.91,108.45 39.03,108.58 39.03,108.87 39.16,109 39.39,109 39.52,108.87 39.52,108.58 39.64,108.45 39.9,108.45 40.02,108.58 40.02,108.87 40.15,109 42.6,109 53.82,97.78 53.82,97.54 54.94,96.42 55.18,96.42 55.35,96.26 58.97,96.26 60.23,94.99 60.24,94.99 60.41,94.83 71.13,94.83 v2(72.42,93.53)
  BOTTOM w0.089: 79.6,84.25 79.99,83.85 79.99,82.94 80.19,82.74 80.19,82.52 80.17,82.49 80.17,82.49 80.11,82.4 80.11,82.4 79.95,82.16 79.93,82.15 UC1.AR53
  BOTTOM w0.102: v2(72.42,93.53) 73.24,92.72 76.01,92.72 79.49,89.24 79.49,84.36 79.6,84.25 ; JDIMM1.7 38.72,109.18 36.48,109.18 36.18,109.47 v2(36.18,109.66)
DDR_M0_D1: length 65
  IN1 w0.127: v2(73.06,93.53) 71.47,95.12 71.36,95.12 71.28,95.19 60.56,95.19 58.3,97.45 57.96,97.45 57.84,97.33 57.84,96.96 57.67,96.79 57.1,96.79 56.97,96.92 56.97,97.28 56.85,97.4 56.59,97.4 56.46,97.28 56.46,96.92 56.34,96.79 56.08,96.79 55.96,96.92 55.96,97.28 55.83,97.4 55.58,97.4 55.45,97.28 55.45,96.92 55.32,96.79 55.09,96.79 54.19,97.7 54.19,98.34 43.1,109.43 39.92,109.43 39.86,109.37 39.61,109.37 39.48,109.5 39.48,109.97 39.35,110.09 39.1,110.09 38.97,109.97 38.97,109.5 38.84,109.37 38.59,109.37 38.46,109.5 38.46,109.97 38.34,110.09 37.84,110.09 v2(37.45,109.7)
  BOTTOM w0.089: UC1.AP55 80.17,83.15 80.17,84.59 80.37,84.79
  BOTTOM w0.102: v2(37.45,109.7) 37.93,110.18 JDIMM1.3 ; 80.37,84.79 80.37,87.31 79.89,87.79 79.89,89.42 76.18,93.12 73.47,93.12 v2(73.06,93.53)
DDR_M0_D2: length 66.1
  IN1 w0.127: v2(33.55,109.6) 34.42,110.47 36.23,110.47 36.63,110.87 42.71,110.87 54.88,98.7 58.1,98.7 60.8,95.99 72.5,95.99 v2(74.96,93.53)
  BOTTOM w0.089: UC1.AP53 80.54,82.47 80.54,82.69 80.64,82.83 80.64,83.04 80.62,83.07 80.62,83.24 80.43,83.43 80.43,84.32 80.63,84.53 80.63,84.75
  BOTTOM w0.102: 80.63,84.75 80.63,87.51 80.41,87.73 80.41,89.48 76.36,93.53 v2(74.96,93.53) ; v2(33.55,109.6) 32.88,108.93 JDIMM1.8
DDR_M0_D3: length 66.1
  IN1 w0.127: v2(74.33,93.53) 72.25,95.61 60.66,95.61 57.95,98.33 54.72,98.33 42.57,110.48 36.77,110.48 36.37,110.09 35.31,110.09 v2(34.82,109.6)
  BOTTOM w0.089: 80.88,84.46 80.62,84.19 80.62,83.5 80.83,83.28 UC1.AN54
  BOTTOM w0.102: v2(34.82,109.6) 34.37,110.04 32.68,110.04 32.56,109.93 JDIMM1.4 ; 80.88,84.46 80.88,89.59 76.54,93.94 74.74,93.94 v2(74.33,93.53)
DDR_M0_D4: length 64.6
  IN1 w0.127: v2(74.08,91.5) 74.08,92.01 73.31,92.77 69.69,92.77 69.52,92.94 68.99,92.94 68.86,93.07 68.86,93.37 68.73,93.5 68.48,93.5 68.35,93.37 68.35,93.07 68.22,92.94 67.97,92.94 67.84,93.07 67.84,93.37 67.72,93.5 67.46,93.5 67.33,93.37 67.33,93.07 67.21,92.94 66.95,92.94 66.83,93.07 66.83,93.37 66.7,93.5 66.45,93.5 66.32,93.37 66.32,93.07 66.19,92.94 65.94,92.94 65.81,93.07 65.81,93.37 65.68,93.5 59.77,93.5 58.34,94.93 53.27,94.93 43.02,105.17 43.02,105.72 41.69,107.06 35.21,107.06 v2(34.32,106.17)
  BOTTOM w0.089: 79.04,83.29 79.04,82.99 79.04,82.68 79.04,82.63 UC1.AU54
  BOTTOM w0.102: v2(34.32,106.17) 33.56,106.93 JDIMM1.16 ; v2(74.08,91.5) 75.47,91.5 78.23,88.74 78.23,85.57 78.43,85.36 78.43,83.89 79.04,83.29
DDR_M0_D5: length 65.8
  IN1 w0.127: v2(72.81,91.5) 72.81,91.4 72.09,90.69 69.81,90.69 68.89,91.6 58.35,91.6 56.97,92.98 53.61,92.98 47.5,99.09 45.76,99.09 45.6,98.94 45.42,98.94 45.24,99.12 45.24,99.3 45.4,99.45 45.4,99.63 45.23,99.79 45.05,99.79 44.78,99.52 44.6,99.52 44.42,99.69 44.42,99.87 44.7,100.15 44.7,100.33 44.52,100.51 44.34,100.51 44.06,100.23 43.88,100.23 43.7,100.41 43.7,100.59 43.98,100.87 43.98,101.05 43.8,101.23 43.62,101.23 43.34,100.95 43.16,100.95 42.98,101.13 42.98,101.31 43.26,101.59 43.26,101.77 43.08,101.95 42.9,101.95 42.62,101.67 42.44,101.67 42.26,101.85 42.26,102.03 42.54,102.31 42.54,102.49 39.62,105.4 33.55,105.4 v2(32.79,106.17)
  BOTTOM w0.089: 78.85,83.12 78.85,82.85 78.74,82.69 UC1.AV53
  BOTTOM w0.102: v2(32.79,106.17) 32.55,105.93 JDIMM1.20 ; 78.85,83.12 78.24,83.72 78.24,85.17 77.82,85.59 77.82,88.57 75.35,91.04 73.26,91.04 v2(72.81,91.5)
DDR_M0_D6: length 65.7
  IN1 w0.127: v2(37.36,106.17) 39.57,106.17 40.44,105.3 41.83,105.3 42.1,105.04 42.1,104.83 41.83,104.57 41.83,104.39 42.01,104.21 42.19,104.21 42.46,104.48 42.64,104.48 42.82,104.3 42.82,104.12 42.31,103.61 42.31,103.43 42.49,103.25 42.67,103.25 43.18,103.76 43.36,103.76 43.54,103.58 43.54,103.4 43.03,102.89 43.03,102.71 43.21,102.53 43.39,102.53 43.9,103.04 44.08,103.04 44.26,102.86 44.26,102.68 43.75,102.17 43.75,101.99 43.93,101.81 44.11,101.81 44.62,102.32 44.8,102.32 44.98,102.14 44.98,101.96 44.6,101.58 44.6,101.4 44.78,101.23 44.96,101.23 45.34,101.6 45.52,101.6 45.77,101.34 45.77,101.16 45.43,100.82 45.43,100.64 45.66,100.41 45.84,100.41 46.18,100.76 46.36,100.76 46.52,100.59 46.52,100.42 46.24,100.14 46.24,99.91 46.37,99.78 46.6,99.78 46.88,100.06 47.06,100.06 53.75,93.36 57.11,93.36 58.51,91.97 69.16,91.97 70.06,91.07 71.1,91.07 v2(71.57,91.53)
  BOTTOM w0.089: UC1.AV55 78.57,82.94
  BOTTOM w0.102: JDIMM1.21 37.86,105.68 v2(37.36,106.17) ; v2(71.57,91.53) 72.46,90.64 75.17,90.64 77.42,88.39 77.42,85.68 78.05,85.04 78.05,83.46 78.57,82.94
DDR_M0_D7: length 67
  IN1 w0.127: v2(70.3,91.53) 69.49,92.34 64.7,92.34 64.58,92.46 64.58,92.83 64.45,92.96 64.2,92.96 64.07,92.83 64.07,92.46 63.94,92.34 63.71,92.34 63.62,92.43 63.62,92.84 63.49,92.97 63.24,92.97 63.11,92.84 63.11,92.43 63.02,92.34 62.72,92.34 62.63,92.43 62.63,92.84 62.5,92.97 62.25,92.97 62.12,92.84 62.12,92.43 62.03,92.34 61.71,92.34 61.61,92.43 61.61,92.84 61.49,92.97 61.23,92.97 61.1,92.84 61.1,92.43 61.01,92.34 60.72,92.34 60.62,92.43 60.62,92.84 60.49,92.97 60.24,92.97 60.11,92.84 60.11,92.43 60.02,92.34 58.66,92.34 58.5,92.5 58.5,92.68 58.81,92.99 58.81,93.17 58.63,93.35 58.45,93.35 58.14,93.04 57.96,93.04 57.26,93.73 56.65,93.73 56.52,93.86 56.52,94.15 56.39,94.28 56.17,94.28 56.04,94.15 56.04,93.86 55.91,93.73 55.66,93.73 55.53,93.86 55.53,94.15 55.4,94.28 53.4,94.28 42,105.67 40.59,105.67 39.61,106.65 36.32,106.65 v2(35.84,106.17)
  BOTTOM w0.089: 77.86,83.29 78.3,82.86 78.39,82.71 78.39,82.52 78.32,82.42 UC1.AW53
  BOTTOM w0.102: JDIMM1.17 36.35,106.68 v2(35.84,106.17) ; v2(70.3,91.53) 71.6,90.23 74.99,90.23 77.01,88.21 77.01,85.71 77.86,84.85 77.86,83.29
DDR_M0_D8: length 56.1
  IN2 w0.089: v2(78.79,80.89) 78.79,82.08 76.53,84.35
  IN2 w0.127: 76.53,84.35 76.19,84.35 75.51,85.03 74.62,85.03 74.51,84.93 73.58,84.93 73.36,85.15 62.66,85.15 61.08,83.57 51.6,83.57 40.65,94.53 36.03,94.53 v2(35.22,93.72)
  BOTTOM w0.089: UC1.AU51 v2(78.79,80.89)
  BOTTOM w0.102: v2(35.22,93.72) 34.77,93.28 32.22,93.28 32.07,93.43 JDIMM1.70
DDR_M0_D9: length 57.6
  IN2 w0.089: 75.16,83.77 75.63,83.77 76.18,83.22 76.75,83.22 78.2,81.77 78.2,80.05 v2(78.72,79.54)
  IN2 w0.127: 75.16,83.77 72.55,83.77 72.5,83.71 71.62,83.71 70.53,82.62 61.41,82.62 60.75,81.96 60.45,81.96 60.38,82.02 60.38,82.55 60.25,82.67 60,82.67 59.87,82.55 59.87,82.02 59.8,81.96 59.45,81.96 59.39,82.02 59.39,82.55 59.26,82.67 59.01,82.67 58.88,82.55 58.88,82.02 58.81,81.96 58.46,81.96 58.4,82.02 58.4,82.55 58.27,82.67 58.02,82.67 57.89,82.55 57.89,82.02 57.82,81.96 57.45,81.96 57.38,82.02 57.38,82.55 57.25,82.67 57,82.67 56.87,82.55 56.87,82.02 56.81,81.96 56.43,81.96 56.37,82.02 56.37,82.55 56.24,82.67 55.98,82.67 55.86,82.55 55.86,82.02 55.79,81.96 55.56,81.96 55.44,82.08 55.44,82.23 55.31,82.35 55.05,82.35 54.93,82.23 54.93,82.08 54.8,81.96 52.18,81.96 40.42,93.72 v2(38.27,93.72)
  BOTTOM w0.089: v2(78.72,79.54) 78.98,79.8 UC1.AU48
  BOTTOM w0.102: JDIMM1.67 38.72,94.18 v2(38.27,93.72)
DDR_M0_D10: length 58.2
  IN2 w0.089: 75.16,84.56 75.22,84.56 76.28,83.5 76.44,83.5 76.47,83.47 76.88,83.47 78.39,81.96 78.39,80.51 78.73,80.18 v2(78.73,80.17)
  IN2 w0.127: v2(36.74,93.72) 37.17,94.15 40.51,94.15 51.55,83.1 52.56,83.1 52.68,82.98 52.68,82.69 52.81,82.57 53.07,82.57 53.19,82.69 53.19,82.98 53.32,83.1 53.57,83.1 53.7,82.98 53.7,82.69 53.83,82.57 54.08,82.57 54.21,82.69 54.21,82.98 54.44,83.21 61.4,83.21 62.92,84.73 64.44,84.73 64.66,84.51 64.99,84.51 65.21,84.73 65.44,84.73 65.56,84.6 65.56,84.3 65.69,84.17 65.94,84.17 66.07,84.3 66.07,84.6 66.2,84.73 66.45,84.73 66.58,84.6 66.58,84.3 66.71,84.17 66.96,84.17 67.09,84.3 67.09,84.6 67.21,84.73 67.47,84.73 67.59,84.6 67.59,84.3 67.72,84.17 67.98,84.17 68.1,84.3 68.1,84.6 68.23,84.73 73.21,84.73 73.38,84.56 75.16,84.56
  BOTTOM w0.089: v2(78.73,80.17) 79.07,80.51 UC1.AU49
  BOTTOM w0.102: JDIMM1.71 37.29,93.18 v2(36.74,93.72)
DDR_M0_D11: length 57.4
  IN2 w0.127: v2(77.77,79.44) 77.62,79.44 76.88,78.71 74.32,78.71 74.2,78.6 71.29,78.6 71.15,78.74 58.82,78.74 58.09,78.01 57.84,78.01 57.71,78.14 57.71,78.52 57.59,78.65 57.33,78.65 57.2,78.52 57.2,78.14 57.08,78.01 56.85,78.01 56.18,78.68 55.32,78.68 55.2,78.55 55.2,78.02 55.07,77.9 54.82,77.9 54.69,78.02 54.69,78.52 54.54,78.68 54.31,78.68 54.18,78.55 54.18,78.14 54.05,78.01 53.8,78.01 53.67,78.14 53.67,78.55 53.55,78.68 53.29,78.68 53.17,78.55 53.17,78.14 53.04,78.01 52.78,78.01 52.66,78.14 52.66,78.55 52.53,78.68 52.28,78.68 52.15,78.55 52.15,78.14 52.02,78.01 51.39,78.01 40.57,88.83 37.27,88.83 v2(36.02,90.08)
  BOTTOM w0.089: v2(77.77,79.44) 77.41,79.09 UC1.BA46
  BOTTOM w0.102: v2(36.02,90.08) 37.09,91.15 38.68,91.15 38.7,91.18 JDIMM1.79
DDR_M0_D12: length 58.9
  IN2 w0.127: v2(37.29,90.08) 38.09,89.28 38.58,89.28 38.71,89.4 38.71,90.01 38.84,90.14 39.27,90.14 39.4,90.01 39.4,89.4 39.52,89.28 40.64,89.28 50.88,79.04 51.64,79.04 51.77,79.17 51.77,79.67 51.89,79.8 52.25,79.8 52.38,79.67 52.38,79.17 52.5,79.04 52.76,79.04 52.89,79.17 52.89,79.67 53.01,79.8 53.27,79.8 53.39,79.67 53.39,79.17 53.52,79.04 53.77,79.04 53.9,79.17 53.9,79.67 54.03,79.8 54.33,79.8 54.46,79.67 54.46,79.17 54.59,79.04 54.97,79.04 55.1,79.17 55.1,79.71 55.22,79.84 55.49,79.84 55.61,79.71 55.61,79.17 55.74,79.04 56,79.04 56.12,79.17 56.12,79.71 56.25,79.84 56.5,79.84 56.63,79.71 56.63,79.17 56.76,79.04 57.01,79.04 57.14,79.17 57.14,79.71 57.27,79.84 57.52,79.84 57.65,79.71 57.65,79.17 57.77,79.04 58.03,79.04 58.15,79.17 58.15,79.71 58.28,79.84 58.57,79.84 58.7,79.71 58.7,79.42 58.83,79.29 59.08,79.29 59.21,79.42 59.21,79.56 59.34,79.69 59.52,79.69 59.64,79.56 59.64,79.42 59.77,79.29 60.02,79.29 60.15,79.42 60.15,79.56 60.28,79.69 60.53,79.69 60.66,79.56 60.66,79.42 60.79,79.29 61.04,79.29 61.17,79.42 61.17,79.56 61.29,79.69 71.38,79.69 71.44,79.74 72.94,79.74 72.95,79.74 75.52,79.74 75.82,79.44 v2(76.82,79.44)
  BOTTOM w0.102: JDIMM1.83 38.5,90.18 38.12,90.55 37.77,90.55 v2(37.29,90.08)
  BOTTOM w0.127: v2(76.82,79.44) 77.17,79.8 UC1.BA48
DDR_M0_D13: length 57.1
  IN2 w0.127: v2(76.82,80.15) 76.68,80.15 76.34,80.5 76.34,81.47 75.93,81.88 74.42,81.88 73.45,80.91 71.51,80.91 70.87,80.27 70.21,80.27 70.09,80.4 70.09,80.63 69.96,80.75 69.65,80.75 69.52,80.63 69.52,80.37 69.39,80.25 69.14,80.25 69.01,80.37 69.01,80.63 68.89,80.75 68.55,80.75 68.45,80.65 68.45,80.35 68.32,80.22 68.07,80.22 67.94,80.35 67.94,80.63 67.81,80.75 67.56,80.75 67.43,80.63 67.43,80.35 67.31,80.22 67.05,80.22 66.93,80.35 66.93,80.63 66.8,80.75 66.54,80.75 66.42,80.63 66.42,80.35 66.29,80.22 66.04,80.22 65.91,80.35 65.91,80.63 65.78,80.75 65.55,80.75 65.43,80.63 65.43,80.32 65.3,80.2 65.05,80.2 64.92,80.32 64.92,80.63 64.79,80.75 62.12,80.75 61.58,80.21 50.65,80.21 40.82,90.04 40.03,90.04 39.54,90.53 35.19,90.53 v2(34.74,90.08)
  BOTTOM w0.102: v2(34.74,90.08) 34.26,89.59 33.01,89.59 32.68,89.93 JDIMM1.84
  BOTTOM w0.127: v2(76.82,80.15) 77.17,80.51 UC1.BA49
DDR_M0_D14: length 57.6
  IN2 w0.127: v2(33.13,90.05) 33.13,90.82 33.25,90.95 39.76,90.95 40.16,90.55 41.69,90.55 42.17,90.07 42.17,89.89 41.92,89.64 41.92,89.46 42.1,89.28 42.28,89.28 42.53,89.53 42.71,89.53 42.89,89.35 42.89,89.17 42.64,88.92 42.64,88.74 42.82,88.56 43,88.56 43.25,88.81 43.42,88.81 43.6,88.63 43.6,88.45 43.36,88.2 43.36,88.02 43.54,87.84 43.71,87.84 43.96,88.09 44.14,88.09 44.32,87.91 44.32,87.73 44.07,87.48 44.07,87.3 44.25,87.12 44.43,87.12 44.68,87.37 44.86,87.37 45.02,87.21 45.02,87.03 44.78,86.78 44.78,86.6 44.96,86.42 45.14,86.42 45.38,86.67 45.56,86.67 45.74,86.49 45.74,86.31 45.64,86.21 45.64,86.03 45.82,85.85 46,85.85 46.1,85.95 46.28,85.95 51.29,80.94 51.61,80.63 61.3,80.63 61.96,81.29 72.62,81.29 73.58,82.25 76.11,82.25 76.81,81.55 v2(76.81,81.5)
  BOTTOM w0.089: v2(76.81,81.5) 76.9,81.5 77.18,81.22 UC1.BA51
  BOTTOM w0.102: JDIMM1.80 32.58,90.93 33.13,90.38 v2(33.13,90.05)
DDR_M0_D15: length 55.9
  IN2 w0.089: 76.34,84.64 76.62,84.64 79.36,81.89 v2(79.36,81.69)
  IN2 w0.127: v2(33.69,93.72) 34.89,94.91 40.79,94.91 50.99,84.7 61.69,84.7 62.58,85.59 73.44,85.59 73.74,85.29 74.36,85.29 74.47,85.4 75.29,85.4 75.34,85.35 75.63,85.35 76.34,84.64
  BOTTOM w0.089: v2(79.36,81.69) 79.38,81.69 79.84,81.22 UC1.AR51
  BOTTOM w0.102: v2(33.69,93.72) 33.2,94.21 32.49,94.21 32.27,94.43 JDIMM1.66
DDR_M0_D16: length 58.3
  IN2 w0.127: v2(65.28,88.93) 63.67,90.53 58.2,90.53 57.39,89.72 54.22,89.72 53.65,90.29 53.47,90.29 53.3,90.13 53.12,90.13 52.99,90.25 52.99,90.54 53.11,90.65 53.11,90.83 45.82,98.12 44.67,98.12 43.09,99.7 39.59,99.7 39.01,100.28 35.69,100.28 v2(35.23,99.82)
  BOTTOM w0.089: 77.29,85.06 77.68,84.67 UC1.AY55
  BOTTOM w0.102: JDIMM1.50 33.83,98.43 v2(35.23,99.82) ; 77.29,85.06 76.5,85.85 76.5,88 74.79,89.71 66.06,89.71 v2(65.28,88.93)
DDR_M0_D17: length 58.6
  IN2 w0.127: v2(64.02,88.92) 64.02,89.3 63.15,90.17 58.35,90.17 57.46,89.28 53.37,89.28 51.27,91.38 51.27,91.56 51.27,91.57 51.27,91.75 51.09,91.93 50.91,91.93 50.71,91.73 50.53,91.73 50.35,91.91 50.35,92.09 50.55,92.29 50.55,92.47 50.37,92.65 50.19,92.65 50,92.45 49.82,92.45 49.64,92.63 49.64,92.81 49.83,93.01 49.83,93.19 49.65,93.37 49.47,93.37 49.28,93.17 49.1,93.17 48.92,93.35 48.92,93.53 49.12,93.73 49.12,93.91 48.94,94.09 48.76,94.09 48.56,93.89 48.38,93.89 48.2,94.07 48.2,94.25 48.36,94.41 48.36,94.59 48.18,94.77 48,94.77 47.84,94.61 47.66,94.61 47.48,94.79 47.48,94.97 47.77,95.26 47.77,95.44 47.59,95.62 47.41,95.62 47.12,95.33 46.94,95.33 46.76,95.51 46.76,95.69 46.99,95.92 46.99,96.1 46.81,96.28 46.63,96.28 46.4,96.04 46.22,96.04 46.04,96.23 46.04,96.41 46.3,96.67 46.3,96.85 46.12,97.03 45.94,97.03 45.68,96.77 45.5,96.77 45.32,96.95 45.32,97.13 45.58,97.39 45.58,97.57 45.4,97.75 45.22,97.75 44.96,97.49 44.78,97.49 43,99.27 39.41,99.27 38.85,99.83 v2(38.06,99.83)
  BOTTOM w0.089: 76.61,84.77 77.23,84.15 77.23,83.57 77.23,83.57 UC1.BA54
  BOTTOM w0.102: JDIMM1.45 38.53,99.68 38.38,99.83 v2(38.06,99.83) ; 76.61,84.77 75.69,85.69 75.69,87.64 74.43,88.9 67.03,88.9 66.65,88.51 64.36,88.51 64.02,88.85 v2(64.02,88.92)
DDR_M0_D18: length 59.7
  IN2 w0.127: v2(36.79,99.82) 37.22,99.39 38.67,99.39 39.23,98.84 42.16,98.84 42.91,98.84 52.17,89.58 53.65,88.09 55.29,88.09 55.42,88.22 55.42,88.45 55.54,88.58 55.8,88.58 55.93,88.45 55.93,88.22 56.05,88.09 56.28,88.09 56.41,88.22 56.41,88.77 56.54,88.9 56.79,88.9 56.92,88.77 56.92,88.22 57.04,88.09 57.3,88.09 57.42,88.22 57.42,88.77 57.55,88.9 57.81,88.9 57.93,88.77 57.93,88.22 58.06,88.09 58.31,88.09 58.44,88.22 58.44,88.77 58.57,88.9 58.82,88.9 58.95,88.77 58.95,88.22 59.08,88.09 59.3,88.09 60.68,89.47 62.27,89.47 62.42,89.31 62.43,89.31 62.67,89.07 62.67,89.06 v2(62.84,88.9)
  BOTTOM w0.089: UC1.BA53 77.23,82.14 76.94,82.56 76.94,82.69 77.04,82.83 77.05,82.84 77.05,83.85 76.26,84.63
  BOTTOM w0.102: 76.26,84.63 75.28,85.61 75.28,87.47 74.27,88.49 67.64,88.49 67.23,88.08 63.4,88.08 62.84,88.64 v2(62.84,88.9) ; JDIMM1.49 37.74,98.68 36.79,99.63 v2(36.79,99.82)
DDR_M0_D19: length 59.1
  IN2 w0.127: v2(33.81,99.82) 34.7,100.71 39.19,100.71 39.45,100.45 39.77,100.13 43.18,100.13 44.82,98.49 45.97,98.49 54.26,90.2 55.34,90.2 55.47,90.33 55.47,90.61 55.59,90.74 55.85,90.74 55.98,90.61 55.98,90.33 56.1,90.2 56.33,90.2 56.46,90.33 56.46,90.65 56.59,90.78 56.84,90.78 56.97,90.65 56.97,90.33 57.09,90.2 57.35,90.2 58.11,90.97 64.51,90.97 v2(66.52,88.96)
  BOTTOM w0.089: UC1.AY53 77.68,82.49 77.41,82.84 77.41,83.05 77.41,83.64 77.4,83.65 77.4,84.46 76.95,84.91
  BOTTOM w0.102: v2(66.52,88.96) 66.86,89.3 74.61,89.3 76.09,87.82 76.09,85.77 76.95,84.91 ; JDIMM1.46 32.92,99.43 32.97,99.37 33.37,99.37 v2(33.81,99.82)
DDR_M0_D20: length 58.3
  IN2 w0.127: v2(72.43,86.86) 72.43,86.74 72.18,86.48 69.8,86.48 69.67,86.61 62.45,86.61 61.5,85.66 52.23,85.66 51.89,86 51.89,86.74 51.74,86.89 51.38,86.89 51.13,86.63 50.65,86.63 50.29,86.99 50.29,87.47 50.55,87.73 50.55,88.26 50.39,88.41 50.11,88.41 49.68,87.98 49.35,87.98 49.23,88.11 49.23,88.39 49.53,88.69 49.53,89.22 49.35,89.4 49.07,89.4 48.69,89.02 48.46,89.02 48.29,89.19 48.29,89.38 48.44,89.53 48.44,89.71 48.13,90.01 47.6,90.01 41.68,95.93 36.63,95.93 v2(36.04,96.52)
  BOTTOM w0.089: 74.01,85.26 76.15,83.13 76.15,82.85 76.04,82.69 76.04,82.56 76.12,82.44 76.19,82.29 76.33,82.15 UC1.BC53
  BOTTOM w0.102: v2(72.43,86.86) 72.43,87.06 72.64,87.27 73.73,87.27 74.01,86.99 74.01,85.26 ; v2(36.04,96.52) 36.04,95.74 36.61,95.18 JDIMM1.63
DDR_M0_D21: length 57.1
  IN2 w0.127: v2(73.6,86.8) 72.9,86.1 62.52,86.1 61.57,85.15 51.25,85.15 47.17,89.23 47.17,89.41 47.25,89.5 47.25,89.68 47.07,89.86 46.89,89.86 46.81,89.77 46.63,89.77 46.46,89.94 46.46,90.12 46.62,90.29 46.62,90.47 46.44,90.65 46.26,90.65 46.1,90.48 45.92,90.48 45.74,90.66 45.74,90.84 45.9,91.01 45.9,91.19 45.72,91.37 45.54,91.37 45.38,91.2 45.2,91.2 45.02,91.38 45.02,91.56 45.18,91.73 45.18,91.91 45,92.09 44.82,92.09 44.66,91.92 44.48,91.92 44.3,92.1 44.3,92.28 44.47,92.45 44.47,92.63 44.29,92.8 44.11,92.8 43.94,92.64 43.76,92.64 43.58,92.82 43.58,93 43.75,93.16 43.75,93.34 43.57,93.52 43.39,93.52 43.22,93.36 43.04,93.36 42.86,93.54 42.86,93.72 43.03,93.88 43.03,94.06 42.85,94.24 42.67,94.24 42.5,94.08 42.32,94.08 40.9,95.5 34.5,95.5 v2(33.42,96.57)
  BOTTOM w0.089: UC1.BD55 75.87,83.02 74.18,84.71
  BOTTOM w0.102: v2(33.42,96.57) 33.12,96.27 33.12,96.24 33.02,96.14 32.56,96.14 32.27,96.43 JDIMM1.58 ; 74.18,84.71 73.6,85.29 v2(73.6,86.8)
DDR_M0_D22: length 58.2
  IN2 w0.127: v2(37.29,96.52) 37.29,96.59 37.69,96.99 42.35,96.99 42.79,96.55 42.79,96.37 42.4,95.98 42.4,95.8 42.58,95.62 42.76,95.62 43.15,96.01 43.33,96.01 43.51,95.83 43.51,95.65 43.12,95.26 43.12,95.08 43.3,94.9 43.48,94.9 43.87,95.29 44.05,95.29 44.23,95.11 44.23,94.93 43.84,94.54 43.84,94.36 44.02,94.18 44.2,94.18 44.59,94.57 44.77,94.57 44.95,94.39 44.95,94.21 44.56,93.82 44.56,93.64 44.74,93.46 44.92,93.46 45.31,93.85 45.49,93.85 45.75,93.59 45.75,93.41 45.33,92.99 45.33,92.81 45.51,92.63 45.69,92.63 46.11,93.05 46.29,93.05 46.47,92.87 46.47,92.69 46.05,92.27 46.05,92.09 46.22,91.91 46.4,91.91 46.83,92.33 47.01,92.33 47.17,92.17 47.17,91.99 46.81,91.63 46.81,91.45 46.99,91.27 47.17,91.27 47.53,91.63 47.71,91.63 47.87,91.47 47.87,91.29 47.84,91.25 47.84,91.07 48.02,90.89 48.19,90.89 48.23,90.93 48.41,90.93 53.24,86.1 61.38,86.1 62.25,86.98 69.9,86.98 v2(69.95,86.93)
  BOTTOM w0.089: 73.94,84.32 73.96,84.32 75.29,83 75.29,82.76 UC1.BE54
  BOTTOM w0.102: v2(69.95,86.93) 69.95,85.91 70.84,85.02 73.24,85.02 73.94,84.32 ; JDIMM1.59 38.42,96.18 38.27,96.02 37.73,96.02 37.29,96.46 v2(37.29,96.52)
DDR_M0_D23: length 58.8
  IN2 w0.127: v2(34.69,96.57) 34.69,96.84 35.21,97.36 42.5,97.36 53.39,86.47 60.92,86.47 61.79,87.35 62.51,87.35 62.64,87.47 62.64,88.07 62.76,88.2 63.02,88.2 63.14,88.07 63.14,87.47 63.27,87.35 63.53,87.35 63.65,87.47 63.65,88.07 63.78,88.2 64.03,88.2 64.16,88.07 64.16,87.47 64.29,87.35 64.54,87.35 64.67,87.47 64.67,88.07 64.8,88.2 65.05,88.2 65.18,88.07 65.18,87.47 65.3,87.35 65.56,87.35 65.68,87.47 65.68,88.07 65.81,88.2 66.07,88.2 66.19,88.07 66.19,87.47 66.32,87.35 71.12,87.35 71.23,87.23 v2(71.23,86.93)
  BOTTOM w0.089: UC1.BD53 75.71,82.69 75.67,82.75 75.63,82.81 75.59,82.9 75.59,82.96 73.98,84.58 73.96,84.58
  BOTTOM w0.102: 73.96,84.58 73.2,85.34 71.73,85.34 71.23,85.83 v2(71.23,86.93) ; JDIMM1.62 33.54,95.43 v2(34.69,96.57)
DDR_M0_D24: length 70
  IN2 w0.089: 78.72,85.05 78.72,84.72 81.14,82.3 81.14,79.24 80.78,78.89 80.78,78.4 v2(81.16,78.02)
  IN2 w0.127: v2(34.97,104.75) 35.48,104.24 46.66,104.24 48.43,102.48 48.61,102.48 48.8,102.67 48.98,102.67 49.16,102.49 49.16,102.31 48.97,102.12 48.97,101.94 49.15,101.76 49.33,101.76 49.52,101.95 49.7,101.95 49.88,101.77 49.88,101.59 49.69,101.4 49.69,101.22 49.87,101.04 50.05,101.04 50.24,101.23 50.42,101.23 50.6,101.05 50.6,100.87 50.41,100.68 50.41,100.5 50.59,100.32 50.77,100.32 50.96,100.51 51.14,100.51 51.31,100.33 51.31,100.15 51.12,99.96 51.12,99.78 51.3,99.6 51.48,99.6 51.67,99.79 51.85,99.79 52.03,99.61 52.03,99.43 51.84,99.24 51.84,99.06 52.02,98.88 52.2,98.88 52.39,99.07 52.57,99.07 52.75,98.89 52.75,98.71 52.56,98.52 52.56,98.34 52.74,98.16 52.92,98.16 53.11,98.35 53.29,98.35 55.52,96.12 63.66,96.12 69.21,90.57 74.6,90.57 78.72,86.44 78.72,85.05
  BOTTOM w0.089: v2(81.16,78.02) 80.81,77.67 UC1.AN43
  BOTTOM w0.102: v2(34.97,104.75) 34.31,104.09 34.07,104.09 32.74,104.09 32.58,103.93 JDIMM1.28
DDR_M0_D25: length 70.9
  IN2 w0.089: 78.94,85.81 78.94,84.81 81.34,82.41 81.34,79.17 81.16,79 v2(81.16,78.73)
  IN2 w0.127: 78.94,85.81 78.94,86.74 74.75,90.93 69.37,90.93 62.97,97.33 57.25,97.33 57.12,97.2 57.12,96.62 56.99,96.49 55.68,96.49 54.06,98.1 54.06,98.28 54.24,98.46 54.24,98.64 54.06,98.82 53.88,98.82 53.7,98.64 53.52,98.64 53.36,98.8 53.36,98.98 53.69,99.32 53.69,99.5 53.51,99.68 53.34,99.68 53,99.34 52.82,99.34 52.64,99.52 52.64,99.7 52.98,100.04 52.98,100.22 52.8,100.4 52.62,100.4 52.28,100.06 52.1,100.06 51.94,100.22 51.94,100.4 52.33,100.79 52.33,100.97 52.15,101.15 51.97,101.15 51.58,100.76 51.4,100.76 51.22,100.94 51.22,101.12 51.61,101.51 51.61,101.69 51.43,101.87 51.25,101.87 50.86,101.48 50.68,101.48 50.5,101.66 50.5,101.84 50.89,102.23 50.89,102.41 50.71,102.59 50.53,102.59 50.14,102.2 49.96,102.2 49.79,102.38 49.79,102.56 50.1,102.87 50.1,103.05 49.92,103.23 49.74,103.23 49.43,102.92 49.25,102.92 49.07,103.1 49.07,103.28 49.38,103.59 49.38,103.77 49.2,103.95 49.02,103.95 48.71,103.64 48.53,103.64 48.35,103.81 48.35,103.99 48.66,104.31 48.66,104.49 48.48,104.67 48.3,104.67 47.99,104.35 47.81,104.35 47.49,104.68 v2(38.04,104.68)
  BOTTOM w0.089: UC1.AN44 80.81,78.38 v2(81.16,78.73)
  BOTTOM w0.102: JDIMM1.25 v2(38.04,104.68)
DDR_M0_D26: length 70.6
  IN2 w0.089: v2(79.62,80.12) 79.99,80.49 79.99,81.62 76.4,85.21 76.23,85.21
  IN2 w0.102: 75.59,85.86 76.23,85.21
  IN2 w0.127: 75.59,85.86 74.97,86.48 74.79,86.48 74.14,85.83 73.96,85.83 73.81,85.98 73.81,86.16 74.46,86.81 74.46,86.99 73.57,87.88 73.23,87.88 73.11,87.75 73.11,87.52 72.98,87.4 72.72,87.4 72.6,87.52 72.6,87.75 72.47,87.88 72.24,87.88 72.04,87.67 71.73,87.67 71.53,87.88 68.45,87.88 67.92,88.41 67.74,88.41 67.23,87.9 67.05,87.9 66.85,88.1 66.85,88.28 67.37,88.79 67.37,88.97 64.83,91.5 63.74,91.5 63.61,91.63 63.61,92.26 63.49,92.39 63.23,92.39 63.11,92.26 63.11,91.63 62.98,91.5 62.72,91.5 62.6,91.63 62.6,92.26 62.47,92.39 62.22,92.39 62.09,92.26 62.09,91.63 61.96,91.5 61.72,91.5 61.59,91.63 61.59,92.26 61.47,92.39 61.21,92.39 61.09,92.26 61.09,91.63 60.96,91.5 60.7,91.5 60.58,91.63 60.58,91.88 60.45,92.01 60.2,92.01 60.07,91.88 60.07,91.63 59.94,91.5 58.26,91.5 57.65,92.11 57.34,92.42 52.79,92.42 45.47,99.74 45.29,99.74 44.99,99.43 44.81,99.43 44.63,99.61 44.63,99.79 44.93,100.1 44.93,100.28 44.55,100.67 39.99,100.67 39.41,101.24 35.16,101.24 35.03,101.37 v2(35.03,101.73)
  BOTTOM w0.089: v2(79.62,80.12) 79.76,80.12 UC1.AR48
  BOTTOM w0.102: v2(35.03,101.73) 33.72,100.43 JDIMM1.42
DDR_M0_D27: length 69.9
  IN2 w0.089: 77.89,84.64 80.55,81.97 80.55,79.87 79.87,79.19 79.57,79.19 79.31,78.93 79.31,78.27 79.23,78.18 79.23,77.81 v2(78.73,77.31)
  IN2 w0.102: 77.71,85.5 77.89,85.32 77.89,84.64
  IN2 w0.127: v2(33.63,101.73) 34.05,102.15 35.13,102.15 35.84,102.86 46.07,102.86 46.37,102.56 46.37,102.38 46.28,102.29 46.28,102.08 46.41,101.95 46.59,101.95 46.66,102.02 46.91,102.02 47.09,101.85 47.09,101.67 46.75,101.34 46.75,101.16 46.93,100.98 47.11,100.98 47.45,101.31 47.63,101.31 47.8,101.13 47.8,100.95 47.47,100.62 47.47,100.44 47.65,100.26 47.83,100.26 48.16,100.59 48.34,100.59 48.53,100.41 48.53,100.23 48.19,99.88 48.19,99.7 48.37,99.52 48.54,99.52 48.89,99.87 49.07,99.87 51.31,97.63 51.31,96.62 51.78,96.15 52.31,96.15 52.88,95.57 52.88,95.09 53.19,94.79 63.11,94.79 68.66,89.24 73.97,89.24 77.71,85.5
  BOTTOM w0.089: v2(78.73,77.31) 79.08,76.95 UC1.AU41
  BOTTOM w0.102: v2(33.63,101.73) 33.05,101.15 32.55,101.15 32.27,101.43 JDIMM1.38
DDR_M0_D28: length 72
  IN2 w0.089: 77.63,84.59 80.35,81.87 80.35,79.97 79.83,79.44 79.55,79.44 79.1,79 79.1,78.4 v2(78.73,78.02)
  IN2 w0.102: 77.63,84.59 77.63,85.06 77.42,85.27
  IN2 w0.127: 77.42,85.27 73.82,88.87 68.51,88.87 63.36,94.01 62.29,94.01 62.17,94.14 62.17,94.29 62.04,94.42 61.79,94.42 61.66,94.29 61.66,94.14 61.53,94.01 61.28,94.01 61.15,94.14 61.15,94.29 61.02,94.42 60.77,94.42 60.64,94.29 60.64,94.14 60.52,94.01 60.29,94.01 60.16,94.14 60.16,94.29 60.03,94.42 59.78,94.42 59.65,94.29 59.65,94.14 59.53,94.01 59.27,94.01 59.14,94.14 59.14,94.29 59.02,94.42 58.76,94.42 58.64,94.29 58.64,94.14 58.42,93.92 58.05,93.92 57.92,94.05 57.92,94.29 57.79,94.42 57.49,94.42 57.36,94.29 57.36,94.06 57.23,93.94 56.95,93.94 56.83,94.06 56.83,94.29 56.7,94.42 56.47,94.42 56.34,94.29 56.34,93.92 56.22,93.8 55.96,93.8 55.83,93.92 55.83,94.29 55.71,94.42 52.94,94.42 52.48,94.89 52.48,95.45 52.25,95.68 51.69,95.68 50.94,96.43 50.94,97.44 50.8,97.58 50.5,97.58 50.24,97.33 50.06,97.33 49.84,97.55 49.84,97.73 50.06,97.96 50.06,98.32 49.87,98.51 48.86,98.51 45.57,101.8 45.31,101.8 45.05,101.53 44.76,101.53 44.63,101.66 44.63,102.34 44.51,102.47 44.25,102.47 44.13,102.34 44.13,101.66 44,101.53 43.47,101.53 43.34,101.66 43.34,102.37 43.21,102.5 42.96,102.5 42.83,102.37 42.83,101.66 42.7,101.53 40.35,101.53 40.06,101.82 40.06,102.23 39.93,102.36 36.43,102.36 36.3,102.23 v2(36.3,101.73)
  BOTTOM w0.089: UC1.AU43 79.08,77.67 v2(78.73,78.02)
  BOTTOM w0.102: v2(36.3,101.73) 37.26,100.77 38.38,100.77 38.47,100.68 JDIMM1.41
DDR_M0_D29: length 69.4
  IN2 w0.089: v2(81.16,77.31) 81.55,77.7 81.55,82.55 79.16,84.95
  IN2 w0.127: 79.16,84.95 79.16,87.05 74.07,92.13 68.69,92.13 63.06,97.76 57.21,97.76 55.5,99.47 55.32,99.47 55.15,99.3 54.97,99.3 54.79,99.48 54.79,99.66 54.96,99.83 54.96,100.01 54.8,100.17 54.58,100.17 54.2,99.79 54.02,99.79 53.84,99.97 53.84,100.15 54.2,100.51 54.2,100.69 54.02,100.87 53.84,100.87 53.6,100.63 53.42,100.63 51.87,102.18 51.87,102.35 52.06,102.54 52.06,102.71 51.87,102.89 51.7,102.89 51.4,102.6 51.22,102.6 51.04,102.78 51.04,102.96 51.27,103.19 51.27,103.37 51.09,103.55 50.91,103.55 50.68,103.32 50.5,103.32 48.67,105.15 36.85,105.15 v2(36.43,104.74)
  BOTTOM w0.089: UC1.AN41 80.81,76.95 v2(81.16,77.31)
  BOTTOM w0.102: JDIMM1.29 37.49,103.68 v2(36.43,104.74)
DDR_M0_D30: length 68.8
  IN2 w0.089: 79.42,85.02 81.73,82.7 81.73,77.17 v2(81.16,76.6)
  IN2 w0.127: v2(33.45,104.75) 33.45,104.84 34.14,105.53 49.96,105.53 57.33,98.17 63.18,98.17 68.73,92.62 74.11,92.62 79.42,87.31 79.42,85.02
  BOTTOM w0.089: UC1.AN39 80.81,76.24 v2(81.16,76.6)
  BOTTOM w0.102: JDIMM1.24 32.27,104.93 32.63,105.28 33.3,105.28 33.45,105.13 v2(33.45,104.75)
DDR_M0_D31: length 71.1
  IN2 w0.089: 77.25,84.92 77.31,84.85 77.31,84.6 80.17,81.75 80.17,80.1 79.77,79.7 79.53,79.7 78.85,79.03 78.85,78.86 v2(78.73,78.73)
  IN2 w0.127: 77.25,84.92 73.73,88.44 68.41,88.44 63.86,93 63.25,93 63.12,93.12 63.12,93.53 63.01,93.65 62.73,93.65 62.61,93.53 62.61,93.12 62.49,93 62.23,93 62.11,93.12 62.11,93.53 61.99,93.65 61.71,93.65 61.6,93.53 61.6,93.12 61.47,93 61.22,93 61.09,93.12 61.09,93.53 60.98,93.65 60.7,93.65 60.58,93.53 60.58,93.12 60.45,93 60.2,93 60.07,93.12 60.07,93.53 59.96,93.65 59.68,93.65 59.57,93.53 59.57,93.12 59.44,93 59.21,93 59.08,93.12 59.08,93.43 58.96,93.56 58.7,93.56 58.58,93.43 58.58,93.12 58.45,93 58.19,93 58.07,93.12 58.07,93.43 57.94,93.56 57.69,93.56 57.56,93.43 57.56,93.12 57.43,93 57.2,93 57.08,93.12 57.08,93.33 56.95,93.46 56.7,93.46 56.57,93.33 56.57,93.12 56.44,93 56.21,93 56.09,93.12 56.09,93.21 55.96,93.34 55.7,93.34 55.58,93.21 55.58,93.12 55.45,93 52.74,93 52.58,93.16 52.58,93.34 52.89,93.65 52.89,93.83 52.71,94.01 52.53,94.01 52.22,93.7 52.04,93.7 51.86,93.88 51.86,94.06 52.17,94.37 52.17,94.55 51.99,94.73 51.81,94.73 51.5,94.42 51.32,94.42 51.14,94.6 51.14,94.78 51.45,95.09 51.45,95.27 51.27,95.45 51.09,95.45 50.78,95.14 50.6,95.14 50.42,95.32 50.42,95.49 50.73,95.8 50.73,95.98 50.55,96.16 50.37,96.16 50.06,95.85 49.88,95.85 49.7,96.03 49.7,96.21 50.01,96.52 50.01,96.7 49.83,96.88 49.65,96.88 49.34,96.57 49.16,96.57 48.98,96.75 48.98,96.93 49.29,97.24 49.29,97.42 49.11,97.6 48.93,97.6 48.62,97.29 48.44,97.29 48.28,97.45 48.28,97.63 48.37,97.72 48.37,97.9 48.19,98.08 48.01,98.08 47.92,97.99 47.74,97.99 44.64,101.1 40.17,101.1 39.59,101.68 v2(37.66,101.68)
  BOTTOM w0.089: v2(78.73,78.73) 79.08,78.38 UC1.AU44
  BOTTOM w0.102: v2(37.66,101.68) JDIMM1.37
DDR_M0_D32: length 58.4
  IN2 w0.127: v2(76.81,73.95) 76.81,73.93 76.28,73.4 73.95,73.4 73.76,73.21 73.76,69.79 71.78,67.81 67.6,67.81 67.47,67.94 67.47,68.26 67.35,68.38 67.09,68.38 66.97,68.26 66.97,67.94 66.84,67.81 60.73,67.81 57.56,64.64 55.33,64.64 42.23,51.54 34.95,51.54 34.6,51.18 33.58,51.18 v2(32.84,51.93)
  BOTTOM w0.089: v2(76.81,73.95) 76.84,73.95 UC1.BA35
  BOTTOM w0.102: JDIMM1.228 v2(32.84,51.93)
DDR_M0_D33: length 58.3
  IN2 w0.127: v2(35.61,50.92) 36.44,50.1 38.63,50.1 39.34,50.8 43.4,50.8 53.24,60.64 53.56,60.64 56.8,63.88 58.52,63.88 61.69,67.05 72.06,67.05 74.96,69.96 74.96,70.25 76.58,71.87 76.58,72.27 76.78,72.47 77.8,72.47 78.2,72.87 v2(78.2,72.96)
  BOTTOM w0.089: v2(78.2,72.96) 78.2,73.07 77.95,73.32 UC1.AY33
  BOTTOM w0.102: JDIMM1.225 37.37,52.68 v2(35.61,50.92)
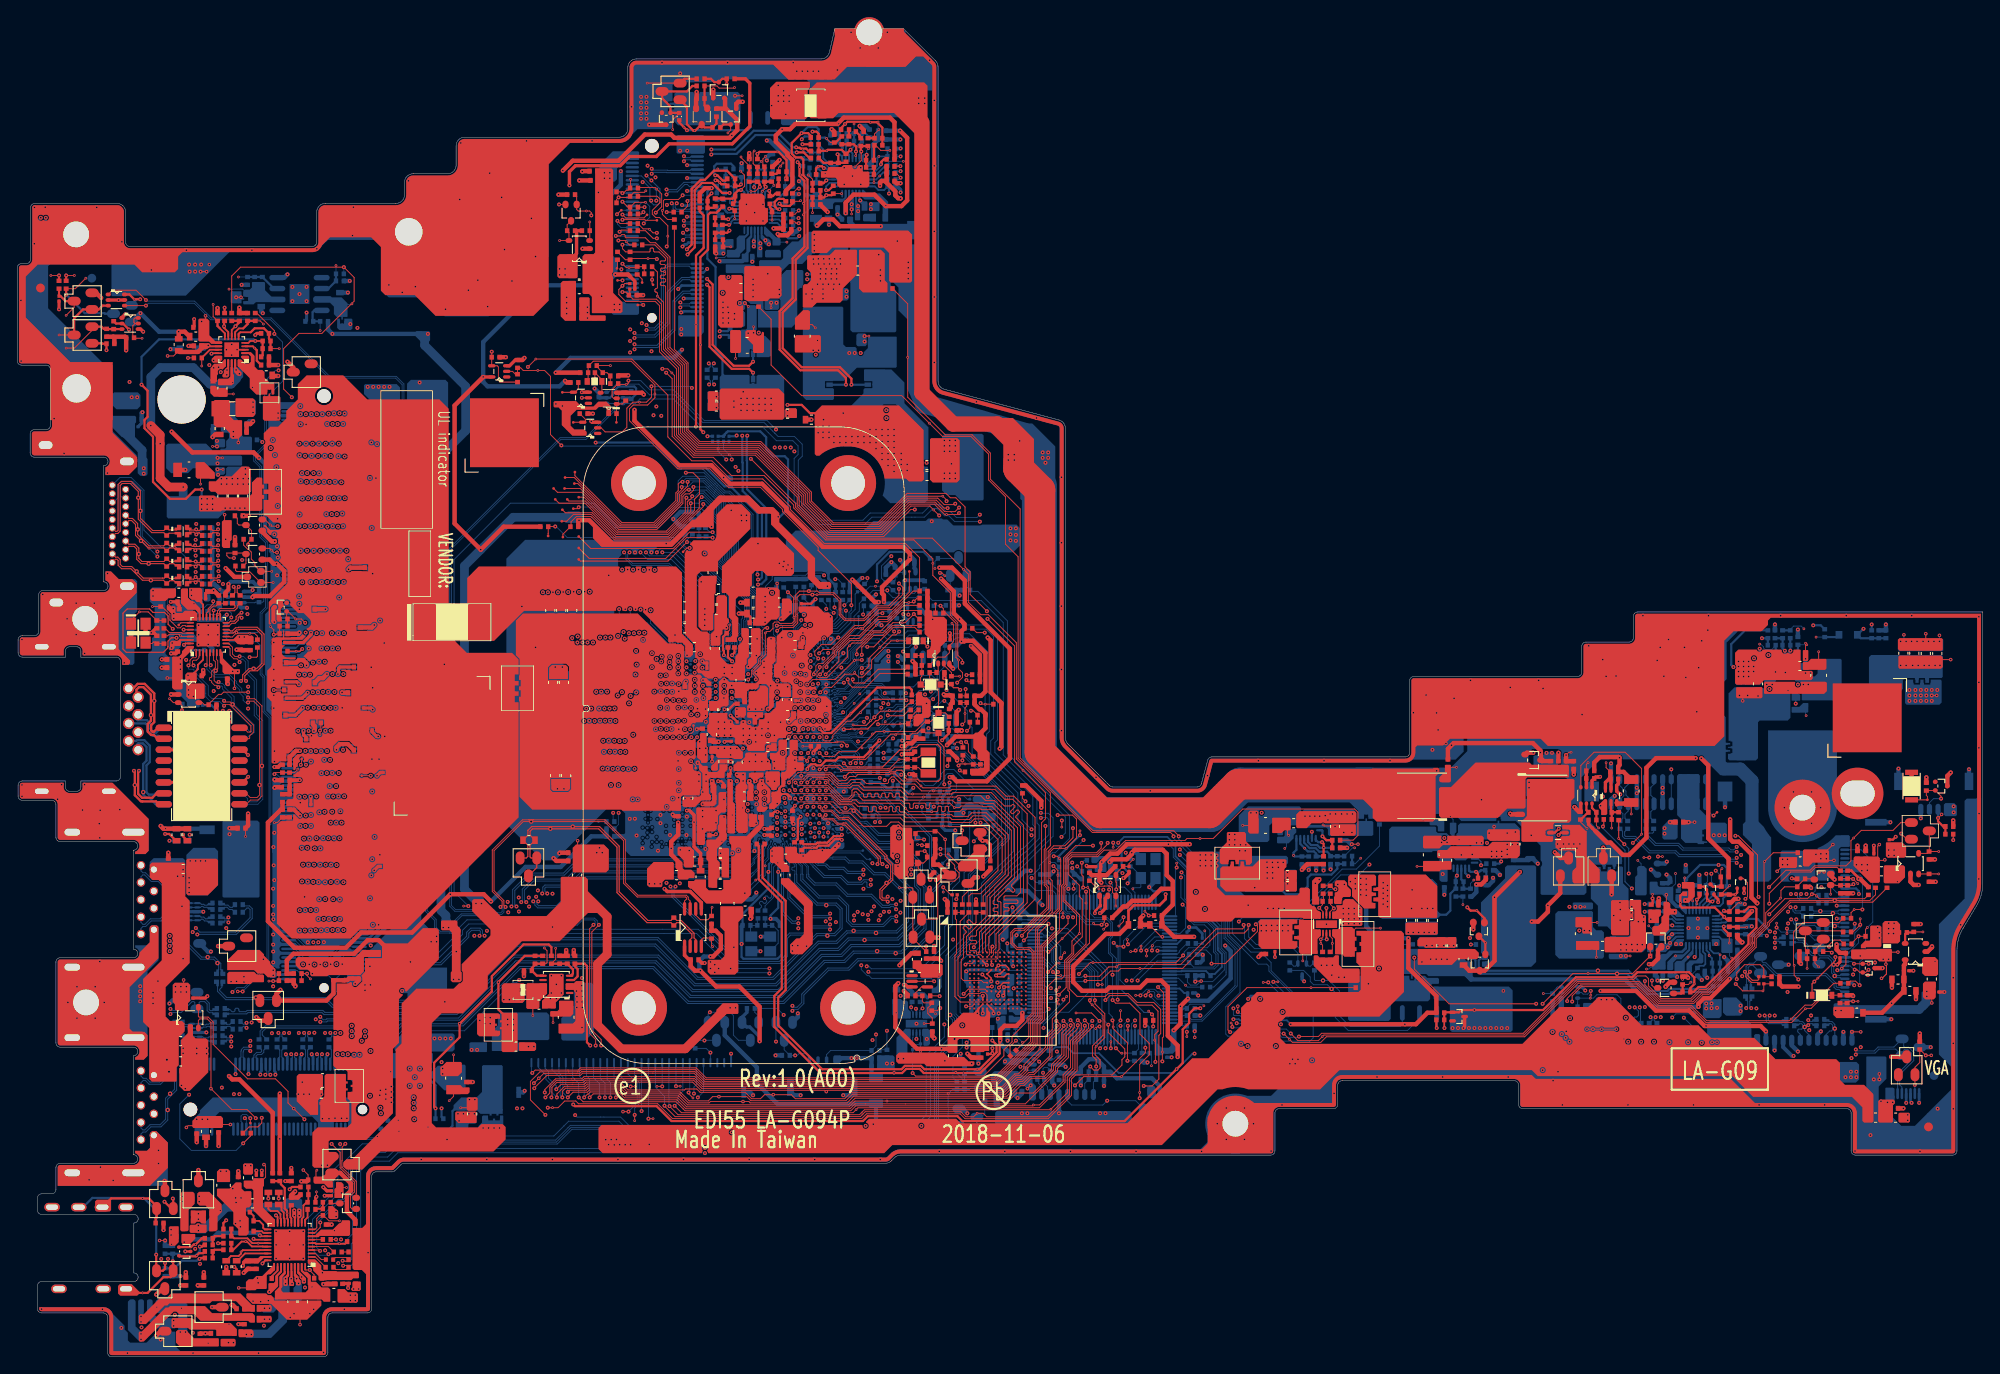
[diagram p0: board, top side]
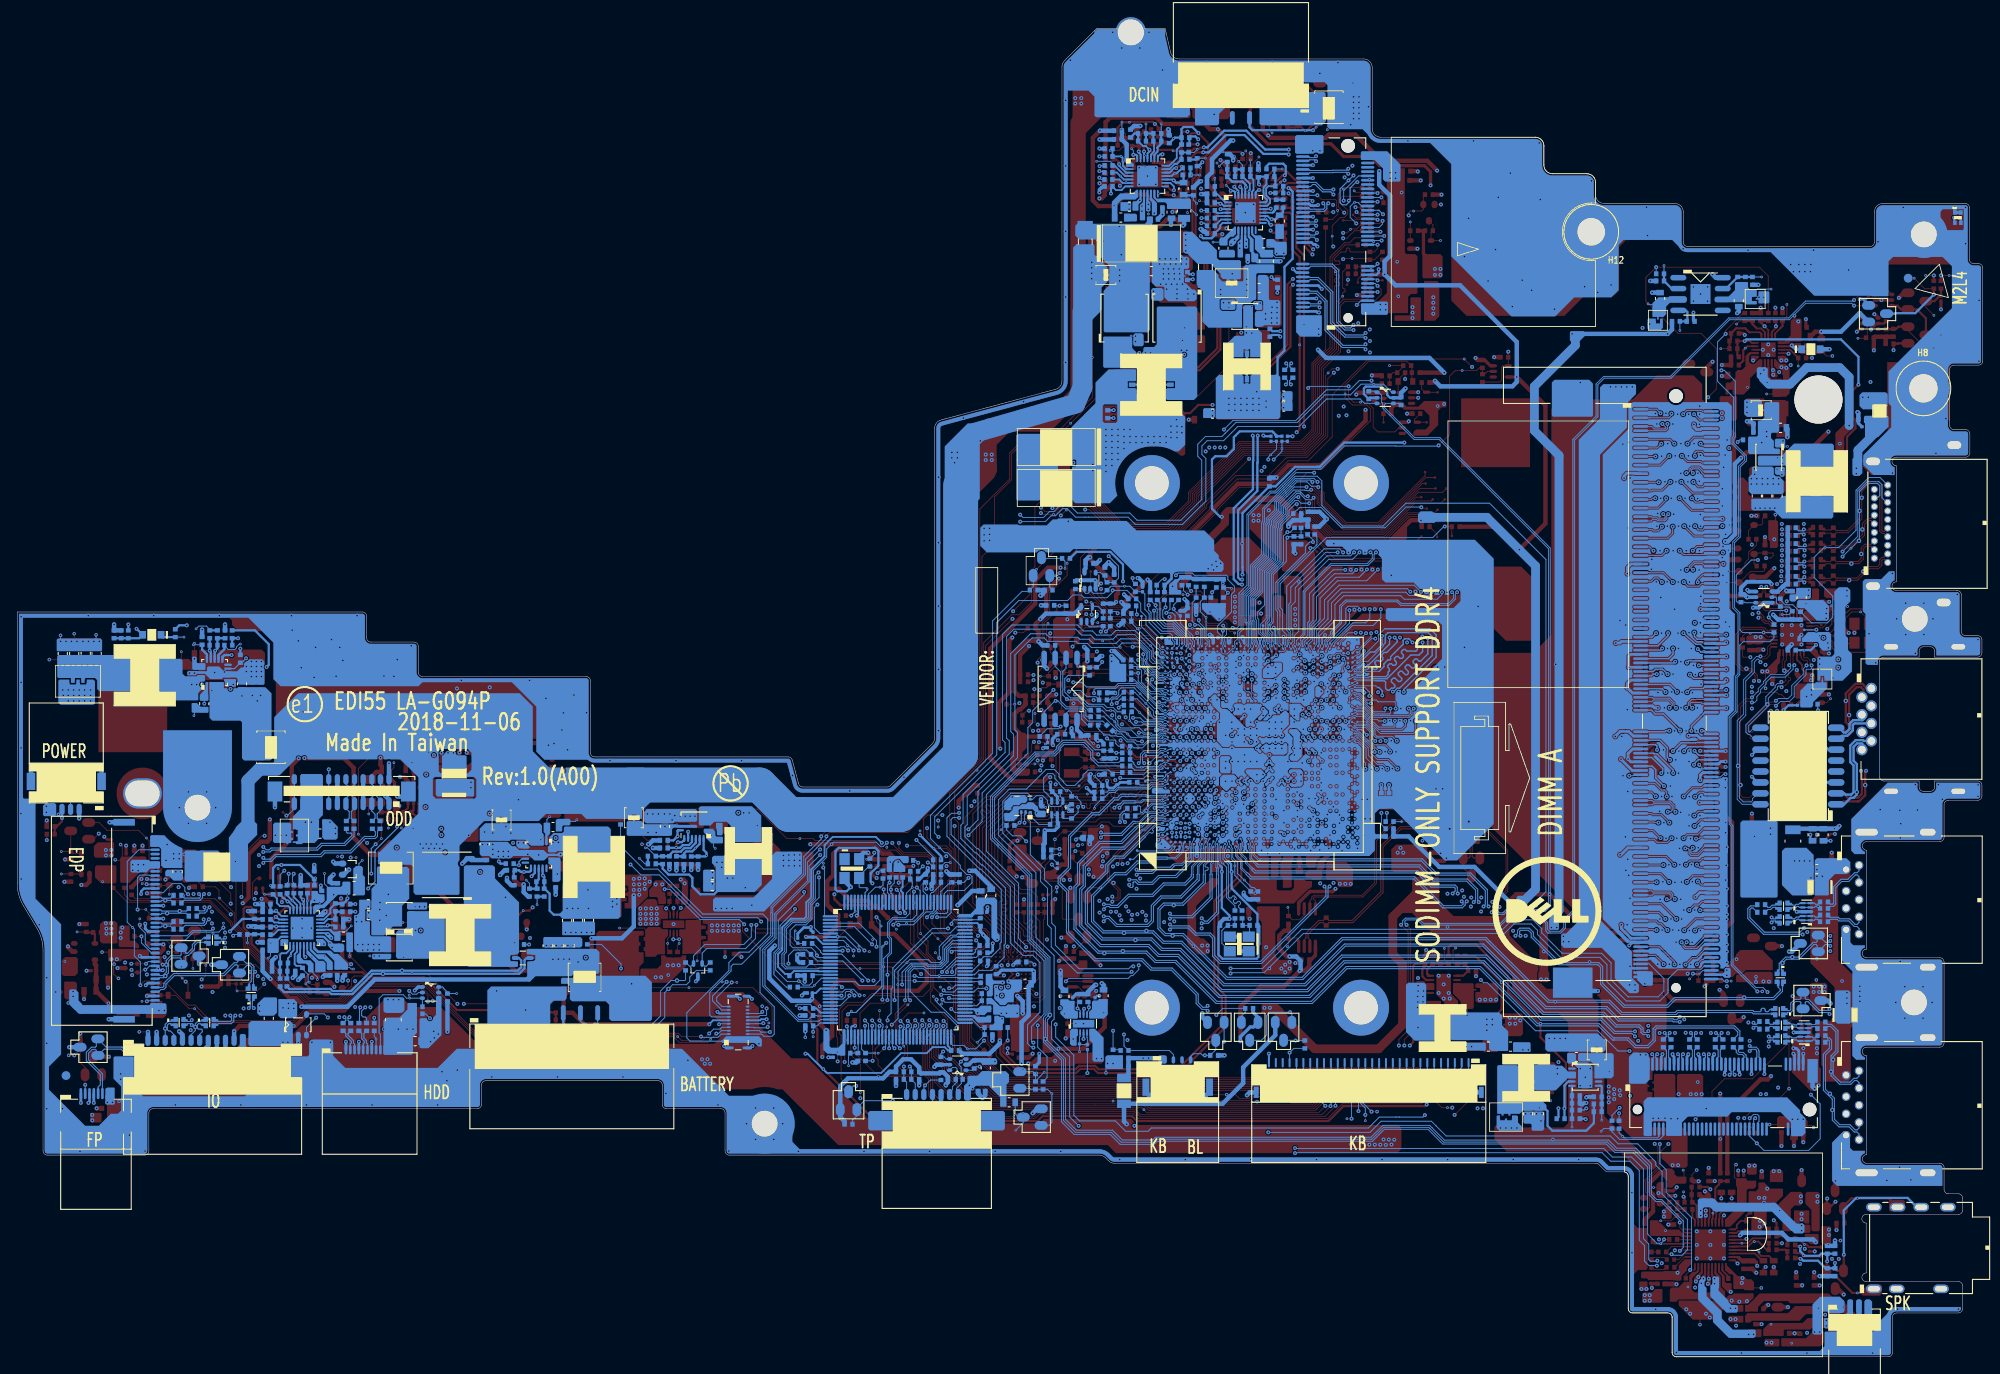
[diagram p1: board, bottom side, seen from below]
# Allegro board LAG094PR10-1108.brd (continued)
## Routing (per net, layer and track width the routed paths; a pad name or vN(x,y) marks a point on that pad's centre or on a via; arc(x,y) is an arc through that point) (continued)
DDR_M0_D34: length 58
  IN2 w0.127: v2(36.88,50.9) 37.31,50.48 38.32,50.48 39.01,51.17 42.39,51.17 52.63,61.41 53.71,61.41 54.1,61.8 54.1,61.98 53.81,62.27 53.81,62.45 53.99,62.63 54.17,62.63 54.5,62.3 54.7,62.3 54.86,62.46 54.86,62.67 54.55,62.98 54.55,63.16 54.72,63.32 54.9,63.32 55.22,63 55.4,63 56.64,64.24 57.81,64.24 61,67.43 71.92,67.43 74.33,69.84 74.33,72.17 74.74,72.59 76.18,72.59 76.5,72.9 76.5,73.13 76.72,73.35 77.21,73.35 v2(77.59,72.97)
  BOTTOM w0.089: v2(77.59,72.97) 77.23,73.32 UC1.BA33
  BOTTOM w0.102: v2(36.88,50.9) 37.65,51.68 JDIMM1.229
DDR_M0_D35: length 59.7
  IN2 w0.089: v2(77.53,73.96) 77.19,74.3 76.97,74.3 76.96,74.31 76.66,74.31 76.66,74.3 75,74.3
  IN2 w0.127: v2(34.11,51.94) 34.11,52.67 34.23,52.8 34.98,52.8 35.87,51.91 42.08,51.91 55.18,65.01 55.61,65.01 55.73,65.13 55.73,65.37 55.86,65.5 56.12,65.5 56.24,65.37 56.24,65.13 56.37,65.01 57.21,65.01 61.02,68.81 70.92,68.81 73.37,71.26 73.37,73.46 73.59,73.68 73.59,74.02 73.88,74.3 75,74.3
  BOTTOM w0.089: UC1.AY35 77.91,74.35 v2(77.53,73.96)
  BOTTOM w0.102: JDIMM1.224 32.61,52.93 33.01,52.53 33.52,52.53 v2(34.11,51.94)
DDR_M0_D36: length 59.5
  IN2 w0.127: v2(76.81,75.47) 76.37,75.92 75.35,75.92 74.85,76.42 73.61,76.42 71.15,73.96 71.15,72.88 70.34,72.07 66.77,72.07 66.34,71.64 66.34,71.46 66.43,71.36 66.43,71.18 66.25,71 66.07,71 65.98,71.1 65.8,71.1 65.5,70.8 59.79,70.8 58.36,69.37 58,69.37 57.87,69.5 57.87,70.09 57.74,70.21 57.49,70.21 57.36,70.09 57.36,69.5 57.23,69.37 56.76,69.37 50.16,62.77 49.82,62.77 41.31,54.26 35.61,54.26 35.49,54.38 35.49,54.5 35.36,54.63 35.11,54.63 34.98,54.5 34.98,54.38 34.85,54.26 34.59,54.26 34.4,54.44 v2(34.4,55.21)
  BOTTOM w0.089: UC1.BA37 77.23,75.05 v2(76.81,75.47)
  BOTTOM w0.102: JDIMM1.212 33.69,55.93 v2(34.4,55.21)
DDR_M0_D37: length 59.7
  IN2 w0.089: 75.04,75.69 75.11,75.62 75.11,75.22 75.32,75.01 76.54,75.01 76.6,75.07 77.94,75.07 v2(78.3,75.43)
  IN2 w0.127: v2(33.11,55.27) 33.2,55.18 33.2,55.01 34.39,53.82 37.92,53.82 38.15,53.59 38.45,53.59 38.68,53.82 41.4,53.82 49.98,62.4 50.31,62.4 56.76,68.85 58.67,68.85 60.18,70.37 67.14,70.37 67.76,70.99 71.22,70.99 72.04,71.81 72.04,74.26 73.1,75.32 73.12,75.32 73.65,75.85 74.88,75.85 75.04,75.69
  BOTTOM w0.089: UC1.AY37 77.95,75.08 v2(78.3,75.43)
  BOTTOM w0.102: JDIMM1.216 32.17,54.93 32.24,54.86 32.69,54.86 v2(33.11,55.27)
DDR_M0_D38: length 58.5
  IN2 w0.127: v2(77.53,76.32) 76.86,77 76.72,77 76.5,77.22 76.5,77.57 76.29,77.78 73.57,77.78 70.24,74.46 70.24,73.41 69.8,72.97 66.21,72.97 65.5,72.26 65.27,72.26 65.15,72.39 65.15,72.77 65.02,72.89 64.77,72.89 64.64,72.77 64.64,72.39 64.51,72.26 64.26,72.26 64.13,72.39 64.13,72.77 64,72.89 63.75,72.89 63.62,72.77 63.62,72.39 63.5,72.26 63.24,72.26 63.12,72.39 63.12,72.77 62.99,72.89 62.73,72.89 62.61,72.77 62.61,72.39 62.48,72.26 62.23,72.26 62.1,72.39 62.1,72.77 61.97,72.89 61.72,72.89 61.59,72.77 61.59,72.39 61.46,72.26 61.21,72.26 61.08,72.39 61.08,72.77 60.96,72.89 60.7,72.89 60.58,72.77 60.58,72.39 59.93,71.74 59.55,71.74 59.42,71.86 59.42,72.14 59.3,72.27 59.04,72.27 58.91,72.14 58.91,71.86 58.79,71.74 57.67,71.74 41.1,55.18 v2(37.91,55.18)
  BOTTOM w0.089: v2(77.53,76.32) UC1.AY39
  BOTTOM w0.102: JDIMM1.215 38.29,55.18 v2(37.91,55.18)
DDR_M0_D39: length 57.1
  IN2 w0.127: v2(76.88,76.3) 76.37,76.81 73.35,76.81 70.7,74.15 70.7,73.25 69.96,72.51 66.54,72.51 65.4,71.37 65.17,71.37 65.05,71.5 65.05,71.76 64.92,71.89 64.66,71.89 64.54,71.76 64.54,71.5 64.41,71.37 64.16,71.37 64.03,71.5 64.03,71.76 63.9,71.89 63.65,71.89 63.52,71.76 63.52,71.5 63.39,71.37 63.14,71.37 63.01,71.5 63.01,71.76 62.89,71.89 62.63,71.89 62.51,71.76 62.51,71.5 62.38,71.37 62.12,71.37 62,71.5 61.49,71.5 61.36,71.37 57.82,71.37 41.14,54.69 36.95,54.69 v2(36.44,55.2)
  BOTTOM w0.089: v2(76.88,76.3) 77.23,75.94 UC1.BA39
  BOTTOM w0.102: JDIMM1.211 37.42,56.18 v2(36.44,55.2)
DDR_M0_D40: length 53.2
  IN2 w0.127: v2(68.32,73.95) 68.32,74.08 68.03,74.37 59.99,74.37 59.29,73.67 57.25,73.67 55.87,72.28 55.69,72.28 55.36,72.6 55.18,72.6 55,72.42 55,72.24 55.33,71.92 55.33,71.74 55.16,71.58 54.99,71.58 54.64,71.93 54.46,71.93 54.28,71.75 54.28,71.57 54.63,71.22 54.63,71.04 54.46,70.88 54.22,70.88 53.86,71.24 53.68,71.24 53.5,71.06 53.5,70.88 53.86,70.52 53.86,70.34 53.68,70.16 53.5,70.16 53.14,70.52 52.96,70.52 52.8,70.36 52.8,70.18 53.19,69.79 53.19,69.61 53.01,69.43 52.83,69.43 52.44,69.82 52.26,69.82 52.08,69.64 52.08,69.46 52.12,69.42 52.12,69.24 51.94,69.06 51.76,69.06 51.72,69.1 51.54,69.1 41.12,58.68 40.42,58.68 38.92,57.18 v2(37.11,57.18)
  BOTTOM w0.089: UC1.BJ36 72.95,74.86 72.8,74.97 72.8,74.97 72.78,74.99 72.07,74.99 71.98,74.91 71.67,74.6 71.34,74.26 71.3,74.26 70.78,73.75 70.73,73.75
  BOTTOM w0.102: v2(37.11,57.18) JDIMM1.207 ; v2(68.32,73.95) 68.32,73.31 68.42,73.21 70.2,73.21 70.73,73.75
DDR_M0_D41: length 53
  IN2 w0.127: v2(35.84,57.21) 36.94,58.32 37.21,58.32 37.33,58.19 37.33,57.69 37.46,57.57 37.72,57.57 37.84,57.69 37.84,58.19 37.97,58.32 39.04,58.32 39.78,59.05 40.78,59.05 56.21,74.48 59.45,74.48 59.76,74.79 61.65,74.79 61.77,74.91 61.77,75.05 61.9,75.18 62.15,75.18 62.28,75.05 62.28,74.91 62.41,74.79 62.66,74.79 62.79,74.91 62.79,75.05 62.92,75.18 63.17,75.18 63.3,75.05 63.3,74.91 63.42,74.79 63.68,74.79 63.81,74.91 63.81,75.05 63.93,75.18 64.19,75.18 64.31,75.05 64.31,74.91 64.44,74.79 64.69,74.79 64.82,74.91 64.82,75.05 64.95,75.18 65.2,75.18 65.33,75.05 65.33,74.91 65.46,74.79 69.07,74.79 69.51,74.35 v2(69.51,73.92)
  BOTTOM w0.089: UC1.BK37 72.67,75.18 72,75.18 71.85,75.03 71.57,74.75 71.26,74.44 71.23,74.44 71.22,74.44 70.87,74.09 70.34,74.09
  BOTTOM w0.102: v2(35.84,57.21) 36.8,58.18 JDIMM1.203 ; 70.34,74.09 70.18,73.92 v2(69.51,73.92)
DDR_M0_D42: length 54.8
  IN2 w0.127: v2(65.89,73.92) 65.85,73.88 60.08,73.88 59.38,73.18 57.29,73.18 52.79,68.69 51.65,68.69 51.28,68.32 51.28,68.14 51.61,67.82 51.61,67.64 51.43,67.46 51.25,67.46 50.93,67.78 50.75,67.78 50.57,67.6 50.57,67.42 50.96,67.03 50.96,66.85 50.78,66.67 50.6,66.67 50.21,67.06 50.03,67.06 41.28,58.31 40.99,58.31 38.89,56.21 35.5,56.21 v2(34.49,57.22)
  BOTTOM w0.089: UC1.BJ35 73.09,74.53 73.03,74.54 72.85,74.54 72.78,74.47 72.04,74.47 71.48,73.91 71.45,73.91 70.6,73.06 70.59,73.06
  BOTTOM w0.102: JDIMM1.204 32.58,57.93 32.85,57.65 34.06,57.65 v2(34.49,57.22) ; 70.59,73.06 69.99,72.46 66.13,72.46 65.89,72.69 v2(65.89,73.92)
DDR_M0_D43: length 53.9
  IN2 w0.127: v2(67.1,73.92) 67.1,73.82 66.78,73.5 60.27,73.5 59.57,72.8 57.43,72.8 49.69,65.07 49.51,65.07 49.46,65.12 49.28,65.12 49.1,64.94 49.1,64.76 49.16,64.71 49.16,64.53 48.98,64.35 48.8,64.35 48.4,64.74 48.22,64.74 48.04,64.56 48.04,64.38 48.44,63.99 48.44,63.81 48.26,63.63 48.08,63.63 47.69,64.02 47.51,64.02 47.33,63.84 47.33,63.66 47.72,63.27 47.72,63.09 42.57,57.94 42.13,57.94 39.94,55.75 34.69,55.75 v2(33.22,57.22)
  BOTTOM w0.089: UC1.BL36 72.05,74.73 71.78,74.45 71.78,74.45 71.41,74.09 71.37,74.09 70.69,73.4 70.66,73.4
  BOTTOM w0.102: v2(67.1,73.92) 67.1,73.34 67.48,72.96 70.22,72.96 70.66,73.4 ; v2(33.22,57.22) 32.93,56.93 JDIMM1.208
DDR_M0_D44: length 53.1
  IN2 w0.127: v2(68.23,75.37) 67.81,75.79 67.17,75.79 66.45,76.51 59.21,76.51 58.51,75.81 55.47,75.81 51,71.34 49.9,71.34 49.55,70.99 49.55,70.81 49.65,70.71 49.65,70.53 49.5,70.38 49.26,70.38 49.19,70.45 49.01,70.45 48.83,70.27 48.83,70.09 49.2,69.73 49.2,69.55 49.02,69.37 48.84,69.37 48.47,69.73 48.29,69.73 48.11,69.55 48.11,69.37 48.13,69.36 48.13,69.18 47.95,69 47.77,69 47.75,69.01 47.57,69.01 38.31,59.75 36.71,59.75 v2(36.17,60.29)
  BOTTOM w0.089: UC1.BJ39 73.61,76.61 73.35,76.87 73.35,77.01 73.11,77.25 72.88,77.25 72.77,77.15 72.39,77.15 71.61,76.36 70.47,76.36 70.34,76.23
  BOTTOM w0.102: JDIMM1.195 38.19,60.18 37.83,59.81 36.65,59.81 v2(36.17,60.29) ; v2(68.23,75.37) 68.21,75.39 68.21,76.05 68.31,76.15 70.26,76.15 70.34,76.23
DDR_M0_D45: length 52
  IN2 w0.127: v2(68.83,75.37) 68.04,76.15 67.33,76.15 66.33,77.15 59.22,77.15 58.52,76.45 54.49,76.45 53.54,75.49 53.54,75.31 53.57,75.28 53.57,75.1 53.39,74.92 53.21,74.92 53.18,74.96 53,74.96 52.82,74.78 52.82,74.6 53.16,74.26 53.16,74.08 52.98,73.9 52.8,73.9 52.46,74.24 52.28,74.24 52.1,74.06 52.1,73.88 52.44,73.54 52.44,73.36 52.26,73.18 52.08,73.18 51.74,73.52 51.56,73.52 51.38,73.33 51.38,73.15 51.71,72.82 51.71,72.64 51.53,72.46 51.35,72.46 51.02,72.79 50.84,72.79 50.66,72.62 50.66,72.44 51.03,72.07 51.03,71.89 50.85,71.71 50.67,71.71 50.3,72.08 50.12,72.08 38.34,60.29 v2(37.45,60.29)
  BOTTOM w0.089: 69.77,74.73 70.74,74.73 72.54,76.53 UC1.BL40
  BOTTOM w0.102: JDIMM1.191 38.33,61.18 v2(37.45,60.29) ; 69.77,74.73 68.93,74.73 68.83,74.84 v2(68.83,75.37)
DDR_M0_D46: length 51.8
  IN2 w0.127: v2(34.77,60.29) 34.77,60.71 35.01,60.95 38.48,60.95 54.53,77.01 58.55,77.01 59.25,77.71 66.3,77.71 67.3,76.7 68.1,76.7 v2(69.42,75.39)
  BOTTOM w0.089: UC1.BJ40 73.13,76.53 72.78,76.79 72.54,76.79 71.23,75.47 71.22,75.47
  BOTTOM w0.102: v2(69.42,75.39) 69.42,75.09 69.52,74.99 70.73,74.99 71.22,75.47 ; JDIMM1.190 32.42,61.43 33.14,60.71 34.36,60.71 v2(34.77,60.29)
DDR_M0_D47: length 50.9
  IN2 w0.127: v2(71.1,75.98) 70.1,75.98 69.33,76.76 69.33,77.6 68.64,78.29 59.08,78.29 58.31,77.53 54.53,77.53 38.32,61.32 34.4,61.32 v2(33.32,60.25)
  BOTTOM w0.089: UC1.BK41 72.97,76.97 72.47,76.97 71.48,75.98 v2(71.1,75.98)
  BOTTOM w0.102: JDIMM1.194 32.79,60.43 32.97,60.25 v2(33.32,60.25)
DDR_M0_D48: length 62.6
  IN1 w0.127: v2(76.2,72.03) 75.57,71.4 75.57,65.45 72.08,61.96 69.29,61.96 69.16,61.83 69.16,61.65 69.04,61.53 68.78,61.53 68.66,61.65 68.66,61.83 68.53,61.96 68.27,61.96 68.15,61.83 68.15,61.65 68.02,61.53 67.77,61.53 67.64,61.65 67.64,61.83 67.51,61.96 65.94,61.96 65.31,61.34 64.42,61.34 56.81,53.73 52.05,53.73 42.66,44.34 36.49,44.34 35.75,45.08 35.08,45.08 v2(34.55,45.61)
  BOTTOM w0.089: UC1.BD29 v2(76.2,72.03)
  BOTTOM w0.102: JDIMM1.246 32.27,47.43 33.29,46.41 33.74,46.41 v2(34.55,45.61)
DDR_M0_D49: length 62.4
  IN1 w0.127: v2(35.82,45.62) 35.82,45.53 36.58,44.77 37.04,44.77 37.17,44.9 37.17,45.1 37.3,45.23 37.55,45.23 37.68,45.1 37.68,45.02 37.81,44.89 38.06,44.89 38.19,45.02 38.19,45.14 38.33,45.28 38.57,45.28 38.7,45.16 38.7,45.02 38.82,44.89 39.05,44.89 39.18,45.02 39.18,45.14 39.3,45.27 39.56,45.27 39.69,45.14 39.69,45.02 39.81,44.89 42.69,44.89 51.68,53.88 51.9,54.1 52.32,54.1 52.45,54.22 52.45,54.39 52.58,54.52 52.83,54.52 52.96,54.39 52.96,54.22 53.08,54.1 56.54,54.1 64.23,61.78 65.17,61.78 65.72,62.33 70.3,62.33 71.02,63.04 72.64,63.04 75.19,65.59 75.19,71.76 v2(75.48,72.04)
  BOTTOM w0.089: UC1.BF29 75.48,72.02 v2(75.48,72.04)
  BOTTOM w0.102: JDIMM1.245 37.57,47.68 35.82,45.92 v2(35.82,45.62)
DDR_M0_D50: length 62.5
  IN1 w0.089: 74.81,71.92 74.81,71.95 v2(74.75,72.01)
  IN1 w0.127: 74.81,71.92 74.81,65.73 72.49,63.41 70.81,63.41 70.1,62.7 65.56,62.7 65.09,62.23 63.9,62.23 56.57,54.9 52.18,54.9 50.25,52.97 50.07,52.97 49.95,53.09 49.77,53.09 49.59,52.91 49.59,52.73 49.71,52.61 49.71,52.43 49.44,52.16 49.26,52.16 49.14,52.28 48.96,52.28 48.78,52.1 48.78,51.92 48.9,51.8 48.9,51.62 48.73,51.44 48.55,51.44 48.42,51.57 48.24,51.57 48.06,51.39 48.06,51.21 48.19,51.08 48.19,50.9 48.01,50.72 47.83,50.72 47.7,50.85 47.52,50.85 47.34,50.67 47.34,50.49 47.47,50.36 47.47,50.18 47.29,50 47.11,50 46.99,50.13 46.81,50.13 46.63,49.95 46.63,49.77 46.75,49.65 46.75,49.47 46.57,49.29 46.39,49.29 46.27,49.41 46.09,49.41 45.91,49.23 45.91,49.05 46.03,48.93 46.03,48.75 45.85,48.57 45.67,48.57 45.55,48.69 45.37,48.69 45.19,48.51 45.19,48.33 45.31,48.21 45.31,48.03 45.13,47.85 44.95,47.85 44.83,47.97 44.65,47.97 44.47,47.79 44.47,47.61 44.59,47.49 44.59,47.31 44.41,47.13 44.23,47.13 44.11,47.25 43.93,47.25 43.75,47.07 43.75,46.89 43.87,46.77 43.87,46.59 43.44,46.16 40.07,46.16 39.94,46.03 39.94,45.76 39.81,45.64 39.56,45.64 39.43,45.76 39.43,46.03 39.3,46.16 39.05,46.16 38.92,46.03 38.92,45.78 38.8,45.65 38.54,45.65 38.42,45.78 38.42,46.03 38.29,46.16 37.6,46.16 v2(37.09,45.65)
  BOTTOM w0.089: v2(74.75,72.01) UC1.BH29
  BOTTOM w0.102: v2(37.09,45.65) 37.09,45.71 38.05,46.68 JDIMM1.249
DDR_M0_D51: length 63.5
  IN1 w0.127: v2(36.64,49.62) 37.12,49.14 38.65,49.14 40.9,51.39 41.08,51.39 41.53,50.94 41.71,50.94 41.89,51.12 41.89,51.3 41.44,51.75 41.44,51.93 41.62,52.11 41.8,52.11 42.25,51.66 42.43,51.66 42.61,51.84 42.61,52.02 42.16,52.47 42.16,52.65 42.33,52.83 42.51,52.83 42.97,52.38 43.15,52.38 43.33,52.56 43.33,52.74 42.87,53.19 42.87,53.37 43.05,53.55 43.23,53.55 43.69,53.1 43.87,53.1 44.04,53.28 44.04,53.46 43.59,53.91 43.59,54.09 43.83,54.32 44,54.32 44.3,54.03 44.48,54.03 44.66,54.21 44.66,54.39 44.36,54.68 44.36,54.86 46.47,56.97 55.42,56.97 62.78,64.32 64.26,64.32 64.33,64.38 64.76,64.82 66.74,64.82 67.54,65.62 70.36,65.62 72.52,67.78 72.52,73.44 73.57,74.48 74.18,74.48 v2(74.74,73.92)
  BOTTOM w0.089: v2(74.74,73.92) 75.1,73.57 UC1.BF33
  BOTTOM w0.102: v2(36.64,49.62) 37.37,50.35 37.62,50.35 37.94,50.68 JDIMM1.233
DDR_M0_D52: length 62.5
  IN1 w0.127: v2(76.96,72.06) 75.95,71.05 75.95,65.31 71.34,60.7 66.55,60.7 66.43,60.83 66.43,60.96 66.3,61.08 66.05,61.08 65.92,60.96 65.92,60.83 65.79,60.7 64.46,60.7 57.11,53.36 52.21,53.36 42.82,43.97 36.25,43.97 35.65,44.57 34.92,44.57 34.41,45.08 33.77,45.08 v2(33.22,45.63)
  BOTTOM w0.089: v2(76.96,72.06) 76.95,72.05 76.93,72.05 UC1.BC29
  BOTTOM w0.102: JDIMM1.250 32.27,46.43 32.49,46.21 32.64,46.21 v2(33.22,45.63)
DDR_M0_D53: length 62.6
  IN1 w0.127: v2(76.2,73.86) 76.2,74.45 75.98,74.67 74.52,74.67 74.32,74.86 73.2,74.86 72.15,73.81 72.15,67.94 70.27,66.05 67.45,66.05 66.59,65.19 64.61,65.19 64.11,64.69 62.4,64.69 55.05,57.33 54.82,57.33 54.69,57.46 54.69,58.16 54.57,58.29 54.31,58.29 54.18,58.16 54.18,57.46 54.06,57.33 53.8,57.33 53.68,57.46 53.68,58.16 53.55,58.29 53.3,58.29 53.17,58.16 53.17,57.46 53.04,57.33 52.79,57.33 52.66,57.46 52.66,58.16 52.53,58.29 52.28,58.29 52.15,58.16 52.15,57.46 52.03,57.33 51.77,57.33 51.64,57.46 51.64,58.16 51.52,58.29 51.26,58.29 51.14,58.16 51.14,57.46 51.01,57.33 50.78,57.33 50.65,57.46 50.65,57.72 50.53,57.84 50.27,57.84 50.15,57.72 50.15,57.46 50.02,57.33 46.32,57.33 38.49,49.51 38.02,49.51 v2(37.91,49.62)
  BOTTOM w0.089: UC1.BD33 v2(76.2,73.86)
  BOTTOM w0.102: JDIMM1.237 38.31,49.68 38.25,49.62 v2(37.91,49.62)
DDR_M0_D54: length 63.7
  IN1 w0.089: 73.57,72.39 73.57,71.32 73.41,71.17 73.38,71.17
  IN1 w0.127: 73.57,72.39 73.57,73.21 73.82,73.46 75,73.46 v2(75.46,73.92) ; v2(33.43,49.56) 34.25,48.73 35.82,48.73 36.3,48.25 41.15,48.25 41.79,48.9 41.97,48.9 42.5,48.36 42.68,48.36 42.86,48.54 42.86,48.72 42.33,49.26 42.33,49.44 42.51,49.62 42.69,49.62 43.22,49.08 43.4,49.08 43.58,49.26 43.58,49.44 43.05,49.98 43.05,50.16 43.25,50.36 43.43,50.36 43.78,50.02 43.96,50.02 44.14,50.2 44.14,50.38 43.79,50.72 43.79,50.9 49.12,56.23 55.94,56.23 63.27,63.56 64.54,63.56 65.07,64.08 67.05,64.08 67.79,64.82 70.6,64.82 73.35,67.57 73.35,71.15 73.38,71.17
  BOTTOM w0.089: UC1.BF35 75.1,74.28 v2(75.46,73.92)
  BOTTOM w0.102: v2(33.43,49.56) 33.02,49.97 31.9,49.97 31.86,49.93 JDIMM1.236
DDR_M0_D55: length 62.5
  IN1 w0.127: v2(74.03,73.92) 73.63,73.92 72.98,73.28 72.98,67.72 70.45,65.19 67.63,65.19 66.9,64.45 64.91,64.45 64.48,64.02 64.48,64.02 64.42,63.95 63.15,63.95 55.79,56.6 48.97,56.6 47.84,55.47 47.66,55.47 47.1,56.03 46.92,56.03 46.75,55.85 46.75,55.67 47.3,55.11 47.3,54.93 47.12,54.75 46.94,54.75 46.39,55.31 46.21,55.31 46.03,55.13 46.03,54.95 46.58,54.39 46.58,54.21 46.42,54.05 46.24,54.05 45.87,54.42 45.7,54.42 45.52,54.24 45.52,54.06 45.88,53.69 45.88,53.51 41.07,48.7 36.48,48.7 36.01,49.16 35.13,49.16 v2(34.7,49.59)
  BOTTOM w0.089: UC1.BH35 74.39,74.28 v2(74.03,73.92)
  BOTTOM w0.102: JDIMM1.232 33.37,50.93 v2(34.7,49.59)
DDR_M0_D56: length 48.5
  IN1 w0.127: v2(37.99,65.17) 39.53,65.17 39.73,64.97 39.73,64.32 39.85,64.19 40.11,64.19 40.24,64.32 40.24,65.04 40.36,65.17 40.67,65.17 40.8,65.04 40.8,64.32 40.92,64.19 41.18,64.19 41.3,64.32 41.3,65.04 41.43,65.17 41.92,65.17 42.38,64.7 42.38,64.53 41.96,64.1 41.96,63.92 42.14,63.74 42.32,63.74 42.74,64.17 42.92,64.17 43.1,63.99 43.1,63.81 42.68,63.38 42.68,63.2 42.86,63.02 43.04,63.02 43.46,63.45 43.64,63.45 44.25,62.84 54.11,62.84 62.19,70.92 65.44,70.92 66.18,71.66 68.06,71.66 v2(68.1,71.62)
  BOTTOM w0.089: UC1.BL34 71.65,73.83 71.56,73.73 71.52,73.73 70.63,72.84 70.63,72.37 70.4,72.15
  BOTTOM w0.102: 70.4,72.15 68.62,72.15 v2(68.1,71.62) ; v2(37.99,65.17) 38.02,65.17 38.53,65.68 JDIMM1.173
DDR_M0_D57: length 50.2
  IN1 w0.127: v2(69.19,68.36) 68.52,67.69 63.6,67.69 55.48,59.56 40.06,59.56 38.11,61.51 35.79,61.51 34.99,62.31 34.99,62.49 35.23,62.73 35.41,62.73 36.01,62.13 36.39,62.13 v2(36.42,62.1)
  BOTTOM w0.089: UC1.BL30 72.63,72.02 71.41,70.8 71.41,69.94 70.34,68.87
  BOTTOM w0.102: 70.34,68.87 69.71,68.87 v2(69.19,68.36) ; JDIMM1.183 38.51,63.18 38.35,63.02 37.34,63.02 v2(36.42,62.1)
DDR_M0_D58: length 50.5
  IN1 w0.127: v2(70.4,68.36) 70.4,68.3 69.4,67.29 65.44,67.29 63.74,65.59 62.03,65.59 55.63,59.2 39.9,59.2 37.96,61.14 35.64,61.14 35.35,61.43 35.17,61.43 35.1,61.36 34.92,61.36 34.75,61.54 34.75,61.72 34.81,61.79 34.81,61.97 34.55,62.23 33.65,62.23 33.52,62.36 v2(33.52,62.93)
  BOTTOM w0.089: UC1.BJ29 73.53,71.56 73.19,71.76 73.13,71.81 73.06,71.84 72.94,71.85 72.85,71.81 72.48,71.57 71.66,70.75 71.66,69.62 v2(70.4,68.36)
  BOTTOM w0.102: v2(33.52,62.93) 33.03,63.43 32.22,63.43 JDIMM1.182
DDR_M0_D59: length 50.2
  IN1 w0.127: v2(71.73,68.36) 70.3,66.92 65.59,66.92 63.89,65.22 62.18,65.22 55.79,58.83 43.91,58.83 43.79,58.7 43.79,58.44 43.66,58.31 43.4,58.31 43.28,58.44 43.28,58.7 43.15,58.83 39.75,58.83 37.81,60.77 34.45,60.77 v2(33.5,61.72)
  BOTTOM w0.089: v2(71.73,68.36) 71.73,69.03 71.92,69.21 71.92,70.75 72.6,71.43 72.85,71.43 UC1.BK29
  BOTTOM w0.102: JDIMM1.186 32.8,62.43 v2(33.5,61.72)
DDR_M0_D60: length 50
  IN1 w0.127: v2(68.87,70.35) 68.32,69.81 63.01,69.81 54.94,61.74 41.76,61.74 41.55,61.94 40.08,61.94 38.11,63.92 33.55,63.92 33.42,64.04 v2(33.42,65.12)
  BOTTOM w0.089: 70.41,71.15 70.68,71.15 71.22,71.69 71.22,72.67 71.74,73.2 72.73,73.2 arc(72.78,73.18) 72.84,73.15 arc(72.85,73.14) 72.87,73.13 72.87,73.13 arc(72.88,73.12) 72.89,73.12 arc(72.92,73.11) 72.96,73.1 72.99,73.1 arc(73.07,73.12) 73.14,73.15 73.15,73.15 73.37,73.37 UC1.BJ33
  BOTTOM w0.102: JDIMM1.174 32.27,65.43 32.49,65.64 32.9,65.64 v2(33.42,65.12) ; 70.41,71.15 70.4,71.14 69.4,71.14 68.87,70.61 v2(68.87,70.35)
DDR_M0_D61: length 49.2
  IN1 w0.127: v2(34.76,65.15) 34.54,64.93 34.54,64.41 34.67,64.28 38.26,64.28 38.3,64.24 40.24,62.31 41.71,62.31 41.91,62.11 54.6,62.11 62.69,70.19 65.88,70.19 66.46,70.77 70.02,70.77 70.59,71.34 v2(70.59,71.6)
  BOTTOM w0.089: v2(70.59,71.6) 70.98,71.99 70.98,72.69 71.67,73.37 UC1.BK33
  BOTTOM w0.102: v2(34.76,65.15) 33.74,66.16 32.67,66.16 32.4,66.43 JDIMM1.170
DDR_M0_D62: length 49.4
  IN1 w0.127: v2(69.38,71.62) 68.89,71.14 66.31,71.14 65.73,70.56 62.43,70.56 54.35,62.48 42.14,62.48 41.44,63.18 39.89,63.18 38.42,64.65 35.9,64.65 35.66,64.89 35.66,65.34 35.91,65.59 36.28,65.59 v2(36.73,65.15)
  BOTTOM w0.089: UC1.BJ34 73.29,73.82 73.29,73.82 72.83,73.6 72.78,73.55 71.66,73.55 71.66,73.55 71.59,73.55 70.81,72.77 70.81,72.27 70.49,71.96
  BOTTOM w0.102: v2(36.73,65.15) 36.73,65.65 36.98,65.91 37.36,65.91 38.13,66.68 JDIMM1.169 ; 70.49,71.96 69.71,71.96 v2(69.38,71.62)
DDR_M0_D63: length 50.7
  IN1 w0.127: v2(68.02,68.39) 63.47,68.39 55.05,59.96 54.58,59.96 54.45,60.09 54.45,60.28 54.33,60.41 54.07,60.41 53.94,60.28 53.94,60.09 53.79,59.93 53.53,59.93 53.4,60.06 53.4,60.28 53.27,60.41 53.02,60.41 52.89,60.28 52.89,60.06 52.77,59.93 52.51,59.93 52.38,60.06 52.38,60.28 52.26,60.41 52,60.41 51.88,60.28 51.88,60.06 51.75,59.93 51.5,59.93 51.37,60.06 51.37,60.28 51.24,60.41 50.99,60.41 50.86,60.28 50.86,60.06 50.73,59.93 50.51,59.93 50.38,60.06 50.38,60.28 50.25,60.41 50,60.41 49.87,60.28 49.87,60.06 49.74,59.93 49.49,59.93 49.36,60.06 49.36,60.28 49.24,60.41 48.98,60.41 48.85,60.28 48.85,60.06 48.73,59.93 48.47,59.93 48.35,60.06 48.35,60.28 48.22,60.41 47.97,60.41 47.84,60.28 47.84,60.06 47.71,59.93 47.46,59.93 47.33,60.06 47.33,60.28 47.2,60.41 46.95,60.41 46.82,60.28 46.82,60.06 46.7,59.93 46.44,59.93 46.31,60.06 46.31,60.28 46.19,60.41 45.93,60.41 45.81,60.28 45.81,60.06 45.68,59.93 45.43,59.93 45.3,60.06 45.3,60.28 45.17,60.41 44.92,60.41 44.79,60.28 44.79,60.06 44.66,59.93 40.21,59.93 39.53,60.61 38.04,62.1 v2(37.69,62.1)
  BOTTOM w0.089: UC1.BJ30 73.05,72.02 72.78,72.3 72.58,72.3 71.77,71.49 71.77,71.48 71.09,70.81 71.09,70.19 70.34,69.44
  BOTTOM w0.102: v2(37.69,62.1) 38.07,62.1 38.14,62.18 JDIMM1.187 ; v2(68.02,68.39) 69.07,69.44 70.34,69.44
DDR_M0_DQS0: length 61.9
  IN1 w0.127: v2(36.65,108.46) 36.81,108.3 36.81,107.97 37.13,107.65 41.84,107.65 54.04,95.46 58.56,95.46 60,94.03 70.6,94.03 70.71,93.92 70.71,93.72 v2(70.52,93.53)
  BOTTOM w0.089: 79.28,83.31 79.21,83.24 79.21,82.99 79.21,82.84 UC1.AT53
  BOTTOM w0.102: v2(36.65,108.46) 36.65,107.9 36.87,107.68 JDIMM1.13 ; v2(70.52,93.53) 70.73,93.32 70.73,92.72 71.45,92.01 75.7,92.01 78.77,88.93 78.77,83.99 79.28,83.48 79.28,83.31
DDR_M0_DQS1: length 55.4
  IN2 w0.089: 76.22,83 76.43,83 77.47,81.95 77.47,81.27 77.38,81.18 77.38,80.78 77.47,80.69 77.67,80.69 77.77,80.79 v2(77.77,80.87)
  IN2 w0.127: 76.22,83 75.51,83 75.46,83.04 73.25,83.04 72.95,82.75 71.63,82.75 70.97,82.09 61.63,82.09 61.16,81.62 60.97,81.42 51.94,81.42 41.09,92.27 34.13,92.27 33.85,91.99 33.85,91.69 v2(33.67,91.5)
  BOTTOM w0.089: UC1.AW49 78.13,80.51 v2(77.77,80.87)
  BOTTOM w0.102: v2(33.67,91.5) 33.73,91.5 33.9,91.67 33.9,91.82 33.5,92.22 32.57,92.22 32.27,91.93 JDIMM1.76
DDR_M0_DQS2: length 55.1
  IN2 w0.127: v2(61.09,88.89) 61.24,88.74 61.24,88.06 60.74,87.56 53.43,87.56 49.33,91.66 49.26,91.73 42.74,98.25 39.02,98.25 38.45,98.82 37.34,98.82 37.34,98.82 37.03,98.82 36.84,98.63 36.68,98.47 36.68,98.11 v2(36.55,97.98)
  BOTTOM w0.089: UC1.BC54 76.33,83.2 75.61,83.92 75.61,84.05 75.6,84.06 75.6,84.12 75.59,84.12 75.59,84.14
  BOTTOM w0.102: JDIMM1.55 38.54,97.18 38.38,97.34 37.91,97.34 37.77,97.2 36.94,97.2 36.72,97.42 36.72,97.82 v2(36.55,97.98) ; v2(61.09,88.89) 61.3,88.68 61.3,88.07 62,87.37 67.66,87.37 68.07,87.78 73.96,87.78 74.52,87.22 74.52,85.28 75.59,84.2 75.59,84.14
DDR_M0_DQS3: length 66.8
  IN2 w0.089: v2(79.68,77.31) 79.75,77.31 79.93,77.49 80.2,77.49 80.43,77.72 80.43,79.06 80.91,79.54 80.91,82.2 78.39,84.71 78.39,84.72
  IN2 w0.102: 78.39,84.72 78.39,85.96 78.15,86.21
  IN2 w0.127: 78.15,86.21 74.32,90.03 68.99,90.03 63.44,95.59 54.48,95.59 46.4,103.66 34.17,103.66 33.78,103.28 33.78,102.85 v2(33.69,102.75)
  BOTTOM w0.089: UC1.AR41 80.03,76.95 v2(79.68,77.31)
  BOTTOM w0.102: v2(33.69,102.75) 33.82,102.88 33.82,103.14 33.72,103.25 33.02,103.25 32.69,102.91 32.69,102.84 32.28,102.43 JDIMM1.34
DDR_M0_DQS4: length 60.1
  IN2 w0.089: 73.96,74.99 74.39,74.99 74.58,74.8 77.57,74.8 78.09,74.28 78.49,74.28 78.58,74.37 78.58,74.54 78.44,74.69 v2(78.32,74.69)
  IN2 w0.127: v2(36.72,53.21) 36.63,53.29 36.35,53.29 36.22,53.16 36.22,52.83 36.35,52.7 41.03,52.7 50.2,61.87 50.7,61.87 55.57,66.74 57.45,66.74 60.36,69.65 70.64,69.65 72.58,71.59 72.58,74.02 73.34,74.78 73.54,74.99 73.96,74.99
  BOTTOM w0.089: v2(78.32,74.69) 78.57,74.69 78.66,74.78 UC1.AV37
  BOTTOM w0.102: v2(36.72,53.21) 36.65,53.14 36.4,53.14 36.23,53.31 36.23,53.69 36.37,53.83 38.27,53.83 38.42,53.68 JDIMM1.221
DDR_M0_DQS5: length 52.7
  IN2 w0.127: v2(34.57,59.11) 34.27,59.11 33.97,58.81 33.97,58.61 34.22,58.37 35.42,58.37 36.17,59.11 38.43,59.11 41.57,62.25 42.85,62.25 55.88,75.27 59.12,75.27 59.82,75.97 66.23,75.97 66.52,75.69 66.52,75.56 v2(66.71,75.37)
  BOTTOM w0.089: 69.91,74.54 69.93,74.54 69.93,74.54 70.81,74.54 71.75,75.48 71.75,75.5 71.8,75.54 72.59,75.54 UC1.BL38
  BOTTOM w0.102: 69.91,74.54 66.75,74.54 66.52,74.77 66.52,75.18 v2(66.71,75.37) ; v2(34.57,59.11) 34.27,59.11 34.13,58.97 34.13,58.52 33.9,58.29 33.1,58.29 32.47,58.93 JDIMM1.200
DDR_M0_DQS6: length 60.9
  IN1 w0.089: v2(74.78,73.02) 74.83,73.06 75,73.06 75.09,72.98 75.09,72.78 74.89,72.58 74.4,72.58 74.37,72.55
  IN1 w0.127: 74.37,72.55 74.34,72.55 73.88,72.09 73.88,66.02 73.72,65.83 72.13,64.24 72.13,64.24 68.04,64.24 67.29,63.49 65.23,63.49 64.76,63.03 63.57,63.03 56.24,55.7 50.9,55.7 42.61,47.4 34.91,47.4 34.67,47.64 34.67,47.87 34.99,48.19 v2(34.99,48.2)
  BOTTOM w0.089: UC1.BF31 74.88,72.52 74.78,72.62 v2(74.78,73.02)
  BOTTOM w0.102: v2(34.99,48.2) 34.84,48.04 34.84,47.73 34.58,47.48 33.22,47.48 32.27,48.43 JDIMM1.242
DDR_M0_DQS7: length 48.7
  IN1 w0.127: v2(36.6,63.38) 36.41,63.38 36.28,63.25 36.28,63.06 36.41,62.93 38.34,62.93 39.86,61.41 41.33,61.41 41.53,61.21 55.16,61.21 63.23,69.27 70.03,69.27 70.16,69.4 70.16,70.25 v2(70.08,70.33)
  BOTTOM w0.089: UC1.BJ32 72.89,72.73 72.88,72.73 72.8,72.65 72.43,72.65 71.41,71.64 71.41,71.63 70.37,70.59 70.35,70.59 70.21,70.46
  BOTTOM w0.102: 70.21,70.46 v2(70.08,70.33) ; v2(36.6,63.38) 36.28,63.38 36.09,63.56 36.09,64.03 36.37,64.31 38.27,64.31 38.4,64.18 JDIMM1.179
DDR_M0_DQS#0: length 61.9
  IN1 w0.127: v2(37.23,108.46) 37.07,108.3 37.07,108.08 37.24,107.92 41.95,107.92 54.15,95.72 58.67,95.72 60.11,94.29 70.71,94.29 70.97,94.03 70.97,93.71 v2(71.15,93.53)
  BOTTOM w0.089: UC1.AT55 79.46,82.91 79.46,82.81 79.54,82.73 79.65,82.73 79.76,82.84 79.76,83.27
  BOTTOM w0.102: v2(37.23,108.46) 37.22,108.46 36.85,108.09 36.85,107.98 36.96,107.88 38.19,107.88 38.48,108.18 JDIMM1.11 ; 79.76,83.27 78.98,84.06 78.98,89.02 75.78,92.21 71.54,92.21 70.94,92.81 70.94,93.32 v2(71.15,93.53)
DDR_M0_DQS#1: length 55.5
  IN2 w0.089: v2(77.77,80.15) 77.77,80.42 77.68,80.51 77.39,80.51 77.2,80.71 77.2,81.25 77.29,81.34 77.29,81.88 76.37,82.8 76.26,82.8 76.24,82.78 76.22,82.78
  IN2 w0.127: v2(34.41,91.5) 34.31,91.5 34.11,91.7 34.11,91.88 34.24,92.01 40.98,92.01 51.83,81.16 61.08,81.16 61.43,81.51 61.74,81.82 71.08,81.82 71.74,82.48 73.06,82.48 73.36,82.78 76.22,82.78
  BOTTOM w0.089: v2(77.77,80.15) 78.13,79.8 UC1.AW48
  BOTTOM w0.102: v2(34.41,91.5) 34.31,91.5 34.11,91.7 34.11,91.9 33.58,92.43 JDIMM1.74
DDR_M0_DQS#2: length 55.2
  IN2 w0.127: v2(61.67,88.9) 61.5,88.73 61.5,87.95 60.85,87.3 53.32,87.3 49.22,91.39 49.15,91.47 42.63,97.98 38.91,97.98 38.34,98.55 37.14,98.55 36.95,98.36 36.95,98.17 v2(37.14,97.98)
  BOTTOM w0.089: 75.79,84.14 75.8,84.12 75.8,84 76.52,83.28 76.52,82.82 76.62,82.71 76.62,82.46 UC1.BB53
  BOTTOM w0.102: JDIMM1.53 38.53,97.68 38.39,97.54 37.82,97.54 37.68,97.4 37.02,97.4 36.92,97.5 36.92,97.76 v2(37.14,97.98) ; v2(61.67,88.9) 61.5,88.73 61.5,88.16 62.09,87.57 67.58,87.57 67.98,87.98 74.05,87.98 74.72,87.3 74.72,86.71 74.71,86.69 74.71,85.35 75.79,84.28 75.79,84.14
DDR_M0_DQS#3: length 66.7
  IN2 w0.089: v2(79.68,78.02) 79.6,77.95 79.6,77.78 79.72,77.67 80.12,77.67 80.25,77.79 80.25,79.13 80.73,79.61 80.73,82.13 78.2,84.65
  IN2 w0.102: 77.98,86.04 78.2,85.82 78.2,84.65
  IN2 w0.127: v2(34.44,102.75) 34.28,102.75 34.05,102.98 34.05,103.17 34.28,103.4 46.29,103.4 54.37,95.32 63.33,95.32 68.88,89.77 74.22,89.77 77.95,86.04 77.98,86.04
  BOTTOM w0.089: UC1.AR43 79.77,77.67 79.68,77.75 v2(79.68,78.02)
  BOTTOM w0.102: JDIMM1.32 32.42,102.93 32.94,103.45 33.8,103.45 34.02,103.23 34.02,103 34.28,102.75 v2(34.44,102.75)
DDR_M0_DQS#4: length 60.1
  IN2 w0.089: 74.2,74.73 74.39,74.55 77.57,74.54 78.01,74.1 78.57,74.1 78.76,74.29 78.76,74.56 78.85,74.65 v2(79.04,74.65)
  IN2 w0.127: 74.2,74.73 73.66,74.73 73.52,74.6 72.84,73.91 72.84,71.48 70.75,69.39 60.47,69.39 57.56,66.48 55.68,66.48 50.81,61.6 50.31,61.6 41.14,52.44 36.24,52.44 35.96,52.72 35.96,53.04 v2(35.79,53.21)
  BOTTOM w0.089: v2(79.04,74.65) 78.74,74.35 UC1.AV35
  BOTTOM w0.102: JDIMM1.219 38.46,54.18 38.32,54.03 36.28,54.03 36.03,53.78 36.03,53.46 v2(35.79,53.21)
DDR_M0_DQS#5: length 52.8
  IN2 w0.127: v2(66.12,75.37) 66.25,75.5 66.25,75.58 66.12,75.71 59.93,75.71 59.23,75.01 55.98,75.01 42.96,61.99 41.68,61.99 38.54,58.85 36.27,58.85 35.53,58.1 34.11,58.1 33.71,58.5 v2(33.71,59.18)
  BOTTOM w0.089: 69.91,74.35 69.92,74.36 70.89,74.36 71.88,75.35 72.67,75.35 72.72,75.35 UC1.BJ38
  BOTTOM w0.102: JDIMM1.198 32.26,59.43 33.18,58.5 33.81,58.5 33.92,58.61 33.92,58.97 v2(33.71,59.18) ; v2(66.12,75.37) 66.33,75.16 66.33,74.69 66.67,74.35 69.91,74.35
DDR_M0_DQS#6: length 61
  IN1 w0.089: 74.43,72.33 74.47,72.33 74.53,72.4 74.96,72.4 75.27,72.7 75.27,72.78 v2(75.46,72.97)
  IN1 w0.127: v2(34.41,48.2) 34.41,47.53 34.8,47.14 42.72,47.14 51.01,55.43 56.35,55.43 63.68,62.76 64.87,62.76 65.34,63.23 67.39,63.23 68.15,63.98 72.02,63.98 72.24,63.98 73.85,65.58 73.85,65.58 74.14,65.87 74.14,72.04 74.22,72.12 74.43,72.33
  BOTTOM w0.089: UC1.BD31 75.81,72.61 v2(75.46,72.97)
  BOTTOM w0.102: v2(34.41,48.2) 34.63,47.97 34.63,47.82 34.5,47.68 33.49,47.68 32.49,48.68 32.49,48.71 32.27,48.93 JDIMM1.240
DDR_M0_DQS#7: length 48.7
  IN1 w0.127: v2(35.71,63.36) 36.02,63.05 36.02,62.95 36.3,62.67 38.23,62.67 39.75,61.14 41.22,61.14 41.42,60.94 55.27,60.94 63.34,69.01 70.14,69.01 70.43,69.29 70.43,70.09 v2(70.67,70.33)
  BOTTOM w0.089: UC1.BK31 72.5,72.47 71.59,71.56 71.59,71.56 70.67,70.63 v2(70.67,70.33)
  BOTTOM w0.102: JDIMM1.177 38.42,64.68 38.25,64.51 36.28,64.51 35.89,64.12 35.89,63.54 v2(35.71,63.36)
DDR_M0_DRAMRST#: length 61.1
  TOP w0.102: RC42.1 RC41.2 31.32,85.87 D14.2 31.47,86.67 v1(32.36,85.78) 33.02,85.78 v2(33.46,85.34)
  IN1 w0.089: 77.4,81.97 77.4,79 76.87,78.47 v2(76.87,78.21)
  IN1 w0.127: v2(33.46,85.34) 35.18,85.34 40.01,90.17 40.83,90.17 41.28,90.35 42.37,90.35 42.5,90.49 57.89,90.49 58.47,91.07 68.16,91.07 70.54,88.68 74.29,88.68 77,85.97 77,82.74 77.4,82.33 77.4,81.97
  BOTTOM w0.089: v2(76.87,78.21) 76.87,78.16 UC1.BC43
DDR_M0_DRAMRST#_R: length 4.4
  TOP w0.102: v1(29.44,84.89) 29.82,84.52 v2(29.82,83.97) 30.07,83.97 30.17,84.07 CD29.1 RC42.2
  BOTTOM w0.102: v2(29.82,83.97) 29.86,83.93 JDIMM1.108
DDR_M0_MA0: length 58.1
  IN1 w0.089: 70.72,78.72 70.98,78.72 71.28,78.42 74.22,78.42 74.59,78.79 74.92,78.79 v2(75.37,79.24)
  IN1 w0.193: 70.72,78.72 69.67,78.72 69.64,78.69 64.38,78.69 64.17,78.48 64.14,78.48 64.08,78.42 61.83,78.42 56.55,73.14 48.97,73.14 48.84,73.27 48.84,73.81 48.64,74 48.26,74 48.06,73.81 48.06,72.8 47.93,72.67 47.42,72.67 47.29,72.8 47.29,73.81 47.1,74 46.71,74 46.52,73.81 46.52,72.8 46.39,72.67 45.88,72.67 45.75,72.8 45.75,73.81 45.55,74 45.17,74 44.98,73.81 44.98,72.8 44.85,72.67 44.26,72.67 43.8,73.14 42.21,73.14 42.01,73.34 41.12,73.34 40.92,73.14 40.92,72.96 40.73,72.77 40.35,72.77 40.15,72.96 40.15,73.14 39.96,73.34 39.66,73.34 39.47,73.14 39.47,72.87 39.28,72.67 38.89,72.67 38.7,72.87 38.7,73.15 38.51,73.35 38.12,73.35 37.93,73.15 37.93,72.87 37.73,72.67 37.35,72.67 37.16,72.87 37.16,73.15 36.96,73.35 34.04,73.35 33.89,73.2 33.89,72.81 v2(33.86,72.77)
  BOTTOM w0.142: UC1.BD45 75.37,79.21 v2(75.37,79.24)
  BOTTOM w0.15: JDIMM1.144 32.27,74.93 33.86,73.34 v2(33.86,72.77)
DDR_M0_MA1: length 55.6
  IN1 w0.089: 72.51,81.44 v2(73.76,80.19)
  IN1 w0.193: v2(36.87,77.29) 37.4,76.76 37.95,76.76 38.15,76.95 38.15,77.01 38.2,77.06 38.2,77.14 38.34,77.28 38.73,77.28 38.92,77.09 38.92,76.95 39.11,76.76 39.41,76.76 39.84,77.2 40.43,77.2 40.87,76.76 43.97,76.76 44.16,76.95 44.16,77.46 44.35,77.66 44.74,77.66 44.93,77.46 44.93,76.95 45.12,76.76 45.51,76.76 45.7,76.95 45.7,77.46 45.9,77.66 46.28,77.66 46.48,77.46 46.48,76.95 46.67,76.76 47.05,76.76 47.25,76.95 47.25,77.46 47.44,77.66 47.83,77.66 48.02,77.46 48.02,76.95 48.21,76.76 48.6,76.76 48.79,76.95 48.79,77.46 48.98,77.66 49.37,77.66 49.56,77.46 49.56,76.95 49.76,76.76 50.14,76.76 50.34,76.95 50.34,77.46 50.53,77.66 50.92,77.66 51.11,77.46 51.11,76.95 51.3,76.76 51.69,76.76 51.88,76.95 51.88,77.46 52.07,77.66 52.46,77.66 52.65,77.46 52.65,76.95 52.85,76.76 53.23,76.76 53.42,76.95 53.42,77.46 53.62,77.66 54,77.66 54.2,77.46 54.2,76.95 54.39,76.76 54.78,76.76 54.97,76.95 54.97,77.46 55.16,77.66 55.55,77.66 55.74,77.46 55.74,76.95 55.93,76.76 56.36,76.76 57.12,77.52 57.12,77.79 56.94,77.98 56.94,78.25 57.21,78.53 57.48,78.53 57.67,78.34 57.94,78.34 61.06,81.46 72.49,81.46 72.51,81.44
  BOTTOM w0.089: v2(73.76,80.19) 73.77,80.21 UC1.BH50
  BOTTOM w0.15: JDIMM1.133 37.25,77.68 v2(36.87,77.29)
DDR_M0_MA2: length 56.9
  IN1 w0.193: v2(34.35,77.27) 34.53,77.09 34.53,77.05 35,76.58 35,76.14 34.8,75.94 32.9,75.94 32.71,76.14 32.71,76.81 33.59,77.7 34.8,77.7 35.38,78.28 41.38,78.28 41.88,78.78 51.12,78.78 52.29,79.95 58.15,79.95 60.65,82.46 70.81,82.46 71.38,83.03 72.4,83.03 72.54,82.89 72.91,82.89 73.57,83.55 74.66,83.55 74.87,83.34 74.87,82.39 74.31,81.83 v2(74.31,81.15)
  BOTTOM w0.089: v2(74.31,81.15) 74.06,80.9 74.06,80.51 74.39,80.18 UC1.BH47
  BOTTOM w0.15: JDIMM1.132 32.27,77.93 32.51,77.69 33.93,77.69 v2(34.35,77.27)
DDR_M0_MA3: length 54.2
  IN1 w0.193: v2(73.76,81.81) 73.81,81.87 73.81,82.03 74.28,82.5 74.28,82.75 74.11,82.93 73.69,82.93 73.07,82.3 72.32,82.3 72.09,82.53 71.58,82.53 71.01,81.96 60.86,81.96 58.27,79.37 55.63,79.37 55.44,79.18 55.44,78.35 55.25,78.15 54.86,78.15 54.67,78.35 54.67,79.18 54.48,79.37 54.06,79.37 53.8,79.11 53.8,78.47 53.61,78.28 53.25,78.28 53.06,78.47 53.06,79.24 52.86,79.43 52.48,79.43 52.28,79.24 52.28,78.47 52.09,78.28 43.66,78.28 43.47,78.09 43.47,77.45 43.27,77.26 42.89,77.26 42.7,77.45 42.7,78.06 42.5,78.25 42.1,78.25 41.91,78.06 41.91,77.45 41.72,77.26 41.07,77.26 40.55,77.78 36,77.78 35.98,77.76 35.95,77.76 35.69,77.49 35.69,77.47 v2(35.53,77.31)
  BOTTOM w0.089: v2(73.76,81.81) 73.76,81.81 UC1.BG52
  BOTTOM w0.15: JDIMM1.131 36.36,78.18 35.53,77.34 v2(35.53,77.31)
DDR_M0_MA4: length 59.4
  IN1 w0.193: v2(34.03,79.31) 34.03,79.21 33.57,78.75 31.04,78.75 30.7,78.42 30.7,78.12 30.9,77.93 31.65,77.93 31.85,77.74 31.85,77.35 31.65,77.16 30.9,77.16 30.7,76.97 30.7,76.29 31.28,75.71 31.97,75.71 32.21,75.95 32.21,77.39 32.42,77.6 32.79,77.6 33.39,78.19 33.8,78.19 34.38,78.19 34.51,78.32 34.51,78.61 34.68,78.78 41.17,78.78 41.67,79.28 50.91,79.28 52.1,80.46 57.95,80.46 60.56,83.07 61.72,83.07 61.74,83.05 v2(65.1,83.05)
  BOTTOM w0.089: UC1.BK45 70.98,78.78 70.92,78.84
  BOTTOM w0.15: v2(65.1,83.05) 65.1,82 65.5,81.59 66.46,81.59 69.21,78.84 70.92,78.84 ; v2(34.03,79.31) 33.6,78.88 32.11,78.88 32.06,78.93 JDIMM1.128
DDR_M0_MA5: length 58.7
  IN1 w0.193: v2(66.26,83.05) 66.26,84.06 64.93,85.4 56.93,85.4 56.55,85.02 56.55,84.13 56.1,83.69 54.92,83.69 54.36,84.25 54.36,84.92 54.16,85.11 53.7,85.11 53.54,84.95 53.54,84.4 53.32,84.18 52.77,84.18 49.71,81.13 49.02,81.13 48.75,81.39 48.41,81.39 48.14,81.13 47.51,81.13 47.27,81.36 46.9,81.36 46.67,81.13 45.88,81.13 45.66,81.35 45.25,81.35 45.03,81.13 44.42,81.13 44.18,81.36 43.72,81.36 43.48,81.13 42.85,81.13 42.61,81.36 42.21,81.36 41.97,81.13 40.03,81.13 39.28,80.38 36.92,80.38 36.37,79.83 34.55,79.83 34.48,79.89 32.68,79.89 32.48,80.09 32.48,80.97 32.23,81.22 30.83,81.22 30.64,81.03 30.64,79.51 30.83,79.31 v2(32.76,79.31)
  BOTTOM w0.089: 70.16,79.66 71.61,79.66 71.7,79.76 71.96,79.76 72.21,79.51 72.76,79.51 72.92,79.4 73.05,79.4 UC1.BJ46
  BOTTOM w0.15: v2(32.76,79.31) 32.65,79.43 JDIMM1.126 ; v2(66.26,83.05) 66.7,83.48 67.17,83.48 67.34,83.31 67.34,82.86 67.51,82.7 67.52,82.7 68,82.22 68,82.21 68.33,81.88 68.33,81.88 68.81,81.4 68.81,81.11 68.89,81.04 69.11,81.04 69.59,80.56 69.59,80.23 70.16,79.66
DDR_M0_MA6: length 60.1
  IN1 w0.193: v2(37.9,79.38) 37.9,79.38 41.07,79.38 41.46,79.77 50.7,79.77 51.6,80.67 51.9,80.97 51.9,81.91 52.1,82.1 52.48,82.1 52.67,81.91 52.67,81.24 52.87,81.04 53.25,81.04 53.45,81.24 53.45,82.4 53.75,82.71 54.03,82.71 54.22,82.51 54.22,81.24 54.49,80.96 54.79,80.96 54.98,81.15 54.98,82.17 55.18,82.37 55.56,82.37 55.75,82.17 55.75,81.15 55.95,80.96 56.24,80.96 56.43,81.15 56.43,82.16 56.63,82.35 57.01,82.35 57.21,82.16 57.21,81.15 57.4,80.96 57.74,80.96 58.26,81.47 58.26,81.75 57.98,82.03 57.98,82.3 58.25,82.58 58.52,82.58 58.81,82.29 59.08,82.29 59.31,82.52 59.31,82.79 59.05,83.05 59.05,83.33 59.32,83.6 59.6,83.6 59.85,83.34 60.13,83.34 60.36,83.57 61.93,83.57 61.94,83.56 v2(64.49,83.56)
  BOTTOM w0.089: UC1.BJ44 72.83,78.56 72.78,78.61 72.56,78.61 70.57,78.61
  BOTTOM w0.15: v2(64.49,83.56) 64.49,81.72 65.31,80.9 65.52,80.9 65.76,81.13 65.97,81.13 66.18,80.92 66.18,80.7 65.95,80.47 65.95,80.26 66.13,80.08 66.34,80.08 66.7,80.44 66.91,80.44 67.1,80.25 67.1,80.04 66.74,79.68 66.74,79.47 66.89,79.32 67.1,79.32 67.49,79.71 67.7,79.71 67.92,79.49 67.92,79.28 67.53,78.89 67.53,78.68 67.69,78.52 67.9,78.52 68.29,78.91 68.5,78.91 68.72,78.7 68.72,78.48 68.33,78.09 68.33,77.88 68.48,77.73 68.71,77.73 68.94,77.5 69.18,77.5 69.39,77.71 69.39,78.46 69.54,78.61 70.57,78.61 ; v2(37.9,79.38) 38.3,79.38 38.51,79.18 JDIMM1.127
DDR_M0_MA7: length 57.4
  IN1 w0.193: v2(68.93,83.62) 68.93,84.05 66.09,86.9 52.51,86.9 51.58,85.97 51.58,85.69 51.74,85.53 51.74,85.26 51.46,84.99 51.19,84.99 51.03,85.15 50.76,85.15 50.05,84.44 42.28,84.44 40.55,82.71 39.5,82.71 38.66,81.87 34.8,81.87 34.63,82.04 34.63,82.67 34.5,82.81 33.18,82.81 32.99,83 32.99,83.5 32.75,83.74 30.96,83.74 30.77,83.55 30.77,81.91 30.96,81.72 32.6,81.72 32.98,81.34 v2(32.98,80.39)
  BOTTOM w0.089: 71.5,80.43 71.82,80.12 72.15,80.12 72.4,79.86 72.77,79.86 72.78,79.88 72.92,79.98 73.05,79.98 73.2,79.88 73.38,79.69 UC1.BJ47
  BOTTOM w0.15: JDIMM1.122 31.84,80.43 31.88,80.39 v2(32.98,80.39) ; 71.5,80.43 71.36,80.43 68.93,82.86 v2(68.93,83.62)
DDR_M0_MA8: length 59.1
  IN1 w0.193: v2(65.68,83.05) 65.69,83.07 65.69,83.93 64.72,84.91 63.66,84.91 63.47,84.71 63.47,84.26 63.27,84.07 62.89,84.07 62.69,84.26 62.69,84.71 62.5,84.91 62.12,84.91 61.92,84.71 61.92,84.26 61.73,84.07 61.34,84.07 61.15,84.26 61.15,84.71 60.96,84.91 60.57,84.91 60.38,84.71 60.38,84.26 60.19,84.07 59.8,84.07 59.61,84.26 59.61,84.71 59.41,84.91 58.96,84.91 58.77,84.71 58.77,83.75 58.33,83.31 58.01,83.31 57.82,83.5 57.82,84.67 57.62,84.86 57.24,84.86 57.04,84.67 57.04,83.5 56.85,83.31 56.61,83.31 56.16,82.86 54.58,82.86 53.78,83.66 53.17,83.66 52.97,83.47 52.97,82.93 52.78,82.73 52.03,82.73 50.74,81.45 50.74,81.18 50.83,81.09 50.83,80.82 50.56,80.54 50.29,80.54 50.2,80.63 49.92,80.63 49.56,80.27 48.54,80.27 48.19,80.63 47.77,80.63 47.41,80.27 47,80.27 46.64,80.63 46.23,80.63 45.87,80.27 45.45,80.27 45.1,80.63 44.68,80.63 44.32,80.27 43.91,80.27 43.55,80.63 43.14,80.63 42.78,80.27 42.36,80.27 42.01,80.63 40.26,80.63 40.02,80.39 40.02,80.09 39.8,79.88 37.13,79.88 36.81,79.56 36.81,79.56 v2(36.63,79.38)
  BOTTOM w0.089: 71.27,79.08 71.39,78.96 72.76,78.96 72.85,79.02 72.94,79.06 73.06,79.06 73.13,79.02 73.15,79 UC1.BJ45
  BOTTOM w0.15: JDIMM1.125 38.33,79.68 38.06,79.94 37.19,79.94 v2(36.63,79.38) ; 71.27,79.08 69.35,79.08 69.1,79.33 69.1,79.6 68.95,79.75 68.95,79.97 69.14,80.16 69.14,80.37 68.92,80.58 68.71,80.58 68.52,80.39 68.31,80.39 68.13,80.57 68.13,80.78 68.36,81 68.36,81.21 68.15,81.43 67.93,81.43 67.71,81.2 67.5,81.2 67.32,81.38 67.32,81.59 67.54,81.82 67.54,82.03 67.33,82.24 67.12,82.24 66.93,82.05 65.87,82.05 65.69,82.23 65.69,82.64 65.68,82.65 v2(65.68,83.05)
DDR_M0_MA9: length 57.1
  IN1 w0.193: v2(35.74,80.82) 35.74,81.18 35.93,81.37 38.87,81.37 39.71,82.22 41.24,82.22 41.95,82.92 41.98,82.92 42.23,83.17 42.23,83.68 42.49,83.94 42.87,83.94 43.06,83.75 43.06,83.17 43.26,82.98 43.58,82.98 43.84,83.24 43.84,83.75 44.03,83.94 44.42,83.94 44.61,83.75 44.61,83.17 44.8,82.98 45.12,82.98 45.38,83.24 45.38,83.75 45.57,83.94 45.96,83.94 46.15,83.75 46.15,83.17 46.35,82.98 46.67,82.98 46.93,83.24 46.93,83.75 47.12,83.94 47.5,83.94 47.7,83.75 47.7,83.17 47.89,82.98 48.21,82.98 48.47,83.24 48.47,83.75 48.66,83.94 48.99,83.94 49.18,83.75 49.18,83.17 49.37,82.98 50.16,82.98 50.37,83.19 50.37,83.46 50.21,83.62 50.21,83.89 50.48,84.17 50.75,84.17 50.91,84.01 51.19,84.01 52.65,85.48 52.65,85.52 53.54,86.4 65.83,86.4 68.35,83.89 v2(68.35,83.62)
  BOTTOM w0.089: UC1.BK47 72.28,79.69 72.05,79.92 72.04,79.92 72.03,79.94 71.48,79.94
  BOTTOM w0.15: v2(35.74,80.82) 35.88,80.68 JDIMM1.121 ; 71.48,79.94 71.27,80.15 70.98,80.15 70.74,79.91 70.49,79.91 70.37,80.03 70.37,80.24 70.52,80.39 70.54,80.39 70.54,80.48 70.63,80.57 70.63,80.78 70.45,80.96 70.24,80.96 70.14,80.86 69.93,80.86 69.72,81.07 69.72,81.28 69.82,81.38 69.82,81.64 69.57,81.89 69.26,81.89 68.03,83.12 68.03,83.3 v2(68.35,83.62)
DDR_M0_MA10: length 55.2
  IN1 w0.089: 70.72,79.22 70.92,79.22 70.95,79.19 71.33,79.19 71.77,78.75 74.3,78.75 v2(74.76,79.21)
  IN1 w0.193: 70.72,79.22 70.69,79.22 70.68,79.23 64.19,79.23 63.88,78.92 61.63,78.92 57.27,74.57 56.81,74.57 56.61,74.37 56.61,73.91 56.42,73.72 56.03,73.72 55.84,73.91 55.84,74.37 55.65,74.57 55.26,74.57 55.07,74.37 55.07,73.91 54.88,73.72 54.49,73.72 54.3,73.91 54.3,74.37 54.1,74.57 53.72,74.57 53.52,74.37 53.52,73.91 53.33,73.72 52.95,73.72 52.75,73.91 52.75,74.37 52.56,74.57 52.17,74.57 51.98,74.37 51.98,73.91 51.79,73.72 51.4,73.72 51.21,73.91 51.21,74.37 51.02,74.57 44.89,74.57 44.17,73.85 43.98,73.85 43.97,73.84 33.94,73.84 32.81,74.97 32.14,74.97 31.71,74.54 31.71,74.17 32.32,73.57 32.32,73.11 v2(32.65,72.78)
  BOTTOM w0.089: UC1.BF45 75.1,78.86 v2(74.76,79.21)
  BOTTOM w0.15: JDIMM1.146 32.01,72.43 32.36,72.78 v2(32.65,72.78)
DDR_M0_MA11: length 55.3
  IN1 w0.193: v2(70.59,83.49) 70.05,82.95 67.63,82.95 67.35,83.24 67.35,83.24 67.09,83.51 67.08,83.51 66.77,83.82 66.77,84.76 65.63,85.9 56.01,85.9 55.82,85.71 55.82,84.71 55.63,84.51 55.24,84.51 55.05,84.71 55.05,85.71 54.86,85.9 53.78,85.9 49.6,81.72 49.16,81.72 48.97,81.91 48.97,82.29 48.78,82.48 48.39,82.48 48.2,82.29 48.2,81.91 47.95,81.66 47.67,81.66 47.42,81.91 47.42,82.29 47.23,82.48 46.85,82.48 46.65,82.29 46.65,81.82 46.46,81.62 46.09,81.62 45.88,81.83 45.88,82.29 45.69,82.48 45.3,82.48 45.11,82.29 45.11,81.91 44.86,81.66 44.59,81.66 44.34,81.91 44.34,82.29 44.14,82.48 43.76,82.48 43.56,82.29 43.56,81.91 43.31,81.66 43.04,81.66 42.79,81.91 42.79,82.29 42.6,82.48 42.21,82.48 42.02,82.29 42.02,81.91 41.83,81.72 39.92,81.72 39.07,80.87 36.71,80.87 36.17,80.33 34.75,80.33 v2(34.37,80.71)
  BOTTOM w0.089: UC1.BJ51 72.8,81.58 72.66,81.62 72.55,81.62 72.39,81.78 72.39,82.16 71.05,83.49 v2(70.59,83.49)
  BOTTOM w0.15: v2(34.37,80.71) 34.15,80.93 JDIMM1.120
DDR_M0_MA12: length 55.5
  IN1 w0.193: v2(71.08,84.13) 71.08,84.65 70.83,84.89 69.81,84.89 66.79,87.92 65.63,87.92 65.62,87.93 49.65,87.93 49.45,87.73 49.45,86.93 49.26,86.74 48.92,86.74 48.72,86.93 48.72,87.73 48.53,87.93 48.14,87.93 47.95,87.73 47.95,86.93 47.76,86.74 47.37,86.74 47.18,86.93 47.18,87.73 46.99,87.93 46.6,87.93 46.41,87.73 46.41,86.93 46.21,86.74 45.83,86.74 45.63,86.93 45.63,87.73 45.44,87.93 45.05,87.93 44.86,87.73 44.86,86.93 44.67,86.74 44.28,86.74 44.09,86.93 44.09,87.73 43.9,87.93 43.56,87.93 43.32,87.68 43.32,86.93 43.12,86.74 42.37,86.74 40.34,84.7 40.22,84.59 39.97,84.59 38.39,83.01 36.45,83.01 35.99,82.55 v2(35.99,82.36)
  BOTTOM w0.089: UC1.BJ52 72.83,82.24 72.56,82.24 71.09,83.71 71.09,84.13 v2(71.08,84.13)
  BOTTOM w0.15: JDIMM1.119 36.51,81.18 35.99,81.69 v2(35.99,82.36)
DDR_M0_MA13: length 59.4
  IN1 w0.089: 70.72,77.13 70.72,77.13 71.3,77.71 73.66,77.71 v2(74.03,77.34)
  IN1 w0.193: 70.72,77.13 70.72,77.03 70.15,76.47 70.15,75.43 69.64,74.92 64.23,74.92 64.03,74.72 64.03,73.85 63.84,73.66 63.45,73.66 63.26,73.85 63.26,74.72 63.07,74.92 62.55,74.92 54.35,66.71 45.58,66.71 43.26,69.04 41.04,69.04 40.39,69.69 39.56,69.69 39.28,69.4 39.28,68.58 39.08,68.38 38.75,68.38 38.56,68.58 38.56,68.72 38.36,68.91 37.98,68.91 37.79,68.72 37.79,68.58 37.59,68.38 37.24,68.38 37.05,68.58 37.05,68.71 36.85,68.9 36.55,68.9 36.47,68.9 36.28,68.71 36.28,68.58 36.08,68.38 35.77,68.38 35.5,68.65 35.5,68.71 35.31,68.9 35.04,68.9 34.84,68.71 34.84,67.56 34.65,67.37 34.13,67.37 33.38,68.12 33,68.12 32.54,68.59 32.54,68.61 32.5,68.64 32.5,69.02 32.88,69.39 33.19,69.39 33.55,69.03 v2(33.55,68.84)
  BOTTOM w0.089: v2(74.03,77.34) 74.39,77.69 UC1.BH43
  BOTTOM w0.15: JDIMM1.158 33.06,69.43 33.55,68.93 v2(33.55,68.84)
DDR_M0_MA14_WE#: length 58.2
  IN1 w0.193: v2(68.55,77.34) 68.55,77.01 68.36,76.82 62.75,76.82 62.34,76.82 55.56,70.04 44.37,70.04 43.23,71.18 37.7,71.18 37.51,70.99 37.51,70.76 37.7,70.57 v2(37.86,70.57)
  BOTTOM w0.089: UC1.BJ48 73.03,80.41 72.55,80.41 72.12,80.84 71.46,80.84 69.61,82.69 69.61,82.83 69.45,82.99
  BOTTOM w0.15: v2(68.55,77.34) 68.42,77.34 68.03,77.73 67.78,77.73 63.98,81.53 63.98,83.75 64.42,84.2 69.12,84.2 69.42,83.89 69.42,83.01 69.45,82.99 ; JDIMM1.151 38.03,71.18 37.86,71 v2(37.86,70.57)
DDR_M0_MA15_CAS#: length 59
  IN1 w0.193: v2(33.49,70.46) 34.06,71.02 36.84,71.02 37.5,71.68 56.5,71.68 62.13,77.31 v2(67.28,77.31)
  BOTTOM w0.089: UC1.BJ50 72.98,80.99 72.47,80.99 70.2,83.26 70.2,83.94 70.18,83.96 69.97,84.17 69.97,84.17 69.49,84.65 69.45,84.65
  BOTTOM w0.15: v2(67.28,77.31) 67.28,77.58 63.52,81.34 63.52,83.56 63.52,83.94 64.23,84.65 69.45,84.65 ; JDIMM1.156 32.96,69.93 v2(33.49,70.46)
DDR_M0_MA16_RAS#: length 59.4
  IN1 w0.193: v2(76.24,76.36) 75.79,75.91 75.12,75.91 75.06,75.97 72.8,75.97 70.99,74.15 70.99,73.12 70.6,72.73 65.72,72.73 64.99,71.99 61.74,71.99 54.45,64.7 43.89,64.7 41.75,66.85 33.95,66.85 33.18,67.62 32.79,67.62 32.04,68.38 32.04,68.4 32,68.43 32,69.22 32.76,69.97 34.3,69.97 34.71,70.39 v2(34.71,70.42)
  BOTTOM w0.089: UC1.BD41 75.81,76.79 v2(76.24,76.36)
  BOTTOM w0.15: v2(34.71,70.42) 34.71,70.44 34.23,70.93 JDIMM1.152
DDR_M0_ODT0: length 53.9
  IN1 w0.193: v2(35.98,67.88) 36.15,67.71 36.15,67.7 36.41,67.43 36.43,67.43 36.51,67.35 39.95,67.35 40.62,68.01 42.19,68.01 42.38,67.82 42.38,67.05 44.23,65.2 44.69,65.2 44.89,65.39 44.89,65.52 45.08,65.72 45.46,65.72 45.66,65.52 45.66,65.39 45.85,65.2 46.24,65.2 46.43,65.39 46.43,65.52 46.62,65.72 47.01,65.72 47.2,65.52 47.2,65.39 47.39,65.2 47.78,65.2 48.04,65.46 48.67,65.46 48.94,65.2 54.24,65.2 61.53,72.49 64.78,72.49 65.52,73.23 70.19,73.23 70.49,73.52 70.49,74.36 72.77,76.64 75.2,76.64 v2(75.48,76.36)
  BOTTOM w0.089: v2(75.48,76.36) 75.48,76.24 UC1.BD39
  BOTTOM w0.15: JDIMM1.155 38.27,70.18 38.2,70.11 37.86,70.11 35.98,68.22 v2(35.98,67.88)
DDR_M0_ODT1: length 54.6
  IN1 w0.193: v2(37.05,66.35) 37.93,66.35 38.31,65.97 38.71,65.97 39.09,66.35 41.54,66.35 44.48,63.41 44.82,63.41 45.01,63.6 45.01,63.94 45.21,64.13 45.59,64.13 45.78,63.94 45.78,63.6 45.98,63.41 46.36,63.41 46.56,63.6 46.56,63.94 46.75,64.13 47.14,64.13 47.33,63.94 47.33,63.6 47.52,63.41 47.91,63.41 48.1,63.6 48.1,63.94 48.29,64.13 48.68,64.13 48.87,63.94 48.87,63.6 49.07,63.41 49.45,63.41 49.65,63.6 49.65,63.94 49.84,64.13 50.22,64.13 50.42,63.94 50.42,63.6 50.61,63.41 51,63.41 51.19,63.6 51.19,63.94 51.38,64.13 51.77,64.13 51.96,63.94 51.96,63.6 52.16,63.41 53.86,63.41 61.94,71.49 65.19,71.49 65.93,72.23 70.8,72.23 71.48,72.91 71.48,73.95 73.01,75.47 v2(74.72,75.47)
  BOTTOM w0.089: v2(74.72,75.47) 74.72,75.53 UC1.BF39
  BOTTOM w0.15: JDIMM1.161 38.42,68.68 38,68.26 38,67.3 v2(37.05,66.35)
DDR_M0_PAR: length 7
  TOP w0.102: RD36.1 35.28,72.91 v2(35.18,72.81) v1(35.18,72.33)
  BOTTOM w0.15: JDIMM1.143 38.5,75.18 38.06,74.73 37.1,74.73 v2(35.18,72.81)
DDR_M0_RCOMP: length 13.2
  IN2 w0.305: v2(78.34,72.04) 77.73,71.43 76.74,71.43 75.66,70.35 75.66,69.24 72.59,66.16 70.2,66.16 v2(69.88,66.48)
  BOTTOM w0.254: UC1.AY29 77.95,71.65 v2(78.34,72.04)
  BOTTOM w0.305: RC38.2 v2(69.88,66.48)
DDR_M1_RCOMP: length 14.3
  IN2 w0.305: v2(69,66.48) 69,66.1 69.69,65.4 72.94,65.4 76.23,68.69 76.23,70.29 76.74,70.8 77.31,70.8 77.59,70.52 v2(77.59,70.23)
  BOTTOM w0.305: v2(77.59,70.23) 77.59,70.24 UC1.AY27 ; RC39.1 v2(69,66.48)
DEVSLP0_HDD: length 129
  TOP w0.102: v2(162.34,46.41) 162.34,45.08 166.38,41.04 v2(176.5,41.04) ; v2(91.79,78.16) 91.86,78.16 92.44,78.75 95.04,78.75 97.25,80.96 v1(97.3,80.96) 97.36,81.02 v2(98.14,81.02)
  IN1 w0.127: v2(98.14,81.02) 98.15,81.02 100.08,79.1 104.34,79.1 105.6,80.36 107.75,80.36 108.07,80.67 109.03,80.67 109.42,80.28 111.24,80.28 115.1,76.43 115.1,66.29 115.24,66.15 115.24,65.74 117.45,63.53 117.45,59.22 119.07,57.59 120.81,57.59 121.07,57.34 121.07,54.89 121.97,53.99 122.94,53.99 124.63,52.29 124.63,51.01 125.91,49.74 127.83,49.74 127.91,49.65 132.18,49.65 133.38,50.86 137.02,50.86 137.62,50.26 141.03,50.26 143.71,47.58 147.92,47.58 148.52,46.98 152.48,46.98 152.59,46.87 161.88,46.87 v2(162.34,46.41) ; v2(186.91,39.42) 186.16,40.18 179.44,40.18 178.16,41.46 176.92,41.46 v2(176.5,41.04)
  BOTTOM w0.089: v2(91.79,78.16) 91.55,77.83 UC1.J43
  BOTTOM w0.102: RS61.1 v2(186.91,39.42)
DIMM_CHA_SA0: length 4.6
  TOP w0.102: v1(34.07,43.94) 33.68,44.33 v2(33.68,44.55) 33.67,44.56 RD1.2 RD4.1
  BOTTOM w0.102: v2(33.68,44.55) 33.64,44.51 32.93,44.51 32.51,44.93 JDIMM1.256
DIMM_CHA_SA1: length 3.9
  TOP w0.102: v1(29.25,43.68) v2(29.74,43.68) 30.36,43.68 RD5.1 RD2.2
  BOTTOM w0.102: JDIMM1.260 30.3,43.93 30.06,43.68 v2(29.74,43.68)
DIMM_CHA_SA2: length 4.8
  TOP w0.102: v2(29.89,67.75) 29.89,67.82 29.99,67.93 RD3.2 RD6.1 32.21,67.93 v1(32.61,68.32)
  BOTTOM w0.102: JDIMM1.166 30.45,67.43 30.13,67.75 v2(29.89,67.75)
DMIC_CLK: length 2
  TOP w0.102: UA1.3 34.63,12.01 35.34,11.3 L5.2
DMIC_CLK_EDP: length 213.6
  TOP w0.102: v2(213.52,45.02) 213.78,45.02 214.1,44.69 D12.3 214.78,44.69 215.08,44.99 v2(215.12,44.99) ; v2(37.82,11.17) 37.88,11.11 38.31,11.11 CA486.1 38.25,11.55 36.97,11.55 L5.1
  IN2 w0.127: v2(215.12,44.99) 215.93,44.18 215.93,36.19 213.9,34.16 210.73,34.16 209.97,33.4 209.97,31.11 209.44,30.59 178.13,30.59 174.88,33.84 153.05,33.84 150.32,31.11 139.97,31.11 134.44,25.59 102.14,25.59 100.78,24.23 86.32,24.23 86.29,24.19 79.99,24.19 v2(79.92,24.27)
  BOTTOM w0.102: JEDP1.31 212.99,45.45 213.43,45.02 v2(213.52,45.02) ; v2(79.92,24.27) 79.87,24.21 65.93,24.21 44.03,24.21 43.04,23.22 40.8,23.22 39.43,21.85 39.43,13.74 38.82,13.13 38.82,11.31 38.62,11.11 37.93,11.11 37.87,11.17 v2(37.82,11.17)
DMIC_DATA: length 2.1
  TOP w0.102: RA46.2 34.63,11.61 UA1.2
DMIC_DATA_EDP: length 214.9
  TOP w0.102: RA46.1 37,10.16 38.25,10.16 CA491.1 38.29,10.63 37.91,10.63 v2(37.87,10.59) ; v2(213.43,45.69) D12.2 v2(215.15,45.69)
  IN2 w0.127: v2(79.92,23.68) 86.5,23.68 86.53,23.72 100.99,23.72 102.35,25.08 134.65,25.08 140.18,30.6 150.53,30.6 153.26,33.33 174.67,33.33 177.92,30.08 209.65,30.08 210.47,30.9 210.47,33.19 210.94,33.65 214.11,33.65 216.44,35.98 216.44,44.64 215.38,45.69 v2(215.15,45.69)
  BOTTOM w0.102: JEDP1.30 213.18,45.95 v2(213.43,45.69) ; v2(79.92,23.68) 79.87,23.73 44.23,23.73 43.24,22.74 41,22.74 39.91,21.65 39.91,13.54 39.3,12.93 39.3,11.11 38.82,10.63 37.96,10.63 37.92,10.59 v2(37.87,10.59)
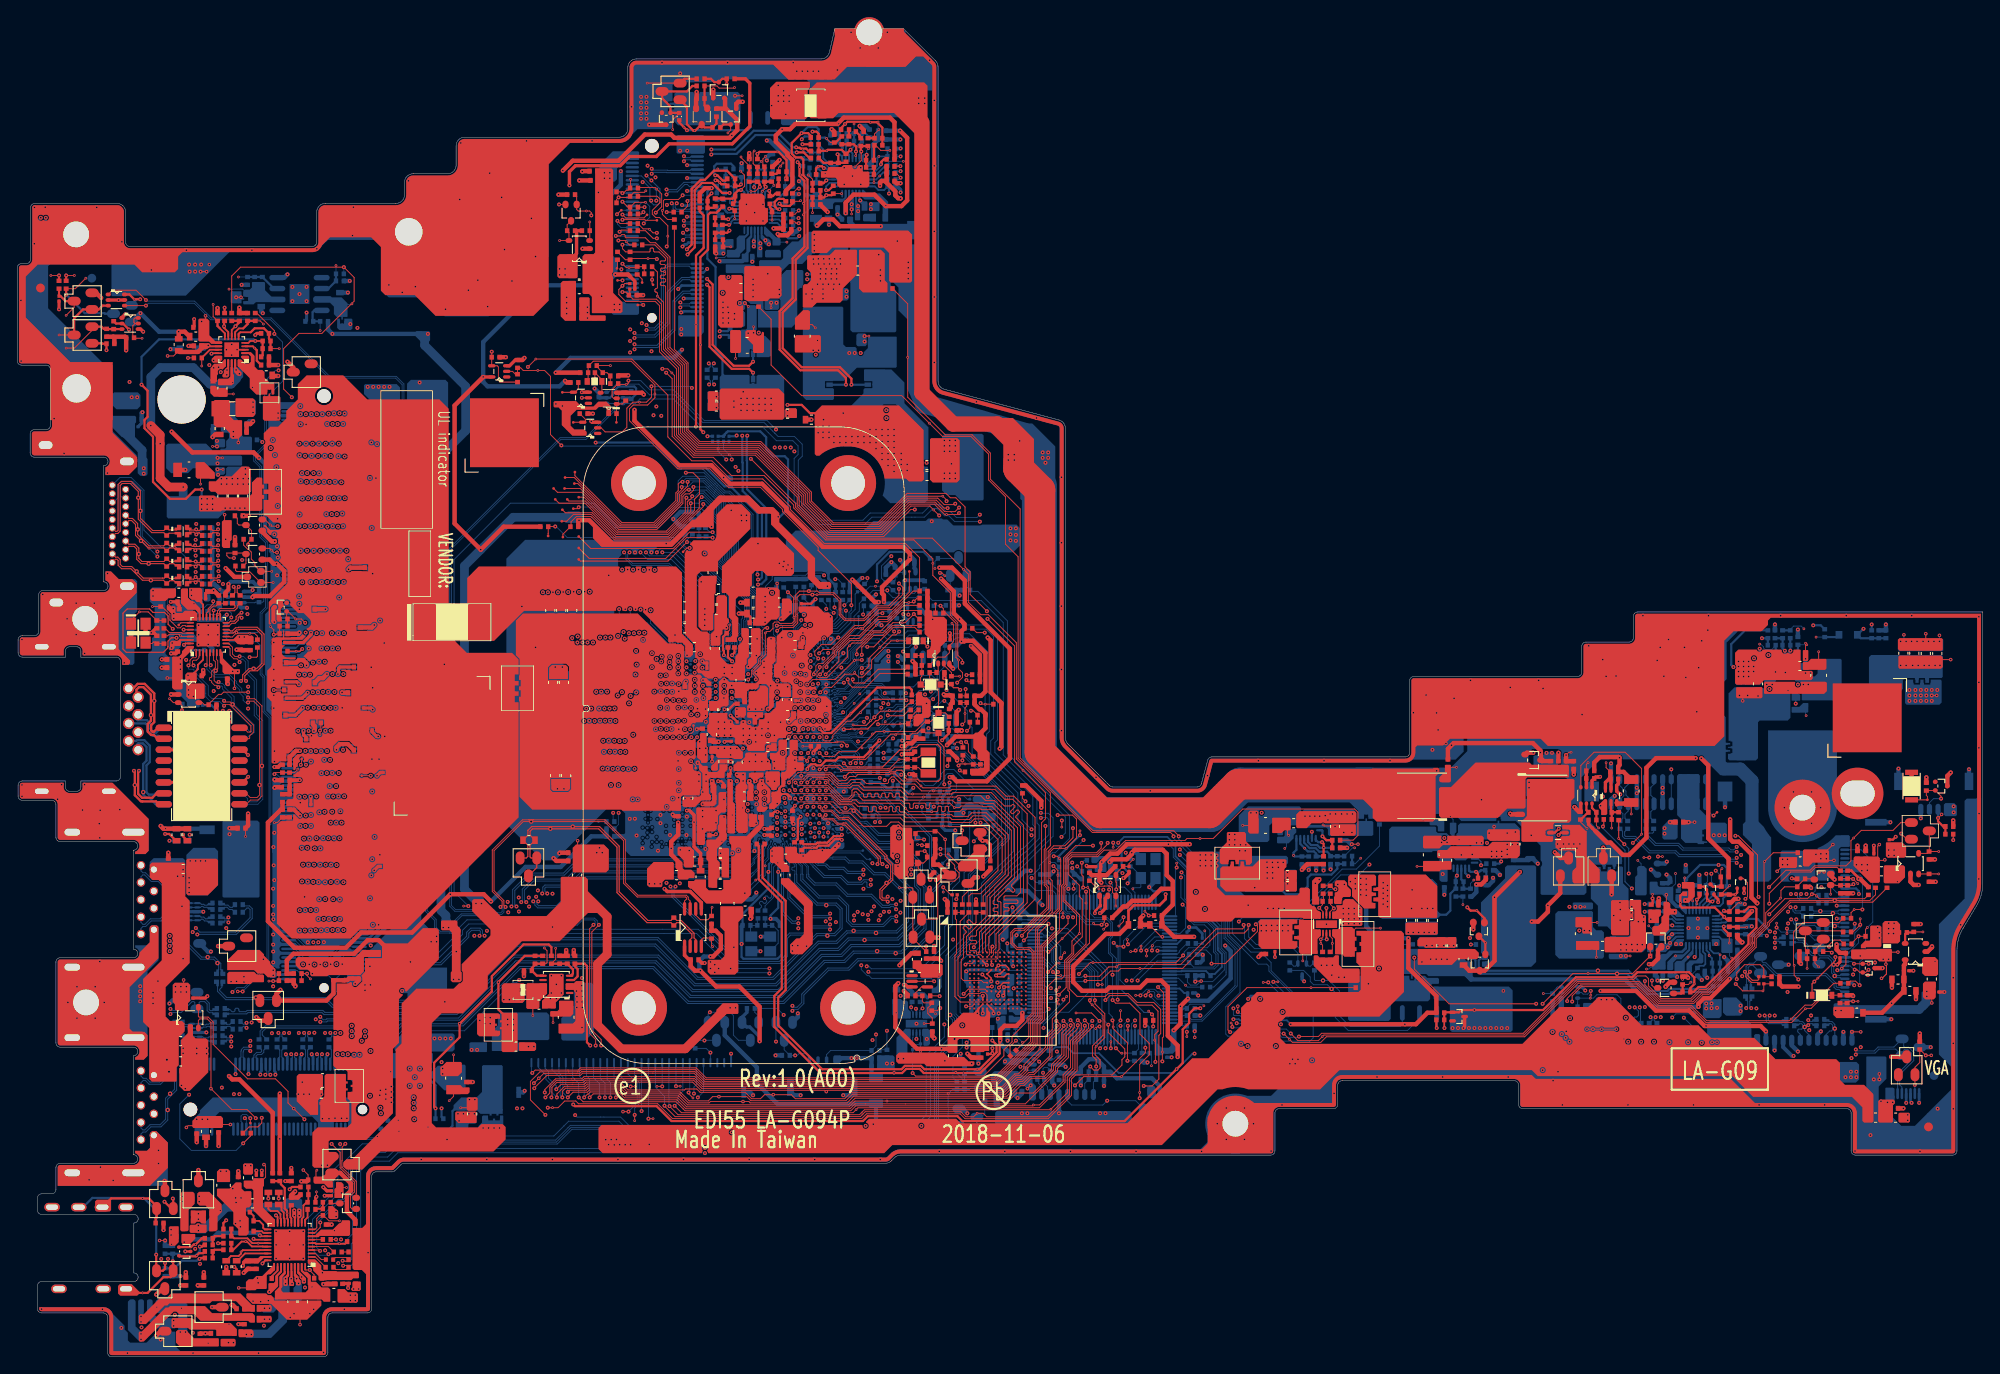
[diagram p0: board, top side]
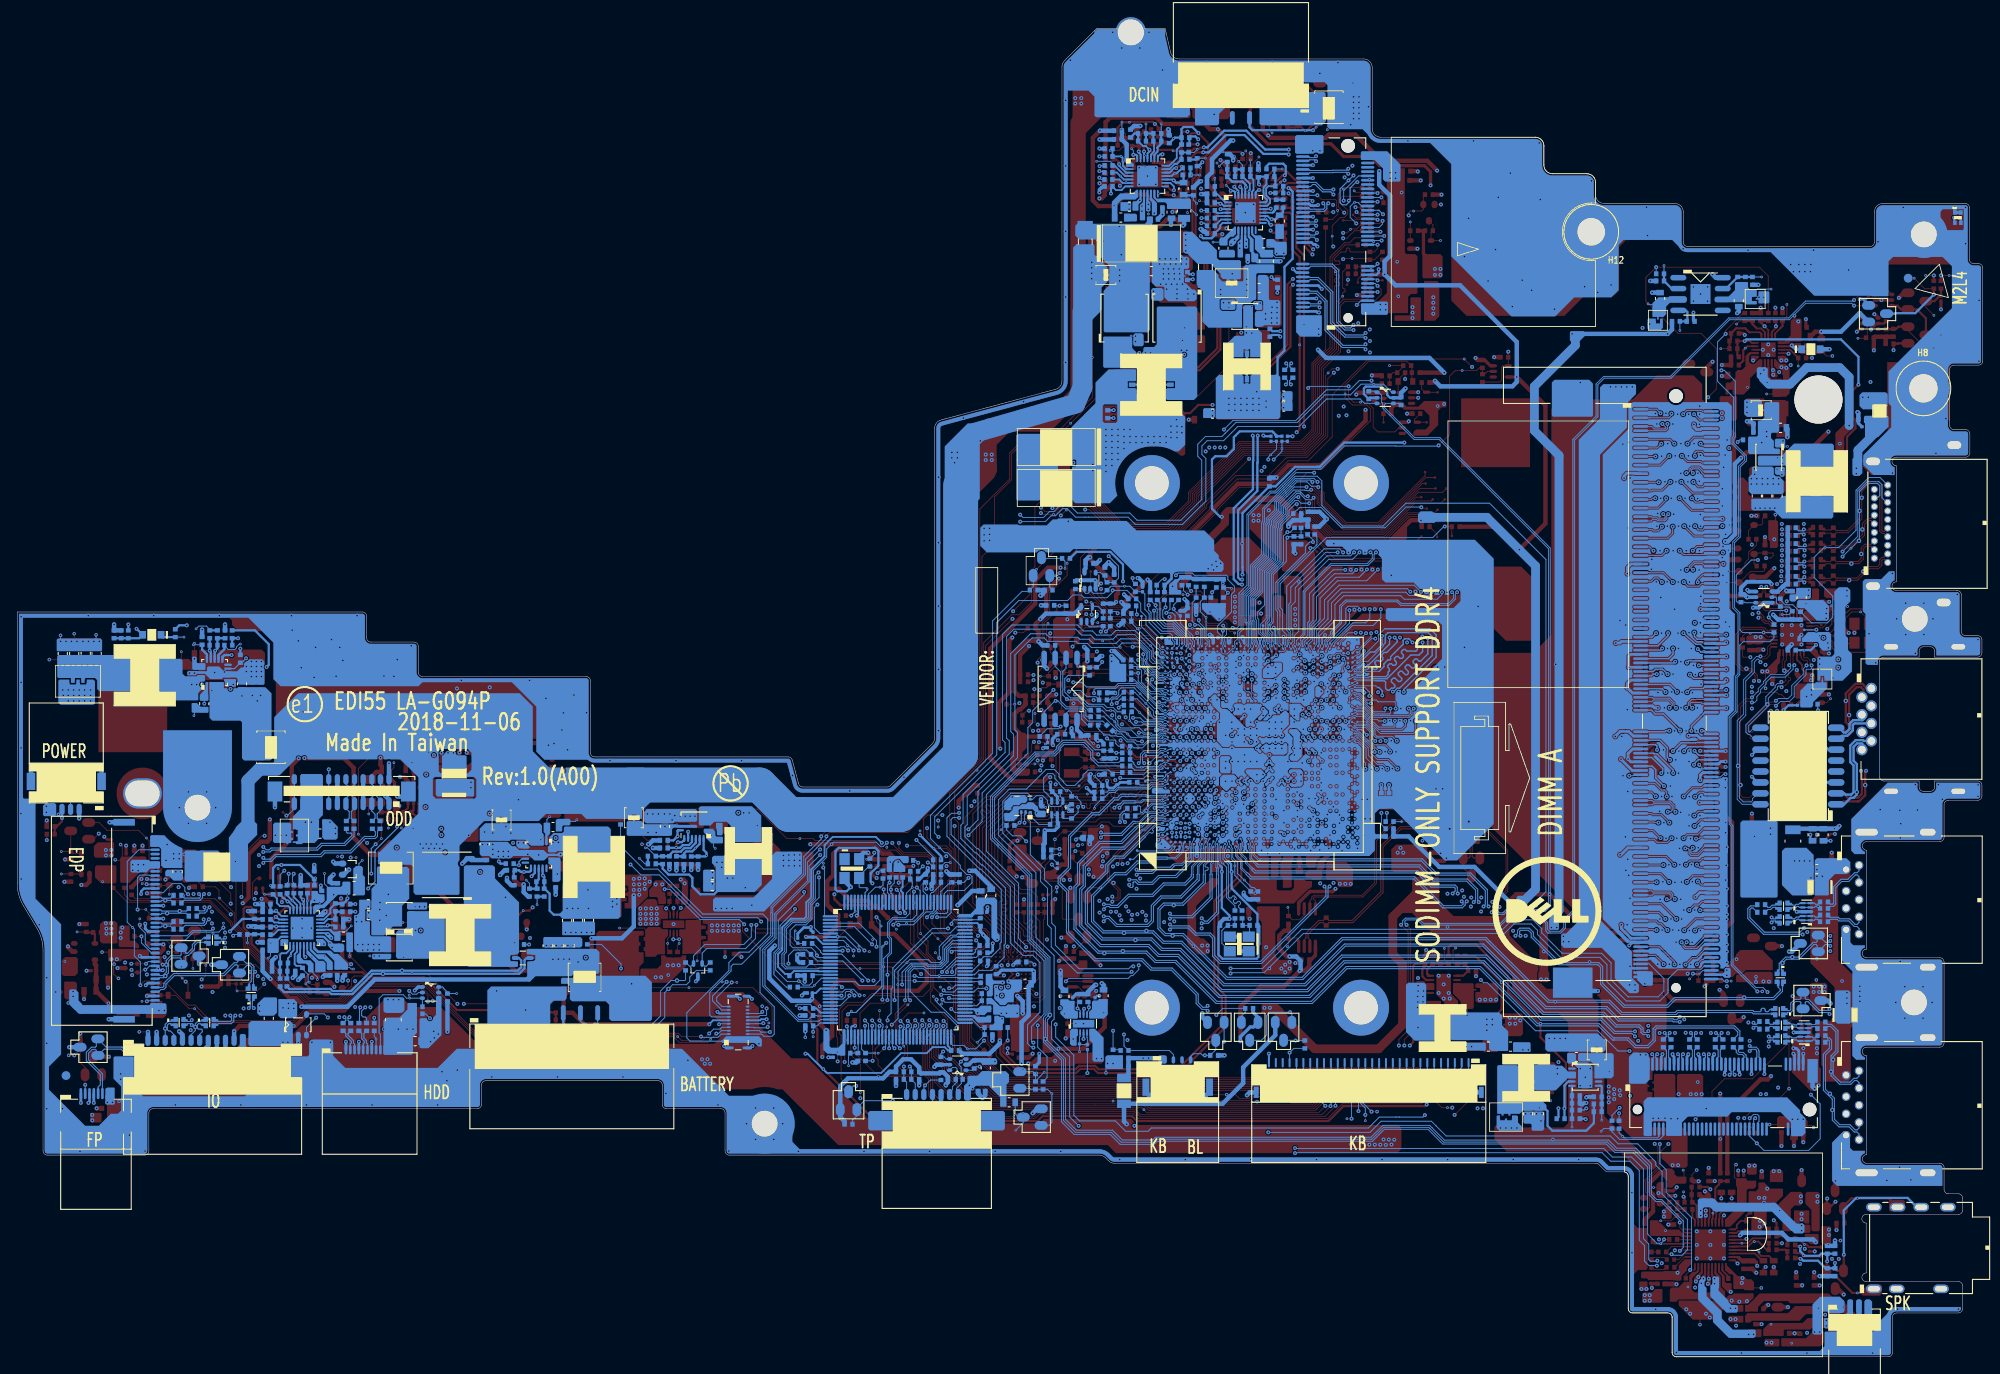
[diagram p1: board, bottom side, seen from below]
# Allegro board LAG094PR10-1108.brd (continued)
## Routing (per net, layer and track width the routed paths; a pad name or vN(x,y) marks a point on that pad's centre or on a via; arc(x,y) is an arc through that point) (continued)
EC_CLR_CMOS: length 26.5
  TOP w0.102: v2(105.62,47.72) RC64.1 104.11,48.62 QC1.2 104.11,49.72 104.07,49.75 QC10.2 104.07,54.44 103.97,54.54 v1(102.52,54.54)
  IN1 w0.127: v2(105.62,47.72) 105.62,45.66 108.32,42.97 111.3,42.97 111.77,42.5 115.45,42.5 v2(115.79,42.84)
  BOTTOM w0.102: UE1.74 117.24,42.42 116.82,42.84 v2(115.79,42.84)
EC_ENVDD: length 122.8
  TOP w0.102: v2(120.89,41.52) 120.89,41.13 v1(121,41.02) ; D4.3 219.57,60.18 v2(218.92,60.83)
  IN1 w0.127: v2(218.92,60.83) 218.92,56.07 215.24,52.38 215.24,46.92 214.47,46.16 213.27,46.16 211.91,44.8 211.91,44.78 211.66,44.53 211.64,44.53 211.59,44.48 204.52,44.48 201.66,41.63 199.89,41.63 195.68,37.42 180.91,37.42 179.27,39.05 163.8,39.05 161.26,36.51 147.03,36.51 146.46,37.08 138.63,37.08 134.95,40.76 128.96,40.76 128.32,40.13 122.28,40.13 v2(120.89,41.52)
  BOTTOM w0.102: v2(120.89,41.52) 120.58,41.22 UE1.71
EC_GPIO65: length 7.7
  TOP w0.102: RE41.1 126.32,50.55 v2(126.01,50.23) 125.23,50.23 v1(125.07,50.4)
  BOTTOM w0.102: v2(126.01,50.23) 124.26,50.23 122.77,51.72 122.08,51.72 121.88,51.92 UE1.102
EC_MUTE#: length 132.8
  TOP w0.102: UA1.40 33.46,10.19 33.56,10.09 v2(34.01,10.09) 34.01,10.03 34.5,9.53 RA8.2 ; v2(120.35,44.73) 120.77,44.32 v1(121.26,44.32)
  IN1 w0.127: v2(37.52,24.74) 37.52,25.97 38.83,27.28 38.83,29.7 42.96,33.82 42.96,38.81 49.17,45.02 53.4,45.02 57.15,48.78 79.4,48.78 87.92,40.25 87.92,38.41 89.98,36.36 97.72,36.36 98.2,35.87 106.74,35.87 108.95,38.09 108.95,38.27 109.74,39.05 110.71,39.05 111.16,38.6 115.35,38.6 116.3,39.56 116.3,40.44 117.64,41.78 117.64,43.75 119.2,45.32 119.95,45.32 120.35,44.92 v2(120.35,44.73)
  BOTTOM w0.102: v2(37.52,24.74) 37.52,22.48 36.79,21.75 36.79,19.13 33.84,16.19 33.84,10.26 v2(34.01,10.09) ; v2(120.35,44.73) 120.35,44.94 119.27,46.02 UE1.83
EC_ON: length 110.7
  TOP w0.254: PQB29.2 170.5,50.98 v1(169.6,51.87) 168.88,51.87 v2(168.5,52.26)
  IN1 w0.127: v2(168.5,52.26) 168.17,52.26 165.73,49.82 161.2,49.82 159.36,47.97 153.1,47.97 152.96,48.12 151.35,48.12 147.84,51.62 147.63,51.62 147.63,51.62 147.21,51.62 147.21,51.62 146.99,51.62 146.99,51.62 142.72,51.62 141.83,52.51 136.43,52.51 135.69,53.25 135.48,53.25 135.14,53.25 135.14,53.25 134.52,53.25 133.98,52.7 127.87,52.7 126.85,53.72 126.79,53.72 v2(126.21,54.3)
  IN2 w0.254: v2(199.42,80.2) 199.36,80.13 199.36,69.81 194.21,64.66 193.99,64.66 189.64,64.66 188.53,63.56 187.58,63.56 187.58,63.56 185.26,63.56 184.88,63.18 184.88,61.59 184.36,61.07 183.47,61.07 182,62.54 178.61,62.54 176.02,59.96 176.02,58.97 171.02,53.97 170.21,53.97 v2(168.5,52.26)
  BOTTOM w0.102: UE1.112 125.88,53.98 v2(126.21,54.3)
  BOTTOM w0.254: PR506.1 200.77,84.46 199.17,82.86 199.17,80.45 v2(199.42,80.2)
EC_RSMRST#: length 38.9
  TOP w0.102: v2(106.27,78.67) 106.03,78.91 RC52.1 CC89.2 107.02,79.75 UC3.1
  IN1 w0.127: v2(117.86,55.68) 116.18,57.37 116.18,63 113.97,65.21 113.97,65.58 113.19,66.35 113.19,76.53 111.46,78.26 110.13,78.26 109.57,78.82 108.39,78.82 108.07,78.51 106.43,78.51 v2(106.27,78.67)
  BOTTOM w0.102: UE1.100 121.08,54.08 120,55.16 CE19.1 RE35.1 118.38,55.16 v2(117.86,55.68)
EC_RST#: length 4.3
  BOTTOM w0.102: UE1.37 130.68,35.35 CE1.1 131.58,35.31 RE1.1 131.8,35.1 v1(131.8,33.84)
EC_RX: length 143.6
  TOP w0.102: v2(74.33,130.68) 73.88,130.68 v1(73.47,131.09) 73.43,131.14 72.74,131.14 RW13.1
  IN1 w0.127: v2(74.33,130.68) 75.81,130.68 76.62,129.87 76.62,126.04 76.84,125.82 76.84,125.81 78.82,123.82 78.82,120.28 82.14,116.96 82.14,109.91 83.12,108.94 87.07,108.94 87.3,108.71 90.61,108.71 93,106.32 93,106.17 93,104.38 93,104.31 92.39,103.7 92.39,99.79 97.34,94.84 109.52,94.84 120.18,84.18 120.18,68.66 123.68,65.16 127.63,61.21 128.56,61.21 129.95,59.81 134.27,59.81 v2(135.1,58.99)
  BOTTOM w0.102: v2(135.1,58.99) 136.58,57.5 136.58,55.31 140.43,51.46 140.43,48.73 141.77,47.4 141.77,43.11 137.68,39.02 135.25,39.02 135.06,39.22 UE1.31
EC_RX_R: length 3.9
  TOP w0.102: RW13.2 70.07,131.76 v2(69.75,132.08)
  BOTTOM w0.102: v2(69.75,132.08) 69.75,131.7 70.15,131.3 JWLAN1.40
EC_SCI#: length 69.4
  TOP w0.102: v1(128.01,50.08) 128.56,50.63 v2(128.56,51.11)
  IN1 w0.127: v2(128.56,51.11) 127.89,51.11 126.3,52.7 125.57,52.7 124.68,53.59 124.68,57.27 123.67,58.29 122.91,58.29 120.16,61.04 120.16,62.05 119.72,62.49 119.72,64.08 116.62,67.18 116.62,80.8 112.8,84.62 111.26,84.62 109.68,86.19 105.03,86.19 104.31,85.47 103.03,85.47 v2(101.9,84.33)
  BOTTOM w0.102: v2(101.9,84.33) 101.38,84.85 RC1143.2 ; UE1.20 131.03,43.62 130.59,43.18 128.77,43.18 128.14,43.81 128.14,50.7 v2(128.56,51.11)
EC_SCI#_SOC: length 14
  TOP w0.089: v2(92.57,79.35) 92.57,79.61 92.81,79.85 92.81,80.32 93.07,80.59 93.6,80.59 94.8,81.78 94.8,82.18 95.99,83.38
  TOP w0.102: 95.99,83.38 97.32,84.7 v1(98.01,84.7) 98.25,84.7 100,86.46 v2(100.53,86.46)
  BOTTOM w0.089: v2(92.57,79.35) 92.56,79.34 92.56,79.29 UC1.H45
  BOTTOM w0.102: v2(100.53,86.46) 100.73,86.66 RC121.1 RC1143.1
EC_SMB_CK1: length 114
  TOP w0.102: v2(124.12,43.71) 124.17,43.76 125.95,43.76 127.04,44.85 127.93,44.85 128.22,45.14 v1(130.46,45.14) 135.4,45.14 139.53,49.27 142.58,49.27 143.04,49.73 143.04,50.15 v2(143.1,50.21)
  IN2 w0.127: v2(196.86,56.16) 196.78,56.09 196.78,55.95 196.78,55.04 199.58,52.25 199.58,46.08 198.07,44.58 192.71,44.58 192.3,44.17 186.95,44.17 185.88,45.24 168.32,45.24 166.68,46.88 158.04,46.88 157.43,47.49 151.19,47.49 147.95,50.73 143.23,50.73 143.05,50.55 143.05,50.26 v2(143.1,50.21)
  BOTTOM w0.102: v2(143.1,50.21) 143.1,48.81 143.98,47.94 148.5,47.94 149.81,46.63 PD5.3 149.81,45.7 150.1,45.42 150.28,45.42 150.71,45.84 PR42.2 ; v2(196.86,56.16) 196.86,56.06 196.88,56.03 196.88,55.22 197.04,55.07 PRB20.1 ; v2(124.12,43.71) 124.12,43.71 123.97,43.71 123.88,43.62 UE1.77 116.72,43.62 116.66,43.56 116.52,43.56 RE36.2
EC_SMB_CK2: length 116.3
  IN2 w0.127: v2(118.95,62.66) 118.87,62.73 118.57,62.73 117.98,63.32 117.98,65.42 115.1,68.3 115.1,90.29 112.37,93.02 112.37,96.59 v2(111.86,97.1)
  BOTTOM w0.102: v2(118.95,62.66) 119,62.71 119.65,62.71 119.88,62.47 119.88,60.72 116.35,57.18 116.22,57.18 113.57,54.53 113.57,48.02 113.72,47.87 113.72,46.45 114.65,45.52 RE38.2 115.13,44.93 116.65,44.93 117.16,44.42 UE1.79 ; v2(111.86,97.1) 108.94,97.1 108.25,97.79 107.74,97.79 106.92,98.61 106.4,98.61 105.41,97.62 104.33,97.62 99.31,97.62 98.47,96.78 92.98,96.78 90.28,99.48 90.28,104.45 90.74,104.91 90.74,105.9 90.13,106.51 88.22,106.51 87.28,107.45 86.57,108.16 79.85,108.16 79.45,108.16 76.25,111.36 72.35,111.36 71.84,110.85 Q11.3
EC_SMB_DA1: length 113.1
  TOP w0.102: v2(142.52,50.21) 142.55,50.17 142.55,49.93 142.38,49.75 139.33,49.75 135.2,45.63 128.02,45.63 v1(127.73,45.33) 126.84,45.33 125.75,44.24 124.17,44.24 v2(124.12,44.29)
  IN2 w0.127: v2(196.27,56.16) 196.27,54.83 197.82,53.29 199.07,52.04 199.07,46.29 197.86,45.09 192.5,45.09 192.09,44.67 187.16,44.67 186.09,45.75 168.53,45.75 166.89,47.39 158.25,47.39 157.64,48 151.4,48 148.16,51.24 143.02,51.24 142.54,50.76 142.54,50.24 v2(142.52,50.21)
  BOTTOM w0.102: PRB19.1 196.25,55.07 196.4,55.22 196.4,55.83 196.37,55.86 196.37,56.06 v2(196.27,56.16) ; v2(124.12,44.29) 124.02,44.19 123.77,44.19 123.68,44.1 118.34,44.1 UE1.78 116.74,44.02 116.52,44.24 RE37.2 ; v2(142.52,50.21) 142.62,50.11 142.62,48.61 143.78,47.46 148.28,47.46 148.81,46.93 PD5.2 148.81,45.7 148.52,45.42 148.33,45.42 147.9,45.84 PR37.2
EC_SMB_DA2: length 118.9
  IN2 w0.127: v2(111.86,97.91) 111.86,97.82 112.87,96.8 112.87,93.23 115.6,90.5 115.6,68.51 118.49,65.63 118.49,63.53 118.78,63.24 v2(118.95,63.24)
  BOTTOM w0.102: v2(118.95,63.24) 119,63.19 119.85,63.19 120.37,62.67 120.37,60.52 116.55,56.7 116.42,56.7 114.05,54.33 114.05,48.22 114.21,48.07 114.21,47.49 115.18,46.52 116.07,46.52 116.51,46.08 RE39.2 116.51,45.75 117.44,44.82 UE1.80 ; Q11.6 68.69,112.15 69.63,113.09 72.23,113.09 73.48,111.84 76.45,111.84 79.65,108.64 86.77,108.64 87.77,107.65 88.07,107.35 88.42,106.99 90.33,106.99 91.22,106.1 91.22,104.71 90.76,104.25 90.76,99.68 93.18,97.26 98.27,97.26 99.11,98.1 105.21,98.1 106.2,99.09 107.12,99.09 107.94,98.27 108.45,98.27 109.14,97.58 111.53,97.58 v2(111.86,97.91)
EC_TP_INT#: length 78.9
  TOP w0.102: v2(130.91,31.49) 131.86,31.49 v1(132.34,31.97) 132.66,32.29 132.66,37.37 132.88,37.59 132.88,40.38 132.05,41.21 130.13,41.21 129.1,42.24 126.77,42.24 126.44,41.91 123.16,41.91 122.3,42.77 122.3,45.8 124.6,48.1 124.6,54.31 124.35,54.56 v2(123.86,54.56) 123.86,54.56 123.86,55.87 123.71,56.03 v2(123.71,57.44) ; DC4.1 105.28,83.06 v2(105.76,82.57)
  IN1 w0.127: v2(123.71,57.44) 123.71,57.62 123.29,58.03 122.8,58.03 119.91,60.93 119.91,61.94 119.46,62.39 119.46,63.98 116.37,67.08 116.37,77 111.16,82.2 106.14,82.2 v2(105.76,82.57)
  BOTTOM w0.102: v2(130.91,31.49) 131.23,31.49 131.8,30.92 Q9.1 ; UE1.106 123.48,54.18 123.86,54.56 v2(123.86,54.56) ; RE32.1 123.99,57.72 v2(123.71,57.44)
EC_TX: length 142.5
  TOP w0.102: RW14.1 73,130.93 73.88,130.04 v2(74.33,130.04)
  IN1 w0.127: v2(135.1,58.35) 133.89,59.56 129.85,59.56 128.45,60.96 127.52,60.96 119.92,68.55 119.92,84.07 109.41,94.59 97.21,94.59 92.14,99.66 92.14,103.81 92.74,104.42 92.74,104.49 92.74,106.21 90.5,108.45 87.19,108.45 86.96,108.68 82.99,108.68 81.89,109.79 81.89,116.84 78.57,120.15 78.57,123.72 76.59,125.71 76.59,125.71 76.36,125.94 76.36,129.6 75.92,130.04 v2(74.33,130.04)
  BOTTOM w0.102: v2(135.1,58.35) 136.38,57.07 136.38,55.23 140.23,51.38 140.23,48.65 141.51,47.37 141.51,43.15 137.59,39.23 136.44,39.23 135.99,39.68 RE29.1 135.5,39.68 135.44,39.62 UE1.30
EC_TX_R: length 2.8
  TOP w0.102: RW14.2 71.14,131 70.19,131 v2(70,130.81)
  BOTTOM w0.102: JWLAN1.38 70,130.8 v2(70,130.81)
ECAGND: length 64.9
  TOP w0.254: v2(114.22,36.76) 114.16,36.7 114.16,35.26 113.98,35.09 113.98,35.08 113.98,35.06 111.91,32.99 v1(109.95,32.99) 105.34,32.99 104.86,33.47 103.3,33.47 102.82,32.99 93.35,32.99 87.98,38.36 87.98,41.96 88.85,42.83 88.85,52.83 86.17,55.51 86.17,59.39 PH1.2
  TOP w0.508: v2(114.22,36.76) 114.22,37.98 114.72,38.48 116.11,38.48 116.8,39.16 v2(116.8,39.99)
  BOTTOM w0.508: v2(114.22,36.76) 114.22,36.43 115.41,35.24 118.58,35.24 CE17.1
EDP_AUXN: length 166.6
  IN1 w0.089: v2(86.82,64.85) 86.95,64.98 86.95,65.19 86.86,65.28 86.59,65.28 86.44,65.12 86.44,62.82 86.89,62.37 86.89,62.02 86.44,61.58 86.44,60.51 86.46,60.49
  IN1 w0.127: 86.46,60.49 86.47,60.48 86.47,60.47 86.56,60.38 86.56,60.32 87.06,59.82 87.06,57.91 87.58,57.4 90.71,57.4 91.73,56.38 95.59,56.38 98.31,53.66 99.61,53.66 100.25,53.03 100.25,51.92 100.42,51.74 v2(100.71,51.74)
  IN2 w0.127: v2(100.71,51.74) 100.75,51.71 100.75,51.26 101.7,50.3 101.7,49.14 106.02,44.83 106.02,40.7 107.35,39.37 112.9,39.37 113.72,38.55 117.24,38.55 118.53,37.27 136.88,37.27 140.8,41.19 146.91,41.19 150.55,37.56 176.66,37.56 176.67,37.55 176.67,37.55 177.71,36.51 178.67,36.51 180.26,34.92 202.42,34.92 205.41,37.92 205.41,41.53 204.94,42 204.94,52.56 205.53,53.14 206.59,53.14 206.86,53.41 206.86,53.65 v2(206.7,53.81)
  BOTTOM w0.089: UC1.W15 v2(86.82,64.85)
  BOTTOM w0.114: C10.1 209,53.09 207.15,53.09 206.87,53.37 206.87,53.64 v2(206.7,53.81)
EDP_AUXN_C: length 2.3
  BOTTOM w0.114: C10.2 210.54,53.08 v4(211.2,53.08) 211.58,53.08 211.7,52.95 JEDP1.16
EDP_AUXP: length 166.6
  IN1 w0.089: v2(86.82,65.64) 86.63,65.46 86.52,65.46 86.26,65.19 86.26,62.75 86.71,62.29 86.71,62.1 86.27,61.65 86.27,60.31
  IN1 w0.127: v2(100.3,51.33) 100.3,51.49 99.98,51.81 99.98,52.92 99.5,53.4 98.21,53.4 95.48,56.12 91.62,56.12 90.6,57.14 87.47,57.14 86.8,57.8 86.8,59.71 86.3,60.21 86.3,60.28 86.27,60.31
  IN2 w0.127: v2(100.3,51.33) 100.48,51.15 101.43,50.19 101.43,49.03 105.75,44.72 105.75,40.59 107.24,39.1 112.79,39.1 113.61,38.29 117.14,38.29 118.42,37.01 136.99,37.01 140.91,40.93 146.8,40.93 150.44,37.3 176.55,37.3 176.56,37.28 176.56,37.28 177.6,36.24 178.56,36.24 180.15,34.66 202.53,34.66 205.68,37.81 205.68,41.64 205.2,42.11 205.2,52.45 205.64,52.88 206.7,52.88 207.12,53.3 207.12,53.65 v2(207.28,53.81)
  BOTTOM w0.089: v2(86.82,65.64) UC1.W17
  BOTTOM w0.114: v2(207.28,53.81) 207.11,53.64 207.11,53.48 207.26,53.33 209,53.33 C11.1
EDP_AUXP_C: length 2.3
  BOTTOM w0.114: C11.2 210.56,53.32 211.58,53.32 211.7,53.45 JEDP1.15
EDP_BKLT_CTRL: length 3.8
  TOP w0.102: D3.2 209.86,48.23 208.94,47.3 R8.2 208.9,47.07 R9.2 208.9,45.77 v1(209.33,45.33)
EDP_HPD: length 4.8
  TOP w0.102: v1(210.72,53.78) Q5027.2 211.26,54.84 211.3,54.81 RT29.1 CT14.1 213.23,54.81 v2(213.37,54.95)
  BOTTOM w0.102: JEDP1.12 v2(213.37,54.95)
EDP_HPD#: length 146.2
  TOP w0.102: v2(189.14,43.68) 189.14,43.25 190.92,41.47 194.57,41.47 195.6,42.51 196.38,42.51 201.66,47.79 201.66,48.78 203.18,50.31 203.18,51.62 v1(204.89,53.33) 204.95,53.38 204.95,54.22 205.37,54.64 RT31.1 206.84,54.71 207.7,55.57 RT28.1 208.75,55.57 Q5027.1
  IN1 w0.127: v2(95.72,76.11) 100.02,76.11 100.34,76.42 101.27,76.42 102.98,74.71 110.28,74.71 111.59,73.4 111.59,64.97 114.65,61.91 114.65,56.41 119.38,51.68 120.26,51.68 121.28,50.66 122.11,50.66 125.06,47.71 126.17,47.71 126.95,46.92 129,46.92 129.76,47.68 132.89,47.68 133.13,47.44 138.47,47.44 140.9,45.02 142.14,45.02 143.25,43.91 144.4,43.91 145.61,42.7 173.01,42.7 174.18,43.87 188.95,43.87 v2(189.14,43.68)
  BOTTOM w0.089: UC1.B39 95.69,76.08 v2(95.72,76.11)
EDP_RCOMP_N: length 1.5
  TOP w0.381: v2(86.82,61.37) 87.52,61.37 RC1.2
  BOTTOM w0.203: UC1.AA7 v2(86.82,61.37)
EDP_RCOMP_P: length 1.5
  TOP w0.381: RC1.1 87.56,60.66 v2(86.82,60.66)
  BOTTOM w0.203: UC1.AA5 v2(86.82,60.66)
EDP_TXN0: length 171.6
  IN1 w0.127: v2(84.89,64.27) 84.74,64.13 84.33,64.13 83.87,63.67 83.87,60.06 84.26,59.67 84.26,56.24 86.22,54.28 94.29,54.28 v2(97.25,51.32)
  IN2 w0.127: v2(97.25,51.32) 98.13,50.44 98.13,49.61 101.69,46.05 101.69,40.16 102.25,39.59 102.25,37.08 108.68,30.66 134.5,30.66 136.94,33.09 145.84,33.09 147.8,35.05 151.46,35.05 152.23,35.82 176.06,35.82 177.08,34.8 177.72,34.8 179.64,32.88 203.67,32.88 207.44,36.65 207.44,42.37 207.97,42.9 207.97,51.05 207.4,51.62 206.82,51.62 206.64,51.79 v2(206.64,52.26)
  BOTTOM w0.089: UC1.AE13 84.88,64.27 84.88,64.27 v2(84.89,64.27)
  BOTTOM w0.114: v2(206.64,52.26) 206.59,52.21 206.59,51.94 206.69,51.84 207.25,51.84 C6.1
EDP_TXN0_C: length 4.1
  BOTTOM w0.114: C6.2 208.76,51.82 v4(209.52,51.82) 211.58,51.82 211.7,51.95 JEDP1.18
EDP_TXN1: length 170.3
  IN1 w0.089: v2(85.86,65.64) 85.68,65.46 85.5,65.46 85.2,65.16 85.2,64.65 85.3,64.55 85.3,63.24 85.26,63.2 85.26,63.18
  IN1 w0.127: 85.26,63.18 85.26,62.4 85.18,62.32 85.18,60.75 84.97,60.54 84.97,56.54 86.41,55.1 95.26,55.1 98.86,51.5 v2(98.86,51.38)
  IN2 w0.127: v2(206.73,50.86) 206.73,50.41 207,50.13 207,47.83 206.55,47.38 206.55,36.84 203.41,33.7 180.01,33.7 178.17,35.55 177.31,35.55 176.35,36.51 151.94,36.51 151.17,35.74 147.48,35.74 145.52,33.79 136.65,33.79 134.86,32 108.32,32 103.01,37.31 103.01,41.75 103.66,42.4 103.66,45.54 99.4,49.8 99.4,50.91 98.92,51.38 v2(98.86,51.38)
  BOTTOM w0.089: UC1.AC17 v2(85.86,65.64)
  BOTTOM w0.114: C8.1 209.13,50.41 206.76,50.41 206.66,50.51 206.66,50.8 v2(206.73,50.86)
EDP_TXN1_C: length 2.3
  BOTTOM w0.114: C8.2 210.51,50.32 211.58,50.32 211.7,50.45 JEDP1.21
EDP_TXP0: length 171.6
  IN1 w0.127: v2(97.66,51.74) 97.62,51.77 97.17,51.77 94.4,54.54 86.33,54.54 84.52,56.35 84.52,59.78 84.13,60.17 84.13,63.56 84.44,63.86 84.77,63.86 84.89,63.75 v2(84.89,63.51)
  IN2 w0.127: v2(206.06,52.26) 206.06,52.23 206.38,51.91 206.38,51.69 206.71,51.36 207.29,51.36 207.7,50.94 207.7,43.01 207.17,42.48 207.17,36.75 203.56,33.14 179.75,33.14 177.99,34.91 177.83,35.06 177.19,35.06 176.17,36.08 152.12,36.08 151.35,35.31 147.69,35.31 145.73,33.35 136.83,33.35 134.39,30.92 108.79,30.92 102.52,37.19 102.52,39.7 101.95,40.27 101.95,46.16 98.4,49.72 98.4,50.55 97.67,51.27 97.67,51.72 v2(97.66,51.74)
  BOTTOM w0.089: UC1.AE12 84.69,63.86 84.89,63.67 v2(84.89,63.51)
  BOTTOM w0.114: C7.1 207.18,51.6 206.59,51.6 206.34,51.84 206.34,51.98 v2(206.06,52.26)
EDP_TXP0_C: length 4.1
  BOTTOM w0.114: JEDP1.19 211.7,51.45 211.58,51.58 v4(210.98,51.58) 208.79,51.58 C7.2
EDP_TXP1: length 170.2
  IN1 w0.089: 85.52,63.18 85.52,63.2 85.48,63.24 85.48,64.63 85.38,64.73 85.38,65.09 85.57,65.29 85.76,65.29 85.86,65.18 v2(85.86,64.93)
  IN1 w0.127: 85.52,63.18 85.52,62.29 85.44,62.21 85.44,60.64 85.24,60.43 85.24,56.65 86.52,55.37 95.37,55.37 98.94,51.8 v2(99.27,51.8)
  IN2 w0.127: v2(206.13,50.86) 206.46,50.53 206.46,50.3 206.74,50.02 206.74,47.94 206.28,47.49 206.28,36.94 203.31,33.97 180.12,33.97 178.28,35.81 177.42,35.81 176.46,36.78 151.83,36.78 151.06,36.01 147.37,36.01 145.41,34.05 136.54,34.05 134.75,32.26 108.43,32.26 103.27,37.42 103.27,41.64 103.92,42.29 103.92,45.65 99.67,49.91 99.67,51.02 99.3,51.39 99.3,51.77 v2(99.27,51.8)
  BOTTOM w0.089: UC1.AC15 v2(85.86,64.93)
  BOTTOM w0.114: v2(206.13,50.86) 206.42,50.57 206.42,50.41 206.66,50.17 208.87,50.17 C9.1
EDP_TXP1_C: length 2.3
  BOTTOM w0.114: C9.2 210.59,50.08 v4(211.2,50.08) 211.58,50.08 211.7,49.95 JEDP1.22
EDP_VDD_EN: length 167.7
  TOP w0.102: v2(203.55,54.61) 205.52,56.57 208.34,56.57 208.85,57.08 212.51,57.08 213.08,57.65 213.08,60 v1(213.39,60.32) 214.28,61.21 217.97,61.21 218.87,62.11 D4.2
  IN1 w0.127: v2(203.55,54.61) 202.3,54.61 201.6,55.3 192.92,55.3 192.15,54.53 188.86,54.53 187.86,55.52 183.45,55.52 182.38,54.45 181.94,54.45 180.6,54.45 180.6,54.45 178.8,54.45 178.7,54.35 178.7,54.35 178.55,54.2 178.1,54.2 177.4,54.2 173.83,54.2 172.05,52.42 170.34,52.42 168.83,50.91 168.26,50.91 167.33,49.98 167.33,46.39 166.15,45.21 161.11,45.21 159.73,46.58 156.72,46.58 155.81,45.68 154.61,45.68 153.72,46.57 148.57,46.57 147.81,47.33 143.81,47.33 143.2,47.33 140.52,50.01 137.52,50.01 136.96,50.56 133.45,50.56 132.28,49.4 127.81,49.4 127.72,49.48 125.8,49.48 124.38,50.91 124.38,52.16 122.81,53.73 121.87,53.73 121.19,54.41 121.05,54.55 121.05,54.55 116.94,58.66 116.94,63.32 114.73,65.53 114.73,65.89 114.59,66.03 114.59,71.43 114.02,72 114.02,76.79 111.03,79.78 109.17,79.78 108.98,79.58 108.38,79.58 108.11,79.85 105.81,79.85 104.55,78.59 99.81,78.59 98.32,80.08 v2(98.14,80.08)
  BOTTOM w0.089: UC1.C41 94.6,76.98 94.78,77.17 94.93,77.27 95.06,77.27 95.2,77.17 95.21,77.16 95.42,77.16 95.61,77.34 96.67,77.34 ; v2(98.14,80.08) 98.32,80.26 98.53,80.26
  BOTTOM w0.102: RC158.2 98.53,80.26 ; v2(98.14,80.08) 98.03,80.08 97.76,79.81 97.76,78.44 96.67,77.34
EMMC_0_CLK: length 35.7
  TOP w0.089: 95.56,63.22 95.99,63.22 ; v2(91.1,63.95) 91.49,64.34 94.44,64.34 94.83,63.95
  TOP w0.102: 95.99,63.22 96.79,63.22 98.33,61.68 101.02,61.68 101.52,62.18 102.43,62.18 102.9,61.71 v1(107.6,61.71) 108.21,61.71 108.28,61.64 110.01,61.64 111.13,61.64 111.18,61.69 112.41,61.69 113.97,60.13 113.97,56.57 113.88,56.49 113.7,56.31 113.7,56.31 113.69,56.29 112.78,55.38 112.78,55.38 111.72,54.33 110.67,54.33 109.83,53.49 RM14.1 ; 94.83,63.95 95.56,63.22
  BOTTOM w0.089: UC1.J13 v2(91.1,63.95)
EMMC_0_CLK_R: length 16.3
  TOP w0.089: 110.52,41.25 112.95,41.25 UM1.M6
  TOP w0.102: CM8.2 109.01,50.92 109.15,50.78 109.15,46.88 108.96,46.69 108.96,41.88 109.6,41.25 110.52,41.25 ; CM8.2 109.03,51.67 RM14.2 ; CM8.2 RM13.2
EMMC_0_CMD: length 37.1
  TOP w0.089: 96.89,63.71 96.76,63.71 96.51,63.45 95.9,63.45 94.83,64.52 90.78,64.52 v2(90.39,64.9)
  TOP w0.102: 96.89,63.71 96.99,63.71 98.03,62.66 102.63,62.66 103.1,62.19 108.41,62.19 108.48,62.12 110.21,62.12 110.8,62.12 111.22,62.54 112.24,62.54 114.45,60.33 v1(114.45,59.56) 114.45,56.37 114.23,56.15 113.9,55.82 113.89,55.81 112.98,54.9 112.98,54.9 111.93,53.84 110.87,53.84 110.59,53.56 RM15.1
  BOTTOM w0.089: UC1.M13 v2(90.39,64.9)
EMMC_0_CMD_R: length 14.6
  TOP w0.089: 110.52,42.18 110.59,42.24 111.88,42.24 111.99,42.35 112.42,42.35 112.7,42.06 UM1.M5
  TOP w0.102: RM15.2 110.59,51.65 109.57,50.63 109.57,46.73 109.32,46.48 109.32,42.03 109.59,41.76 110.11,41.76 110.52,42.18
EMMC_0_DATA0: length 49.3
  TOP w0.089: 95.86,64.76 94.21,66.41 90.8,66.41 v2(90.44,66.77) ; 111.82,47.46 111.82,47.11 UM1.A3
  TOP w0.102: 111.82,47.46 111.82,49.38 113.41,50.96 113.41,51.28 113.51,51.38 113.85,51.38 113.95,51.48 113.95,51.68 113.85,51.78 113.51,51.78 113.41,51.89 113.41,52.09 113.51,52.19 113.85,52.19 113.95,52.29 113.95,52.5 113.88,52.57 113.84,52.57 113.82,52.6 113.51,52.6 113.41,52.7 113.41,52.98 113.53,53.11 113.53,53.36 115.87,55.7 115.87,61.36 113.27,63.97 112.22,63.97 112.15,64.04 109.68,64.04 109.49,63.86 v1(108.89,63.86) 108.38,64.37 108.23,64.37 107.05,64.37 107.05,64.37 106.1,64.37 105.99,64.27 105.99,63.84 105.89,63.74 105.69,63.74 105.59,63.84 105.59,64.27 105.49,64.37 104.22,64.37 104.12,64.27 104.12,63.84 104.02,63.74 103.82,63.74 103.72,63.84 103.72,64.27 103.62,64.37 103.11,64.37 102.9,64.58 102.76,64.71 98.27,64.71 97.98,65 97.81,65.17 97.81,65.37 97.49,65.69 97.34,65.69 97.24,65.59 97.24,65.27 96.73,64.76 95.86,64.76
  BOTTOM w0.089: UC1.M19 v2(90.44,66.77)
EMMC_0_DATA1: length 49.7
  TOP w0.089: 95.47,65.46 94.31,66.63 94.31,66.92 94.1,67.13 93.74,67.13 93.7,67.17 92.92,67.17 v2(92.52,66.77) ; UM1.A4 112.2,47.43
  TOP w0.102: 112.2,47.43 112.18,47.46 112.18,49.2 114.31,51.33 114.31,52.82 114.21,52.92 113.99,52.92 113.89,53.03 113.89,53.21 115.09,54.42 115.24,54.42 115.63,54.03 115.79,54.03 115.92,54.16 115.92,54.31 115.53,54.7 115.53,54.85 116.23,55.55 116.23,61.51 113.42,64.32 112.37,64.32 112.29,64.4 108.99,64.4 108.66,64.73 v1(107.41,64.73) 107.2,64.73 103.25,64.73 102.91,65.07 102.59,65.07 102.49,65.17 102.49,65.43 102.39,65.53 102.19,65.53 102.09,65.43 102.09,65.17 101.98,65.07 101.78,65.07 101.68,65.17 101.68,65.43 101.58,65.53 101.37,65.53 101.27,65.43 101.27,65.17 101.17,65.07 100.97,65.07 100.87,65.17 100.87,65.43 100.77,65.53 100.56,65.53 100.46,65.43 100.46,65.17 100.36,65.07 100.16,65.07 100.05,65.17 100.05,65.43 99.95,65.53 99.75,65.53 99.65,65.43 99.65,65.17 99.55,65.07 99.33,65.07 99.23,65.17 99.23,65.43 99.13,65.53 98.93,65.53 98.82,65.43 98.82,65.17 98.72,65.07 98.41,65.07 98.33,65.15 98.33,65.43 98.23,65.53 98.15,65.53 97.64,66.04 97.2,66.04 97,65.85 97,65.34 96.61,64.95 95.99,64.95 95.47,65.46
  BOTTOM w0.089: UC1.H19 v2(92.52,66.77)
EMMC_0_DATA2: length 49.4
  TOP w0.089: 112.53,47.84 112.53,47.17 UM1.A5 ; v2(91.81,66.77) 92.39,67.35 94.16,67.35 95.35,66.16 96.16,66.16
  TOP w0.102: 96.16,66.16 96.81,66.16 97.05,66.4 97.78,66.4 98.3,65.88 102.61,65.88 103.41,65.08 v1(105.32,65.08) 107.35,65.08 107.35,65.08 108.7,65.08 108.7,65.08 109.12,65.08 109.27,65.24 111.96,65.24 112.52,64.68 113.56,64.68 116.58,61.66 116.58,54 116.18,53.59 114.77,53.59 114.66,53.48 114.66,53.22 114.77,53.11 116.18,53.11 116.28,53.01 116.28,52.81 116.18,52.71 114.77,52.71 114.66,52.61 114.66,52.34 114.77,52.24 115.15,52.24 115.25,52.14 115.25,51.93 115.15,51.83 114.77,51.83 114.66,51.73 114.66,51.18 112.53,49.05 112.53,47.84
  BOTTOM w0.089: UC1.J19 v2(91.81,66.77)
EMMC_0_DATA3: length 48.8
  TOP w0.089: UM1.B2 110.95,46.75 110.52,46.75 ; 97.25,64.38 95.6,64.38 94.51,65.47 90.12,65.47 v2(89.74,65.86)
  TOP w0.102: 110.52,46.75 110.4,46.75 110.31,46.84 110.31,48.87 112.7,51.26 112.7,53.53 115.16,55.99 115.16,60.7 112.61,63.25 110.92,63.25 110.5,62.84 108.77,62.84 108.58,63.03 v1(107.79,63.03) 103.44,63.03 103.1,63.37 102.63,63.37 102.53,63.47 102.53,63.9 102.43,64 102.22,64 102.12,63.9 102.12,63.47 102.02,63.37 101.82,63.37 101.72,63.47 101.72,63.9 101.61,64 101.41,64 101.31,63.9 101.31,63.47 101.21,63.37 99.91,63.37 99.81,63.47 99.81,63.9 99.71,64 99.51,64 99.4,63.9 99.4,63.47 99.3,63.37 99.01,63.37 98.9,63.47 98.9,63.9 98.8,64 97.7,64 97.31,64.38 97.25,64.38
  BOTTOM w0.089: UC1.P17 v2(89.74,65.86)
EMMC_0_DATA4: length 53.2
  TOP w0.089: v2(89.68,66.77) 89.68,66.87 90.74,67.93 91.44,67.93 91.47,67.89 94.57,67.89 ; UM1.B3 111.95,46.25 113.84,46.25 113.95,46.36 113.95,47.2
  TOP w0.102: 113.95,47.2 114.09,47.34 114.09,49.02 118.27,53.2 118.27,62.72 115.81,65.18 114.89,65.18 113.72,66.35 108.5,66.35 108.29,66.15 105.24,66.15 v1(105.02,66.37) 104.44,66.95 102.88,66.95 102.08,67.75 102.04,67.79 101.48,67.79 101.41,67.71 97.69,67.71 97.44,67.47 96.73,67.47 96.4,67.13 96.39,67.13 96.24,66.98 95.48,66.98 94.57,67.89
  BOTTOM w0.089: UC1.P19 v2(89.68,66.77)
EMMC_0_DATA5: length 49.3
  TOP w0.089: 110.66,47.43 110.66,47.33 110.75,47.25 111.35,47.25 111.45,47.14 111.45,46.86 111.56,46.75 111.95,46.75 UM1.B4 ; 95.12,65.18 94.32,65.98 94.32,66 94.11,66.21 94.09,66.21 94.08,66.23 91.47,66.23 v2(91.1,65.86)
  TOP w0.102: 110.66,47.43 110.66,47.91 110.77,48.01 111.36,48.01 111.46,48.11 111.46,48.32 111.36,48.42 110.77,48.42 110.66,48.52 110.66,48.72 110.85,48.91 111.36,48.91 111.46,49.01 111.46,49.52 113.05,51.11 113.05,53.38 115.52,55.84 115.52,61.22 113.12,63.61 112.08,63.61 112,63.69 109.83,63.69 109.52,63.38 108.33,63.38 108.23,63.48 108.23,63.91 108.13,64.01 107.92,64.01 107.82,63.91 107.82,63.48 107.72,63.38 107.52,63.38 107.42,63.48 107.42,63.91 107.31,64.01 107.07,64.01 106.97,63.91 106.97,63.48 106.87,63.38 v1(106.27,63.38) 103.59,63.38 102.62,64.36 97.84,64.36 97.46,64.74 97.1,64.74 96.93,64.57 95.73,64.57 95.12,65.18
  BOTTOM w0.089: UC1.J15 v2(91.1,65.86)
EMMC_0_DATA6: length 49.2
  TOP w0.089: UM1.B5 112.95,46.75 112.95,47.34 112.9,47.39 112.9,47.84 ; v2(91.1,66.77) 91.22,66.77 91.98,67.53 94.29,67.53 95.41,66.42 96.7,66.42 97.04,66.76 97.13,66.76
  TOP w0.102: 112.9,47.84 112.9,48.84 116.94,52.88 116.94,61.81 116.04,62.71 116.04,62.85 116.45,63.26 116.45,63.41 116.3,63.57 116.15,63.57 115.74,63.15 115.59,63.15 115.45,63.29 115.45,63.44 115.93,63.92 115.93,64.06 115.78,64.2 115.64,64.2 115.48,64.05 114.71,64.05 113.72,65.03 113.72,65.07 113.21,65.59 108.74,65.59 108.59,65.44 108.55,65.44 108.08,65.44 v1(104.05,65.44) 103.56,65.44 102.76,66.24 98.45,66.24 97.93,66.76 97.13,66.76
  BOTTOM w0.089: UC1.L17 v2(91.1,66.77)
EMMC_0_DATA7: length 50.9
  TOP w0.089: 97.13,67.11 96.89,67.11 96.45,66.67 95.47,66.67 94.43,67.71 91.86,67.71 91.31,67.17 90.28,67.17 90.06,66.95 90.06,66.22 v2(90.39,65.89) ; UM1.B6 113.45,46.75 113.45,47.26 113.73,47.54 113.73,47.84
  TOP w0.102: 97.13,67.11 98.21,67.11 98.67,66.65 101.11,66.65 101.25,66.78 101.25,67.05 101.55,67.36 101.63,67.43 101.89,67.43 102.73,66.59 104.29,66.59 105.09,65.79 v1(106.46,65.79) 107.64,65.79 107.94,65.79 107.94,65.79 108.44,65.79 108.62,65.97 113.6,65.97 114.75,64.83 115.04,64.83 115.66,64.83 117.36,63.13 117.36,52.79 113.73,49.16 113.73,47.84
  BOTTOM w0.089: UC1.M17 v2(90.39,65.89)
EMMC_0_RCLK: length 35.8
  TOP w0.089: v2(91.1,64.9) 91.48,65.28 94.45,65.28 95.54,64.19 97,64.19 97.19,64.01
  TOP w0.102: RM24.1 112.24,53.57 114.8,56.14 114.8,60.55 v1(114.08,61.28) 112.46,62.9 111.07,62.9 110.86,62.69 110.65,62.48 110.35,62.48 108.62,62.48 108.43,62.67 103.3,62.67 102.95,63.01 98.18,63.01 97.19,64.01
  BOTTOM w0.089: UC1.L15 v2(91.1,64.9)
EMMC_0_RCLK_R: length 15
  TOP w0.089: 110.52,43.75 112.05,43.75 112.3,43.5 UM1.H5
  TOP w0.102: RM24.2 RM12.2 111.41,50.48 111.27,50.33 111.13,50.33 110.67,50.79 110.52,50.79 110.38,50.65 110.38,50.51 110.84,50.05 110.84,49.9 110.69,49.76 110.55,49.76 110.22,50.09 110.07,50.09 109.93,49.95 109.93,49.81 110.26,49.47 110.26,49.33 109.95,49.02 109.95,46.41 109.7,46.16 109.7,44 109.95,43.75 110.52,43.75
EMMC_0_RST: length 8.4
  TOP w0.102: UM2.4 105.09,43.01 104.38,42.3 CM6.1 RM25.1 105.18,41.35 105.37,41.16 RM28.2 106.27,41.03 105.81,40.57 105.81,39.91 106.33,39.39 RM27.2 v1(105.38,38.74)
EMMC_0_RST_R: length 7.1
  TOP w0.089: 110.52,42.75 112.45,42.75 UM1.K5
  TOP w0.102: RM25.2 107.15,41.97 v2(107.19,41.93) ; v2(109.97,42.2) 110.52,42.75 110.52,42.75
  IN1 w0.127: v2(109.97,42.2) 107.46,42.2 v2(107.19,41.93)
EMMC_DET: length 35.8
  IN1 w0.127: v2(83.03,104.33) 83.21,104.15 84.91,104.15 86.24,102.82 86.24,97.05 86.9,96.39 86.9,91.45 88.39,89.96 88.39,86.53 88.05,86.19 88.05,85.58 87.84,85.38 87.84,84.29 88.35,83.78 88.35,79.87 88.35,79.56 87.12,78.33 87.12,77.83 87.42,77.53 88.12,77.53 88.3,77.35 v2(88.3,77.27)
  BOTTOM w0.089: v2(88.3,77.27) 88.22,77.27 UC1.U41
  BOTTOM w0.102: RC172.1 RC171.2 82.08,105.53 v1(82.74,104.87) 83.03,104.58 v2(83.03,104.33)
EN_0.6VSP: length 4.7
  TOP w0.102: PRM09.2 28.24,120.44 v1(28.61,120.07)
  TOP w0.203: PUM01.7 25.33,119.14 25.75,119.57 26.26,119.57
  TOP w0.254: PRM09.2 PCM16.1 26.77,120.07 26.26,119.57
EN_1.2V: length 3.1
  TOP w0.203: v2(25.36,119.82) 24.93,119.39 PUM01.8
  TOP w0.254: PRM08.2 PCM15.1 25.82,120.28 v2(25.36,119.82)
EN_1.05V: length 4.5
  TOP w0.254: PRH02.1 PRH01.2 152.12,60.07 v2(151.67,60.51)
  BOTTOM w0.254: PUH01.6 151.59,61.22 151.67,61.15 v2(151.67,60.51) 152.14,60.04 PCH09.1
EN_1.05VS: length 61.5
  TOP w0.102: PRH01.1 155.23,60.07 155.79,60.63 155.79,63.32 155.42,63.69 142.4,63.69 138.97,60.26 v1(137.45,60.26) 135.92,60.26 135.69,60.03 128.8,60.03 127.68,58.91 126.29,58.91 125.53,58.15 122.58,58.15 122.18,57.76 122.18,56.05 123.41,54.82 123.41,53.53 123.76,53.18 123.76,48.82 122.77,47.83 122.77,46.84 121.89,45.97 121.89,42.95 v2(121.03,42.09)
  BOTTOM w0.102: UE1.73 119.72,42.02 119.82,42.12 121,42.12 v2(121.03,42.09)
EN_1.8V: length 4.8
  BOTTOM w0.102: v1(47.74,26.71) PR1808.2
  BOTTOM w0.254: PU1801.5 47.75,30.88 47.74,30.87 PC1805.1 PR1802.1 PR1801.2 PR1808.2
EN_1.24V: length 5.7
  TOP w0.102: v1(62.57,47.49) 62.57,46.21 62.07,45.72 PR1205.2
  TOP w0.254: PU1201.5 64.32,44.3 64.57,44.56 64.57,45.04 63.92,45.7 PC1205.1 PR1206.1 PR1205.2
EN_2.5V: length 3.8
  BOTTOM w0.102: v1(37.04,126.88) PR2501.2
  BOTTOM w0.254: PR2501.2 PC2503.1 36.15,124.2 PU2501.2
EN_3V: length 70.1
  IN2 w0.254: v2(215.49,85.15) 215.46,85.12 209.76,85.12 208.71,84.07 200.13,84.07 197.58,81.52 197.58,70.19 194.89,67.5 190.22,67.5 189.39,66.67 184.88,66.67 183.04,64.83 178.88,64.83 175.58,61.53 169.64,61.53 168.63,60.51 v2(168.63,55.88)
  BOTTOM w0.254: PU301.12 168.25,56.25 v2(168.63,55.88) ; PR502.1 v2(215.49,85.15)
EN_5V: length 4.3
  BOTTOM w0.102: 204.33,82.69 203.87,82.23 203.11,82.23 202.92,82.42 202.92,82.55 202.6,82.86 v1(202.47,82.86)
  BOTTOM w0.254: PR503.1 204.33,82.28 205.01,81.6 PU501.12
ENBKL: length 53.6
  TOP w0.102: v2(121.51,51.11) v1(121.51,51.62)
  IN1 w0.127: v2(121.51,51.11) 121.39,51.11 119.38,53.12 118.31,53.12 114.91,56.52 114.91,62.01 111.84,65.08 111.84,73.5 109.71,75.64 109.23,75.64 108.56,74.96 103.09,74.96 101.37,76.68 96.24,76.68 v2(96.15,76.6)
  BOTTOM w0.089: UC1.C40 94.93,76.69 95.06,76.69 95.22,76.8 95.95,76.8 v2(96.15,76.6)
  BOTTOM w0.102: v2(121.51,51.11) 120.42,51.11 119.88,51.65 UE1.97 ; v2(96.15,76.6) 96.46,76.6 98.6,78.74 RC160.2
ENLDO_3V5V: length 57.9
  TOP w0.254: v2(169.52,56.38) 169.74,56.15 PC317.1
  IN2 w0.254: v2(169.52,56.38) 169.52,57.26 169.9,57.64 170.5,57.64 171.03,57.11 173.12,57.11 175.38,59.38 175.38,60.22 175.57,60.4 178.37,63.2 183.83,63.2 184.95,64.32 185.58,64.32 185.58,64.32 187.9,64.32 188.22,64.32 190.63,66.73 194.89,66.73 194.89,66.73 195.2,66.73 198.56,70.09 198.56,70.31 198.56,81.19 199.09,81.72 203.36,81.72 v2(203.49,81.59)
  BOTTOM w0.254: PR302.1 170.71,55.81 170.71,56.45 PR303.1 170.1,56.57 170.04,56.51 170.02,56.51 169.9,56.38 v2(169.52,56.38) 168.88,56.38 168.7,56.56 PU301.11 ; PU501.11 204.56,81.34 204.3,81.59 v2(203.49,81.59)
FB_1.2V: length 7.2
  TOP w0.102: v1(30.45,117.22) PCM17.1
  TOP w0.203: 27.14,119.12 25.93,119.12 25.73,118.92 PUM01.6
  TOP w0.254: 27.14,119.12 27.59,119.58 28.67,119.58 PRM11.1 29.26,118.36 29.43,118.18 PRM10.1 PCM17.1
FB_1.05V: length 7.5
  BOTTOM w0.102: v1(155.41,59.18) 155.16,59.18 PRH12.2
  BOTTOM w0.254: PRH12.2 154.17,58.19 153.41,58.19 PRH08.1 PRH09.1 152.61,58.33 152.21,58.73 151.29,58.73 150.88,59.14 150.17,59.14 149.54,59.77 PUH01.10
FB_1.8V: length 4.3
  BOTTOM w0.102: v1(44.28,27.5) PC1807.2
  BOTTOM w0.254: PC1807.2 PR1807.2 PR1805.1 44.28,31.41 44.37,31.51 PU1801.6
FB_1.24V: length 5.8
  TOP w0.102: v1(61.25,47.53) 61.57,47.21 61.57,45.84 61.43,45.7 PC1206.2
  TOP w0.254: PC1206.2 PR1204.2 60.17,45.58 59.8,45.21 PR1202.1 60.37,44.32 61.08,44.32 PU1201.6
FB_3V: length 4.6
  BOTTOM w0.102: PR308.1 168.88,55.05 v1(169.26,55.43)
  BOTTOM w0.254: PR308.1 PC315.1 168.07,54.5 PR307.2 167.8,55.51 PU301.13
FB_3V_R: length 1.8
  BOTTOM w0.102: v1(167.99,52.57) PC315.2
  BOTTOM w0.254: PC315.2 PR306.1
FB_5V: length 3.5
  BOTTOM w0.254: PR511.1 PC517.1 205.14,82.75 PR510.2 205.13,82.36 v2(205.4,82.09) 205.46,82.03 PU501.13
FB_5V_R: length 2.9
  BOTTOM w0.102: PR509.1 206.03,84.58 206.41,84.96 207.3,84.96 v1(207.62,84.64)
  BOTTOM w0.254: PR509.1 PC517.2
FB_VCCGI: length 5.9
  BOTTOM w0.102: PRG18.1 v1(97.24,143.34)
  BOTTOM w0.203: PUG1.24 96.66,139.77 96.3,140.14 96.3,141.27 PCG12.2
  BOTTOM w0.254: PCG12.2 PRG17.2 PRG18.1 PCG11.1
FB_VNN: length 6.2
  BOTTOM w0.102: v1(86.46,139) 86.03,138.57 PRZ09.2
  BOTTOM w0.203: PCZ04.2 85.99,137.22 85.17,136.41 85.17,135.69 85.3,135.57 PUZ1.24
  BOTTOM w0.254: PCZ05.1 PRZ10.1 PRZ09.2 PCZ04.2
FFS_INT1: length 70.8
  TOP w0.102: v2(121.38,62.35) v1(121.38,61.59)
  IN1 w0.127: v2(91.03,79.43) 91.6,80 91.6,80.49 91.45,80.71 91.45,82.39 93.51,84.45 96.29,84.45 97.12,85.28 97.85,85.28 99.66,87.08 100.98,87.08 101.97,88.07 103.47,88.07 104.16,88.76 108.18,88.76 108.87,89.44 111.68,89.44 117.89,83.23 117.89,67.71 121.51,64.09 121.51,62.48 v2(121.38,62.35)
  IN2 w0.127: v2(121.38,62.35) 121.22,62.19 113.09,62.19 112.58,61.68 111.48,61.68 111.35,61.81 v2(111.35,62.1)
  BOTTOM w0.089: UC1.L46 90.69,79.09 v2(91.03,79.43)
  BOTTOM w0.102: US2.12 111.23,63.14 111.35,63.01 v2(111.35,62.1)
FFS_INT2: length 140.8
  TOP w0.102: v2(182.85,42.54) v1(182.85,42.03)
  IN1 w0.127: v2(117.52,64.05) 117.59,64.11 117.59,64.75 115.6,66.73 115.6,76.66 110.83,81.44 107.75,81.44 107.44,81.12 105.28,81.12 104.02,79.86 100.39,79.86 99.07,81.19 99.07,81.64 98.36,82.35 97.28,82.35 96.24,81.31 96.24,79.86 95.29,78.91 92.25,78.91 92.23,78.89 90.99,78.89 90.65,78.54 v2(90.53,78.54) ; v2(182.85,42.54) 182.38,43.01 181.77,43.62 174.28,43.62 173.12,42.45 145.5,42.45 144.3,43.66 143.14,43.66 142.04,44.76 140.33,44.76 137.9,47.19 134.54,47.19 134.02,46.67 131.73,46.67 130.72,45.65 126.42,45.65 125.64,46.44 124.54,46.44 121.84,49.14 119.73,49.14 113.13,55.74 113.13,60.9 v2(111.93,62.1)
  IN2 w0.127: v2(117.52,64.05) 113.88,64.05 v2(111.93,62.1)
  BOTTOM w0.089: v2(90.53,78.54) 90.53,78.48 UC1.M43
  BOTTOM w0.102: v2(182.85,42.54) 182.47,42.16 181.97,42.16 181.78,42.35 QS1.2 ; RS64.2 112.25,61.78 v2(111.93,62.1) 111.73,62.31 US2.11
FFS_INT2_Q: length 12.4
  BOTTOM w0.102: RS63.2 181.31,41.13 181.32,41.14 QS1.3 v1(182.79,41.7) 183.15,41.7 183.55,42.1 185.9,42.1 186.34,41.65 186.34,37.65 186.2,37.51 JHDD1.9
FPR_SCAN#: length 120.8
  TOP w0.102: v3(222.41,35.05) v2(221.78,35.05) 221.09,35.73 RC213.1 221.08,34.22 220.52,33.66 EU4012.3 220.52,31.64 v2(220.5,31.62)
  IN1 w0.127: v2(120.11,42.86) 119.62,42.36 119.62,41.51 121.51,39.62 128.56,39.62 129.19,40.25 134.08,40.25 135.49,38.84 135.49,35.86 136.56,34.79 137,34.79 137.38,35.17 178.41,35.17 180.18,33.4 209.9,33.4 211.62,31.68 218.41,31.68 v2(221.78,35.05)
  BOTTOM w0.102: v2(120.11,42.86) 119.71,42.86 119.35,43.22 UE1.76 ; JFP1.2 v2(220.5,31.62)
FSET: length 5.6
  BOTTOM w0.102: PRB38.1 195.25,45.09 194.6,44.45 194.6,43.62 v1(194.85,43.37)
  BOTTOM w0.203: PUB01.3 195.9,47.08 196.16,46.82 196.16,45.65 195.97,45.46 195.49,45.46 PRB38.1
GPIO_27: length 18.8
  TOP w0.102: v2(85.84,78.77) 85.84,79.04 85.51,79.37 85.51,79.71 86.34,80.55 86.34,81.06 86.93,81.64 v1(86.93,84.16) 87.11,84.34 87.46,84.34 87.83,84.7 87.83,85.24 88.02,85.43 88.46,85.43 88.62,85.28 90.01,85.28 90.29,85.55 90.29,86 90.2,86.09 90.2,88.25 v2(89.56,88.9)
  BOTTOM w0.089: v2(85.84,78.77) 85.84,77.61 85.56,77.33 85.25,77.33 84.95,77.02 84.95,76.68 UC1.AE39
  BOTTOM w0.102: RC97.1 89.06,89.39 v2(89.56,88.9) 89.56,88.41 RC98.1
GPIO_28: length 16.1
  IN2 w0.127: v2(84.94,79.38) 84.94,79.63 85.38,80.07 85.38,80.45 84.97,80.86 84.97,82.13 84.46,82.63 84.46,88.35 84.95,88.83 v2(87.71,88.83)
  BOTTOM w0.089: UC1.AE46 84.51,79.09 84.84,79.38 v2(84.94,79.38)
  BOTTOM w0.102: v1(87.3,89.34) 87.41,89.45 RC99.1 88.24,89.35 v2(87.71,88.83) 87.71,88.79 RC100.1
GPIO_172: length 4.5
  BOTTOM w0.089: UC1.C20 94.68,67.08 94.73,67.03 94.73,66.95 94.88,66.8 95.1,66.8 95.19,66.89 95.69,66.89 95.78,66.8 96.62,66.8 96.94,66.48 97.57,66.48
  BOTTOM w0.102: 97.57,66.48 97.94,66.48 RC8.1
GPIO_174: length 9.8
  BOTTOM w0.089: 96.47,66.34 95.22,66.34 95.1,66.42 UC1.C18
  BOTTOM w0.102: 96.47,66.34 96.79,66.02 100.42,66.02 100.83,65.61 101.48,65.61 102.02,65.08 102.13,65.08 RC110.2 102.33,64.89 103.22,64 v1(103.22,63.77)
GPIO_175: length 9.6
  BOTTOM w0.089: UC1.A18 95.67,66.57 95.78,66.57 95.78,66.57 96.59,66.57
  BOTTOM w0.102: 96.59,66.57 96.93,66.23 100.36,66.23 100.37,66.22 100.5,66.22 100.91,65.82 101.6,65.82 101.76,65.65 RC9.1 RC12.1 102.32,66.62 v1(103.2,67.5)
H_PROCHOT#: length 212.9
  TOP w0.102: v2(200.82,53.24) 201.07,53.49 201.07,55.12 200.56,55.62 PQB32.1 ; v2(189.95,43.75) 189.95,43.2 190.26,42.9 PQ11.1 ; PQ12.3 181.69,68.75 183.23,70.29 186.85,70.29 188.76,68.38 v1(188.76,60.76) v2(187.74,59.75)
  IN1 w0.127: v2(123.91,60.08) 123.91,62.05 118.14,67.81 118.14,83.34 111.78,89.7 108.76,89.7 108.08,89.01 104.06,89.01 103.37,88.32 101.87,88.32 100.88,87.33 99.06,87.33 98.8,87.08 97.94,87.08 96.46,85.61 94.19,85.61 93.91,85.89 93.91,86.85 v2(94.01,86.95) ; v2(189.95,43.75) 191.11,42.59 191.81,42.59 192.06,42.84 192.06,44.57 193.01,45.52 199.07,45.52 199.6,46.06 199.6,52.09 200.67,53.16 200.74,53.16 v2(200.82,53.24)
  IN2 w0.127: v2(122.59,57.46) 123.12,58 128.41,58 129.57,56.83 129.57,55.02 130.4,54.19 132.14,54.19 132.18,54.22 134.59,54.22 134.83,53.98 136.43,53.98 136.82,53.59 138.47,53.59 140.56,51.49 140.78,51.49 148.73,51.49 151.2,49.02 157.26,49.02 158.03,48.24 167.52,48.24 168.33,47.43 169.71,47.43 169.96,47.69 169.96,52.47 176.34,58.84 176.34,59.82 178.74,62.23 181.83,62.23 183.36,60.7 186.74,60.7 187.69,59.75 v2(187.74,59.75) 188.91,59.75 189.11,59.95 195.64,59.95 198.15,57.44 198.15,56.83 197.85,56.52 v2(197.37,56.52) 199.55,54.34 199.59,54.34 200.68,53.24 v2(200.82,53.24)
  BOTTOM w0.089: CC15.1 93.32,86.15 93.32,86.16
  BOTTOM w0.102: UC1.J54 91.6,82.68 91.6,83.24 91.79,83.43 91.79,83.84 93.25,85.3 CC15.1 ; v2(197.37,56.52) 197.85,56.04 PRB21.1 ; v2(122.59,57.46) 122.47,57.46 RE19.2 RE20.2 121.97,58.14 v2(123.91,60.08) ; 93.32,86.16 94.01,86.85 v2(94.01,86.95) 94.01,87.42 RC69.1
H_THERMTRIP#: length 69.4
  IN1 w0.127: v2(128.43,56.24) 128.43,57.27 127.42,58.29 126.49,58.29 125.19,58.29 124.33,59.15 124.33,61.99 118.4,67.92 118.4,83.44 111.89,89.95 108.66,89.95 107.97,89.27 103.95,89.27 103.26,88.58 100.62,88.58 100.26,88.22 99.54,88.22 98.65,87.33 97.81,87.33 96.69,86.22 95.16,86.22 v2(94.88,86.5)
  BOTTOM w0.089: UC1.J53 91.65,82.23 91.96,82.53 91.96,82.71 91.83,82.84 91.83,83.12 92.11,83.4 92.11,83.73 ; 93.86,85.57 93.86,86.16
  BOTTOM w0.102: v2(128.43,56.24) 128.15,56.52 RE11.2 ; 93.86,85.57 92.11,83.82 92.11,83.73 ; RC70.1 94.45,87.82 94.45,86.93 v2(94.88,86.5) 94.17,86.5 93.86,86.19 93.86,86.16
HDA_BIT_CLK: length 4.1
  BOTTOM w0.089: UC1.A22 95.44,68.28 96.92,68.28 97.46,67.74 97.57,67.74
  BOTTOM w0.102: 97.57,67.74 98.88,67.74 RC13.2
HDA_BIT_CLK_R: length 147.4
  TOP w0.102: UA1.5 36.16,12.81 RA50.2 36.53,11.93 v2(36.17,11.93)
  IN2 w0.127: v2(105.06,26.86) 104.3,26.09 v2(83.03,26.09)
  BOTTOM w0.102: v2(105.06,26.86) 106.1,27.9 106.1,34.87 108.21,36.98 108.21,38.96 107.91,39.26 107.91,46.64 110.03,48.76 110.03,56.28 114.36,60.62 114.36,64.77 113.12,66.01 111.13,66.01 108.85,68.28 107.87,68.28 107.35,67.76 107.35,67.43 106.84,66.92 106.84,66.82 106.44,66.42 105.51,66.42 104.56,67.37 104.56,67.62 103.96,68.22 101.57,68.22 arc(101.54,68.21) 101.5,68.19 101.11,67.8 CC1.2 100.92,67.94 RC13.1 ; v2(83.03,26.09) 71.21,26.09 69.92,27.39 64.07,27.39 63.52,26.84 62.36,25.67 43.28,25.67 42.37,24.76 40.11,24.76 38.01,22.67 38.01,22.28 37.27,21.55 37.27,18.93 34.32,15.99 34.32,12.43 34.95,11.81 36.04,11.81 v2(36.17,11.93)
HDA_CODEC_SDIN0: length 1.3
  TOP w0.102: RA30.2 35.48,13.61 UA1.7
HDA_RST#: length 3.4
  BOTTOM w0.089: UC1.C21 94.78,67.78 94.93,67.67 94.93,67.63 94.94,67.62 94.94,67.52 95.04,67.42 95.04,67.41 95.2,67.25 95.21,67.25 95.28,67.18 95.79,67.18 95.92,67.05 97.19,67.05 T2.1
HDA_SDIN0: length 152.5
  TOP w0.102: RA30.1 v2(37.04,13.65)
  IN1 w0.127: v2(100.24,67.31) 100.24,69.78 v2(100.68,70.23)
  BOTTOM w0.089: UC1.B21 95.1,67.96 96.78,67.96 97.49,67.25 97.57,67.25
  BOTTOM w0.102: RC16.2 v2(100.68,70.23) 100.86,70.23 101.11,70.48 RC17.2 ; RC17.2 101.32,70.68 101.3,70.7 101.3,71.18 RC7.2 ; RC17.2 RC11.1 102.24,70.58 103.16,70.58 104.28,71.69 106.9,71.69 107.6,70.98 107.6,70.8 107.6,70.73 108.02,70.31 110.15,70.31 115.3,65.16 115.3,60.21 110.97,55.88 110.97,48.37 108.85,46.25 108.85,39.76 109.15,39.46 109.15,36.59 107.06,34.49 107.06,27.33 105.57,25.84 101.38,25.84 100.24,24.7 96.3,24.7 95.93,25.07 70.91,25.07 69.53,26.45 64.46,26.45 62.75,24.74 43.74,24.74 42.76,23.75 40.61,23.75 38.95,22.08 38.95,14.27 37.88,13.2 37.37,13.2 37.04,13.53 v2(37.04,13.65) ; v2(100.24,67.31) 100.19,67.25 97.57,67.25
HDA_SDOUT: length 4.9
  BOTTOM w0.089: 97.57,68.22 97.42,68.22 97.18,68.45 95.66,68.45 95.41,68.7 95.22,68.7 94.93,68.42 UC1.C22
  BOTTOM w0.102: RC14.2 98.81,68.44 98.76,68.44 98.55,68.22 97.57,68.22
HDA_SDOUT_R: length 144.9
  TOP w0.102: v2(35.2,12.31) 35.1,12.41 UA1.4
  BOTTOM w0.102: RC14.1 102.78,68.7 103.67,69.59 103.67,70.32 104.56,71.2 106.74,71.2 107.15,70.8 107.15,70.54 107.66,70.03 107.83,69.86 109.96,69.86 114.84,64.97 114.84,60.42 110.51,56.08 110.51,48.56 108.4,46.44 v4(108.4,39.75) 108.4,39.46 108.7,39.16 108.7,36.78 106.59,34.67 106.59,27.62 105.32,26.35 101.13,26.35 99.98,25.2 96.44,25.2 96.12,25.52 71.1,25.52 69.72,26.91 64.27,26.91 64,26.64 62.56,25.19 43.48,25.19 42.54,24.26 40.3,24.26 38.49,22.45 38.49,18.89 37.88,18.28 37.3,18.28 34.81,15.79 34.81,12.71 v2(35.2,12.31)
HDA_SYNC: length 6.2
  BOTTOM w0.089: 95.51,68.92 95.39,68.92 95.11,69.12 95.1,69.13 94.88,69.13 94.86,69.1 94.39,68.89 UC1.C23
  BOTTOM w0.102: 95.51,68.92 95.79,68.64 97.44,68.64 97.53,68.55 v1(97.76,68.55) 98.29,68.55 98.65,68.91 98.65,69.06 98.75,69.16 98.78,69.16 RC15.2 RC16.1
HDA_SYNC_R: length 142.6
  TOP w0.102: v2(35.21,15.62) 35.21,15.04 34.58,14.41 UA1.9
  BOTTOM w0.102: v2(35.21,15.62) 35.21,15.87 37.4,18.05 37.97,18.05 38.72,18.79 38.72,22.23 40.49,24 42.65,24 43.61,24.96 62.65,24.96 64.23,26.54 64.37,26.68 69.62,26.68 71.01,25.29 96.03,25.29 96.37,24.95 100.11,24.95 101.25,26.09 105.44,26.09 106.82,27.47 106.82,34.57 108.92,36.68 v4(108.92,36.95) 108.92,39.31 108.62,39.61 108.62,46.35 110.74,48.46 110.74,55.99 115.07,60.32 115.07,65.07 110.05,70.08 107.93,70.08 107.37,70.64 107.37,70.89 106.83,71.43 104.4,71.43 103.41,70.44 103.41,69.72 102.78,69.08 100.43,69.08 100.05,69.46 RC15.1
HDMI_CLKN: length 3.4
  TOP w0.114: CG34.2 21.15,94.22 20.81,94.22 v2(20.67,94.36) 20.56,94.25 20.34,94.25 20.17,94.42 LI1.2 19.73,94.58 RG59.1
  BOTTOM w0.114: v2(20.67,94.36) 20.8,94.23 21.42,94.23 RG105.1
HDMI_CLKP: length 3.4
  TOP w0.114: RG60.1 19.73,93.75 LI1.3 19.96,93.98 20.5,93.98 v2(20.7,93.77) 20.85,93.93 21.22,93.93 CG33.2
  BOTTOM w0.114: v2(20.7,93.77) 20.9,93.98 21.42,93.98 RG104.1
HDMI_DETECT: length 4.8
  BOTTOM w0.102: QG1.2 24.08,88.32 23.99,88.24 23.99,87.66 23.55,87.23 RG48.1 23.47,87.17 22.53,87.17 22.13,86.78 RG56.1 22.53,86.29 v1(23.34,86.29)
HDMI_L_CLKN: length 8.9
  TOP w0.114: RG59.2 18.65,94.44 LI1.1 18.38,94.42 18.26,94.29 17.7,94.29 RG67.2 17.03,94.29 15.31,94.29 14,95.6 v4(14,96.2) 14,96.87 13.39,97.47 12.98,97.47 JHDMI1.12
HDMI_L_CLKP: length 8.9
  TOP w0.114: JHDMI1.10 12.98,97.23 13.29,97.23 13.75,96.77 13.75,95.5 v4(14.39,94.86) 15.21,94.04 17.04,94.04 RG67.1 17.7,94.04 18.26,94.04 18.38,93.92 LI1.4 18.65,93.89 RG60.2
HDMI_L_TX_N0: length 18.1
  TOP w0.114: JHDMI1.9 11.43,95.97 11.59,95.97 11.72,96.1 11.72,101.4 12.1,101.79 13.24,101.79 14.31,100.71 v4(14.31,98.36) 14.31,97.5 15.74,96.07 17.04,96.07 RG68.1 17.64,96.13 18.53,96.13 LI2.1 18.65,96.28 RG63.2
HDMI_L_TX_N1: length 8.3
  TOP w0.114: JHDMI1.6 12.98,94.47 13.69,94.47 14.13,94.03 v4(14.13,93.34) 14.13,92.83 14.5,92.46 17.04,92.46 RG69.1 17.71,92.46 18.25,92.46 18.32,92.52 LI3.1 18.82,92.69 RG65.2
HDMI_L_TX_N2: length 9.6
  TOP w0.114: JHDMI1.3 11.43,92.97 11.69,92.97 11.97,92.69 11.97,92.13 12.23,91.88 13.1,91.88 13.31,91.88 v4(13.88,91.31) 14.65,90.54 16.89,90.54 16.89,90.54 17.08,90.54 RG71.1 17.71,90.48 18.58,90.48 LI4.1 18.82,90.72 RG70.2
HDMI_L_TX_P0: length 18
  TOP w0.114: RG61.2 18.65,95.73 LI2.4 17.64,95.76 RG68.2 17.04,95.82 15.64,95.82 14.07,97.39 v4(14.07,99.88) 14.07,100.61 13.14,101.54 12.2,101.54 11.96,101.3 11.96,96 11.69,95.73 11.43,95.73 JHDMI1.7
HDMI_L_TX_P1: length 8.4
  TOP w0.114: JHDMI1.4 12.98,94.23 13.58,94.23 13.88,93.93 13.88,92.73 14.4,92.22 v4(15.27,92.22) 17.03,92.22 RG69.2 17.7,92.21 18.2,92.21 18.38,92.02 LI3.4 18.82,91.86 RG64.2
HDMI_L_TX_P2: length 9.7
  TOP w0.114: JHDMI1.1 11.43,92.73 11.59,92.73 11.73,92.59 11.73,92.03 12.12,91.63 13.2,91.63 14.55,90.29 v4(15.53,90.29) 16.99,90.29 RG71.2 17.42,89.91 17.75,90.24 18.2,90.24 18.38,90.05 LI4.4 18.82,89.89 RG66.2
HDMI_SCLK: length 45.4
  TOP w0.102: v2(26.83,94.42) 26.83,94.66 RI13.1 27.22,96.06 Q57.1 25.76,96.71 25.57,96.9 25.57,97.51 CM26.1
  IN1 w0.127: v2(16.29,93.63) 16.12,93.46 16.12,93.46 15.82,93.17 15.82,92.07 18.8,89.09 18.8,87.16 20.12,85.85 20.33,85.85 22.92,85.85 24.57,87.5 27.6,87.5 28.67,88.57 28.67,89.47 25.69,92.45 25.69,93.28 v2(26.83,94.42)
  BOTTOM w0.102: JHDMI1.15 11.19,99.35 11.72,99.88 11.72,101.39 12.06,101.74 13.45,101.74 14.52,100.66 14.52,95.39 v2(16.29,93.63)
HDMI_SDATA: length 41.6
  TOP w0.102: v2(25.18,92.87) 24.63,92.87 24.35,93.15 24.35,93.45 CM27.1 26.47,93.45 Q58.1 26.58,92.25 RI14.1
  IN1 w0.127: v2(25.18,92.87) 25.18,92.6 28.29,89.49 28.29,88.55 27.5,87.75 24.46,87.75 22.81,86.1 20.23,86.1 19.06,87.27 19.06,89.2 16.08,92.18 16.08,92.83 v2(16.29,93.04)
  BOTTOM w0.102: JHDMI1.16 12.26,99.85 11.97,100.13 11.97,101.28 12.23,101.53 13.37,101.53 14.32,100.58 14.32,95.01 v1(15.32,94.02) v2(16.29,93.04)
HDMI_TX_N0: length 3.3
  TOP w0.114: CG32.2 21.15,96.06 20.94,96.06 v2(20.8,96.2) 20.74,96.13 20.73,96.13 20.03,96.13 20.02,96.13 LI2.2 19.9,96.28 RG63.1
  BOTTOM w0.114: RG109.1 21.38,96.03 20.97,96.03 v2(20.8,96.2)
HDMI_TX_N1: length 3.3
  TOP w0.114: CG30.2 21.17,92.32 20.87,92.32 v2(20.74,92.46) 19.96,92.46 LI3.2 19.73,92.69 RG65.1
  BOTTOM w0.114: RG103.1 21.42,92.32 20.87,92.32 v2(20.74,92.46)
HDMI_TX_N2: length 3.4
  TOP w0.114: RG70.1 19.73,90.72 LI4.2 20.04,90.42 20.49,90.42 v2(20.74,90.66) 20.95,90.44 21.19,90.44 CG28.2
  BOTTOM w0.114: v2(20.74,90.66) 20.95,90.44 21.44,90.44 RG107.1
HDMI_TX_P0: length 3.3
  TOP w0.114: RG61.1 19.9,95.73 LI2.3 20.02,95.88 20.53,95.88 20.8,95.61 v2(20.81,95.61) 21.01,95.81 21.17,95.81 CG31.2
  BOTTOM w0.114: RG108.1 21.53,95.71 20.91,95.71 v2(20.81,95.61)
HDMI_TX_P1: length 3.3
  TOP w0.114: RG64.1 19.73,91.86 LI3.3 20.59,92.02 v2(20.74,91.88) 20.93,92.08 21.16,92.08 CG29.2
  BOTTOM w0.114: RG102.1 21.41,92.08 20.93,92.08 v2(20.74,91.88)
HDMI_TX_P2: length 3.4
  TOP w0.114: RG66.1 19.73,89.89 LI4.3 20.02,90.17 20.6,90.17 20.6,90.18 v2(20.74,90.04) 20.89,90.2 21.14,90.2 CG27.2
  BOTTOM w0.114: v2(20.74,90.04) 20.89,90.2 21.39,90.2 RG106.1
HP_DETECT: length 30.9
  BOTTOM w0.102: RG48.2 23.53,88.02 22.95,87.43 22.07,87.43 21.26,86.62 CM17.1 19.9,85.34 18.07,85.34 17.43,85.97 17.43,88.45 19.59,90.61 19.59,92.96 18.45,94.1 v1(18.32,94.1) 16.73,94.1 14.73,96.11 14.73,100.75 13.25,102.23 11.93,102.23 JHDMI1.19
HPOUT_L: length 14.5
  TOP w0.254: v2(21.22,12.81) 21.47,12.81 21.67,13.01 LA2.2 ; JHP1.1 13.13,7.42 v1(14.58,7.42) 15.15,7.42 16.99,9.27 17.81,9.27 18.12,9.57 DA8.2 18.12,11.07 v2(18.08,11.11)
  BOTTOM w0.254: CA498.1 18.07,11.12 v2(18.08,11.11) ; CA498.1 18.78,11.98 19.02,11.74 20.67,11.74 21.22,12.29 v2(21.22,12.81) ; CA498.1 RA54.1
HPOUT_R: length 24.6
  TOP w0.254: LA3.2 21.32,11.49 21.19,11.36 21.19,11.39 v2(21.19,11.39) ; v2(17.18,10.9) 17.18,10.26 16.93,10 DA8.3 16.15,10.04 v2(16.15,11.87)
  BOTTOM w0.254: v2(16.15,11.87) 16.15,17.03 14.7,18.47 8.73,18.47 7.66,17.4 JHP1.2 ; v2(21.19,11.39) 21.19,11.39 21.19,11.36 21.05,11.36 20.86,11.17 19.15,11.17 18.27,10.3 RA57.1 CA504.1 v2(17.18,10.9)
HW_ACAV_IN: length 102.9
  TOP w0.127: v2(186.75,59.6) v1(186.09,60.26) PR31.1
  IN1 w0.127: v2(123.17,57.02) 123.17,54.47 125.2,52.45 126.2,52.45 128.04,50.6 132.05,50.6 133.07,51.62 137.34,51.62 137.94,51.02 147.63,51.02 151.11,47.55 152.72,47.55 152.89,47.38 161.32,47.38 162.52,48.57 165.2,48.57 168.05,51.42 168.62,51.42 170.12,52.93 171.84,52.93 173.62,54.71 177.89,54.71 178.34,54.71 178.49,54.86 178.59,54.96 180.81,54.96 180.81,54.96 181.73,54.96 182.17,54.96 183.4,56.19 v2(187.26,56.19)
  IN2 w0.127: v2(187.26,56.19) 187.26,56.29 190.57,59.6 195.28,59.6 v2(197.7,57.18)
  BOTTOM w0.127: RE21.2 123.72,56.47 v2(123.17,57.02) ; v2(187.26,56.19) 187.26,59.09 v2(186.75,59.6)
  BOTTOM w0.254: PRB25.2 193.87,55.52 PRB26.1 195.54,57.18 v2(197.7,57.18) 198.31,57.18 198.66,56.83 PRB22.2
I2C_5_SCL: length 133.5
  IN2 w0.127: v2(141.7,38.79) 141.7,38.79 141.76,38.73 143.42,38.73 143.67,38.47 143.67,35.96 142.83,35.11 138.84,35.11 137.45,36.5 132.97,36.5 131.9,35.43 123.56,35.43 122.49,36.5 117.73,36.5 116.51,37.71 109.61,37.71 109.19,37.29 109.19,36.36 109.61,35.94 110.22,35.94 110.23,35.92 110.29,35.92 v2(110.32,35.95) 110.4,36.03 111.77,36.03 112.87,34.92 116.44,34.92 116.57,34.79 v2(116.57,33.73)
  BOTTOM w0.089: UC1.C50 95.02,81.01 95.97,81.01 96.39,81.42 96.39,82.31 98.53,84.45
  BOTTOM w0.102: Q10.1 117.38,33.32 R34.2 116.97,33.73 v2(116.57,33.73) ; v2(141.7,38.79) 141.7,38.79 141.76,38.73 142.54,38.73 142.54,38.72 JDB1.10 ; v2(110.32,35.95) 110.42,36.05 110.62,36.05 111.01,36.43 111.01,38.61 109.56,40.05 109.56,45.85 110.38,46.67 111.54,46.67 113,48.13 113,54.64 116.95,58.59 117.08,58.59 118.75,60.27 118.75,61.8 118.49,62.06 118.49,65.38 113.61,70.26 113.61,71.42 113.91,71.73 113.91,83.97 112.8,85.09 105.19,85.09 104.5,84.39 103.45,84.39 102.97,83.91 101.27,83.91 100.74,84.45 98.53,84.45
I2C_5_SDA: length 133.5
  IN2 w0.127: v2(146.85,38.66) 146.85,38.67 146.78,38.73 144.43,38.73 144.18,38.48 144.18,35.75 143.04,34.6 138.63,34.6 137.24,35.99 133.18,35.99 132.11,34.92 123.35,34.92 122.28,35.99 117.52,35.99 116.3,37.21 109.83,37.21 109.7,37.08 109.7,36.57 109.83,36.45 110.01,36.45 110.09,36.53 v2(110.32,36.53) 111.98,36.53 113.08,35.43 120.75,35.43 v2(120.81,35.49)
  BOTTOM w0.089: UC1.A50 95.37,80.78 96.19,80.78 96.62,81.21 96.62,82.06 98.53,83.97
  BOTTOM w0.102: JDB1.9 145.71,38.72 146.79,38.72 v2(146.85,38.66) ; 98.53,83.97 100.54,83.97 101.07,83.43 103.17,83.43 103.65,83.91 104.7,83.91 105.39,84.6 112.6,84.6 113.43,83.77 113.43,71.93 113.13,71.62 113.13,70.06 118.01,65.18 118.01,61.86 118.27,61.6 118.27,60.47 116.88,59.08 116.75,59.08 112.52,54.84 112.52,48.33 111.34,47.15 110.18,47.15 109.08,46.05 109.08,39.85 110.52,38.41 110.52,36.63 110.42,36.53 v2(110.32,36.53) ; v2(120.81,35.49) 121.07,35.24 R33.2 120.7,34.87 120.45,34.62 Q10.4
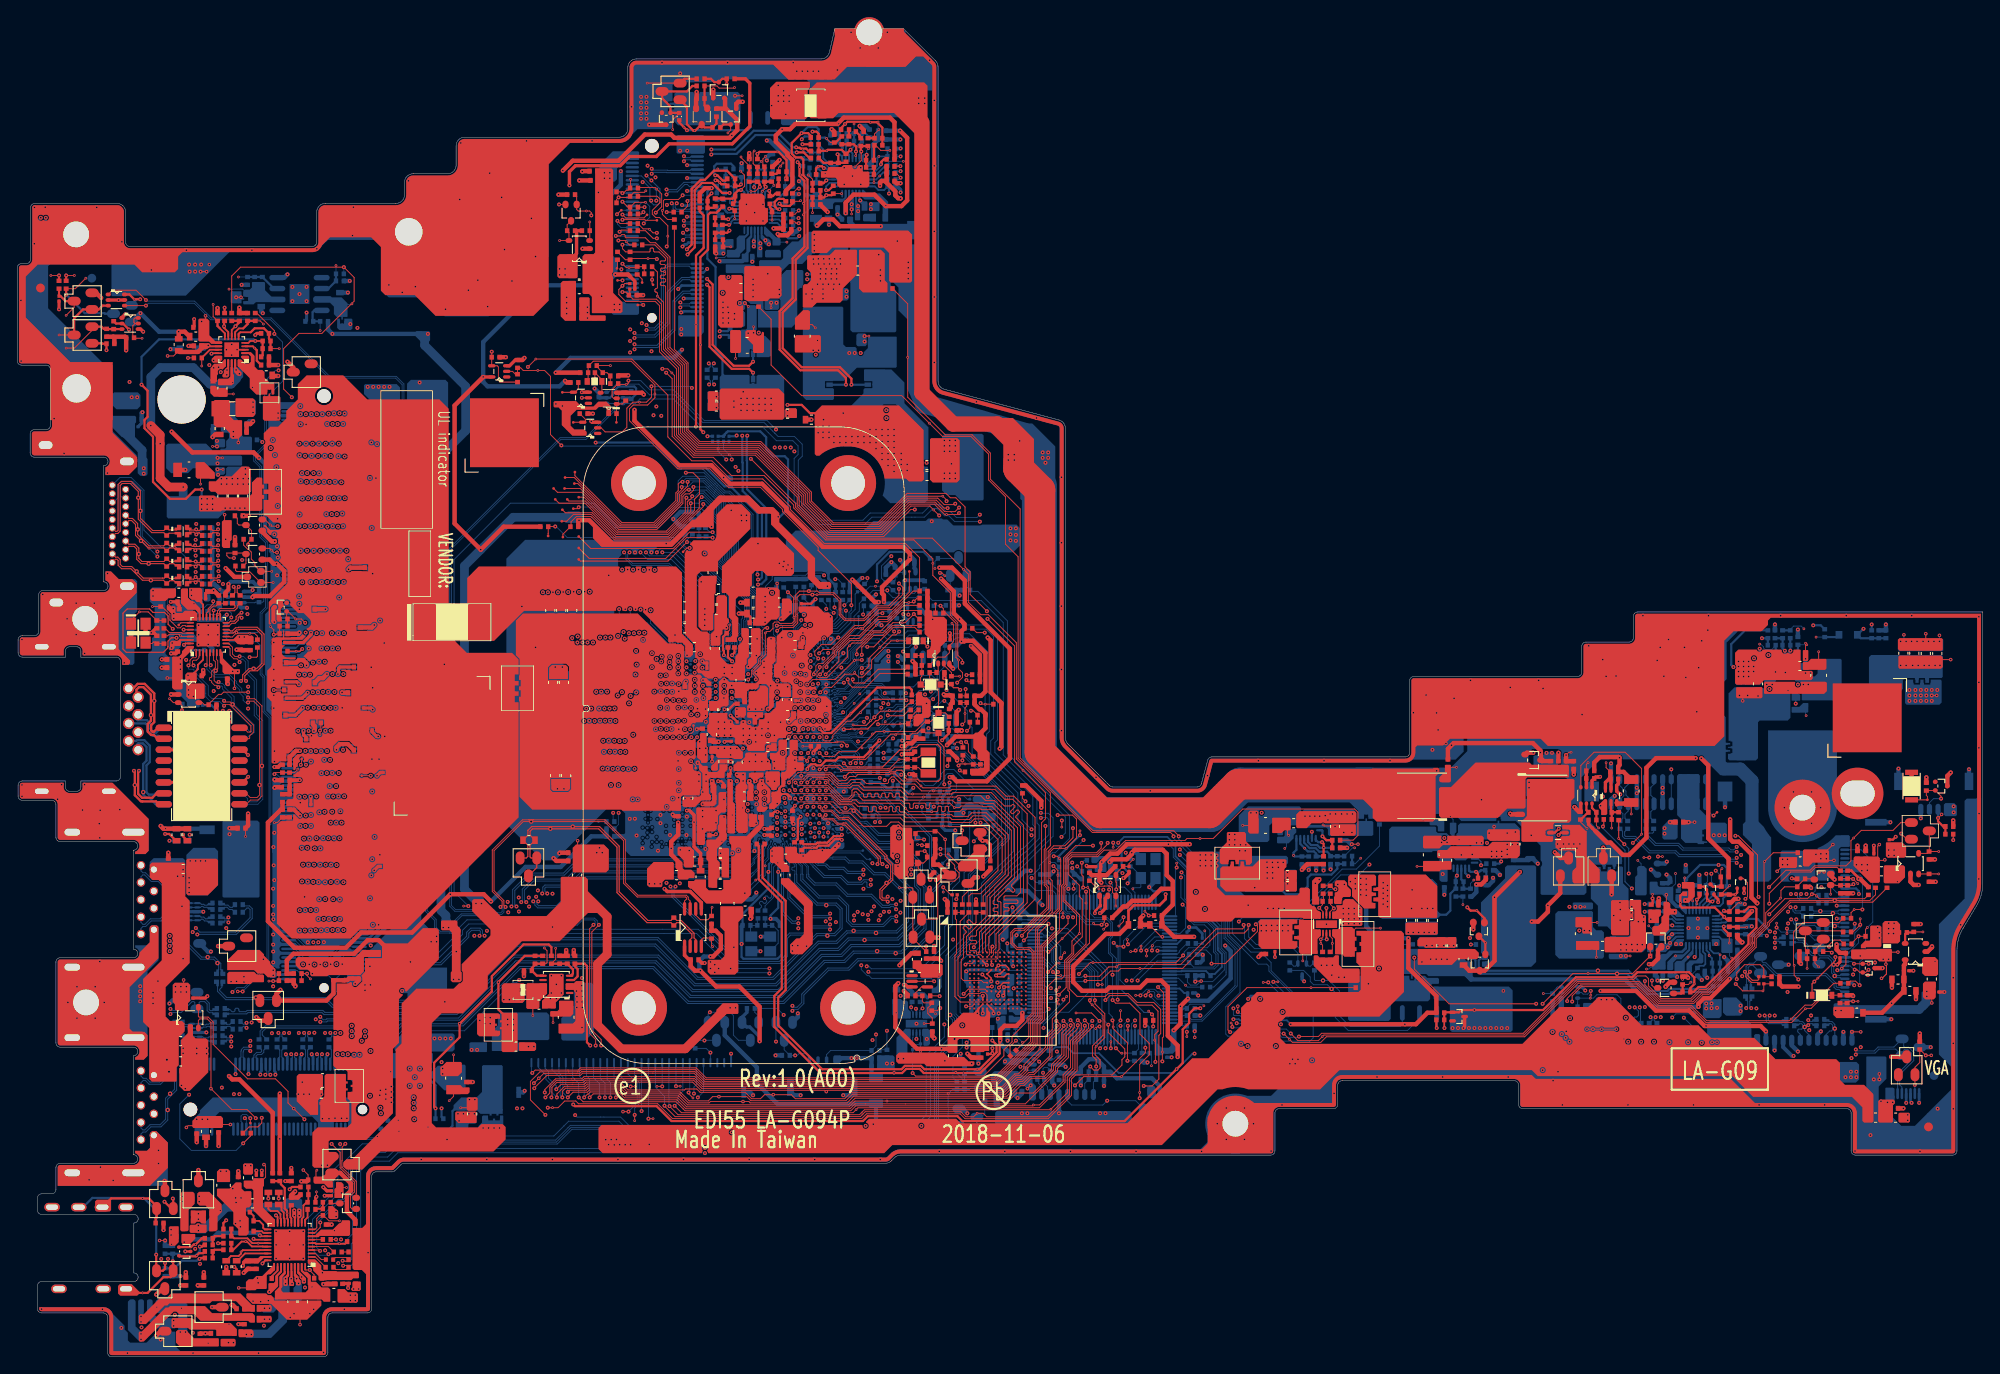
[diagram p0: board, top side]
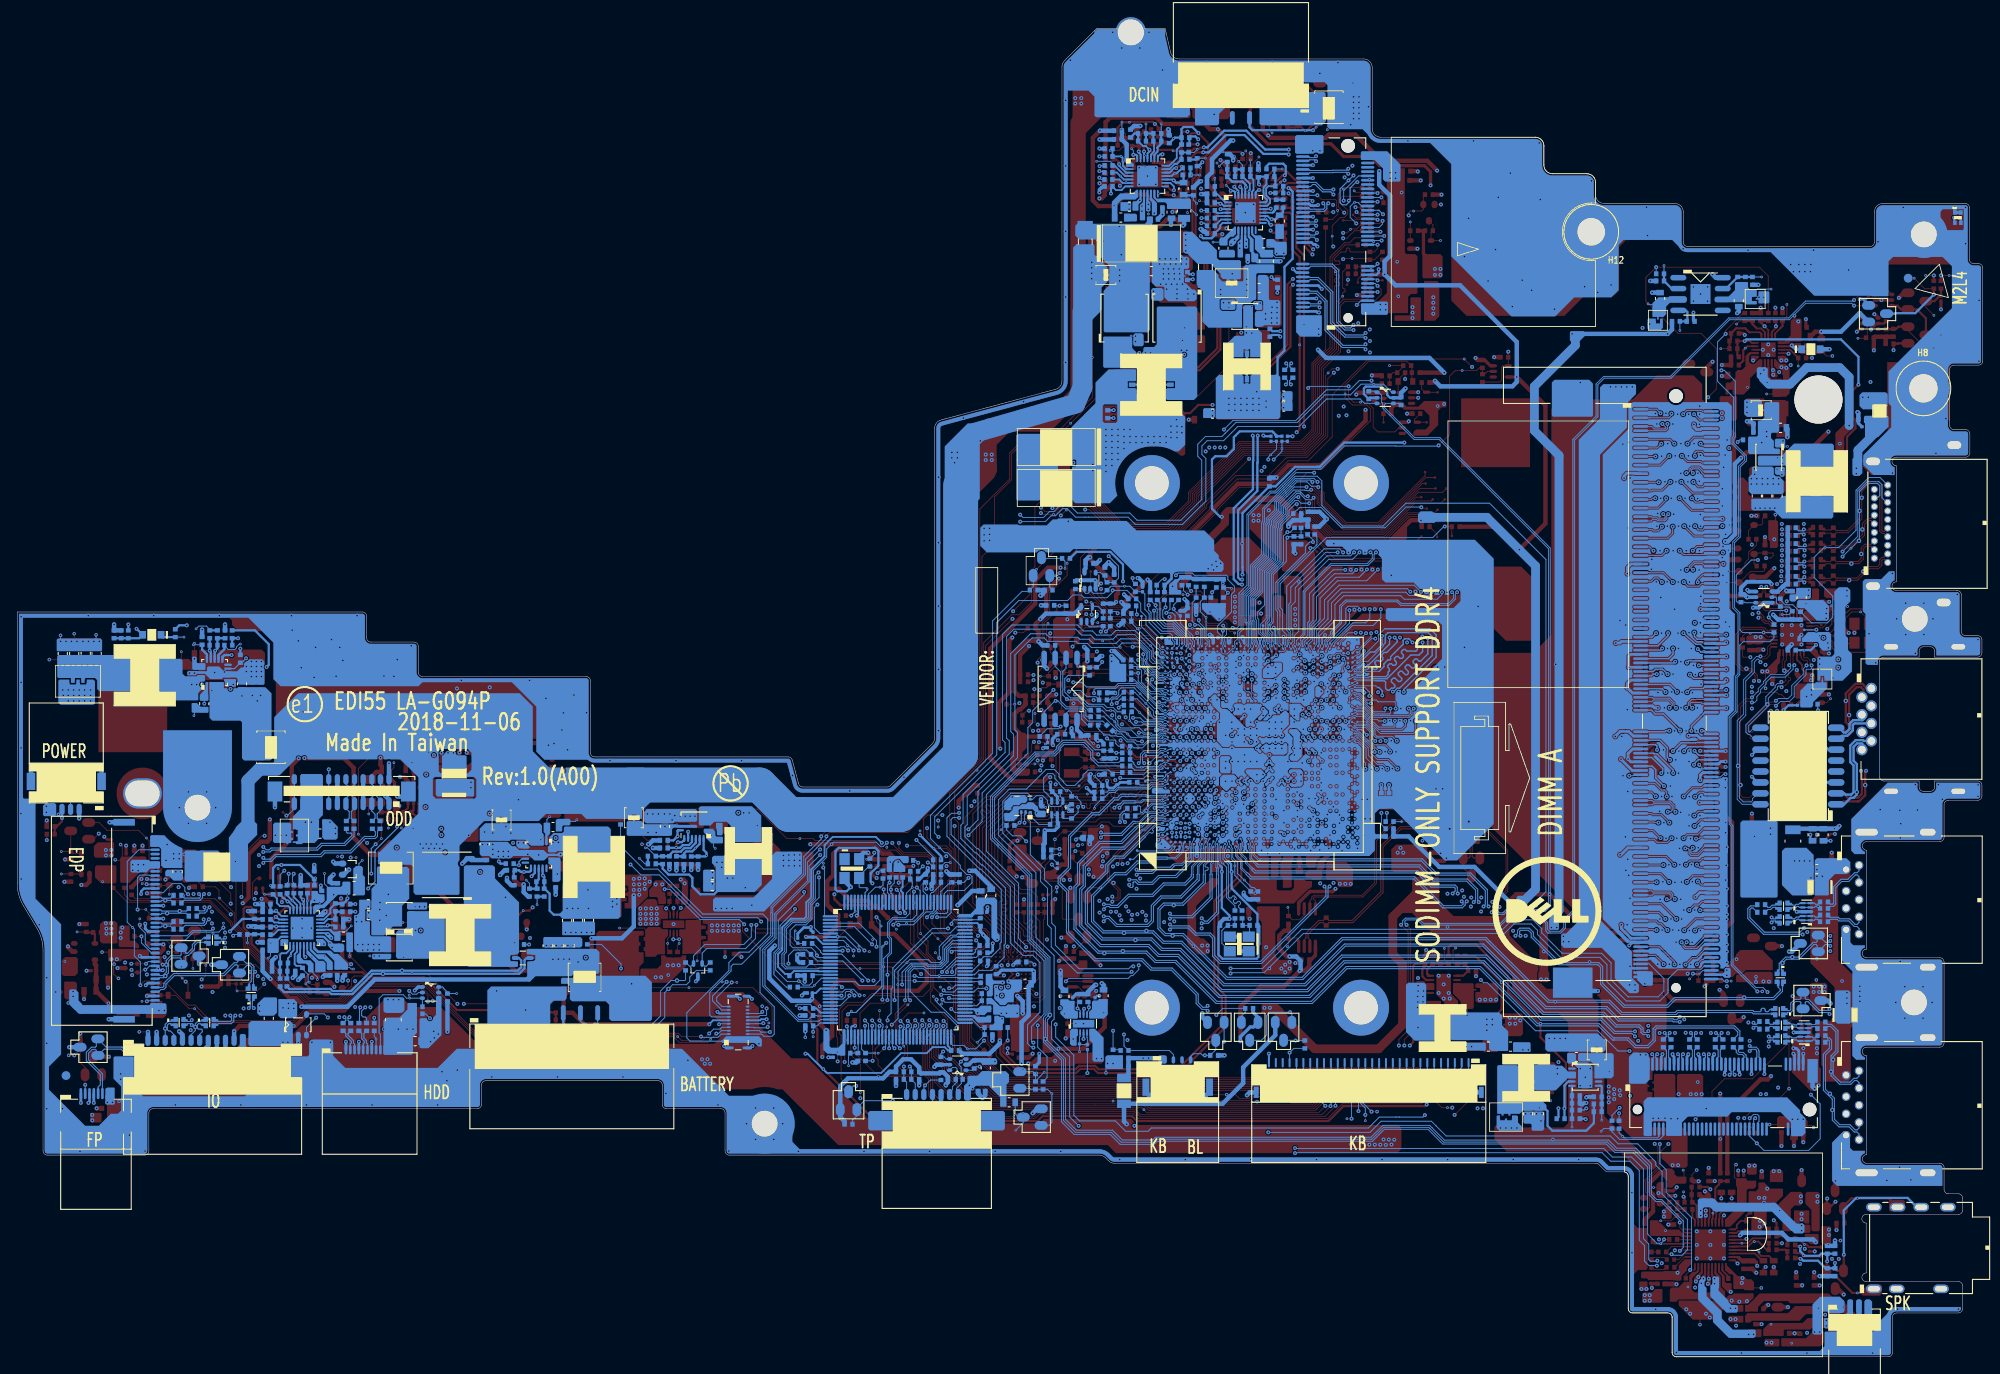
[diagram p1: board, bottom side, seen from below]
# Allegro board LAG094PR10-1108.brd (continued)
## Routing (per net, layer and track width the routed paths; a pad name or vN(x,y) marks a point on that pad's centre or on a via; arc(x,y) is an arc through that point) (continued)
I2C_6_SCL: length 142.1
  TOP w0.102: R87.2 R85.1 202.95,45.17 202.54,45.59 200.71,45.59 199.81,44.69 v2(199.81,43.92)
  IN2 w0.127: v2(199.81,43.92) 199.55,43.92 198.55,42.91 192.28,42.91 191.96,42.59 191.38,42.59 190.7,43.26 187.04,43.26 185.57,44.73 155.28,44.73 153.09,46.92 151.04,46.92 148.87,49.09 142.86,49.09 141.52,50.42 140.08,50.42 139.05,51.45 137.28,51.45 136.94,51.8 134.63,51.8 133.29,53.13 130.36,53.13 127.08,56.41 121.99,56.41 121.83,56.57 121.83,58.13 120.33,59.63 119.69,59.63 117.99,61.32 v2(117.86,61.32)
  BOTTOM w0.089: UC1.C48 94.78,80.14 95.07,80.42 95.42,80.42 95.6,80.6 96.45,80.6 96.81,80.96 96.81,81.94 98.34,83.47 98.53,83.47
  BOTTOM w0.102: v2(117.86,61.32) 116.76,62.43 116.76,65.75 112.64,69.86 112.64,72.4 112.95,72.7 112.95,81.78 110.66,84.07 108.87,84.07 108.47,83.66 105.16,83.66 104.93,83.43 103.85,83.43 103.37,82.95 100.72,82.95 100.2,83.47 98.53,83.47
I2C_6_SDA: length 141.7
  TOP w0.102: v2(199.7,43.34) 200.5,42.54 v1(202.85,42.54) 202.95,42.64 R84.1 R86.2
  IN2 w0.127: v2(117.86,60.64) 119.56,58.94 120.29,58.94 121.32,57.92 121.32,56.36 121.78,55.9 126.87,55.9 130.14,52.62 133.08,52.62 134.42,51.29 136.72,51.29 137.07,50.94 138.84,50.94 139.87,49.92 141.31,49.92 142.64,48.58 148.66,48.58 150.83,46.41 152.88,46.41 155.07,44.22 185.36,44.22 186.83,42.76 190.49,42.76 191.17,42.08 192.17,42.08 192.49,42.4 198.76,42.4 v2(199.7,43.34)
  BOTTOM w0.089: 98.53,82.99 98.11,82.99 97.02,81.9 97.02,81.2 97.14,81.08 97.14,80.65 96.38,79.89 96.06,79.89 95.67,79.5 95.17,79.5 95.1,79.43 94.86,79.43 94.79,79.5 94.65,79.5 94.46,79.69 UC1.C47
  BOTTOM w0.102: 98.53,82.99 100,82.99 100.52,82.47 103.57,82.47 104.05,82.95 105.13,82.95 105.36,83.18 108.67,83.18 109.07,83.59 110.46,83.59 112.47,81.58 112.47,72.9 112.16,72.6 112.16,69.66 116.28,65.55 116.28,62.23 v2(117.86,60.64)
I2C_SCL_TP: length 4.5
  BOTTOM w0.102: Q10.6 119.71,33.65 119.35,33.65 119.2,33.5 v2(119.2,33.02) 119.2,32.72 119.34,32.58 R46.2 119.18,32.09 119.18,31.96 119.73,31.41 119.73,31.05 120.05,30.73 JTP1.6
I2C_SDA_TP: length 5.2
  BOTTOM w0.102: JTP1.7 119.05,30.81 119.25,31.01 119.25,31.21 118.7,31.76 118.7,32.09 R47.2 118.54,32.52 118.72,32.7 118.72,33.7 118.94,33.92 118.94,34.13 v2(118.75,34.32) 118.45,34.62 Q10.3
ILMT_1.05V: length 3.9
  BOTTOM w0.254: PUH01.12 148.64,58.94 148.31,58.61 v1(148.31,58.29) 148.42,58.17 PRH03.2 PRH04.1
IMON_VCCGI: length 2.4
  BOTTOM w0.203: PRG39.2 93.29,137.93 93.35,137.93 93.68,137.6 v1(93.89,137.6) 93.95,137.6 94.27,137.28 PUG1.18
IMON_VNN: length 1.9
  BOTTOM w0.203: PUZ1.18 82.51,133.03
  BOTTOM w0.254: 82.51,133.03 82.39,133.15 82.39,133.16 82.25,133.3 82.25,133.33 82.1,133.49 PRZ24.2
INT_TP#: length 12.4
  BOTTOM w0.102: JTP1.4 122.05,29.74 122.53,29.27 126.15,29.27 v2(126.65,29.78) 129.97,29.78 130.83,28.91 Q9.3 130.83,28.01 131.34,27.5 R39.2
INTRUDE: length 20.7
  TOP w0.102: v1(104.62,59.56) 105.04,59.56 v2(105.12,59.48) 105.17,59.43 RC73.2
  IN1 w0.127: v2(105.12,59.48) 104.96,59.64 104.96,61.14 102.93,63.17 100.04,63.17 97.82,65.38 97.82,67.31 96.87,68.26 95.74,68.26 94.28,69.72 92.85,69.72 v2(92.52,69.39)
  BOTTOM w0.089: v2(92.52,69.39) 92.5,69.39 UC1.H25
ISOLATE#: length 3
  TOP w0.102: UL1.20 22.4,86.91 22.78,87.29 23.11,87.29 RL4.1 RL3.2
JACK_PLUG: length 23.7
  TOP w0.254: v2(17.12,18.03) 17.9,17.24 DA9.3 18.13,18.35 v2(18.08,18.4) ; RA51.1 31.93,19.74 v2(31.66,19.47)
  IN2 w0.254: v2(18.08,18.4) 18.08,17.95 18.58,17.46 23.59,17.46 25.18,19.05 29.82,19.05 30.24,19.47 v2(31.66,19.47) ; v2(17.12,18.03) 13.28,18.03 JHP1.5
JACK_PLUG_DET: length 9.1
  TOP w0.254: RA62.2 16.09,16.06 16.15,16.12 16.15,16.2 16.2,16.25 DA9.2 16.2,17.5 15.29,18.41 v1(14.58,18.41) 10.91,18.41 JHP1.6
JHDD_P10: length 2.3
  BOTTOM w0.102: RS61.2 186.91,37.26 186.7,37.04 v1(186.7,36.95) JHDD1.8
KB_BL_CTRL#: length 4.9
  BOTTOM w0.102: Q8.1 89.12,35.7 EC3001.1 v2(90.39,35.05) 90.65,35.05 90.84,35.24 91.73,35.24 92.05,34.92 JKBBL1.4
KB_DET#: length 148.7
  TOP w0.102: v2(120.9,62.98) 122.62,62.98 123.08,62.52 123.08,60.31 v1(121.89,59.11) 120.43,59.11 120,58.69 120,55.61 120.26,55.35 120.26,51.7 118.35,49.79 118.35,39.73 117.75,39.13 117.75,36.66 113.52,32.43 80.05,32.43 78.9,33.59 74.12,33.59 65.44,33.59 65.19,33.33 65.18,33.33 64,33.33 64,33.33 60.18,33.33 v2(59.85,33)
  IN1 w0.127: v2(120.9,62.98) 120.9,64.34 117.64,67.6 117.64,83.12 111.57,89.19 108.97,89.19 108.29,88.51 104.27,88.51 103.58,87.82 102.48,87.82 100.71,86.04 98.97,86.04 97.96,85.02 97.22,85.02 96.4,84.2 93.61,84.2 91.73,82.31 91.73,80.76 v2(92.19,80.2)
  BOTTOM w0.089: v2(92.19,80.2) 92.19,79.66 UC1.H47
  BOTTOM w0.102: JKB1.1 59.75,33.1 v2(59.85,33)
KB_LED_BL_DET: length 66.4
  TOP w0.102: v2(96.43,71.05) 95.99,71.49 v1(95.24,71.49) 95.18,71.43 91.16,71.43 90.53,72.07 v2(90.39,72.07)
  IN1 w0.127: v2(96.43,71.05) 96.01,70.63 95.62,70.63 95.58,70.67 90.16,70.67 89.94,70.45 89.94,68.26 90.27,67.94 91.37,67.94 91.61,67.7 94.7,67.7 96.81,65.59 96.81,64.96 97.95,63.82 97.95,62.94 99.4,61.5 101.04,61.5 101.7,62.15 102.51,62.15 103.36,61.31 103.36,59.44 105.08,57.72 106.65,57.72 108.52,55.85 108.52,54.91 107.11,53.51 107.11,49.93 104.75,47.56 104.75,42.16 101.06,38.48 v2(101.06,37.9)
  BOTTOM w0.089: UC1.M29 v2(90.39,72.07)
  BOTTOM w0.102: R26.1 100.26,35.7 R27.1 v2(101.06,37.9)
KB_LED_DET_C: length 8.1
  BOTTOM w0.102: JKBBL1.2 94.05,35.15 94.52,35.62 R26.2 99.79,36.14 v2(99.79,37.48)
KB_LED_PWM: length 56.3
  TOP w0.102: v1(131.49,42.46) 131.12,42.09 v2(131.12,42.01)
  IN1 w0.127: v2(88.17,36.65) 88.72,36.1 97.62,36.1 98.1,35.62 106.84,35.62 109,37.78 116.37,37.78 118.4,39.81 118.4,43.22 119.31,44.13 121.19,44.13 122.87,42.45 130.68,42.45 131.12,42.02 v2(131.12,42.01)
  BOTTOM w0.102: Q8.2 88.16,36.66 v2(88.17,36.65) ; v2(131.12,42.01) 131.58,42.48 132.05,42.48 132.18,42.35 132.18,41.86 132.45,41.59 132.94,41.59 132.97,41.62 UE1.25
KSI0: length 69.1
  TOP w0.102: v2(123.24,38.55) 123.24,38.17 v1(122.5,37.43) 122.14,37.07 122.14,34.79 120.87,33.52 120.87,33.15 117.14,29.41 103.2,29.41 97.34,29.41 96.77,28.84 77.69,28.84 76.7,29.83 76.65,29.88 70.47,29.88 69.78,30.56 66.92,30.56 v2(66.52,30.16)
  BOTTOM w0.102: v2(123.24,38.55) 123.24,38.42 123.48,38.17 UE1.55 ; JKB1.9 66.15,32.69 66.52,32.32 v2(66.52,30.16)
KSI1: length 73
  TOP w0.102: v2(123.24,39.14) 123.64,38.73 123.64,38.01 122.4,36.76 122.4,33.65 121.53,32.79 121.53,32.02 118.8,29.28 v1(118.08,29.28) 117.98,29.18 97.44,29.18 96.87,28.61 77.6,28.61 77.38,28.82 76.56,29.65 65.76,29.65 v2(65.25,30.16)
  BOTTOM w0.102: UE1.56 123.08,38.11 122.83,38.36 122.83,38.73 v2(123.24,39.14) ; v2(65.25,30.16) 65.25,31.81 64.55,32.51 JKB1.7
KSI2: length 71.2
  TOP w0.102: v2(63.98,30.16) 64.59,30.77 66.25,30.77 66.5,31.02 69.99,31.02 70.67,30.34 76.84,30.34 76.89,30.28 77.88,29.29 96.58,29.29 97.36,30.07 115.13,30.07 116.58,31.52 116.97,31.52 117.83,32.38 119.46,32.38 120.42,33.34 120.42,33.83 121.64,35.05 121.64,37.47 122.41,38.25 v2(122.41,38.55)
  BOTTOM w0.102: UE1.57 122.68,38.19 122.41,38.46 v2(122.41,38.55) ; JKB1.5 62.95,32.96 63.41,32.51 63.41,30.73 v2(63.98,30.16)
KSI3: length 70.9
  TOP w0.102: v2(65.88,30.16) 66.26,30.54 66.34,30.54 66.6,30.79 69.88,30.79 70.57,30.11 76.75,30.11 77.79,29.07 96.68,29.07 97.35,29.74 v1(101.06,29.74) 115.18,29.74 116.11,30.67 118.07,30.67 120.65,33.24 120.65,33.68 121.89,34.92 121.89,37.33 122.82,38.26 122.82,38.72 v2(122.4,39.14)
  BOTTOM w0.102: v2(65.88,30.16) 65.88,32.06 65.35,32.6 JKB1.8 ; UE1.58 122.28,38.1 122,38.38 122,38.74 v2(122.4,39.14)
KSI4: length 71.2
  TOP w0.102: v2(121.6,38.48) 121.6,38.32 120.24,36.96 120.24,34.91 118.17,32.84 117.64,32.84 116.8,32 116.3,32 114.83,30.53 97.05,30.53 96.3,29.78 85.24,29.78 84.77,30.25 v3(81.54,30.25) 80.8,30.25 80.3,29.75 78.07,29.75 77.32,30.5 77.13,30.69 77.08,30.74 77.03,30.79 70.87,30.79 70.19,31.48 66.31,31.48 66.06,31.22 63.71,31.22 63.34,30.86 v2(63.34,30.16)
  BOTTOM w0.102: JKB1.4 62.15,33.38 63.09,32.44 63.09,30.41 v2(63.34,30.16) ; v2(121.6,38.48) 121.6,38.39 121.88,38.1 UE1.59
KSI5: length 71.1
  TOP w0.102: v2(63.98,30.79) 64.18,31 66.15,31 66.41,31.25 70.09,31.25 70.77,30.56 76.93,30.56 77.04,30.46 77.17,30.33 77.17,30.33 77.23,30.27 77.23,30.27 77.98,29.52 80.4,29.52 80.55,29.68 v3(84.34,29.68) 85.02,29.68 85.17,29.52 96.43,29.52 97.21,30.3 114.98,30.3 116.45,31.77 116.9,31.77 117.73,32.61 119.37,32.61 120.19,33.43 120.19,33.98 121.38,35.17 121.38,37.66 122,38.29 122,38.64 121.59,39.06 v2(121.57,39.06)
  BOTTOM w0.102: UE1.60 121.48,38.02 121.19,38.31 121.19,38.68 v2(121.57,39.06) ; JKB1.6 63.75,31.72 63.98,31.49 v2(63.98,30.79)
KSI6: length 68.2
  TOP w0.102: v2(120.79,38.48) 120.79,38.24 119.73,37.18 119.73,35.91 117.42,33.6 117.42,33.3 116.58,32.46 116.11,32.46 114.64,30.98 94.17,30.98 v3(94.01,30.83) 93.86,30.98 79.44,30.98 78.49,31.94 73.43,31.94 66.12,31.94 66,31.82 65.87,31.68 64.5,31.68 63.22,31.68 v2(62.65,31.11)
  BOTTOM w0.102: JKB1.3 61.35,33.55 61.74,33.16 61.74,32.39 62.65,31.49 v2(62.65,31.11) ; UE1.61 121.08,38.08 120.79,38.37 v2(120.79,38.48)
KSI7: length 73.3
  TOP w0.102: v2(120.75,39.06) 120.78,39.06 121.19,38.65 121.19,38.29 119.99,37.08 119.99,34.98 118.07,33.07 117.54,33.07 116.71,32.23 116.21,32.23 114.73,30.75 96.9,30.75 96.15,30.01 90.42,30.01 89.95,30.48 v3(87.85,30.48) 86.84,30.48 86.37,30.01 85.34,30.01 84.59,30.75 79.35,30.75 78.97,31.14 77.66,31.14 77.54,31.02 70.98,31.02 70.29,31.71 66.22,31.71 65.96,31.45 63.61,31.45 62.71,30.55 v2(62.71,30.16)
  BOTTOM w0.102: v2(120.75,39.06) 120.38,38.69 120.38,38.31 120.68,38.01 UE1.62 ; JKB1.2 60.55,33.65 61.44,32.76 61.44,32.25 62.01,31.68 62.01,30.86 v2(62.71,30.16)
KSO0: length 76.4
  TOP w0.102: v2(73.35,27.68) v1(73.88,27.68)
  IN1 w0.127: v2(129.89,38.48) 130.08,38.29 130.08,34.6 128.81,33.33 128.81,28.87 127.34,27.39 112.34,27.39 110.61,29.12 109.07,29.12 97.4,29.12 96.46,28.18 81.59,28.18 80.57,27.16 80.36,27.16 80.36,27.16 73.87,27.16 v2(73.35,27.68)
  BOTTOM w0.102: v2(129.89,38.48) 129.88,38.47 UE1.39 ; JKB1.18 v2(73.35,27.68)
KSO1: length 80.4
  TOP w0.102: v2(71.75,28.13) v1(71.75,27.45)
  IN1 w0.127: v2(71.75,28.13) 72.97,26.91 80.25,26.91 80.67,26.91 81.69,27.92 96.56,27.92 97.5,28.86 108.12,28.86 108.96,28.86 110.69,27.14 127.44,27.14 129.07,28.76 129.07,33.14 130.34,34.41 130.34,38.67 v2(129.89,39.11)
  BOTTOM w0.102: JKB1.16 71.75,32.43 72.27,31.9 72.27,29.43 71.75,28.91 v2(71.75,28.13) ; UE1.40 129.48,38.7 v2(129.89,39.11)
KSO2: length 75.3
  TOP w0.102: v2(129.05,38.48) v1(129.05,37.98)
  IN1 w0.127: v2(129.05,38.48) 129.19,38.34 129.19,35.87 127.67,34.35 127.67,28.44 127.12,27.9 112.55,27.9 110.82,29.63 110.61,29.63 110.61,29.62 110.4,29.62 107.81,29.62 107.8,29.62 97.19,29.62 96.25,28.68 81.37,28.68 80.46,27.77 80.25,27.77 74.37,27.77 73.57,28.57 v2(72.55,28.57)
  BOTTOM w0.102: v2(129.05,38.48) 129.08,38.45 UE1.41 ; v2(72.55,28.57) 72.55,28.57 JKB1.17
KSO3: length 80.2
  TOP w0.102: v2(71.03,28.51) v3(70.39,28.51)
  IN1 w0.127: v2(129.05,39.11) 129.47,38.69 129.47,35.77 127.92,34.22 127.92,28.34 127.23,27.64 112.45,27.64 110.72,29.37 110.51,29.37 107.91,29.37 97.29,29.37 96.35,28.43 81.48,28.43 80.46,27.41 74.34,27.41 73.63,28.13 72.36,28.13 71.85,28.63 71.15,28.63 v2(71.03,28.51)
  BOTTOM w0.102: JKB1.15 70.95,32.9 72.04,31.81 72.04,29.52 v2(71.03,28.51) ; v2(129.05,39.11) 128.62,38.68 128.62,38.1 128.68,38.04 UE1.42
KSO4: length 74.8
  IN1 w0.127: v2(68.3,30.16) 69.19,29.27 73.63,29.27 74.54,28.35 80.33,28.35 81.16,29.19 96.04,29.19 96.98,30.13 107.59,30.13 110.19,30.13 110.19,30.13 111.03,30.13 112.1,29.07 124.61,29.07 125.83,30.28 125.83,31.75 126.84,32.76 126.84,34.26 128.3,35.72 128.3,38.37 v2(128.2,38.48)
  BOTTOM w0.102: v2(128.2,38.48) 128.28,38.4 UE1.43 ; JKB1.11 67.75,32.36 68.3,31.81 v2(68.3,30.16)
KSO5: length 78.9
  TOP w0.102: v2(128.2,39.11) v1(128.2,40.24)
  IN1 w0.127: v2(67.66,30.16) 68.8,29.01 73.5,29.01 74.49,28.02 80.36,28.02 81.27,28.94 96.14,28.94 97.08,29.88 107.7,29.88 110.3,29.88 110.3,29.88 110.93,29.88 112,28.81 124.82,28.81 127.42,31.4 127.42,34.48 128.62,35.68 128.62,38.67 128.2,39.09 v2(128.2,39.11)
  BOTTOM w0.102: v2(67.66,30.16) 67.66,31.75 66.95,32.46 JKB1.10 ; UE1.44 127.88,38.2 127.8,38.29 127.8,38.65 128.2,39.05 v2(128.2,39.11)
KSO6: length 71.1
  TOP w0.102: v2(127.67,35.87) 128.24,35.3 v1(128.37,35.3)
  IN1 w0.127: v2(69.57,30.16) 70.84,30.16 71.43,29.56 73.72,29.56 74.67,28.61 80.22,28.61 81.06,29.45 81.27,29.45 82.53,29.45 82.53,29.45 95.93,29.45 96.87,30.39 97.32,30.39 97.53,30.39 97.53,30.39 98.38,30.39 98.38,30.39 98.97,30.39 109.6,30.39 110.09,30.39 110.09,30.39 111.14,30.39 112.21,29.32 124.48,29.32 125.57,30.41 125.57,31.87 126.59,32.89 126.59,34.41 127.67,35.49 v2(127.67,35.87)
  BOTTOM w0.102: v2(69.57,30.16) 69.57,32.13 69.35,32.34 JKB1.13 ; UE1.45 127.48,36.06 v2(127.67,35.87)
KSO7: length 71.5
  TOP w0.102: v2(127.08,35.87) v1(127.08,36.63)
  IN1 w0.127: v2(68.93,30.16) 69.5,30.73 70.65,30.73 71.56,29.82 73.61,29.82 77.57,29.82 78.53,28.86 79.87,28.86 81.85,30.84 111.4,30.84 112.67,29.57 124.35,29.57 125.32,30.54 125.32,32 126.34,33.02 126.34,35.13 v2(127.08,35.87)
  BOTTOM w0.102: JKB1.12 68.55,32.25 68.93,31.87 v2(68.93,30.16) ; v2(127.08,35.87) UE1.46
KSO8: length 67.4
  TOP w0.102: v2(71.28,31.43) v1(71.79,31.43)
  IN1 w0.127: v2(71.28,31.43) 71.28,31.3 72.51,30.07 73.51,30.07 77.68,30.07 78.63,29.12 79.77,29.12 81.74,31.1 81.95,31.1 111.29,31.1 111.3,31.1 115.86,31.1 117.13,29.83 124.23,29.83 125.07,30.67 125.07,32.13 126.08,33.14 126.08,35.49 v2(126.46,35.87)
  BOTTOM w0.102: UE1.47 126.68,36.09 v2(126.46,35.87) ; v2(71.28,31.43) 70.15,32.56 JKB1.14
KSO9: length 60.7
  TOP w0.102: v2(78.01,30.73) 78.01,30.6 v1(78.52,30.09)
  IN1 w0.127: v2(78.01,30.73) 78.15,30.59 78.15,29.96 78.73,29.38 79.66,29.38 81.64,31.35 81.85,31.35 82.06,31.35 111.19,31.35 115.75,31.35 115.96,31.35 117.23,30.08 124.1,30.08 124.81,30.79 124.81,32.25 125.83,33.27 v2(125.83,35.87)
  BOTTOM w0.102: UE1.48 126.28,36.33 v2(125.83,35.87) ; JKB1.24 78.15,30.87 v2(78.01,30.73)
KSO10: length 61.1
  TOP w0.102: v1(125.31,38.16) 125.56,38.41 v2(125.76,38.41)
  IN1 w0.127: v2(125.76,38.41) 125.76,36.83 123.92,34.98 123.92,33.21 124.3,32.82 124.3,31.05 123.85,30.59 117.44,30.59 116.07,31.96 80.89,31.96 v2(79.09,30.16)
  BOTTOM w0.102: JKB1.26 79.75,30.82 v2(79.09,30.16) ; v2(125.76,38.41) 125.88,38.29 UE1.49
KSO11: length 66.5
  TOP w0.102: v2(125.76,39.05) 124.83,39.98 v1(123.03,39.98)
  IN1 w0.127: v2(78.63,30.6) 78.63,29.98 78.99,29.63 79.39,29.63 81.37,31.61 81.74,31.61 82.16,31.61 111.08,31.61 115.65,31.61 116.07,31.61 117.34,30.34 123.97,30.34 124.56,30.92 124.56,33.02 124.18,33.4 124.18,34.86 126.21,36.89 126.21,38.6 v2(125.76,39.05)
  BOTTOM w0.102: JKB1.25 78.95,31.67 78.63,31.35 v2(78.63,30.6) ; UE1.50 125.48,38.11 125.36,38.24 125.36,38.64 v2(125.76,39.05)
KSO12: length 65.4
  TOP w0.102: v2(75.22,29.19) 75.22,29.15 76.45,27.92 97.97,27.92 98.18,28.14 98.29,28.24 98.54,28.49 109.64,28.49 110.23,27.91 111.13,27.91 v1(111.54,28.32) 112.24,28.32 112.64,27.91 119.71,27.91 122.27,30.48 122.27,32.38 123.16,33.27 123.16,36.55 124.91,38.31 v2(124.91,38.48)
  BOTTOM w0.102: UE1.51 125.08,38.31 v2(124.91,38.48) ; v2(75.22,29.19) 75.22,30.28 74.15,31.35 JKB1.19
KSO13: length 62.8
  TOP w0.102: v2(76.55,31.47) v1(77.03,31.47)
  IN1 w0.127: v2(124.93,39.06) 125.34,38.65 125.34,36.84 123.67,35.17 123.67,33.08 124.05,32.7 124.05,31.17 123.72,30.84 117.55,30.84 116.18,32.22 115.97,32.22 115.23,32.22 115.23,32.22 115.02,32.22 77.3,32.22 v2(76.55,31.47)
  BOTTOM w0.102: v2(124.93,39.06) 124.92,39.06 124.51,38.65 124.51,38.31 124.68,38.13 UE1.52 ; v2(76.55,31.47) JKB1.22
KSO14: length 61.5
  TOP w0.102: v2(124.05,38.5) 124.05,38.09 122.65,36.69 122.65,33.52 121.76,32.63 121.76,31.93 118.79,28.95 97.7,28.95 v1(97.47,28.73) 97.13,28.38 77.19,28.38 v2(76.39,29.17)
  BOTTOM w0.102: v2(124.05,38.5) 124.28,38.27 UE1.53 ; v2(76.39,29.17) 76.81,29.59 76.81,30.35 77.35,30.89 JKB1.23
KSO15: length 64.6
  TOP w0.102: v2(75.8,29.15) 75.78,29.15 76.78,28.15 97.87,28.15 98.09,28.37 98.09,28.37 98.19,28.47 98.19,28.47 98.45,28.72 120.05,28.72 v1(120.12,28.79) 122.02,30.69 122.02,32.51 122.91,33.4 122.91,36.62 124.49,38.21 124.49,38.68 v2(124.05,39.12)
  BOTTOM w0.102: v2(124.05,39.12) 123.64,38.72 123.64,38.33 123.88,38.09 UE1.54 ; JKB1.21 75.72,34.17 75.72,29.22 v2(75.8,29.15)
KSO16: length 69
  TOP w0.102: v2(74.95,31.44) v1(74.34,31.44)
  IN1 w0.127: v2(119.26,38.24) 119.26,36.1 118.78,35.62 114.84,35.62 111.8,32.57 75.93,32.57 74.95,31.59 v2(74.95,31.44)
  BOTTOM w0.102: UE1.81 119.16,45.22 119.33,45.05 119.33,44.54 119.54,44.33 122.28,44.33 123.07,45.12 124.25,45.12 124.65,44.72 124.65,42.5 122.21,40.06 120.71,40.06 119.26,38.62 v2(119.26,38.24) ; v2(74.95,31.44) JKB1.20
L_BKLT_CTRL: length 152.4
  TOP w0.102: v2(210.85,46.99) 210.73,47.11 R8.1
  IN1 w0.127: v2(210.85,46.99) 210.98,47.11 210.98,51.77 209.48,53.27 205.96,53.27 203.04,56.19 199.76,56.19 198.1,57.86 195.87,57.86 193.89,55.88 192.77,55.88 191.93,55.04 189.07,55.04 187.43,56.68 183.53,56.68 182.07,55.21 181.62,55.21 180.92,55.21 180.92,55.22 178.48,55.22 178.38,55.11 178.23,54.96 177.79,54.96 173.51,54.96 171.73,53.18 170.02,53.18 168.51,51.67 167.95,51.67 165.1,48.83 162.41,48.83 161.3,47.72 153,47.72 152.85,47.87 151.24,47.87 147.83,51.28 138.04,51.28 137.36,51.96 136.16,51.96 135.74,51.96 135.74,51.96 135.53,51.96 134.55,51.96 134.46,51.87 127.57,51.87 126.49,52.95 125.7,52.95 124.94,53.72 124.94,57.46 120.42,61.99 120.42,62.15 119.97,62.6 119.97,64.19 116.87,67.29 116.87,80.9 112.91,84.87 111.36,84.87 109.79,86.44 104.93,86.44 104.31,85.83 104.01,85.83 v2(103.55,86.29)
  BOTTOM w0.102: v2(103.55,86.29) 103.55,87.14 UC8.4 102.77,87.23 RC4.1 RC5.1
LAN_MDIN0: length 15.8
  TOP w0.089: v2(20.48,80.39) 20.35,80.51 20.35,80.88 20.47,80.99 20.83,80.99 21.12,81.28 21.12,81.47 21.2,81.55 UL1.2 ; v2(24.04,76.27) 24.18,76.13 24.75,76.13 v4(25.03,75.86) 27.43,73.45 27.43,72.61 27.02,72.19 27.02,71.94 26.93,71.86 TL1.15
  BOTTOM w0.089: v2(24.04,76.27) 23.77,76.54 22.62,76.54 22.2,76.96 22.2,78.04 20.86,79.37 20.86,80.01 v2(20.48,80.39)
LAN_MDIN1: length 23.7
  TOP w0.089: UL1.5 22.4,81.55 22.34,81.49 22.34,80.57 v2(22.49,80.41) ; v2(26.82,76.66) 26.97,76.51 27.59,76.51 28.44,75.67 v4(28.44,68.7) 28.44,65.19 27.98,64.73 27.11,64.73 26.62,64.24 TL1.9
  BOTTOM w0.089: v2(26.82,76.66) 26.09,77.4 26.09,77.7 25.46,78.33 25.46,78.53 24.69,79.31 23.07,79.31 22.32,80.06 22.32,80.25 v2(22.49,80.41)
LAN_MDIN2: length 13.9
  TOP w0.089: v2(23.4,78.46) 23.29,78.35 23.15,78.35 22.88,78.62 22.88,79.6 v4(23.06,79.77) 23.3,80.02 23.3,80.94 23.15,81.09 23.15,81.53 23.2,81.58 UL1.7
  BOTTOM w0.089: TL2.10 26.59,71.86 27.08,72.35 27.28,72.35 27.53,72.61 27.53,73.48 25.21,75.8 25.21,75.96 25.21,75.97 25.21,76.74 24.13,77.82 24.13,78.02 23.87,78.27 23.59,78.27 v2(23.4,78.46)
LAN_MDIN3: length 23.6
  TOP w0.089: v2(25.84,81.43) 25.29,81.43 25.02,81.71 25.02,82.5 24.7,82.82 24.66,82.82 24.53,82.94 UL1.10
  BOTTOM w0.089: v2(25.84,81.43) 26.29,81.43 26.83,80.89 26.83,79.69 27.82,78.69 27.82,74.68 28.54,73.97 28.54,64.82 27.96,64.24 TL2.16
LAN_MDIP0: length 15.8
  TOP w0.089: TL1.16 26.28,73.13 26.77,72.64 27.06,72.64 27.15,72.73 27.15,73.34 24.64,75.85 24.2,75.85 v2(24.04,75.69) ; UL1.1 20.8,81.53 20.83,81.49 20.83,81.39 20.72,81.28 20.35,81.28 20.07,80.99 20.07,80.56 v2(19.9,80.39)
  BOTTOM w0.089: v2(19.9,80.39) 19.9,80.01 19.97,79.94 20.46,79.94 20.54,79.85 20.54,79.29 21.91,77.92 21.91,77.15 21.91,76.73 22.45,76.2 23.52,76.2 23.76,75.95 23.77,75.95 v2(24.04,75.69)
LAN_MDIP1: length 23.6
  TOP w0.089: v2(26.82,76.08) 26.97,76.23 27.48,76.23 28.15,75.55 v4(28.15,66.48) 28.15,65.31 27.86,65.02 27.08,65.02 26.59,65.51 TL1.10 ; v2(21.9,80.41) 22.05,80.57 22.05,81.47 22,81.53 UL1.4
  BOTTOM w0.089: v2(21.9,80.41) 22.04,80.28 22.04,79.94 22.96,79.02 24.57,79.02 25.18,78.42 25.18,78.21 25.81,77.58 25.81,77.22 26.25,76.78 26.25,76.33 26.51,76.07 26.81,76.07 v2(26.82,76.08)
LAN_MDIP2: length 13.9
  TOP w0.089: v2(23.37,77.85) 23.15,78.07 22.92,78.07 22.6,78.39 22.6,78.53 22.51,78.62 22.42,78.62 22.33,78.71 22.33,78.89 22.42,78.98 22.51,78.98 22.6,79.07 22.6,79.71 23.02,80.13 23.02,80.82 22.82,81.02 22.82,81.47 22.8,81.5 UL1.6
  BOTTOM w0.089: TL2.9 26.59,73.13 27.08,72.64 27.16,72.64 27.25,72.73 27.25,73.37 24.93,75.69 24.93,75.97 24.93,76.58 23.85,77.66 23.85,77.9 23.76,77.99 23.51,77.99 v2(23.37,77.85)
LAN_MDIP3: length 23.5
  TOP w0.089: v2(25.84,80.77) 25.84,80.85 25.54,81.15 25.18,81.15 24.74,81.59 24.74,82.34 24.53,82.54 UL1.9
  BOTTOM w0.089: TL2.15 26.15,65.51 26.77,64.89 26.77,64.66 26.9,64.52 27.84,64.52 28.26,64.94 28.26,73.85 27.54,74.57 27.54,78.58 26.55,79.57 26.55,80.78 26.21,81.11 26.09,81.11 25.84,80.87 v2(25.84,80.77)
LANXIN: length 3.3
  TOP w0.102: UL1.28 19.67,84.14 19.66,84.14 19.18,84.14 19.11,84.21 17.67,84.21 17.19,84.69 RL8.2
LANXIN_R: length 5.1
  TOP w0.102: YL2.1 13.22,85.62 14.19,86.6 v1(14.19,86.61) 15.22,86.61 CL10.2 RL8.1
LANXOUT: length 3.3
  TOP w0.102: RL9.2 17.48,83.83 17.66,84.01 18.79,84.01 v1(18.97,83.83) 19.06,83.74 UL1.29
LANXOUT_R: length 2.3
  TOP w0.102: YL2.3 15.02,82.93 15.66,82.93 15.84,83.1 16.04,83.1 CL11.2 RL9.1
LCD_BRIGHTNESS: length 6
  TOP w0.102: R303.1 213.33,49.4 v2(214.16,50.22) v1(214.16,50.92)
  BOTTOM w0.102: v2(214.16,50.22) 214.16,49.91 213.52,49.27 213.52,48 212.97,47.45 JEDP1.27
LCD_CBL_DET#: length 140.5
  TOP w0.102: R100.2 214.67,53.26 209.4,53.26 v1(209.08,53.59) 208.89,53.78 v2(208.54,53.78) 208.03,53.26 205.41,53.26 v2(203.59,51.45) ; RC1149.2 109.23,53.31 v2(109.13,53.21)
  IN1 w0.127: v2(109.13,53.21) 109.13,51.24 109.32,51.05 109.32,46.98 109.06,46.73 109.06,44.7 109.4,44.37 110.68,44.37 111.6,45.29 111.6,49.44 112.64,50.48 116.69,50.48 119.17,47.99 120.09,47.99 120.5,47.59 121.76,47.59 124.13,45.22 124.89,45.22 125.65,44.46 126.13,44.46 126.59,44 127.84,44 128.61,44.76 131.41,44.76 132.11,45.46 137.52,45.46 139.76,43.22 142.32,43.22 142.78,42.77 143.93,42.77 145.3,41.4 174.43,41.4 175.76,42.73 179.94,42.73 181.73,40.94 186.27,40.94 186.47,41.14 192.97,41.14 194.37,42.54 198.83,42.54 199.19,42.9 200.37,42.9 201.77,44.3 201.77,49.4 203.59,51.21 v2(203.59,51.45)
  BOTTOM w0.102: JEDP1.14 211.45,53.95 210.38,55.01 209.36,55.01 208.92,54.58 208.92,54.16 v2(208.54,53.78)
LCD_CBL_DET#_R: length 30.6
  TOP w0.102: v2(107.6,54.59) 108.48,53.72 RC1149.1
  IN1 w0.089: 89.71,67.86 90.38,67.19 94.76,67.19 95.47,66.48 95.47,65.78 96.71,64.54
  IN1 w0.102: 89.3,70.05 89.13,70.22 v2(88.94,70.22)
  IN1 w0.127: v2(107.6,54.59) 107.43,54.77 107.43,56.58 106.55,57.46 104.97,57.46 102.83,59.61 100.93,59.61 97.63,62.9 97.63,63.62 96.71,64.54 ; 89.3,70.05 89.51,69.85 89.51,68.07 89.71,67.86
  BOTTOM w0.089: UC1.P27 v2(88.94,70.22)
  BOTTOM w0.102: v2(107.6,54.59) v1(107.6,54.03)
LCD_TEST: length 108.4
  TOP w0.102: v2(206.97,43.87) 206.48,44.36 v1(206.48,45.52) 206.41,45.59 206.41,49.4 207.5,50.49 D3.3 211.68,50.49 R304.2
  IN1 w0.127: v2(120.13,41.71) 120.13,41.57 121.83,39.87 128.43,39.87 129.07,40.51 134.84,40.51 138.53,36.83 146.35,36.83 146.97,36.2 161.59,36.2 164.18,38.79 179.04,38.79 180.67,37.16 195.78,37.16 199.99,41.37 201.77,41.37 204.27,43.87 v2(206.97,43.87)
  BOTTOM w0.102: v2(120.13,41.71) 120.04,41.62 UE1.72
LCD_TST_C: length 8
  TOP w0.102: R304.1 213.09,51.63 v1(213.46,52) v2(214.41,52)
  BOTTOM w0.102: JEDP1.10 213.02,55.95 213.08,56 214.16,56 214.41,55.75 v2(214.41,52)
LCDVDD_EN: length 4.8
  TOP w0.102: v1(223.27,58.75) R10.1 ; R10.1 221.95,58.54 U1.4 ; R10.1 222.18,58.77 D4.1
LDO1_CAP: length 3.5
  TOP w0.203: UA1.21 28.76,14.81 28.58,14.99 28.58,15.35 28.13,15.81 CA479.2 27.47,16.39 RA47.2
LDO2_CAP: length 1.6
  TOP w0.203: CA482.2 29.57,9.34 30.26,10.03 UA1.32
LDO3_CAP: length 4.3
  TOP w0.203: CA493.2 38.08,13.14 v1(37.44,13.14) 34.71,13.14 34.63,13.21 UA1.6
LED0: length 2.2
  TOP w0.102: UL1.27 v2(19.34,84.54)
  BOTTOM w0.102: T18.1 19.37,84.51 v2(19.34,84.54)
LED1: length 1.5
  TOP w0.102: T19.1 19.02,85.34 UL1.25
LG_1.2V: length 15.1
  TOP w0.102: v2(23.28,103.18) v1(23.91,103.18)
  IN2 w0.762: 22.32,103.12 20.42,105.02 20.42,107.75 22.58,109.91 22.58,112.71 21.59,113.7 21.59,115.48
  vias: v2(22.83,115.84) v2(23.34,102.55) v2(23.41,115.84)
LG_CHG: length 6.5
  TOP w0.102: v2(186.93,46.6) v1(187.42,46.6)
  IN2 w0.762: 193.07,47.24 192.31,46.48 187.42,46.48
  vias: v2(186.34,46.6) v2(192.76,47.99) v2(193.34,47.99)
LG_VCCGI: length 7.4
  TOP w0.102: v2(96.96,133.42) v1(96.96,132.88)
  IN2 w1.016: 96.53,125.1 96.53,132
  vias: v2(96.36,123.88) v2(96.36,123.25) v2(96.96,134.01)
LG_VNN: length 5.7
  TOP w0.102: v2(84.55,122.51) v1(84.95,122.12)
  IN2 w0.762: 85.17,128.38 84.36,127.57 84.36,123.57
  vias: v2(83.97,122.51) v2(85.59,129.69) v2(85.59,129.1)
LID_CLOSE#: length 4
  TOP w0.102: v2(223.2,62.64) v3(223.62,63.06)
  TOP w0.254: R22.2 EC2902.1 223.81,61.65 223.2,62.26 v2(223.2,62.64)
  BOTTOM w0.254: JPWR1.3 v2(223.2,62.64)
LID_SW#: length 142
  TOP w0.127: D5.1 208.56,43.36 v2(208.82,43.62) v1(209.23,44.03) 211.27,46.07 v2(211.27,46.48) ; R22.1 v2(224.96,60.08)
  IN1 w0.127: v2(127.03,55.14) 127.26,54.91 128.29,54.91 129.99,53.21 133.77,53.21 134.31,53.75 134.93,53.75 134.93,53.76 135.35,53.76 135.35,53.75 135.91,53.75 136.64,53.02 142.04,53.02 142.07,52.99 147.75,52.99 151.35,49.39 151.49,49.39 151.49,49.39 151.83,49.39 152.5,49.39 153.34,48.54 159.21,48.54 160.99,50.33 165.43,50.33 168.79,53.69 171.52,53.69 173.3,55.47 177.58,55.47 178.02,55.47 178.17,55.62 178.27,55.72 181.13,55.72 181.13,55.72 181.41,55.72 181.41,55.72 181.85,55.72 183.32,57.18 187.64,57.18 189.28,55.55 191.72,55.55 192.56,56.38 193.68,56.38 195.66,58.36 198.29,58.36 199.63,59.7 200.49,59.7 204.97,55.22 209.99,55.22 212,53.21 212,47.2 v2(211.27,46.48) ; v2(224.96,60.08) 224.96,54.24 223.17,52.45 221.2,52.45 219.79,51.04 219.79,46.91 216.51,43.62 v2(208.82,43.62)
  BOTTOM w0.102: RE34.1 v2(127.03,55.14) 127.28,54.89 127.28,53.98 127.08,53.78 UE1.115
LINE1-L_C: length 7.8
  TOP w0.254: RA59.1 23.96,15.55 v2(24.28,15.88) ; 29.18,19.11 v2(29.18,18.41)
  IN2 w0.254: v2(29.18,18.41) 27.66,16.89 25.29,16.89 v2(24.28,15.88)
LINE1-L_R: length 11.1
  TOP w0.254: 30.39,19.11 v2(30.39,18.41) ; RA55.1 v2(23.34,13.2)
  IN2 w0.254: v2(30.39,18.41) 28.29,16.31 25.5,16.31 23.34,14.16 v2(23.34,13.2)
LINE1_L: length 3.2
  TOP w0.203: CA500.1 29.18,17.22 29.45,16.95 30.23,16.95 30.59,16.59 30.59,16.06 30.66,15.99 UA1.18
LINE1_R: length 2.4
  TOP w0.203: UA1.17 31.06,16.05 30.97,16.14 30.97,16.77 30.72,17.03 30.72,17.38 CA503.1
LOM_TCT: length 14.6
  TOP w0.102: v1(26.53,60.51) CL12.1
  TOP w0.254: v2(26.83,67.43) 26.83,67.43 26.18,66.78 TL1.11 ; v2(26.82,69.97) 26.2,70.59 TL1.14
  TOP w0.508: v2(26.83,63.15) 26.83,61.77 CL12.1
  IN1 w0.508: v2(26.82,69.97) 26.82,67.44 v2(26.83,67.43) v2(26.83,63.15)
  BOTTOM w0.254: v2(26.82,69.97) 26.83,69.97 26.21,70.59 TL1.14 ; TL1.11 26.18,66.78 v2(26.83,67.43)
LPC_AD0: length 41.6
  TOP w0.102: RC23.2 109.89,69.4 v2(109.83,69.34) ; v2(131.86,47.24) 131.86,47.75 v1(131.92,47.81)
  IN1 w0.127: v2(131.86,47.24) 130.53,45.91 126.53,45.91 125.74,46.69 124.64,46.69 121.94,49.39 119.84,49.39 113.38,55.84 113.38,61.38 109.95,64.81 109.95,69.21 v2(109.83,69.34)
  BOTTOM w0.102: UE1.10 132.82,47.62 132.75,47.68 132.3,47.68 v2(131.86,47.24)
LPC_AD0_R: length 17.8
  TOP w0.102: v1(108.94,71.24) 109.15,71.46 v2(109.67,71.46) 109.89,71.25 RC23.1
  IN1 w0.127: v2(98.74,74.29) 98.81,74.22 98.81,73.57 99.56,72.83 100.54,72.83 100.67,72.96 103.34,72.96 103.67,72.64 108.5,72.64 v2(109.67,71.46)
  BOTTOM w0.102: v2(98.74,74.29) 97.91,74.29 97.48,73.86 95.34,73.86 UC1.A34
LPC_AD1: length 56.1
  TOP w0.102: v2(131.23,47.24) v1(131.23,46.6)
  IN1 w0.127: v2(131.23,47.24) 130.15,46.16 126.63,46.16 125.85,46.94 124.75,46.94 121.79,49.9 120.88,49.9 119.99,50.8 119.15,50.8 113.89,56.05 113.89,61.59 110.78,64.7 110.78,73.13 109.96,73.95 102.55,73.95 101.32,75.18 100.71,75.18 100.41,75.48 100.41,75.47 v2(100.41,75.47)
  BOTTOM w0.102: v2(131.23,47.24) 132.4,48.42 UE1.8 ; v2(100.41,75.47) 100.41,75.47 100.41,75.48 100.14,75.75 RC22.2
LPC_AD1_R: length 5
  BOTTOM w0.089: 98.53,75.44 v1(97.98,74.89) 97.13,74.04 95.47,74.04 95.41,74.1 95.22,74.1 95.06,73.99 94.93,73.99 UC1.C34
  BOTTOM w0.102: 98.53,75.44 98.84,75.75 RC22.1
LPC_AD2: length 56.3
  TOP w0.102: v2(130.59,47.24) v1(130.59,47.75)
  IN1 w0.127: v2(100.64,76) 100.64,75.86 101.07,75.43 101.42,75.43 102.65,74.2 110.07,74.2 111.03,73.24 111.03,64.81 114.14,61.7 114.14,56.18 119.28,51.05 120.18,51.05 121.07,50.15 121.9,50.15 124.85,47.2 125.96,47.2 126.74,46.41 129.76,46.41 v2(130.59,47.24)
  BOTTOM w0.102: RC21.2 100.14,76.51 v2(100.64,76) ; v2(130.59,47.24) 132.17,48.82 UE1.7
LPC_AD2_R: length 5.1
  BOTTOM w0.089: 98.53,76.51 98.28,76.51 96.74,74.98 v1(96.74,74.61) 96.36,74.22 95.54,74.22 95.49,74.28 95.12,74.28 UC1.B35
  BOTTOM w0.102: RC21.1 98.53,76.51
LPC_AD3: length 57.1
  TOP w0.102: v2(129.96,47.24) 129.83,47.11 v1(129.38,47.11)
  IN1 w0.127: v2(101.22,75.88) 101.35,75.88 102.78,74.46 110.17,74.46 111.29,73.34 111.29,64.92 114.4,61.8 114.4,56.31 119.4,51.3 120.28,51.3 121.18,50.41 122,50.41 124.96,47.45 126.06,47.45 126.84,46.67 129.38,46.67 v2(129.96,47.24)
  BOTTOM w0.102: RC20.2 99.83,77.27 100.6,76.5 101.08,76.5 101.22,76.36 v2(101.22,75.88) ; v2(129.96,47.24) 132.33,49.62 UE1.5
LPC_AD3_R: length 6.1
  BOTTOM w0.089: UC1.C35 94.6,74.28 94.78,74.47 94.89,74.54 95.11,74.54 95.19,74.45 95.56,74.45 95.62,74.4 96.14,74.4 96.36,74.62 96.36,75.09 v1(97.25,75.98) 98.49,77.22 98.53,77.22
  BOTTOM w0.102: 98.53,77.22 98.59,77.27 RC20.1
LPC_CLK0: length 9.6
  BOTTOM w0.089: UC1.C37 94.61,75.18 94.88,74.92 95.11,74.92 95.2,75.01 95.35,75.01 95.72,75.37 96.22,75.37 97.72,76.87 97.72,76.89 v1(97.92,77.08) 98.53,77.7 98.53,77.73
  BOTTOM w0.102: 98.53,77.73 98.59,77.78 100.11,77.78 100.4,77.49 100.4,76.99 100.69,76.7 101.16,76.7 101.49,76.38 RC24.1
LPC_CLK_EC: length 70.9
  IN2 w0.127: v2(129.51,43.75) 128.62,42.86 122.65,42.86 121.71,43.8 118.66,43.8 115.35,47.11 111.67,47.11 v2(111.16,47.62) ; v2(107.98,77.54) 106.35,77.54 v2(106.16,77.35)
  BOTTOM w0.102: RE26.2 135.93,48.06 135.04,47.17 135.04,47.05 134.8,46.82 UE1.12 133.15,46.82 132.58,46.82 v2(129.51,43.75) ; CC2.1 102.66,76.4 RC24.2 103.06,76.75 104.11,76.75 104.82,77.47 106.05,77.47 v2(106.16,77.35) ; v2(107.98,77.54) 110.4,75.12 110.4,73.74 110.96,73.18 110.96,70.19 115.78,65.36 115.78,58.79 112.04,55.04 112.04,48.62 111.16,47.75 v2(111.16,47.62)
LPC_FRAME#: length 60.2
  TOP w0.102: v1(129,48.51) 129,48.02 v2(129.07,47.96)
  IN1 w0.127: v2(129.07,47.96) 128.83,48.19 128.07,48.19 127.56,47.68 127.27,47.68 126.48,48.47 125.38,48.47 123.36,50.48 123.36,51.38 122.55,52.19 121.57,52.19 119.6,54.16 118.41,54.16 115.67,56.9 115.67,62.79 113.46,65 113.46,65.36 112.62,66.21 112.62,76.39 112.05,76.96 109.48,76.96 108.24,75.73 106.5,75.73 105.49,76.73 v2(105.49,77.02)
  BOTTOM w0.102: UE1.4 131.12,50.02 v2(129.07,47.96) ; RC19.2 100.55,74.99 101.04,75.48 101.74,75.48 102.13,75.87 103.91,75.87 105.02,76.98 105.46,76.98 v2(105.49,77.02)
LPC_FRAME#_R: length 5.6
  BOTTOM w0.089: UC1.B33 95.04,73.37 95.04,73.38 95.53,73.38 95.65,73.5 97.67,73.5 97.73,73.44 98.53,73.44
  BOTTOM w0.102: 98.53,73.44 98.62,73.44 v1(99.15,73.96) 99.15,74.73 RC19.1
LX_1.2V: length 12.8
  TOP w0.102: v2(23.28,104.52) v1(23.85,104.52)
  TOP w0.508: PRM01.1 v2(19.53,103.12)
  IN2 w0.762: 22.96,114.13 23.91,113.18 23.91,109.22 21.94,107.25 21.94,105.47 22.96,104.45
  vias: v2(22.83,114.98) v2(23.28,103.88) v2(23.4,115.06)
LX_1.05V: length 1.3
  TOP w0.102: PRH07.1 v1(142.4,61.78)
  vias: v2(143.35,63.24) v2(143.99,63.24)
LX_1.8V: length 1.4
  TOP w0.102: PR1804.1 v1(50.71,35.11)
  vias: v2(49.44,33.52) v2(49.44,32.89)
LX_1.24V:
  vias: v2(64.98,42.53) v2(65.05,41.89) v2(65.05,41.26) v2(65.03,40.62) v2(65.62,43.16) v2(65.62,42.53) v2(65.64,41.26) v2(65.68,41.89) v2(65.67,40.62) v3(65.63,38.29)
LX_3V:
  vias: v1(167.55,60.13) v2(165.52,59.81) v2(166.15,59.81) v2(169.58,59.75) v2(170.15,59.75)
LX_5V:
  vias: v1(205.77,77.47) v2(203.3,78.16) v2(203.93,78.16) v2(207.55,78.16) v2(208.12,78.16)
LX_CHG: length 10
  TOP w0.102: PRB40.1 v1(183.59,50.5)
  IN2 w0.762: 191.12,48.04 190.46,48.7 184.08,48.7 183.37,49.41 183.32,49.41
  vias: v2(182.1,49.56) v2(182.69,49.54) v2(191.8,47.61) v2(192.06,48.12)
LX_VCCGI: length 15.3
  IN2 w1.016: 98.05,132.42 98.07,132.41 98.07,122.73 97,121.66 97,117.55
  vias: v1(93,118.17) v2(92.49,117.03) v2(93.13,117.03) v2(96.68,116.71) v2(97.32,116.71) v2(97.71,133.79) v2(97.71,133.21)
LX_VNN: length 9.5
  TOP w0.102: v2(85.57,119.06) v1(85.57,119.76)
  IN2 w0.762: 85.57,119.88 86.78,121.09 86.78,127.67 86.42,128.02
  vias: v2(84.93,119.02) v2(86.34,129.47) v2(86.34,128.89)
MASK_SATA_LED#: length 233.9
  TOP w0.102: v2(124.19,54.08) v1(124.19,52.76) 124.19,47.98 122.09,45.88 122.09,42.6 122.28,42.41 122.28,41.28 120.28,39.28 120.28,38.06 119.49,37.27 119.49,35.99 117.19,33.69 117.19,33.39 116.48,32.69 116,32.69 114.53,31.21 79.55,31.21 78.59,32.16 73.53,32.16 66.03,32.16 65.78,31.91 64.59,31.91 62.72,31.91 62.14,31.33 62.14,30.22 v2(62.07,30.16)
  TOP w0.254: v2(10.37,117.04) R5216.2 9.88,117.79 9.83,117.84 Q22.2
  IN1 w0.127: v2(25.18,30.54) 23.21,30.54 21.43,32.32 21.43,39.56 21.18,39.81 21.18,43.62 25.82,48.26 25.82,72.85 26.07,73.11 26.07,77.85 25.5,78.42 25.5,78.66 25.83,79 26.15,79 26.55,79.4 26.55,82.11 24.86,83.8 24.86,85.36 25.56,86.06 25.56,86.8 25.12,87.24 24.67,87.24 23.02,85.59 20.44,85.59 20.23,85.59 20.23,85.59 20.02,85.59 18.55,87.06 18.55,88.98 14.07,93.47 14.07,102.98 14.26,103.17 14.26,103.74 14.97,104.46 14.97,114.85 13.75,116.07 11.4,116.07 10.44,117.04 v2(10.37,117.04)
  IN2 w0.127: v2(62.07,30.16) 59.72,27.81 53.69,27.81 53.01,27.13 44.13,27.13 40.29,27.13 40.28,27.12 39.97,27.12 39.97,27.13 39.32,27.13 39.32,27.12 39.22,27.12 39.02,26.93 38.91,26.93 38.91,26.93 37.81,26.93 25.66,26.93 25.12,27.47 25.12,30.48 v2(25.18,30.54)
  BOTTOM w0.102: v2(124.19,54.08) 124.28,54 UE1.108
MCT: length 8.8
  TOP w0.508: RL20.1 RL22.1 v1(17.24,61.4) 16.99,61.4 v2(16.67,61.72)
  BOTTOM w0.508: CL13.1 21.94,61.4 RL20.1 RL22.1 16.99,61.4 v2(16.67,61.72)
MCT0: length 12.8
  TOP w0.254: TL1.3 18.02,70.59 v2(18.39,70.23)
  IN2 w0.254: v2(17.69,60) 17.69,69.53 v2(18.39,70.23)
  BOTTOM w0.254: v2(17.69,60) RL19.2
MCT1: length 10
  TOP w0.254: RL20.2 19.27,60.51 v2(19.27,60.7) ; TL1.6 18.05,66.78 v2(18.45,67.18)
  IN1 w0.254: v2(18.45,67.18) 17.81,66.54 17.81,61.84 18.96,60.7 v2(19.27,60.7)
MCT2: length 14.1
  TOP w0.254: v2(17.18,60.79) 17.66,60.79 18.45,60 RL22.2
  IN2 w0.254: v2(17.18,60.79) 17.18,60.79 17.18,69.85 v2(18.45,71.12)
  BOTTOM w0.254: TL2.6 17.92,70.59 v2(18.45,71.12)
MCT3: length 9.3
  IN1 w0.254: v2(20.04,60.7) 19.55,61.18 19.05,61.18 18.2,62.03 18.2,66.23 v2(18.45,66.48)
  BOTTOM w0.254: v2(20.04,60.7) 20.04,60.26 RL23.2 ; TL2.3 18.15,66.78 v2(18.45,66.48)
MDSI_C_TE_GPIO_43: length 51.8
  TOP w0.102: v2(77.69,102.79) 78.53,102.79 79.28,102.04 79.28,100.29 78.71,99.72 78.71,98.42 75.67,95.39 69.56,95.39 66.81,98.13 63.69,98.13 T54.1
  BOTTOM w0.089: 86.19,86.16 86.19,84.69 86.62,84.26 86.62,83.46 86.97,83.12 86.97,82.82 86.88,82.74 86.88,82.51 87.08,82.31 87.22,82.31 87.81,81.72 88.25,81.72 88.5,81.97 UC1.T53
  BOTTOM w0.102: v2(77.69,102.79) 79.8,102.79 81.1,101.49 81.1,101.49 81.34,101.25 81.34,101.25 82.15,100.44 82.73,100.44 85.3,97.86 85.3,89.55 86.19,88.66 86.19,86.16
ME_EN: length 48.3
  BOTTOM w0.102: QC3.2 110.35,89.53 RC92.1 110.88,89 111.63,89 115.06,85.57 115.06,70.18 122.27,62.97 122.27,60.26 v1(121.19,59.18) 120.62,58.61 120.27,58.61 118.82,57.15 118.82,56.83 118.07,56.08 117.7,56.08 117.46,55.85 117.46,55.1 118.33,54.22 120.3,54.22 120.68,53.85 UE1.99
ME_FWP_SOC_Q: length 34.4
  TOP w0.102: v1(107.79,90.8) 107.45,91.14 v2(107.22,91.14)
  IN1 w0.127: v2(93.76,90.86) 93.89,90.99 95.22,90.99 95.67,90.55 95.67,90.23 96.3,89.59 98.65,89.59 99.86,90.8 101.47,90.8 102.02,91.35 106.65,91.35 106.85,91.14 v2(107.22,91.14)
  BOTTOM w0.089: 87.73,86.16 88.93,84.96 88.93,84.26 88.49,83.82 88.49,83.05 88.5,83.05 UC1.T55
  BOTTOM w0.102: v2(93.76,90.86) 93.51,91.12 91.86,91.12 91.6,90.86 87.88,90.86 87.73,90.71 87.73,90.37 86.94,89.58 86.94,89.02 87.31,88.65 87.31,86.58 87.73,86.16 ; v2(107.22,91.14) 107.53,90.84 QC3.3 108.42,89.47 RC94.1
MIC_CAP: length 2.1
  TOP w0.203: CA26.1 31.73,17.5 31.73,16.21 31.86,16.09 UA1.15
NCT7718_DXN: length 34.1
  TOP w0.127: U2.3 78.84,48.5 78.65,48.7 78.65,49.25 77.16,50.73 76.63,50.73 C23.2 75.97,50.73 73.29,50.73 69.95,54.08 69.95,59.37 67.67,61.64 v4(64.55,61.64) 59.78,61.64 59.34,61.21 59.34,60.64 C22.2 59.33,59.51 59.33,58.18 59.15,58 Q14.3
NCT7718_DXP: length 35.6
  TOP w0.127: Q14.1 60.37,56.88 Q14.2 59.71,58 59.59,58.12 59.59,59.48 C22.1 59.6,60.64 59.6,61.1 59.88,61.39 v4(61.95,61.39) 67.57,61.39 69.69,59.26 69.69,53.97 73.19,50.48 75.97,50.48 C23.1 76.63,50.48 77.06,50.48 78.39,49.14 78.39,48.7 78.19,48.5 U2.2
NTC_CHG: length 2
  BOTTOM w0.203: PUB01.13 192.43,50.04 v2(192.31,50.16) 191.61,50.16 PRB13.2
ODD_DA#: length 5.2
  TOP w0.102: T28.1 197.49,63.3 v2(197.11,62.92)
  BOTTOM w0.102: v2(197.11,62.92) 197.01,62.92 196.2,63.73 JODD1.23 JODD1.24
ON/OFF#: length 129.2
  TOP w0.102: SW1.1 221.95,64.75 T29.1 221.97,65.15 221.84,65.27 EC2901.1 222.86,65.83 ED2901.3 223.55,65.18 v2(223.55,64.89)
  IN1 w0.127: v2(209.65,54.61) 209.29,54.96 204.66,54.96 203.17,56.45 199.87,56.45 198.2,58.11 195.77,58.11 193.79,56.13 192.67,56.13 191.83,55.29 189.17,55.29 187.53,56.93 183.42,56.93 181.96,55.47 181.52,55.47 181.02,55.47 181.02,55.47 178.38,55.47 178.28,55.37 178.12,55.21 177.68,55.21 177.68,55.21 173.41,55.21 171.63,53.44 168.99,53.44 165.62,50.07 161.1,50.07 159.25,48.23 153.21,48.23 152.37,49.07 151.96,49.07 151.22,49.07 147.55,52.73 141.97,52.73 141.93,52.76 136.54,52.76 135.8,53.5 135.24,53.5 135.24,53.5 135.03,53.5 135.03,53.5 134.42,53.5 133.87,52.95 128.25,52.95 v2(126.88,54.33)
  IN2 w0.127: v2(223.55,64.89) 225.27,64.89 225.59,64.57 225.59,58.67 223.43,56.51 218.47,56.51 216.49,54.53 212.77,54.53 212.7,54.61 v2(209.65,54.61)
  BOTTOM w0.102: v2(223.55,64.89) 222.67,64.89 222.2,64.43 JPWR1.2 ; RE55.1 126.49,55.52 126.49,55.08 126.88,54.69 v2(126.88,54.33) 126.88,53.91 126.68,53.72 UE1.114
OSCIN: length 10.5
  BOTTOM w0.089: 87.78,57.33 87.78,57.34 88.3,57.86 88.3,59.11 88.24,59.18 88.24,59.43 UC1.U2
  BOTTOM w0.102: RC71.1 86.48,52.3 86.48,52.44 86.24,52.68 86.24,52.82 86.37,52.95 86.54,52.95 86.77,52.73 86.92,52.73 87.09,52.9 87.09,53.04 v1(86.84,53.29) 86.84,53.44 86.98,53.58 87.12,53.58 87.38,53.33 87.52,53.33 87.66,53.48 87.66,57.21 87.78,57.33
OSCOUT: length 8.1
  BOTTOM w0.089: UC1.T1 88.55,59.25 88.55,57.6 v1(88.37,57.43) 88.26,57.31
  BOTTOM w0.102: RC72.1 86.9,52.43 87.87,53.39 87.87,56.92 88.26,57.31
PBTN_OUT#: length 126.1
  TOP w0.102: UC5.2 69.31,111.44 69.12,111.63 69.12,112.44 RC143.1 69.94,113.05 v1(70.77,113.05) 70.86,113.05 71.03,113.22 v2(71.03,113.5)
  IN1 w0.127: v2(88.17,107.82) 88.24,107.88 90.71,107.88 92.49,106.11 92.49,105.96 92.49,105.96 92.49,104.59 92.49,104.52 91.88,103.91 91.88,99.54 97.09,94.33 109.31,94.33 119.67,83.97 119.67,68.45 127.42,60.7 128.35,60.7 129.74,59.3 133.7,59.3 134.27,58.73 134.27,56.75 134.7,56.32 v2(135.29,56.32)
  BOTTOM w0.102: v2(71.03,113.5) 72.46,113.5 73.53,112.43 76.26,112.43 79.84,108.85 87.14,108.85 v2(88.17,107.82) ; UE1.15 135.94,45.62 CE5.1 136.7,45.31 139.01,45.31 139.29,45.59 139.29,46.79 139.01,47.06 139.01,49.78 138.31,50.48 136.78,50.48 136.25,51.01 136.25,52.66 135.67,53.24 135.67,55.94 v2(135.29,56.32)
PBTN_OUT#_R: length 3.5
  TOP w0.102: UC5.4 67.94,112.24 DC5.1 67.94,113.61 RC139.2 v2(67.13,113.69)
PBTN_OUT#_SOC: length 61.2
  TOP w0.102: v2(96.93,87.38) 96.93,89.9 93.07,93.76 93.07,94.13 88.95,98.26 88.95,98.5 86.35,101.1 82.64,101.1 80.49,103.25 76.74,103.25 71.15,108.83 71.15,110.23 71.59,110.66 73.26,110.66 74.1,111.51 v1(74.1,111.95) 74.1,113 71.34,115.76 66.94,115.76 RC144.2 66.34,115.16 RC145.2 66.34,113.51 DC5.2
  BOTTOM w0.089: UC1.E54 93.35,82.69 93.35,83.65 93.77,84.07
  BOTTOM w0.102: v2(96.93,87.38) 96.93,86.82 96.66,86.55 96.66,85.63 95.39,84.36 94.06,84.36 93.77,84.07
PCH_PLTRST#: length 125.7
  TOP w0.102: RM28.1 106.95,40.24 v2(107.25,40.55) ; v2(116.75,48.95) 116.75,49.03 119.85,52.13 119.85,54.61 119.54,54.91 119.54,58.93 120.05,59.43 120.05,65.55 116.1,69.5 116.1,83.02 112.84,86.28 111.98,86.28 110.52,87.73 110.52,90.99 v1(109.95,91.56) 106.33,95.18 94.03,95.18 90.43,98.78 90.43,99.22 v2(85.25,104.4)
  IN1 w0.127: v2(107.25,40.55) 108.23,41.52 115.52,41.52 116.29,42.29 116.29,48.5 v2(116.75,48.95) ; v2(88.33,78.61) 88.73,79.01 88.73,82.09 89.38,82.74 89.38,84.51 88.3,85.59 88.3,86.08 88.64,86.43 88.64,90.07 87.6,91.11 87.6,96.41 86.55,97.46 86.55,98.15 86.55,103.1 v2(85.25,104.4)
  BOTTOM w0.102: UC1.U44 88.14,78.61 v2(88.33,78.61)
PCH_RSMRST#_AND: length 27.2
  TOP w0.102: DC2.1 107.83,74.87 RC56.2 ; DC2.1 107.06,74.76 106.14,73.85 CC6.1 105.51,73.85 104.37,72.71 v1(100.75,72.71) 99.81,72.71 97.46,70.35 95.5,70.35 94.96,69.81 93.63,69.81 v2(93.24,70.2) ; DC2.1 107.06,77.38 106.54,77.89 105.25,77.89 DC3.2 104.98,78.99 105.11,79.13 RC52.2 RC54.2 RC55.1 RC47.1
  BOTTOM w0.089: UC1.F27 v2(93.24,70.2)
PCH_SMB_CLK: length 105.9
  IN2 w0.127: v2(98.71,45.4) 98.4,45.08 87.49,45.08 v2(87.41,45.16)
  BOTTOM w0.102: JDIMM1.253 39.69,45.74 38.81,45.74 37.06,43.99 37.06,42.53 37.73,41.85 41.22,41.85 43.19,43.82 43.19,45.81 44.3,46.92 48.87,46.92 51.25,49.3 51.25,49.79 52.27,50.81 54.68,50.81 55.78,49.71 74.95,49.71 79.14,49.71 83.7,45.14 87.4,45.14 v2(87.41,45.16) ; v2(98.71,45.4) 98.97,45.4 99.25,45.12 105.02,45.12 107.77,47.86 107.77,50.01 108.19,50.43 108.19,54.66 109.03,55.49 109.03,56.73 110.68,58.38 110.68,62.25 110.84,62.42 110.84,63.15 US2.1 110.52,63.17 110.52,62.74 109.69,61.91 RC84.2 108.19,62.1 QC2.1
PCH_SMB_DATA: length 118
  IN2 w0.127: v2(98.91,44.76) 98.71,44.57 v2(87.41,44.57)
  BOTTOM w0.102: v2(98.91,44.76) 98.9,44.76 98.92,44.76 99.05,44.64 105.22,44.64 108.25,47.66 108.25,49.81 108.67,50.23 108.67,54.46 109.51,55.29 109.51,56.53 113.88,60.89 113.88,64.57 112.92,65.53 110.98,65.53 110.71,65.26 110.71,64.86 US2.4 110.41,64.82 109.99,65.24 109.23,65.24 108.68,64.69 108.68,64.34 108.34,63.99 107.22,63.99 106.89,64.32 QC2.4 106.89,64.88 107.21,65.2 RC83.2 ; JDIMM1.254 32.37,45.43 32.79,45 35.48,45 36.58,43.91 36.58,42.73 36.58,42.33 37.53,41.37 41.43,41.37 43.68,43.62 43.68,45.61 44.5,46.44 48.45,46.44 48.67,46.44 49.07,46.44 51.74,49.1 51.74,49.59 52.47,50.32 54.48,50.32 55.58,49.22 75.15,49.22 78.94,49.22 83.5,44.66 87.32,44.66 v2(87.41,44.57)
PCIE_CRX_C_DTX_N5: length 3.5
  TOP w0.114: UL1.18 23.2,86.39 23.28,86.47 23.28,86.72 23.54,86.99 25.14,86.99 25.31,87.17 25.31,87.31 CL27.2
PCIE_CRX_C_DTX_P5: length 3.6
  TOP w0.114: CL26.2 25.87,87.61 25.56,87.31 25.56,87.07 25.24,86.74 23.64,86.74 23.52,86.62 23.52,86.45 23.6,86.38 UL1.17
PCIE_CRX_DTX_N0: length 68
  IN2 w0.089: v2(92.7,61.47) 92.54,61.62 92.05,61.62 91.78,61.35 91.78,60.31 91.47,60 90.43,60 90,59.57 90,59.51 89.98,59.49
  IN2 w0.127: v2(38.42,35.18) 38.78,35.54 40.45,35.54 40.88,35.97 41.41,35.97 46.77,41.33 52.26,41.33 54.38,43.45 57.14,43.45 64.48,50.79 77.4,50.79 84.13,57.52 88.32,57.52 89.35,58.55 89.35,58.86 89.98,59.49
  BOTTOM w0.089: v2(92.7,61.47) 92.57,61.59 92.31,61.59 UC1.H6
  BOTTOM w0.114: v2(38.42,35.18) 38.25,35.01 38.25,34.79 38.38,34.67 JSSD1.5
PCIE_CRX_DTX_N1: length 74.2
  IN2 w0.089: 90.71,59.59 90.73,59.61 90.79,59.61 90.93,59.75 92.29,59.75 92.4,59.86 92.93,59.86 93.02,59.95 93.02,60.18 93.1,60.27 93.28,60.27 93.37,60.18 93.37,59.95 93.46,59.86 93.73,59.86 94.15,60.29 94.15,60.53 94.04,60.65 93.88,60.65 v2(93.7,60.47)
  IN2 w0.127: 90.71,59.59 89.8,58.67 89.8,58.28 88.6,57.08 84.63,57.08 84.31,57.08 76.81,49.59 65.09,49.59 58.52,43.02 54.55,43.02 52.38,40.84 46.92,40.84 41.94,35.87 41.94,35.45 41.43,34.94 40.58,34.94 40.09,34.45 35.31,34.45 35.1,34.66 35.1,34.85 35.42,35.17 v2(35.42,35.18)
  BOTTOM w0.114: v2(35.42,35.18) 35.24,35 35.24,34.8 35.38,34.67 JSSD1.17 ; UC1.E5 93.7,60.51 93.7,60.48 v2(93.7,60.47)
PCIE_CRX_DTX_N2: length 81
  IN2 w0.089: 92.98,59.26 93,59.27 93.06,59.27 93.25,59.47 93.84,59.47 94.65,60.28 94.65,61.28 94.45,61.47 v2(93.71,61.47)
  IN2 w0.127: v2(32.42,35.18) 32.42,35.17 32.1,34.85 32.1,33.97 32.34,33.73 32.71,33.73 32.84,33.86 32.84,34.16 32.97,34.29 33.22,34.29 33.35,34.16 33.35,33.86 33.48,33.73 33.73,33.73 33.86,33.86 33.86,34.16 33.98,34.29 34.24,34.29 34.37,34.16 34.37,33.86 34.49,33.73 40.36,33.73 40.87,34.24 41.71,34.24 42.82,35.35 42.82,35.76 47.14,40.07 47.17,40.07 47.17,40.07 52.76,40.07 55,42.32 58.8,42.32 63.36,46.87 65.07,46.87 66.78,48.59 76.79,48.59 77.1,48.89 83.78,55.57 83.99,55.57 88.21,55.57 90.55,57.91 90.55,58.44 91.21,59.1 92.82,59.1 92.98,59.26
  BOTTOM w0.089: UC1.F6 v2(93.71,61.47)
  BOTTOM w0.114: JSSD1.29 32.38,34.67 32.23,34.81 32.23,35 v2(32.42,35.18)
PCIE_CRX_DTX_N3: length 95.3
  IN2 w0.089: 94.21,58.54 94.23,58.56 94.23,58.62 94.65,59.04 94.65,59.44 95.36,60.16 95.36,61.77 94.53,62.59 92.38,62.59 92.24,62.74 92.24,62.95 92.32,63.04 v2(92.52,63.04)
  IN2 w0.127: 94.21,58.54 93.79,58.12 92.31,58.12 88.79,54.61 84.17,54.61 76.3,46.73 76.14,46.57 76.14,36.67 74.65,35.17 59.1,35.17 56.31,37.96 53.07,37.96 51.92,39.11 47.53,39.11 43.91,35.49 43.91,35.06 42.13,33.28 41.27,33.28 40.76,32.77 31.38,32.77 30.88,33.27 29.38,33.27 29.25,33.14 29.25,32.95 v2(29.42,32.79)
  BOTTOM w0.089: UC1.F9 v2(92.52,63.04)
  BOTTOM w0.114: JSSD1.41 29.38,33.34 29.25,33.21 29.25,32.96 v2(29.42,32.79)
PCIE_CRX_DTX_N4: length 126.8
  TOP w0.089: 95.99,61.82 95.89,61.82 95.85,61.86 95.29,61.86 94.71,62.43 93.74,62.43 93.51,62.66 93.51,62.86 93.37,63 v2(93.24,63)
  TOP w0.114: 95.99,61.82 96.19,61.82 100.05,57.97 100.05,57.37 v2(99.97,57.29)
  IN2 w0.127: v2(99.97,57.29) 99.97,58.28 101.68,59.99 101.68,62.02 103.09,63.43 109.13,63.43 110.52,64.81 110.52,66.54 112.42,68.44 112.42,70.93 113.63,72.14 113.63,89.28 110.77,92.14 110.77,93.29 110.33,93.74 110.33,99.2 109.05,100.47 102.33,100.47 97.92,104.88 93.8,104.88 92.31,103.39 87.68,103.39 86.25,104.82 85.43,104.82 85.42,104.82 85.08,104.82 85.08,104.82 84.61,104.82 84.61,104.82 84.28,104.82 83.92,105.19 83.69,105.41 83.59,105.52 83.38,105.72 83.36,105.74 83.03,105.74 82.22,106.55 82.22,107.2 79.6,109.83 79.6,113.17 78.44,114.33 78.44,122.64 77.61,123.47 76.46,123.47 75.78,124.15 75.78,128.81 75.89,128.92 75.89,129.26 75.78,129.38 75.78,130.81 76.98,132.01 77.38,132.01 v2(77.46,132.09)
  BOTTOM w0.089: UC1.F11 v2(93.24,63)
  BOTTOM w0.114: v2(77.46,132.09) 77.61,131.94 78.2,131.94 78.31,132.05 JWLAN1.43
PCIE_CRX_DTX_N5: length 194.8
  TOP w0.089: v2(93.95,63.95) 93.71,63.95 93.57,63.81 93.57,63.65 93.66,63.56 94.67,63.56 95.54,62.7 95.94,62.7 95.98,62.73 95.99,62.73
  TOP w0.114: v2(101.15,53.5) 100.99,53.34 100.61,53.34 100.49,53.45 100.49,54.22 101.73,55.47 101.73,57.28 101.06,57.95 101.06,58.26 96.58,62.73 95.99,62.73 ; v2(25.15,89.52) 25.3,89.38 25.3,88.83 25.01,88.55 CL27.1
  IN2 w0.127: v2(25.15,89.52) 25.15,89.99 25.58,90.42 25.96,90.42 26.77,89.61 26.77,88.01 26.38,87.62 24.65,87.62 23.86,86.82 23.86,85.52 24.77,84.61 26.8,84.61 27.24,84.17 27.24,82.58 26.52,81.86 26.52,79.32 26.21,79.01 25.83,79.01 25.51,78.69 25.51,55.73 23.21,53.44 23.21,48.51 21.62,46.92 21.62,39.49 20.42,38.29 20.42,31.29 22.84,28.87 22.84,26.08 24.6,24.32 39.56,24.32 40.14,24.89 40.49,24.89 40.49,24.9 61.53,24.9 61.9,25.27 62.06,25.42 62.86,26.23 62.86,26.23 63.02,26.38 69.64,26.38 70.61,25.41 71.04,25.41 71.04,25.41 72.32,25.41 72.32,25.41 72.53,25.41 78.11,25.41 79.01,26.31 84.42,31.72 84.42,44.24 86.27,46.1 91.47,46.1 93,47.62 93,51.11 94.66,52.76 98.97,52.76 99.71,53.5 v2(101.15,53.5)
  BOTTOM w0.089: UC1.D13 v2(93.95,63.95)
PCIE_CRX_DTX_P0: length 68.1
  IN2 w0.089: v2(92.16,61.98) 91.6,61.42 91.6,60.38 91.4,60.18 90.36,60.18 89.87,59.7 89.81,59.7 89.8,59.68
  IN2 w0.127: 89.8,59.68 89.09,58.97 89.09,58.66 88.21,57.78 84.02,57.78 77.29,51.05 64.37,51.05 57.03,43.71 54.27,43.71 52.15,41.6 46.66,41.6 41.3,36.24 40.77,36.24 40.34,35.81 38.67,35.81 38.48,35.62 38.24,35.62 37.83,35.22 v2(37.83,35.18)
  BOTTOM w0.089: v2(92.16,61.98) 92.22,62.05 UC1.G7
  BOTTOM w0.114: v2(37.83,35.18) 38,35.01 38,34.8 37.87,34.67 JSSD1.7
PCIE_CRX_DTX_P1: length 74.2
  IN2 w0.089: 90.9,59.4 90.92,59.42 90.92,59.48 91.01,59.57 92.36,59.57 92.47,59.69 93.8,59.69 94.33,60.22 94.33,60.61 94.22,60.72 v2(94.22,60.96)
  IN2 w0.127: v2(34.83,35.18) 34.83,34.55 35.2,34.19 40.2,34.19 40.69,34.67 41.54,34.67 42.21,35.34 42.21,35.76 47.02,40.57 52.48,40.57 54.66,42.75 58.63,42.75 65.2,49.32 76.92,49.32 84.41,56.82 84.52,56.82 88.71,56.82 90.06,58.17 90.06,58.57 90.9,59.4
  BOTTOM w0.089: v2(94.22,60.96) 94.21,60.95 UC1.D4
  BOTTOM w0.114: JSSD1.19 34.87,34.67 34.99,34.79 34.99,35.02 v2(34.83,35.18)
PCIE_CRX_DTX_P2: length 80.9
  IN2 w0.089: v2(93.18,62.05) 93.94,61.78 94.07,61.65 94.53,61.65 94.83,61.35 94.83,60.21 93.91,59.29 93.33,59.29 93.18,59.15 93.18,59.09 93.17,59.07
  IN2 w0.127: v2(31.83,35.18) 31.83,33.86 32.23,33.47 40.47,33.47 40.98,33.98 41.82,33.98 42.93,35.08 43.09,35.24 43.09,35.65 43.22,35.78 47.24,39.81 47.28,39.81 47.28,39.81 52.87,39.81 55.11,42.06 58.91,42.06 63.47,46.61 65.18,46.61 66.89,48.32 76.9,48.32 77.21,48.63 83.89,55.3 83.93,55.3 88.32,55.3 90.81,57.8 90.81,58.33 91.32,58.83 92.93,58.83 93.17,59.07
  BOTTOM w0.089: UC1.E7 v2(93.18,62.05)
  BOTTOM w0.114: v2(31.83,35.18) 31.99,35.03 31.99,34.79 31.87,34.67 JSSD1.31
PCIE_CRX_DTX_P3: length 95.3
  IN2 w0.089: 94.03,58.73 94.04,58.74 94.1,58.74 94.47,59.11 94.47,59.52 95.18,60.23 95.18,61.69 94.46,62.42 92.31,62.42 92.06,62.67 92.06,62.92 91.95,63.04 v2(91.81,63.04)
  IN2 w0.127: 94.03,58.73 93.68,58.39 92.2,58.39 88.68,54.87 84.28,54.87 84.06,54.87 76.03,46.84 75.88,46.68 75.88,36.78 74.54,35.44 59.21,35.44 56.42,38.22 53.18,38.22 52.03,39.38 47.42,39.38 43.65,35.6 43.65,35.17 42.02,33.54 41.16,33.54 40.65,33.04 31.49,33.04 30.99,33.54 29.27,33.54 28.99,33.25 28.99,32.95 v2(28.83,32.79)
  BOTTOM w0.089: UC1.H9 v2(91.81,63.04)
  BOTTOM w0.114: v2(28.83,32.79) 29,32.96 29,33.23 28.87,33.36 JSSD1.43
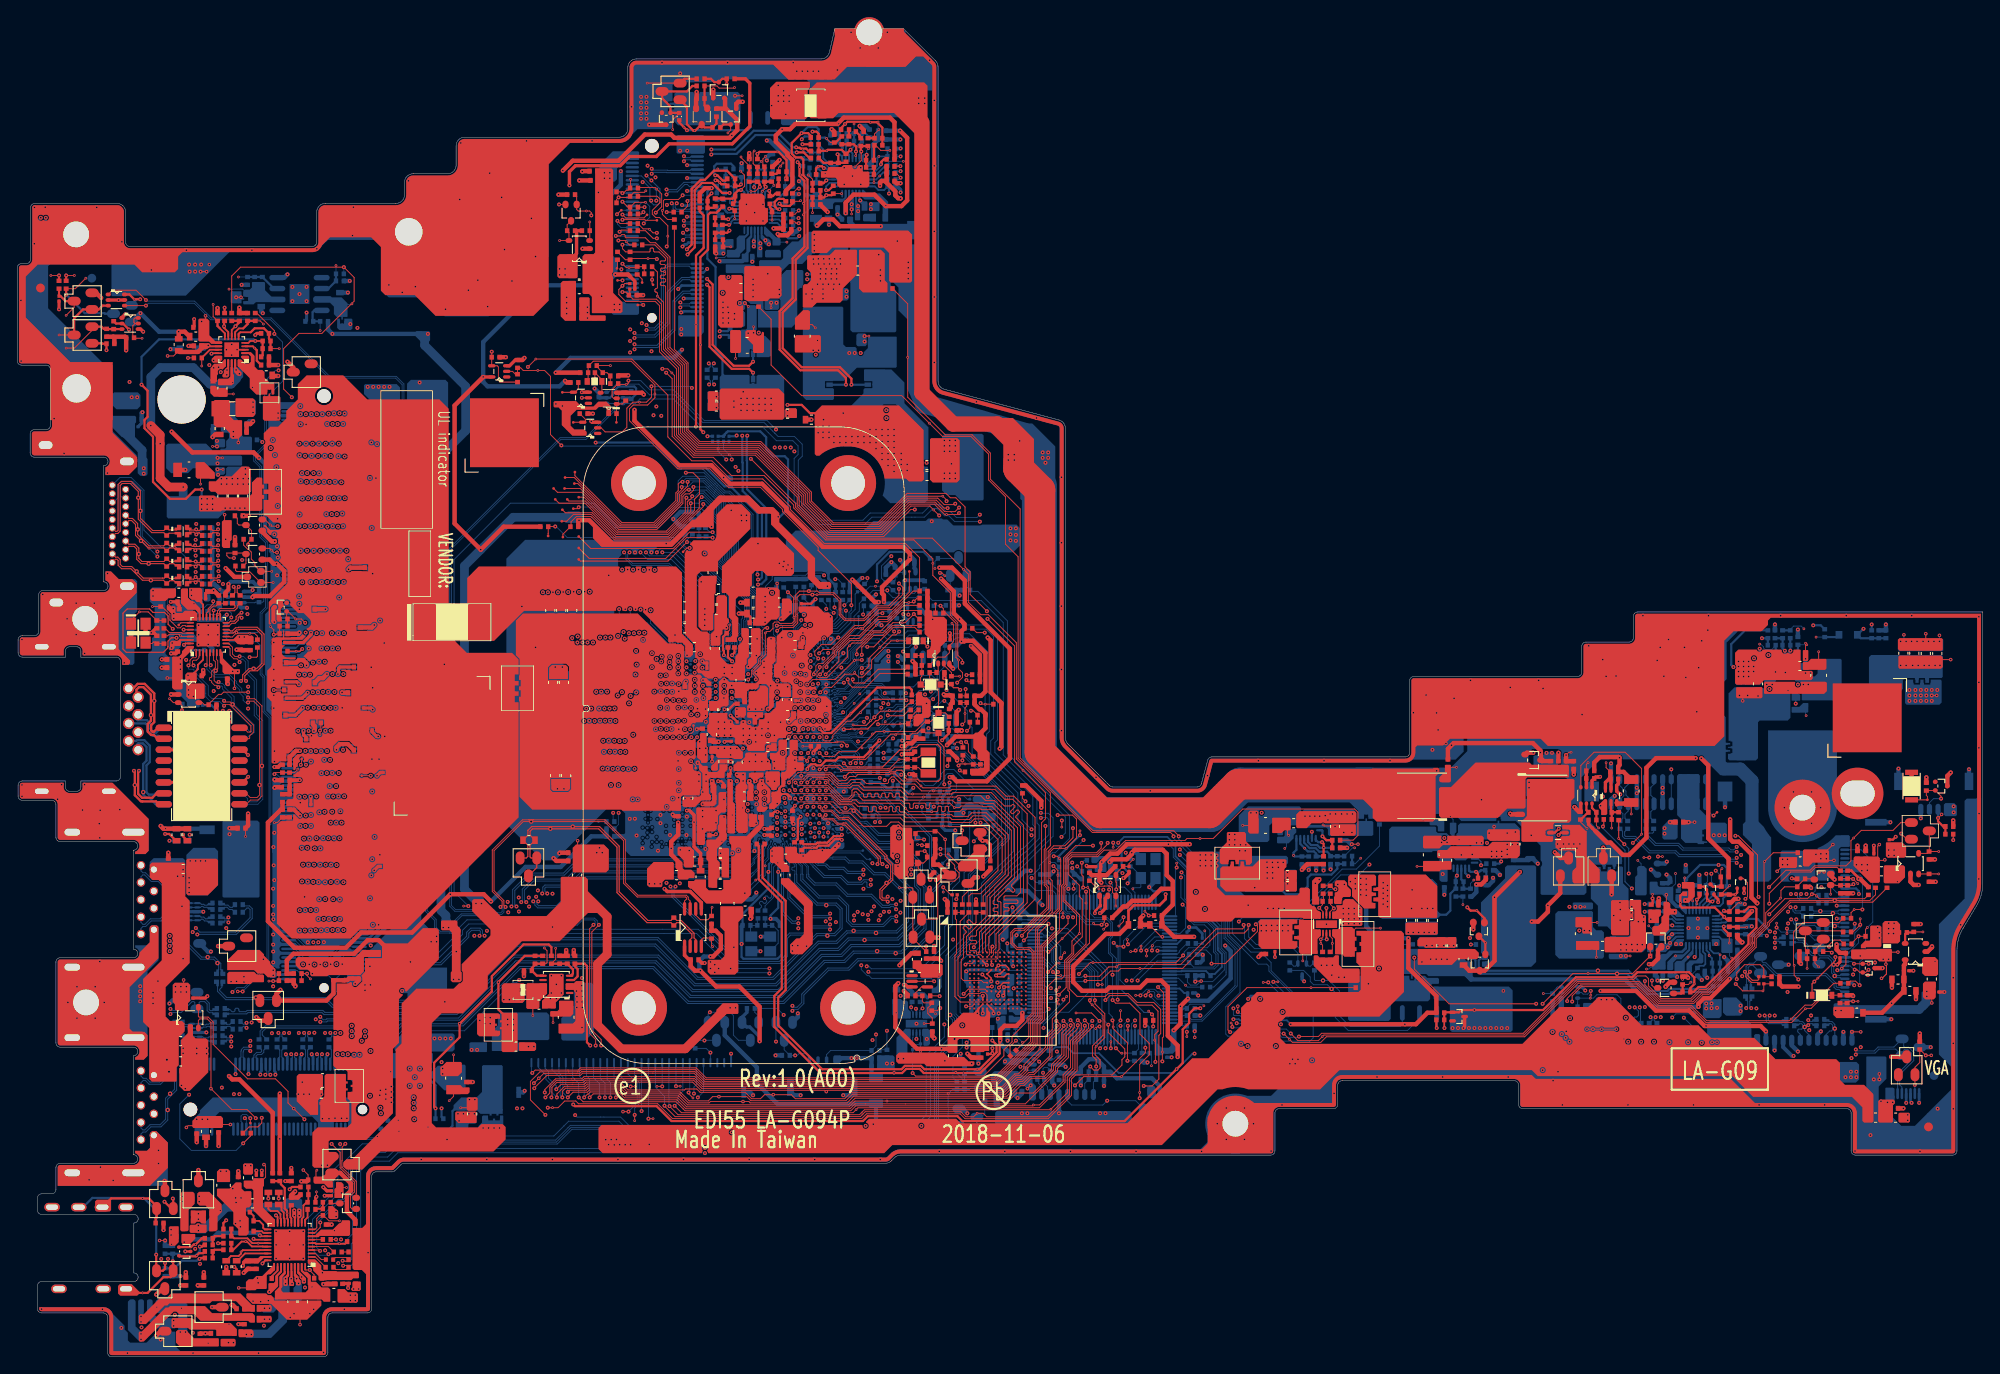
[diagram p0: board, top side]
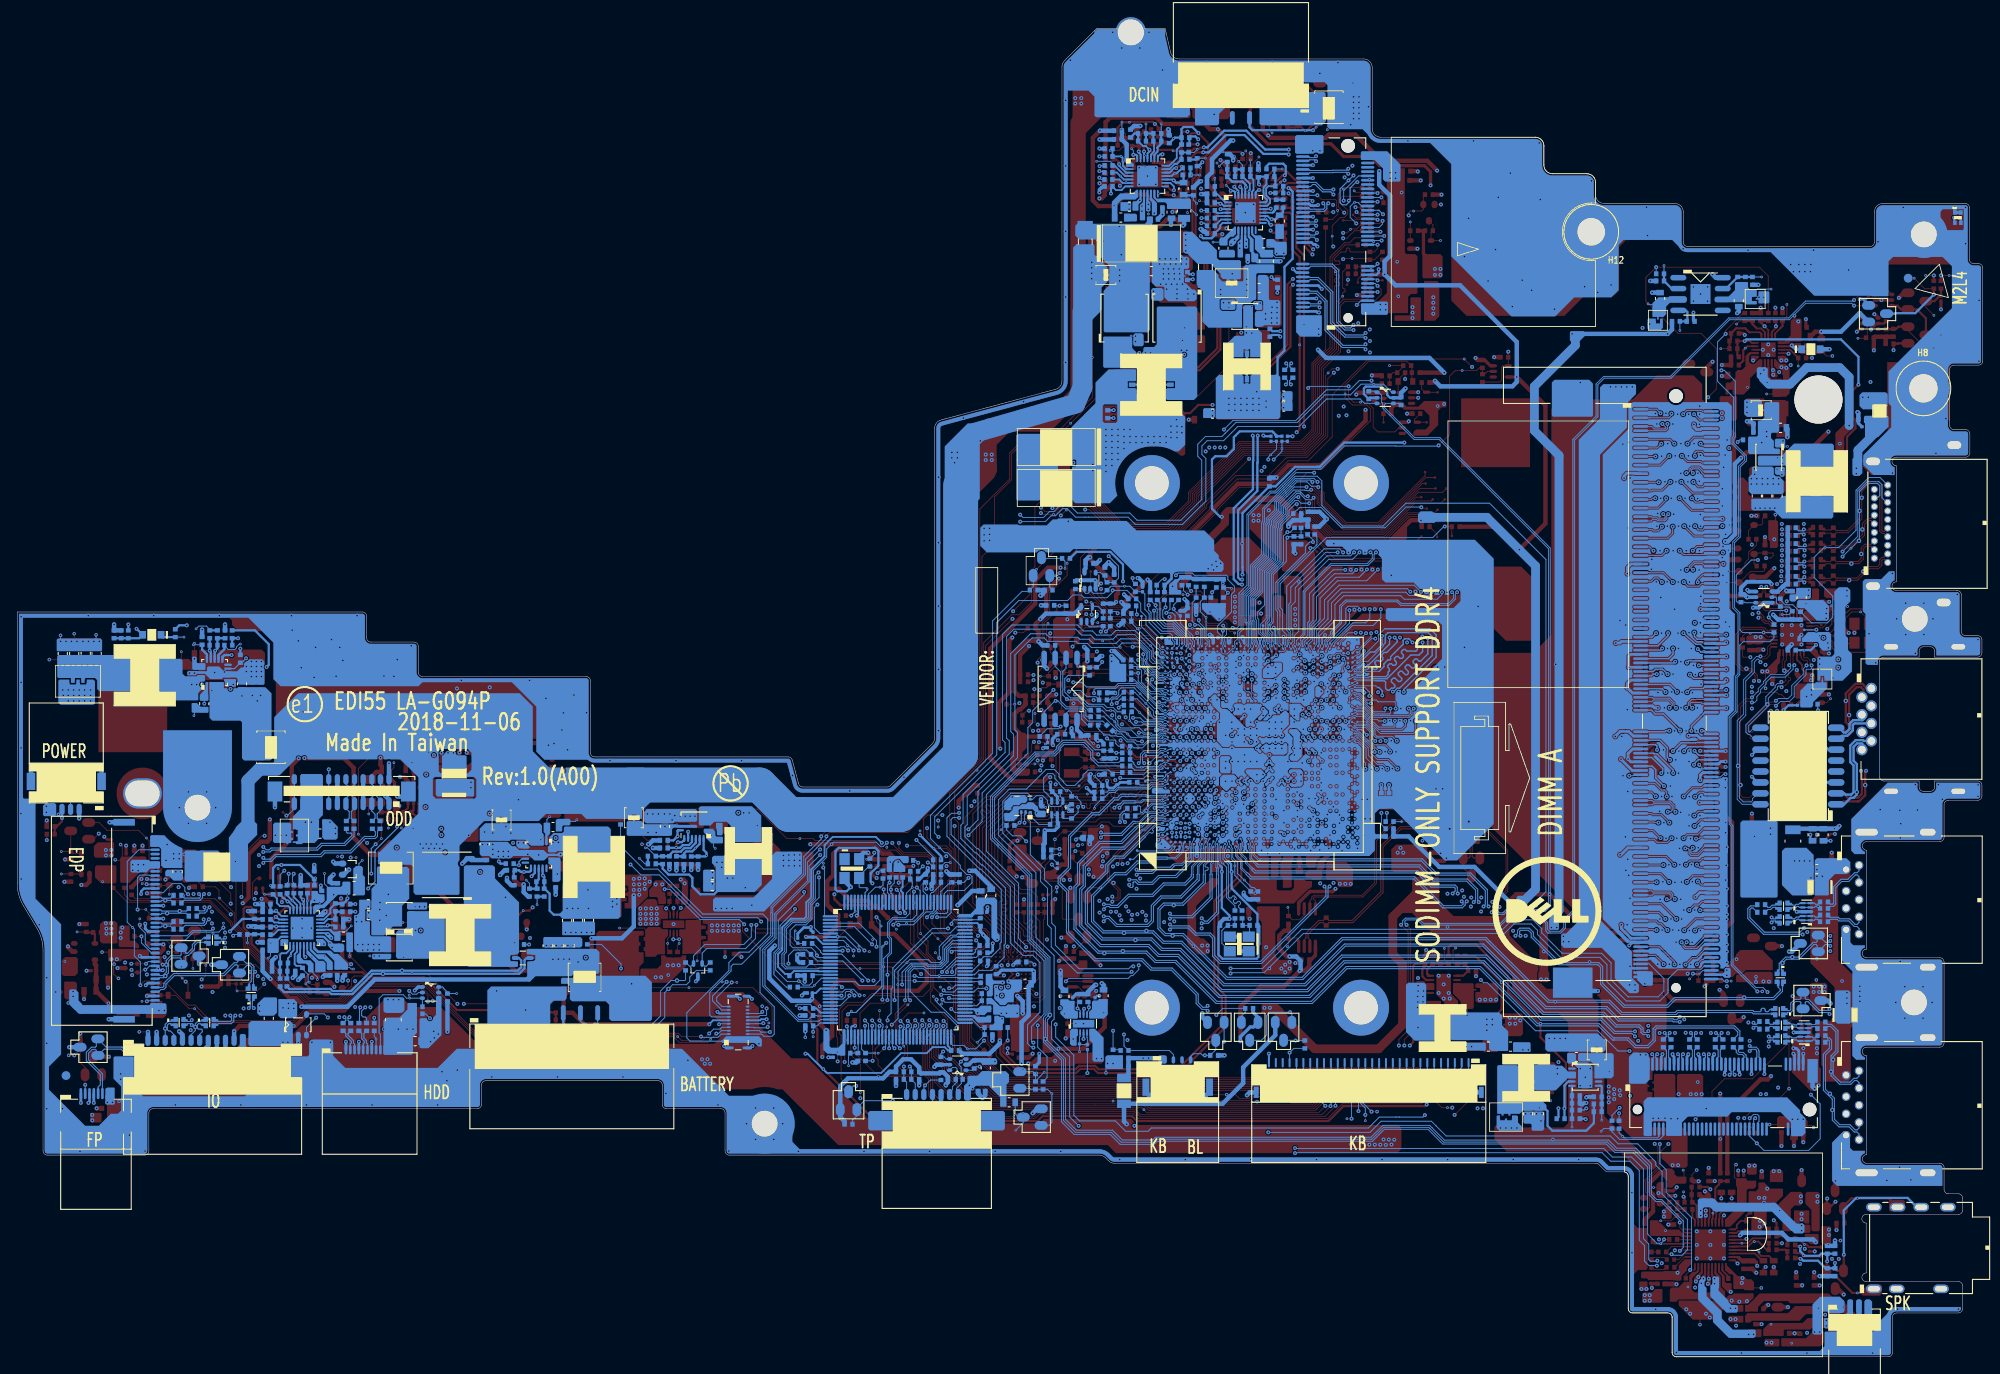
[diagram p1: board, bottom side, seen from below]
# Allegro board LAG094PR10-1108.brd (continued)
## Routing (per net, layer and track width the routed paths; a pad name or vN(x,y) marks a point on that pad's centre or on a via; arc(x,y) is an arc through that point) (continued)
PCIE_CRX_DTX_P4: length 126.7
  TOP w0.089: 95.99,62.07 95.97,62.07 95.93,62.03 95.36,62.03 94.79,62.61 93.81,62.61 93.68,62.73 93.68,62.86 93.82,63 v2(93.95,63)
  TOP w0.114: 95.99,62.07 96.3,62.07 100.29,58.07 100.29,57.54 v2(100.55,57.29)
  IN2 w0.127: v2(77.46,131.51) 77.22,131.75 77.09,131.75 76.04,130.7 76.04,129.49 76.16,129.37 76.16,128.81 76.04,128.7 76.04,124.26 76.57,123.73 77.72,123.73 78.71,122.75 78.71,114.44 79.86,113.28 79.86,109.94 82.48,107.31 82.48,106.66 83.14,106 83.47,106 83.57,105.91 83.77,105.7 83.88,105.6 84.1,105.37 84.39,105.08 84.5,105.08 84.97,105.08 84.97,105.09 85.53,105.09 85.54,105.08 86.36,105.08 87.79,103.66 92.2,103.66 93.69,105.14 98.03,105.14 102.44,100.73 109.16,100.73 110.59,99.31 110.59,93.85 111.03,93.4 111.03,92.25 113.89,89.39 113.89,72.03 112.68,70.82 112.68,68.33 110.78,66.43 110.78,64.7 109.24,63.17 103.2,63.17 101.94,61.91 101.94,59.88 100.23,58.17 100.23,57.61 100.55,57.29 v2(100.55,57.29)
  BOTTOM w0.089: UC1.D11 v2(93.95,63)
  BOTTOM w0.114: v2(77.46,131.51) 77.65,131.69 78.2,131.69 78.34,131.55 JWLAN1.41
PCIE_CRX_DTX_P5: length 194.8
  TOP w0.089: 95.99,62.49 95.94,62.49 95.92,62.5 95.91,62.5 95.9,62.52 95.46,62.52 94.6,63.38 93.58,63.38 93.39,63.57 93.39,63.79 v2(93.24,63.95)
  TOP w0.114: CL26.1 25.56,88.87 25.56,89.34 v2(25.74,89.52) ; v2(101.15,52.92) 100.98,53.09 100.5,53.09 100.24,53.35 100.24,54.33 v4(101.02,55.1) 101.49,55.57 101.49,57.18 100.82,57.85 100.82,58.15 96.52,62.45 96.51,62.45 96.47,62.49 95.99,62.49
  IN2 w0.127: v2(101.15,52.92) 100.94,52.7 100.68,52.7 100.15,53.24 99.82,53.24 99.08,52.5 94.77,52.5 93.26,51 93.26,47.51 91.58,45.83 86.38,45.83 84.68,44.13 84.68,31.61 79.27,26.2 78.22,25.15 72.64,25.15 72.64,25.15 72.43,25.15 72.42,25.15 70.93,25.15 70.93,25.15 70.5,25.15 69.53,26.12 63.13,26.12 62.32,25.31 62.17,25.16 61.64,24.63 40.52,24.63 40.51,24.63 40.25,24.63 39.67,24.05 24.49,24.05 24.34,24.21 22.58,25.97 22.58,28.76 20.15,31.18 20.15,38.4 21.36,39.6 21.36,47.03 22.95,48.62 22.95,53.55 25.24,55.84 25.24,78.8 25.72,79.28 26.1,79.28 26.26,79.43 26.26,81.97 26.98,82.69 26.98,84.06 26.69,84.34 24.66,84.34 23.59,85.41 23.59,86.93 24.55,87.88 26.27,87.88 26.5,88.12 26.5,89.5 25.86,90.15 25.68,90.15 25.49,89.96 25.49,89.78 25.57,89.7 25.57,89.69 v2(25.74,89.52)
  BOTTOM w0.089: UC1.F13 v2(93.24,63.95)
PCIE_CTX_C_DRX_N0: length 2.2
  BOTTOM w0.114: JSSD1.11 36.87,34.69 36.75,34.82 36.75,35.62 CS16.2
PCIE_CTX_C_DRX_N1: length 2.1
  BOTTOM w0.114: JSSD1.23 33.87,34.72 33.75,34.85 33.75,35.67 CS31.2
PCIE_CTX_C_DRX_N2: length 2.2
  BOTTOM w0.114: JSSD1.35 30.87,34.72 30.75,34.85 30.75,35.65 CS33.2
PCIE_CTX_C_DRX_N3: length 2.8
  BOTTOM w0.114: CS36.2 28.65,35.64 28.65,35.4 28.39,35.14 27.92,35.14 27.75,34.97 27.75,34.78 27.87,34.65 JSSD1.47
PCIE_CTX_C_DRX_N4: length 20.4
  IN2 w0.127: v2(80.36,115.5) 80.52,115.66 80.52,116.04 79.14,117.42 79.14,122.93 77.85,124.22 77.41,124.22 76.6,125.02 76.6,125.24 76.6,130.22 76.88,130.49 77.17,130.49 v2(77.37,130.69)
  BOTTOM w0.114: v2(77.37,130.69) 77.63,130.42 78.14,130.42 78.26,130.55 JWLAN1.37 ; v2(80.36,115.5) 80.52,115.34 80.52,115.11 CC20.1
PCIE_CTX_C_DRX_N5: length 169.9
  TOP w0.114: v2(26.59,78.58) 26.44,78.72 26.44,79.17 27.03,79.76 27.92,79.76 28.68,80.52 28.68,84.03 27.89,84.82 25.74,84.82 25.68,84.77 25.37,84.77 24.99,84.39 24.77,84.39 24.61,84.54 UL1.14
  IN2 w0.127: v2(99.68,62.17) 99.88,61.97 99.88,61.74 99.75,61.61 99.54,61.61 99.41,61.49 99.41,61.23 99.54,61.11 99.75,61.11 99.88,60.98 99.88,60.73 94.89,55.75 93.19,55.75 89.07,51.62 84.67,51.62 84.67,51.62 84.45,51.62 78.45,45.62 78.45,35.65 77.19,34.39 77.19,28.31 76.09,27.21 71.5,27.21 69.82,28.9 69.6,28.9 69.6,28.9 62.92,28.9 62.76,28.74 61.39,27.37 53.9,27.37 53.22,26.69 43.95,26.69 40.33,26.69 40.32,26.69 39.93,26.69 39.92,26.69 39.5,26.69 39.5,26.69 39.4,26.69 39.2,26.49 38.73,26.49 37.99,26.5 25.48,26.5 24.64,27.33 24.64,29.74 22.9,31.47 22.9,37.98 24.05,39.12 24.05,45.8 26.21,47.96 26.21,77.9 26.39,78.08 26.39,78.38 v2(26.59,78.58)
  BOTTOM w0.114: v2(99.68,62.17) 100.01,62.51 100.01,62.92 99.75,63.18 99.69,63.18 CC18.1
PCIE_CTX_C_DRX_P0: length 2.1
  BOTTOM w0.114: JSSD1.13 36.38,34.7 36.5,34.82 36.5,35.71 CS30.2
PCIE_CTX_C_DRX_P1: length 2.1
  BOTTOM w0.114: JSSD1.25 33.38,34.75 33.5,34.87 33.5,35.67 CS32.2
PCIE_CTX_C_DRX_P2: length 2.1
  BOTTOM w0.114: CS34.2 30.5,35.68 30.5,34.87 30.38,34.74 JSSD1.37
PCIE_CTX_C_DRX_P3: length 2.8
  BOTTOM w0.114: JSSD1.49 27.38,34.69 27.5,34.82 27.5,35.07 27.82,35.39 28.29,35.39 28.4,35.5 28.4,35.69 CS35.2
PCIE_CTX_C_DRX_P4: length 20.4
  IN2 w0.127: v2(77.38,129.85) 77.38,130.01 77.25,130.14 77.01,130.14 76.87,130 76.87,126.88 77,126.76 77.06,126.76 77.19,126.63 77.19,126.37 77.06,126.25 77,126.25 76.87,126.12 76.87,125.24 76.87,125.13 77.52,124.48 77.96,124.48 79.4,123.04 79.4,117.53 80.79,116.15 80.79,115.66 v2(80.95,115.5)
  BOTTOM w0.114: CC21.1 80.77,115.11 80.77,115.33 v2(80.95,115.5) ; JWLAN1.35 78.26,130.05 78.13,130.18 77.7,130.18 77.65,130.13 v2(77.38,129.85)
PCIE_CTX_C_DRX_P5: length 169.9
  TOP w0.114: UL1.13 25.09,84.14 25.47,84.52 25.78,84.52 25.84,84.58 27.78,84.58 28.44,83.92 28.44,80.63 27.82,80.01 v4(27.47,80.01) 26.93,80.01 26.2,79.28 26.2,78.77 v2(26.01,78.58)
  IN2 w0.127: v2(100.26,62.17) 100.14,62.05 100.14,60.62 95,55.48 93.3,55.48 89.18,51.36 84.56,51.36 78.71,45.51 78.71,35.54 77.45,34.28 77.45,28.2 76.2,26.95 71.9,26.95 71.39,26.95 69.71,28.63 63.03,28.63 61.5,27.11 54.01,27.11 53.33,26.43 43.84,26.43 40.35,26.43 40.35,26.43 39.9,26.43 39.9,26.43 39.61,26.43 39.61,26.43 39.51,26.43 39.31,26.23 38.62,26.23 38.62,26.23 38.1,26.23 25.37,26.23 24.37,27.23 24.37,29.63 22.64,31.36 22.64,38.09 23.78,39.23 23.78,45.91 25.94,48.07 25.94,78.01 26.12,78.19 26.12,78.46 v2(26.01,78.58)
  BOTTOM w0.114: CC19.1 99.4,63.77 99.75,63.42 99.86,63.42 100.26,63.02 v2(100.26,62.17)
PCIE_CTX_DRX_N0: length 97.6
  IN2 w0.127: v2(35.21,39.53) 35.31,39.43 36.29,39.43 36.81,38.91 36.81,37.82 v2(36.97,37.66)
  BOTTOM w0.089: UC1.F2 92.85,59.73 92.85,59.73 92.9,59.68 92.9,59.55 92.85,59.51 92.85,58.76 93.71,57.89 94.74,57.89 94.78,57.86 94.8,57.86
  BOTTOM w0.114: 94.8,57.86 96.16,57.86 96.61,57.41 98.16,57.41 99.53,56.04 100.8,56.04 103.32,53.52 103.32,50.7 102.14,49.53 v4(97.19,49.53) 96.36,49.53 95.16,48.32 93.06,48.32 88.13,43.38 78.79,43.38 74.18,47.99 58,47.99 50.73,40.72 43.68,40.72 42.25,39.29 35.97,39.29 35.86,39.19 35.55,39.19 v2(35.21,39.53) ; v2(36.97,37.66) 36.8,37.49 36.8,37.22 CS16.1
PCIE_CTX_DRX_N1: length 97.9
  IN2 w0.127: v2(33.92,37.66) 33.77,37.51 33.77,37.33 33.89,37.2 37.88,37.2 38.22,37.55 38.54,37.55 38.86,37.87 v2(38.87,37.87)
  BOTTOM w0.089: 97.35,60.41 97.33,60.43 97.33,60.47 96.84,60.97 96.72,60.97 96.63,60.88 96.5,60.88 96.38,61 96.38,61.13 96.47,61.22 96.47,61.34 95.93,61.88 95.53,61.88 95.42,61.77 94.87,61.77 UC1.C7
  BOTTOM w0.114: CS31.1 33.75,37.22 33.75,37.49 v2(33.92,37.66) ; v2(38.87,37.87) 39.03,37.71 39.35,37.71 39.47,37.82 39.47,38.2 39.86,38.6 42.55,38.6 43.87,39.91 44.01,40.05 51.01,40.05 57.66,46.71 63.39,46.71 74.52,46.71 78.53,42.7 88.4,42.7 93.19,47.49 95.34,47.49 96.55,48.7 102.27,48.7 104.03,50.46 104.03,54 101.66,56.37 101.66,57.15 100.84,57.97 99.79,57.97 97.35,60.41
PCIE_CTX_DRX_N2: length 105.4
  IN2 w0.127: v2(40.42,37.26) 40.18,37.5 40.08,37.5 38.82,36.24 32.94,36.24 32.03,37.15 32.03,37.86 31.73,38.16 30.78,38.16 30.7,38.08 30.7,37.9 30.96,37.65 v2(31.01,37.65)
  BOTTOM w0.089: UC1.B9 95,62.57 96.21,62.57 97.44,61.34 97.7,61.34 97.95,61.09 98,61.09 98.01,61.07
  BOTTOM w0.114: CS33.1 30.76,37.22 30.76,37.49 30.93,37.65 v2(31.01,37.65) ; v2(40.42,37.26) 40.76,37.6 42.84,37.6 44.39,39.14 51.38,39.14 57.89,45.65 58.04,45.8 74.14,45.8 78.17,41.77 88.76,41.77 93.54,46.54 95.82,46.54 96.97,47.69 102.56,47.69 104.94,50.07 104.94,54.38 104.53,54.79 104.53,57.1 102.38,59.26 99.83,59.26 98.01,61.07
PCIE_CTX_DRX_N3: length 109.3
  BOTTOM w0.089: UC1.A10 95.39,62.92 95.65,62.92 95.74,63.01 96.01,63.01 96.09,62.92 96.62,62.92 97.76,61.78 98.23,61.78 98.43,61.57 98.48,61.57 98.5,61.56
  BOTTOM w0.114: CS36.1 28.47,37.42 28.47,37.77 28.93,38.22 37.88,38.22 38.07,38.03 38.07,36.73 38.86,35.94 40.4,35.94 41.28,36.83 42.87,36.83 42.87,36.84 43.02,36.84 44.66,38.48 51.82,38.48 58.47,45.13 73.87,45.13 77.92,41.08 89.09,41.08 93.85,45.84 96.17,45.84 97.25,46.92 v4(102.08,46.92) 102.81,46.92 105.61,49.72 105.61,54.65 105.2,55.06 105.2,56.83 105.2,57.38 102.65,59.92 100.13,59.92 98.5,61.56
PCIE_CTX_DRX_N4: length 99.1
  IN2 w0.127: v2(80.4,113.05) 80.55,112.9 80.55,109.86 82.92,107.49 82.92,106.84 83.32,106.44 83.72,106.44 84.57,105.58 86.48,105.58 87.97,104.09 91.86,104.09 93.36,105.58 98.23,105.58 102.64,101.17 109.44,101.17 111.02,99.58 111.02,94.12 111.47,93.68 111.47,92.72 114.32,89.86 114.32,71.85 113.12,70.65 113.12,68.15 111.21,66.25 111.21,63.61 109.83,62.23 106.94,62.23 105.54,60.83 103.93,60.83 103.81,60.96 103.81,61.15 103.68,61.27 103.43,61.27 103.3,61.15 103.3,60.96 103.17,60.83 102.61,60.83 v2(102.47,60.97)
  BOTTOM w0.089: UC1.B11 94.9,63.55 94.9,63.64 94.99,63.72 95.12,63.72 95.39,63.44 95.55,63.44 95.72,63.61 95.84,63.61 95.93,63.52 95.93,63.43 96,63.36 96.88,63.36 98.01,62.23 98.47,62.23 98.51,62.26 98.53,62.26
  BOTTOM w0.114: v2(80.4,113.05) 80.55,113.21 80.55,113.46 CC20.2 ; 98.53,62.26 98.73,62.26 100.13,60.87 102.37,60.87 v2(102.47,60.97)
PCIE_CTX_DRX_N5: length 4.7
  BOTTOM w0.089: CC18.2 98.26,63.11 97.57,63.11 v4(97.19,63.5) 96.51,64.18 95.6,64.18 95.22,64.18 95.1,64.1 94.91,64.1 UC1.C13
PCIE_CTX_DRX_P0: length 97.6
  IN2 w0.127: v2(35.21,38.94) 35.44,39.16 36.18,39.16 36.54,38.8 36.54,37.82 v2(36.38,37.66)
  BOTTOM w0.089: 94.8,58.11 94.78,58.11 94.74,58.07 93.78,58.07 93.03,58.83 93.03,59.43 93.07,59.48 93.07,59.66 UC1.E2
  BOTTOM w0.114: 94.8,58.11 96.26,58.11 96.72,57.65 98.26,57.65 99.63,56.29 100.9,56.29 103.56,53.62 103.56,50.6 102.24,49.28 v4(99.79,49.28) 96.47,49.28 95.26,48.07 93.16,48.07 88.23,43.14 78.69,43.14 74.08,47.75 58.11,47.75 50.83,40.47 43.78,40.47 42.36,39.05 36.07,39.05 35.96,38.94 v2(35.21,38.94) ; CS30.1 36.55,37.22 36.55,37.49 v2(36.38,37.66)
PCIE_CTX_DRX_P1: length 97.9
  IN2 w0.127: v2(38.87,37.29) 38.33,37.29 37.99,36.94 33.79,36.94 33.5,37.22 33.5,37.49 v2(33.33,37.66)
  BOTTOM w0.089: UC1.A7 96,62.06 97.46,60.6 97.51,60.6 97.52,60.58
  BOTTOM w0.114: v2(38.87,37.29) 39.04,37.46 39.46,37.46 39.71,37.72 39.71,38.1 39.96,38.35 42.65,38.35 44.11,39.81 51.11,39.81 57.62,46.32 57.76,46.46 63.39,46.46 74.42,46.46 78.43,42.45 88.5,42.45 93.29,47.24 95.44,47.24 96.66,48.45 v4(98.46,48.45) 102.37,48.45 104.28,50.36 104.28,54.1 101.91,56.47 101.91,57.25 100.94,58.22 99.89,58.22 97.52,60.58 ; CS32.1 33.5,37.22 33.5,37.49 v2(33.33,37.66)
PCIE_CTX_DRX_P2: length 105.4
  IN2 w0.127: v2(40.42,37.84) 40.03,37.84 38.69,36.51 33.05,36.51 32.29,37.26 32.29,37.97 31.99,38.27 31.84,38.42 30.67,38.42 30.35,38.1 v2(30.35,37.66)
  BOTTOM w0.089: 97.84,60.9 97.82,60.92 97.82,60.96 97.63,61.16 97.37,61.16 96.14,62.39 95.22,62.39 95.12,62.29 94.64,62.29 UC1.C9
  BOTTOM w0.114: v2(30.35,37.66) 30.52,37.49 30.52,37.22 CS34.1 ; 97.84,60.9 99.73,59.01 102.24,59.01 104.29,56.97 104.29,54.68 104.7,54.27 104.7,50.18 102.46,47.94 96.87,47.94 95.72,46.79 93.43,46.79 88.66,42.01 78.28,42.01 74.25,46.04 57.94,46.04 57.79,45.9 51.28,39.39 44.29,39.39 42.74,37.84 v2(40.42,37.84)
PCIE_CTX_DRX_P3: length 109.4
  BOTTOM w0.089: 98.32,61.38 98.31,61.4 98.31,61.45 98.15,61.6 97.68,61.6 96.54,62.74 95.2,62.74 UC1.C10
  BOTTOM w0.114: CS35.1 28.23,37.03 28.23,37.87 28.82,38.47 37.98,38.47 38.32,38.13 38.32,36.83 38.96,36.19 40.29,36.19 41.18,37.08 42.77,37.08 42.77,37.08 42.92,37.08 44.56,38.72 51.72,38.72 58.37,45.38 73.97,45.38 78.02,41.33 88.99,41.33 93.75,46.09 96.07,46.09 97.15,47.17 v4(99.92,47.17) 102.71,47.17 105.36,49.83 105.36,54.55 104.95,54.96 104.95,56.93 104.95,57.28 102.55,59.68 100.03,59.68 98.32,61.38
PCIE_CTX_DRX_P4: length 99
  IN2 w0.127: v2(102.47,60.38) 102.65,60.56 105.65,60.56 107.05,61.96 109.94,61.96 111.48,63.5 111.48,66.14 113.38,68.04 113.38,70.54 114.59,71.74 114.59,89.97 111.73,92.83 111.73,93.78 111.29,94.23 111.29,99.69 109.55,101.43 102.75,101.43 98.34,105.84 93.25,105.84 91.75,104.35 88.08,104.35 86.58,105.85 84.68,105.85 83.83,106.7 83.43,106.7 83.18,106.95 83.18,107.6 80.82,109.97 80.82,112.89 v2(80.98,113.05)
  BOTTOM w0.089: UC1.C11 94.89,63.19 95.1,63.19 95.12,63.21 95.17,63.27 95.84,63.27 95.92,63.19 96.8,63.19 97.94,62.05 98.47,62.05 98.51,62.02 98.53,62.02
  BOTTOM w0.114: 98.53,62.02 98.63,62.02 100.03,60.62 102.24,60.62 v2(102.47,60.38) ; v2(80.98,113.05) 80.8,113.24 80.8,113.51 CC21.2
PCIE_CTX_DRX_P5: length 4.8
  BOTTOM w0.089: CC19.2 98.21,64.05 97.98,64.05 97.89,63.96 97.89,63.36 97.82,63.29 97.65,63.29 97.55,63.39 97.55,63.44 97.05,63.94 97,63.94 96.58,64.36 95.68,64.36 UC1.B13
PCIE_RCOMPN: length 6.6
  TOP w0.254: v2(95.82,60.1) 95.73,60.19 95.03,60.19 94.27,59.43 93.13,59.43 92.88,59.19 v1(92.36,59.19) 91.44,59.19 RC81.2
  BOTTOM w0.089: v2(95.82,60.1) 95.54,60.39 95.16,60.39 94.75,60.8 UC1.C5
PCIE_RCOMPP: length 6.6
  TOP w0.254: RC81.1 91.39,59.6 92.8,59.6 92.98,59.77 94.13,59.77 94.89,60.54 95.67,60.54 v2(95.83,60.69)
  BOTTOM w0.102: v2(95.83,60.69) 95.54,60.98 95.12,60.98 UC1.C6
PCIE_REF_CLK_RCOMP: length 3.8
  TOP w0.254: RC78.2 90.66,60.16 90.66,60.17 90.71,60.22 90.71,62.48 v2(91.03,62.8)
  BOTTOM w0.203: v2(91.03,62.8) 91.01,62.91 UC1.L10
PCIE_RST#: length 63.9
  TOP w0.089: v2(84.93,78.75) 85.32,79.14 85.32,79.79 86.16,80.63 86.16,81.14 86.57,81.55 86.57,83.57
  TOP w0.102: UC12.2 57.55,114.58 57.88,114.24 RC1150.2 RC1152.1 58.5,114.98 58.8,114.68 v1(60.5,114.68) 61.28,114.68 61.96,114 61.96,107.23 v2(63.23,105.96) ; v2(87.15,84.75) 86.88,84.75 86.57,84.44 86.57,83.57
  BOTTOM w0.089: v2(87.15,84.75) 86.67,84.75 86.43,84.98 86.43,86.16 ; UC1.AE41 84.63,76.95 84.99,77.31 84.99,78.7 v2(84.93,78.75)
  BOTTOM w0.102: 86.43,86.16 86.43,88.77 85.51,89.7 85.51,97.95 82.81,100.64 82.24,100.64 79.69,103.2 77.2,103.2 77.2,103.2 77.15,103.2 76.92,103.2 74.21,105.91 68.23,105.91 68.21,105.89 63.31,105.89 v2(63.23,105.96)
PCIE_RST_B#: length 168.6
  TOP w0.102: v2(28.42,27.78) 28.42,27.19 27.96,26.73 26.95,26.73 R182.2 ; RW30.2 v2(72.89,133.66) ; v2(55.14,116.86) RC1151.1 55.14,115.23 UC12.4 55.77,115.23 55.91,115.08 55.91,113.52 56.1,113.33 RC1150.1
  IN1 w0.127: v2(25.01,42.41) 25.87,41.56 25.87,32.02 28.42,29.47 v2(28.42,27.78) ; v2(30.37,114.69) 31.38,114.69 32.64,115.95 39.91,115.95 40.83,116.86 v2(55.14,116.86) 62.21,116.86 64.91,119.55 64.91,131.88 66.59,133.57 71.2,133.57 71.3,133.68 71.48,133.68 71.5,133.66 v2(72.89,133.66)
  BOTTOM w0.102: v2(25.01,42.41) 25.52,42.92 26.35,42.92 29.03,45.6 29.03,61.77 29.27,62.01 29.27,74.27 28.55,74.98 28.55,79 28.24,79.32 28.24,82.74 27.83,83.14 24.71,83.14 24.27,83.59 RL24.2 v3(25.47,84.21) 27.92,84.21 28.23,84.52 28.23,86.52 28.85,87.14 28.85,94.65 28.19,95.31 28.19,103.44 27.48,104.15 27.48,104.78 28.93,106.22 28.93,106.79 28.76,106.95 28.76,113.43 30.02,114.69 v2(30.37,114.69)
PCIE_WAKE0#: length 17.8
  TOP w0.089: 95.85,80.74 94.09,78.98 93.1,78.98 92.93,79.15 92.93,79.59 93.26,79.92 v2(93.26,80.19)
  TOP w0.102: 95.85,80.74 96.49,81.38 96.49,82.46 v1(96.69,82.67) 97.02,82.99 98.05,82.99 99.44,84.39 100.34,84.39 102.71,86.76 104.64,86.76 RC170.2
  BOTTOM w0.089: UC1.F47 92.88,79.81 v2(93.26,80.19)
PCIE_WAKE1#: length 15.5
  TOP w0.102: RC169.2 103.03,87.37 101.13,85.47 100.24,85.47 v1(99.82,85.05) 98.04,83.27 96.74,83.27 95.47,82 95.47,80.88 v2(93.94,79.34)
  BOTTOM w0.102: UC1.D47 93.59,79.65 93.94,79.31 v2(93.94,79.34)
PCIE_WAKE2#: length 224.2
  TOP w0.089: 93.63,80.07 93.63,80.3 94.97,81.64 94.97,82.07 95.88,82.98
  TOP w0.102: v2(93.29,79.34) 93.63,79.68 93.63,80.07 ; v2(59.34,115.09) v1(60.26,116.01) 71.41,116.01 75.6,111.82 75.6,106.96 78.38,104.17 80.71,104.17 82.82,102.07 86.62,102.07 89.82,98.86 89.82,98.53 93.78,94.57 103.2,94.57 104.86,92.91 RC168.2 104.11,89.02 101.14,86.05 100.06,86.05 97.86,83.85 96.75,83.85 95.88,82.98 ; v2(22.78,87.84) 22.78,87.58 22.19,86.99 22.19,86.67 22,86.47 UL1.21 ; RE42.2 117.55,37.12 117.55,39.28 118.14,39.88 118.14,47.11 117.7,47.56 116.24,47.56 115.67,48.13 115.67,49.27 115.99,49.59 117.02,49.59 119.65,52.21 119.65,54.52 119.34,54.83 119.34,59.01 119.48,59.15 v2(119.48,61.72)
  IN1 w0.127: v2(119.48,61.72) 119.03,61.72 118.2,62.55 118.2,64.86 116.11,66.95 116.11,76.89 111.06,81.94 107.54,81.94 107.22,81.63 105.07,81.63 104.78,81.34 103.79,81.34 102.82,80.37 100.6,80.37 99.67,81.31 99.67,82.42 98.84,83.24 97.17,83.24 96.37,82.44 95.67,82.44 95.22,82 95.22,80.32 94.65,79.76 93.58,79.76 93.29,79.47 v2(93.29,79.34) ; v2(59.34,115.09) 58.74,115.69 46.33,115.69 45.44,114.8 38.13,114.8 37.98,114.95 37.98,115.29 37.74,115.54 37.39,115.54 37.14,115.29 37.14,114.95 37,114.8 32.06,114.8 31.85,114.8 28.42,111.37 28.42,109 26.51,107.1 26.51,104.2 27.34,103.37 27.34,95.75 24.74,93.15 24.74,92.58 26.89,90.42 26.89,88.45 26.45,88.01 24.36,88.01 24.22,87.87 22.77,87.87 22.77,87.84 v2(22.78,87.84)
  BOTTOM w0.102: UC1.F45 92.88,79.06 93.16,79.34 v2(93.29,79.34)
PCIE_WAKE3#: length 101.7
  TOP w0.102: v2(112.68,86.69) 110.73,88.64 110.73,91.26 110.14,91.84 110.14,98.8 109.06,99.88 108.43,99.88 107.92,100.39 103.41,100.39 99.98,96.96 94.84,96.96 92.3,99.5 92.3,100.52 86.41,106.41 79.32,106.41 77.95,107.78 77.95,115.55 76.36,117.14 RW29.1 ; v2(94.04,80.19) 94.04,80.45 95.16,81.57 95.16,81.97 96.7,83.52 97.82,83.52 100.02,85.72 101.1,85.72 103.08,87.7 v1(103.6,87.7) 104.06,87.7 v2(104.17,87.82) 104.56,88.2 104.86,88.2
  IN1 w0.127: v2(104.17,87.82) 104.61,88.25 108.4,88.25 109.08,88.93 110.43,88.93 v2(112.68,86.69)
  BOTTOM w0.089: v2(94.04,80.19) 94.21,80.37 UC1.D50
PCIE_WAKE#_R: length 7.5
  TOP w0.102: v2(77.32,135.05) 76.83,134.55 75.22,134.55 75.09,134.42 75.09,133.41 v1(74.96,133.28) 74.96,132.84 75.57,132.23 RW29.2
  BOTTOM w0.102: v2(77.32,135.05) JWLAN1.55
PG_1V24ALW: length 4.5
  BOTTOM w0.102: v1(137.89,40.81) 137.71,40.99 136.28,40.99 135.91,40.63 RE8.2
  BOTTOM w0.203: UE1.29 135.05,40.02 135.54,40.51 RE8.2
PLT_RST#: length 385.8
  TOP w0.102: v2(72.77,133.09) 72.55,132.88 RW20.1 ; v2(123.37,44.51) 124.69,45.83 v1(125,45.83) 134.64,45.83 v2(135.48,46.67) ; UL1.19 22.8,86.73 v2(22.83,86.77) ; R182.1 27.14,25.7 v2(26.26,24.82) ; v2(106.55,43.66) UM2.2
  IN1 w0.127: v2(24.88,85.97) 24.6,85.69 24.6,83.71 26.3,82.01 26.3,79.5 26.05,79.25 25.73,79.25 25.24,78.77 25.24,78.29 25.82,77.72 25.82,73.21 25.37,72.77 25.37,55.24 25.56,55.05 25.56,48.45 20.93,43.81 20.93,39.75 20.29,39.11 20.29,30.79 v2(19.97,30.48) ; v2(98.08,45.52) 97.63,45.97 94.46,45.97 92.52,44.03 85.98,44.03 79.28,50.73 61.69,50.73 61.31,50.35 52.99,50.35 52.04,49.4 52.04,48 50.58,46.54 47.72,46.54 41.75,40.57 41.75,34.35 39.66,32.25 31.47,32.25 29.72,30.51 29.72,29.36 33.63,25.46 36.6,25.46 36.99,25.07 36.99,24.32 36.8,24.13 33.82,24.13 33.12,24.82 v2(26.26,24.82) ; v2(123.37,44.51) 123.37,44.9 121.45,46.83 120.52,46.83 120.02,46.33 118.67,46.33 116.54,44.21 116.54,42.19 115.63,41.27 108.94,41.27 107.79,40.13 107.03,40.13 106.55,40.61 v2(106.55,43.66) ; v2(72.77,133.09) 73.08,133.09 73.56,133.57 74.35,133.57 74.65,133.28 74.65,131.69 73.88,130.93 73.88,129.73 74.01,129.6 75.92,129.6 76.11,129.41 76.11,125.83 76.33,125.61 76.33,125.6 78.31,123.62 78.31,116.66 78.96,116 78.96,114.29 79.54,113.72 79.54,111.44 82.55,108.43 86.86,108.43 87.09,108.2 87.91,107.37 88.93,107.37 89.18,107.63 90.61,107.63 92.24,106 92.24,105.86 92.24,104.63 91.63,104.02 91.63,99.41 93.46,97.58 93.46,94.68 94.73,93.4 101.25,93.4 v2(101.57,93.09) 102.14,93.66 109.62,93.66 119.41,83.86 119.41,68.34 127.31,60.45 128.24,60.45 129.64,59.05 133.45,59.05 133.96,58.54 133.96,56.57 134.78,55.75 135.23,55.75 135.23,55.74 v2(135.22,55.74)
  BOTTOM w0.102: v2(106.55,43.66) 106.21,44 99.28,44 98.97,44.32 98.78,44.32 98.08,45.02 v2(98.08,45.52) ; v2(19.97,30.48) 18.89,29.4 18.89,25.33 20.23,24 25.43,24 v2(26.26,24.82) 27.13,25.69 JSSD1.50 ; RL24.1 24.27,85.35 v2(24.88,85.97) 24.88,86.47 24.58,86.77 v2(22.83,86.77) ; UC2.4 102.52,91.18 102.19,90.85 CC90.2 102.02,90.31 RC49.2 101.74,90.03 RC51.1 100.43,90.53 100.43,91.94 v2(101.57,93.09) ; v2(135.22,55.74) 135.22,53.4 136.05,52.57 136.05,50.92 136.75,50.22 137.96,50.22 138.59,49.59 138.59,47.87 138.27,47.56 136.1,47.56 135.61,47.06 135.61,46.77 135.5,46.67 v2(135.48,46.67) 135.48,46.6 135.29,46.42 UE1.13
PLT_RST#_WLAN: length 5.1
  TOP w0.102: RW30.1 71.79,134.23 v1(73,134.23) ; RW30.1 70.97,133.66 v2(70.33,134.3) ; RW30.1 RW20.2
  BOTTOM w0.102: JWLAN1.52 v2(70.33,134.3)
PM_BATLOW#: length 12.6
  IN1 w0.127: v2(98.29,86.31) 97.79,86.31 96.19,84.7 93.38,84.7 91.16,82.48 v2(91.16,80.37)
  BOTTOM w0.089: v2(91.16,80.37) 91.16,80.36 91.64,79.88 UC1.J48
  BOTTOM w0.102: v2(98.29,86.31) 98.34,86.36 98.34,87.27 RC45.1
PM_RST_BTN#: length 7.1
  BOTTOM w0.089: 95.95,82.35 95.83,82.35 95.59,82.11 95.59,81.78 95.43,81.62 95.08,81.62 UC1.C51
  BOTTOM w0.102: RC43.1 CC7.1 98.94,85.34 v1(98.24,84.64) 95.95,82.35
PM_SLP_S3#: length 75
  IN1 w0.127: v2(94.23,81.85) 94.6,81.85 95.45,82.7 96.26,82.7 97.13,83.56 100.24,83.56 101.51,84.83 101.51,85.49 102.79,86.77 104.72,86.77 104.79,86.7 109.89,86.7 111.47,85.12 113.01,85.12 117.13,81.01 117.13,67.39 120.23,64.29 120.23,62.7 120.67,62.26 120.67,62.09 125.19,57.57 125.19,53.84 125.83,53.21 126.62,53.21 127.7,52.13 134.27,52.13 134.72,52.57 v2(135.42,52.57)
  BOTTOM w0.102: UC1.D51 94.2,81.82 v2(94.23,81.85) ; UE1.6 135.13,49.22 135.77,49.86 135.77,52.22 v2(135.42,52.57)
PM_SLP_S4#: length 92.5
  IN1 w0.127: v2(138.02,52.07) 137.83,52.26 136.33,52.26 135.59,52.99 134.63,52.99 134.08,52.45 127.74,52.45 126.72,53.46 126.02,53.46 125.45,54.03 125.45,57.67 120.93,62.2 120.93,62.37 120.48,62.81 120.48,64.4 117.38,67.5 117.38,81.12 113.12,85.38 111.57,85.38 110,86.95 108.28,86.95 107.49,87.74 105.86,87.74 105.17,87.05 102.67,87.05 101.13,85.51 101.13,84.81 100.19,83.88 97,83.88 96.07,82.95 95.25,82.95 94.57,82.28 93.08,82.28 92.75,81.96 92.75,81.44 v2(92.2,80.89)
  BOTTOM w0.102: UE1.18 135.88,44.42 CE6.1 135.97,43.57 136.33,43.21 137.06,43.21 137.46,43.62 138.91,43.62 140.27,44.98 140.27,46.9 139.76,47.4 139.76,50.15 138.02,51.89 v2(138.02,52.07) ; v2(92.2,80.89) 91.82,80.51 UC1.J49
PMC_SUSPWRDNACK_R: length 4.2
  BOTTOM w0.102: UE1.19 134.94,44.02 v1(135.76,43.2) 135.97,42.98 RE7.2
POK: length 296.1
  TOP w0.102: v2(132,38.41) CE9.1 132,39.67 v2(131.86,39.81) v1(131.48,40.19)
  TOP w0.127: v2(109.58,77.54) 109.32,77.8 108.8,77.8 108.56,78.04 RC53.1 107.36,78.21 DC3.1 ; v2(184.26,61.66) 184.36,61.75 PR35.1
  IN1 w0.127: v2(131.86,39.81) 133.51,38.16 133.51,33.4 133.26,33.14 130.34,33.14 129.89,32.7 129.89,28.51 127.76,26.37 110.38,26.37 108.65,28.1 108.44,28.1 97.82,28.1 96.78,27.06 82.18,27.06 81.26,26.14 80.99,26.14 72.61,26.14 71.69,27.06 71.48,27.06 66.89,27.06 65.31,28.63 65.29,28.63 65.07,28.86 63.57,28.86 63.04,29.38 60.79,29.38 59.74,28.33 54.01,28.33 53.26,29.08 49.91,29.08 48.95,30.04 48.58,30.04 47.23,30.04 v2(46.07,28.89) ; v2(109.58,77.54) 109.9,77.21 112.15,77.21 112.87,76.49 112.87,66.31 113.71,65.47 113.71,65.11 115.92,62.9 115.92,57.03 118.53,54.41 119.73,54.41 121.7,52.45 122.75,52.45 123.62,51.57 123.62,50.59 125.49,48.72 126.59,48.72 127.18,48.13 v2(127.42,48.13) 127.8,48.51 136.24,48.51 136.69,48.06 139.16,48.06 141.7,45.52 142.36,45.52 142.99,44.89 156.1,44.89 157.04,45.82 159.42,45.82 160.79,44.45 166.47,44.45 168.25,46.22 168.25,49.82 168.54,50.11 169.1,50.11 170.65,51.66 172.16,51.66 172.16,51.66 172.37,51.66 172.37,51.66 174.06,53.35 174.14,53.44 178.42,53.44 178.86,53.44 179.02,53.59 179.12,53.69 182.7,53.69 183.76,54.76 187.31,54.76 v2(187.62,54.45)
  IN2 w0.127: v2(201.81,81.21) 201.76,81.26 199.27,81.26 198.94,80.93 198.94,70.79 198.94,70.47 198.94,70.16 198.94,69.93 194.05,65.04 189.48,65.04 188.37,63.94 187.74,63.94 185.42,63.94 185.11,63.94 184.57,63.4 184.57,61.96 v2(184.26,61.66) 183.61,61.66 182.41,62.86 178.47,62.86 175.7,60.09 175.7,59.25 173.22,56.76 170.49,56.76 v2(170.1,57.16)
  BOTTOM w0.102: v2(132,38.41) 131.88,38.29 UE1.34
  BOTTOM w0.127: v2(127.42,48.13) 127.93,47.62 127.93,43.04 130.94,40.03 131.64,40.03 v2(131.86,39.81) ; PR1801.1 46.64,28.68 46.63,28.7 46.26,28.7 v2(46.07,28.89) ; PU301.9 169.76,57.9 170.1,57.56 v2(170.1,57.16) 170.53,57.16 PR304.2 ; v2(201.81,81.21) 202.33,80.69 PR504.2 203.15,80.01 PU501.9 ; v2(187.62,54.45) 186.83,55.24 186.83,58.89 184.26,61.45 v2(184.26,61.66)
PRIM_PWRGD: length 32.7
  TOP w0.254: PR1205.1 62.07,47.62 61.76,47.94 58.84,47.94 55.15,44.25 55.15,42.48 v3(51.41,38.73) 51.41,37.14 48.45,34.18 48.45,29.05 v2(48.61,28.89)
  BOTTOM w0.254: PR1803.2 48.61,27.69 v2(48.61,28.89) 48.61,31.56 48.16,32.01 PU1801.4
PROG: length 2
  BOTTOM w0.203: PUB01.19 194.7,53 v1(194.69,53.01) 194.7,53.01 194.7,53.88 PRB17.2
PROH: length 5.5
  TOP w0.254: PRB44.2 196.02,54.67 196.36,54.33 PQB33.2 196.36,53.24 196.66,52.94 v2(196.99,52.94)
  BOTTOM w0.203: PUB01.23 196.3,52.35 196.86,52.92 196.96,52.92 v2(196.99,52.94) 197.34,53.3 197.44,53.3 197.85,53.7 PRB21.2
PROJECT_ID: length 36.4
  IN1 w0.127: v2(82.39,104.33) 82.84,103.88 84.3,103.88 85.99,102.19 85.99,97.24 85.99,97.24 85.99,97.03 85.99,96.95 86.65,96.29 86.65,91.32 88.13,89.84 88.13,86.76 87.79,86.42 87.79,85.69 87.59,85.48 87.59,84.18 88.1,83.67 88.1,79.77 88.1,79.66 86.87,78.44 86.87,77.73 86.88,77.72 86.88,77.71 87.29,77.29 88.01,76.58 v2(88.3,76.58)
  BOTTOM w0.089: v2(88.3,76.58) 87.97,76.24 UC1.U39
  BOTTOM w0.102: v2(82.39,104.33) 81.44,105.28 v1(81.44,105.6) RC173.2 RC174.1
PS_ID: length 153.5
  TOP w0.102: v2(127.35,59.77) v1(127.35,59.24)
  TOP w0.254: PR1.2 80.62,148.59 81,148.2 PD2.1 81.91,148.59 PR5.1 v2(82.44,147.96)
  IN2 w0.127: v2(127.35,59.77) 127.35,59.94 127.03,60.26 126.44,60.26 117.32,69.38 117.32,91.77 114.72,94.38 114.72,100.64 110.71,104.64 107.07,104.64 104.11,107.61 104.11,109.01 103.59,109.53 103.59,122.31 102.99,122.91 102.99,128.24 103.7,128.95 103.7,142.77 98.51,147.96 v2(82.44,147.96)
  BOTTOM w0.102: v2(127.35,59.77) 127.35,59.75 127.74,59.36 128.1,59.36 128.59,59.84 133.55,59.84 134.34,59.05 134.34,58.09 135.87,56.55 135.87,53.33 136.46,52.74 136.46,51.09 136.87,50.68 138.4,50.68 139.21,49.87 139.21,47.15 139.54,46.82 139.54,45.52 139.12,45.11 135.33,45.11 135.22,45.22 UE1.16
PSID: length 10.1
  TOP w0.254: PL3.1 76.93,143.51 v1(77.47,142.97) v2(77.82,142.62)
  BOTTOM w0.254: PJPDC1.3 85.2,142.95 84.87,142.62 v2(77.82,142.62)
PSID-1: length 6.3
  TOP w0.102: v1(83.35,147.57) 83.28,147.51 81.57,147.51 81.31,147.76 PR3.2
  TOP w0.254: PQ2.2 79.87,145.47 PR6.1 PR3.2
PSID-2: length 10.5
  TOP w0.102: v1(76.17,142.68) 76.17,143.82 76.93,144.58 PL3.2
  TOP w0.254: PR3.1 78.46,147.76 77.82,147.12 PQ1.1 74.94,146.32 75.91,145.35 PD1.2 75.93,144.63 PL3.2
PSID-3: length 6
  TOP w0.102: v1(73.2,148.09) PQ1.3
  TOP w0.254: PR1.1 77.52,148.59 PQ1.3
PSID-4: length 8.3
  TOP w0.254: PR4.2 81.25,143.39 PR7.1 79.86,142.93 PQ2.1 79.48,143.25 78.77,142.55 v1(78.71,142.55) 78.57,142.55 77.82,143.3 77.82,145.36 PQ1.2
PSID-5: length 2.4
  TOP w0.102: v1(82.58,142.3) 82.9,142.62 PD3.1
  TOP w0.254: PR7.2 82.05,143.28 PD3.1
PSYS_VCCGI: length 3.3
  TOP w0.254: v2(93.73,138.21) 93.52,138.43 v1(93.07,138.43) 92.82,138.17 PRG16.1
  BOTTOM w0.203: PUG1.19 94.48,137.68 93.95,138.21 v2(93.73,138.21)
PSYS_VNN: length 2.6
  TOP w0.102: PRZ18.1 v1(83.37,132.33)
  TOP w0.254: v2(82.74,133.49) 83.14,133.49 PRZ18.1
  BOTTOM w0.203: PUZ1.19 82.88,133.43 82.82,133.49 82.74,133.49 82.74,133.49 v2(82.74,133.49)
PTP_DIS#: length 14.8
  TOP w0.102: v2(131.09,35.94) 131.09,35.35 v1(128.3,32.57) 123.92,32.57 v2(122.91,31.55)
  BOTTOM w0.102: JTP1.3 123.03,30.52 123.03,31.43 v2(122.91,31.55) 122.28,32.18 R41.2 ; UE1.36 131.08,35.94 v2(131.09,35.94)
QPCN_CHG:
  vias: v1(194.15,46.48)
QPCP_CHG: length 1.5
  BOTTOM w0.102: PCB18.1 194.34,44.95 193.52,44.13 v1(193.52,43.87)
REFCLK_CNV: length 17.5
  TOP w0.102: RW12.2 104.64,75.22 103.86,74.43 RC85.1 103.78,73.86 CW1.1 103.51,73.59 v1(102.59,73.59) 102.54,73.55 v2(100.03,73.55)
  IN2 w0.089: v2(91.1,72.04) 91.1,71.48 92.02,70.56 93.39,70.56 93.43,70.52 93.85,70.52 93.87,70.54 94.17,70.54 94.19,70.52 94.85,70.52 95.43,71.1 95.43,71.2 95.64,71.41 95.85,71.41 95.9,71.47
  IN2 w0.127: v2(100.03,73.55) 99.88,73.4 98.3,73.4 96.54,71.64 96.07,71.64 95.9,71.47
  BOTTOM w0.089: UC1.J29 v2(91.1,72.04)
REFCLK_CNV_R: length 93.1
  TOP w0.102: RW12.1 103.64,75.22 102.95,74.53 101.21,74.53 v2(101.16,74.58)
  IN2 w0.127: v2(101.16,74.58) 101.16,74.58 102.03,75.45 102.03,76.88 102.03,77.94 102.03,78.44 103.35,79.75 103.35,81.46 103.73,81.84 103.73,84.39 102.42,85.7 102.42,86.89 102.9,87.37 102.9,88.32 103.58,89 103.58,90.83 103.22,91.18 102.14,91.18 99.64,93.68 98.3,93.68 98.06,93.93 95.77,93.93 95.13,93.93 95.13,93.93 94.38,93.93 88.94,99.37 83.19,99.37 83.17,99.39 79.49,103.07 79.49,103.35 75.53,107.31 75.53,107.66 75.51,107.68 75.51,109.69 75.12,110.08 74.91,110.08 74.52,110.08 74.35,109.91 73.42,109.91 72.39,110.95 72.39,112.06 72.74,112.41 72.74,113.36 72.74,115.35 75.15,117.77 75.15,117.88 75.16,117.89 75.16,121.12 75.01,121.34 74.97,121.45 74.95,121.5 74.95,121.83 74.9,121.87 73.82,122.95 73.82,122.96 73.68,123.1 73.68,124.12 73.06,124.74 73.06,124.95 73.06,124.95 73.06,125.75 73.06,125.75 73.06,125.96 73.31,126.21 73.31,131.33 73.53,131.55 73.53,133.35 74.27,134.09 v2(74.27,134.42)
  BOTTOM w0.102: JWLAN1.64 72.53,137.3 74.27,135.57 v2(74.27,134.42)
REGOUT:
  vias: v1(17.62,87.31) v2(18.13,86.99) v2(18.2,86.42) v2(18.2,85.85)
RGND_VCCGI: length 5.3
  TOP w0.254: v2(95.32,139.81) 95.41,139.72 PCG05.1 ; PCG04.2 96.17,138.82 PCG05.1 ; PRG42.2 93.71,138.82 PRG32.1 PCG05.1
  BOTTOM w0.203: PUG1.22 95.86,139.53 95.58,139.81 v2(95.32,139.81)
RGND_VNN: length 8
  TOP w0.102: v1(84.04,137.85) 84.5,137.4 84.5,136.09 84.1,135.69 v2(84.1,135.67)
  TOP w0.254: PCZ18.2 81.95,134.68 PRZ01.2 83.12,134.65 PCZ19.1 ; PRZ32.1 83.42,134.3 PCZ19.1 ; PCZ19.1 83.42,134.96 83.42,135.26 83.78,135.62 84.08,135.62 84.13,135.67 v2(84.1,135.67)
  BOTTOM w0.203: v2(84.1,135.67) 84.21,135.67 84.5,135.38 PUZ1.22
RING2: length 11.6
  BOTTOM w1.016: 22.01,15.11 24.29,17.39 30.96,17.39 31.47,17.9 32.42,17.9
  vias: v2(21.05,15.26) v2(21.05,14.66) v2(32.77,17) v2(32.77,16.42)
RING2_R: length 24.4
  IN1 w1.016: 20.35,17.46 18.64,15.74 16.35,15.74 15.27,14.66 15.27,7.87 14.13,6.73 6.02,6.73 JHP1.4
  vias: v1(23.59,17.01) v2(21.14,18.66) v2(21.14,18.03)
RJ45_MDIN0: length 9.8
  TOP w0.267: TL1.2 16.31,71.86 15.86,72.3 15.55,72.3 15.18,72.67 15.18,73.59 15.54,73.95 v4(15.54,74.61) 15.54,76.98 14.66,77.86 14.15,77.86 13.85,77.56 13.85,76.9 JRJ45.2
RJ45_MDIN1: length 17
  TOP w0.267: TL1.8 16.46,64.24 16.13,64.57 14.55,64.57 14.54,64.59 14.37,64.59 13.67,65.29 v4(13.67,66.48) 13.67,68.03 v2(13.57,68.13)
  IN1 w0.178: v2(13.57,68.13) 13.67,68.23 13.67,68.86 15.02,70.21 15.02,71.74 15.6,72.32 15.6,74.67 15.53,74.75 15.36,74.75 14.05,73.44 JRJ45.6
RJ45_MDIN2: length 5.2
  BOTTOM w0.267: JRJ45.5 14.91,73.64 15.1,73.45 15.1,72.85 15.75,72.19 16.38,72.19 16.71,71.86 TL2.7
RJ45_MDIN3: length 10.5
  BOTTOM w0.267: JRJ45.8 13.9,70.73 13.9,71.15 14.07,71.32 14.61,71.32 15.02,70.91 15.02,69.3 14.64,68.92 v4(14.64,65.65) 14.64,65.37 15.03,64.98 15.36,64.98 16.1,64.24 TL2.1
RJ45_MDIP0: length 9.8
  TOP w0.267: JRJ45.1 13.47,77.72 13.99,78.24 14.82,78.24 15.92,77.14 v4(15.92,76.26) 15.92,73.8 15.56,73.43 15.56,72.83 15.7,72.69 15.89,72.69 16.34,73.13 TL1.1
RJ45_MDIP1: length 17
  TOP w0.267: v2(14.15,68.13) 14.05,68.03 14.05,65.45 14.5,65 15.7,65 16.21,65.51 TL1.7
  IN1 w0.178: v2(14.15,68.13) 13.97,68.31 13.97,68.74 15.32,70.09 15.32,71.61 15.91,72.19 15.91,74.8 15.66,75.05 15.21,75.05 14.58,75.68 JRJ45.3
RJ45_MDIP2: length 5.1
  BOTTOM w0.267: JRJ45.4 13.94,74.66 13.76,74.48 13.76,74.24 13.98,74.02 15.07,74.02 15.48,73.61 15.48,73.01 15.91,72.58 16.15,72.58 16.7,73.13 TL2.8
RJ45_MDIP3: length 10.5
  BOTTOM w0.267: JRJ45.7 13.81,71.6 13.91,71.7 14.77,71.7 15.4,71.06 15.4,69.15 15.02,68.77 15.02,65.63 15.29,65.36 15.95,65.36 16.1,65.51 TL2.2
RSET: length 3.4
  TOP w0.203: UL1.31 19.54,82.94 v2(19.38,82.77)
  BOTTOM w0.254: v2(19.38,82.77) 19.99,82.16 v1(20.74,82.16) RL2.2
RTC_DET#: length 54.9
  TOP w0.102: RC138.1 116.81,64.93 v2(117.17,64.58) ; v2(109.8,61.21) QC9.1
  IN1 w0.127: v2(117.17,64.58) 115.35,66.39 115.35,76.53 110.7,81.18 107.85,81.18 107.54,80.87 105.39,80.87 104.13,79.61 100.29,79.61 98.81,81.08 98.81,81.54 98.26,82.1 97.39,82.1 96.49,81.2 96.49,79.76 95.39,78.66 92.36,78.66 92.31,78.61 91.4,78.61 v2(91.02,78.23)
  IN2 w0.127: v2(109.8,61.21) 113.17,64.58 v2(117.17,64.58)
  BOTTOM w0.089: v2(91.02,78.23) 90.75,77.95 UC1.L43
RTC_PWR: length 2.9
  TOP w0.102: v1(108.17,58.48) 109.69,56.97 DC1.3
SATA_CRX_C_DTX_N0: length 2.5
  BOTTOM w0.114: JHDD1.5 188.2,36.37 188.07,36.5 188.07,36.68 188.37,36.98 188.37,37.57 CS6.2
SATA_CRX_C_DTX_N1: length 5.4
  BOTTOM w0.114: JODD1.10 189.2,66.58 189.58,66.2 189.58,65.27 189.2,64.89 JODD1.9 189.2,63.78 189.58,63.4 189.58,62.61 CS110.2
SATA_CRX_C_DTX_P0: length 2.5
  BOTTOM w0.114: CS5.2 188.12,37.57 188.12,37.08 187.83,36.79 187.83,36.5 187.7,36.37 JHDD1.6
SATA_CRX_C_DTX_P1: length 5.5
  BOTTOM w0.114: CS111.2 189.82,62.63 189.82,63.38 190.2,63.76 JODD1.11 190.2,64.91 189.82,65.29 189.82,66.21 190.2,66.59 JODD1.12
SATA_CRX_DTX_N0: length 111.6
  IN1 w0.089: 91.49,60.38 91.49,60.39 91.56,60.45 91.56,60.51 91.56,60.84 91.48,60.93 91.26,60.93 91.16,60.83 v2(91.16,60.74)
  IN1 w0.127: 91.49,60.38 91.35,60.25 91.35,58.93 91.94,58.34 93.08,57.2 96.22,57.2 96.73,57.71 98.01,57.71 99.4,56.32 103.63,56.32 v2(103.87,56.08)
  IN2 w0.127: v2(103.87,56.08) 104.83,56.08 105.02,55.89 107.09,55.89 110.48,52.5 113.81,52.5 114.3,52.99 119.34,52.99 120.77,51.57 123.53,51.57 125.57,49.53 126.85,49.53 127.06,49.32 132.15,49.32 133.34,48.13 138.16,48.13 140.6,45.69 148.1,45.69 152.01,41.78 180.81,41.78 182.65,39.94 187.62,39.94 187.81,39.75 188.24,39.75 188.54,40.05 v2(188.54,40.63)
  BOTTOM w0.089: v2(91.16,60.74) 91.24,60.74 UC1.J5
  BOTTOM w0.114: v2(188.54,40.63) 188.63,40.54 188.63,38.87 CS6.1
SATA_CRX_DTX_N1: length 152.4
  IN1 w0.089: v2(92.18,60.96) 92.18,60.74 92.05,60.61 92.05,59.91 92.15,59.81
  IN1 w0.127: v2(102.24,57.62) 101.49,57.62 101.14,57.96 99.54,57.96 99.02,58.48 96.24,58.48 95.79,58.03 93.39,58.03 92.54,58.88 92.54,59.42 92.32,59.64 92.15,59.81
  IN2 w0.127: v2(102.24,57.62) 102.41,57.78 103.07,57.78 103.14,57.85 105.41,57.85 105.61,57.66 108.35,57.66 109.12,56.89 109.12,56.14 110.66,54.6 120.08,54.6 121.52,53.16 126.08,53.16 127.51,51.72 132.52,51.72 133.85,50.39 136.35,50.39 136.7,50.04 138.47,50.04 139.49,49.02 140.85,49.02 142.18,47.68 148.29,47.68 152.65,43.32 184.99,43.32 186.45,41.86 190.12,41.86 190.79,41.18 192.54,41.18 192.87,41.51 199.13,41.51 202.09,44.47 202.09,49.57 203.12,50.6 203.12,55.29 201.84,56.57 199.74,56.57 199.3,57.02 199.3,57.22 199.3,58.73 199.42,58.86 199.65,58.86 v2(199.81,58.7)
  BOTTOM w0.089: UC1.G5 v2(92.18,60.96)
  BOTTOM w0.114: CS110.1 189.26,60.51 190.33,59.45 192.97,59.45 193.51,58.91 198.8,58.91 199.01,58.7 v2(199.81,58.7)
SATA_CRX_DTX_P0: length 111.7
  IN1 w0.089: v2(91.16,61.37) 91.43,61.11 91.55,61.11 91.74,60.92 91.74,60.51 91.74,60.37 91.68,60.32 91.68,60.29 91.64,60.25 91.64,60.23 91.63,60.22
  IN1 w0.127: 91.63,60.22 91.61,60.2 91.61,59.04 92.12,58.53 92.12,58.53 93.19,57.46 96.11,57.46 96.62,57.97 98.12,57.97 99.51,56.59 103.74,56.59 103.8,56.59 v2(103.87,56.66)
  IN2 w0.127: v2(103.87,56.66) 104.04,56.5 104.05,56.5 104.2,56.34 104.94,56.34 105.13,56.15 107.2,56.15 110.59,52.76 113.7,52.76 114.19,53.26 119.45,53.26 120.88,51.83 123.64,51.83 125.68,49.79 126.96,49.79 127.17,49.58 132.26,49.58 133.45,48.39 138.27,48.39 140.71,45.95 148.21,45.95 152.12,42.04 180.92,42.04 182.76,40.2 187.73,40.2 187.92,40.01 188.13,40.01 188.28,40.16 188.28,40.3 188.12,40.46 188.12,40.46 v2(187.96,40.63)
  BOTTOM w0.089: UC1.J7 v2(91.16,61.37)
  BOTTOM w0.114: CS5.1 187.8,39.37 187.94,39.51 188.2,39.51 188.38,39.69 188.38,40.2 v2(187.96,40.63)
SATA_CRX_DTX_P1: length 152.4
  IN1 w0.089: 92.25,60.09 92.22,60.11 92.22,60.53 92.31,60.62 92.47,60.62 v2(92.66,60.43)
  IN1 w0.127: v2(102.26,58.2) 102.23,58.2 101.91,57.88 101.6,57.88 101.25,58.22 99.65,58.22 99.13,58.74 96.13,58.74 95.68,58.3 93.5,58.3 92.81,58.99 92.81,59.53 92.25,60.09
  IN2 w0.127: v2(102.26,58.2) 102.26,58.19 102.41,58.05 102.96,58.05 103.03,58.12 105.52,58.12 105.72,57.92 108.46,57.92 109.38,57 109.38,56.25 110.77,54.86 120.19,54.86 121.63,53.42 126.19,53.42 127.62,51.99 132.63,51.99 133.96,50.65 136.46,50.65 136.81,50.31 138.58,50.31 139.6,49.28 140.96,49.28 142.29,47.95 148.4,47.95 152.76,43.59 185.1,43.59 186.56,42.12 190.23,42.12 190.9,41.45 192.44,41.45 192.76,41.77 199.02,41.77 201.83,44.57 201.83,49.68 202.85,50.71 202.85,55.18 201.73,56.31 199.63,56.31 199.03,56.91 199.03,57.11 199.03,58.84 199.31,59.12 199.65,59.12 v2(199.81,59.28)
  BOTTOM w0.089: UC1.H4 v2(92.66,60.43)
  BOTTOM w0.114: v2(199.81,59.28) 199.47,58.95 199.11,58.95 198.9,59.16 193.62,59.16 193.07,59.7 190.43,59.7 189.51,60.62 189.51,60.78 189.62,60.89 190.04,60.89 190.15,61.01 CS111.1
SATA_CTX_C_DRX_N0: length 2.6
  BOTTOM w0.114: CS4.2 189.66,37.89 189.96,37.59 189.96,37.4 189.33,36.76 189.33,36.5 189.2,36.37 JHDD1.3
SATA_CTX_C_DRX_N1: length 5.5
  BOTTOM w0.114: JODD1.6 187.2,66.57 186.79,66.16 186.79,65.91 186.93,65.76 186.93,65.32 187.2,65.05 JODD1.5 187.2,63.46 186.82,63.09 186.82,62.61 CS113.2
SATA_CTX_C_DRX_P0: length 2.6
  BOTTOM w0.114: JHDD1.2 189.7,36.37 189.57,36.5 189.57,36.66 190.21,37.3 190.21,37.57 CS3.2
SATA_CTX_C_DRX_P1: length 5.5
  BOTTOM w0.114: JODD1.4 186.2,66.43 186.54,66.09 186.54,65.81 186.69,65.66 186.69,65.23 186.2,64.74 JODD1.3 186.2,63.51 186.58,63.13 186.58,62.64 CS18.2
SATA_CTX_DRX_N0: length 110.8
  IN2 w0.127: v2(189.8,39.49) 189.95,39.64 189.95,39.83 189.85,39.93 189.51,39.93 188.32,38.74 182.65,38.74 181.03,40.36 175.39,40.36 174.74,41.01 151.06,41.01 147.15,44.92 140.28,44.92 137.95,47.25 133.13,47.25 131.83,48.55 125.09,48.55 123.37,50.26 120.71,50.26 119.42,51.56 107.6,51.56 104.16,55 99.31,55 v2(99.19,54.88)
  BOTTOM w0.089: 92.47,56.95 92.46,56.97 92.46,57.02 91.74,57.74 91.74,59.54 UC1.J2
  BOTTOM w0.114: CS4.1 189.97,39.13 189.97,39.32 v2(189.8,39.49) ; v2(99.19,54.88) 99.19,54.68 99.07,54.57 98.84,54.57 98.74,54.67 98.74,55.13 98.64,55.22 98.46,55.22 98.17,54.93 96.45,54.93 95.67,55.72 93.71,55.72 92.47,56.95
SATA_CTX_DRX_N1: length 157.9
  IN2 w0.127: v2(98.32,56.05) 102.43,56.05 103.46,57.08 105.07,57.08 105.39,56.77 107.35,56.77 110.36,53.76 119.82,53.76 121.2,52.38 125.71,52.38 128,50.09 132.82,50.09 133.64,49.27 138.15,49.27 139.17,48.25 140.53,48.25 141.86,46.91 147.97,46.91 152.33,42.55 181.13,42.55 182.86,40.83 186.85,40.83 187.11,41.09 189.8,41.09 189.87,41.02 190.63,40.25 191.3,40.25 191.42,40.13 191.42,39.24 191.92,38.74 198.8,38.74 199.81,39.75 199.81,41.09 202.89,44.17 202.89,49.28 204.27,50.66 204.27,55.54 201.96,57.85 199.97,57.85 v2(199.81,58.01)
  BOTTOM w0.089: 93.98,57.04 93.98,57.06 93.91,57.13 93.01,57.13 92.09,58.05 92.09,59.29 92.14,59.34 UC1.H2
  BOTTOM w0.114: CS113.1 186.78,61.04 186.78,60.62 186.89,60.5 188.05,60.5 189.72,58.83 192.74,58.83 193.18,58.4 198.42,58.4 198.97,57.85 199.64,57.85 v2(199.81,58.01) ; v2(98.32,56.05) 98.18,56.19 96.46,56.19 95.98,56.68 94.32,56.68 93.98,57.01 93.98,57.04
SATA_CTX_DRX_P0: length 110.8
  IN2 w0.127: v2(99.19,55.47) 99.38,55.27 104.27,55.27 107.71,51.82 119.53,51.82 120.82,50.53 123.48,50.53 125.2,48.81 131.94,48.81 133.24,47.51 138.06,47.51 140.39,45.18 147.26,45.18 151.17,41.27 174.85,41.27 175.5,40.62 181.14,40.62 182.76,39 188.21,39 189.4,40.19 189.96,40.19 190.22,39.94 190.22,39.65 v2(190.38,39.49)
  BOTTOM w0.089: 92.65,57.13 92.6,57.13 91.91,57.81 91.91,59.69 UC1.J3
  BOTTOM w0.114: v2(190.38,39.49) 190.21,39.32 190.21,39.13 CS3.1 ; 92.65,57.13 93.81,55.96 95.77,55.96 96.55,55.18 98.07,55.18 98.35,55.47 v2(99.19,55.47)
SATA_CTX_DRX_P1: length 157.9
  IN2 w0.127: v2(199.81,57.43) 199.97,57.59 200.56,57.59 200.69,57.46 200.69,57.27 200.82,57.15 201.07,57.15 201.2,57.27 201.2,57.46 201.33,57.59 201.85,57.59 204.01,55.43 204.01,50.77 202.63,49.39 202.63,44.28 199.54,41.2 199.54,39.86 198.69,39 192.03,39 191.69,39.35 191.69,40.24 191.56,40.36 191.41,40.52 190.74,40.52 190.13,41.13 189.91,41.35 187,41.35 186.74,41.09 182.97,41.09 181.24,42.81 152.44,42.81 148.08,47.18 141.97,47.18 140.64,48.51 139.28,48.51 138.26,49.54 133.75,49.54 132.93,50.36 128.11,50.36 125.82,52.65 121.31,52.65 119.93,54.03 110.47,54.03 107.46,57.03 105.5,57.03 105.18,57.35 103.35,57.35 102.32,56.31 98.65,56.31 98.33,56.63 v2(98.33,56.63)
  BOTTOM w0.089: 94.16,57.19 94.15,57.2 94.1,57.2 93.99,57.31 93.09,57.31 92.27,58.13 92.27,58.47 92.36,58.56 92.53,58.56 92.62,58.65 92.62,58.82 92.53,58.91 92.36,58.91 92.27,59 92.27,59.21 92.36,59.31 UC1.H1
  BOTTOM w0.114: CS18.1 186.53,61.1 186.53,60.52 186.79,60.26 187.95,60.26 189.62,58.59 192.63,58.59 193.07,58.15 198.32,58.15 198.86,57.6 199.63,57.6 v2(199.81,57.43) ; 94.16,57.19 94.42,56.92 96.08,56.92 96.56,56.44 98.14,56.44 v2(98.33,56.63)
SATA_LED#: length 277.9
  TOP w0.102: v2(61.38,28.13) 59.63,29.87 59.63,32.02 60.74,33.13 64.09,33.13 65.27,33.13 65.52,33.38 74.03,33.38 78.81,33.38 79.97,32.23 113.6,32.23 117.95,36.58 117.95,39.02 118.55,39.61 118.55,49.7 120.93,52.07 v1(120.93,56) 120.93,56.54 v2(120.41,57.06)
  TOP w0.254: v2(12.99,119.44) 12.29,120.14 Q25.2 11.48,120.14 R78.1
  IN1 w0.127: v2(120.41,57.06) 119.13,57.06 117.19,59 117.19,63.43 114.98,65.63 114.98,66 114.84,66.14 114.84,76.32 111.13,80.03 109.31,80.03 108.92,80.42 108.17,80.42 107.86,80.11 105.7,80.11 104.44,78.85 99.97,78.85 98.24,80.58 97.67,80.58 94.81,77.72 93.59,77.72 93.07,78.24 v2(93.07,78.27) ; v2(61.38,28.13) 60.82,27.57 48.39,27.57 47.77,26.94 42.62,26.94 41.69,27.87 41.69,28.44 v2(42.2,28.95)
  IN1 w0.254: v2(39.53,119.63) 38.2,118.3 35.97,118.3 34.83,119.44 27.02,119.44 26.26,118.68 13.75,118.68 v2(12.99,119.44)
  IN2 w0.254: v2(67.22,106.29) 62.1,101.18 56.97,101.18 51.85,106.29 51.85,113.6 45.82,119.63 v2(39.53,119.63) ; v2(86.02,90.95) 86.41,90.95 89.32,88.04 89.32,86.36 90.79,84.88 90.79,83.36 91.64,82.51 91.64,80.01 92.08,79.56 92.08,79.08 92.41,78.75 92.59,78.75 93.07,78.27 v2(93.07,78.27)
  BOTTOM w0.102: R77.2 43.09,28.07 42.2,28.95 v2(42.2,28.95)
  BOTTOM w0.254: v2(93.07,78.27) 93.07,78 UC1.F43 ; v2(86.02,90.95) 86.01,90.96 86.01,91.79 86.03,91.8 86.03,98.08 RC119.1 82.18,101.2 79.9,103.48 77.32,103.48 77.31,103.48 77.08,103.48 77.03,103.48 74.21,106.29 v2(67.22,106.29)
SATA_LED#_R: length 7.9
  TOP w0.102: v1(5.69,117.28) 6.64,117.28 8.7,119.34 Q22.3
  TOP w0.254: Q25.3 12.16,119.49 R78.2 10.41,119.49 R80.2 10.05,119.52 9.8,119.77 Q22.3
SATA_ODD_PRSNT: length 160.3
  TOP w0.089: 95.99,73.47 94.78,72.26 94.78,71.94 94.45,71.62 93.76,71.62 93.63,71.74 93.63,72.24 93.43,72.44 90.13,72.44 89.76,72.07 v2(89.68,72.07)
  TOP w0.102: v2(111.95,76) 112.07,75.88 v1(112.49,75.88) RC120.1 ; 95.99,73.47 96.43,73.91 96.87,73.91 99.41,76.45 103.16,76.45 103.27,76.34 v2(103.32,76.34)
  IN1 w0.127: v2(103.32,76.34) 103.4,76.27 103.48,76.27 104.53,75.22 108.45,75.22 109.69,76.45 111.5,76.45 v2(111.95,76) 112.1,75.85 112.1,65.18 115.16,62.12 115.16,56.65 118.22,53.59 119.44,53.59 121.34,51.68 122.13,51.68 122.69,51.12 v2(122.69,51.1) 122.69,50.44 125.17,47.96 126.27,47.96 127.06,47.18 128.88,47.18 129.64,47.94 133,47.94 133.24,47.7 138.58,47.7 141,45.27 142.25,45.27 142.88,44.64 156.21,44.64 157.14,45.57 159.31,45.57 160.69,44.19 166.59,44.19 168.5,46.1 168.5,48.38 v2(168.82,48.69)
  IN2 w0.127: v2(192.2,68.31) 190.46,68.31 189.2,67.05 184.82,67.05 184.76,66.99 184.75,66.99 183.04,65.27 183.02,65.27 182.89,65.15 178.6,65.15 175.68,62.23 169.13,62.23 166.85,59.94 166.85,50.66 v2(168.82,48.69)
  BOTTOM w0.089: UC1.P29 v2(89.68,72.07)
  BOTTOM w0.102: UE1.101 121.48,52.03 121.99,51.52 122.27,51.52 122.69,51.1 v2(122.69,51.1) ; v2(192.2,68.31) JODD1.16 JODD1.15
SCL_CHG: length 2.5
  BOTTOM w0.203: PUB01.22 195.9,52.51 v1(196.39,53.01) 197.04,53.65 PRB20.2
SDA_CHG: length 2.3
  BOTTOM w0.203: PUB01.21 195.5,52.7 196.25,53.45 PRB19.2
SDIO_VCCGI: length 4.7
  BOTTOM w0.102: PRG12.1 101.13,138.74 101.38,139 v1(102.97,139)
  BOTTOM w0.203: PRG12.1 100.9,138.51 99.67,137.28 PUG1.4
SDIO_VNN: length 1.6
  BOTTOM w0.203: PRZ14.1 88.93,132.97 88.38,132.97 88.32,133.03 PUZ1.4
SERIRQ: length 66.6
  TOP w0.102: v1(127.8,47.75) 128.49,47.75 v2(128.55,47.68)
  IN1 w0.127: v2(103.28,77.16) 104.96,75.47 108.35,75.47 109.58,76.7 111.94,76.7 112.37,76.28 112.37,66.1 113.21,65.26 113.21,64.89 115.41,62.69 115.41,56.75 118.26,53.91 119.48,53.91 121.45,51.94 122.44,51.94 123.11,51.27 123.11,50.38 125.27,48.21 126.38,48.21 127.16,47.43 128.3,47.43 v2(128.55,47.68)
  BOTTOM w0.089: UC1.B37 95,75.18 95.28,75.18 95.64,75.55 95.92,75.55 98.41,78.04 98.53,78.04
  BOTTOM w0.102: v2(128.55,47.68) 128.55,48.37 130.59,50.42 UE1.3 ; v2(103.28,77.16) 103.28,77.54 103.13,77.68 100.78,77.68 100.43,78.04 98.53,78.04
SET1_VCCGI: length 3.1
  TOP w0.254: PRG13.1 PRG06.2 98.64,139.68 v2(98.71,139.76)
  BOTTOM w0.102: v1(98.9,140.46) 98.71,140.27 v2(98.71,139.76)
  BOTTOM w0.203: PUG1.28 98.26,139.63 98.41,139.77 98.7,139.77 v2(98.71,139.76)
SET1_VNN: length 3.5
  TOP w0.254: PRZ41.2 88.1,135.24 87.82,134.96 PRZ15.1 87.46,135.49 v2(87.38,135.57)
  BOTTOM w0.102: v1(87.92,136.2) 87.38,135.67 v2(87.38,135.57)
  BOTTOM w0.203: PUZ1.28 86.9,135.41 87.05,135.57 v2(87.38,135.57)
SET2_VCCGI: length 4.5
  TOP w0.102: v1(97.34,138.35) 98.08,139.09 v2(98.08,140.14)
  TOP w0.254: PRG07.2 PRG14.1 98.03,140.19 v2(98.08,140.14)
  BOTTOM w0.203: v2(98.08,140.14) 98.08,140.01 97.86,139.8 PUG1.27
SET2_VNN: length 3.3
  TOP w0.102: v2(86.98,136.03) 86.98,135.9 v1(86.58,135.5)
  TOP w0.254: v2(86.98,136.03) 86.84,136.16 PRZ16.1 PRZ07.2
  BOTTOM w0.203: PUZ1.27 86.5,135.57 86.95,136.03 v2(86.98,136.03)
SET3_VCCGI: length 3.7
  TOP w0.102: v1(97.43,139.66) 97.46,139.69 v2(97.46,140.14)
  TOP w0.254: v2(97.46,140.14) 97.49,140.17 97.49,140.7 97.21,140.98 PRG08.2 PRG15.1
  BOTTOM w0.203: PUG1.26 v2(97.46,140.14)
SET3_VNN: length 4
  TOP w0.102: v1(85.25,135.5) 85.76,135.5 86.28,136.03 v2(86.29,136.03)
  TOP w0.254: PRZ17.1 PRZ08.2 86.01,136.58 86.29,136.3 v2(86.29,136.03)
  BOTTOM w0.203: v2(86.29,136.03) 86.1,135.83 PUZ1.26
SLEEVE: length 15.1
  IN1 w1.016: 18.96,14.47 19.85,14.47 20.54,13.77 21.75,13.77 22.51,14.54 22.51,15.87 24.16,17.52 31.4,17.52
  vias: v1(17.94,13.08) v2(17.88,14.79) v2(17.88,14.16) v2(32.19,17) v2(32.19,16.42)
SLEEVE_R: length 14.3
  IN1 w1.016: 18.51,17.52 18.07,17.08 15.76,17.08 14,18.83 6.46,18.83 5.53,17.89
  vias: v2(19.21,18.66) v2(19.21,18.03)
SMB_1.8V_3.3V: length 20.8
  TOP w0.254: v2(100.19,71.66) v3(99.21,70.68) 99.21,70.56 98.36,69.71 95.47,69.71 95.08,69.32 93.96,69.32 93.4,68.77 92.87,68.77 92.74,68.89 92.24,68.89 91.81,68.47 v2(91.81,68.34) ; RC6.2 RC10.1 108.25,72.46 v2(107.48,71.69)
  IN1 w0.254: v2(107.48,71.69) 107.1,72.07 103.41,72.07 103.09,72.39 100.91,72.39 v2(100.19,71.66)
  BOTTOM w0.254: v2(91.81,68.34) 91.81,68.25 UC1.J21
SN_1.2V: length 1.7
  TOP w0.102: PRM01.2 v1(21.31,101.47)
SN_1.05V: length 1.4
  TOP w0.102: v1(147.74,60.64) 147.61,60.76 PCH13.1
SN_1.8V: length 1.5
  TOP w0.102: PR1804.2 50.71,30.28 v1(50.2,29.78)
SN_1.24V: length 1
  TOP w0.102: PC1207.1 v1(62.26,38.86)
SN_3V: length 1.7
  TOP w0.102: PR305.2 v1(162.66,57.02)
SN_5V: length 1.4
  TOP w0.102: PR505.2 v1(209.33,81.97)
SN_CHG: length 1.3
  TOP w0.102: PCB29.1 v1(183.5,46.45)
SN_VCCGI: length 1.7
  TOP w0.102: PRG20.2 92.36,120.01 v1(92.74,119.63)
SN_VNN: length 1.5
  TOP w0.102: PRZ23.2 v1(83.47,116.07)
SOC_BKLTCTL: length 15.5
  TOP w0.102: v2(98.14,79.5) 98.97,80.32 98.97,81.21 v1(100.24,82.48) 101.68,83.93 102.09,83.93 v2(102.48,84.32)
  BOTTOM w0.089: 98.53,79.5 v2(98.14,79.5) ; UC1.B41 95.63,76.98 95.73,77.08
  BOTTOM w0.102: RC159.2 98.53,79.5 ; UC8.2 104.11,85.15 103.84,84.88 102.92,84.88 102.85,84.95 RC5.2 102.21,84.6 v2(102.48,84.32) ; 95.73,77.08 96.68,77.08 98.14,78.55 v2(98.14,79.5)
SOC_DP1_CTRL_CLK: length 114.8
  TOP w0.102: RC3.1 103.42,79.41 103.42,79.41 103.37,79.46 100.25,79.46 98.65,77.86 97.02,77.86 96.55,78.33 96.55,78.71 96.51,78.75 v2(96.51,78.77) ; v2(30.26,96.58) 29.56,96.58 v1(29.43,96.71) 28.78,97.36 Q57.3
  IN2 w0.127: v2(96.51,78.77) 96.5,78.77 96.5,79.99 95.75,80.75 95.75,80.76 94.78,81.73 94.78,82.02 94.26,82.55 93.44,82.55 92.64,83.34 92.64,85.63 90.12,88.16 90.12,88.93 89.63,89.42 88.75,89.42 86.65,91.52 77.63,91.52 74.98,94.17 70.24,94.17 69.6,94.17 66.09,97.68 64.83,97.68 62.48,100.03 56.66,100.03 41.76,114.93 37.26,114.93 36.69,114.36 33.7,114.36 31.34,112 31.34,102.87 29.05,100.58 29.05,96.83 29.23,96.64 30.2,96.64 v2(30.26,96.58)
  BOTTOM w0.089: UC1.C42 94.86,77.61 95.1,77.61 95.2,77.71 96.1,77.71 96.71,78.31 96.71,78.56 96.51,78.75 v2(96.51,78.77)
SOC_DP1_CTRL_DATA: length 118
  TOP w0.102: v2(97.09,78.77) 97.04,78.71 97.04,78.53 97.22,78.34 98.45,78.34 100.05,79.94 103.21,79.94 RC2.1 ; Q58.3 29.36,93.99 v1(29.56,93.78) 29.83,93.52 v2(30.19,93.52)
  IN2 w0.127: v2(97.09,78.77) 97.01,78.85 97.01,80.2 96.26,80.96 96.26,80.97 95.28,81.94 95.28,82.24 94.47,83.05 93.65,83.05 93.15,83.55 93.15,85.84 90.62,88.37 90.62,89.14 89.84,89.93 88.96,89.93 86.86,92.03 77.84,92.03 75.19,94.67 70.24,94.67 69.81,94.67 66.3,98.19 65.04,98.19 62.69,100.54 56.87,100.54 41.97,115.44 37.05,115.44 36.48,114.87 33.49,114.87 30.83,112.21 30.83,103.08 28.54,100.79 28.54,94.87 29.88,93.53 30.2,93.53 30.2,93.52 v2(30.19,93.52)
  BOTTOM w0.089: UC1.A42 95.4,77.53 96.17,77.53 96.88,78.24 96.88,78.56 v2(97.09,78.77)
SOC_DP1_HPD#: length 157.7
  TOP w0.102: v2(74.96,114.87) 75.6,114.87 v1(76.08,114.39) 76.36,114.1 76.36,107.12 78.65,104.83 85.75,104.83 90.64,99.95 90.64,98.87 94.12,95.39 100.69,95.39 103.82,98.51 v2(104.3,98.51)
  IN1 w0.127: v2(26.13,92.64) 27.59,94.1 27.59,103.48 26.77,104.3 26.77,106.99 28.67,108.9 28.67,111.26 31.96,114.55 40.07,114.55 40.33,114.3 45.38,114.3 46.46,115.37 58.33,115.37 59.09,114.61 61.02,114.61 62.03,115.63 73.21,115.63 73.21,115.63 73.42,115.63 74.18,114.87 v2(74.96,114.87)
  IN2 w0.127: v2(105.69,78.42) 105.69,79.32 109.03,82.66 109.03,89.37 107.78,90.61 107.78,92.06 104.3,95.54 v2(104.3,98.51)
  BOTTOM w0.089: 98.53,78.28 98.4,78.28 95.87,75.74 95.57,75.74 95.42,75.89 95.2,75.89 95.04,75.74 95.04,75.71 94.96,75.63 UC1.C38
  BOTTOM w0.102: 98.53,78.28 100.47,78.28 100.87,77.89 104.15,77.89 104.69,78.42 v2(105.69,78.42) ; v2(26.13,92.64) 26.89,92.64 28.65,90.89 28.65,87.85 28.53,87.74 RG47.2 27.67,87.74 27.6,87.67 QG1.6
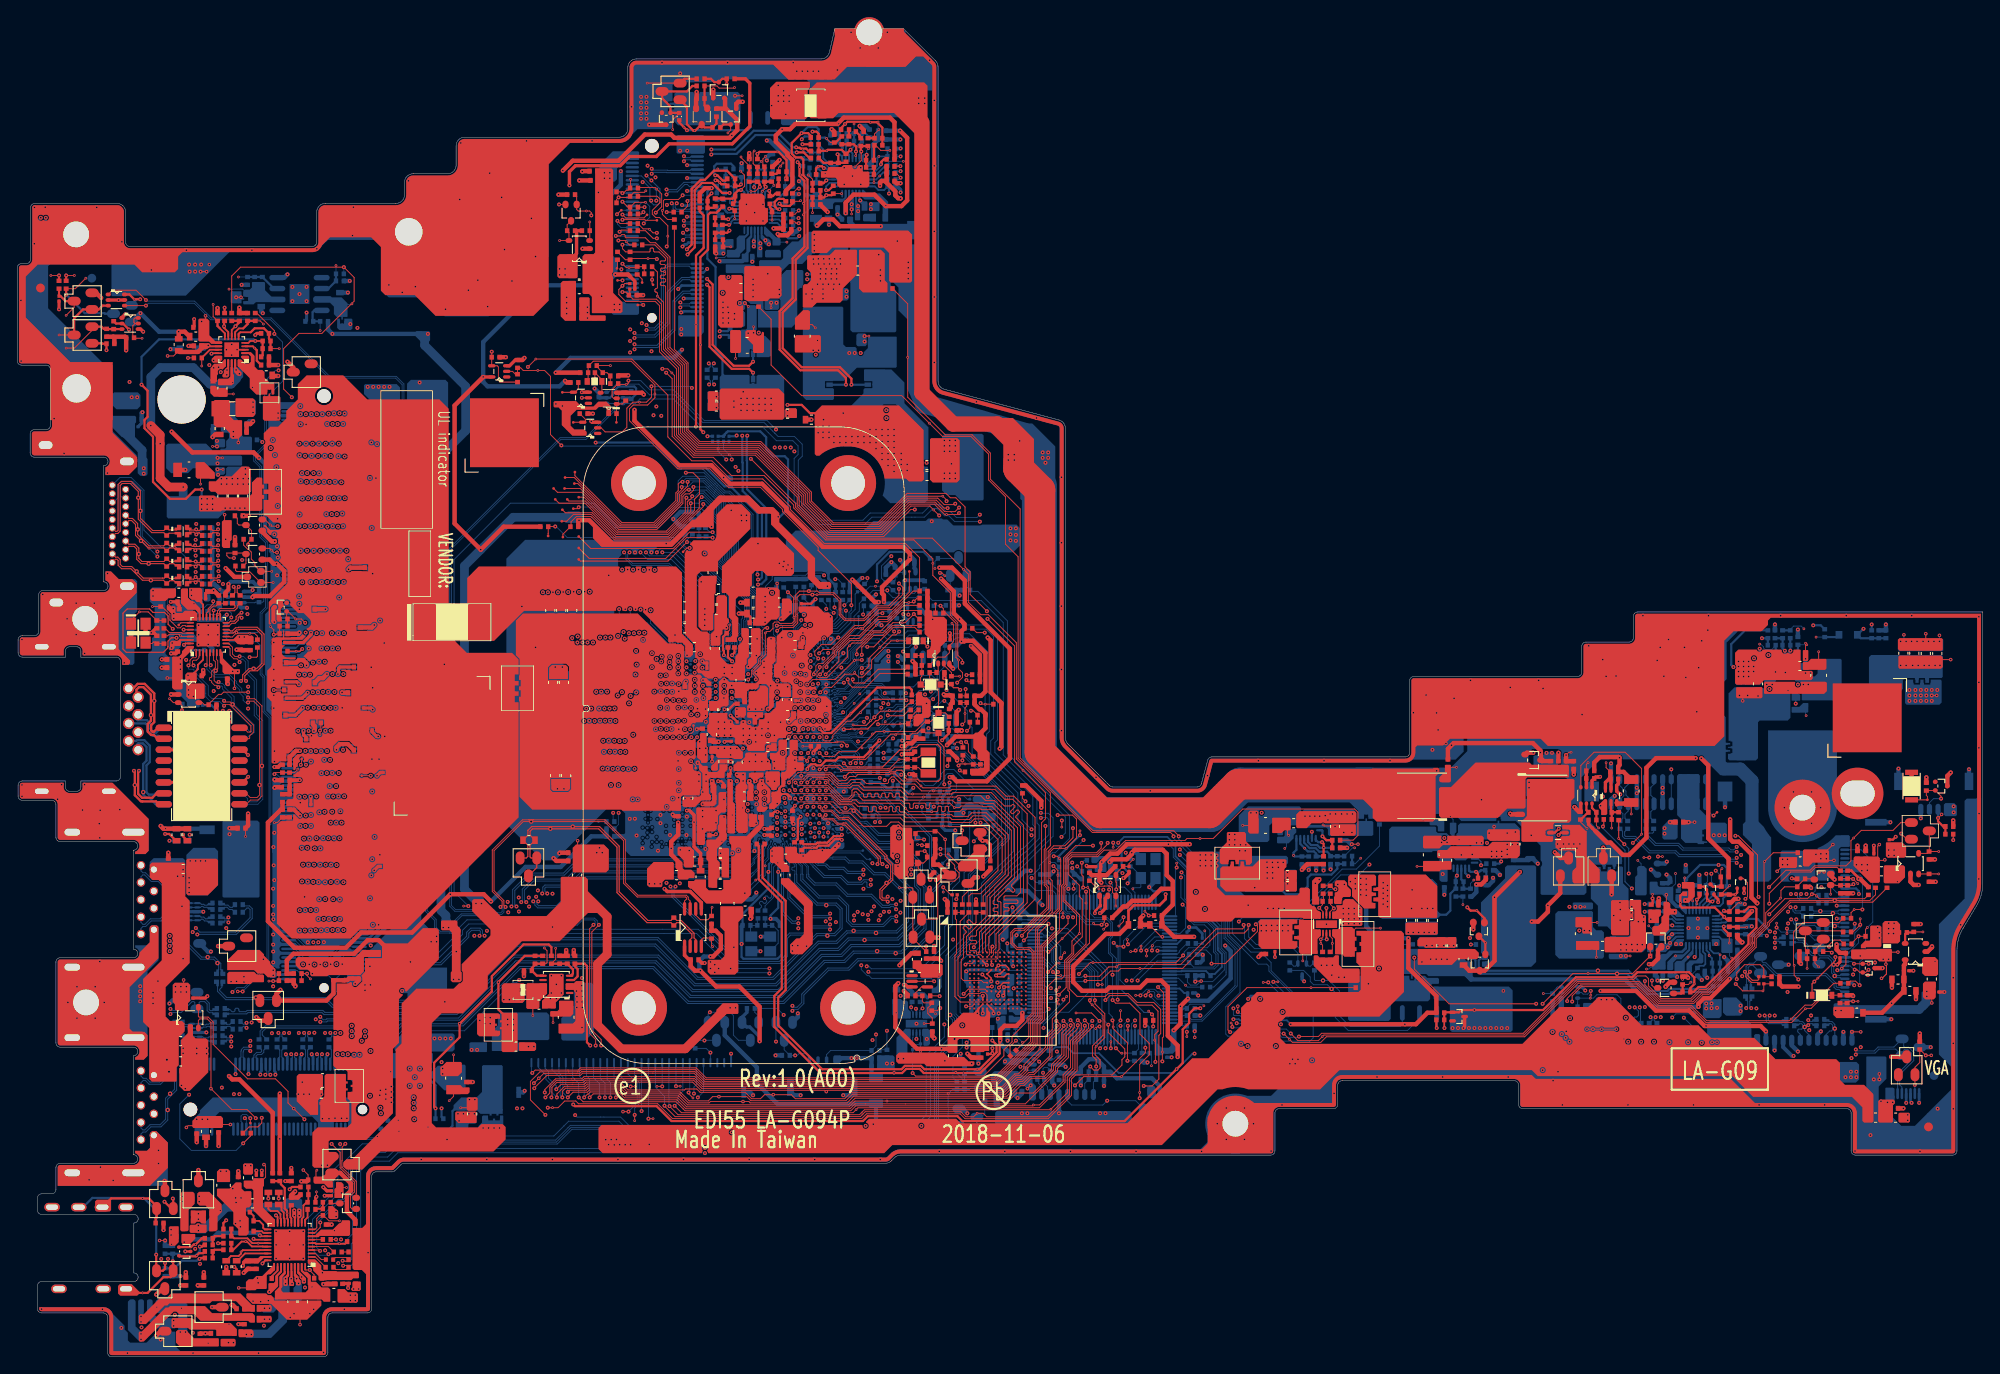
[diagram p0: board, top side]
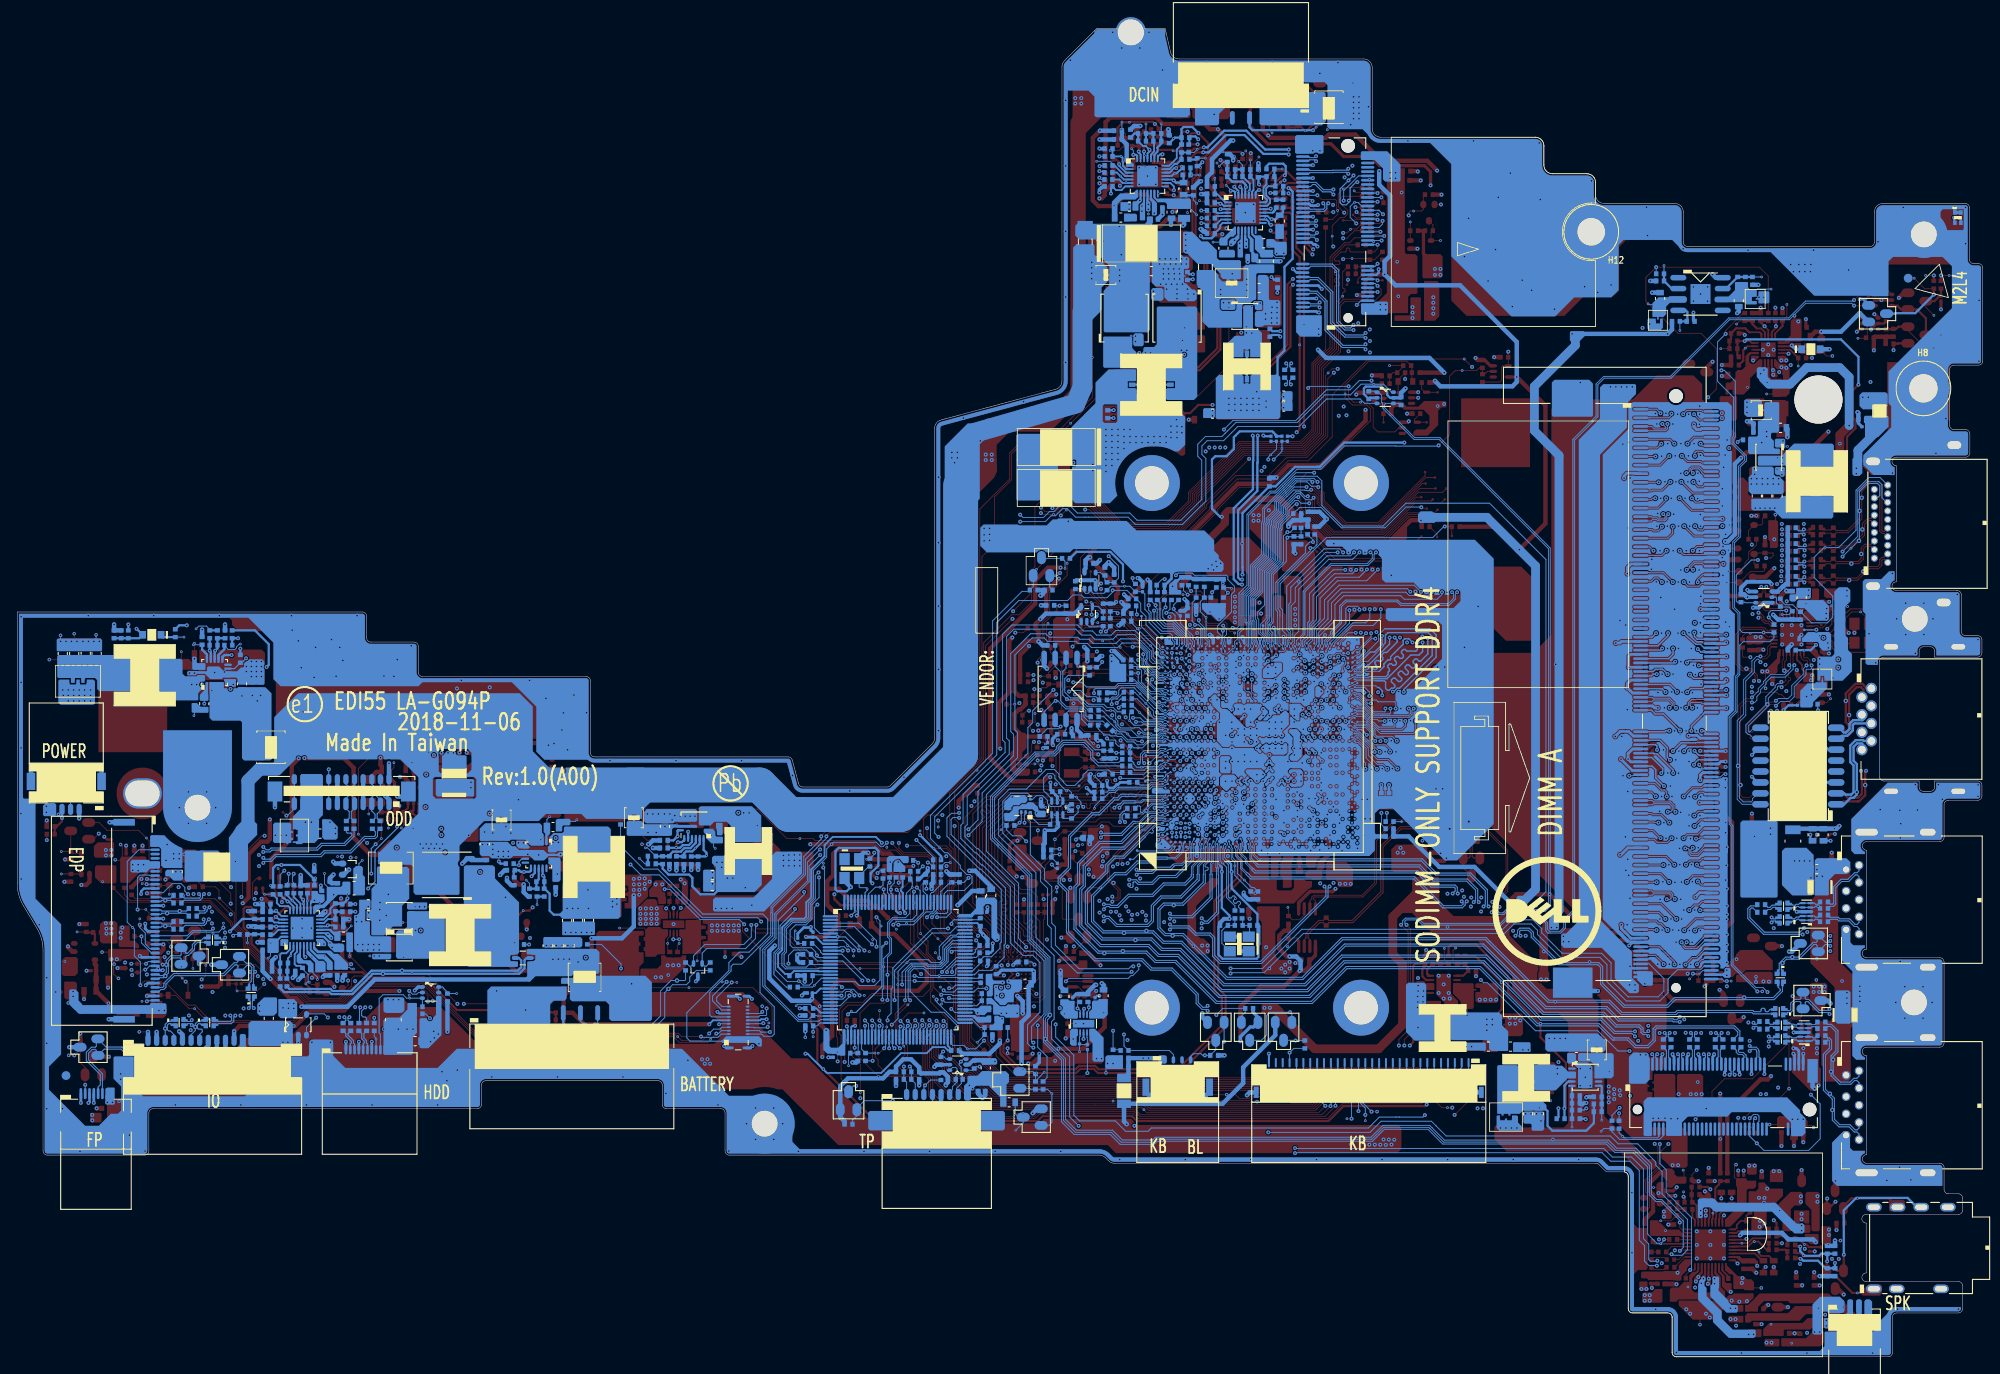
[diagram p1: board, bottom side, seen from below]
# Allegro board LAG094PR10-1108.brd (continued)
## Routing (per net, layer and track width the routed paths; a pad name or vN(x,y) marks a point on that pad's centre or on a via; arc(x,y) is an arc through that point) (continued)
SOC_DP1_N0: length 122.1
  TOP w0.114: v2(23.43,90.76) 23.42,90.76 23.2,90.54 22.59,90.54 CG28.1
  IN2 w0.127: v2(23.43,90.76) 23.42,90.76 23.58,90.61 23.97,90.61 24.55,91.19 26.28,91.19 29.04,88.43 29.04,42.94 29.94,42.03 41.79,42.03 44.85,45.1 49.65,45.1 50.85,46.3 55.92,46.3 61.05,51.42 61.05,53.83 v2(61.01,53.86)
  BOTTOM w0.089: UC1.AA3 85.98,59.68 85.98,59.52 86.07,59.39 86.08,59.37 86.08,59.12 86.22,58.91 86.22,58.62 85.52,57.92 85.52,57.48 84.89,56.85 84.84,56.8 84.79,56.8 84.72,56.73
  BOTTOM w0.114: 84.72,56.73 84.49,56.5 65.65,56.5 64,54.85 61.32,54.85 61.07,54.59 61.07,53.92 v2(61.01,53.86)
SOC_DP1_N1: length 118.8
  TOP w0.114: v2(23.36,92.57) 23.11,92.32 22.72,92.32 CG30.1
  IN2 w0.127: v2(23.36,92.57) 23.54,92.39 25.56,92.39 25.95,91.99 26.46,91.99 29.74,88.72 29.74,86.75 30.83,85.65 30.83,66.17 30.56,65.89 30.56,46.82 33.37,44 34.77,44 35.53,44.76 43.53,44.76 44.56,45.79 49.27,45.79 50.47,47 55.49,47 60.11,51.61 60.11,52.81 v2(59.97,52.95)
  BOTTOM w0.089: UC1.Y1 86.8,59.41 86.88,59.41 86.97,59.32 86.97,59.19 86.83,59.05 86.83,58.23 86.25,57.66 86.25,56.79 85.6,56.14 85.6,56.1 85.59,56.08
  BOTTOM w0.114: 85.59,56.08 85.07,55.56 66.11,55.56 62.75,52.2 60.48,52.2 60.15,52.53 60.15,52.77 v2(59.97,52.95)
SOC_DP1_N2: length 115.6
  TOP w0.114: v2(23.34,96.21) 23.19,96.06 22.72,96.06 CG32.1
  IN2 w0.127: v2(57.43,52.36) 57.51,52.28 57.51,51.37 54.52,48.39 49.93,48.39 49.93,48.39 49.89,48.39 48.88,47.38 33.03,47.38 31.95,48.46 31.95,65.32 32.23,65.59 32.23,86.22 31.13,87.32 31.13,89.3 27.79,92.63 27.79,94.98 26.62,96.14 23.4,96.14 v2(23.34,96.21)
  BOTTOM w0.089: 83.93,57.87 84.08,57.87 84.62,58.4 84.62,59.34 UC1.AD3
  BOTTOM w0.114: v2(57.43,52.36) 57.57,52.49 57.57,54.32 59.49,56.25 63.48,56.25 65.13,57.9 83.89,57.9 83.93,57.87
SOC_DP1_N3: length 115.9
  TOP w0.114: CG34.1 22.4,94.55 22.71,94.24 23.22,94.24 v2(23.34,94.36)
  IN2 w0.127: v2(23.34,94.36) 23.46,94.24 26.18,94.24 26.9,93.51 26.9,92.54 30.43,89.01 30.43,87.03 31.53,85.94 31.53,65.88 31.25,65.61 31.25,48.09 32.79,46.55 49.04,46.55 50.18,47.69 50.21,47.69 50.22,47.69 55.07,47.69 58.72,51.35 58.72,52.06 58.56,52.22 v2(58.56,52.87)
  BOTTOM w0.089: 84.24,57.27 84.25,57.29 84.3,57.29 84.97,57.96 84.97,58.98 85.16,59.18 85.16,59.39 85.08,59.52 85.08,59.68 UC1.AC3
  BOTTOM w0.114: 84.24,57.27 84.16,57.2 65.41,57.2 63.76,55.55 59.88,55.55 58.69,54.36 58.69,52.99 v2(58.56,52.87)
SOC_DP1_P0: length 122
  TOP w0.114: CG27.1 22.85,90.3 23.31,90.3 v2(23.42,90.18)
  IN2 w0.127: v2(23.42,90.18) 23.59,90.34 24.08,90.34 24.66,90.93 26.17,90.93 28.78,88.32 28.78,42.83 29.83,41.77 41.89,41.77 44.96,44.83 49.76,44.83 50.96,46.03 56.03,46.03 61.31,51.31 61.31,53.57 61.43,53.69 61.43,53.7 v2(61.59,53.86)
  BOTTOM w0.089: UC1.AA2 86.24,59.44 86.26,59.42 86.26,59.17 86.39,58.96 86.39,58.54 85.7,57.85 85.7,57.4 84.96,56.67 84.91,56.62 84.91,56.57 84.89,56.55
  BOTTOM w0.114: 84.89,56.55 84.6,56.26 65.76,56.26 64.11,54.61 61.43,54.61 61.31,54.49 61.31,54.15 v2(61.59,53.86)
SOC_DP1_P1: length 118.7
  TOP w0.114: v2(23.36,91.97) 23.36,91.98 23.27,92.07 22.72,92.07 CG29.1
  IN2 w0.127: v2(23.36,91.97) 23.36,91.98 23.5,92.12 25.45,92.12 25.85,91.73 26.35,91.73 29.47,88.61 29.47,86.64 30.57,85.54 30.57,66.28 30.29,66 30.29,46.71 33.26,43.74 34.88,43.74 35.64,44.5 43.64,44.5 44.67,45.53 49.38,45.53 50.58,46.73 55.6,46.73 60.37,51.5 60.37,52.77 v2(60.55,52.95)
  BOTTOM w0.089: 85.41,56.25 85.49,56.33 85.54,56.33 86.08,56.87 86.08,57.73 86.65,58.3 86.65,58.9 86.43,59.22 86.43,59.39 UC1.Y3
  BOTTOM w0.114: 85.41,56.25 84.96,55.8 66,55.8 62.65,52.45 60.58,52.45 60.39,52.63 60.39,52.8 v2(60.55,52.95)
SOC_DP1_P2: length 115.5
  TOP w0.114: v2(23.34,95.63) 23.34,95.69 23.21,95.82 22.73,95.82 22.6,95.69 22.59,95.69 CG31.1
  IN2 w0.127: v2(58.01,52.36) 57.77,52.12 57.77,51.26 54.63,48.13 50.04,48.13 50.03,48.12 50,48.12 48.99,47.11 32.93,47.11 31.68,48.35 31.68,65.43 31.96,65.7 31.96,86.12 30.86,87.21 30.86,89.19 27.53,92.52 27.53,94.87 26.51,95.88 23.6,95.88 23.51,95.79 23.5,95.79 v2(23.34,95.63)
  BOTTOM w0.089: UC1.AD1 84.79,59.21 84.79,58.33 84.15,57.69 84.02,57.69 84.01,57.67 83.93,57.67 83.9,57.65 83.79,57.65
  BOTTOM w0.114: v2(58.01,52.36) 57.81,52.56 57.81,54.22 59.6,56 63.58,56 65.24,57.65 83.79,57.65
SOC_DP1_P3: length 115.9
  TOP w0.114: v2(23.34,93.77) 23.12,93.99 22.73,93.99 CG33.1
  IN2 w0.127: v2(23.34,93.77) 23.55,93.98 26.07,93.98 26.64,93.4 26.64,92.43 30.17,88.9 30.17,86.93 31.27,85.83 31.27,65.99 30.99,65.72 30.99,47.98 32.68,46.29 49.15,46.29 50.29,47.43 50.32,47.43 50.33,47.43 55.18,47.43 58.98,51.24 58.98,52.17 58.83,52.33 58.83,52.54 59.15,52.86 v2(59.15,52.87)
  BOTTOM w0.089: UC1.AC2 85.34,59.1 85.15,58.91 85.15,57.89 84.43,57.16 84.43,57.12 84.41,57.1
  BOTTOM w0.114: 84.41,57.1 84.27,56.95 65.51,56.95 63.86,55.3 59.98,55.3 58.94,54.26 58.94,53.08 v2(59.15,52.87)
SOC_EMMC_PWR_EN#: length 98.4
  TOP w0.102: v2(112.75,85.8) 115.9,82.65 115.9,69.17 v1(116.87,68.19) 119.48,65.59 119.48,62.54 119.03,62.1 119.03,53.27 118.53,52.76 118.53,51.38 116.94,49.79 115.9,49.79 115.46,49.36 115.46,48.04 116.15,47.35 117.57,47.35 117.94,46.99 117.94,39.96 117.34,39.36 117.34,38.98 115.6,37.24 115.6,36.63 114.65,35.68 114.65,34.98 112.3,32.63 104.4,32.63 v2(104.05,32.99)
  IN1 w0.127: v2(112.75,85.8) 111.61,85.8 109.41,88 105.75,88 105.06,87.31 102.33,87.31 100.81,85.78 100.13,85.78 98.48,84.13 96.89,84.13 95.97,83.21 95.14,83.21 94.61,82.67 92.98,82.67 92.17,81.87 v2(92.17,81.59)
  BOTTOM w0.089: v2(92.17,81.59) 92.54,81.22 UC1.G51
  BOTTOM w0.102: RM31.1 v2(104.05,32.99)
SOC_EMMC_PWR_EN#_R: length 4.7
  BOTTOM w0.102: UM3.5 104.09,37.12 104.05,37.08 RM31.2 104.87,36.29 RM30.2 ; RM30.2 104.96,37.18 104.89,37.25 UM3.3 ; RM30.2 v1(104.96,35.47)
SOC_PLTRST#: length 18.5
  BOTTOM w0.102: RC50.1 105.4,89.3 UC2.1 104.38,88.9 104.24,88.76 103.99,88.76 103.86,88.9 103.86,89.18 UC2.2 103.54,89.11 103.54,88.96 103.35,88.77 102.13,88.77 RC49.1 101.43,89.47 101.43,89.47 101.3,89.59 v1(99.73,89.59) 99.11,89.59 RC48.1 CC8.1 97.37,88.68 97.37,86.9 96.87,86.41 96.87,85.39 95.56,84.08 94.37,84.08 94.14,83.85 94.14,83.35 93.95,83.16 93.95,82.64 UC1.D54
SOC_PWROK: length 79.5
  TOP w0.089: v2(96.82,69.01) 96.82,69.08
  TOP w0.102: v2(107.73,66.56) 107.69,66.59 107.69,70.9 107.31,71.28 107.31,71.28 107.07,71.52 107.07,71.52 107.03,71.56 107.03,72.37 107.06,72.4 DC2.2 105.52,72.54 105.28,72.78 RC57.1 104.89,72.78 104.61,72.5 104.02,72.5 CC9.1 103.13,72.4 101.5,72.4 98.53,69.43 97.17,69.43 96.82,69.08 ; v2(135.91,37.78) v1(135.91,37.22)
  IN1 w0.127: v2(108.75,48.51) 108.56,48.7 108.56,53.67 109.32,54.44 109.32,58.48 107.54,60.26 107.54,65.65 107.73,65.84 v2(107.73,66.56)
  IN2 w0.127: v2(108.75,48.51) 113.64,48.51 114.52,47.62 115.56,47.62 117.38,45.8 120.98,45.8 121.46,45.32 124.95,45.32 126.27,44 128.41,44 128.6,44.19 133.64,44.19 134.93,42.9 134.93,38.76 v2(135.91,37.78)
  BOTTOM w0.089: UC1.D25 93.85,69.46 94.46,69.46 94.71,69.72 94.71,69.87 94.88,70.04 95.08,70.04 95.59,69.72 96.11,69.72 v2(96.82,69.01)
  BOTTOM w0.102: v2(135.91,37.78) CE2.1 135.44,38.48 135.1,38.82 UE1.32
SOC_RTCTEST#: length 24.5
  TOP w0.102: QC10.1 105.04,56.47 104.69,56.82 CLRP2.2 105.32,57.41 105.74,57.83 RC65.2 105.74,58.51 v2(105.45,58.8) 104.9,58.8 104.66,58.56 104.64,58.56 CC11.2
  IN1 w0.127: v2(93.25,69.27) 94.37,69.27 95.64,68 96.77,68 97.57,67.2 97.57,65.28 99.93,62.92 102.83,62.92 104.7,61.04 104.7,59.3 105.21,58.8 v2(105.45,58.8)
  BOTTOM w0.102: UC1.F25 93.25,69.35 v2(93.25,69.27)
SOC_RTCX1: length 13.3
  TOP w0.102: v2(93.95,68.29) 94.21,68.56 95.36,68.56 v1(95.77,68.16) 101.24,68.16 101.3,68.22 101.6,68.22 101.94,68.56 RC67.1 103.75,68.56 103.79,68.52 CC13.1 104.72,68.52 105.41,67.83 105.69,67.83 105.7,67.83 YC2.1
  BOTTOM w0.089: UC1.D23 v2(93.95,68.29)
SOC_RTCX2: length 14.4
  TOP w0.102: v2(93.24,68.29) 93.39,68.29 93.86,68.77 95.62,68.77 96.03,68.36 101.16,68.36 101.22,68.42 101.42,68.42 v1(102.47,69.48) RC67.2 103.77,69.48 103.79,69.45 CC14.1 104.49,69.65 104.68,69.65 104.78,69.76 104.85,69.76 105.41,70.32 105.68,70.32 105.7,70.33 YC2.2
  BOTTOM w0.089: UC1.F23 v2(93.24,68.29)
SOC_SMBALERT#: length 2.1
  BOTTOM w0.102: UC1.A26 95.53,70.22 95.84,69.91 T8.1
SOC_SMBCLK: length 25.1
  IN1 w0.127: v2(98.08,69.02) 98.27,69.21 98.46,69.21 98.59,69.08 98.59,65.82 99.65,64.77 101.93,64.77 102.76,63.94 v2(104.53,63.94)
  BOTTOM w0.089: 97.89,70.05 97.46,70.48 95.86,70.48 95.6,70.73 95.06,70.73 UC1.B27
  BOTTOM w0.102: v2(98.08,69.02) 97.89,69.21 97.89,70.05 ; QC2.6 108.19,64.88 109.13,65.82 109.13,67.33 108.65,67.8 108.07,67.8 107.83,67.56 107.83,67.23 107.32,66.72 107.32,66.62 106.64,65.93 106.23,65.93 105.89,65.59 RC89.1 105.46,65.16 104.8,64.5 104.8,64.21 v2(104.53,63.94)
SOC_SMBDATA: length 20.1
  IN1 w0.127: v2(105.13,63.94) 104.62,64.45 102.97,64.45 102.14,65.27 99.86,65.27 99.09,66.04 99.09,69.29 98.67,69.72 97.95,69.72 97.44,69.2 v2(97.44,69.03)
  BOTTOM w0.089: UC1.C27 94.67,70.56 94.9,70.4 95.11,70.4 95.2,70.49 95.51,70.49 95.78,70.23 97.38,70.23
  BOTTOM w0.102: QC2.3 106.89,62.67 106.81,62.59 RC90.1 105.84,62.59 105.13,63.3 v2(105.13,63.94) ; v2(97.44,69.03) 97.63,69.22 97.63,69.97 97.38,70.23
SOC_SPI_CLK: length 4.5
  BOTTOM w0.089: UC1.B29 95.08,71.48 95.15,71.48 96.96,71.48 97.65,70.8 v1(98.17,70.8) 98.52,70.8
  BOTTOM w0.102: RC36.1 98.82,70.99 98.63,70.8 98.52,70.8
SOC_SPI_CLK_R: length 12.7
  IN2 w0.127: v2(101.77,71.9) 103.37,73.5 106.93,73.5 v2(107.16,73.27)
  BOTTOM w0.102: RC37.1 109.58,72.16 108.72,73.02 107.41,73.02 v2(107.16,73.27) 107.68,73.27 107.79,73.39 UC11.6 ; v2(101.77,71.9) 101.58,71.71 100.85,71.71 100.75,71.61 100.75,71.29 100.44,70.99 RC36.2
SOC_SPI_CS#0: length 19.9
  BOTTOM w0.089: UC1.C31 94.78,72.66 94.93,72.76 95.06,72.76 95.2,72.66 95.21,72.65 95.57,72.65 95.84,72.37 96.48,72.37 96.63,72.53 97.4,72.53 98.06,73.19 98.53,73.19
  BOTTOM w0.102: RC35.1 106.28,79.23 106.68,78.84 106.68,77.29 105.99,76.61 105.03,76.61 104.06,75.64 102.33,75.64 101.84,75.15 v1(101.35,75.15) 101.03,75.15 100.76,74.87 100.76,74.2 100.51,73.95 100.51,73.46 100.16,73.11 98.61,73.11 98.53,73.19
SOC_SPI_CS#0_R: length 4.3
  BOTTOM w0.102: UC11.1 105.25,80.28 105.12,80.15 RC35.2 103.75,80.18 RC30.1 102.85,80.18 102.33,80.7 v2(102.33,80.79)
SOC_SPI_IO2: length 8.6
  BOTTOM w0.089: UC1.A30 95.35,71.89 95.48,71.84 96.64,71.84 96.88,71.84 97.01,71.97 97.59,71.97 97.62,71.99 98.53,71.99
  BOTTOM w0.102: RC163.1 102.12,74.42 100.35,72.65 99.61,72.65 v1(99.38,72.42) 98.95,71.99 98.53,71.99
SOC_SPI_IO2_0_R: length 11.3
  BOTTOM w0.102: RC163.2 104.09,74.42 104.22,74.56 104.22,75.1 104.68,75.56 106.45,75.56 107.16,76.27 107.16,79.65 107.79,80.28 UC11.3 RC32.1
SOC_SPI_IO3: length 10
  BOTTOM w0.089: 98.53,71.38 98.31,71.15 97.54,71.15 97.03,71.66 95.34,71.66 95.06,71.86 94.93,71.86 94.78,71.76 UC1.C29
  BOTTOM w0.102: RC161.1 102.8,73.03 v1(102.08,72.31) 101.49,72.31 101.38,72.19 100.64,72.19 100.56,72.12 100.07,72.12 99.45,71.5 98.65,71.5 98.53,71.38
SOC_SPI_IO3_0_R: length 6.5
  BOTTOM w0.102: RC31.1 106.64,72.82 106.52,72.93 UC11.7 106.52,74.8 106.24,75.08 104.9,75.08 104.71,74.89 104.71,74.13 104.02,73.44 RC161.2
SOC_SPI_SI: length 8.4
  IN2 w0.127: v2(97.71,71.55) 98.07,71.91 v2(98.07,72.57)
  BOTTOM w0.089: v2(97.71,71.55) 98.27,71.55 98.44,71.73 98.53,71.73 ; v2(98.07,72.57) 97.69,72.57 97.45,72.32 96.74,72.32 96.62,72.2 95.77,72.2 95.5,72.46 95,72.46 UC1.B31
  BOTTOM w0.102: 98.53,71.73 99.35,71.73 100.05,72.42 100.77,72.42 RC162.1
SOC_SPI_SI_0_R: length 10.3
  BOTTOM w0.102: RC162.2 102.26,73.91 103.96,73.91 104.45,74.4 104.45,75.01 104.78,75.33 106.55,75.33 107.48,76.26 v2(107.73,76.26) 107.8,76.26 109.06,75 UC11.5
SOC_SPI_SO: length 9.8
  BOTTOM w0.089: 98.53,72.46 98.24,72.17 97.54,72.17 97.52,72.14 96.88,72.14 96.76,72.02 95.69,72.02 95.42,72.29 95.2,72.29 95.06,72.18 94.93,72.18 UC1.C30
  BOTTOM w0.102: RC164.1 102.33,75.18 101.33,74.18 101.2,74.18 v1(100.86,73.83) 100.74,73.71 100.74,73.36 100.26,72.88 98.95,72.88 98.53,72.46
SOC_SPI_SO_0_R: length 8.5
  BOTTOM w0.102: RC164.2 103.95,75.18 105.14,76.37 106.03,76.37 106.03,76.38 106.34,76.38 v2(106.42,76.46) 106.9,76.94 106.9,79.69 106.52,80.07 UC11.2
SOC_SPKR: length 158.7
  TOP w0.102: v2(52.42,52.41) v1(51.88,52.41) ; DA7.2 38.91,17.19 38.72,17.38 38.72,18.69 39.2,19.17 39.2,20.3 37.52,21.97 37.52,23.76 v2(36.53,24.75)
  IN1 w0.127: v2(36.53,24.75) 33.89,24.75 29.43,29.21 29.43,30.79 31.21,32.57 39.51,32.57 41.5,34.56 41.5,40.68 42.07,41.25 42.07,41.27 47.66,46.86 50.45,46.86 51.79,48.19 51.79,49.5 52.42,50.14 v2(52.42,52.41)
  BOTTOM w0.089: UC1.AA54 86.24,82.9 86.42,83.08 86.42,84.13 85.96,84.59 85.96,86.16
  BOTTOM w0.102: v2(52.42,52.41) 50.76,54.07 50.76,92.7 57.31,99.25 67.03,99.25 69.68,96.59 74.41,96.59 76.81,98.99 76.81,101.85 77.34,102.38 79.92,102.38 80.89,101.41 80.89,101.4 81.25,101.04 81.26,101.04 83.67,98.64 83.67,97.14 83.8,97.01 83.8,93.32 85.1,92.02 85.1,89.46 85.96,88.6 85.96,86.16
SOC_SRTCRST#: length 38
  TOP w0.102: QC1.1 106.87,50.88 106.97,50.99 106.97,54.92 107.35,55.3 108.93,55.3 109.44,55.82 109.44,56.26 108.94,56.76 108.94,57.15 107.84,58.24 107.84,60.14 v3(107.83,60.16) 106.89,61.1 RC66.2 104.64,61.1 CC12.2 104.38,60.23 104.48,60.13 v2(105.38,60.13)
  IN1 w0.127: v2(105.38,60.13) 105.38,61.08 103.04,63.42 100.14,63.42 98.08,65.49 98.08,67.41 96.98,68.51 95.94,68.51 94.28,70.18 v2(94.02,70.18)
  BOTTOM w0.102: v2(105.38,60.13) 105.38,60.19 105.25,60.32 CLRP1.2 ; v2(94.02,70.18) 94.02,70.17 UC1.D27
SOC_SVID_ALERT#: length 7.3
  BOTTOM w0.089: UC1.G54 92.56,83.67
  BOTTOM w0.102: 92.56,83.67 94.09,85.2 94.95,85.2 95.61,85.86 v1(95.61,86.93) 95.61,87.69 RC60.1
SOC_SVID_ALERT#_R: length 78.2
  IN1 w0.127: v2(95.06,90.41) 95,90.36 93.51,90.36 93.1,90.76 93.1,93.06 92.06,94.1 92.06,96.99 90.23,98.82 90.23,104.6 90.84,105.21 90.84,105.42 90.09,106.17 89.7,106.17 v2(89.25,105.72)
  IN2 w0.127: v2(102.65,137.85) 102.47,137.85 101.44,138.88 101.44,139.63 99.81,141.26 99.81,142.87 98.25,144.42 95.03,144.42 93.72,143.12 93.72,141.21 92.62,140.11 92.62,135.48 92.57,135.43 92.57,135.4 91.32,134.15 91.32,132.93 v2(90.79,132.39) 90.58,132.39 89.75,131.55 89.75,129.67 90.46,128.96 90.46,121.9 89.32,120.75 89.32,116.94 90.46,115.8 90.46,108.88 89.25,107.67 v2(89.25,105.72)
  BOTTOM w0.102: RC60.2 96,88.98 RC61.2 96,89.77 95.35,90.41 v2(95.06,90.41) ; PRG11.2 102.15,137.79 102.59,137.79 v2(102.65,137.85) ; PRZ13.2 v2(90.79,132.39)
SOC_SVID_CLK: length 84.6
  TOP w0.102: PRZ05.2 90.36,131.96 90.51,131.81 v2(90.81,131.81) ; PRG04.2 102.17,137.57 v2(102.65,137.09)
  IN1 w0.127: v2(96.3,86.75) 96.1,86.75 94.52,88.32 94.42,88.32 92.59,90.15 92.59,92.54 91.55,93.58 91.55,96.78 89.72,98.6 89.72,105.34 89.89,105.5 v2(89.89,105.72)
  IN2 w0.127: v2(102.65,137.09) 102.45,137.09 100.94,138.6 100.94,139.42 99.3,141.05 99.3,142.66 98.04,143.91 95.24,143.91 94.23,142.9 94.23,141 93.13,139.9 93.13,135.27 93.07,135.22 93.07,135.19 91.86,133.97 91.86,132.7 90.97,131.81 v2(90.81,131.81) 90.36,131.35 90.36,129.82 90.97,129.22 90.97,121.68 89.82,120.54 89.82,117.15 90.97,116.01 90.97,108.67 89.89,107.59 v2(89.89,105.72)
  BOTTOM w0.089: 93.67,84.24 93.05,83.62 UC1.F55
  BOTTOM w0.102: v2(102.65,137.09) 102.62,137.09 102.42,136.89 PRG09.2 ; PRZ11.2 90.46,131.81 v2(90.81,131.81) ; 93.67,84.24 94.12,84.69 95.23,84.69 96.3,85.76 v2(96.3,86.75)
SOC_SVID_DAT: length 87.6
  TOP w0.102: PRZ06.2 90.38,132.85 v2(90.81,133.28) ; v2(102.62,138.44) 102.62,138.43 101.96,138.43 PRG05.2
  IN1 w0.127: v2(88.62,105.72) 89.22,105.12 89.22,98.39 91.04,96.57 91.04,93.37 92.08,92.33 92.08,89.94 92.36,89.67 94.21,87.82 94.28,87.82 v2(94.97,87.13)
  IN2 w0.127: v2(102.62,138.44) 101.95,139.11 101.95,139.84 100.31,141.48 100.31,143.08 98.46,144.93 95.51,144.93 94.82,144.93 93.21,143.33 93.21,142.9 93.21,141.42 92.11,140.32 92.11,139.9 92.11,135.69 90.81,134.4 v2(90.81,133.28) 90.5,133.28 90.04,132.82 90.04,132.82 89.24,132.03 89.24,129.46 89.95,128.75 89.95,122.11 88.81,120.96 88.81,115.76 89.95,114.61 89.95,109.09 88.62,107.75 v2(88.62,105.72)
  BOTTOM w0.089: UC1.G53 92.56,82.24 92.3,82.5 92.3,82.74 92.36,82.81 92.36,82.82 92.37,82.83 92.37,83.75
  BOTTOM w0.102: PRZ14.2 v2(90.81,133.28) ; RC59.2 94.97,87.87 v2(94.97,87.13) 95.28,86.81 95.28,85.97 94.79,85.48 94.1,85.48 92.37,83.75 ; PRG12.2 102.54,138.51 102.62,138.43 v2(102.62,138.44)
SOC_THERMTRIP#: length 3.8
  BOTTOM w0.102: RE11.1 127.8,54.86 128.05,54.61 v1(128.15,54.61) 128.68,54.61 129.48,53.8 UE1.121
SOC_XTAL19_IN: length 3
  BOTTOM w0.102: RC71.2 86,50.9 RC68.1 CC16.2 85.2,48.95 YC1.1
SOC_XTAL19_OUT: length 5.4
  BOTTOM w0.102: RC72.2 86.91,50.96 RC68.2 CC17.2 87.82,50.16 88.43,49.55 88.43,48.08 YC1.3
SPI_0_FS0_GPIO_80: length 18.4
  TOP w0.102: v1(97.13,73.46) 97.18,73.41 98.66,73.41 v2(99.6,74.35) 100.31,75.06 102.71,75.06 103.59,75.94 103.7,75.94 RC107.2
  IN1 w0.127: v2(91.1,75.43) 91.8,74.73 92.83,74.73 93.16,75.07 94.95,75.07 95.54,74.48 96.17,74.48 96.94,75.24 98.74,75.24 99.6,74.38 v2(99.6,74.35)
  BOTTOM w0.089: v2(91.1,75.43) UC1.L37
SPI_0_FS1_GPIO_81: length 31.2
  TOP w0.102: v2(109.23,78.38) 109.84,78.99 109.84,79.55 109.38,80.01 v1(109.38,81.02) 109.09,81.32 109.09,85.28 107.88,86.48 RC151.2 107.62,86.99 v2(107.29,87.32)
  IN1 w0.127: v2(91.89,76.39) 91.89,76.28 92.32,75.85 93.21,75.85 93.66,76.3 94.64,76.3 95.68,77.34 99.79,77.34 100.28,77.83 105.69,77.83 106.11,78.25 109.1,78.25 v2(109.23,78.38)
  BOTTOM w0.089: UC1.J39 91.52,75.91 91.62,76.01 91.92,76.31 91.92,76.39 v2(91.89,76.39)
  BOTTOM w0.102: RC102.1 107.86,87.32 v2(107.29,87.32) 106.53,87.32 RC101.1
SPI_0_FS1_GPIO_81_R: length 1.1
  TOP w0.102: RC151.1 106.7,86.91 106.71,86.93 T52.1
SPI_0_TX_GPIO_83: length 22
  TOP w0.102: RC106.1 110.31,76.84 ; 110.31,76.84 RC105.1 ; 110.31,76.84 110.21,76.94 v2(110.21,77.63)
  IN1 w0.127: v2(110.21,77.63) 109.88,77.96 106.18,77.96 105.8,77.58 100.39,77.58 99.83,77.02 95.79,77.02 94.82,76.05 93.76,76.05 92.73,75.01 92.23,75.01 v2(91.81,75.43)
  BOTTOM w0.089: v2(91.81,75.43) UC1.J37
SPI_2_CLK_GPIO_84: length 27.4
  TOP w0.102: v2(109.81,73.5) 110.13,73.82 v1(110.13,74.8) 110.13,75.43 110.33,75.64 RC104.1 RC103.1
  IN1 w0.127: v2(90.39,75.43) 90.39,73.98 90.9,73.46 95.52,73.46 97.04,74.99 98.64,74.99 99.16,74.46 99.16,73.59 99.67,73.08 100.43,73.08 101.04,73.69 109.63,73.69 v2(109.81,73.5)
  BOTTOM w0.089: v2(90.39,75.43) UC1.M37
SSD_SCP#: length 155.2
  TOP w0.102: v2(130.43,30.06) v1(130.43,30.73) 130.43,34 131.54,35.11 131.54,36.44 130.46,37.52 130.46,39.94 129.28,41.12 127.64,41.12 v2(127.29,41.47)
  IN1 w0.127: v2(111.16,59.94) 110.46,59.24 110.46,52.7 112.43,50.73 116.79,50.73 119.28,48.25 121.47,48.25 124.17,45.55 125.04,45.55 125.88,44.71 126.98,44.71 v2(127.28,44.42) ; v2(42.26,28.32) 43.46,28.32 44.58,27.2 47.66,27.2 48.29,27.82 60.31,27.82 61.04,28.55 65.02,28.55 66.76,26.81 71.59,26.81 72.5,25.89 79.83,25.89 81.62,25.89 82.46,26.73 96.81,26.73 97.93,27.85 108.54,27.85 110.27,26.12 127.95,26.12 130.4,28.57 130.4,30.03 v2(130.43,30.06)
  BOTTOM w0.102: UE1.107 123.88,51.38 124.42,50.84 126.61,50.84 127.08,50.38 127.08,48.9 126.81,48.63 126.81,46.93 127.28,46.46 v2(127.28,44.42) 127.28,41.49 v2(127.29,41.47) ; R300.2 v2(42.26,28.32) ; RS64.1 113.45,61.27 112.75,60.57 111.79,60.57 v2(111.16,59.94)
SUS_STAT#: length 16.3
  TOP w0.102: T5.1 103.67,88.91 101.62,86.86 100.12,86.86 98.29,85.03 97.34,85.03 94.54,82.23 93.62,82.23 v2(93.19,81.8)
  BOTTOM w0.089: UC1.E52 v2(93.19,81.8)
SUSCLK: length 135.4
  TOP w0.102: v2(93.09,81.19) 92.68,81.59 92.68,82.04 93.44,82.8 94.52,82.8 95.35,83.62 v2(95.41,83.62)
  IN2 w0.127: v2(101.1,89.11) 101.1,90.79 99.22,92.67 97.88,92.67 97.64,92.91 95.35,92.91 93.96,92.91 90.14,96.73 83.96,96.73 82.46,98.23 82.46,98.67 80.96,100.16 78.47,102.65 78.47,102.85 77.69,103.63 77.25,103.63 74.33,106.55 74.33,108.28 71.82,110.79 71.82,112.06 71.82,112.06 71.82,112.27 72.23,112.69 72.23,113.15 72.23,115.76 73.15,116.68 73.15,117.13 74.64,118.61 74.64,120.72 74.65,120.72 74.58,121.05 74.52,121.21 74.42,121.35 74.39,121.38 74.39,121.66 73.31,122.74 73.31,122.75 73.17,122.89 73.17,123.91 72.55,124.53 72.55,124.95 72.55,125.17 72.55,125.54 72.55,125.96 72.55,126.17 72.68,126.3 72.68,131.65 v2(72.8,131.77) ; v2(121.34,60.45) 123.29,58.5 128.71,58.5 v2(128.81,58.61)
  BOTTOM w0.089: UC1.G49 v2(93.09,81.19)
  BOTTOM w0.102: JWLAN1.50 72.18,133.8 72.58,134.2 73.06,134.2 73.5,133.75 73.5,132.48 v2(72.8,131.77) ; RE31.1 128.81,58.43 v2(128.81,58.61) ; v2(121.34,60.45) 121.79,60.89 121.79,62.77 114.58,69.98 114.58,85.37 112,87.94 106.33,87.94 105.7,88.58 104.75,88.58 104.43,88.26 101.76,88.26 101.1,88.92 v2(101.1,89.11) 99.45,89.11 98.47,88.13 RC58.1 97.85,87.6 97.85,86.7 97.24,86.09 97.24,85.14 95.73,83.62 v2(95.41,83.62)
SUSP#: length 256.4
  TOP w0.102: v2(153.17,54.36) 152.97,54.36 R926.1 R927.2 ; v2(138.78,45.72) 140.37,45.72 144.12,49.46 144.12,50.1 v2(143.93,50.29) ; v2(29.88,118.93) 29.88,119.31 27.83,121.36 PRM09.1 ; v2(26.2,42.48) v3(25.62,42.48)
  IN1 w0.127: v2(107.73,38.65) 108.64,39.56 110.4,39.56 111.29,40.44 115.54,40.44 117.06,41.97 117.06,43.94 118.95,45.82 120.68,45.82 123.39,43.11 124.77,43.11 125.35,43.7 125.81,43.7 126.27,43.24 129.69,43.24 v2(130.19,43.75) ; v2(64.83,28.1) 62.39,28.1 61.6,27.31 48.5,27.31 47.87,26.69 41.66,26.69 40.99,27.36 v2(40.99,30.35)
  IN2 w0.127: v2(40.99,30.35) 38.9,30.35 38.32,29.78 27.59,29.78 26.13,31.24 24.74,31.24 23.4,32.57 23.4,37.84 24.55,38.98 24.55,40.83 v2(26.2,42.48)
  BOTTOM w0.102: v2(153.17,54.36) 152.57,54.36 149.06,50.85 144.48,50.85 v2(143.93,50.29) ; v2(64.83,28.1) 65.06,27.87 67.79,27.87 70.12,27.87 71.39,26.6 96.62,26.6 97,26.22 99.6,26.22 100.81,27.43 104.95,27.43 105.62,28.1 105.62,35.07 107.73,37.18 v2(107.73,38.65) ; v2(29.88,118.93) 30.82,117.99 30.82,113.41 28.96,111.55 28.96,107.04 29.13,106.87 29.13,106.14 27.69,104.7 27.69,104.23 28.39,103.53 28.39,95.4 29.05,94.74 29.05,87.05 28.44,86.44 28.44,79.4 28.76,79.08 28.76,75.07 29.47,74.35 29.47,61.93 29.23,61.68 29.23,45.51 v2(26.2,42.48) ; v2(138.78,45.72) 138.78,46.67 138.15,47.3 136.67,47.3 DE1.2 135.89,46.52 135.89,46.5 135.65,46.26 135.63,46.26 135.38,46.02 UE1.14 132.46,46.02 v2(130.19,43.75)
SUSPWRDNACK#: length 91.6
  IN1 w0.127: v2(96.11,87.38) 96.93,88.2 98.57,88.2 100.09,89.72 101.21,89.72 102.08,88.86 103.18,88.86 103.85,89.52 107.87,89.52 108.55,90.2 111.99,90.2 118.65,83.55 118.65,68.03 124.58,62.1 124.58,59.26 125.3,58.54 126.59,58.54 127.67,58.54 129.45,56.76 129.45,54.73 130.27,53.91 132.05,53.91 132.58,54.44 134.64,54.44 135.63,54.44 136.56,54.44 v2(136.96,54.05)
  BOTTOM w0.089: 93.57,84.41 92.76,83.6 92.76,82.8 93.11,82.44 UC1.F54
  BOTTOM w0.102: RC46.1 96.13,87.38 v2(96.11,87.38) 96.11,87.12 95.93,86.94 95.93,86.53 95.94,86.52 95.94,85.81 95.08,84.95 94.11,84.95 93.57,84.41 ; RE7.1 139.04,42.98 140.47,44.42 140.47,44.72 140.47,46.98 139.96,47.49 139.96,50.76 136.96,53.76 v2(136.96,54.05)
SWTRAP: length 3
  BOTTOM w0.102: UE1.70 116.9,40.82 RE27.2 RE28.1
SYSON: length 244.8
  TOP w0.102: v2(119.84,50.34) 118.75,49.26 118.75,39.5 118.16,38.9 118.16,36.49 113.69,32.02 79.89,32.02 78.73,33.18 73.95,33.18 65.61,33.18 65.35,32.93 65.02,32.93 61.16,32.93 v3(60.61,32.38) v2(60.04,31.81) ; v2(31.91,111.56) 30.96,112.52 30.96,117.22 32.74,118.99 35.4,118.99 39.15,122.74 39.15,125.5 v2(37.96,126.69) 25.95,126.69 24.93,125.66 PRM08.1
  IN1 w0.127: v2(31.91,111.56) 30.64,111.56 29.82,110.74 29.82,108.31 27.91,106.4 27.91,105.34 28.55,104.7 28.55,104.33 28.61,104.27 28.61,104.09 28.64,104.06 28.64,102.11 28.48,101.95 28.48,90.57 29.31,89.75 29.31,88.49 27.43,86.61 27.43,80.7 27.44,80.69 27.44,75.39 26.58,74.52 26.58,72.89 26.37,72.69 26.37,47.92 23.28,44.83 23.28,31.81 v2(23.78,31.3)
  IN2 w0.127: v2(23.78,31.3) 24.1,30.98 26.01,30.98 27.59,29.4 38.45,29.4 38.96,29.9 42.24,29.9 43.04,29.1 43.87,29.1 45.63,30.86 48.8,30.86 50.2,29.46 56.61,29.46 57.5,30.35 57.63,30.35 59.09,31.81 v2(60.04,31.81)
  BOTTOM w0.102: v2(119.84,50.34) 119.84,50.52 119.54,50.82 UE1.95 116.67,50.82 CE18.1 ; PR2501.1 v2(37.96,126.69)
T_CRIT#: length 3
  TOP w0.102: U2.4 79.49,48.47 79.72,48.7 80.61,48.7 R29.2 80.68,47.81 v1(80.81,47.68)
THM_SML1_CLK: length 116.4
  TOP w0.102: v2(56.74,52.3) 56.55,52.5 56.55,53.05 55.41,54.19 55.41,58.84 58.79,62.23 v4(59.72,62.23) 68.23,62.23 70.46,60 70.46,55.05 72.04,53.46 77.66,53.46 77.77,53.36 77.77,53.22 77.54,52.99 U2.8
  BOTTOM w0.102: v2(56.74,52.3) 56.55,52.11 56.55,51.69 56.28,51.42 55.68,51.42 55.3,51.8 50.85,51.8 50.26,52.38 50.26,94.04 63.09,106.87 66.01,106.87 69.55,110.41 69.55,110.7 69.4,110.85 Q11.4 67.79,110.85 R49.2
THM_SML1_DATA: length 117.2
  TOP w0.102: U2.7 78.19,52.99 77.97,53.22 77.97,53.44 77.75,53.67 72.13,53.67 70.66,55.13 70.66,60.09 68.32,62.43 60.03,62.43 60.01,62.45 59.44,62.45 59.42,62.43 58.71,62.43 55.2,58.92 55.2,54.11 56.35,52.97 56.35,52.49 v2(56.16,52.3)
  BOTTOM w0.102: v2(56.16,52.3) 56.35,52.11 56.35,51.77 56.2,51.62 55.76,51.62 55.38,52 50.93,52 50.47,52.47 50.47,93.95 63.17,106.66 66.09,106.66 69.76,110.32 69.76,110.88 69.86,110.99 69.86,111.79 70.22,112.15 Q11.1 70.51,112.28 R48.2
TON_1.2V: length 2
  TOP w0.203: 24.04,119.63 24.53,119.14 PUM01.9
  TOP w0.254: PRM07.2 24.04,120.38 v2(24.04,119.82) 24.04,119.63
TOUCH_PANEL_PD#: length 26.1
  IN1 w0.127: v2(91.1,70.2) 91.1,69.15 91.36,68.89 94.44,68.89 95.32,68.02 95.32,67.75 96.08,66.99 96.17,66.99 97.32,65.84 97.32,65.17 99.83,62.66 102.72,62.66 104.45,60.93 104.45,59.2 105.42,58.22 107.09,58.22 v2(107.28,58.42)
  BOTTOM w0.089: UC1.L27 90.75,70.56 v2(91.1,70.2)
  BOTTOM w0.102: RC1147.1 108.24,58.07 RC1146.2 107.92,58.42 v2(107.28,58.42)
TOUCH_SCREEN_INT#: length 159.5
  TOP w0.102: v2(205.65,49.78) v1(205.65,49.21) ; v2(110.31,79.27) 110.35,79.31 RC203.2
  IN1 w0.127: v2(92.57,77.26) 93.02,76.81 94.43,76.81 95.47,77.85 99.58,77.85 100.07,78.34 104.65,78.34 105.91,79.6 108.01,79.6 108.28,79.33 110.25,79.33 v2(110.31,79.27) 111.17,79.27 113.76,76.68 113.76,71.45 113.75,71.44 113.75,66.51 114.48,65.79 114.48,65.42 116.68,63.21 116.68,58.55 120.88,54.35 120.89,54.35 121.8,53.44 122.75,53.44 124.12,52.06 124.12,50.8 125.7,49.23 127.56,49.23 127.65,49.14 132.58,49.14 133.66,50.22 135.33,50.22 136.03,49.53 140.22,49.53 142.67,47.07 147.71,47.07 148.47,46.31 153.62,46.31 154.53,45.4 155.89,45.4 156.82,46.33 159.63,46.33 161.01,44.95 166.26,44.95 167.74,46.43 167.74,50.03 168.33,50.62 168.89,50.62 170.44,52.17 172.16,52.17 173.93,53.94 177.9,53.94 178.21,53.94 178.65,53.94 178.8,54.1 178.91,54.2 182.49,54.2 183.55,55.27 187.76,55.27 188.75,54.28 193.2,54.28 193.97,55.05 201.5,55.05 202.31,54.24 203.34,54.24 205.35,52.23 205.35,50.08 v2(205.65,49.78)
  BOTTOM w0.089: v2(92.57,77.26) UC1.H41
  BOTTOM w0.102: v2(205.65,49.78) 205.85,49.58 208.01,49.58 208.64,48.95 JEDP1.24
TOUCH_SCREEN_PD#: length 135
  TOP w0.102: v2(180.69,41.31) 180.69,41.96 181.76,43.04 188.2,43.04 190.58,40.66 194.45,40.66 196.24,38.87 206.19,38.87 v1(207.79,40.47) 207.83,40.51 208.45,40.51 209.98,42.03 D5.2 210.94,42.05 R19.2
  IN1 w0.127: v2(180.69,41.31) 180.32,40.94 179.88,40.94 178.6,42.22 175.97,42.22 174.64,40.89 145.75,40.89 145.03,40.17 143.52,40.17 141.59,42.1 140.16,42.1 137.37,44.89 132.26,44.89 131.53,44.17 128.73,44.17 128.05,43.49 126.38,43.49 125.92,43.95 125.44,43.95 124.67,44.71 123.92,44.71 121.55,47.08 120.41,47.08 120,46.67 119.61,46.67 118.91,47.37 118.91,47.54 116.48,49.97 112.85,49.97 112.11,49.23 112.11,45.01 110.96,43.86 108.78,43.86 108.05,44.59 108.05,49.14 107.37,49.83 107.37,53.4 108.81,54.85 108.81,56.6 v2(108.17,57.24)
  BOTTOM w0.102: RC1147.2 107.76,56.79 108.17,57.21 v2(108.17,57.24)
TOUCH_SCREEN_RST: length 159.8
  TOP w0.102: v2(204.44,49.91) v1(204.44,50.41) ; v2(110.3,78.68) 110.5,78.48 RC117.2
  IN1 w0.127: v2(204.44,49.91) 204.69,50.16 204.69,52.53 203.24,53.99 202.2,53.99 201.39,54.8 194.08,54.8 193.3,54.02 188.64,54.02 187.65,55.01 183.66,55.01 182.59,53.94 179.01,53.94 178.91,53.84 178.76,53.69 178.32,53.69 178.15,53.69 174.04,53.69 172.26,51.91 170.55,51.91 169,50.36 168.43,50.36 167.99,49.92 167.99,46.33 166.36,44.7 160.9,44.7 159.52,46.08 156.93,46.08 156,45.14 154.42,45.14 153.51,46.06 148.75,46.06 148.54,45.84 143.54,45.84 140.12,49.27 135.92,49.27 135.23,49.97 133.77,49.97 132.69,48.89 127.54,48.89 127.46,48.98 125.59,48.98 123.87,50.7 123.87,51.95 122.64,53.18 121.69,53.18 121.52,53.36 116.43,58.45 116.43,63.11 114.22,65.32 114.22,65.68 113.5,66.41 113.5,76.59 111.4,78.68 v2(110.3,78.68) 109.91,79.07 108.17,79.07 107.9,79.35 106.02,79.35 104.76,78.08 100.18,78.08 99.69,77.59 95.57,77.59 94.53,76.55 93.32,76.55 v2(93.1,76.34)
  BOTTOM w0.089: UC1.F39 92.88,76.1 93.08,76.3 93.08,76.34 v2(93.1,76.34)
  BOTTOM w0.102: v2(204.44,49.91) 204.97,49.38 207.93,49.38 208.86,48.45 JEDP1.25
TP_CLK: length 24.6
  TOP w0.102: v2(125.37,33.75) 125.37,34.55 124.94,34.98 124.94,36.14 126.17,37.37 126.17,39.66 v1(124.91,40.92) 124.65,41.18 v2(124.65,41.46)
  BOTTOM w0.102: UE1.87 119.87,47.62 120.23,47.25 120.23,45.93 121.02,45.14 122.77,45.14 122.99,45.36 124.34,45.36 124.88,44.82 124.88,41.69 v2(124.65,41.46) ; JTP1.1 125.05,31.93 C27.1 R32.2 v2(125.37,33.75)
TP_DAT: length 26.5
  TOP w0.102: v2(124.68,33.75) 125.1,33.33 125.57,33.33 125.83,33.59 125.83,34.54 125.26,35.11 125.26,35.99 v1(125.38,36.12) 126.37,37.11 126.37,39.9 125.23,41.04 v2(125.23,41.46)
  BOTTOM w0.102: JTP1.2 124.05,31.8 C26.1 R31.2 124.51,33.57 v2(124.68,33.75) ; UE1.88 119.75,48.02 120.43,47.34 120.43,46.02 121.09,45.36 122.57,45.36 122.77,45.56 124.42,45.56 125.17,44.82 125.17,41.52 v2(125.23,41.46)
TP_EN#: length 25.8
  TOP w0.102: v1(121.07,45.78) 120.81,45.78 v2(119.77,44.74)
  IN1 w0.127: v2(119.77,44.74) 119.2,44.74 117.89,43.43 117.89,40.06 116.11,38.29 110.07,38.29 v2(109.82,38.54)
  BOTTOM w0.102: UE1.82 119.39,45.62 119.77,45.23 v2(119.77,44.74) ; v2(109.82,38.54) 109.82,36 108.73,34.91 108.73,32.47 R38.1
TS_EN: length 3.2
  TOP w0.102: v1(213.9,41.33) v2(213.33,41.33) 212.84,41.33 C16.1 R19.1
  BOTTOM w0.102: JEDP1.39 213.21,41.45 v2(213.33,41.33)
TSEN_VCCGI: length 15.3
  TOP w0.254: v2(93.99,135.64) 94.32,135.64 PRG27.1
  IN1 w0.254: v2(93.99,135.64) 93.89,135.54 93.81,135.54 93.53,135.26 93.53,135.19 93.13,134.78 93.13,133.36 91.55,131.78 91.55,128.96 91.09,128.5 91.09,125.81 91.63,125.28 v2(91.79,125.28)
  BOTTOM w0.102: PHZ2.1 92.35,125.28
  BOTTOM w0.203: PUG1.16 94.4,136.48 93.99,136.08 v2(93.99,135.64)
  BOTTOM w0.254: 92.35,125.28 v2(91.79,125.28)
TSEN_VNN: length 9.8
  TOP w0.254: PRZ30.1 v2(82.71,131.61)
  IN1 w0.254: v2(82.65,125.53) 82.46,125.73 82.46,126.55 83.22,127.31 83.22,128.28 83.4,128.46 83.4,131.05 82.84,131.61 v2(82.71,131.61)
  BOTTOM w0.203: PUZ1.16 83.23,132.23 82.97,131.97 82.97,131.77 82.81,131.61 v2(82.71,131.61)
  BOTTOM w0.254: v2(82.65,125.53) 82.34,125.23 PHG2.1
UART_1_CTXD_GPIO_61: length 7.5
  BOTTOM w0.089: 90.15,83.57 89.85,83.27 UC1.N54
  BOTTOM w0.102: RC95.1 RC96.1 90.93,87.8 90.93,86.63 v1(90.25,85.96) 90.25,83.68 90.15,83.57
UART_2_CRTS#_GPIO_66: length 5.5
  BOTTOM w0.089: UC1.K53 91.07,82.45 91.07,82.69 90.92,82.84 90.92,84.49 91.1,84.67 v1(91.86,84.67) 92.29,84.67
  BOTTOM w0.102: RC91.2 92.64,85.94 92.64,85.02 92.29,84.67
UART_2_CRXD_GPIO_64: length 54.2
  TOP w0.102: T41.1 73.77,124.76 v2(73.77,125.22) RW10.2
  IN1 w0.127: v2(73.77,125.22) 75.66,123.33 75.66,117.24 77.44,115.46 77.44,111.14 82.73,105.85 82.9,105.85 83.11,105.85 83.32,105.85 83.92,105.85 84.13,105.85 84.34,105.85 84.99,105.85 85.42,105.85 86.2,105.85 87.82,104.24 87.82,99.63 87.57,99.39 87.57,97.73 87.57,97.52 90.01,95.08 90.01,92.83 90.81,92.04 90.81,87.28 90.9,87.18 90.9,86.14 91.1,85.94 v2(91.1,85.66)
  BOTTOM w0.089: UC1.M53 90.3,82.55 90.04,82.81 90.04,83.14 90.47,83.57
  BOTTOM w0.102: v2(91.1,85.66) 91.1,85.44 90.47,84.8 90.47,83.57
UART_2_CTXD_GPIO_65: length 65
  TOP w0.102: RC148.2 70.67,127.55 RW9.2 71.36,127.69 v1(73.3,127.69) 74.27,127.69 v2(74.33,127.63)
  IN1 w0.127: v2(74.33,127.63) 74.33,126.04 75.92,124.46 75.92,117.34 77.69,115.57 77.69,111.25 82.84,106.1 83.01,106.1 84.02,106.1 84.89,106.1 85.52,106.1 86.31,106.1 88.12,104.29 88.12,99.58 87.82,99.28 87.82,97.63 90.28,95.17 90.28,93.01 91.09,92.2 91.09,87.35 91.83,86.61 91.83,85.7 91.55,85.42 v2(91.55,85.1)
  BOTTOM w0.089: UC1.L54 90.71,82.66 90.71,83.66
  BOTTOM w0.102: RC109.2 RC108.2 91.41,88.14 91.87,87.69 91.87,85.54 91.55,85.23 v2(91.55,85.1) 91.12,85.1 90.71,84.69 90.71,83.66
UART_2_CTXD_GPIO_65_R: length 1
  TOP w0.102: RC148.1 69.76,126.61 T40.1
UG_1.2V: length 7.5
  TOP w0.102: v2(23.21,105.85) v1(22.7,105.85)
  IN2 w0.762: 24.29,107.82 25.31,108.83 25.31,113.6 24.74,114.17
  vias: v2(23.21,106.48) v2(24.38,114.73) v2(24.35,114.17)
UG_CHG: length 10.7
  TOP w0.102: v2(181.64,52.32) v1(182.15,52.32)
  IN2 w0.762: 191.5,49.56 191.4,49.67 184.67,49.67 182.3,52.03
  vias: v2(181.06,52.32) v2(191.91,48.7) v2(192.29,49.13)
UG_VCCGI:
  vias: v2(97.95,134.45)
UG_VCCGI_R: length 14
  TOP w0.102: v2(98.46,118.68) v1(98.97,118.68)
  IN2 w1.016: 99,119.28 99,121.76 99.41,122.17 99.41,132.61 99.4,132.62
  vias: v2(98.46,118.04) v2(99.2,134.02) v2(99.2,133.43)
UG_VNN: length 6.2
  TOP w0.102: v2(87.6,122.55) v1(87.6,121.98)
  IN2 w0.762: 87.4,128.65 87.73,128.32 87.73,123.12
  vias: v2(86.94,129.81) v2(87.35,129.36) v2(88.24,122.55)
USB2_ID: length 6.2
  BOTTOM w0.089: UC1.V1 87.6,59.28 87.33,59.01 87.33,57.89 87.16,57.72
  BOTTOM w0.102: RC76.1 86.91,55.96 v1(86.91,57.08) 86.91,57.48 87.16,57.72
USB2_RCOMP: length 2
  TOP w0.089: v2(88.34,63.37) 88.62,63.37 v1(88.81,63.18)
  TOP w0.254: RC77.1 87.99,63.37 v2(88.34,63.37)
  BOTTOM w0.254: UC1.U12 87.91,63.75 v2(88.34,63.37)
USB2_VBUSSENSE: length 7.4
  BOTTOM w0.089: 86.47,56.08 86.59,56.2 86.59,57.47 87.16,58.03 87.16,59.09 87.28,59.22 87.28,59.37 87.51,59.6 87.51,59.84 UC1.V3
  BOTTOM w0.102: RC75.1 84.69,54.57 84.96,54.57 v1(85.82,55.43) 86.47,56.08
USB3_CRX_DTX_N0: length 144.7
  IN2 w0.089: 97.25,64.68 97.17,64.6 94.25,64.6 v2(93.95,64.9)
  IN2 w0.127: v2(24.54,50.5) 24.92,50.5 25.04,50.38 25.04,48.56 22.83,46.34 22.83,39.61 21.3,38.08 21.3,31.37 23.48,29.2 23.48,26.85 25,25.33 38.25,25.33 39.68,25.33 39.88,25.53 40.43,25.53 40.43,25.53 61.27,25.53 61.42,25.68 62.23,26.49 62.76,27.02 62.76,27.02 63.03,27.29 69.73,27.29 70.97,26.05 71.31,26.05 72.05,26.05 72.27,26.05 72.27,26.05 77.85,26.05 78.37,26.57 82.33,30.53 82.33,47.54 84.94,50.15 89.24,50.15 93.62,54.53 95.32,54.53 101.04,60.25 101.04,62.28 101.87,63.11 101.87,64 100.78,65.08 98.79,65.08 98.38,64.68 97.25,64.68
  BOTTOM w0.089: UC1.D15 v2(93.95,64.9)
  BOTTOM w0.114: RU14.2 23.74,50.55 LU12.2 23.98,50.55 24.1,50.67 24.37,50.67 v2(24.54,50.5)
USB3_CRX_DTX_N1: length 104.6
  IN2 w0.089: 95.86,62.54 95.79,62.54 94.76,63.58 92.64,63.58 92.52,63.69 v2(92.52,63.95)
  IN2 w0.127: v2(24.87,36.66) 25.09,36.66 25.38,36.37 25.38,35.32 27.38,33.33 27.38,32.66 28.17,31.87 41.18,31.87 41.69,32.38 42.5,32.38 44.81,34.69 44.81,35.07 47.95,38.21 51.55,38.21 52.7,37.06 52.92,37.06 52.92,37.06 55.88,37.06 58.66,34.28 75.08,34.28 77.04,36.23 77.04,46.2 77.2,46.36 84.1,53.26 88.72,53.26 92.64,57.18 94.17,57.18 96.64,59.65 96.64,61.76 95.86,62.54
  BOTTOM w0.089: UC1.H11 v2(92.52,63.95)
  BOTTOM w0.114: RU23.2 23.99,36.7 LU8.2 24.23,36.7 24.36,36.83 24.7,36.83 v2(24.87,36.66)
USB3_CRX_DTX_P0: length 144.7
  IN2 w0.089: 97.25,64.41 97.14,64.41 97.13,64.42 97.08,64.42 97.08,64.42 96.93,64.42 94.18,64.42 94.06,64.54 93.77,64.54 93.4,64.9 v2(93.24,64.9)
  IN2 w0.127: v2(24.54,51.09) 24.55,51.09 24.87,50.77 25.03,50.77 25.31,50.49 25.31,48.45 23.09,46.23 23.09,39.5 21.56,37.97 21.56,31.48 23.74,29.3 23.74,26.96 25.11,25.6 38.36,25.6 39.57,25.6 39.77,25.79 40.41,25.79 40.41,25.79 61.16,25.79 61.96,26.6 62.65,27.28 62.65,27.28 62.76,27.4 62.92,27.55 69.84,27.55 71.08,26.31 71.42,26.31 71.94,26.31 72.16,26.31 77.74,26.31 78.11,26.68 82.07,30.64 82.07,47.65 84.83,50.41 89.13,50.41 93.51,54.8 95.21,54.8 100.78,60.36 100.78,62.39 101.6,63.22 101.6,63.89 100.67,64.82 98.9,64.82 98.57,64.49 98.49,64.41 97.25,64.41
  BOTTOM w0.089: UC1.F15 v2(93.24,64.9)
  BOTTOM w0.114: v2(24.54,51.09) 24.37,50.92 24.1,50.92 23.98,51.05 LU12.3 23.74,51.05 RU22.2
USB3_CRX_DTX_P1: length 104.6
  IN2 w0.089: v2(91.81,63.95) 92.01,63.95 92.56,63.4 94.68,63.4 95.65,62.43 95.65,62.37 95.67,62.35
  IN2 w0.127: 95.67,62.35 96.37,61.65 96.37,59.76 94.06,57.45 92.53,57.45 88.61,53.53 83.99,53.53 76.93,46.47 76.78,46.31 76.78,36.34 74.97,34.54 58.77,34.54 55.99,37.32 52.81,37.32 51.66,38.48 47.84,38.48 44.55,35.18 44.55,34.8 42.39,32.64 41.58,32.64 41.07,32.14 28.28,32.14 27.64,32.77 27.64,33.43 25.65,35.43 25.65,36.48 24.88,37.24 v2(24.87,37.24)
  BOTTOM w0.089: UC1.J11 v2(91.81,63.95)
  BOTTOM w0.114: RU16.2 23.99,37.2 LU8.3 24.23,37.2 24.36,37.08 24.7,37.08 v2(24.87,37.24)
USB3_CRX_L_DTX_N0: length 4.2
  BOTTOM w0.114: RU14.1 22.56,50.55 LU12.1 22.19,50.55 22.06,50.67 21.78,50.67 21.58,50.87 21.39,50.87 21.26,50.75 EU2605.9 EU2605.1 19.58,50.75 19.45,50.87 19.19,50.87 RU33.2
USB3_CRX_L_DTX_N0_R: length 4.8
  BOTTOM w0.114: RU33.1 17.73,50.86 16.89,50.86 16.71,50.67 15.57,50.67 14.93,50.03 14.62,50.03 14.38,49.8 JUSB1.5
USB3_CRX_L_DTX_N1: length 4.1
  BOTTOM w0.114: RU29.2 19.48,36.84 19.73,36.84 19.85,36.71 EU2606.1 EU2606.9 21.51,36.71 21.64,36.84 22.16,36.84 22.3,36.7 LU8.1 22.81,36.7 RU23.1
USB3_CRX_L_DTX_N1_R: length 15
  BOTTOM w0.114: JUSB2.5 14.38,25.9 14.62,26.13 14.93,26.13 15.54,26.74 16.71,26.74 17.49,27.52 v4(17.49,28.7) 17.49,29.96 18.53,31 18.53,35.19 17.82,35.89 17.82,36.71 17.93,36.83 18.04,36.83 RU29.1
USB3_CRX_L_DTX_P0: length 4.2
  BOTTOM w0.114: RU22.1 22.56,51.05 LU12.4 22.19,51.05 22.06,50.92 21.88,50.92 21.68,51.12 21.36,51.12 21.23,51.25 EU2605.8 EU2605.2 19.58,51.25 19.45,51.12 19.14,51.12 RU34.2
USB3_CRX_L_DTX_P0_R: length 4.8
  BOTTOM w0.114: RU34.1 17.74,51.11 16.79,51.11 16.6,50.92 15.47,50.92 14.83,50.28 14.61,50.28 14.38,50.51 JUSB1.6
USB3_CRX_L_DTX_P1: length 4
  BOTTOM w0.114: RU16.1 22.81,37.2 LU8.4 22.3,37.2 22.18,37.09 21.68,37.09 21.55,37.21 EU2606.8 EU2606.2 19.85,37.21 19.73,37.09 19.46,37.09 RU30.2
USB3_CRX_L_DTX_P1_R: length 15
  BOTTOM w0.114: JUSB2.6 14.38,26.61 14.61,26.38 14.83,26.38 15.43,26.98 16.61,26.98 17.24,27.62 17.24,30.06 v4(17.77,30.59) 18.28,31.1 18.28,35.09 17.57,35.79 17.57,36.81 17.83,37.07 18.04,37.07 RU30.1
USB3_CTX_C_DRX_N0: length 2
  BOTTOM w0.114: CU24.2 24.97,52.01 24.64,52.01 24.39,52.26 24.11,52.26 23.98,52.13 LU7.2 23.74,52.13 RU15.2
USB3_CTX_C_DRX_N1: length 1.4
  BOTTOM w0.114: CU16.2 24.72,38.42 24.4,38.42 24.27,38.29 LU11.2 23.99,38.29 RU13.2
USB3_CTX_C_DRX_P0: length 2
  BOTTOM w0.114: CU30.2 24.97,52.25 24.74,52.25 24.49,52.51 24.16,52.51 24.04,52.63 LU7.3 23.74,52.63 RU17.2
USB3_CTX_C_DRX_P1: length 1.4
  BOTTOM w0.114: RU20.2 23.99,38.79 LU11.3 24.24,38.79 24.37,38.66 24.72,38.66 CU29.2
USB3_CTX_DRX_N0: length 164.7
  IN2 w0.127: v2(20.76,49.85) 20.78,49.83 21.2,49.83 21.56,49.47 21.56,48.13 20.72,47.29 20.71,47.28 20.71,39.98 18.78,38.05 18.78,32.77 18.58,32.57 18.58,26.35 21.56,23.36 40.03,23.36 40.67,24 77.96,24 79.91,25.94 79.91,25.94 87.14,33.17 87.14,39.91 87.87,40.65 89.92,40.65 v2(90.08,40.81)
  BOTTOM w0.089: 98.53,65.16 98.51,65.16 98.47,65.19 97.3,65.19 97.19,65.08 95.19,65.08 95.09,64.98 94.9,64.98 94.62,65.26 UC1.C15
  BOTTOM w0.114: v2(90.08,40.81) 90.25,40.64 90.62,40.64 91.16,41.18 91.16,42.17 94.2,45.2 96.55,45.2 97.63,46.29 103.09,46.29 106.23,49.42 106.23,54.15 107.2,55.13 107.2,55.6 106,56.81 106,60.47 103.45,63.01 102.62,63.01 100.89,64.75 100.47,64.75 100.06,65.16 98.53,65.16 ; v2(20.76,49.85) 21.24,49.37 25.37,49.37 27.06,51.06 27.06,52.01 26.89,52.18 26.7,52.18 CU24.1
USB3_CTX_DRX_N1: length 115.1
  IN2 w0.127: v2(100.9,63.84) 100.9,63.85 100.49,64.26 100.14,64.26 99.99,64.11 99.46,64.11 98.32,62.96 98.32,60.6 94.39,56.66 93.16,56.66 92.83,56.66 88.76,52.59 84.58,52.59 84.47,52.59 84.14,52.59 77.55,45.99 77.55,36.02 75.24,33.71 58.33,33.71 55.49,36.55 52.49,36.55 51.34,37.7 48.16,37.7 45.32,34.86 45.32,34.48 42.66,31.82 42.02,31.82 41.52,31.31 27.96,31.31 26.82,32.46 26.58,32.46 26.14,32.9 26.14,33.77 24.3,35.61 24.3,37.41 25.38,38.49 26.41,38.49 v2(26.65,38.25)
  BOTTOM w0.089: UC1.A14 97.62,64.81 97.81,64.61 98.47,64.61 98.51,64.64 98.53,64.64
  BOTTOM w0.114: v2(26.65,38.25) 26.48,38.42 26.28,38.42 CU16.1 ; 98.53,64.64 99.87,64.64 100.26,64.26 100.49,64.26 v2(100.9,63.84)
USB3_CTX_DRX_P0: length 164.4
  IN2 w0.127: v2(20.93,49.1) 21.17,49.1 21.3,48.98 21.3,48.24 20.46,47.4 20.46,47.4 20.45,47.39 20.45,40.09 18.51,38.16 18.51,32.88 18.31,32.68 18.31,26.24 21.45,23.1 40.14,23.1 40.78,23.73 78.07,23.73 83.02,28.68 87.4,33.06 87.4,39.8 87.98,40.38 89.92,40.38 v2(90.08,40.22)
  BOTTOM w0.089: 98.53,65.41 98.51,65.41 98.47,65.37 97.22,65.37 97.11,65.26 UC1.B15
  BOTTOM w0.114: v2(90.08,40.22) 90.25,40.39 90.72,40.39 91.41,41.08 91.41,42.06 94.3,44.95 96.65,44.95 97.74,46.04 103.2,46.04 106.48,49.32 106.48,54.05 107.45,55.02 107.45,55.7 106.24,56.91 106.24,60.57 103.55,63.26 102.73,63.26 100.99,65 100.57,65 100.16,65.41 98.53,65.41 ; v2(20.93,49.1) 20.95,49.12 25.48,49.12 27.31,50.95 27.31,52.11 26.99,52.43 26.36,52.43 CU30.1
USB3_CTX_DRX_P1: length 115.1
  IN2 w0.127: v2(26.65,38.83) 26.57,38.75 25.27,38.75 24.04,37.52 24.04,35.5 25.88,33.66 25.88,32.79 26.47,32.19 26.71,32.19 27.85,31.05 41.63,31.05 42.13,31.55 42.77,31.55 45.58,34.37 45.58,34.75 48.27,37.44 51.23,37.44 52.38,36.29 55.38,36.29 58.22,33.45 75.35,33.45 77.81,35.91 77.81,45.88 84.25,52.32 84.36,52.32 84.47,52.32 84.47,52.32 88.87,52.32 92.94,56.4 93.05,56.4 94.5,56.4 98.59,60.49 98.59,62.85 99.57,63.84 v2(100.32,63.84)
  BOTTOM w0.089: UC1.C14 95.24,64.55 95.36,64.55 95.54,64.63 97.54,64.63 97.74,64.43 98.47,64.43 98.51,64.4 98.53,64.4
  BOTTOM w0.114: 98.53,64.4 99.76,64.4 v2(100.32,63.84) ; CU29.1 26.28,38.66 26.48,38.66 v2(26.65,38.83)
USB3_CTX_L_DRX_N0: length 4.1
  BOTTOM w0.114: RU15.1 22.56,52.13 LU7.1 22.19,52.13 22.06,52.26 21.68,52.26 21.58,52.37 21.42,52.37 21.3,52.25 EU2605.7 EU2605.4 19.58,52.25 19.45,52.37 19.15,52.37 RU36.2
USB3_CTX_L_DRX_N0_R: length 7.1
  BOTTOM w0.114: RU36.1 17.74,52.38 17.34,52.38 17.09,52.64 17.09,54.57 16.39,55.26 15.58,55.26 14.81,56.03 14.61,56.03 14.38,55.81 JUSB1.8
USB3_CTX_L_DRX_N1: length 4.1
  BOTTOM w0.114: RU13.1 22.81,38.29 LU11.1 22.45,38.29 22.32,38.42 22.07,38.42 22,38.34 21.62,38.34 21.49,38.21 EU2606.7 EU2606.4 19.98,38.21 19.82,38.38 19.43,38.38 RU31.2
USB3_CTX_L_DRX_N1_R: length 11.5
  BOTTOM w0.114: RU31.1 18.04,38.41 17.69,38.41 17.08,37.8 17.08,35.54 17.64,34.98 v4(17.64,33.14) 17.64,32.68 16.65,31.69 15.33,31.69 14.89,32.13 14.65,32.13 14.38,31.87 JUSB2.8
USB3_CTX_L_DRX_P0: length 4.2
  BOTTOM w0.114: RU17.1 22.56,52.63 LU7.4 22.19,52.63 22.07,52.51 21.79,52.51 21.68,52.61 21.4,52.61 21.26,52.75 EU2605.6 EU2605.5 19.58,52.75 19.45,52.62 19.18,52.62 RU35.2
USB3_CTX_L_DRX_P0_R: length 7.1
  BOTTOM w0.114: RU35.1 17.73,52.63 17.44,52.63 17.33,52.74 17.33,54.67 16.49,55.51 15.68,55.51 14.91,56.28 14.6,56.28 14.38,56.5 JUSB1.9
USB3_CTX_L_DRX_P1: length 4.1
  BOTTOM w0.114: RU32.2 19.51,38.62 19.87,38.62 19.96,38.71 EU2606.5 EU2606.6 21.51,38.71 21.64,38.59 21.89,38.59 21.97,38.66 22.26,38.66 22.38,38.79 LU11.4 22.81,38.79 RU20.1
USB3_CTX_L_DRX_P1_R: length 11.5
  BOTTOM w0.114: JUSB2.9 14.38,32.64 14.64,32.38 14.99,32.38 15.43,31.94 16.54,31.94 17.39,32.78 v4(17.39,34.54) 17.39,34.88 16.83,35.44 16.83,37.9 17.59,38.66 18.04,38.66 RU32.1
USB20_N0: length 83.8
  IN2 w0.127: v2(54.31,48.95) 54.08,49.18 54.08,49.79 55.73,51.44 55.73,53.16 56.17,53.59 56.87,53.59 58.84,55.56 64.8,55.56 66.66,53.71 76.68,53.71 79.48,56.51 79.48,59.22 80.35,60.08 81.58,60.08 82.8,61.31 86.12,61.31 86.62,61.81 87.08,61.81 87.32,61.56 87.32,61.3 87.61,61.01 87.96,61.01 v2(88.3,60.66)
  BOTTOM w0.089: UC1.U5 v2(88.3,60.66)
  BOTTOM w0.114: RU18.1 23.78,43.48 LU9.3 23.78,42.98 23.53,42.73 23.53,42.58 24.34,41.77 v4(27.72,41.77) 35.82,41.77 36.71,40.88 41.63,40.88 44.17,43.42 44.17,45.37 44.62,45.83 49.16,45.83 52.22,48.9 52.22,49.35 52.71,49.84 53.81,49.84 54.06,49.58 54.06,49.2 v2(54.31,48.95)
USB20_N0_R: length 16.8
  IN2 w0.127: JUSB1.2 15.88,53.53 16.01,53.4 16.67,53.4 17.24,52.83 17.24,48.34 17.38,48.2 17.56,48.2 v2(17.72,48.36)
  BOTTOM w0.114: v2(17.72,48.36) 17.89,48.19 18.28,48.19 EU2608.3 19.25,48.9 19.25,48.3 19.36,48.19 19.72,48.19 21.44,46.47 v4(22.13,46.47) 22.92,46.47 23.65,45.74 23.65,45.02 23.78,44.89 LU9.4 23.78,44.65 RU18.2
USB20_N1: length 94.1
  BOTTOM w0.089: 90.58,56.07 90.58,56.09 90.55,56.12 90.55,57.22 90.04,57.73 90.04,59.42 90.11,59.52 90.11,59.71 UC1.N3
  BOTTOM w0.114: 90.58,56.07 90.58,55.18 93.01,52.76 95.2,52.76 95.86,52.1 95.86,49.78 95.04,48.96 v4(94.14,48.96) 92.98,48.96 87.9,43.88 78.99,43.88 74.38,48.49 57.8,48.49 57.51,48.2 50.52,41.21 43.44,41.21 42.02,39.79 35.65,39.79 35.42,40.02 26.81,40.02 26.67,39.88 LU10.2 24.24,39.88 RU19.1
USB20_N1_R: length 22.6
  IN2 w0.127: JUSB2.2 15.88,29.3 16.16,29.01 16.93,29.01 17.42,29.51 17.42,38.46 18.38,39.41 18.38,39.89 18.25,40.02 17.97,40.02 v2(17.81,39.86)
  BOTTOM w0.114: RU19.2 23.07,39.88 LU10.1 22.83,39.88 22.7,40 22.33,40 22.07,40.26 22.07,41.01 21.78,41.3 21.26,41.3 21.14,41.19 21.14,40.71 EU2607.3 20.63,40.71 20.63,41.19 20.52,41.3 20.32,41.3 19.05,40.03 17.97,40.03 v2(17.81,39.86)
USB20_N2: length 129.3
  IN2 w0.127: v2(102.13,52.61) 102.14,52.6 103.44,52.6 105.82,50.22 116.62,50.22 118.15,48.69 122.47,48.69 124.17,47 125.69,47 126.87,45.82 134.64,45.82 135.47,45 137.46,45 139.47,43 147.19,43 150.55,39.63 174.23,39.63 174.84,39.03 178.95,39.03 181.41,36.57 185.51,36.57 186.29,37.34 201.47,37.34 203.21,39.09 203.21,39.52 v2(203.05,39.68)
  BOTTOM w0.089: 91.98,56.07 91.98,56.09 91.95,56.12 91.95,57.01 90.92,58.05 90.92,59 90.94,59.03 90.94,59.42 91.02,59.53 91.02,59.72 90.87,59.93 UC1.L3
  BOTTOM w0.114: RU28.1 205.44,38.61 LU14.3 205.14,38.61 205.01,38.73 203.52,38.73 203.24,39.01 203.24,39.49 v2(203.05,39.68) ; v2(102.13,52.61) 101.43,52.61 101.31,52.49 100.58,52.49 99.28,53.78 96.52,53.78 95.21,55.09 92.73,55.09 91.98,55.84 91.98,56.07
USB20_N2_R: length 3.5
  BOTTOM w0.114: JIOB1.7 207.2,37.48 206.89,37.79 206.89,37.98 207.01,38.1 207.34,38.1 207.46,38.21 207.46,38.61 207.34,38.73 207.13,38.73 207.01,38.61 LU14.4 206.62,38.61 RU28.2
USB20_N3: length 103.2
  IN2 w0.089: 97.13,67.93 94.42,67.93 94.19,67.7 91.59,67.7 91.29,68 90.96,68 90.2,67.24 89.49,67.24 89.14,66.89 89.14,66.53 88.62,66.01 88.62,64.89 88.71,64.8 88.99,64.8 v2(89.15,64.97)
  IN2 w0.127: 97.13,67.93 99.01,67.93 99.97,68.88 102.83,68.88 104.05,70.1 104.05,71.56 104.74,72.25 107.49,72.25 108.09,72.85 108.09,75.42 108.69,76.02 108.69,79.1 108.3,79.49 108.3,80.79 110.41,82.9 110.41,89.08 108.56,90.93 108.56,92.38 105.7,95.24 105.7,98.2 104.62,99.28 103.29,99.28 103.29,99.28 103.07,99.28 102.02,98.24 95.08,98.24 90.51,102.81 85.57,102.81 83.78,104.61 83.78,104.61 83.37,105.01 83.15,105.23 82.82,105.23 81.71,106.34 81.71,106.76 81.71,106.99 79.09,109.62 79.09,112.96 77.93,114.12 77.93,122.2 77.62,122.51 77.13,122.51 v2(77.05,122.59)
  BOTTOM w0.089: v2(89.15,64.97) UC1.R15
  BOTTOM w0.114: JWLAN1.5 78.27,122.55 78.14,122.42 77.22,122.42 v2(77.05,122.59)
USB20_N4: length 142.1
  IN2 w0.127: v2(102.15,51.22) 103.12,51.22 104.9,49.43 114.93,49.43 117.76,46.6 120.37,46.6 120.98,47.21 122.3,47.21 123.41,46.1 125.37,46.1 126.36,45.1 134.38,45.1 135.18,44.3 137.17,44.3 139.18,42.3 146.9,42.3 150.27,38.93 173.63,38.93 174.23,38.33 177.1,38.33 178.08,37.35 178.92,37.35 180.4,35.87 202.03,35.87 204.64,38.49 204.64,40.7 203.53,41.81 203.53,48.32 203.78,48.58 204.08,48.58 v2(204.24,48.74)
  BOTTOM w0.089: UC1.M3 90.56,59.37 90.56,59.16 90.51,59.1 90.51,57.87 91.26,57.11 91.26,56.12 91.3,56.09 91.3,56.07
  BOTTOM w0.114: R18.2 205.12,48.7 L3.4 204.83,48.7 204.7,48.57 204.41,48.57 v2(204.24,48.74) ; v2(102.15,51.22) 101.52,51.22 100.58,50.28 97.06,50.28 96.62,50.72 96.62,52.48 95.51,53.58 93.22,53.58 91.3,55.51 91.3,56.07
USB20_N4_R: length 10.3
  BOTTOM w0.114: JEDP1.33 211.94,44.45 211.81,44.32 211.48,44.32 211.08,44.73 v4(211.08,45.59) 211.08,46.09 210.54,46.63 209.47,46.63 209.36,46.74 D11.2 208.82,47.04 208.82,46.97 208.77,46.91 208.61,46.91 208.05,47.47 208.05,47.92 207.53,48.44 207,48.44 206.74,48.7 L3.3 206.3,48.7 R18.1
USB20_N5: length 133.3
  IN2 w0.127: v2(200.91,40.54) 201.06,40.4 201.06,39.53 199.63,38.11 186.07,38.11 185.23,37.26 181.7,37.26 179.24,39.72 175.12,39.72 174.48,40.37 150.8,40.37 146.89,44.28 139.16,44.28 137.75,45.7 135.75,45.7 134.83,46.61 127.59,46.61 126.45,47.76 124.8,47.76 123.17,49.39 118.44,49.39 116.91,50.92 107.28,50.92 103.93,54.27 99.37,54.27 98.63,53.54 94.02,53.54 91.28,50.79 90.96,50.79 v2(90.76,50.99)
  BOTTOM w0.089: UC1.R3 89.21,59.68 89.21,59.57 89.11,59.32 89.11,56.9 89.05,56.83
  BOTTOM w0.114: v2(90.76,50.99) 90.43,50.65 90.11,50.65 89.05,51.71 89.05,56.83 ; v2(200.91,40.54) 201.08,40.71 201.08,41.33 200.95,41.46 L4.4 200.95,41.76 R21.2
USB20_N5_R: length 19.2
  TOP w0.114: R84.2 202.21,43.53 201.52,43.53 200.85,44.19 200.85,44.67 v2(200.76,44.76)
  BOTTOM w0.114: R21.1 200.95,42.94 L4.3 200.95,44.57 v2(200.76,44.76) 200.89,44.9 200.89,45.37 201.28,45.76 201.78,45.76 DA6.3 202.75,46.38 202.75,45.96 202.89,45.82 203.19,45.82 204.45,44.56 210.23,44.56 211.36,43.43 211.36,43.06 211.48,42.95 JEDP1.36
USB20_N6: length 151.1
  IN2 w0.127: v2(208.12,38.57) 208.13,38.57 208.45,38.89 208.69,38.89 208.9,38.67 208.9,37.72 208.77,37.6 208.7,37.6 208.57,37.47 208.57,37.21 208.7,37.09 208.77,37.09 208.9,36.96 208.9,36.25 204.9,32.25 179.35,32.25 177.36,34.24 176.76,34.24 175.7,35.31 152.44,35.31 149.71,32.58 137.85,32.58 134.6,29.33 109.28,29.33 101.75,36.87 101.75,39.38 101.18,39.95 101.18,45.6 95.49,51.28 94.7,51.28 v2(94.46,51.53)
  BOTTOM w0.089: 89.8,56.08 89.8,56.1 89.76,56.14 89.76,57.32 89.59,57.49 89.59,58.94 89.67,59.01 89.67,59.35 UC1.P3
  BOTTOM w0.114: v2(208.12,38.57) 208.29,38.73 208.56,38.73 208.69,38.61 LU13.3 209.06,38.5 RU25.1 ; v2(94.46,51.53) 94.22,51.29 91.93,51.29 89.8,53.42 89.8,56.08
USB20_N6_R: length 3.3
  BOTTOM w0.114: JIOB1.4 210.2,37.48 210.6,37.88 210.8,37.88 210.95,38.03 210.95,38.55 210.77,38.73 210.6,38.73 210.48,38.61 LU13.4 210.11,38.61 RU25.2
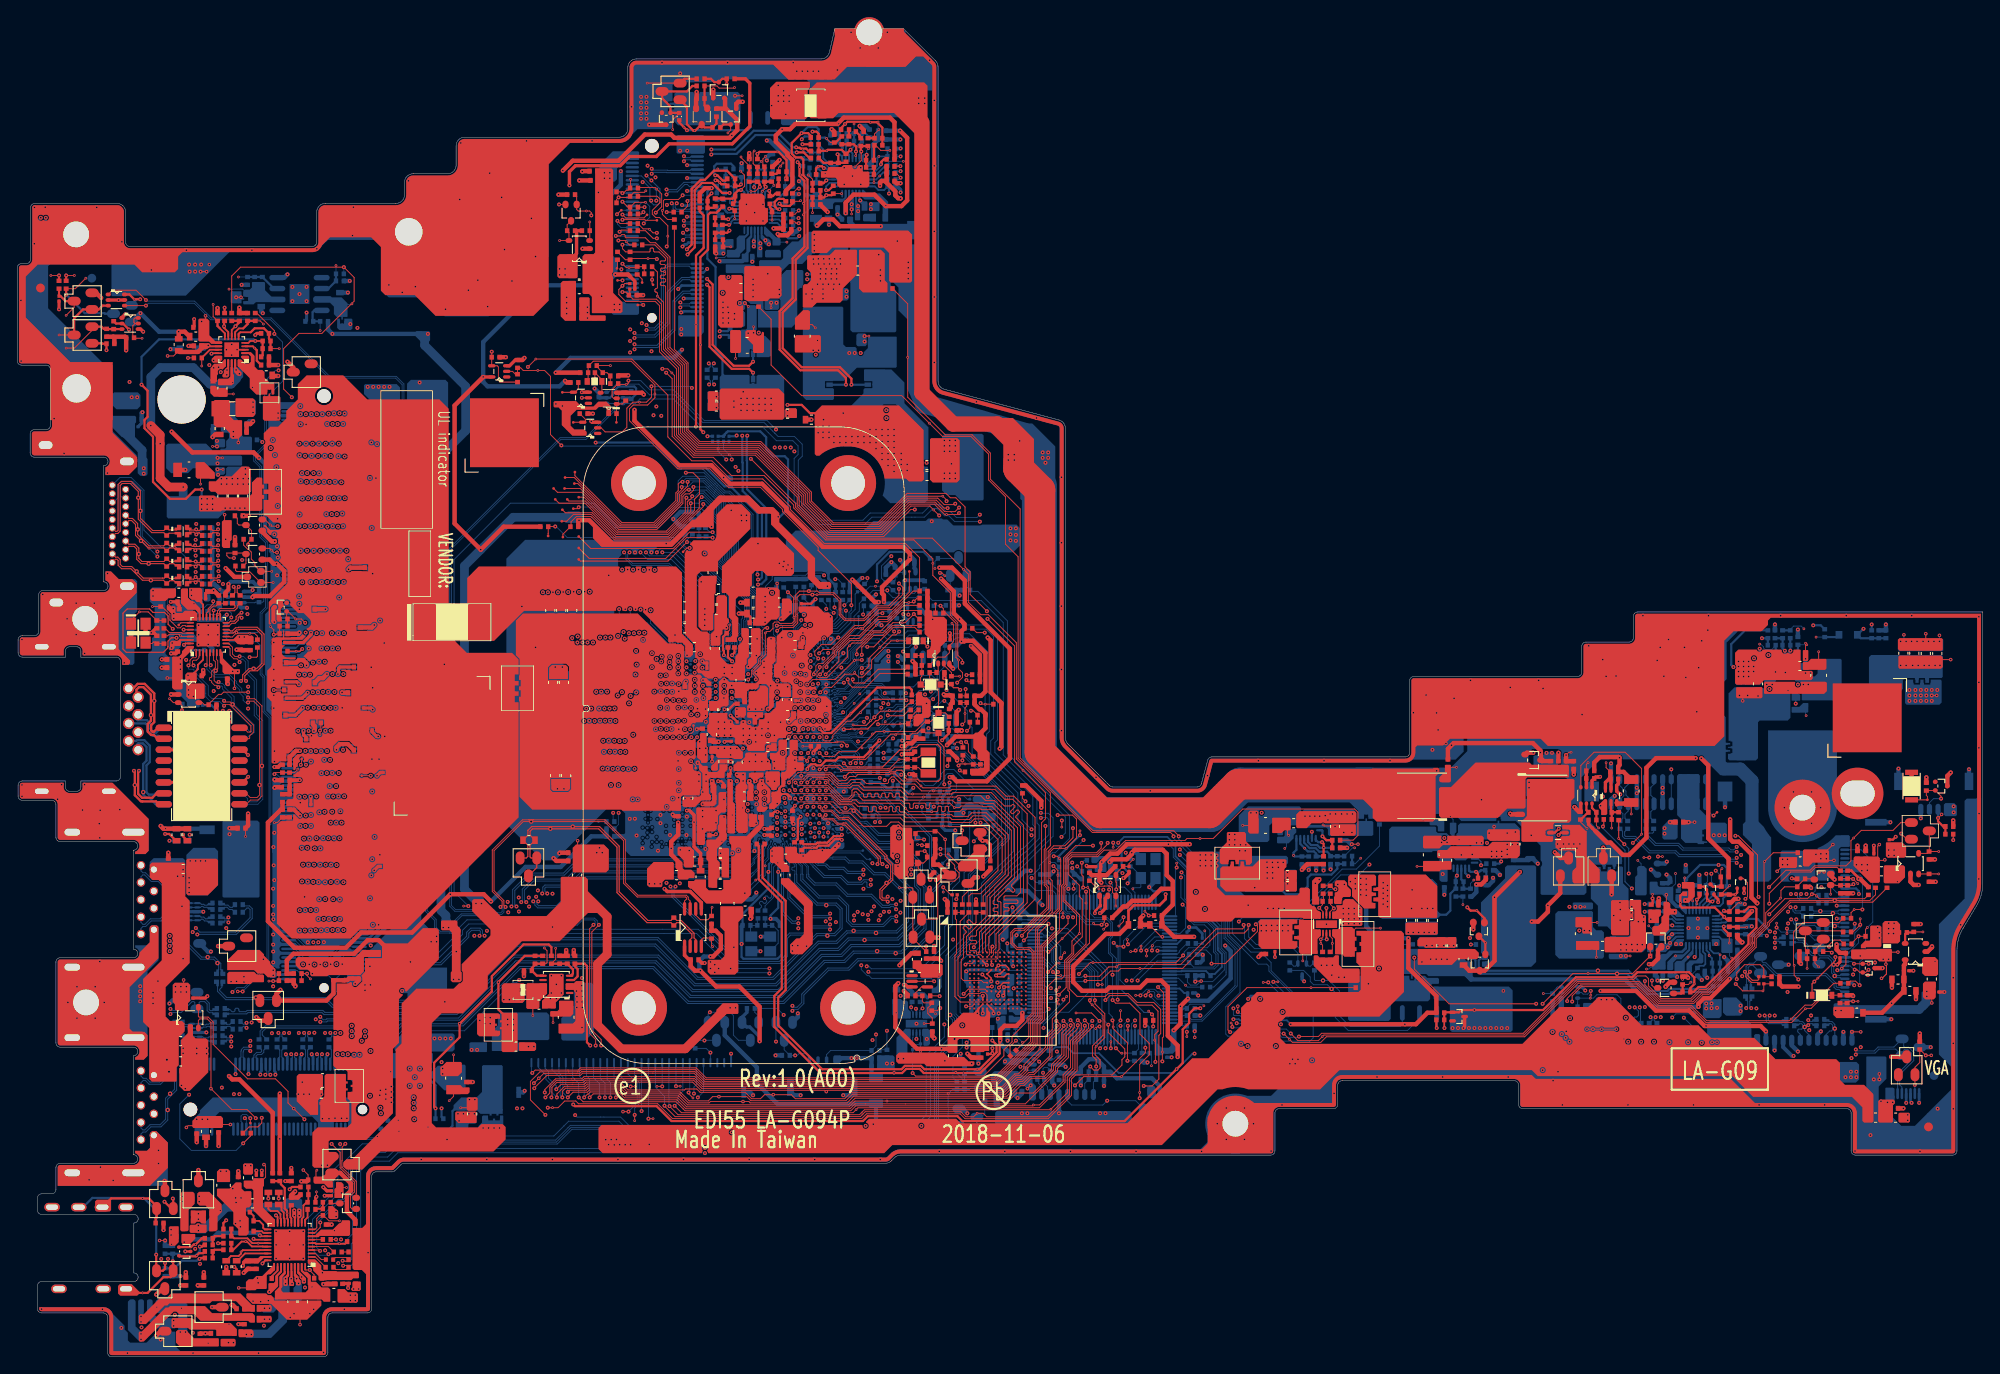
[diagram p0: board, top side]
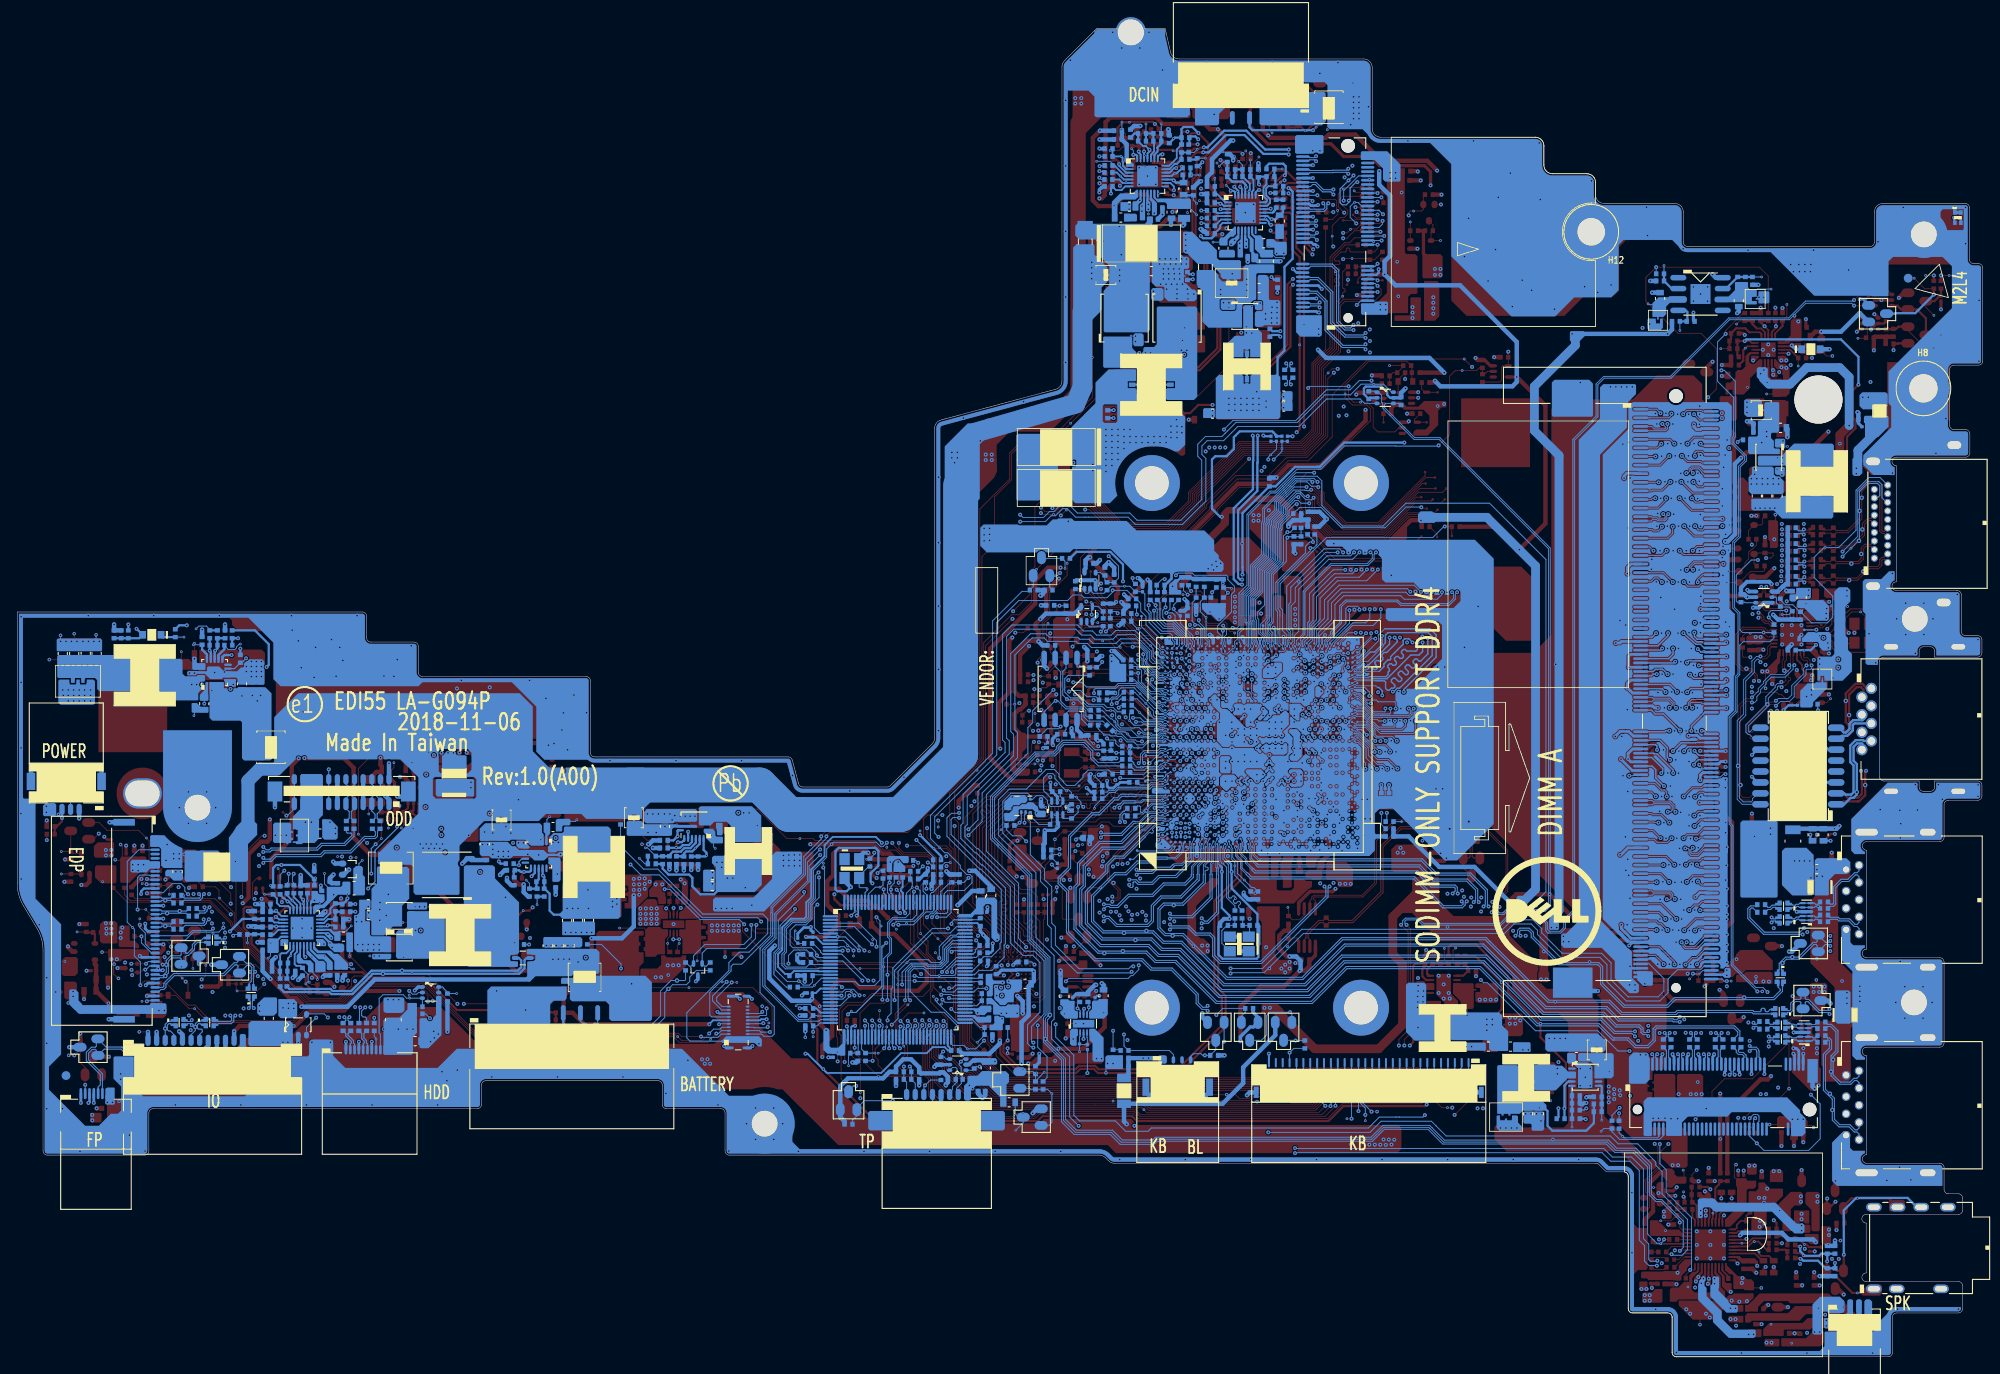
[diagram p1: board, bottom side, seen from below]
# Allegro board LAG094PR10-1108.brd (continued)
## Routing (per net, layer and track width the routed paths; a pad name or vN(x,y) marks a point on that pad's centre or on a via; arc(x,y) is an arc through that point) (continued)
USB20_N7: length 197.8
  IN2 w0.127: v2(88.3,62.73) 88.13,62.57 87.83,62.57 87.6,62.81 85.49,62.81 85.25,62.57 82.56,62.57 81.65,61.67 80.57,61.67 78.51,59.6 78.51,58.69 76.07,56.25 76.07,54.84 v2(75.91,54.68) ; v2(94.45,49.68) 94.61,49.84 94.98,49.84 100.22,44.6 100.22,33.8 100.83,33.2 102.73,33.2 108.51,27.42 134.45,27.42 138.65,31.62 150.11,31.62 152.84,34.35 175.09,34.35 175.22,34.21 175.23,34.21 178.34,31.1 205.44,31.1 209.64,35.31 213.49,35.31 v2(213.65,35.15)
  BOTTOM w0.114: v2(88.3,62.73) 88.3,62.76 UC1.U10 ; JFP1.6 218.5,31.2 218.5,32.91 220.13,34.54 220.13,35.3 219.67,35.75 219.32,35.75 219.21,35.63 219.21,35.23 EU2701.2 218.28,35.77 216.34,35.77 215.88,35.31 213.82,35.31 v2(213.65,35.15) ; v2(94.45,49.68) 94.28,49.85 92.34,49.85 91.51,49.03 89.86,49.03 89.5,48.66 89.5,46.57 88.66,45.72 83.82,45.72 76.09,53.45 76.09,54.5 v2(75.91,54.68)
USB20_P0: length 83.9
  IN2 w0.127: v2(53.72,48.95) 53.82,49.05 53.82,49.9 55.47,51.55 55.47,53.26 56.11,53.91 56.74,53.91 58.65,55.82 64.91,55.82 66.76,53.97 76.57,53.97 79.22,56.62 79.22,59.33 80.24,60.35 81.47,60.35 82.69,61.57 86.01,61.57 86.51,62.07 87.19,62.07 87.59,61.67 87.59,61.41 87.72,61.27 88.2,61.27 v2(88.3,61.37)
  BOTTOM w0.089: UC1.U7 v2(88.3,61.37)
  BOTTOM w0.114: v2(53.72,48.95) 53.82,49.05 53.82,49.47 53.7,49.59 52.81,49.59 52.47,49.25 52.47,48.79 49.26,45.58 44.73,45.58 44.41,45.27 44.41,43.32 41.73,40.64 36.61,40.64 35.72,41.52 24.24,41.52 23.28,42.48 LU9.2 23.28,43.48 RU21.1
USB20_P0_R: length 16.7
  IN2 w0.127: v2(17.72,47.77) 17.56,47.93 17.27,47.93 16.98,48.23 16.98,52.72 16.56,53.13 15.91,53.13 15.78,53.01 15.78,52.25 JUSB1.3
  BOTTOM w0.114: RU21.2 23.28,44.65 LU9.1 23.28,44.89 23.41,45.02 23.41,45.64 v4(23.27,45.77) 22.82,46.22 21.34,46.22 19.62,47.94 19.36,47.94 19.25,47.83 19.25,47.23 EU2608.2 18.28,47.94 17.89,47.94 v2(17.72,47.77)
USB20_P1: length 94.2
  BOTTOM w0.089: UC1.N2 89.86,59.61 89.86,57.65 90.37,57.14 90.37,57.02 90.28,56.93 90.1,56.93 90.01,56.84 90.01,56.66 90.1,56.57 90.28,56.57 90.37,56.49 90.37,56.12 90.34,56.09 90.34,56.07
  BOTTOM w0.114: 90.34,56.07 90.34,55.08 92.9,52.51 v4(94.01,52.51) 95.09,52.51 95.61,51.99 95.61,49.88 94.94,49.21 92.88,49.21 87.8,44.13 79.09,44.13 74.48,48.74 57.7,48.74 57.26,48.3 50.42,41.46 43.34,41.46 41.92,40.04 35.75,40.04 35.52,40.27 26.71,40.27 26.57,40.12 25.87,40.12 25.76,40.24 25.76,40.41 25.64,40.52 25.41,40.52 25.3,40.41 25.3,40.24 25.18,40.12 24.97,40.12 24.71,40.38 LU10.3 24.24,40.38 RU24.1
USB20_P1_R: length 22.6
  IN2 w0.127: v2(17.81,40.44) 17.97,40.28 18.36,40.28 18.64,40 18.64,39.3 17.69,38.35 17.69,29.4 17.03,28.75 16.38,28.75 JUSB2.3
  BOTTOM w0.114: RU24.2 23.07,40.38 LU10.4 22.83,40.38 22.7,40.25 22.43,40.25 22.31,40.36 22.31,41.11 21.88,41.55 21.26,41.55 21.14,41.66 21.14,42.13 EU2607.2 20.63,42.13 20.63,41.66 20.52,41.55 20.22,41.55 18.94,40.27 17.97,40.27 v2(17.81,40.44)
USB20_P2: length 129.2
  IN2 w0.127: v2(203.64,39.68) 203.48,39.52 203.48,38.98 201.58,37.08 186.4,37.08 185.62,36.3 181.3,36.3 178.84,38.76 174.73,38.76 174.12,39.37 150.44,39.37 147.08,42.73 139.36,42.73 137.35,44.73 135.36,44.73 134.54,45.56 126.76,45.56 125.58,46.73 124.06,46.73 122.36,48.43 118.04,48.43 116.51,49.96 105.71,49.96 103.33,52.33 102.44,52.33 102.14,52.03 v2(102.13,52.03)
  BOTTOM w0.089: UC1.L2 90.75,59.09 90.74,59.08 90.74,57.97 91.77,56.94 91.77,56.12 91.74,56.09 91.74,56.07
  BOTTOM w0.114: v2(102.13,52.03) 101.79,52.37 101.53,52.37 101.41,52.24 100.48,52.24 99.18,53.53 96.42,53.53 95.11,54.85 92.62,54.85 91.74,55.73 91.74,56.07 ; RU27.1 205.44,39.11 LU14.2 205.14,39.11 205.01,38.98 203.62,38.98 203.48,39.12 203.48,39.52 v2(203.64,39.68)
USB20_P2_R: length 3.6
  BOTTOM w0.114: JIOB1.6 208.2,37.44 207.7,37.93 v4(207.7,38.35) 207.7,38.71 207.45,38.97 207.15,38.97 207.01,39.11 LU14.1 206.62,39.11 RU27.2
USB20_P3: length 103.2
  IN2 w0.089: 95.16,68.19 94.43,68.19 94.12,67.88 91.66,67.88 91.36,68.18 90.89,68.18 90.13,67.42 89.42,67.42 88.96,66.96 88.96,66.6 88.44,66.08 88.44,64.82 88.63,64.63 89.02,64.63 v2(89.26,64.39)
  IN2 w0.127: v2(77.05,122.01) 77.29,122.25 77.51,122.25 77.67,122.09 77.67,114.01 78.83,112.85 78.83,109.51 81.45,106.88 81.45,106.87 81.45,106.23 82.71,104.97 83.04,104.97 83.26,104.75 83.27,104.75 83.51,104.5 83.51,104.5 85.46,102.55 90.4,102.55 94.97,97.98 102.13,97.98 103.18,99.02 104.51,99.02 105.43,98.1 105.43,95.13 108.29,92.27 108.29,90.82 110.14,88.97 110.14,83.01 108.04,80.9 108.04,79.38 108.43,78.99 108.43,76.12 107.83,75.53 107.83,72.96 107.38,72.51 104.63,72.51 103.78,71.67 103.78,70.21 102.72,69.15 99.86,69.15 98.9,68.19 95.16,68.19
  BOTTOM w0.089: v2(89.26,64.39) UC1.R13
  BOTTOM w0.114: JWLAN1.3 78.26,122.05 78.13,122.18 77.22,122.18 v2(77.05,122.01)
USB20_P4: length 142.1
  IN2 w0.127: v2(102.15,50.63) 102.16,50.63 102.48,50.95 103.01,50.95 104.79,49.17 114.82,49.17 117.65,46.34 120.48,46.34 121.09,46.95 122.19,46.95 123.31,45.83 125.26,45.83 126.25,44.84 134.27,44.84 135.07,44.04 137.06,44.04 139.07,42.03 146.79,42.03 150.16,38.67 173.52,38.67 174.12,38.07 176.99,38.07 177.98,37.09 178.19,37.09 178.81,37.09 180.29,35.61 202.14,35.61 204.9,38.38 204.9,40.81 203.79,41.92 203.79,48.21 203.89,48.31 204.08,48.31 v2(204.24,48.15)
  BOTTOM w0.089: UC1.M1 90.33,59.28 90.33,57.79 91.08,57.04 91.08,56.12 91.05,56.09 91.05,56.07
  BOTTOM w0.114: 91.05,56.07 91.05,55.41 93.12,53.34 95.41,53.34 96.37,52.38 96.37,50.62 96.95,50.03 100.68,50.03 101.62,50.97 101.81,50.97 v2(102.15,50.63) ; R17.2 205.12,48.2 L3.1 204.82,48.2 204.69,48.32 204.41,48.32 v2(204.24,48.15)
USB20_P4_R: length 10.3
  BOTTOM w0.114: JEDP1.34 211.98,43.95 211.86,44.08 211.38,44.08 v4(211.19,44.27) 210.83,44.63 210.83,45.99 210.44,46.38 209.47,46.38 209.36,46.27 D11.3 208.87,46.12 208.87,46.49 208.7,46.67 208.5,46.67 207.81,47.37 207.81,47.81 207.43,48.2 L3.2 206.3,48.2 R17.1
USB20_P5: length 133.4
  IN2 w0.127: v2(201.49,40.54) 201.32,40.37 201.32,39.42 199.74,37.84 186.18,37.84 185.34,37 181.59,37 179.13,39.46 175.02,39.46 174.37,40.11 150.69,40.11 146.78,44.02 139.06,44.02 137.64,45.43 135.64,45.43 134.73,46.35 127.48,46.35 126.34,47.49 124.69,47.49 123.06,49.13 118.33,49.13 116.8,50.66 107.17,50.66 103.82,54.01 99.48,54.01 98.74,53.27 94.13,53.27 91.39,50.53 90.89,50.53 v2(90.76,50.4)
  BOTTOM w0.089: UC1.R2 88.94,59.6 88.94,56.99 88.86,56.91 88.86,56.85 88.84,56.84 88.84,56.83
  BOTTOM w0.114: v2(90.76,50.4) 90.01,50.4 88.8,51.61 88.8,56.04 88.84,56.08 88.84,56.83 ; v2(201.49,40.54) 201.32,40.71 201.32,41.33 201.45,41.46 L4.1 201.45,41.76 R20.2
USB20_P5_R: length 19.2
  TOP w0.114: v2(201.34,44.76) 201.33,44.76 201.1,44.53 201.1,44.29 201.62,43.77 202.26,43.77 202.37,43.89 R85.2
  BOTTOM w0.114: JEDP1.37 211.96,42.45 211.71,42.7 211.37,42.7 211.12,42.96 211.12,43.33 210.12,44.32 204.35,44.32 203.09,45.58 202.88,45.58 202.75,45.44 202.75,44.8 DA6.2 201.68,45.51 201.38,45.51 201.14,45.27 201.14,44.97 v2(201.34,44.76) 201.2,44.62 201.2,43.65 201.45,43.4 L4.2 201.45,42.94 R20.1
USB20_P6: length 151.1
  IN2 w0.127: v2(94.46,50.94) 94.54,51.02 95.38,51.02 100.92,45.49 100.92,39.84 101.48,39.27 101.48,36.76 109.17,29.07 134.71,29.07 137.96,32.32 149.82,32.32 152.55,35.04 175.59,35.04 176.66,33.98 177.25,33.98 179.24,31.99 205.01,31.99 209.16,36.14 209.16,38.78 208.8,39.15 v2(208.12,39.15)
  BOTTOM w0.089: UC1.P1 89.49,59.21 89.49,59.09 89.42,59.01 89.42,57.41 89.59,57.25 89.59,56.14 89.55,56.1 89.55,56.08
  BOTTOM w0.114: RU26.1 209.06,39.21 LU13.2 208.69,39.11 208.56,38.98 208.29,38.98 v2(208.12,39.15) ; v2(94.46,50.94) 94.36,51.04 91.83,51.04 89.55,53.32 89.55,56.08
USB20_P6_R: length 3.3
  BOTTOM w0.114: RU26.2 210.11,39.11 LU13.1 210.48,39.11 210.6,38.98 210.87,38.98 211.2,38.66 v4(211.2,38.16) JIOB1.3
USB20_P7: length 197.8
  IN2 w0.127: v2(88.3,62.09) 88.08,62.3 87.72,62.3 87.49,62.54 85.6,62.54 85.36,62.31 82.67,62.31 81.76,61.4 80.68,61.4 78.77,59.49 78.77,58.58 76.33,56.14 76.33,54.84 v2(76.49,54.68) ; v2(213.65,35.73) 213.49,35.57 209.53,35.57 205.33,31.36 178.45,31.36 175.33,34.48 175.2,34.61 152.73,34.61 150,31.89 138.54,31.89 134.34,27.68 108.62,27.68 102.84,33.46 100.94,33.46 100.48,33.91 100.48,44.71 95.08,50.11 94.61,50.11 v2(94.45,50.27)
  BOTTOM w0.114: v2(76.49,54.68) 76.33,54.52 76.33,53.55 83.92,45.97 88.55,45.97 89.25,46.67 89.25,48.76 89.76,49.27 91.41,49.27 92.24,50.1 94.28,50.1 v2(94.45,50.27) ; JFP1.5 219,31.36 218.75,31.61 218.75,32.81 220.37,34.44 220.37,35.4 219.78,35.99 219.33,35.99 219.21,36.11 219.21,36.77 EU2701.3 218.07,36.02 216.24,36.02 215.78,35.56 213.82,35.56 v2(213.65,35.73) ; UC1.U8 88.26,62.09 v2(88.3,62.09)
USB20_VCC: length 0.6
  TOP w0.102: v2(196.95,36.57) v3(197.52,36.57)
USB30_VCCA:
  vias: v2(15.78,42.35) v2(15.78,41.71) v2(15.78,41.08) v2(18.64,55.88) v2(19.27,57.21) v2(19.27,56.64) v2(19.27,55.88) v3(16.35,43.68) v3(19.15,52.38) v3(19.27,46.29)
USB_EN#: length 217.3
  TOP w0.102: v2(33.37,27.62) v3(32.13,28.86) 31.47,29.52 31.47,30.86 30.01,32.32 26.77,32.32 22.77,36.32 22.77,38.92 22.2,39.49 21.15,39.49 21.05,39.59 UU2.4
  IN1 w0.127: v2(192.31,39.45) 191.65,38.79 188.14,38.79 186.5,40.43 179.55,40.43 178.27,41.71 176.18,41.71 174.85,40.38 162.98,40.38 162.19,39.59 143.37,39.59 141.38,41.59 139.23,41.59 138.04,42.78 133.99,42.78 133.28,43.49 132.43,43.49 131.67,42.73 123.11,42.73 121.11,44.74 v2(120.94,44.74) 120.94,44.74 120.11,45.57 119.08,45.57 117.32,43.81 117.32,41.84 115.99,40.51 115.99,39.68 115.16,38.86 111.29,38.86 110.84,39.3 109.63,39.3 108.65,38.32 108.65,38.14 106.63,36.13 98.31,36.13 97.83,36.61 90.1,36.61 88.17,38.54 88.17,40.38 79.52,49.03 57.05,49.03 53.29,45.27 49.04,45.27 42.71,38.94 42.71,33.93 37.47,28.7 34.45,28.7 v2(33.37,27.62)
  BOTTOM w0.102: v2(120.94,44.74) 119.26,46.42 UE1.84 117,46.42 116.57,46.85 RE30.2 ; UU3.4 194.72,39.87 192.73,39.87 v2(192.31,39.45)
USB_OC0#: length 212
  TOP w0.102: v2(102.46,89.28) 102.46,88.54 101.23,87.31 99.87,87.31 98.36,85.8 96.26,85.8 95.71,86.35 95.71,88.03 94.9,88.83 93.19,88.83 92.99,89.03 v2(91.99,89.03) 91.98,89.02 90.9,89.02 90.41,88.53 90.41,86.19 90.49,86.1 90.49,85.44 90.06,85.01 v2(88.27,85.01) ; v2(27.72,27.74) 26.7,28.76 24.93,28.76 v3(22.51,31.17) 22.51,38.86 22.08,39.29 21.23,39.29 21.05,39.11 UU2.3 ; v2(61.3,30.74) 61.31,30.74 61.31,31.08 62.55,32.32 64.43,32.32 64.43,32.32 64.76,32.32 64.76,32.32 65.61,32.32 65.86,32.57 73.7,32.57 73.7,32.57 78.76,32.57 79.72,31.62 113.89,31.62 118.59,36.32 118.59,38.73 119.16,39.3 119.16,47.7 121.11,49.65 121.11,51.68 121.33,51.9 121.33,54.74 121.57,54.98 121.57,58.01 123,59.43 v2(125,59.43)
  IN1 w0.127: v2(102.46,89.28) 103.24,89.28 103.74,89.78 107.76,89.78 108.45,90.46 112.1,90.46 118.91,83.65 118.91,68.13 125,62.04 v2(125,59.43)
  IN2 w0.127: v2(61.3,30.74) 60.15,29.59 57.88,29.59 56.99,28.7 50.96,28.7 50.73,28.47 43.44,28.47 42.6,27.63 40.24,27.63 40.23,27.63 40.02,27.63 40.01,27.63 39.22,27.63 38.28,28.57 28.55,28.57 v2(27.72,27.74)
  BOTTOM w0.089: UC1.U54 88.05,83.16 88.14,83.24 88.14,83.72 87.89,83.97 87.89,84.63 v2(88.27,85.01)
  BOTTOM w0.102: v2(91.99,89.03) 92.3,89.34 RC80.2
USB_OC1#: length 193.9
  TOP w0.102: v2(202.35,53.46) 202.22,53.59 202.22,58.35 200,60.57 v2(199.65,60.57) ; v2(88.3,84.42) 88.68,84.79 90.17,84.79 90.7,85.32 90.7,86.23 90.61,86.32 90.61,88.29 90.93,88.61 v2(92.39,88.61) v1(92.93,88.61) 94.79,88.61 95.51,87.89 95.51,86.26 96.17,85.59 98.44,85.59 99.93,87.08 101.35,87.08 102.9,88.63 102.9,89.47 v2(102.46,89.91)
  IN1 w0.127: v2(102.46,89.91) 102.8,89.57 103.18,89.57 103.64,90.03 107.66,90.03 108.34,90.71 112.21,90.71 119.16,83.76 119.16,68.24 127.2,60.19 128.11,60.19 128.39,59.91 128.39,58.26 129.7,56.95 129.7,54.86 130.4,54.16 131.92,54.16 132.37,54.61 132.39,54.61 132.48,54.69 134.54,54.69 135.74,54.69 138.13,54.69 138.89,53.93 147.86,53.93 151,50.8 152.31,50.8 152.94,50.16 152.94,50 153.65,49.29 158.9,49.29 160.68,51.07 163.3,51.07 165.03,51.07 168.33,54.38 171.24,54.38 173.75,56.89 176.94,56.89 177.09,57.04 177.73,57.04 181.31,57.04 182.86,58.59 187.78,58.59 188.15,58.59 189.36,57.39 190.27,57.39 190.67,56.99 191.92,56.99 194.08,59.15 197.9,59.15 199.32,60.57 v2(199.65,60.57) ; v2(193.66,39.42) 193.66,40.15 195.55,42.03 199.04,42.03 199.4,42.39 201.35,42.39 202.28,43.32 202.28,49.19 204.44,51.35 204.44,52.43 203.4,53.46 v2(202.35,53.46)
  BOTTOM w0.089: 88.31,83.93 88.31,83.17 88.23,83.08 88.23,82.94 arc(88.24,82.86) 88.27,82.78 arc(88.3,82.73) 88.31,82.68 88.32,82.67 arc(88.32,82.64) 88.32,82.62 arc(88.31,82.55) 88.28,82.48 UC1.U53
  BOTTOM w0.102: RC79.2 92.87,89.52 92.87,89.08 v2(92.39,88.61) ; UU3.3 194.79,38.3 v2(193.66,39.42) ; 88.31,83.93 88.31,84.41 v2(88.3,84.42)
VCIN0_PH1: length 88.4
  TOP w0.254: PH1.1 86.61,59.38 86.61,55.7 89.29,53.02 89.29,42.64 88.43,41.78 88.43,38.54 93.53,33.44 102.76,33.44 103.15,33.83 105.01,33.83 105.4,33.44 v1(111.54,33.44) 111.83,33.44 113.8,35.41 113.8,36.28 v2(113.31,36.77)
  IN1 w0.127: v2(127.87,41.52) 127.5,41.89 122.71,41.89 120.98,43.62 119.52,43.62 119.03,43.13 119.03,39.62 116.62,37.21 113.74,37.21 v2(113.31,36.77)
  BOTTOM w0.102: PR9.2 v2(113.31,36.77) ; UE1.109 124.68,51.56 125.19,51.05 126.7,51.05 127.28,50.46 127.28,48.82 127.01,48.55 127.01,47.01 127.71,46.31 127.71,42.85 127.87,42.69 v2(127.87,41.52)
VCIN1_AC_IN: length 4
  BOTTOM w0.102: UE1.110 125.08,53.89 124.4,54.57 v1(124.4,54.57) 124.4,55.21 124.63,55.44 CE20.2 RE21.1
VCIN1_BATT_TEMP: length 102.3
  TOP w0.203: PR39.2 165.82,38.25 v2(165.85,38.22)
  TOP w0.254: PRB24.2 200.69,51.77 201.23,52.31 201.86,52.31 202.09,52.08 202.09,49.9 201.18,48.98 201.18,47.99 196.18,42.99 195.37,42.99 194.79,42.41 PC14.1 194.42,42.87 194.88,43.33 194.88,44.1 194.27,44.71 188.26,44.71 187.68,44.13 181.12,44.13 177.31,40.32 v3(169.33,40.32) 167.8,40.32 167.54,40.06 PD6.2 165.9,40.06 165.85,40 PR41.1 PR39.2
  IN1 w0.203: v2(136.81,35.25) 136.81,35.25 136.88,35.17 136.97,35.17 137.26,35.47 163.09,35.47 v2(165.85,38.22)
  BOTTOM w0.203: UE1.63 120.28,36.17 119.87,35.76 CE17.2 120.24,35.62 120.62,36 122.02,36 122.72,35.3 125.7,35.3 128,33 134.32,33 136.56,35.24 136.81,35.24 136.81,35.25 v2(136.81,35.25)
VCIN1_BATT_TEMP_R: length 2.7
  TOP w0.254: PR39.1 164.91,38.27 v2(164.95,38.23)
  BOTTOM w0.254: v2(164.95,38.23) 164.95,38.23 PBATT1.5
VCLK_VCCGI: length 2.2
  BOTTOM w0.203: PRG09.1 100.34,136.89 99.93,136.48 PUG1.6
VCLK_VNN: length 1.8
  BOTTOM w0.203: PRZ11.1 88.51,132.23 PUZ1.6
VCOUT0_MAIN_PWR_ON: length 117.7
  TOP w0.102: v2(122.75,54.42) v1(122.75,54.96)
  IN1 w0.127: v2(141.96,50.6) 141.79,50.77 137.83,50.77 137.23,51.37 133.17,51.37 132.09,50.29 127.99,50.29 126.09,52.19 125.09,52.19 122.87,54.42 v2(122.75,54.42)
  IN2 w0.127: v2(208.7,85.05) 205.93,85.05 205.39,84.51 200.12,84.51 197.27,81.66 197.27,70.39 195.64,68.77 190.53,68.77 189.07,67.31 184.69,67.31 182.85,65.46 178.41,65.46 175.68,62.73 157.88,62.73 157.13,61.98 v2(157.13,57.23)
  BOTTOM w0.102: UE1.104 122.68,53.68 123.14,54.14 123.14,55.06 123.03,55.16 CE4.1 122.75,55.08 v2(122.75,54.42) ; v2(157.13,57.23) 155.93,56.03 153.79,56.03 148.81,51.05 142.34,51.05 141.96,50.67 v2(141.96,50.6)
  BOTTOM w0.254: v2(208.7,85.05) 209.57,85.05 PR507.1
VCOUT1_PROCHOT#: length 6
  BOTTOM w0.102: UE1.103 122.28,53.83 122.12,54 121.97,54 121.05,54.92 CE3.1 CE21.2 RE19.1 121.05,57 120.58,57.46 v1(119.99,57.46)
VL: length 2.9
  BOTTOM w0.102: PC515.1 v1(207.95,82.79)
  BOTTOM w0.254: PU501.15 206.36,81.67 206.92,82.23 PC515.1
VLP_DIS: length 6.4
  TOP w0.102: v1(129.69,57.84) 129.19,57.35 CE37.2 RE54.1 127.67,56.18 U15.4 127.67,55.22 127.71,55.17 v2(127.71,54.34)
  BOTTOM w0.102: UE1.116 127.48,53.67 127.71,53.9 v2(127.71,54.34)
VNN_EN: length 136.6
  TOP w0.102: v2(90.84,135.82) 90.64,135.82 PRZ40.2 ; v2(125.95,59.75) 125.95,59.15 125.41,58.61 122.46,58.61 121.78,57.92 121.78,54.9 121.53,54.66 121.53,52.99 123.1,51.43 123.1,50.29 v1(121.41,48.6) 119.89,47.09 v2(119.82,47.09)
  IN2 w0.127: v2(125.95,59.75) 125.95,60.38 117.06,69.27 117.06,91.67 114.46,94.27 114.46,100.54 110.74,104.26 107.1,104.26 103.86,107.5 103.86,108.91 103.34,109.43 103.34,122.2 102.74,122.8 102.74,128.35 103.45,129.06 103.45,140.29 102.62,141.12 101.39,141.12 100.85,141.66 100.85,143.26 98.67,145.44 95.3,145.44 95.3,145.44 94.88,145.44 94.46,145.44 91.77,142.74 91.77,140.91 91.6,140.75 91.6,140.53 91.6,136.58 v2(90.84,135.82)
  BOTTOM w0.102: v2(119.82,47.09) 119.69,47.22 UE1.86
VNN_N01: length 2.3
  TOP w0.102: v1(86.97,139.59) 86.65,139.27 86.65,138.54 PRZ35.1
  TOP w0.254: PRZ16.2 86.84,138.35 PRZ35.1
VNN_N02: length 31.8
  TOP w0.254: v2(80.16,125.32) 80.81,124.68 80.81,117.66 83.24,115.22 85.04,115.22 v2(85.51,115.69) ; v2(82.79,135.31) 81.93,135.31 80.76,136.48 79.56,136.48 78.72,135.64 78.72,128.99 v2(77.9,128.17)
  IN1 w0.254: v2(77.9,128.17) 77.9,128.16 77.9,127.9 80.16,125.64 v2(80.16,125.32)
  BOTTOM w0.254: PLZ1.2 v2(85.51,115.69) ; PRZ42.1 v2(82.79,135.31)
VNN_N03: length 2
  TOP w0.102: v1(87.71,132.15) PRZ36.1
  TOP w0.254: PRZ36.1 87.71,133.41 87.46,133.66 PRZ15.2
VNN_N04: length 2.4
  TOP w0.102: PRZ37.1 85.06,138.48 84.11,139.43 v1(84.11,139.5)
  TOP w0.254: PRZ37.1 PRZ17.2
VNN_N05: length 2.1
  TOP w0.102: PRZ03.2 88.48,138.29 v1(88.98,138.8)
  TOP w0.254: PRZ03.2 88.24,137.55 PRZ07.1
VNN_N06: length 1.7
  TOP w0.102: v1(82.93,129.05) PRZ38.1
  TOP w0.254: PRZ38.1 PRZ31.2
VNN_N07: length 21.2
  TOP w0.254: PRZ39.1 82.32,136.33 81.83,136.33 v1(81.59,136.57) 81.37,136.79 v2(81.14,136.79)
  IN1 w0.254: v2(81.63,119.25) 81.11,119.77 81.11,126.9 80.58,127.43 80.58,133.89 81.16,134.48 81.16,136.76 v2(81.14,136.79)
  BOTTOM w0.254: v2(81.63,119.25) 82.57,119.25 PHZ1.2
VNN_N08: length 0.8
  BOTTOM w0.254: PRZ24.1 PRZ21.2
VNN_N09: length 4.6
  TOP w0.102: PRZ40.1 90.95,134.35 v1(91.03,134.42)
  TOP w0.254: v2(88.58,134.07) 88.74,133.91 88.77,133.91 88.87,133.82 89.77,133.82 90.08,134.12 PRZ40.1
  BOTTOM w0.203: PUZ1.2 88.21,133.83 88.45,134.07 v2(88.58,134.07) 88.68,134.17 PCZ08.2
VNN_N10: length 3
  TOP w0.102: v1(85.64,140.2) 85.52,140.08 85.52,138.73 85.9,138.35 PRZ04.2
  TOP w0.254: PRZ04.2 PRZ08.1
VNN_N11: length 0.8
  TOP w0.254: PRZ41.1 88.43,136.46 88.48,136.51 PRZ02.2
VNN_N13: length 10.8
  TOP w0.254: v2(82.76,130.95) 82.51,130.69 PRZ30.2 PRZ29.2 81.11,129.89 PRZ31.1
  IN1 w0.254: v2(82.76,130.95) 82.84,130.87 82.84,127.47 82.08,126.71 82.08,123.81 v2(81.97,123.71)
  BOTTOM w0.254: PHG2.2 81.95,123.73 v2(81.97,123.71)
VNN_N14: length 0.8
  TOP w0.254: PRZ29.1 81.11,132.42 PRZ28.2
VNN_N15: length 2.2
  BOTTOM w0.102: PRZ25.2 82.61,128.23 82.61,128.14 82.52,128.14 82.18,127.8 81.26,127.8 v1(81.22,127.76)
VNN_SENSE: length 60.2
  TOP w0.254: v2(78.87,108.17) 78.88,108.17 v1(78.88,120.01) 78.88,128.05 79.76,128.94 79.76,132.71 79.31,133.17 PRZ43.2
  IN1 w0.102: v2(82.16,77.31) 81.53,77.94 81.53,78.88 81.24,79.18
  IN1 w0.254: v2(78.87,108.17) 78.9,108.13 78.9,107.53 78.89,107.52 78.89,102.24 81.57,99.56 81.57,94.95 80.36,93.74 80.36,88.62 80.93,88.05 80.93,84.79 81.77,83.96 81.77,83.27 81.24,82.74 81.24,79.18
  BOTTOM w0.203: v2(82.16,77.31) UC1.AJ41
VNN_SENSE_N: length 60.8
  TOP w0.254: PRZ01.1 81.66,133.42 81.66,133.41 81.51,133.26 81.49,133.26 81.26,133.03 80.53,133.03 80.27,132.77 80.27,128.73 79.38,127.84 v1(79.38,117.66) 79.38,107.84 v2(79.73,107.5)
  IN1 w0.102: v2(82.16,78.02) 82.09,78.02 81.75,78.36 81.75,79.32 81.63,79.43
  IN1 w0.254: v2(79.73,107.5) 79.4,107.17 79.4,102.45 82.08,99.77 82.08,94.74 80.87,93.53 80.87,88.83 81.44,88.26 81.44,85 82.28,84.17 82.28,83.06 81.63,82.42 81.63,79.43
  BOTTOM w0.203: v2(82.16,78.02) UC1.AJ43
VNN_VGATE: length 122.7
  TOP w0.102: v2(122.68,61.46) 122.68,60.35 121.74,59.41 120.44,59.41 119.8,58.77 119.8,55.21 v1(119.93,55.08) 120.06,54.96 120.06,51.89 117.38,49.22 117.38,48.83 v2(116.97,48.41)
  IN2 w0.127: v2(90.86,130.31) 90.87,130.31 92.36,131.81 92.36,133.64 93.23,134.51 95.43,134.51 96.66,135.73 101.56,135.73 101.85,135.44 101.85,122.43 102.45,121.84 102.45,109.04 102.97,108.52 102.97,107.31 106.78,103.5 110.15,103.5 110.28,103.37 110.37,103.37 113.49,100.25 113.49,93.88 116.18,91.19 116.18,90.92 116.18,90.92 116.18,69.08 122.68,62.58 v2(122.68,61.46)
  BOTTOM w0.102: UE1.85 117.31,46.82 117.06,47.06 117.06,47.32 CE8.1 116.57,48.01 v2(116.97,48.41)
  BOTTOM w0.203: PRZ34.1 88.6,131.25 88.6,131.55 88.33,131.83 PUZ1.7
  BOTTOM w0.254: PRZ34.1 89.24,130.41 89.59,130.06 90.61,130.06 v2(90.86,130.31)
VR_HOT#: length 125.7
  TOP w0.102: v2(123.49,60.65) v1(123.49,61.15)
  TOP w0.254: PRG25.2 100.69,139.23 100.41,138.95 100.41,138.67 v2(100.36,138.67) ; PRZ20.2 89.04,134.63 88.38,134.63 88.02,134.27 88.02,133.76 88.36,133.43 v2(88.57,133.43)
  IN1 w0.254: v2(88.57,133.43) 88.93,133.43 89.38,133.88 89.38,141.48 92.06,144.15 98.59,144.15 100.41,142.32 100.41,138.67 v2(100.36,138.67)
  IN2 w0.127: v2(100.36,138.67) 100.36,138.06 102.17,136.25 102.17,122.56 102.78,121.95 102.78,109.16 103.29,108.65 103.29,107.35 106.88,103.75 110.44,103.75 113.89,100.3 113.89,93.92 116.49,91.32 116.49,69.13 123.49,62.13 v2(123.49,60.65)
  BOTTOM w0.203: v2(100.36,138.67) 100.38,138.65 100.38,138.5 99.56,137.68 PUG1.3 ; PUZ1.3 v2(88.57,133.43)
  BOTTOM w0.254: RE20.1 121.05,58.21 v2(123.49,60.65)
VREF_VCCGI: length 19.1
  TOP w0.254: PRG24.1 93.68,136.44 v2(94.01,136.77) ; PRG03.1 95.74,142.88 v2(96.2,143.34) 96.45,143.59 99.01,143.59 99.06,143.54 v1(99.16,143.54) 99.89,143.54 100.53,142.91 PRG02.1 PRG01.1
  IN2 w0.254: v2(96.2,143.34) 96.2,141.37 94.75,139.92 94.75,137.51 v2(94.01,136.77)
  BOTTOM w0.203: v2(94.01,136.77) 94.12,136.88 PUG1.17
  BOTTOM w0.254: PRG28.1 92.87,137.3 PRG29.2 93.76,136.52 v2(94.01,136.77)
VREF_VNN: length 20
  TOP w0.254: PRZ28.1 82.15,132.29 82.62,132.29 v2(82.62,132.27) ; PRZ04.1 v2(86.01,139.86) 86.24,140.09 v1(88.3,140.09) 88.48,140.09 89.06,139.5 89.06,139.47 89.39,139.14 PRZ03.1 PRZ02.1
  IN1 w0.254: v2(82.62,132.27) 83.17,132.27 83.85,132.95 83.85,134.3 84.95,135.39 84.95,137.98 86.01,139.05 v2(86.01,139.86)
  BOTTOM w0.203: v2(82.62,132.27) 82.74,132.27 83.1,132.63 PUZ1.17
  BOTTOM w0.254: PRZ21.1 81.31,133.12 PRZ22.2 82.16,132.27 v2(82.62,132.27)
VSEN_VCCGI: length 9.7
  TOP w0.254: v2(96.83,140.34) 96.35,139.86 PCG04.1 95.83,140.33 94.19,140.33 v1(94.08,140.22) 93.51,140.22 93.48,140.19 PRG43.1 93.13,140.22 PRG19.1
  BOTTOM w0.203: PCG11.2 97.58,140.77 97.27,140.77 v2(96.83,140.34) 96.83,140.14 97.06,139.91 PUG1.25
  BOTTOM w0.254: PCG08.1 98.57,142.24 PRG18.2 PCG11.2
VSEN_VNN: length 15.1
  TOP w0.254: v2(80.68,135.27) 80.22,134.81 PRZ12.1 PRZ43.1 80.93,133.59 PCZ18.1
  IN2 w0.254: v2(85.63,136) 84.41,134.78 82.36,134.78 81.87,135.27 v2(80.68,135.27)
  BOTTOM w0.102: v1(88.73,138.43) 88.23,138.92 PCZ17.1
  BOTTOM w0.203: PUZ1.25 85.7,135.96 85.66,136 v2(85.63,136)
  BOTTOM w0.254: PCZ17.1 87.79,138.06 PRZ10.2 PCZ05.2 87.22,136.63 86.01,136.63 85.63,136.25 v2(85.63,136)
VTTREF_1.2V: length 3.5
  TOP w0.203: PUM01.4 27.38,117.49 v1(27.59,117.28)
  TOP w0.254: v1(27.59,117.28) 27.83,117.04 27.83,115.82 PCM19.1
WHITE_LED_BAT: length 4.9
  TOP w0.102: v1(5.69,121.09) 6.61,122.02 Q19.1
  TOP w0.254: R69.2 C41.1 5.04,123.33 5.62,122.74 Q19.1
WLAN_PWR_EN: length 137.2
  TOP w0.102: QW1.3 v2(62.96,133.98) ; v2(134.73,56.89) v1(134.73,57.39)
  IN1 w0.127: v2(134.73,56.89) 135.54,57.7 135.54,59.24 134.72,60.07 130.06,60.07 128.66,61.46 127.73,61.46 120.43,68.77 120.43,84.28 109.62,95.09 97.47,95.09 92.64,99.92 92.64,103.6 93.25,104.21 93.25,104.28 93.25,105.86 93.25,106.07 93.25,106.07 93.25,106.28 93.25,106.28 93.25,106.42 90.71,108.96 87.4,108.96 87.17,109.19 83.24,109.19 82.39,110.04 82.39,117.09 79.08,120.4 79.08,124.4 76.87,126.61 76.87,130.3 74.99,132.18 74.99,133.32 74.48,133.83 73.43,133.83 73.11,134.15 71.41,134.15 71.09,133.83 63.11,133.83 v2(62.96,133.98)
  BOTTOM w0.102: UE1.1 134.5,51.22 134.59,51.3 134.59,56.75 v2(134.73,56.89)
WLAN_RADIO_DIS#: length 74.4
  TOP w0.102: v2(74.2,133.03) 74.89,133.71 74.89,135.2 v1(74.32,135.77) 74.13,135.96 72.21,135.96 RW3.2
  IN1 w0.127: v2(74.2,133.03) 73.76,132.58 73.76,131.96 73,131.2 73,124.39 75.03,122.36 75.03,117.15 76.93,115.25 76.93,111.25 82.84,105.34 83.32,105.34 83.53,105.34 83.71,105.34 84.34,105.34 84.55,105.34 85.2,105.34 85.41,105.34 85.42,105.34 85.78,105.34 85.99,105.34 87.06,104.27 87.06,97.94 87.06,97.67 88.11,96.62 88.11,91.36 89.98,89.49 89.98,87.94 89.37,87.33 89.37,86.11 89.44,86.04 89.44,85.59 90.59,84.45 90.59,82.74 89.62,81.77 89.62,81.09 89.84,80.87 89.84,78.54 90.27,78.12 90.27,77.97 90.52,77.72 91.94,77.72 92.42,78.2 v2(92.45,78.2)
  BOTTOM w0.089: UC1.H43 92.17,77.92 v2(92.45,78.2)
WLAN_RADIO_DIS#_R: length 4.1
  TOP w0.102: RW27.1 70.19,135.44 v2(70.33,135.3) 70.44,135.3 70.77,135.63 70.96,135.63 RW3.1 71.27,135.94 v1(71.27,136.9)
  BOTTOM w0.102: v2(70.33,135.3) JWLAN1.56
WOL_EN: length 179.3
  TOP w0.102: v2(122.11,51.11) 122.11,50.36 119.36,47.62 119.36,39.2 118.84,38.68 v1(118.84,35.81) 116.98,33.94 116.98,33.56 116.31,32.89 115.91,32.89 114.44,31.42 79.63,31.42 78.68,32.37 73.61,32.37 65.95,32.37 65.69,32.11 64.68,32.11 64.68,32.11 64.51,32.11 62.64,32.11 61.88,31.36 61.88,30.67 61.72,30.5 61.72,30.5 61.48,30.26 61.48,30.26 v2(61.38,30.16) ; v2(26.83,77.27) 23.97,77.27 23.72,77.02 23.4,77.02 22.25,75.87 RL6.2 21.75,75.81 21.51,76.06 UL2.4
  IN1 w0.127: v2(26.83,77.27) 26.32,76.77 26.32,73 26.07,72.75 26.07,48 22.96,44.89 22.96,31.43 23.5,30.88 23.96,30.88 24.03,30.96 25.59,30.96 25.82,30.73 v2(25.82,30.54)
  IN2 w0.127: v2(61.38,30.16) 59.28,28.06 53.56,28.06 52.88,27.38 49.19,27.38 48.36,28.21 43.54,28.21 42.71,27.38 40.26,27.38 40.26,27.38 39.99,27.38 39.99,27.38 39.21,27.38 39.21,27.38 39.11,27.38 38.92,27.18 37.7,27.18 26.06,27.18 25.57,27.67 25.57,30.23 25.82,30.48 v2(25.82,30.54)
  BOTTOM w0.102: UE1.98 120.28,51.72 120.46,51.54 121.67,51.54 v2(122.11,51.11)
XCLKI: length 5.7
  BOTTOM w0.102: UE1.122 129.88,53.98 129.64,54.22 v1(129.64,54.41) 129.76,54.54 130.46,54.54 130.57,54.64 YE1.3 130.57,55.9 129.46,57.01 RE31.2
XDP_PBTN_OUT#: length 3.4
  TOP w0.102: T53.1 69.63,109.02 69.64,109.04 RC142.2 69.64,110.76 UC5.1 70.33,110.79 CC92.2
XDP_PLTRST#_B_R: length 54.3
  TOP w0.102: v2(73.69,112.83) 73.69,111.56 73.12,110.99 v1(72.3,110.99) 71.54,110.99 70.84,110.29 70.84,108.07 70.3,107.54 68.32,107.54 67.85,108.01 UC6.2
  IN1 w0.127: v2(98.79,90.55) 98.79,90.5 98.14,89.85 96.43,89.85 96.05,90.23 96.05,90.84 92.57,94.31 92.57,97.2 90.74,99.03 90.74,104.39 91.35,105 91.35,105.07 91.35,105.49 91.35,105.49 91.35,105.63 90.24,106.74 89.55,106.74 89.17,106.36 87.66,106.36 86.48,107.54 82.12,107.54 78.39,111.27 v2(78.39,112.64)
  BOTTOM w0.102: v2(78.39,112.64) 78.21,112.83 v2(73.69,112.83) ; v2(98.79,90.55) 98.78,90.55 98.78,90.18 RC48.2
XDP_PLTRST#_R: length 2.7
  TOP w0.102: RC140.2 66.04,108.98 66.04,108.76 65.94,108.66 UC6.4 64.63,108.66 T38.1
XDP_PRDY#: length 38.7
  TOP w0.102: v2(79.71,99.14) 79.71,98.85 75.84,94.98 69.39,94.98 66.77,97.59 66.77,97.59 66.66,97.71 64.98,97.71 64.36,97.08 64.36,96.59 RC155.1 63.41,95.64 T46.1
  BOTTOM w0.089: UC1.AH55 83.07,82.96 83.07,83.88 83.33,84.15 83.33,85.42 83.07,85.68 83.07,86.16
  BOTTOM w0.102: v2(79.71,99.14) 79.89,99.14 80.62,98.42 80.62,97.83 81.64,96.81 81.64,96.3 81.76,96.18 81.76,92.49 83.07,91.18 83.07,86.16
XDP_PREQ#: length 35.4
  TOP w0.102: v2(65.25,98.78) 65.08,98.61 T51.1
  BOTTOM w0.089: UC1.AJ53 82.83,82.42 82.9,82.52 82.9,82.72 82.83,82.83 82.83,83.05 82.85,83.07 82.85,83.92 83.16,84.22 83.16,85.29 82.86,85.58 82.86,86.16
  BOTTOM w0.102: 82.86,86.16 82.86,91.09 81.56,92.4 81.56,96.09 81.43,96.21 81.43,96.7 80.12,98.01 RC114.2 80.12,98.06 79.76,98.43 79.69,98.43 79.37,98.75 76.88,98.75 74.52,96.39 69.44,96.39 67.03,98.8 65.27,98.8 v2(65.25,98.78)
XDP_RSMRST#_B_R: length 57.1
  TOP w0.102: UC7.2 v2(65.61,111.5) ; v2(102.94,82.01) 103.42,81.53 RC47.2
  IN1 w0.127: v2(65.61,111.5) 71.28,111.5 72.73,110.05 74.19,110.05 v2(74.84,109.41)
  IN2 w0.127: v2(102.94,82.01) 102.9,82.04 102.9,84.49 101.91,85.48 101.91,85.97 101.91,87.1 102.14,87.33 102.14,88.26 102.14,88.9 101.82,89.21 101.82,90.78 99.43,93.18 98.09,93.18 97.85,93.42 95.56,93.42 94.92,93.42 94.17,93.42 88.73,98.86 82.98,98.86 81.47,100.37 78.98,102.86 78.98,103.09 74.84,107.23 v2(74.84,109.41)
XDP_RSMRST#_R: length 2.8
  TOP w0.102: T36.1 64.62,112.14 UC7.4 64.82,112.15 65.2,112.53 RC141.2
XDP_TCK0: length 16.7
  TOP w0.102: v2(78.14,94.04) 77.82,94.04 T42.1
  BOTTOM w0.089: UC1.AM53 81.39,82.42 81.39,82.66 81.68,82.95 81.68,86.16
  BOTTOM w0.102: RC115.1 77.38,95.36 77.38,94.43 77.77,94.04 v2(78.14,94.04) 78.14,93.73 81.9,89.97 81.9,86.95 81.68,86.73 81.68,86.16
XDP_TDI: length 32.3
  TOP w0.102: v2(80.81,95.88) 78.12,95.88 76.21,93.98 66.65,93.98 T43.1
  BOTTOM w0.089: 82.66,86.16 82.66,85.48 82.98,85.16 82.98,84.3 82.67,83.99 82.67,83.16 82.64,83.12 UC1.AJ54
  BOTTOM w0.102: 82.66,86.16 82.66,91.01 81.25,92.42 81.25,95.44 v2(80.81,95.88) 80.48,95.88 RC111.1
XDP_TDO: length 32.7
  TOP w0.102: v2(62.52,96.54) 61.73,96.54 RC156.2 61.71,95.75 61.69,95.74 T48.1
  BOTTOM w0.089: UC1.AL53 81.22,82 81.01,82.22 81.01,82.41 81.09,82.49 81.09,82.73 81.02,82.8 81.02,83.04 81.05,83.07 81.05,83.41 80.87,83.59 80.87,83.93 81.1,84.16
  BOTTOM w0.102: v2(62.52,96.54) 62.62,96.54 63.92,95.25 76.27,95.25 81.65,89.87 81.65,87.11 81.38,86.84 81.38,84.44 81.1,84.16
XDP_TMS: length 29
  TOP w0.102: T47.1 65.44,92.51 75.62,92.51 v2(77.83,94.73)
  BOTTOM w0.089: UC1.AL54 81.9,82.79 81.9,84.64 81.94,84.69 81.94,86.16
  BOTTOM w0.102: 81.94,86.16 81.94,86.64 82.15,86.85 82.15,90.03 78.71,93.47 78.71,94.23 78.21,94.73 v2(77.83,94.73) 77.83,94.99 RC112.1
XDP_TRST#: length 33.7
  TOP w0.102: v2(80.81,95.25) 77.77,95.25 75.36,92.83 66.46,92.83 T45.1
  BOTTOM w0.089: UC1.AK53 82.36,82.68 82.46,82.83 82.46,83.19 82.5,83.23 82.5,84.15 82.57,84.22
  BOTTOM w0.102: 82.57,84.22 82.79,84.44 82.79,85.04 82.46,85.38 82.46,90.92 80.93,92.45 80.93,95.12 v2(80.81,95.25) 80.67,95.39 CC22.1 RC116.1 RC113.1
N72123: length 3.7
  BOTTOM w0.102: v1(89.24,137.03) PRZ33.1
  BOTTOM w0.203: PRZ33.1 PCZ15.1 88.96,135.19 88,134.23 PUZ1.1
N17003752: length 3
  TOP w0.102: RD23.2 30.59,77.53 30.59,77.53 30.13,77.53 v2(29.82,77.53)
  BOTTOM w0.102: v2(29.82,77.53) 29.92,77.43 JDIMM1.134
N17389450: length 18.2
  IN2 w0.254: v2(202.74,83.55) 208.85,83.55 209.94,84.64 v2(214.54,84.64)
  BOTTOM w0.254: v2(214.54,84.64) 214.52,84.64 PD501.2 214.22,83.55 PR502.2 PR508.1 PC516.2 ; PR503.2 203.42,82.75 PR506.2 v2(202.74,83.55)
N17415515: length 0.8
  TOP w0.102: v2(83.41,146.62) v1(84.24,146.62)
N18009640: length 8.7
  BOTTOM w0.508: QG1.3 23.82,88.97 v1(23.56,89.24) 23.23,89.57 23.17,89.57 22.89,89.85 RG106.2 RG107.2 RG102.2 RG103.2 RG104.2 RG105.2 RG108.2 RG109.2
N18855880: length 2.3
  TOP w0.102: U1.3 222.15,56.14 R57.2 v1(223.27,56.14)
N21380741: length 1.1
  TOP w0.102: PC508.1 v1(207.81,82.96)
  vias: v2(207.81,81.15)
N21599913: length 3.1
  TOP w0.102: v1(17.69,76.51) 18.15,76.06 UL2.3 18.82,76.06 19.15,75.73 v2(19.15,75.18)
  BOTTOM w0.102: RL7.2 19.2,75.23 v2(19.15,75.18)
N22038366: length 2.4
  TOP w0.102: U11.12 152.53,48.92 152.82,48.64 v1(152.82,48.06) 152.82,47.32 C967.2
N22038385: length 2.4
  TOP w0.102: C976.2 151.68,47.86 v1(151.48,48.06) 151.48,48.57 151.73,48.82 U11.10
N23005873: length 6
  TOP w0.102: UL1.26 19.61,84.94 19.53,85.02 19.21,85.02 18.94,84.76 18.63,84.76 17.75,85.63 17.75,86.29 16.81,87.23 RL17.1 v1(15.72,87.23)
N23133643: length 1.2
  BOTTOM w0.102: PDB01.1 188.7,57.33 v1(188.31,57.72)
N28483977: length 3.8
  TOP w0.102: v1(185.28,61.48) PR35.2
  TOP w0.254: PR35.2 PR45.1 ; PR45.1 185.29,63.32 PR31.2 ; PR45.1 185.2,63.38 PQ13.2
N28484391: length 3.2
  TOP w0.102: PR33.2 183.5,61.76 v1(183.77,61.48)
  TOP w0.254: PQ12.6 182.99,63.81 PC13.1 PR33.2
N28484416: length 2.9
  TOP w0.102: v1(182.53,69.08) 182.33,68.88 PR36.2
  TOP w0.381: PR36.2 PR44.2 182.33,67.18 182.34,67.17 PQ12.2
N28484439: length 3
  TOP w0.102: v1(194.47,43.56) 194.2,43.29 PR43.1
  TOP w0.254: PQ11.2 193.34,42.25 PC14.2 193.52,42.43 PR43.1
N28484451: length 4.8
  TOP w0.102: PR34.2 184.63,68.5 v1(184.63,69.07)
  TOP w0.381: PQ13.5 185.2,67.1 PR38.1 184.95,67.18 184.55,66.78 PQ13.6
  TOP w0.508: PR38.1 PR34.2
N28484500: length 3.8
  TOP w0.102: PR40.1 181.64,62.2 v1(182.4,61.44)
  TOP w0.254: PQ12.5 182.34,63.55 PC13.2 182.53,63.3 181.69,62.47 PR40.1
N28866422: length 16.3
  TOP w0.254: v2(179.1,60.66) 179.38,60.94 PRB02.3
  IN2 w0.254: v2(189.11,51.75) 188.98,51.75 185.43,55.3 185.43,56.78 181.31,60.89 179.33,60.89 v2(179.1,60.66)
  BOTTOM w0.254: PRB12.1 v2(189.11,51.75)
N28866508: length 2.8
  BOTTOM w0.102: v1(201.66,48.13) PRB32.1
  BOTTOM w0.254: PRB32.1 201.63,49.13 PCB13.1 199.93,49.13 PRB31.1
N28866577: length 2
  TOP w0.102: v1(200.96,49.94) PCB11.1
  TOP w0.254: PCB11.1 199.83,50 PRB30.2
N28866613: length 16.2
  TOP w0.254: v2(179.13,61.4) 178.67,60.94 PRB02.2
  IN2 w0.254: v2(179.13,61.4) 179.26,61.27 181.47,61.27 185.81,56.94 185.81,55.46 188.63,52.64 v2(189.11,52.64)
  BOTTOM w0.254: PRB11.1 v2(189.11,52.64)
N29056076: length 2.4
  TOP w0.254: PQB28.2 v1(170.6,48.14) PQB29.1
N29179188:
  vias: v3(170.15,64.77)
N29179461:
  vias: v2(175.68,66.8) v2(175.68,66.16) v3(175.93,60.64)
N29179506: length 1
  TOP w0.102: PRB06.1 v1(167.23,68.54)
N29179534: length 80.9
  TOP w0.508: v2(202.19,52.74) 202.18,52.74 201.52,53.4 201.52,58.43 200.06,59.89 199.34,59.89 199.04,60.19 v2(199.04,62.48) ; PRB06.2 166.25,70.7 v3(166.66,71.11) 166.91,71.36 176.12,71.36 177.01,70.47 v2(177.01,70.25) 177.06,70.2 PQB03.1 177.17,69.26 PCB01.2 ; v2(173.49,63.15) 173.58,63.06 PQB12.4
  IN1 w0.508: v2(192.88,44.16) 194.02,43.02 197.2,43.02 201.08,46.9 201.08,49.08 200.95,49.21 200.95,50.35 201.39,50.8 201.42,50.8 202.19,51.57 v2(202.19,52.74) ; v2(173.49,63.15) 174.4,64.06 174.4,67.44 177.01,70.05 v2(177.01,70.25) 177.06,70.3 177.06,70.45 177.68,71.08 191.97,71.08 195.21,67.84 195.21,65.92 198.65,62.48 v2(199.04,62.48)
  BOTTOM w0.508: v2(192.88,44.16) 192.7,44.34 192.06,44.34 PRB07.1
N35174703: length 3.6
  TOP w0.102: v1(198.09,56.76) 197.95,56.62 PRB42.2
  TOP w0.254: PRB42.2 198.03,55.71 PRB43.1 197.03,54.67 PQB33.1
N35174707: length 3.9
  TOP w0.102: PRB43.2 198.03,53.83 v1(198.99,54.79)
  TOP w0.254: PRB43.2 198.93,53.75 PCB36.1 199.63,53.74 199.86,53.97 PQB32.2
N36068621: length 3.8
  BOTTOM w0.102: v1(106.64,91.66) 106.64,92.49 RC93.2 109.29,92.83 QC3.1
N36974075: length 3
  BOTTOM w0.089: T9.1 83.65,84.18 83.24,83.78 83.24,83.16 83.35,83.06 83.35,83.05 83.35,83.04 83.35,82.83 UC1.AH53
N36975833: length 5.7
  BOTTOM w0.089: 95.64,82.77 95.64,82.44 95.43,82.23 95.42,82.23 95.14,82.23 UC1.C52
  BOTTOM w0.102: T32.1 97.76,84.9 95.64,82.77
N37347070: length 5.9
  BOTTOM w0.102: UC1.D1 93.92,59.09 94.43,58.58 97.95,58.58 98.69,57.84 T6.1
N37347073: length 5.1
  BOTTOM w0.102: T7.1 98.22,58.81 94.53,58.81 94.22,59.13 94.22,59.45 UC1.D2
N37348861: length 6.6
  TOP w0.102: RC54.1 106.03,80.41 106.97,81.35 107.81,81.35 108.32,81.86 UC3.4 108.32,82.66 108.8,83.14 108.8,85.1 v1(108.62,85.28)
N37471844: length 2.5
  TOP w0.089: v2(91.89,70.2) 92.22,70.53 RC25.1 v1(91.28,70.99)
  BOTTOM w0.089: v2(91.89,70.2) 91.46,69.77 UC1.J25
N37471848: length 1.2
  TOP w0.203: v2(90.37,64.07) 90.08,63.78 RC18.2
  BOTTOM w0.203: UC1.L13 90.58,64.27 v2(90.37,64.07)
N38547614: length 5.9
  TOP w0.102: RI13.2 26.31,94.37 26.81,93.87 26.89,93.87 27.2,93.56 27.2,92.75 27.62,92.33 27.62,92.03 27.88,91.77 27.88,91.72 28.28,91.32 DI1.3 v1(29.58,91.32)
N38547616: length 5.5
  TOP w0.102: RI14.2 25.36,91.45 25.5,91.31 26.99,91.31 28.28,90.02 DI1.2 v1(29.74,90.02)
N38557843: length 2.1
  TOP w0.102: T12.1 v2(72.74,122.3)
  BOTTOM w0.102: v2(72.74,122.3) 72.24,122.8 JWLAN1.6
N38557881: length 1.8
  TOP w0.102: T13.1 v2(70.33,125.15)
  BOTTOM w0.102: v2(70.33,125.15) 70.47,125.3 JWLAN1.16
N38557883: length 5.2
  TOP w0.102: T15.1 73,132.14 72.92,132.22 70.34,132.22 v2(70.33,132.2)
  BOTTOM w0.102: JWLAN1.44 70.43,132.3 v2(70.33,132.2)
N38557885: length 4.3
  TOP w0.102: T16.1 72.83,132.42 70.71,132.42 v2(70.33,132.8)
  BOTTOM w0.102: JWLAN1.46 v2(70.33,132.8)
N38557887: length 2.7
  TOP w0.102: T17.1 70.18,133.28 70.14,133.28 v2(69.69,132.84)
  BOTTOM w0.102: v2(69.69,132.84) 70.16,133.3 JWLAN1.48
N38557915: length 1.2
  TOP w0.102: RW18.2 72.07,125.84 72.61,125.29 T14.1
N38572293: length 2.2
  TOP w0.102: v1(66.53,131.95) RW6.2 66.53,129.81 UW1.3
N38572305: length 3.7
  TOP w0.102: QW1.1 63.9,131.62 RW5.2 64.11,130.72 UW1.4 v1(63.03,129.79)
N38577962: length 3.5
  TOP w0.102: T34.1 v2(27.09,27.74)
  BOTTOM w0.102: JSSD1.54 26.13,27.24 26.01,27.36 26.01,28 26.2,28.19 26.64,28.19 v2(27.09,27.74)
N38577990: length 9.1
  BOTTOM w0.102: JSSD1.10 37.13,25.71 37.58,25.26 37.9,25.26 42.18,25.26 43.09,26.16 R77.1 44.04,26.54 v1(44.36,26.22)
N38604520: length 4.8
  TOP w0.102: UA1.10 34.6,14.81 34.81,15.02 34.81,16.09 35.06,16.37 35.14,16.44 RA32.2 35.59,16.44 36.23,15.81 v1(37.44,15.81)
N38605656: length 0.8
  TOP w0.102: RA50.1 CA487.2
N38607202: length 1.7
  TOP w0.203: RA31.2 RA48.1 34.72,17.2 CA478.1
N38607812: length 3.4
  TOP w0.254: RA52.1 21.45,13.77 v1(20.74,13.06) 20.51,13.06 20.2,12.75 DA10.2
N38607828: length 3.3
  TOP w0.254: DA10.3 18.86,11.68 20.77,11.68 v1(20.86,11.77) 21.14,12.05 21.6,12.05 RA53.1
N38612980: length 3.2
  BOTTOM w0.102: v1(177.34,42.24) RS62.2 178.41,42.41 178.87,42.87 178.87,42.9 178.97,43 QS1.6 QS1.5
N38638766: length 11.5
  TOP w0.102: v2(5.69,125.73) v1(6.64,125.73)
  TOP w0.254: R68.1 v2(5.69,125.73)
  IN1 w0.254: v2(5.69,125.73) 5.18,125.22 4.61,125.22 3.02,126.8 3.02,132.01 2.74,132.29 v2(2.74,132.43)
  BOTTOM w0.254: LED1.4 2.55,132.24 v2(2.74,132.43)
N38638768: length 9.5
  TOP w0.102: v2(4.86,125.73) v1(3.91,125.73)
  TOP w0.254: R69.1 v2(4.86,125.73)
  IN1 w0.254: v2(4.86,125.73) 3.53,127.06 3.53,132.23 v2(3.33,132.43)
  BOTTOM w0.254: v2(3.33,132.43) 3.33,131.93 LED1.2
N38639135: length 4.3
  TOP w0.102: 13.69,120.14 13.43,119.88 13.43,118.63 R79.2 13.64,118.42 v1(14.51,118.42) ; 13.69,120.14 Q25.5 ; 13.69,120.14 13.56,120.26 13.56,120.65 13.7,120.79 Q25.6
N38653708: length 2.7
  TOP w0.254: PRH05.2 v1(151.8,59.2) 151.8,59.66 v2(151.62,59.84)
  BOTTOM w0.254: PUH01.7 150.89,60.1 151.16,59.84 v2(151.62,59.84)
N38657718: length 4.2
  BOTTOM w0.102: 110.08,32.06 R35.2 110.36,33.16 Q12.3 ; 110.08,32.06 v1(109.06,33.08) ; 110.08,32.06 C18.1
N38657720: length 8.7
  BOTTOM w0.102: Q13.2 108.5,26.91 108.17,27.24 v1(108.17,30.6) 108.67,31.1 R38.2 C18.2 110.64,31.1 110.77,31.22 Q12.2
N38657736: length 4.3
  BOTTOM w0.102: R37.1 112.43,28.25 112.05,27.87 Q13.1 111.5,27.21 v1(112.37,26.35)
N38658993: length 14.2
  TOP w0.102: DC4.2 v1(102.27,83.24) 101.53,83.24 99.28,81 99.28,80.07 98.25,79.03 97.79,79.03 97.44,79.37 96.17,79.37 94.61,77.81 93.87,77.81 v2(93.32,77.26)
  BOTTOM w0.089: UC1.F41 92.9,76.86 93.29,77.26 v2(93.32,77.26)
N38736705: length 1.4
  TOP w0.254: v2(81.19,60.76) 81.07,60.65 RC33.2
  BOTTOM w0.203: v2(81.19,60.76) 81.44,61.02 UC1.AL5
N38858837: length 0.9
  BOTTOM w0.102: RC40.2 T30.1
N38886483: length 3.2
  BOTTOM w0.102: v1(128.74,35.31) RE5.2 130.28,35.77 UE1.38
N38915222: length 3
  TOP w0.102: v1(131.03,51.81) 131.48,51.37 v2(131.48,51.3) RE25.1
  BOTTOM w0.102: UE1.125 131.08,51.7 v2(131.48,51.3)
N38916474: length 2.4
  BOTTOM w0.102: RE26.1 137.68,48.06 CE23.2 137.74,48.09 138.06,48.41 138.06,49.46 v1(138,49.53)
N38916969: length 0.7
  BOTTOM w0.102: CC3.1 108.67,71.42 RC37.2
N38993155: length 1.9
  BOTTOM w0.102: v1(90.33,139.35) PRG21.2
  BOTTOM w0.254: PRG21.2 91.45,139.2 92.19,139.2 PRG45.1
N38993903: length 0.8
  BOTTOM w0.254: PRZ44.1 PRZ42.2
N39173777: length 3.5
  BOTTOM w0.254: PUH01.9 149.99,59.85 150.35,59.49 151.06,59.49 151.38,59.18 v1(151.86,59.18) 152.75,59.18 152.78,59.15 PCH10.1
N39173785: length 4.1
  BOTTOM w0.254: PUH01.11 149.09,59.64 v1(149.6,59.13) 149.97,58.76 150.68,58.76 150.94,58.5 PCH11.1 151.27,58.17 151.29,58.2 PRH11.2
N39200796: length 4.3
  TOP w0.102: v1(22.77,122.36) 22.77,120.95 PRM06.2
  TOP w0.203: 23.53,119.59 24.13,118.99 PUM01.10
  TOP w0.254: PRM06.2 23.28,119.85 23.53,119.59
N39291721: length 3.1
  TOP w0.102: PR32.2 v1(187.55,63.11)
  TOP w0.508: PR32.2 186.91,64.45 186.79,64.32 186,64.32 185.91,64.41 PQ13.3
N39387882: length 6.3
  BOTTOM w0.102: R300.1 42.26,26.03 v1(41.85,25.62) 41.69,25.46 37.82,25.46 37.63,25.65 JSSD1.8
N39393826: length 8.2
  TOP w0.102: v1(180.56,70.29) 180.31,70.29 v2(179.98,69.96)
  TOP w0.508: PQB03.2 175.41,70.23 v2(176.16,70.23) ; PRB04.1 180.86,69.25 PRB03.2 v2(179.98,69.96)
  IN2 w0.508: v2(179.98,69.96) 179.98,69.78 179.47,69.28 176.67,69.28 176.16,69.78 v2(176.16,70.23)
N39399976: length 0.8
  TOP w0.102: v3(204.5,56.45) 204.89,56.83 204.89,57.08
  vias: v2(205.14,57.84) v2(205.14,57.21) v2(205.71,57.84) v2(205.71,57.21)
N39406703: length 1.9
  BOTTOM w0.203: PRB31.2 198.61,49.08 198.05,49.64 PUB01.29
N39614986: length 17.3
  IN2 w0.127: v2(69.88,63.24) 70.46,63.81 73.14,63.81 76.59,67.27 77.15,67.27 77.78,67.9 77.78,69.35 78.15,69.72 78.52,69.72 78.84,70.04 78.84,71.88 79,72.04 v2(79,72.04)
  BOTTOM w0.089: v2(69.88,63.24) 69.88,61.9 69.45,61.46
  BOTTOM w0.102: RC157.1 69.45,61.46
  BOTTOM w0.254: UC1.AV29 78.66,71.7 v2(79,72.04)
N39655859: length 2.8
  BOTTOM w0.102: v1(209.03,83.68) PR507.2
  BOTTOM w0.254: PR507.2 211.42,83.68 PD501.1
N39906676: length 77.6
  TOP w0.102: v2(148.94,37.23) 151.19,37.23 151.57,37.61 175,37.61 181.23,43.85 187.79,43.85 188.23,44.28 189.24,44.28 189.55,43.97 189.55,43.13 191,41.68 194.48,41.68 195.52,42.71 196.29,42.71 201.46,47.88 201.46,48.87 202.98,50.39 202.98,57.53 v1(203.04,57.59) 204.06,58.61 RB1.2
  BOTTOM w0.102: v2(148.94,37.23) 148.85,37.14 146.97,37.14 146.6,37.52 JDB1.3
N39906689: length 82.2
  TOP w0.102: RB2.2 215.59,52.86 206.07,52.86 203.62,50.4 203.62,50.16 202.07,48.61 202.07,47.62 196.54,42.1 195.83,42.1 194.79,41.07 190.75,41.07 188.37,43.44 181.4,43.44 175.17,37.21 152.12,37.21 151.47,36.56 148.18,36.56 v1(147.82,36.92) v2(147.16,37.58)
  BOTTOM w0.102: JDB1.5 146.58,37.92 146.92,37.58 v2(147.16,37.58)
N39906706: length 81.4
  TOP w0.102: v2(147.99,37.59) 148.81,36.76 151.19,36.76 v1(151.64,37.22) 151.83,37.41 175.08,37.41 181.32,43.65 188.46,43.65 190.83,41.27 194.71,41.27 195.74,42.31 196.46,42.31 201.86,47.71 201.86,48.7 203.41,50.25 203.41,50.48 205.99,53.06 215.28,53.06 215.93,53.72 RB3.2
  BOTTOM w0.102: v2(147.99,37.59) 147.48,38.1 146.72,38.1 146.49,38.32 JDB1.7
N39906735: length 24.4
  TOP w0.102: v2(145.96,43.6) v1(146.49,43.6)
  IN1 w0.127: v2(158.24,45.15) 157.08,45.15 155.17,43.24 146.32,43.24 v2(145.96,43.6)
  BOTTOM w0.102: v2(158.24,45.15) 158.24,45.68 160.51,47.95 RB5.2 ; JDB1.17 145.71,40.32 146.53,40.32 147.61,41.4 147.61,41.95 v2(145.96,43.6)
N39906737: length 113.8
  TOP w0.102: RB4.2 103.48,122.44 v1(103.48,116.2) 103.48,111.56 107.84,107.2 110.96,107.2 113.08,105.08 113.08,102.04 116.54,98.57 116.54,69.63 125.02,61.16 134.39,61.16 134.97,60.57 v2(134.97,60.51)
  BOTTOM w0.102: v2(134.97,60.51) 134.97,60.19 137,58.16 137,56.13 140.81,52.32 140.81,51.66 140.84,51.63 140.84,49.03 144.21,45.65 145.19,45.65 145.45,45.4 145.45,44.86 147.93,42.38 147.93,39.75 147.7,39.52 145.71,39.52 JDB1.13
N39906754: length 32.6
  TOP w0.102: v2(145.38,43.53) v1(144.79,43.53)
  IN1 w0.127: v2(168.92,47.94) 168.92,46.13 165.74,42.96 145.95,42.96 v2(145.38,43.53)
  BOTTOM w0.102: v2(145.38,43.53) 147.12,41.79 147.12,41.36 146.49,40.72 145.71,40.72 JDB1.19 ; RB6.2 v2(168.92,47.94)
N39906812: length 125.8
  TOP w0.102: v2(134.37,60.51) 134.37,60.61 134.02,60.96 124.93,60.96 116.3,69.59 116.3,93.02 114.84,94.48 114.84,99.99 112.87,101.96 112.87,104.96 110.84,106.99 107.54,106.99 v1(105.98,108.55) 102.78,111.76 91.16,111.76 87.6,115.31 87.6,120.63 RB7.1
  BOTTOM w0.102: v2(134.37,60.51) 134.37,60.29 135.26,59.39 135.27,59.39 135.5,59.16 135.5,59.15 136.8,57.86 136.8,56.05 140.61,52.24 140.61,51.57 140.64,51.55 140.64,48.94 142.08,47.49 142.08,42.35 140.43,40.7 140.43,37.52 140.69,37.27 141.64,37.27 141.89,37.52 143.53,37.52 JDB1.4
N39906827: length 21.5
  TOP w0.102: v2(140.94,37.75) 140.69,38.01 140.69,40.7 142.91,42.92 v1(150.34,42.92) RB8.1
  BOTTOM w0.102: v2(140.94,37.75) 141.99,37.75 142.16,37.92 JDB1.6
N39906848: length 44
  TOP w0.102: v1(141.05,38.81) 141.19,38.67 v2(141.19,38.35)
  IN1 w0.127: v2(141.19,38.35) 141.39,38.16 148.62,38.16 148.88,38.41 162.3,38.41 163.44,39.56 180.25,39.56 v2(180.44,39.37)
  BOTTOM w0.102: v2(141.19,38.35) 141.3,38.24 142.73,38.24 142.8,38.32 JDB1.8 ; RB9.1 180.95,39.87 v2(180.44,39.37)
N39906878: length 207
  IN1 w0.127: v2(58.33,43.81) 59.15,43.81 60.11,44.76 74.46,44.76 76.55,42.67 84.74,42.67 87.41,40 87.41,36.06 88.01,35.47 97.53,35.47 97.89,35.11 107.41,35.11 109.25,36.95 112.49,36.95 113.13,36.32 116.92,36.32 118.84,38.24 118.84,38.86 119.29,39.3 119.29,43.03 119.56,43.3 120.94,43.3 123.29,40.95 128.07,40.95 128.58,41.46 128.64,41.52 135.35,41.52 135.67,41.21 138.27,41.21 138.97,40.51 v2(141.32,40.51) ; v2(28.48,106.36) 28.48,105.15 28.86,104.77 28.86,104.2 28.89,104.17 28.89,102 28.74,101.84 28.74,90.68 29.56,89.85 29.56,88.38 27.68,86.5 27.68,80.81 27.69,80.79 27.69,62.92 27.15,62.37 27.15,43.37 28.77,41.75 34.04,41.75 34.64,41.14 40.55,41.14 41.06,40.64 v2(41.06,35.56)
  BOTTOM w0.102: v2(41.06,35.56) 42.39,35.56 44.74,37.9 51.97,37.9 57.56,43.49 58.01,43.49 v2(58.33,43.81) ; RB10.1 28.23,106.61 v2(28.48,106.36) ; v2(141.32,40.51) 141.32,39.76 141.4,39.68 142.08,39.68 142.25,39.52 143.53,39.52 JDB1.14
N39956795: length 4.6
  TOP w0.102: v1(68.93,115.25) RC144.1 67.34,115.12 RC139.1 68.54,114.42 CC93.2 RC143.2
N40664383: length 2.4
  TOP w0.102: T10.1 v2(41.08,67.56)
  BOTTOM w0.102: v2(41.08,67.56) 40.62,67.56 40.5,67.68 JDIMM1.165
N40775614:
  vias: v1(106.71,39.87)
N40775618: length 1.8
  BOTTOM w0.102: CM29.1 105.2,41 v2(105.2,40.51) 105.12,40.51 104.89,40.28 UM3.12
N40775624:
  vias: v1(102.14,40)
N40775687: length 1.6
  BOTTOM w0.102: CM30.1 103.87,41.15 v2(103.87,40.64) 103.87,40.32 104.09,40.1 UM3.10
N40892116: length 7.3
  TOP w0.102: RE42.1 115.36,35.02 115.36,36.08 v2(116.05,36.76)
  BOTTOM w0.102: UE1.64 119.88,36.4 119.67,36.19 118.39,36.19 v1(118,35.81) 117,35.81 v2(116.05,36.76)
N40978125: length 5.3
  TOP w0.102: v1(127.67,52.41) U15.3 127.28,53.98 127.28,54.49 127.04,54.73 126.87,54.73 126.87,54.73 126.32,54.73 126.31,54.72 125.26,54.72 124.62,55.35 RE53.2
N41027888: length 14.4
  IN2 w0.127: v2(78.3,70.22) 78.23,70.22 77.43,69.43 77.43,68.03 77.02,67.62 76.49,67.62 72.93,64.07 70.07,64.07 v2(69.25,63.24)
  BOTTOM w0.102: v2(69.25,63.24) 69.25,62.37 RC40.1
  BOTTOM w0.203: v2(78.3,70.22) UC1.AV27
N41527020: length 2.3
  TOP w0.102: v2(32.95,68.83) 33.05,68.92 33.05,69.22 33.05,69.22 T11.1
  BOTTOM w0.102: v2(32.95,68.83) 32.55,68.43 JDIMM1.162
N48572179: length 2.2
  BOTTOM w0.102: v1(156.12,57.97) 155.47,57.32 PCH14.2
  BOTTOM w0.254: PCH14.2 PRH12.1
N124752685: length 2
  TOP w0.102: v1(29.88,62.11) 30.21,62.11 CD30.2
  TOP w0.457: CD30.2 RD11.1
N392641980: length 3
  BOTTOM w0.089: T1.1 96.89,73.32 95.72,73.32 95.6,73.2 95.21,73.2 95.1,73.08 94.84,73.08 UC1.C32

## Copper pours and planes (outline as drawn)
+0.6V_DDR_VTT on TOP (solid shape): 30.58,111.56 30.58,108.96 30.45,108.83 28.74,108.83 28.55,109.02 28.55,111.63 28.61,111.69 30.45,111.69
+0.6V_DDR_VTT on TOP (solid shape): 28.67,46.79 28.67,46.64 29.39,45.92 29.39,45.9 29.4,45.77 29.46,45.65 29.47,45.63 29.47,45.62 30.01,45.08 30.01,44.19 29.94,44.13 29.12,44.13 28.67,44.57 28.6,44.57 27.91,44.57 27.53,44.95 24.4,44.95 24.4,46.08 25.62,47.3 28.16,47.3
+0.6V_DDR_VTT on BOTTOM (solid shape): 30,45.08 30,44.78 30.22,44.57 31.8,44.57 31.82,44.54 31.82,44.36 31.75,44.29 30.22,44.29 30,44.06 29.43,44.06 29.3,44.19 29.3,44.63 29.3,44.63 29.3,45.08 29.43,45.21 29.87,45.21
+0.6V_DDR_VTT on IN1 (solid shape): 31.27,109.72 31.27,108.13 31.08,107.94 30.13,107.94 30.01,108.07 30.01,109.92 30.13,110.04 30.95,110.04
+0.6V_DDR_VTT on IN1 (solid shape): 29.43,45.27 29.93,45.27 30.06,45.14 30.06,44.19 29.93,44.06 28.66,44.06 28.09,44.63 28.09,45.46 28.35,45.71 28.98,45.71
+0.6VSP on TOP (solid shape): 27.58,116.38 27.58,115.13 27.97,114.74 28.48,114.74 28.74,114.49 28.74,113.85 29.31,113.28 29.75,113.28 29.88,113.15 29.88,111.95 29.82,111.88 29.56,111.88 29.56,112.45 29.05,112.45 29.05,111.88 27.78,111.88 27.02,112.64 27.02,113.79 25.62,115.18 25.62,115.9 25.7,115.97 26.01,115.97 26.51,115.46 26.92,115.46 27.15,115.69 27.15,116.33 26.89,116.58 26.08,116.58 26.03,116.63 26.03,116.76 26.08,116.81 27.15,116.81
+1.2V_DDR on TOP (solid shape): 54.37,63.55 44.37,63.55 44.37,78.55 54.37,78.55
+1.2V_DDR on TOP (solid shape): outline of 9352 points within 28.65,48.64 58.26,114.1
+1.2V_DDR_SOC on TOP (solid shape): outline of 4792 points within 57.95,63.5 80.68,86.42
+1.2V_DDR_SOC on BOTTOM (solid shape): 77.55,77.78 77.55,76.84 77.39,76.68 77.13,76.68 76.62,77.19 76.62,77.44 77.13,77.95 77.39,77.95
+1.2V_DDR_SOC on BOTTOM (solid shape): 80.56,75.85 80.56,74.88 80.51,74.83 80.51,74.75 80.19,74.44 80.19,74.44 79.86,74.11 79.8,74.07 79.75,74.01 79.48,74.01 79.42,74.08 79.42,74.79 78.9,75.31 78.9,75.46 79.35,75.92 80.5,75.92
+1.2V_DDR_SOC on BOTTOM (solid shape): 80.64,68.13 80.64,67.95 80.5,67.81 80.41,67.78 80.34,67.84 80.11,68.01 79.83,67.94 79.71,67.65 79.89,67.39 79.94,67.31 79.89,67.22 79.73,67.02 79.76,66.76 80.01,66.6 80.29,66.7 80.36,66.74 80.44,66.71 80.55,66.6 80.55,66.48 80.31,66.24 80.22,66.24 80.21,66.25 80.08,66.28 79.95,66.25 79.94,66.24 79.82,66.24 79.81,66.25 79.71,66.29 79.27,66.3 79.03,66.54 79.03,68.07 79.27,68.31 80.46,68.31
+1.2V_GLML on TOP (solid shape): 81.06,66.99 81.06,66.67 81.25,66.48 81.25,64.32 80.93,64 79.54,64 79.41,64.13 79.41,64.38 79.6,64.57 80.62,64.57 80.74,64.7 80.74,65.46 80.55,65.65 80.55,66.48 80.49,66.54 80.49,67.05 80.62,67.18 80.87,67.18
+1.2V_GLML on TOP (solid shape): 77.31,57.46 77.31,57.03 77.31,57.03 77.31,56.83 77.5,56.64 78.33,56.64 78.71,56.26 78.71,55.75 78.62,55.66 78.06,55.66 77.9,55.49 76.93,55.49 76.74,55.68 76.74,56.57 76.49,56.83 76.49,57.53 76.62,57.65 77.12,57.65
+1.2V_GLML on IN2 (solid shape): outline of 293 points within 78.58,66.42 82.52,75.56
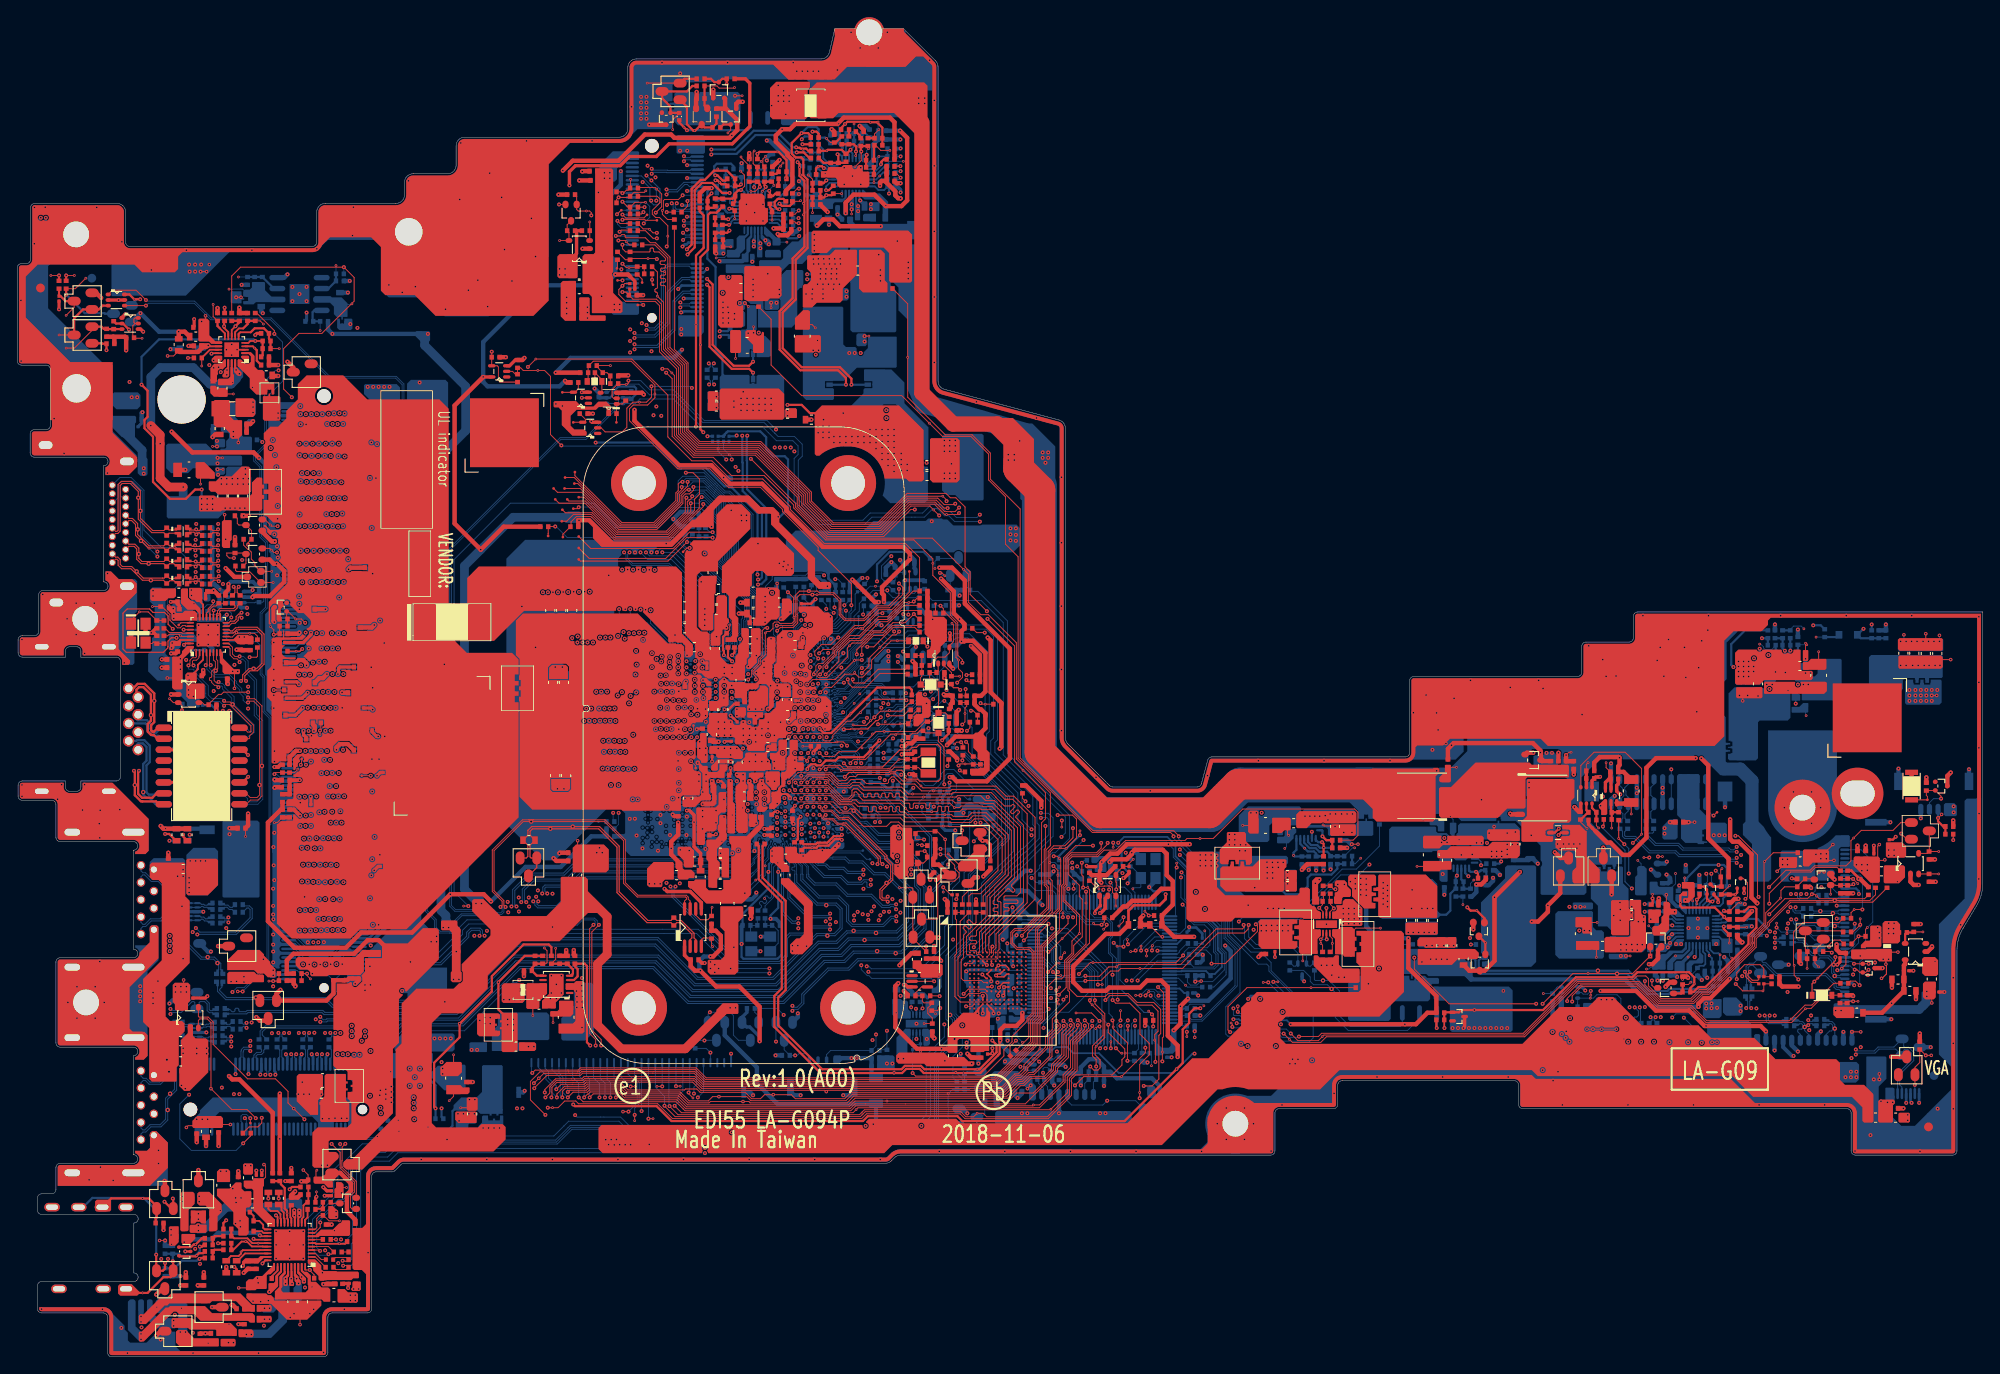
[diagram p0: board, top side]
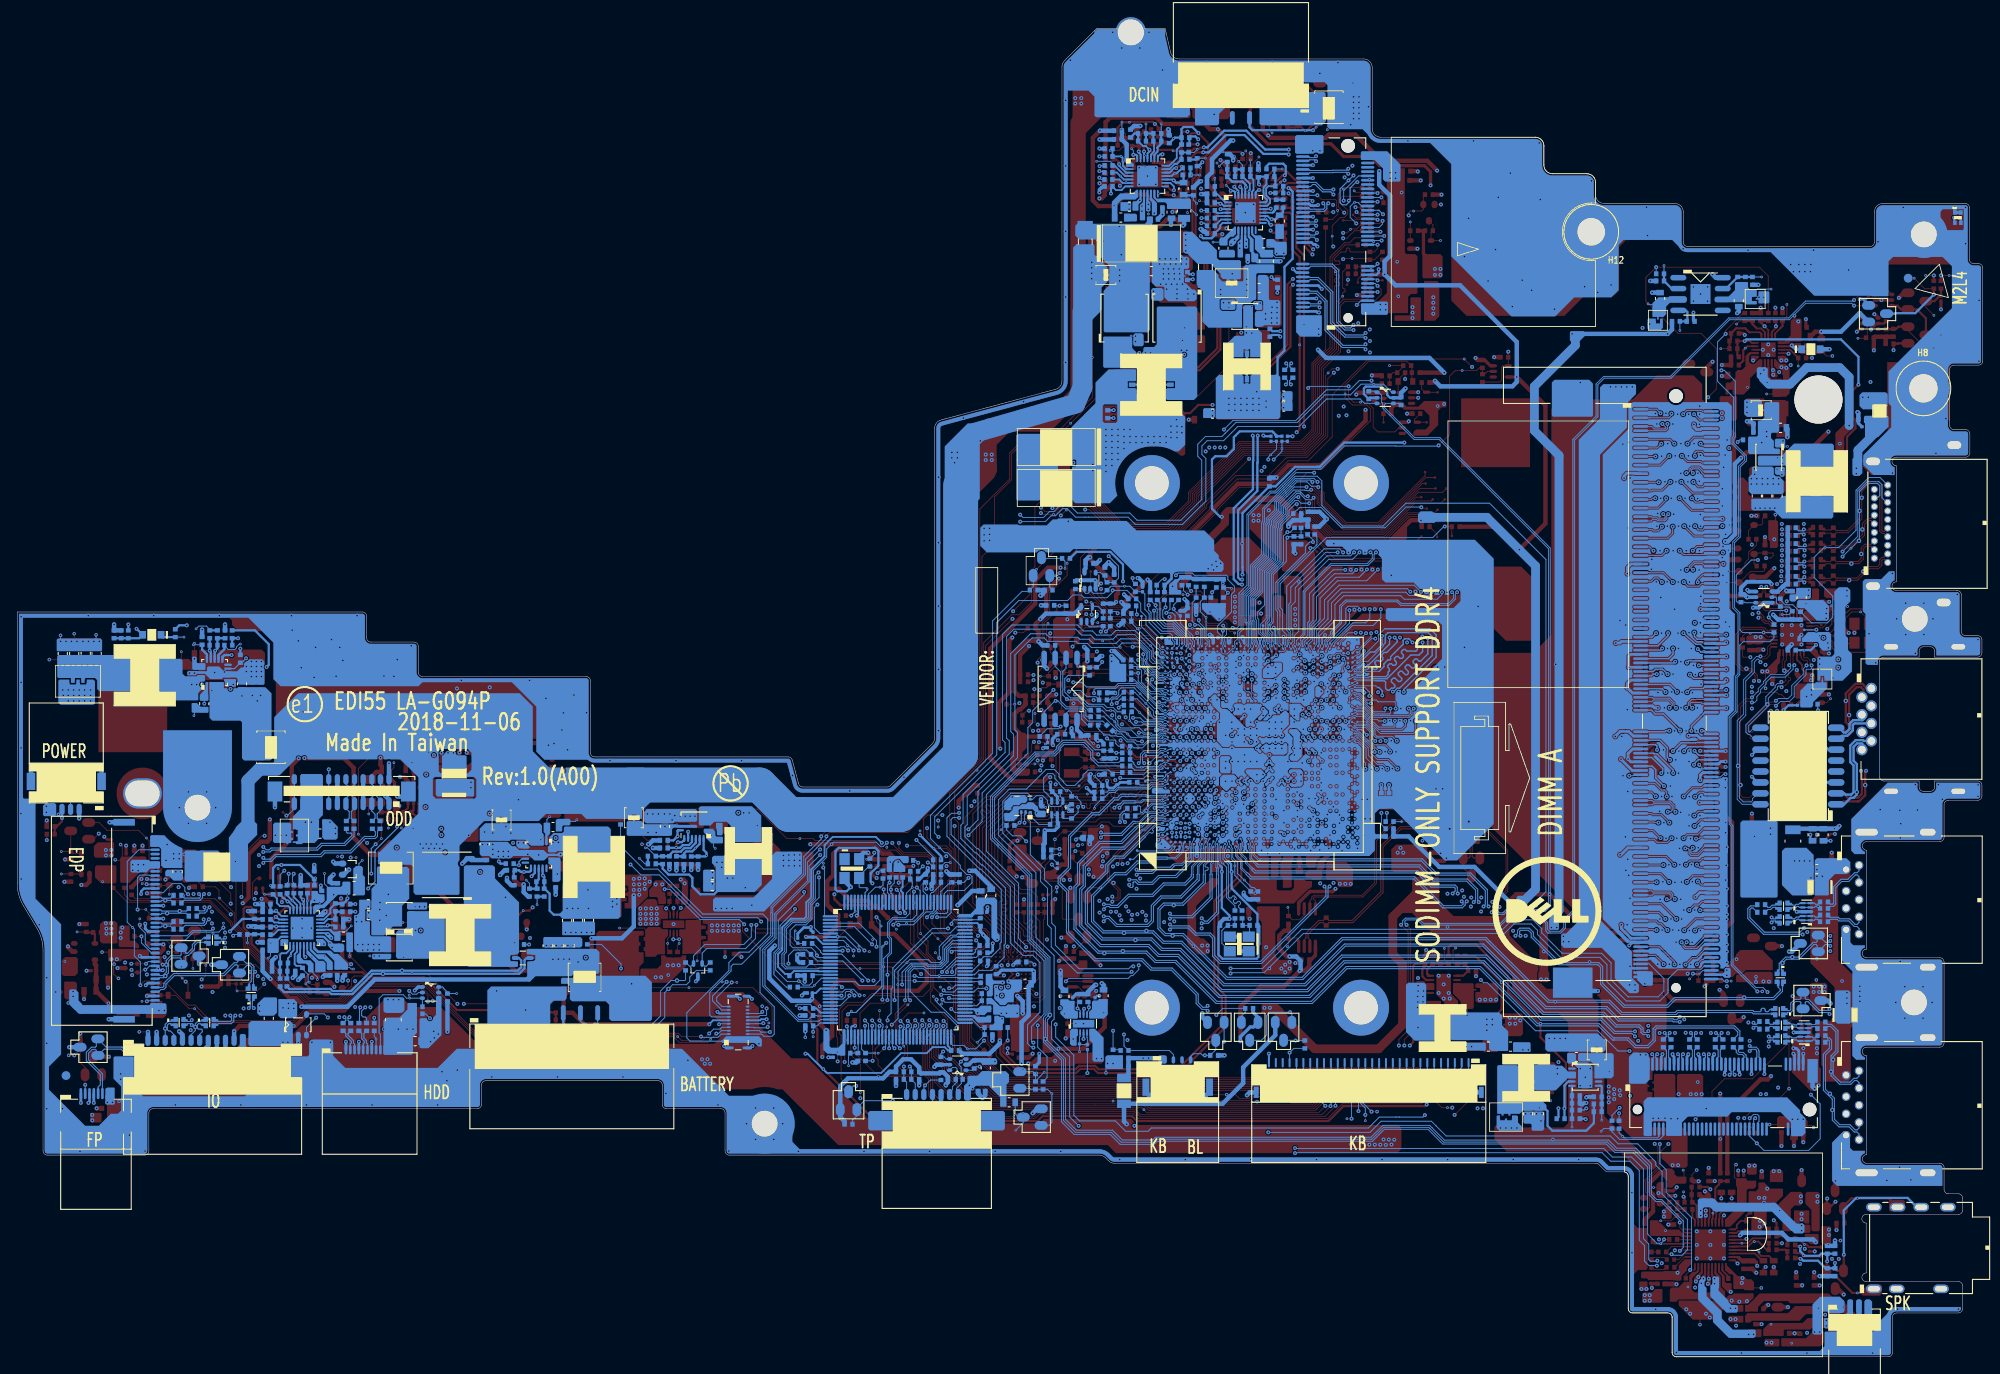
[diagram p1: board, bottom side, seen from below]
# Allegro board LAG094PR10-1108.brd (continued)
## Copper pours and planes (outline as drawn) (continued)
+1.2V_MPHY on TOP (solid shape): 84.67,67.88 84.67,66.62 84.87,66.42 84.87,66.1 84.68,65.91 84.68,64.53 84.55,64.27 84.68,64.01 84.68,63.77 84.56,63.46 84.77,63.2 84.78,63.2 84.88,63.09 84.88,62.47 84.9,62.47 84.9,62.31 84.88,62.31 84.88,61.58 84.9,61.58 84.9,61.12 84.67,60.89 83.85,60.89 83.54,61.21 83.54,64.31 83.47,64.37 83.47,66.3 83.98,66.81 83.98,67.14 83.83,67.29 83.65,67.29 83.4,67.54 83.4,67.87 83.47,67.95 84.6,67.95
+1.2V_MPHY on BOTTOM (solid shape): 85.48,68.31 85.66,68.13 85.66,67.95 85.26,67.54 85.23,67.52 85.21,67.49 84.99,67.28 84.82,67.18 84.72,67 84.41,66.7 84.24,66.7 84.23,66.72 84.17,66.78 84.1,66.82 83.98,66.94 83.88,67.17 83.65,67.28 83.63,67.29 83.55,67.36 83.55,67.38 83.48,67.51 83.36,67.59 83.33,67.6 83.33,67.77 83.35,67.79 83.37,67.8 83.47,67.87 83.54,67.97 83.55,67.98 83.87,68.31
+1.2V_PLL on TOP (solid shape): 82.39,62.91 82.39,60.9 82.46,60.84 82.46,60.19 81.31,59.05 81.31,57.79 81.63,57.48 81.63,55.84 81.34,55.55 81.34,54.57 81.31,54.54 80.43,54.54 80.3,54.67 80.3,57.62 80.08,57.84 80.08,58.73 80.11,58.74 80.3,59.04 80.11,59.34 80.08,59.36 80.08,60.04 80.17,60.13 81.12,60.13 81.57,60.57 81.57,60.99 81.42,61.15 81.42,61.78 81.57,61.93 81.57,62.87 81.7,63 82.3,63
+1.2V_SOC on TOP (solid shape): outline of 119 points within 77.95,52.7 86.75,63.03
+1.2V_USB2 on TOP (solid shape): 83.16,67.05 83.16,64.51 83.41,64.26 83.41,60.89 83.38,60.86 82.62,60.86 82.52,60.96 82.52,67.11 82.58,67.18 83.03,67.18
+1.2V_VNNAON on TOP (solid shape): outline of 183 points within 85.93,63.37 87.51,67.19
+1.2VP on TOP (solid shape): 25.45,115.95 25.45,115.06 26.06,114.45 26.06,114.19 25.93,114.07 25.62,114.07 25.22,114.47 25.22,115.95 25.27,116 25.4,116
+1.2VP on TOP (solid shape): 28.48,102.1 28.48,98.55 28.29,98.36 25.69,98.36 25.62,98.42 23.78,98.42 23.66,98.29 21.24,98.29 21.12,98.42 21.12,100.01 21.24,100.13 22.89,100.13 23.12,99.91 26.86,99.91 27.28,100.33 27.28,101.66 27.85,102.23 28.36,102.23
+1.2VP on BOTTOM (solid shape): 26.26,114.87 26.26,113.91 25.94,113.6 25.31,113.6 24.99,113.91 24.99,114.87 25.18,115.06 26.07,115.06
+1.2VP on BOTTOM (solid shape): 23.66,99.75 26.83,99.75 26.89,99.69 26.89,98.61 26.7,98.42 24.29,98.42 23.34,97.47 17.56,97.47 17.37,97.66 17.37,99.94 17.5,100.07 23.34,100.07
+1.05VS on TOP (solid shape): 142.78,60.83 142.78,59.94 143.48,59.24 143.48,57.46 143.23,57.21 142.78,57.21 142.78,57.78 141.96,57.78 141.96,57.27 141.58,57.27 141.58,57.78 140.75,57.78 140.75,57.27 139.92,57.27 139.73,57.46 139.73,58.99 140.56,59.81 140.56,60.89 140.69,61.02 142.59,61.02
+1.05VS on TOP (solid shape): 90.27,93.4 90.27,91.12 89.95,90.8 87.16,90.8 86.58,91.37 85.76,91.37 85.36,90.97 85.36,89.7 85.16,89.51 85.16,88.53 85.05,88.42 83.81,88.42 83.47,88.08 83.47,86.23 83.79,85.91 83.79,83.82 83.6,83.62 83.6,83.12 82.33,83.12 82.33,83.62 82.84,83.62 83.08,83.87 83.08,85.07 83.07,85.16 83.03,85.25 83.03,85.66 82.71,85.97 82.71,88.45 82.36,88.8 81.91,88.8 81.89,88.83 81.89,91.89 85.25,95.26 88.41,95.26
+1.05VS on BOTTOM (solid shape): 107.13,97.47 107.45,97.47 107.56,97.35 108.07,97.35 108.76,96.67 111.86,96.67 112.01,96.69 112.14,96.77 116.11,96.77 116.49,96.39 116.49,94.29 115.73,93.53 109.91,93.53 109.38,93.81 108.85,93.53 106.08,93.53 105.7,93.91 101.32,93.91 98.52,91.12 94.4,91.12 94.27,90.99 94.27,90.8 94.24,90.75 94.18,90.76 94.11,90.83 94.12,90.85 94.01,91.12 93.75,91.22 93.72,91.22 93.7,91.24 93.63,91.24 93.58,91.3 91.78,91.3 91.73,91.24 88.49,91.24 88.24,91.5 88.24,92.27 88.79,92.83 88.79,93.2 89.32,93.72 89.32,94.93 90.46,96.07 98.33,96.07 98.61,96.35 98.65,96.35 99.49,97.19 105.59,97.19 105.86,97.47 107.09,97.47
+1.05VS on IN2 (solid shape): 120.56,97.09 120.56,94.42 120.07,93.93 117.74,93.93 117.32,94.36 115.35,94.36 115.1,94.61 115.1,97.09 115.41,97.4 120.24,97.4
+1.05VS on IN2 (solid shape): 142.78,64.64 142.78,62.92 143.29,62.42 143.29,59.57 143.28,59.56 143.28,58.73 143.04,58.48 140.93,58.48 139.86,59.55 139.86,61.08 138.72,62.23 138.72,64.26 139.54,65.08 142.34,65.08
+1.05VS_SOC_SRAM on TOP (solid shape): 87.26,77.73 87.26,75.78 87.19,75.71 87.07,75.71 86.85,75.5 86.85,75.45 86.85,75.24 86.7,75.09 84.9,75.09 84.82,75.17 84.82,75.65 85,75.83 85,77.26 85.12,77.39 85.92,77.39 86.29,77.76 86.29,78.01 86.98,78.01
+1.05VS_SOC_SRAM on TOP (solid shape): 88.59,89.15 88.59,86.13 88.51,86.05 88.47,86.02 88.4,85.94 88.4,85.9 88.22,85.72 87.63,85.72 87.03,85.12 87.01,85.11 86.96,85.09 86.91,85.06 86.87,85.03 86.85,85.01 85.53,85.01 85.5,85.04 85.5,85.68 85.81,85.99 85.81,88.43 85.84,88.47 85.84,88.86 87.36,88.86 87.36,88.81 87.37,88.75 87.38,88.7 87.41,88.65 87.44,88.61 87.47,88.57 87.51,88.54 87.56,88.51 87.61,88.49 87.66,88.48 87.71,88.48 87.77,88.48 87.82,88.49 87.87,88.51 87.92,88.54 87.96,88.57 87.99,88.61 88.02,88.65 88.05,88.7 88.06,88.75 88.07,88.81 88.07,88.86 88.06,88.91 88.05,88.96 88.02,89.01 87.99,89.05 87.96,89.09 87.92,89.13 87.87,89.15 87.82,89.17 87.77,89.18 87.71,89.19 87.66,89.18 87.61,89.17 87.56,89.15 87.51,89.13 87.47,89.09 87.44,89.05 87.41,89.01 87.38,88.96 87.37,88.91 87.36,88.86 85.84,88.86 85.84,89.38 85.89,89.43 88.31,89.43
+1.05VS_SOC_SRAM on BOTTOM (solid shape): 85.59,75.92 85.86,75.8 86.13,75.92 86.15,75.94 86.83,75.94 87.03,75.74 87.06,75.66 87.02,75.59 86.89,75.28 87.07,75 87.1,74.98 87.1,74.77 86.94,74.61 86.92,74.59 86.15,74.59 86.14,74.63 86.01,74.83 85.79,74.91 85.68,74.89 85.59,74.84 85.51,74.76 85.45,74.65 85.47,74.41 85.64,74.23 85.66,74.22 85.66,73.34 85.64,73.31 85.59,73.28 85.54,73.25 85.37,73.25 85.35,73.26 85.09,73.38 84.83,73.26 84.81,73.25 84.68,73.25 84.55,73.37 84.55,73.48 84.73,73.66 84.73,73.91 84.67,73.97 84.61,74.04 84.54,74.1 84.32,74.32 84.32,74.36 83.83,74.85 83.83,75 83.99,75.31 83.8,75.61 83.78,75.62 83.78,75.76 83.96,75.94 85.58,75.94
+1.05VS_SOC_SRAM on IN2 (solid shape): outline of 2030 points within 84.11,69.59 90.84,88.6
+1.05VSP on TOP (solid shape): 147.48,57.72 147.48,56.95 147.23,56.7 147.23,54.29 147.04,54.1 140.43,54.1 139.8,54.73 139.8,56.76 140.05,57.02 141,57.02 141,57.59 141.39,57.59 141.39,57.02 142.15,57.02 142.15,57.59 142.53,57.59 142.53,57.02 143.57,57.02 144.39,57.84 147.35,57.84
+1.05VSP on BOTTOM (solid shape): 147.67,58.03 147.67,57.4 147.23,56.95 147.23,54.03 142.72,54.03 141.89,54.86 141.89,58.05 142.1,58.25 147.46,58.25
+1.8V_AVDD on TOP (solid shape): 30.77,10.85 30.77,9.84 30.32,9.39 30.32,8.2 29.45,7.32 29.17,7.32 29.04,7.45 29.04,7.63 29.19,7.78 29.19,8.49 29.27,8.57 29.8,8.57 29.98,8.75 29.98,9.41 30.56,9.99 30.56,10.85 30.62,10.9 30.72,10.9
+1.8V_CPVDD on TOP (solid shape): 37.92,20.05 37.92,18.68 37.71,18.47 36.94,18.47 36.87,18.55 36.87,19.5 37.04,19.66 37.04,20.26 37.08,20.3 37.68,20.3
+1.8V_CPVDD on TOP (solid shape): 29.55,11.67 29.55,11.57 29.5,11.51 28.66,11.51 28,10.85 26.53,10.85 26.42,10.75 26.42,10.42 26.32,10.32 26.07,10.32 25.97,10.42 25.97,10.65 26.12,10.8 26.12,11.08 26.5,11.46 28,11.46 28.25,11.72 29.5,11.72
+1.8V_DVDDIO on TOP (solid shape): 38.68,15.77 38.68,14.19 38.54,14.05 35.16,14.05 35.01,13.9 33.82,13.9 33.77,13.95 33.77,14.08 33.82,14.13 34.64,14.13 35.3,14.79 36.67,14.79 37.41,15.53 37.63,15.61 37.71,15.83 37.75,15.87 38.58,15.87
+1.8V_EMMC on TOP (solid shape): outline of 81 points within 108.11,35.36 113.06,40.62
+1.8V_PRIM on TOP (solid shape): 83.8,40.93 83.8,39.96 83.7,39.86 82.42,39.86 82.12,39.56 81.82,39.56 81.25,40.13 81.25,40.36 82,41.11 83.63,41.11
+1.8V_PRIM on TOP (solid shape): 88.55,98.1 88.55,97.02 92.71,92.86 92.71,90.71 93.32,90.1 94.4,90.1 94.59,89.91 94.59,89.47 94.4,89.28 93.13,89.28 91.86,90.55 91.86,92.51 87.6,96.77 87.6,97.98 87.35,98.23 87.35,98.48 87.6,98.74 87.92,98.74
+1.8V_PRIM on TOP (solid shape): 108.17,34.86 110.02,34.86 110.52,34.35 111.16,34.35 111.22,34.29 111.22,33.97 111.03,33.78 105.69,33.78 105.39,34.08 102.4,34.08 102.14,34.34 102.14,34.79 102.14,35.05 102.46,35.36 107.67,35.36
+1.8V_PRIM on TOP (solid shape): 112.3,72.32 112.62,72 112.62,70.61 113,70.23 113,68.19 112.37,67.56 110.91,67.56 110.71,67.75 110.71,68.32 110.78,68.38 111.73,68.38 111.84,68.5 112.33,68.5 112.33,69.26 111.92,69.26 111.92,69.27 111.73,69.46 111.67,69.46 111.6,69.53 111.6,70.29 111.1,70.8 111.1,72.32 111.35,72.58 112.3,72.58
+1.8V_PRIM on TOP (solid shape): 80.93,98.67 80.93,96.32 80.87,96.26 80.55,96.26 80.36,96.45 78.39,96.45 76.11,94.17 67.92,94.17 66.9,95.18 66.9,96.45 66.33,97.02 64.99,97.02 64.93,97.09 64.93,97.4 65.06,97.53 66.58,97.53 69.31,94.8 75.92,94.8 78.46,97.34 78.77,97.34 80.23,98.8 80.81,98.8
+1.8V_PRIM on TOP (solid shape): outline of 433 points within 37.91,21.78 67.66,55.81
+1.8V_PRIM on BOTTOM (solid shape): 54.2,53.4 54.2,52.51 54.07,52.38 53.22,52.38 52.99,52.61 52.99,53.4 53.18,53.59 54.01,53.59
+1.8V_PRIM on BOTTOM (solid shape): 65.63,97.98 65.63,97.15 65.44,96.96 63.72,96.96 63.53,97.15 63.53,98.04 63.6,98.1 63.79,98.1 63.98,98.29 65.31,98.29
+1.8V_PRIM on BOTTOM (solid shape): 103.8,38.07 103.8,36.82 103.45,36.47 103.45,34.5 103.27,34.32 102.23,34.32 102.17,34.39 102.17,37.12 103.12,38.07 103.12,38.07 103.19,38.14 103.73,38.14
+1.8V_PRIM on BOTTOM (solid shape): 54.71,27.49 56.1,27.49 56.1,28.06 56.42,28.06 56.49,28 56.49,26.6 56.17,26.28 53.63,26.28 53.56,26.35 53.56,26.79 54.01,27.24 54.01,27.94 54.14,28.06 54.71,28.06
+1.8V_PRIM on BOTTOM (solid shape): 93.38,90.86 93.38,90.61 93.57,90.42 93.87,90.42 94.55,89.75 94.55,88.65 93.15,88.65 93.15,89.14 93.18,89.16 93.51,89.16 93.61,89.26 93.61,89.97 93.2,90.38 92.03,90.38 91.83,90.18 87.97,90.18 87.97,90.69 91.83,90.69 92.03,90.89 93.35,90.89
+1.8V_PRIM on IN1 (solid shape): outline of 87 points within 82.58,32.95 103.27,40.95
+1.8VALW_SOC on TOP (solid shape): 68.74,58.99 68.74,56.64 68.42,56.32 64.61,56.32 64.55,56.38 64.55,59.18 64.93,59.56 68.17,59.56
+1.8VALW_SOC on TOP (solid shape): 83.17,69.4 83.17,69.07 83.09,68.99 82.64,68.99 82.64,69 81.49,69 81.42,68.92 81.42,68.26 81.31,68.16 80.76,68.16 80.68,68.23 80.68,68.74 80.82,68.88 80.83,68.88 80.97,68.97 81.06,69.11 81.06,69.12 81.42,69.48 83.09,69.48
+1.8VALW_SOC on TOP (solid shape): 89.44,71.69 89.44,69.93 89.26,69.75 89.26,68.26 89.23,68.22 87.83,68.22 87.77,68.29 87.77,68.97 87.71,69.02 87.71,69.34 87.47,69.59 87.47,70.11 87.54,70.18 88.19,70.18 88.25,70.24 88.61,70.24 88.61,70.19 88.62,70.14 88.64,70.09 88.66,70.05 88.69,70 88.73,69.97 88.77,69.94 88.82,69.91 88.86,69.9 88.92,69.89 88.97,69.89 89.02,69.9 89.07,69.91 89.11,69.94 89.16,69.97 89.19,70 89.22,70.05 89.25,70.09 89.26,70.14 89.27,70.19 89.27,70.24 89.26,70.3 89.25,70.35 89.22,70.39 89.19,70.43 89.16,70.47 89.11,70.5 89.07,70.52 89.02,70.54 88.97,70.55 88.92,70.55 88.86,70.54 88.82,70.52 88.77,70.5 88.73,70.47 88.69,70.43 88.66,70.39 88.64,70.35 88.62,70.3 88.61,70.24 88.25,70.24 88.45,70.45 88.45,71.59 88.62,71.75 89.38,71.75
+1.8VALW_SOC on BOTTOM (solid shape): 88.63,69.65 88.63,68.04 88.45,67.86 87.55,67.86 87.37,68.04 87.41,68.07 87.41,68.87 87.61,69.07 87.61,69.38 87.61,69.4 87.56,69.43 87.41,69.58 87.41,69.66 87.43,69.68 87.5,69.73 87.55,69.81 87.57,69.83 88.45,69.83
+1.8VALW_SOC on IN1 (solid shape): outline of 896 points within 67.09,57.08 88.24,69.78
+1.8VALWP on TOP (solid shape): 53.5,30.03 53.5,28.76 53.37,28.63 52.36,28.63 52.23,28.76 52.23,30.03 52.36,30.16 53.37,30.16
+1.8VALWP on BOTTOM (solid shape): 56.42,33.78 56.42,28.25 53.82,28.25 53.44,28.63 50.71,28.63 50.71,29.27 51.6,30.16 53.37,30.16 54.01,30.79 54.01,33.78 54.14,33.9 56.3,33.9
+1.8VS on TOP (solid shape): 37.31,21.59 37.31,21.08 36.66,20.43 36.66,19.7 36.64,19.68 36.1,19.68 35.66,20.12 34.58,20.12 34.45,20.25 34.45,20.89 34.51,20.95 35.53,20.95 35.85,21.27 35.85,21.59 36.1,21.84 37.05,21.84
+1.24VALW on TOP (solid shape): 56.1,39.75 56.1,39.3 55.53,39.3 55.53,37.9 56.1,37.9 56.1,37.46 55.91,37.27 53.69,37.27 53.44,37.52 53.44,39.75 53.63,39.94 55.91,39.94
+1.24VALW on TOP (solid shape): 86.72,67.9 86.72,67.39 86.7,67.37 86.29,67.37 86.01,67.09 86.01,66.84 85.89,66.71 85.61,66.71 85.51,66.8 85.51,67.08 85.23,67.37 85.23,67.9 85.25,67.93 86.7,67.93
+1.24VALW on TOP (solid shape): 84.36,52.26 84.36,51.11 83.79,50.54 83.79,44.83 83.41,44.45 80.55,44.45 80.23,44.76 80.23,46.03 80.36,46.16 81.76,46.16 82.2,46.6 82.2,49.46 81.7,49.97 81.7,52.32 81.76,52.38 84.24,52.38
+1.24VALW on IN1 (solid shape): outline of 217 points within 53.22,38.1 81.82,48.33
+1.24VALWP on TOP (solid shape): 58.14,39.87 58.14,35.62 57.95,35.43 56.42,35.43 56.3,35.56 56.3,39.94 56.36,40 58.01,40
+1.24VALWP on BOTTOM (solid shape): 61.82,39.75 61.82,36.95 61.69,36.83 57.69,36.83 57.37,36.51 57.37,35.81 57.12,35.56 55.22,35.56 55.15,35.62 55.15,37.84 55.85,38.54 55.85,39.68 56.2,40.03 61.53,40.03
+2.5V_MEM on BOTTOM (solid shape): 26.07,123.82 26.07,122.49 24.93,122.49 24.8,122.61 24.8,123.76 24.93,123.88 26.01,123.88
+2.5V_MEM on BOTTOM (solid shape): 40.16,44.7 40.16,43.81 39.5,43.15 38.47,43.15 38.34,43.28 38.34,44.66 38.5,44.82 40.04,44.82
+2.5VP on BOTTOM (solid shape): 28.8,124.87 28.8,124.01 29.56,123.25 31.02,123.25 31.15,123.12 31.15,122.74 31.02,122.61 27.72,122.61 27.47,122.36 26.32,122.36 26.26,122.42 26.26,122.74 26.83,122.74 26.83,123.25 26.26,123.25 26.26,123.88 26.45,124.07 27.02,124.07 27.28,124.33 27.28,124.9 27.34,124.96 28.71,124.96
+3.3V_WLAN on TOP (solid shape): 69.25,137.98 69.25,130.51 69.2,130.32 69.25,130.14 69.25,126.12 69.12,125.84 69.25,125.56 69.25,123.69 70.33,122.61 70.33,121.53 70.14,121.34 66.84,121.34 66.77,121.41 66.77,123.25 66.46,123.57 65.82,123.57 65.69,123.69 65.69,127.95 65.95,128.2 66.96,128.2 67.15,128.39 67.15,138.17 69.06,138.17
+3.3V_WLAN on BOTTOM (solid shape): 70.77,122.46 72.2,122.46 72.25,122.4 72.25,121.3 72.11,121.15 69.25,121.15 69.12,121.28 69.12,122.55 69.25,122.68 70.56,122.68
+3.3V_WLAN on BOTTOM (solid shape): 72.27,140.04 72.27,139.25 72.17,139.15 70.67,139.15 69.69,138.17 69.69,136.9 69.44,136.65 67.79,136.65 67.66,136.77 67.66,138.62 69.21,140.17 72.14,140.17
+3V_DVDD on TOP (solid shape): 35.33,10.62 35.33,10.16 35.53,9.96 37.09,9.96 37.16,9.9 39.57,9.9 39.7,9.77 39.7,9.2 39.63,9.13 39.04,9.13 38.83,8.92 35.98,8.92 35.94,8.89 35.12,8.89 35.01,9 35.01,9.41 34.39,10.03 34.39,10.28 33.77,10.9 33.77,11.26 33.82,11.31 34.64,11.31
+3V_EMMC on TOP (solid shape): 105.06,46.04 105.06,45.76 105.16,45.65 107.41,45.65 107.54,45.52 107.54,44.45 107.17,44.08 105.06,44.08 104.94,44.2 104.94,44.52 104.82,44.64 104.82,44.64 104.37,45.08 104.17,45.08 104.05,45.21 104.05,46.03 104.11,46.1 105,46.1
+3V_EMMC on BOTTOM (solid shape): outline of 146 points within 111.67,40.9 114.86,43.87
+3VALW on TOP (solid shape): 92.43,48 91.22,46.79 90.01,46.79 89.82,46.99 89.82,47.94 90.52,48.64 90.9,48.64 91.41,49.14 91.41,49.33 92.43,49.33
+3VALW on TOP (solid shape): 90.59,54.73 90.59,53.91 90.46,53.78 90.01,53.78 88.74,55.05 88.74,55.56 88.81,55.62 89.7,55.62
+3VALW on TOP (solid shape): 65.12,125.53 64.99,125.41 62.96,125.41 62.77,125.6 62.77,127.95 63.03,128.2 65.12,128.2
+3VALW on TOP (solid shape): 21.78,78.12 21.78,76.66 21.62,76.5 19.92,76.5 19.66,76.77 19.66,78.16 19.77,78.28 21.62,78.28
+3VALW on TOP (solid shape): 58.96,43.3 58.96,42.92 58.39,42.92 58.39,42.41 58.96,42.41 58.96,41.4 58.71,41.14 56.49,41.14 56.3,41.33 56.3,43.18 56.55,43.43 58.84,43.43
+3VALW on TOP (solid shape): 157.9,55.88 157.9,54.8 157.39,54.8 157.39,53.97 157.9,53.97 157.9,53.59 157.39,53.59 157.39,52.76 157.83,52.76 157.83,52.19 157.77,52.13 156.5,52.13 155.1,53.53 155.1,54.41 154.66,54.86 154.66,55.81 154.91,56.07 157.7,56.07
+3VALW on TOP (solid shape): 106.32,86.69 106.32,86.08 106.42,86.08 106.46,86.04 107.67,86.04 108.03,85.67 108.03,84.27 108.03,84.26 108.01,84.13 108.03,84 108.03,83.99 108.03,83.29 107.29,82.55 107.29,82.03 106.5,81.24 105.8,81.24 105.7,81.34 105.7,82.12 105.73,82.19 105.8,82.22 106.03,82.34 106.12,82.58 106.12,82.6 106.17,82.66 106.17,83.34 105.44,84.07 105.44,86.74 105.51,86.8 106.21,86.8
+3VALW on TOP (solid shape): outline of 125 points within 135.86,50.6 151.48,58.73
+3VALW on BOTTOM (solid shape): 225.4,64.07 225.4,62.99 225.27,62.86 224.06,62.86 223.87,63.05 223.87,64.19 224.06,64.38 225.08,64.38
+3VALW on BOTTOM (solid shape): 37.5,120.14 38.01,120.14 38.01,120.71 38.83,120.71 38.96,120.58 38.96,119.57 38.77,119.38 37.44,119.38 37.18,119.63 37.18,120.65 37.25,120.71 37.5,120.71
+3VALW on BOTTOM (solid shape): 106.07,37.92 106.07,36.38 105.87,36.18 105.36,36.18 105.3,36.24 105.3,37.22 105.16,37.35 105.16,38.04 105.26,38.14 105.84,38.14
+3VALW on BOTTOM (solid shape): 50.83,37.4 50.83,35.75 50.58,35.5 45.75,35.5 45.75,35.49 45.11,35.49 45.11,36.06 44.6,36.06 44.6,35.49 44.03,35.49 43.84,35.68 43.84,36.7 44.73,37.59 50.64,37.59
+3VALW on BOTTOM (solid shape): 140.69,58.29 140.69,55.56 142.85,53.4 147.29,53.4 147.54,53.14 147.54,51.94 147.39,51.78 141.61,51.78 137.19,56.19 137.19,58.54 137.38,58.73 140.24,58.73
+3VALW on BOTTOM (solid shape): 18.7,78.42 19.4,78.42 19.53,78.29 20.35,78.29 21.21,77.43 21.21,75.59 21.12,75.5 19.91,75.5 19.72,75.69 19.72,76.1 18.13,77.69 18.13,78.42 18.58,78.42 18.58,78.99 18.7,78.99
+3VALW on IN1 (solid shape): 196.76,70.01 196.76,69.43 196.55,69.22 194.73,69.22 194.65,69.3 194.65,70.09 194.8,70.24 196.53,70.24
+3VALW on IN1 (solid shape): 225.84,65.15 225.84,62.8 225.78,62.73 225.6,62.73 225.33,63 224.37,63 224.27,63.1 224.27,65.21 224.39,65.34 224.89,65.34 225.14,65.59 225.4,65.59
+3VALW on IN1 (solid shape): outline of 198 points within 19.05,73.46 25.62,78.23
+3VALW on IN2 (solid shape): 195.97,70.01 195.97,69.43 195.5,68.96 193.9,68.96 193.81,69.05 193.81,69.99 193.99,70.16 195.82,70.16
+3VALW on IN2 (solid shape): outline of 645 points within 137,51.75 157.58,60
+3VALW on VCC: outline of 133 points within 20.01,32.06 140.05,136.65 ; 1 cut-out
+3VALW_1.8V on BOTTOM (solid shape): 47.02,35.17 47.02,34.48 46.9,34.35 45.56,34.35 45.12,33.9 45.12,32.44 45.06,32.38 43.15,32.38 42.9,32.63 42.9,35.11 43.09,35.3 46.9,35.3
+3VALW_1.24V on TOP (solid shape): 61.57,43.37 61.57,42.22 60.68,41.33 60.68,40.64 60.49,40.44 59.28,40.44 59.15,40.57 59.15,43.3 59.28,43.43 61.5,43.43
+3VALW_2.5V on BOTTOM (solid shape): 36.55,123.19 37.69,123.19 38.39,122.49 38.39,120.96 38.32,120.9 37.12,120.9 36.8,121.22 36.8,122.11 36.36,122.55 34.58,122.55 34.39,122.74 34.39,123.12 34.58,123.31 36.42,123.31
+3VALW_EC on BOTTOM (solid shape): 114.84,39.62 114.84,38.79 115.03,38.6 115.35,38.6 115.41,38.54 115.41,38.03 115.35,37.97 113.95,37.97 113.88,38.04 113.88,38.66 113.72,38.82 113.72,39.43 113.83,39.53 114.26,39.53 114.38,39.66 114.8,39.66
+3VALW_EC on BOTTOM (solid shape): 117,53.14 117,52.13 117.64,51.49 118.91,51.49 119.16,51.24 119.16,51.18 119.1,51.11 117.45,51.11 117.13,51.43 116.18,51.43 116.11,51.49 116.11,52.38 115.86,52.64 115.35,52.64 115.19,52.48 115.19,48.73 114.72,48.26 114.46,48.26 114.23,48.48 114.23,49.04 114.52,49.33 114.52,53.08 114.84,53.4 116.75,53.4
+3VALW_EC on BOTTOM (solid shape): 134.72,38.03 134.72,35.68 134.27,35.24 133.26,35.24 133.07,35.05 132.24,35.05 132.18,35.11 132.18,38.03 132.24,38.1 132.43,38.1 132.5,38.03 132.5,36.44 133,35.94 133.83,35.94 134.02,36.13 134.02,38.03 134.21,38.22 134.53,38.22
+3VALW_EC on BOTTOM (solid shape): 127.35,57.97 127.35,56.44 127.31,56.39 126.74,56.39 126.74,57.36 126.69,57.41 126.69,57.51 126.37,57.82 126.27,57.82 125.92,57.89 125.66,57.64 125.43,57.4 124.94,57.4 124.81,57.53 124.81,58.1 124.94,58.22 127.1,58.22
+3VALW_EC on BOTTOM (solid shape): 115.86,44.45 115.86,43.38 115.85,43.37 115.85,43.29 115.83,43.23 115.76,43.19 115.43,42.87 115.69,42.5 115.73,42.49 115.73,41.97 115.67,41.91 115.16,41.91 115.03,42.03 115.03,43.18 114.99,43.22 114.99,43.27 114.89,43.37 113.7,43.37 113.64,43.43 113.64,43.68 113.7,43.75 114.91,43.75 115.1,43.94 115.1,44.5 115.81,44.5
+3VALW_SOC on TOP (solid shape): 89.06,59.11 89.06,57.65 89.7,57.02 89.7,56.38 88.81,56.38 88.81,56.57 87.98,57.4 87.66,57.4 87.47,57.59 87.47,58.92 87.85,59.3 88.87,59.3
+3VALW_SOC on TOP (solid shape): 88.5,68.05 88.63,67.93 88.63,66.53 88.27,66.18 88.24,66.14 88.24,65.93 88.21,65.9 87.68,65.9 87.64,65.93 87.64,66.05 87.64,66.1 86.98,66.76 86.98,67.98 87.05,68.05 88.46,68.05
+3VALW_SOC on TOP (solid shape): 65.57,110.49 66.96,110.49 67.53,111.06 68.46,111.06 69,110.53 69,109.41 68.48,109.41 68.48,110.22 68.26,110.44 67.58,110.44 67.25,110.1 64.99,110.1 64.3,109.41 64.3,108.26 64.74,107.82 65.88,107.82 66.16,107.54 66.16,107.17 66.09,107.09 64.51,107.09 63.28,108.33 63.28,110.01 62.9,110.39 62.43,110.39 62.33,110.49 62.33,110.99 62.45,111.12 64.93,111.12
+3VALW_SOC on BOTTOM (solid shape): 88.63,67.32 88.63,66.91 88.61,66.81 88.63,66.7 88.63,66.42 88.19,65.98 88.18,65.98 88.07,65.91 87.99,65.82 87.98,65.79 87.82,65.79 87.37,66.24 87.34,66.25 87.22,66.28 87.09,66.25 87.08,66.24 86.83,66.24 86.65,66.42 86.65,66.6 86.68,66.61 86.87,66.93 86.68,67.25 86.65,67.26 86.65,67.32 86.97,67.64 87.01,67.68 88.27,67.68
+3VALW_SOC on IN1 (solid shape): outline of 307 points within 86.95,58 89.18,68.86
+3VALWP on TOP (solid shape): 165.01,54.73 165.01,51.11 164.94,51.05 158.34,51.05 158.15,51.24 158.15,52.95 157.58,52.95 157.58,53.4 158.15,53.4 158.15,54.16 157.58,54.16 157.58,54.54 158.15,54.54 158.15,55.94 158.28,56.07 163.67,56.07
+3VALWP on BOTTOM (solid shape): 165.01,54.99 165.01,51.87 165.45,51.43 165.45,51.37 165.01,50.92 158.57,50.92 158.3,51.19 158.3,55.41 158.45,55.55 159.98,55.55 159.99,55.56 164.44,55.56
+3VLP on BOTTOM (solid shape): 126.56,57.45 126.56,56.4 126.53,56.37 125.25,56.37 125.22,56.41 125.22,57.01 125.9,57.69 126.32,57.69
+3VLP on BOTTOM (solid shape): 166.66,57.97 166.66,57.4 166.21,56.95 166.21,55.3 166.15,55.24 165.45,55.24 165.26,55.43 165.26,57.91 165.39,58.03 166.59,58.03
+3VS on TOP (solid shape): 218.79,50.29 218.79,48.32 218.54,48.06 216.82,48.06 216.76,48.13 216.76,49.72 216.76,50.4 217.03,50.67 218.41,50.67
+3VS on TOP (solid shape): 219.93,28.25 219.93,27.36 219.81,27.24 218.73,27.24 218.6,27.36 218.6,28.25 218.73,28.38 219.81,28.38
+3VS on TOP (solid shape): 39.93,8.69 39.93,7.84 39.73,7.65 38.95,7.65 38.83,7.77 38.83,7.96 38.96,8.09 38.96,8.66 39.04,8.75 39.87,8.75
+3VS on TOP (solid shape): 64.93,125.03 64.93,120.52 64.87,120.45 63.66,120.45 63.15,120.96 63.15,124.84 63.41,125.09 64.87,125.09
+3VS on TOP (solid shape): 219.49,59.37 219.49,58.22 219.3,58.03 217.33,58.03 217.14,58.22 217.14,59.75 217.2,59.81 219.05,59.81
+3VS on TOP (solid shape): 148.75,50.35 148.18,50.35 148.18,48.32 148.75,48.32 148.75,47.68 148.5,47.43 146.45,47.43 145.84,47.43 144.62,47.43 144.24,47.81 144.24,49.34 144.29,49.39 144.29,50.17 144.27,50.19 144.27,50.22 144.28,50.33 144.25,50.44 144.24,50.45 144.24,50.6 144.49,50.85 144.88,50.85 144.89,50.86 148.75,50.86
+3VS on TOP (solid shape): outline of 786 points within 34.3,21.98 48.99,49.84
+3VS on BOTTOM (solid shape): 117.91,34.2 118.33,34.2 118.46,34.07 118.46,33.89 118.33,33.75 117.73,33.75 117.26,34.22 116.43,34.22 116.18,33.97 114.65,33.97 114.53,34.09 114.53,34.52 114.74,34.73 117.38,34.73
+3VS on BOTTOM (solid shape): 202.54,37.4 202.54,36.19 204.44,34.29 213.71,34.29 214.03,33.97 214.03,32.25 213.65,31.87 202.92,31.87 201.27,33.52 201.27,35.56 201.84,36.13 201.84,37.4 201.96,37.52 202.41,37.52
+3VS on BOTTOM (solid shape): 44.48,112.71 44.48,109.09 46.95,106.61 46.95,50.68 48.42,49.21 48.8,49.21 48.98,49.03 48.98,47.87 48.67,47.56 44.29,47.56 42.76,46.03 42.76,44 41.05,42.29 40.16,42.29 39.97,42.48 39.97,43.26 40.78,44.06 40.78,47.09 41.15,47.47 41.34,47.57 41.44,47.75 44.48,50.79 44.48,104.9 41.36,108.01 41.36,110.87 40.48,111.75 40.48,111.76 40.29,111.94 40.29,112.96 40.42,113.09 44.09,113.09
+3VS on BOTTOM (solid shape): 111.16,64.26 111.67,64.26 111.92,64 112.6,64 112.73,63.87 112.73,63.62 113.12,63.23 113.65,63.23 113.7,63.18 113.7,62.41 113.56,62.27 112.61,62.27 112.05,62.83 112.05,63.56 111.92,63.69 111.81,63.69 111.73,63.7 111.64,63.69 111.31,63.69 111.23,63.7 111.14,63.69 110.9,63.69 110.62,63.75 110.37,63.62 110.09,63.34 110.09,62.92 109.91,62.73 109,62.73 108.87,62.86 108.87,63.37 109,63.5 109.7,63.5 109.76,63.56 109.76,63.88 110.33,64.45 110.97,64.45
+3VS on IN2 (solid shape): 39.94,9.33 39.94,7.83 39.73,7.62 38.94,7.62 38.82,7.73 38.82,9.35 38.92,9.45 39.83,9.45
+3VS on IN2 (solid shape): 37.59,21.65 37.59,21.51 37.04,20.96 36.71,20.96 36.25,21.42 35.43,21.42 35.13,21.72 35.13,22.39 35.26,22.51 36.72,22.51
+3VS on IN2 (solid shape): outline of 992 points within 212,26.92 223.49,55.68
+3VS on VCC: 54.94,104.71 47.07,112.52 40.08,112.52 39.53,113.07 39.53,116.41 39.76,116.64 59.77,116.64 61.38,118.25 61.38,123.21 61.73,123.57 66.54,123.57 73.95,116.16 73.95,105.19 73.46,104.71
+3VS on VCC: 42.94,28.76 40.36,31.34 40.36,32.34 44.02,36 50.81,36 52.02,37.21 91.81,37.21 94.61,34.41 117.17,34.41 123.73,40.97 123.73,47.96 131.84,56.07 139.39,56.07 140.56,57.23 140.56,68.15 140.99,68.58 161.54,68.58 161.56,68.6 162.48,69.07 162.95,69.99 162.97,70.01 162.97,71.38 163.52,71.94 217.48,71.94 218.6,70.82 218.6,48.55 217.86,47.81 206.96,47.81 206.54,48.23 206.54,55.54 200.42,61.65 196.65,61.65 196,61 196,55.45 197.77,53.67 197.77,45.63 197.29,45.14 183.7,45.14 183.06,44.51 170.7,44.51 162.19,53.02 152.27,53.02 148.39,49.14 140.71,49.14 138.02,46.46 138.02,38.96 128.96,29.9 45.14,29.9 44,28.76 ; 4 cut-outs
+3VS_CAM on TOP (solid shape): 217.84,47.3 217.84,46.03 217.78,45.97 216.38,45.97 216.12,46.22 213.28,46.22 213.1,46.4 213.1,47.23 213.23,47.36 213.52,47.36 213.52,47.37 214.85,47.37 214.92,47.43 217.71,47.43
+3VS_CAM on IN1 (solid shape): 217.9,47.24 217.9,46.1 217.71,45.91 216.63,45.91 216.51,46.03 216.51,47.24 216.7,47.43 217.71,47.43
+3VS_OUT on TOP (solid shape): 149.36,50.78 150.66,50.78 150.76,50.68 150.76,49.73 150.8,49.69 151.39,49.69 151.47,49.61 151.47,48.95 151.09,48.57 151.09,47.64 151.09,47.63 151.09,46.85 149.13,46.85 148.93,47.05 148.93,48.55 148.37,48.55 148.37,48.93 148.93,48.93 148.93,49.74 148.4,49.74 148.4,50.15 148.93,50.15 148.93,50.83 149.31,50.83
+3VS_SSD on TOP (solid shape): 23.91,27.74 23.91,26.73 23.78,26.6 20.48,26.6 20.35,26.73 20.35,27.43 20.93,28 23.66,28
+3VS_SSD on TOP (solid shape): 38.2,32.82 38.2,29.84 38.58,29.46 38.58,27.49 38.39,27.3 35.34,27.3 35.21,27.43 35.21,29.78 35.72,30.28 35.72,32.7 35.91,32.89 38.13,32.89
+3VS_SSD on BOTTOM (solid shape): 39.4,29.71 39.4,29.1 39.32,28.75 39.4,28.4 39.4,25.79 39.28,25.66 38.57,25.66 38.46,25.76 38.46,27.29 38.32,27.43 36.91,27.43 36.79,27.3 36.79,25.79 36.69,25.69 35.06,25.69 34.96,25.79 34.96,27.24 34.26,27.94 33.53,27.94 33.52,27.94 33.37,27.97 33.22,27.94 33.21,27.94 29.69,27.94 29.18,28.44 23.49,28.44 22.28,27.24 22.28,25.76 22.17,25.65 20.99,25.65 20.61,26.03 20.61,27.74 20.87,28 21.23,28.37 21.23,28.66 22.73,30.16 38.96,30.16
+5V_AVDD on TOP (solid shape): 28.67,20.7 28.67,19.87 28.56,19.76 28.56,17.33 29.96,15.93 29.96,15.17 29.9,15.12 29.35,15.12 27.44,17.03 27.44,19.36 27.26,19.54 26.59,19.54 26.32,19.81 26.32,20.44 26.36,20.48 27.38,20.48 27.42,20.52 27.42,20.67 27.5,20.76 28.61,20.76
+5V_HDD on BOTTOM (solid shape): 183.04,41.08 183.04,40.38 183.99,39.43 185.52,39.43 185.84,39.11 185.84,35.17 185.77,35.11 182.6,35.11 182.41,35.3 182.41,37.21 181.96,37.65 181.96,41.08 182.03,41.14 182.98,41.14
+5V_HDMI on TOP (solid shape): 24.93,97.21 24.93,94.99 24.74,94.8 24.74,94.1 24.67,94.04 23.97,94.04 23.78,94.23 23.78,97.09 23.97,97.28 24.86,97.28
+5V_HDMI on BOTTOM (solid shape): 15.15,104.39 15.15,102.61 14.96,102.42 14.32,102.42 14,102.74 14,103.76 14,103.77 14,104.33 14.26,104.58 14.96,104.58
+5V_HDMI on BOTTOM (solid shape): 13.81,109.28 13.81,108.64 13.69,108.52 13.69,106.93 13.62,106.87 13.31,106.87 13.24,106.93 12.16,106.93 10.96,108.14 10.96,109.28 11.08,109.41 13.69,109.41
+5V_HDMI on IN2 (solid shape): 15.02,103.37 15.02,100.77 14.64,100.39 12.23,100.39 12.04,100.58 12.04,101.47 14.13,103.56 14.83,103.56
+5V_KB_BL on BOTTOM (solid shape): 95.92,34.79 95.92,34.54 95.47,34.09 94.97,34.09 94.84,34.22 94.84,34.92 94.97,35.05 95.67,35.05
+5V_PVDD on TOP (solid shape): 31.17,10.85 31.17,10.02 31.23,9.96 31.23,9.66 30.82,9.25 30.82,8.12 30.7,8.01 30.7,7.68 30.9,7.49 33.5,7.49 33.82,7.81 33.82,8.31 33.75,8.38 33.75,9.14 32.95,9.94 32.95,10.85 33,10.9 33.1,10.9 33.16,10.85 33.16,10.09 33.36,9.89 33.69,9.89 34.12,9.46 34.12,8.75 34.15,8.72 34.71,8.72 35.37,8.06 36.15,8.06 36.37,7.84 36.37,6.45 36.33,6.41 35.64,6.41 35.39,6.66 29.94,6.66 29.94,7.62 30.45,8.12 30.45,9.32 30.95,9.81 30.95,10.83 31.02,10.9 31.12,10.9
+5VALW on TOP (solid shape): 51.15,50.6 51.15,49.65 51.09,49.59 49.37,49.59 49.25,49.72 49.25,50.6 49.37,50.73 51.02,50.73
+5VALW on TOP (solid shape): 51.65,44.7 51.65,43.75 51.46,43.56 50.57,43.56 50.38,43.75 50.38,44.7 50.51,44.83 51.52,44.83
+5VALW on TOP (solid shape): 20.1,43.24 20.1,41.4 19.85,41.14 19.85,40.38 19.72,40.25 18.45,40.25 18.32,40.38 18.32,41.02 18.07,41.27 18.07,43.24 18.32,43.49 19.85,43.49
+5VALW on TOP (solid shape): 156.31,52.13 156.31,50.22 156.18,50.1 153.83,50.1 153.64,50.29 153.64,50.8 153.51,50.92 152.88,50.92 152.82,50.99 152.82,51.75 152.86,51.8 152.89,51.79 153.29,51.93 153.28,52.35 153.26,52.45 153.36,52.51 153.96,52.51 154.02,52.57 154.02,52.95 154.28,53.21 155.23,53.21
+5VALW on BOTTOM (solid shape): 50.39,50.86 50.39,49.78 50.26,49.65 49.37,49.65 49.25,49.78 49.25,50.8 49.37,50.92 50.33,50.92
+5VALW on BOTTOM (solid shape): 198.05,41.52 198.05,39.64 197.77,39.37 196.12,39.37 195.87,39.62 195.87,41.21 196.25,41.59 197.99,41.59
+5VALW on BOTTOM (solid shape): 47.98,119.12 47.98,118.17 47.79,117.98 46.96,117.98 46.2,118.74 46.2,119.06 46.39,119.25 47.85,119.25
+5VALW on BOTTOM (solid shape): 96.78,135.64 96.78,134.81 96.81,134.78 96.81,134.53 96.55,134.27 96.55,132.77 96.49,132.71 96.08,132.71 95.97,132.82 95.97,134.15 96.55,134.73 96.55,135.64 96.6,135.69 96.73,135.69
+5VALW on BOTTOM (solid shape): 220.32,78.16 221.14,78.16 221.14,78.74 221.52,78.74 221.52,78.16 222.35,78.16 222.35,78.74 223.49,78.74 223.62,78.61 223.62,76.07 223.36,75.81 219.55,75.81 219.36,76 219.36,78.54 219.55,78.74 220.32,78.74
+5VALW on BOTTOM (solid shape): 85.42,131.33 85.42,130.17 85.19,129.94 85.19,128.54 85,128.35 85,127.34 84.92,127.26 84.26,127.26 84.18,127.34 84.18,128.2 84.24,128.25 84.51,128.25 84.73,128.47 84.73,129.92 85.18,130.37 85.18,131.32 85.24,131.38 85.37,131.38
+5VALW on IN1 (solid shape): 51.65,44 51.65,43.49 51.46,43.3 51.46,42.48 50.45,42.48 50.45,44 50.57,44.13 51.52,44.13
+5VALW on IN1 (solid shape): 58.52,29.65 59.03,29.14 59.03,28.76 58.84,28.57 57.95,28.57 57.5,29.01 57.5,29.97 58.52,29.97
+5VALW on VCC: outline of 95 points within 17.62,22.67 227.23,78.42
+5VALWP on TOP (solid shape): 223.74,81.34 223.74,80.2 223.55,80.01 218.73,80.01 218.6,80.13 218.6,81.4 218.73,81.53 223.55,81.53
+5VALWP on BOTTOM (solid shape): 223.74,81.47 223.74,79.05 223.62,78.93 222.16,78.93 222.16,78.35 221.71,78.35 221.71,78.93 220.95,78.93 220.95,78.35 220.57,78.35 220.57,78.93 219.36,78.93 219.11,78.67 219.11,77.66 218.86,77.4 215.3,77.4 215.17,77.53 215.17,81.34 215.43,81.59 223.62,81.59
+5VS on TOP (solid shape): 27.4,22.35 27.4,21.33 27.28,21.2 26.39,21.2 26.26,21.33 26.26,22.35 26.39,22.47 27.28,22.47
+5VS on TOP (solid shape): 38.43,7.5 38.79,7.5 38.79,7.49 39.4,7.49 39.59,7.3 39.59,6.44 39.44,6.28 37.36,6.28 37.24,6.4 37.24,7.84 37.28,7.88 38.04,7.88
+5VS on TOP (solid shape): outline of 1383 points within 67.55,23.68 215.68,49.53
+5VS on BOTTOM (solid shape): 14.32,111.82 14.32,110.55 13.94,110.17 11.53,110.17 11.08,110.61 11.08,111.95 11.27,112.14 14,112.14
+5VS on BOTTOM (solid shape): 185.84,41.65 185.84,40.19 185.64,40 183.68,40 183.42,40.25 183.42,41.65 183.55,41.78 185.71,41.78
+5VS on BOTTOM (solid shape): 198.66,61.91 198.66,59.9 198.51,59.75 196.57,59.75 196.57,61.93 196.73,62.1 198.47,62.1
+5VS on IN1 (solid shape): 21.53,74.96 21.53,73.81 20.96,73.81 20.58,74.2 20.58,74.96 20.64,75.02 21.47,75.02
+5VS on IN1 (solid shape): outline of 833 points within 24.99,6.3 149.49,34.92
+5VS on IN2 (solid shape): 14.19,111.76 14.19,110.42 14.13,110.36 13.18,110.36 13.05,110.49 13.05,111.82 13.12,111.88 14.07,111.88
+5VS on IN2 (solid shape): outline of 302 points within 15.66,73.85 21.88,87.18
+5VS on VCC: 194.11,41.84 193.1,40.83 183.53,40.83 183.42,40.93 183.42,44.15 183.91,44.64 197.5,44.64 198.28,45.42 198.28,53.89 196.5,55.66 196.5,60.79 196.86,61.15 200.21,61.15 206.03,55.33 206.03,42.02 205.85,41.84
+5VS_ODD on BOTTOM (solid shape): 195.49,67.62 195.49,63.69 196.38,62.8 196.38,61.34 195.8,61.34 195.8,59.94 195.82,59.93 196.38,59.93 196.38,59.75 193.84,59.75 193.33,60.26 193.33,62.54 192.88,62.99 192.88,67.56 193.07,67.75 195.36,67.75
+5VS_OUT on TOP (solid shape): 155.43,49.64 155.43,46.52 154.24,46.52 153.96,46.79 153.2,46.79 153.13,46.86 153.13,48.6 152.82,48.92 152.82,49.65 152.88,49.72 153.45,49.72 153.7,49.97 155.1,49.97
+17.4V_BATT on BOTTOM (solid shape): 176.5,56.95 176.5,45.91 175.93,45.33 170.28,45.33 170.21,45.4 170.21,45.91 170.28,45.97 170.98,45.97 171.1,46.1 171.1,46.6 170.91,46.79 170.28,46.79 170.09,46.99 170.09,52.83 172.88,55.62 172.88,56.37 174.25,56.37 174.26,56.32 174.27,56.27 174.29,56.22 174.31,56.17 174.35,56.13 174.39,56.09 174.43,56.06 174.48,56.04 174.53,56.02 174.58,56.01 174.63,56.01 174.69,56.02 174.74,56.04 174.79,56.06 174.83,56.09 174.87,56.13 174.9,56.17 174.93,56.22 174.95,56.27 174.96,56.32 174.97,56.37 174.96,56.42 174.95,56.48 174.93,56.53 174.9,56.57 174.87,56.61 174.83,56.65 174.79,56.68 174.74,56.7 174.69,56.72 174.63,56.73 174.58,56.73 174.53,56.72 174.48,56.7 174.43,56.68 174.39,56.65 174.35,56.61 174.31,56.57 174.29,56.53 174.27,56.48 174.26,56.42 174.25,56.37 172.88,56.37 172.88,56.89 173.14,57.15 176.31,57.15
+17.4V_BATT+ on TOP (solid shape): 169.83,46.97 169.83,46.46 169.6,46.24 167.38,46.24 166.71,45.57 162.8,45.57 162.75,45.63 162.75,47.33 162.82,47.41 169.39,47.41
+17.4V_BATT+ on BOTTOM (solid shape): 169.2,47.3 169.2,46.86 169.13,46.79 168.31,46.79 168.18,46.67 168.18,46.22 168.44,45.97 169.07,45.97 169.13,45.91 169.13,44.25 169.33,44.06 169.33,43.81 168.69,43.81 168.25,44.25 163.99,44.25 163.74,44.51 162.98,44.51 162.98,43.98 162.77,43.98 162.77,44.48 162.16,44.48 162.16,43.95 161.96,43.95 161.96,44.51 160.96,44.51 160.75,44.71 160.75,46.41 161.98,46.41 161.99,46.36 162,46.31 162.02,46.26 162.05,46.21 162.08,46.17 162.12,46.13 162.16,46.1 162.21,46.08 162.26,46.07 162.31,46.06 162.37,46.06 162.42,46.07 162.47,46.08 162.52,46.1 162.56,46.13 162.6,46.17 162.63,46.21 162.66,46.26 162.68,46.31 162.69,46.36 162.7,46.41 162.69,46.47 162.68,46.52 162.66,46.57 162.63,46.61 162.6,46.66 162.56,46.69 162.52,46.72 162.47,46.75 162.42,46.76 162.37,46.77 162.31,46.77 162.26,46.76 162.21,46.75 162.16,46.72 162.12,46.69 162.08,46.66 162.05,46.61 162.02,46.57 162,46.52 161.99,46.47 161.98,46.41 160.75,46.41 160.75,47.05 161.13,47.43 169.07,47.43
+17.4V_BATT++ on BOTTOM (solid shape): 161.77,44.27 161.77,43.75 161.79,43.77 162.37,43.77 162.39,43.8 162.39,44.31 162.54,44.31 162.57,44.28 162.57,43.75 163.17,43.75 163.17,44.29 163.18,44.31 163.58,44.31 163.83,44.06 165.07,44.06 165.2,43.94 165.2,43.43 165.13,43.37 164.44,43.37 164.18,43.11 164.18,41.59 163.93,41.33 159.99,41.33 159.61,40.95 159.61,39.3 159.36,39.05 154.85,39.05 154.66,39.24 154.66,43.56 155.41,44.31 161.73,44.31
+19V_ADPIN on TOP (solid shape): 92.11,148.17 92.11,147.59 91.85,147.33 91.85,144.15 91.59,143.89 87.78,143.89 87.47,144.2 87.47,147.52 88.2,148.24 92.03,148.24
+19V_ADPIN on BOTTOM (solid shape): 91.54,147.06 91.54,143.31 91.41,143.19 88.93,143.19 88.74,143.38 88.74,144.52 88.05,145.22 88.05,147.12 88.36,147.44 91.16,147.44
+19V_VIN on TOP (solid shape): 165.26,68.32 165.26,67.94 164.82,67.5 164.82,62.54 164.5,62.23 157.96,62.23 157.51,62.67 157.51,63.69 156.05,65.15 156.05,66.99 157.45,68.38 164.5,68.38 164.59,68.48 165.1,68.48
+19V_VIN on TOP (solid shape): 118.14,106.71 118.14,102.67 118.02,102.55 114.91,102.55 114.59,102.87 114.59,106.04 112.75,107.88 112.75,108.96 112.94,109.15 115.7,109.15
+19V_VIN on TOP (solid shape): 105.77,147.78 105.77,142.5 105.44,142.17 104.35,142.17 101.91,144.61 95.98,144.61 95.97,144.6 95.41,144.6 94.81,144 92.22,144 92.04,144.18 92.04,144.8 92.61,144.8 92.61,145.4 92.03,145.4 92.03,145.6 92.61,145.6 92.61,146.2 92.04,146.2 92.04,147.28 92.92,148.17 105.39,148.17
+19V_VIN on IN2 (solid shape): 105.7,146.53 105.7,144.18 105.46,143.95 104.15,143.95 103.92,144.18 103.92,146.53 104.05,146.66 105.57,146.66
+19V_VIN on IN2 (solid shape): 116.46,108.89 116.46,104.06 116.27,103.87 115.06,103.87 114.75,104.19 114.75,109.35
+19VB on TOP (solid shape): 27.66,111.18 27.66,109.53 27.4,109.28 25.5,109.28 25.37,109.41 25.37,111.37 25.43,111.44 27.4,111.44
+19VB on TOP (solid shape): 103.98,130.49 103.98,125.09 103.79,124.9 101.51,124.9 101.32,125.09 101.32,128.33 100.68,128.96 100.47,128.96 97.78,128.96 97.61,128.96 94.92,128.96 94.71,128.96 94.08,128.33 92.43,128.33 92.3,128.46 92.3,130.74 92.49,130.93 103.54,130.93
+19VB on TOP (solid shape): 182.19,61.22 182.26,61.17 182.34,61.14 182.38,61.13 182.38,58.17 183.88,56.68 183.88,55.23 183.7,55.05 180.91,55.05 180.73,55.23 180.73,56.5 181.16,56.93 181.16,58.63 180.91,58.89 180.33,58.89 180.27,58.89 180.22,58.89 179.16,58.89 179.03,59.02 178.92,59.1 178.8,59.15 178.76,59.16 178.76,60.24 178.81,60.33 178.91,60.33 179.15,60.29 179.37,60.39 179.52,60.54 180.3,60.54 180.45,60.69 180.45,61.17 180.3,61.32 179.93,61.32 179.92,61.32 179.59,61.32 179.54,61.37 179.54,61.84 180.42,61.84 181.56,61.84
+19VB on BOTTOM (solid shape): 27.72,111.18 27.72,109.61 27.4,109.29 25.74,109.29 25.68,109.36 25.68,109.8 26.13,109.8 26.13,110.31 25.68,110.31 25.68,111.05 25.94,111.31 27.59,111.31
+19VB on BOTTOM (solid shape): 120.62,105.85 120.62,99.75 119.92,99.06 117.26,99.06 116.56,99.75 116.56,106.1 115.67,106.99 115.67,107.88 116.3,108.52 117.95,108.52
+19VB on BOTTOM (solid shape): 105.7,128.96 105.7,121.03 105.19,120.52 103.54,120.52 102.4,121.66 102.4,124.32 101.76,124.95 101.76,125.48 101.81,125.53 102.24,125.53 102.24,126.04 101.76,126.04 101.74,126.07 101.74,126.65 103.22,128.14 103.22,129.22 103.35,129.34 105.32,129.34
+19VB on BOTTOM (solid shape): 202.96,61.61 203.26,61.09 203.62,60.62 203.62,60.57 203.81,60.38 203.81,55.56 203.49,55.24 201.77,55.24 201.58,55.43 201.58,59.62 200.52,60.68 200.52,61.93 200.82,62.23 202.35,62.23
+19VB on BOTTOM (solid shape): 92.93,130.68 92.93,128.52 92.68,128.27 92.43,128.27 91.22,127.06 89.7,127.06 88.55,125.92 88.55,125.58 88.29,125.31 86.84,125.31 86.81,125.29 86.32,125.29 86.2,125.41 86.2,127.38 86.33,127.5 88.74,127.5 89,127.76 89,127.78 89,128.65 90.03,129.67 90.77,129.67 91.13,130.04 91.17,130.08 91.2,130.12 91.88,130.81 92.81,130.81
+19VB on BOTTOM (solid shape): outline of 608 points within 154.59,53.72 199.04,77.15
+19VB on IN1 (solid shape): 120.63,107.44 120.63,103.77 120.49,103.63 117.95,103.63 117.32,104.26 117.32,107.5 117.64,107.82 120.25,107.82
+19VB on IN1 (solid shape): 28.48,112.9 28.48,112.64 28.04,112.2 28.04,109.66 27.78,109.41 26.89,109.41 26.58,109.72 26.58,112.96 27.09,113.47 27.91,113.47
+19VB on IN1 (solid shape): 105.79,129 105.79,123.98 105.57,123.76 103.29,123.76 103.19,123.85 103.19,127.85 104.4,129.06 105.73,129.06
+19VB on IN1 (solid shape): outline of 87 points within 68.55,139.06 75.98,143.38
+19VB_1.2V on TOP (solid shape): 24.74,111.12 24.74,109.34 25.18,108.9 26.07,108.9 26.13,108.83 26.13,107.18 25.69,106.74 24.93,106.74 24.74,106.93 24.74,107.37 24.04,108.07 23.15,108.07 22.83,108.39 22.83,111.12 22.96,111.25 24.61,111.25
+19VB_1.2V on BOTTOM (solid shape): 25.37,110.87 25.37,109.22 25.75,108.83 26.01,108.83 26.13,108.71 26.13,107.12 26.26,106.99 27.15,106.99 27.28,106.87 27.28,105.15 27.09,104.96 23.66,104.96 23.59,105.02 23.59,105.53 23.66,105.6 24.16,105.6 24.29,105.72 24.29,106.5 24.61,106.82 24.61,107.32 24.48,107.45 23.85,107.45 23.66,107.64 23.66,110.87 23.78,110.99 25.24,110.99
+19VB_1.05V on TOP (solid shape): 155.55,61.78 155.55,60.76 155.36,60.57 152.69,60.57 152.56,60.7 152.56,61.72 152.75,61.91 155.42,61.91
+19VB_1.05V on BOTTOM (solid shape): 157.58,62.16 157.58,60.7 157.45,60.57 152.43,60.57 152.31,60.7 152.31,61.34 152.12,61.53 149.45,61.53 149.39,61.59 149.39,61.72 149.51,61.84 151.8,61.84 151.86,61.91 155.48,61.91 155.86,62.29 157.45,62.29
+19VB_3V on TOP (solid shape): 174.6,61.15 174.6,60.07 174.53,60 171.1,60 170.8,60.3 170.8,61.16 170.98,61.34 174.41,61.34
+19VB_3V on BOTTOM (solid shape): 174.66,61.4 174.66,60.07 174.6,60 171.17,60 171.04,60.13 169.39,60.13 168.69,59.43 167.29,59.43 167.23,59.49 167.23,60.76 167.42,60.96 167.42,61.78 167.67,62.03 174.02,62.03
+19VB_5V on TOP (solid shape): 202.79,77.78 202.79,76.7 202.66,76.58 199.87,76.58 199.74,76.7 199.74,77.78 199.81,77.85 202.73,77.85
+19VB_5V on BOTTOM (solid shape): 206.05,78.39 206.05,77.1 206.05,77.1 206.05,76.28 206.05,76.28 206.05,74.3 205.72,73.97 202.47,73.97 202.28,73.78 202.28,69.59 202.03,69.34 200.65,69.34 200.63,69.35 198.97,69.35 198.79,69.53 198.79,70.1 199.3,70.1 199.3,70.8 198.79,70.8 198.79,70.92 199.3,70.92 199.3,71.62 198.85,71.62 198.85,77.14 199.56,77.85 202.73,77.85 202.84,77.73 203.16,77.73 203.23,77.7 203.26,77.64 203.62,77.3 203.97,77.64 204,77.7 204.07,77.73 204.35,77.73 204.4,77.78 204.4,78.37 204.48,78.44 206,78.44
+19VB_CHG on TOP (solid shape): 187.23,53.04 187.23,52.2 187.23,52.19 187.47,51.95 187.48,51.95 187.52,51.91 187.7,51.91 187.79,51.82 187.79,50.86 187.69,50.76 187.46,50.76 187.43,50.73 187.36,50.73 187.31,50.68 187.31,49.11 187.21,49 185.38,49 185.2,49.18 185.2,52.97 185.33,53.09 187.18,53.09
+19VB_CHG on BOTTOM (solid shape): 186.6,56.89 186.6,55.05 187.23,54.41 187.23,52.07 187.36,51.94 187.68,51.94 187.8,51.81 187.8,50.8 187.74,50.73 187.3,50.73 187.23,50.67 187.23,49.08 187.17,49.02 185.77,49.02 184.76,50.03 183.74,50.03 183.68,50.1 183.68,52.45 182.85,53.27 182.85,56.7 183.1,56.95 183.99,56.95 183.99,56.45 184.82,56.45 184.82,56.95 185.2,56.95 185.2,56.45 185.96,56.45 185.96,57.02 186.47,57.02
+19VB_DB on BOTTOM (solid shape): 146.62,36.67 146.47,36.51 142.72,36.51 142.27,36.06 141.96,36.06 141.88,36.14 141.88,36.92 142.23,37.27 146.02,37.27
+19VB_VCCGI on TOP (solid shape): 100.81,128.27 100.81,125.15 101.13,124.84 101.13,123.82 101.06,123.76 98.27,123.76 97.82,124.2 97.82,128.65 97.89,128.71 100.36,128.71
+19VB_VCCGI on BOTTOM (solid shape): 97.14,132.52 97.14,131.96 97.37,131.73 105.22,131.73 105.44,131.5 105.44,130.36 105,129.92 103.09,129.92 102.84,129.66 102.84,128.2 101.53,126.89 101.53,126.81 101.48,126.76 101.48,125.96 101.53,125.91 101.53,125.87 101.58,125.87 101.64,125.8 101.66,125.74 101.61,125.71 101.51,125.71 101.51,125.59 101.51,124.85 101.51,124.85 101.51,124.58 102.14,123.95 102.14,121.56 102.14,119.25 102.02,119.12 98.58,119.12 97.64,119.12 97.06,119.12 96.81,119.38 96.81,126.87 96.78,126.89 96.78,131.48 96.43,131.83 96.43,132.52 96.48,132.57 97.09,132.57
+19VB_VNN on TOP (solid shape): 88.81,126.55 88.81,123.38 88.49,123.06 87.47,123.06 87.16,122.74 84.83,122.74 84.71,122.83 84.57,122.87 84.55,122.87 84.49,122.93 84.49,126.68 84.62,126.8 88.55,126.8
+19VB_VNN on BOTTOM (solid shape): 85.2,127.01 85.23,126.99 85.28,126.97 85.33,126.95 85.39,126.94 85.45,126.95 85.5,126.95 85.56,126.97 85.62,127 85.91,126.7 85.91,125.16 86.03,125.03 86.61,125.03 86.61,124.49 87.16,124.49 87.16,125.03 87.41,125.03 87.41,124.49 87.96,124.49 87.96,125.02 87.96,125.03 88.36,125.03 88.39,125.06 88.41,125.06 88.41,125.07 88.81,125.47 88.81,125.79 89.38,126.36 91.22,126.36 91.35,126.23 91.35,124.65 90.65,123.95 90.65,120.33 89.98,119.66 86.08,119.66 86.08,122.25 85.91,122.41 85.2,122.41 84.75,122.86 86.71,122.86 86.71,121.8 86.91,121.6 87.07,121.6 87.1,121.59 87.15,121.58 87.17,121.58 87.53,121.58 87.55,121.58 87.6,121.59 87.63,121.6 88.42,121.6 88.68,121.86 88.68,122.86 88.48,123.06 86.91,123.06 86.71,122.86 84.75,122.86 84.74,122.87 84.55,122.87 84.43,122.99 84.43,125.87 84.3,125.99 82.43,125.99 82.33,126.09 82.33,126.93 82.41,127.01 84.26,127.01 84.28,127.01
+VCC_VCCGI on BOTTOM (solid shape): 99.73,139.15 99.73,139.02 99.55,138.84 99.55,138.44 99.5,138.39 98.71,138.39 98.66,138.44 98.66,138.67 99.32,139.33 99.55,139.33
+VCC_VCGI on TOP (solid shape): outline of 161 points within 92.55,101.79 105.32,110.61
+VCC_VCGI on TOP (solid shape): outline of 1645 points within 80.19,70.44 94.78,87.24
+VCC_VCGI on BOTTOM (solid shape): outline of 103 points within 92.68,99.25 105.89,114.8
+VCC_VCGI on BOTTOM (solid shape): outline of 285 points within 80.64,70.91 89.82,77.02
+VCC_VCGI on VCC: 84.61,68.26 84.43,68.44 84.43,71.23 84.03,71.62 81.43,71.62 81.25,71.8 81.25,73.86 81.43,74.04 83.84,74.04 84.24,74.43 84.24,75.7 87.35,78.81 87.35,82.31 87.47,82.44 87.47,107.97 89.48,109.98 102.04,109.98 114.14,97.87 114.14,72.05 113.66,71.56 99.24,71.56 97.78,70.1 96.45,70.1 95.88,69.53 93.4,69.53 92.89,69.02 92.13,69.02 91.98,68.87 91.98,68.69 91.55,68.26
+VCCIOA on TOP (solid shape): 81.25,89.89 81.14,89.78 81.14,88.79 81,88.64 81,86.55 80.87,86.42 80.87,84.58 80.74,84.45 79.6,84.45 79.16,84.89 79.16,90.42 79.54,90.8 81.25,90.8
+VCCIOA on TOP (solid shape): 80.11,72.36 80.11,70.99 80.23,70.86 80.23,69.21 80.11,69.08 79.47,69.08 79.47,69.26 79.27,69.46 79.22,69.46 79,69.68 79,70.69 79,70.7 79,71.53 79.33,71.86 79.33,72.39 79.47,72.53 79.94,72.53
+VCCIOA on BOTTOM (solid shape): 80.63,72.8 80.63,72.62 80.61,72.59 80.6,72.59 80.48,72.51 80.4,72.39 80.4,72.38 80.1,72.08 80.1,71.99 80.09,71.98 80.08,71.88 80.09,71.79 80.1,71.78 80.09,71.22 80.09,71.19 80.08,71.11 80.09,71.03 80.11,70.97 80.17,70.91 80.21,70.87 80.24,70.72 80.16,70.58 80.1,70.53 80.1,70.46 80.08,70.41 80.08,70.36 80.12,70.21 80.23,70.1 80.31,70.07 80.54,69.83 80.54,69.47 80.37,69.3 79.65,69.3 79.13,69.81 79.13,70.84 79.13,70.89 79.15,70.91 79.27,71.12 79.15,71.33 79.13,71.35 79.13,71.63 79.29,71.79 79.31,71.82 79.37,72.03 79.29,72.24 79.29,72.53 79.74,72.97 80.46,72.97
+VCCIOA on IN1 (solid shape): outline of 1445 points within 76.44,69.65 80.9,87.44
+VDD10 on TOP (solid shape): 20.86,79.5 20.86,78.48 20.8,78.42 19.78,78.42 19.53,78.67 19.53,79.31 19.78,79.56 20.8,79.56
+VDD10 on TOP (solid shape): 21.5,89.21 21.5,87.82 21.43,87.75 20.86,87.75 20.61,88.01 20.29,88.01 19.97,88.32 19.97,89.34 20.04,89.4 21.31,89.4
+VDD10 on TOP (solid shape): 19.02,83.18 19.02,82.8 18.89,82.67 18.32,82.67 18.26,82.61 18.26,82.42 18,82.16 17.75,82.16 17.69,82.23 17.69,82.48 17.75,82.55 17.75,83.05 17.94,83.24 18.96,83.24
+VDD10 on TOP (solid shape): 23.7,82.24 23.7,82.06 23.91,81.85 23.91,81.21 25.18,79.94 25.82,79.94 25.88,79.88 25.88,79.5 25.75,79.37 24.1,79.37 23.85,79.62 23.85,80.39 23.54,80.7 23.54,81.45 23.5,81.49 23.5,82.23 23.55,82.28 23.66,82.28
+VDD10 on BOTTOM (solid shape): 21.69,89.34 21.69,88.7 21.75,88.64 22.39,88.64 22.45,88.58 22.45,88.01 22.26,87.82 21.81,87.82 21.5,88.13 20.1,88.13 19.97,88.26 19.97,89.34 20.04,89.4 21.62,89.4
+VDD10 on BOTTOM (solid shape): outline of 89 points within 17.62,82.1 20.99,84.26
+VDD10 on IN1 (solid shape): outline of 630 points within 16.1,78.35 25.94,83.82
+VDD10 on IN2 (solid shape): outline of 157 points within 17.56,82.16 20.61,89.47
GND on TOP (solid shape): 11.1,108.9 3.85,108.9 3.85,115.65 11.1,115.65
GND on TOP (solid shape): 94.71,149.47 94.71,148.59 94.65,148.52 89.63,148.52 89.63,149.6 89.76,149.73 94.46,149.73
GND on TOP (solid shape): 81.47,112.14 81.47,110.1 81.35,109.98 80.27,109.98 80.27,112.14 80.39,112.26 81.35,112.26
GND on TOP (solid shape): 148.69,56.51 148.69,54.22 148.56,54.1 147.42,54.1 147.35,54.16 147.35,56.51 147.42,56.57 148.62,56.57
GND on TOP (solid shape): 165.07,50.41 165.07,49.21 164.94,49.08 161.39,49.08 161.32,49.14 161.32,50.35 161.45,50.48 165.01,50.48
GND on TOP (solid shape): 223.74,83.43 223.74,82.23 223.62,82.1 218.73,82.1 218.54,82.29 218.54,83.37 218.73,83.56 223.62,83.56
GND on TOP (solid shape): 82.71,59.04 82.71,55.74 81.95,55.74 81.85,55.84 81.85,57.57 81.49,57.93 81.49,59.01 81.64,59.16 82.58,59.16
GND on TOP (solid shape): 24.74,21.59 24.74,20.38 24.67,20.32 23.28,20.32 23.21,20.38 23.21,21.52 23.53,21.84 24.48,21.84
GND on TOP (solid shape): 60.3,36.38 60.3,35.75 60.11,35.56 58.39,35.56 58.33,35.62 58.33,36.51 58.39,36.57 60.11,36.57
GND on TOP (solid shape): 64.25,67.17 64.25,66.05 63.99,65.79 62.26,65.79 62.06,66 62.06,67.17 62.09,67.19 64.22,67.19
GND on TOP (solid shape): 78.65,58.86 78.65,57.08 78.46,56.89 77.63,56.89 77.44,57.08 77.44,57.72 76.74,58.42 76.74,59.18 76.87,59.3 78.2,59.3
GND on TOP (solid shape): 90.03,87.87 90.03,86.52 89.06,85.56 88.65,85.56 88.53,85.68 88.53,85.89 88.86,86.22 88.86,88.07 88.93,88.15 89.75,88.15
GND on TOP (solid shape): 167.21,48.64 167.21,47.69 167.08,47.56 163.59,47.56 163.4,47.75 162.77,47.75 162.7,47.82 162.7,48.45 163.02,48.77 167.08,48.77
GND on TOP (solid shape): 184.76,64.7 184.76,63.11 184.63,62.99 184.12,62.99 184.06,63.05 184.06,63.56 183.8,63.81 183.8,64.19 184.37,64.77 184.69,64.77
GND on TOP (solid shape): 190.99,51.98 190.99,51.34 190.76,51.1 190.76,50.48 190.7,50.43 189.62,50.43 189.54,50.5 189.54,51.95 189.59,52 190.97,52
GND on TOP (solid shape): 23.34,57.72 23.34,54.86 22.13,53.65 19.85,53.65 19.66,53.84 19.66,57.78 19.78,57.91 23.15,57.91
GND on TOP (solid shape): 63.99,80.2 63.99,78.82 63.97,78.8 61.83,78.8 61.81,78.82 61.81,80.12 62.14,80.45 63.74,80.45
GND on TOP (solid shape): 63.47,44.45 63.47,42.1 62.58,41.21 62.58,40.57 62.52,40.51 60.99,40.51 60.99,41.4 61.82,42.22 61.82,44.38 61.95,44.51 63.41,44.51
GND on TOP (solid shape): 66.52,123.06 66.52,121.22 66.65,121.09 68.3,121.09 68.36,121.03 68.36,120.52 68.3,120.45 65.38,120.45 65.31,120.52 65.31,123.12 65.38,123.19 66.39,123.19
GND on TOP (solid shape): 76.3,57.4 76.3,55.56 76.23,55.49 75.28,55.49 74.96,55.18 74.96,54.73 74.84,54.61 73.44,54.61 73.19,54.86 73.19,56.76 73.95,57.53 76.17,57.53
GND on TOP (solid shape): 85.96,63.05 85.96,62.44 85.96,62.25 86.08,62.14 86.08,62.02 85.64,61.59 85.17,61.59 85.05,61.72 85.05,63.05 85.09,63.09 85.92,63.09
GND on TOP (solid shape): 90.59,110.17 90.59,109.22 90.52,109.15 89.38,109.15 89.25,109.28 89.25,110.17 89.38,110.29 90.46,110.29
GND on TOP (solid shape): 109.51,106.55 109.51,101.98 109.19,101.66 106.38,101.66 106.07,101.98 106.07,106.68 106.19,106.8 109.25,106.8
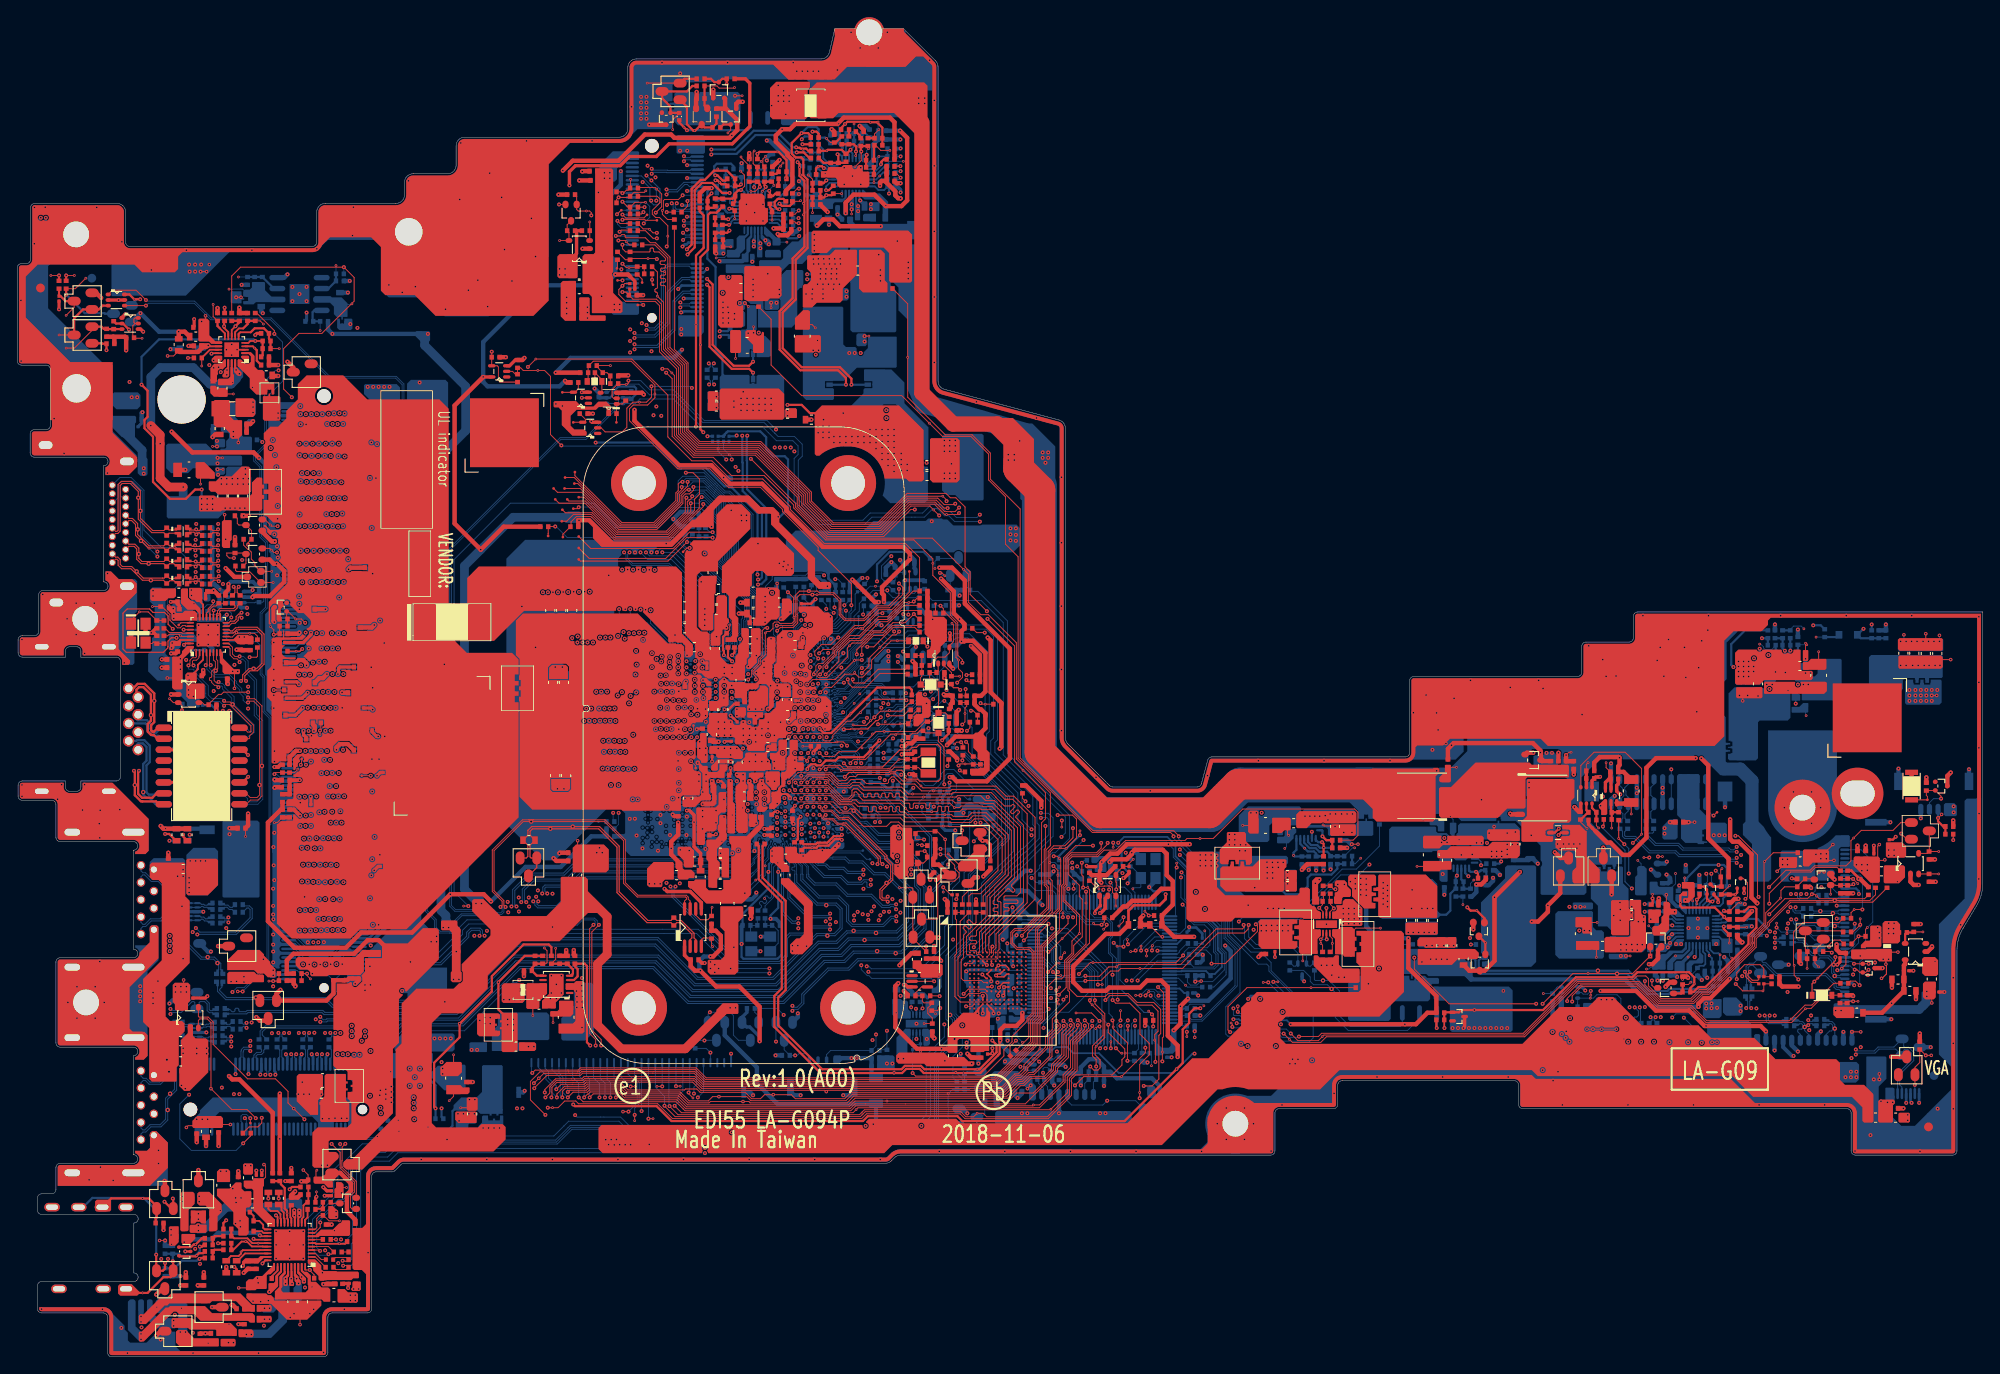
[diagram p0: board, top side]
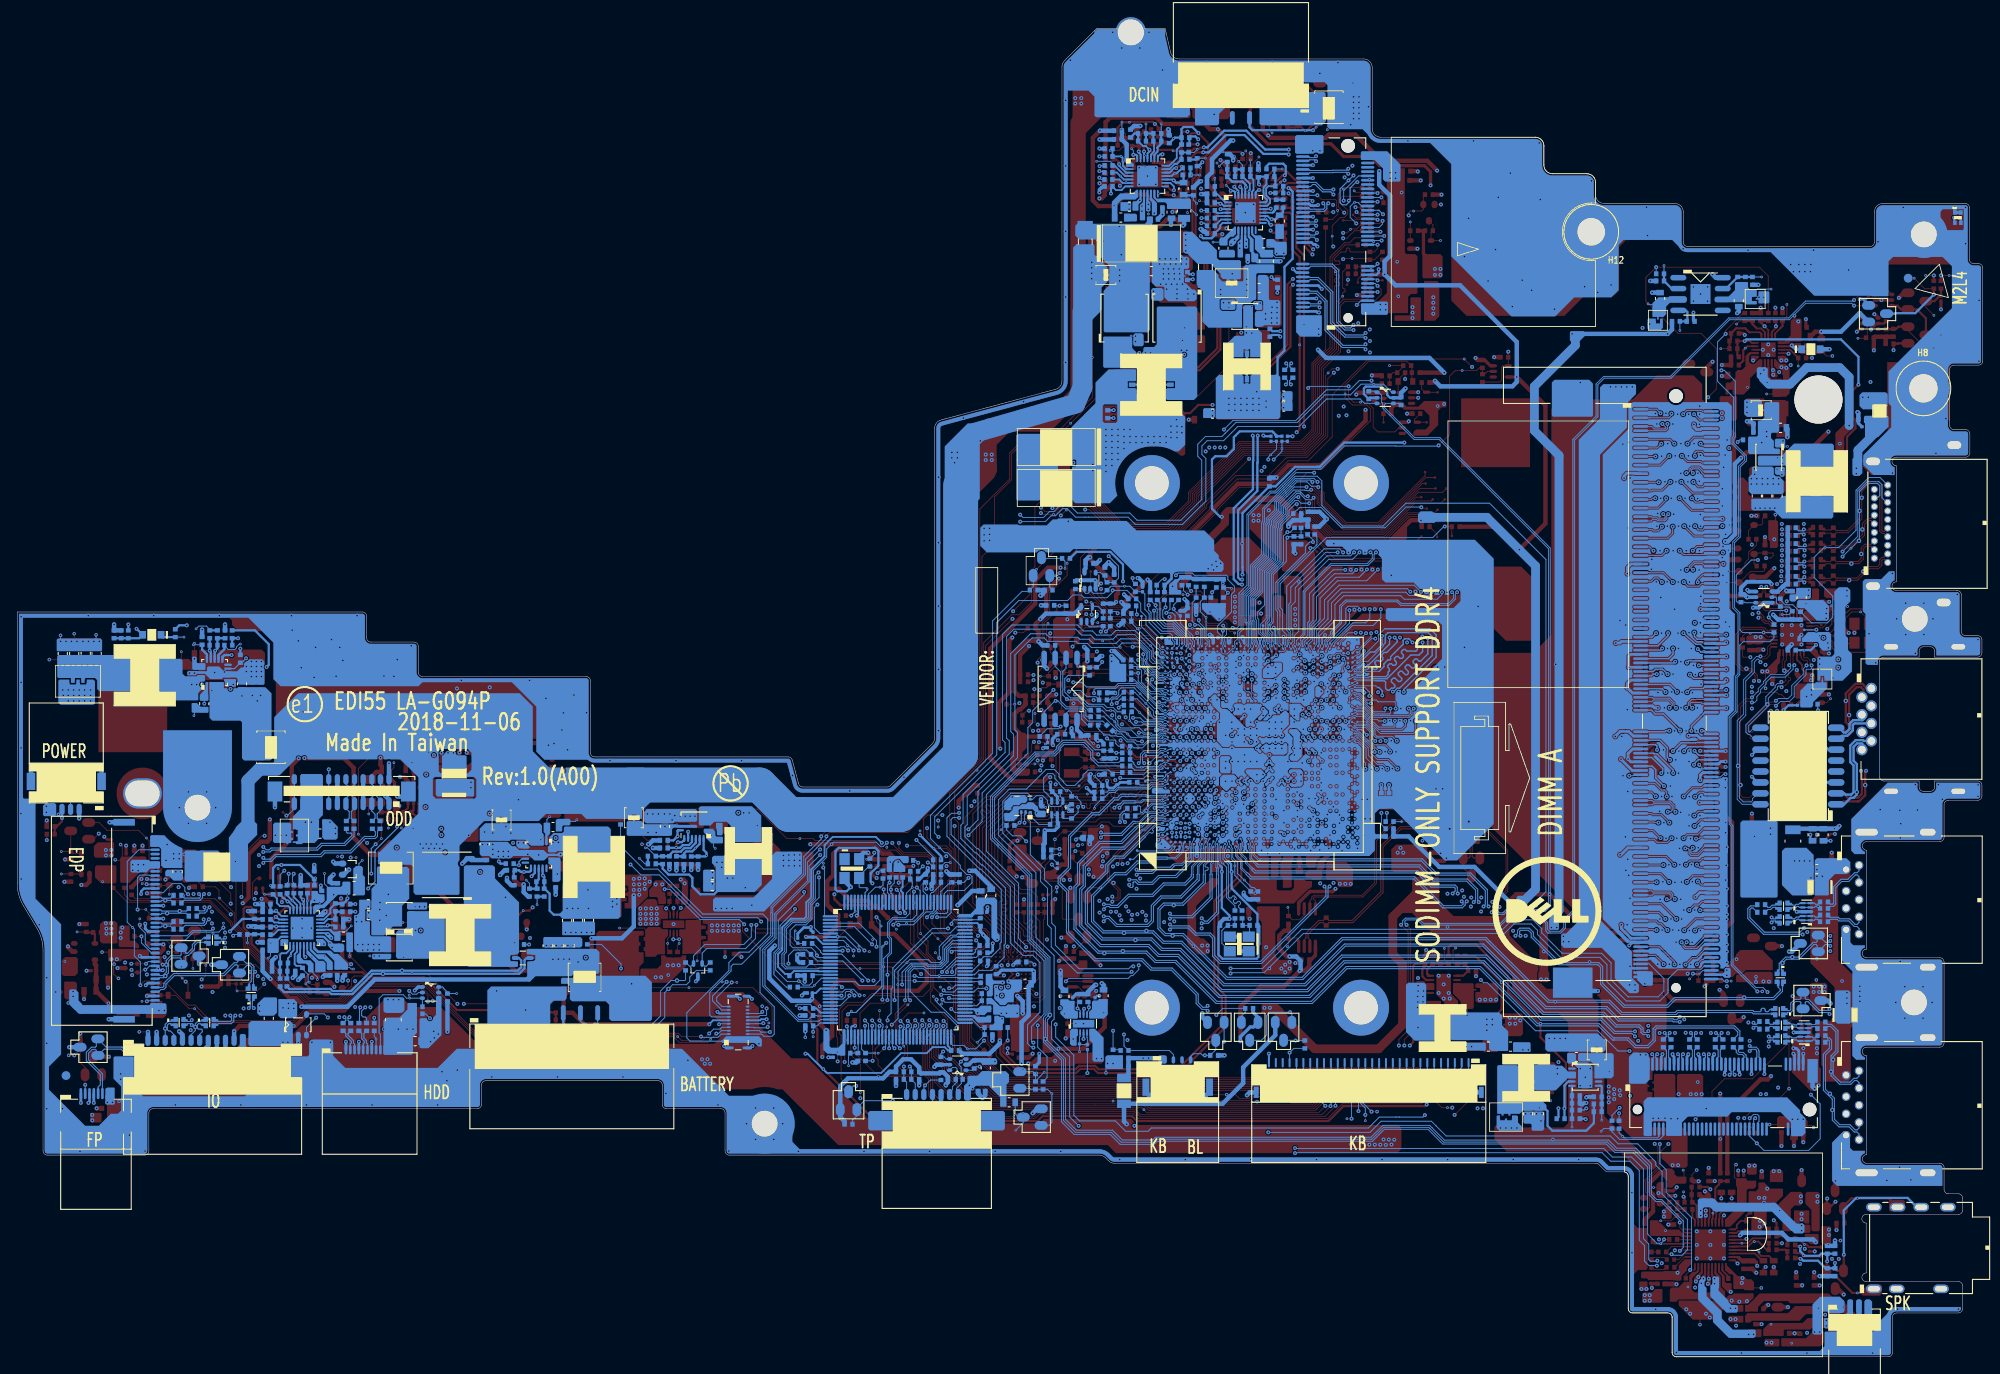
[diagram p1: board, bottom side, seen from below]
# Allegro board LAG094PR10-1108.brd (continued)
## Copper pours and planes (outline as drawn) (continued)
GND on TOP (solid shape): 37.3,16.9 37.3,16.16 37.23,16.09 37.13,16.06 37.05,16.01 36.32,16.01 36.17,16.17 36.17,17.48 36.2,17.52 36.69,17.52
GND on TOP (solid shape): 53.37,28.38 53.37,27.24 53.31,27.17 51.28,27.17 50.9,27.55 50.9,28.38 51.02,28.51 53.25,28.51
GND on TOP (solid shape): 27.15,103.25 27.15,100.64 26.77,100.26 23.34,100.26 23.02,100.58 22.51,100.58 22.26,100.83 22.26,101.72 22.32,101.79 23.08,101.79 23.66,102.36 24.93,102.36 26.07,103.5 26.89,103.5
GND on TOP (solid shape): 37.25,8.7 37.25,8.25 37.18,8.19 35.47,8.19 35.34,8.31 35.34,8.62 35.42,8.69 35.8,8.69 35.85,8.75 37.2,8.75
GND on TOP (solid shape): 86.39,84.58 86.39,81.66 85.95,81.21 85.95,80.7 85.21,79.97 84.84,79.97 84.72,80.09 84.72,80.27 84.93,80.49 84.93,81.06 85.25,81.38 85.25,84.58 85.38,84.7 86.27,84.7
GND on TOP (solid shape): 216.61,49.98 216.61,47.75 216.49,47.62 214.84,47.62 214.73,47.51 214.25,47.51 214.24,47.52 214.24,47.88 214.73,48.37 215.24,48.37 215.32,48.45 215.32,50.03 215.42,50.14 216.45,50.14
GND on TOP (solid shape): 35.53,32.7 35.53,30.41 34.96,29.84 34.96,28.19 34.9,28.13 34.07,28.13 32.48,29.71 32.48,32.63 32.74,32.89 35.34,32.89
GND on TOP (solid shape): 174.6,59.62 174.6,58.29 174.28,57.97 165.13,57.97 165.01,58.1 165.01,58.8 165.13,58.92 166.15,58.92 166.59,59.37 170.91,59.37 171.42,59.88 174.34,59.88
GND on TOP (solid shape): 86.67,74.91 86.67,74.33 86.65,74.3 86.24,74.3 85.99,74.05 85.99,73.54 85.96,73.52 85.51,73.52 85.45,73.57 85.45,74.2 85.33,74.33 84.87,74.33 84.82,74.38 84.82,74.89 84.87,74.94 86.65,74.94
GND on TOP (solid shape): 151.55,55.66 151.55,55.33 151.16,54.95 151.16,53.55 151.29,53.42 151.29,52.64 151.23,52.57 150.53,52.57 150.47,52.64 150.47,55.34 150.88,55.76 151.44,55.76
GND on TOP (solid shape): 27.85,44.45 28.55,44.45 28.67,44.32 28.67,43.62 28.61,43.56 27.34,43.56 27.12,43.34 24.49,43.34 24.42,43.42 24.42,44.57 24.61,44.76 27.53,44.76
GND on TOP (solid shape): 20.42,38.55 20.42,37.31 20.72,37.02 21.94,37.02 22.2,36.76 22.2,33.08 20.04,30.92 19.4,30.92 18.83,31.49 18.83,33.52 19.02,33.71 19.02,36.83 19.82,37.63 19.82,38.58 19.91,38.67 20.31,38.67
GND on TOP (solid shape): 151.35,46.41 152.88,46.41 153.13,46.67 153.51,46.67 153.58,46.6 153.58,45.59 154.02,45.14 155.86,45.14 155.99,45.02 155.99,43.62 155.86,43.49 152.62,43.49 150.66,45.45 150.66,46.6 150.72,46.67 151.1,46.67
GND on TOP (solid shape): 155.61,63.24 155.61,62.23 155.42,62.03 151.94,62.03 151.74,62.12 151.53,62.03 150.4,62.03 149.83,61.46 148.75,61.46 148.62,61.59 148.62,63.05 149.01,63.43 155.42,63.43
GND on TOP (solid shape): 29.12,7.17 29.5,7.17 29.82,6.85 29.82,6.6 29.88,6.54 35.28,6.54 35.34,6.47 35.34,5.96 33.69,4.31 31.34,4.31 29.5,6.15 27.34,6.15 26.64,6.85 26.64,7.3 26.7,7.36 28.93,7.36
GND on TOP (solid shape): 85.25,135.22 85.34,135.24 86.5,135.24 86.56,135.23 86.85,134.93 86.85,133.69 86.98,133.56 87.18,133.56 87.23,133.51 87.23,131.99 86.88,131.63 84.01,131.63 83.85,131.78 83.85,134.4 84.06,134.6 84.06,135.24 85.17,135.24
GND on TOP (solid shape): 95.67,59.69 95.67,59.37 93.7,57.4 89.76,57.4 89.25,57.91 89.25,59.3 90.46,59.3 90.59,59.18 90.59,58.67 90.78,58.48 91.66,58.48 92.15,58.96 92.2,58.96 92.21,58.95 92.37,58.91 92.52,58.96 92.98,58.96 93.07,59.05 94.52,59.05 95.28,59.81 95.54,59.81
GND on TOP (solid shape): 97.57,128.65 97.57,125.85 95.92,124.2 95.92,122.87 95.6,122.55 92.91,122.55 92.36,122 91.35,122 91.28,122.07 91.28,124.52 91.47,124.71 91.79,124.71 92.24,125.15 92.24,126.04 91.79,126.49 91.79,127.95 91.92,128.07 94.4,128.07 95.03,128.71 97.51,128.71
GND on TOP (solid shape): 188.71,53.04 188.71,52.23 188.72,52.22 188.72,51.52 188.86,51.37 189.11,51.37 189.26,51.21 189.26,47.56 188.73,47.02 184.57,47.02 184.44,47.15 184.44,48.62 184.64,48.83 187.31,48.83 187.46,48.98 187.46,50.58 187.51,50.63 187.74,50.63 187.92,50.81 187.92,52 187.88,52.04 187.57,52.04 187.36,52.26 187.36,53.07 187.41,53.12 188.63,53.12
GND on TOP (solid shape): 82.48,88.3 82.48,85.94 82.71,85.71 82.71,85.35 82.68,85.34 82.52,85.12 82.62,84.87 82.62,84.6 82.58,84.56 82,84.56 81.95,84.51 81.95,84.07 81.71,83.83 81.71,82.8 81.59,82.69 80.65,82.69 80.58,82.76 80.58,84.03 81,84.45 81,84.52 81,86.3 81.24,86.55 81.24,88.32 81.44,88.53 82.25,88.53
GND on TOP (solid shape): 85.31,67.05 85.31,66.73 85.57,66.48 85.57,65.79 85.56,65.78 85.53,65.64 85.56,65.5 85.57,65.49 85.57,65.08 85.56,65.07 85.53,64.93 85.56,64.79 85.57,64.78 85.57,64.7 85.51,64.64 84.87,64.64 84.81,64.7 84.81,65.72 85,65.91 85,66.05 85,66.47 85,66.48 84.81,66.67 84.81,67.05 84.93,67.18 85.19,67.18
GND on TOP (solid shape): 88.22,70.45 87.67,70.45 87.66,70.45 87.46,70.45 87.11,70.1 87.11,69.65 87.44,69.32 87.44,69.04 87.61,68.87 87.61,68.28 87.55,68.22 86.96,68.22 86.87,68.13 83.33,68.13 83.24,68.22 83.24,68.76 83.69,69.2 84.05,69.2 84.44,69.6 84.44,69.6 84.59,69.74 84.59,70.1 84.72,70.24 85.89,70.24 85.89,70.24 86.85,70.24 87.03,70.42 87.03,70.5 87.03,70.5 87.03,71 87.18,71.15 88.22,71.15
GND on TOP (solid shape): 103,150 99,150 96.17,151.17 95,154 95,154.4 103,154.4
GND on TOP (solid shape): 105.19,77.2 105.17,77.17 105.24,76.77 105.64,76.7 105.67,76.71 106.14,76.24 106.14,74.54 105.89,74.29 105.38,74.29 105.32,74.23 105.32,73.95 104.7,73.33 104.25,73.33 104.15,73.43 104.15,74.07 104.16,74.07 104.16,74.44 104.47,74.75 105.15,74.75 105.15,75.51 105.14,75.51 105.14,75.71 104.43,75.71 104.43,77.03 104.72,77.32 105.06,77.32
GND on TOP (solid shape): 79.35,69.21 79.35,69.02 79.66,68.7 80.17,68.7 80.23,68.64 80.23,68.12 80.35,68 81.34,68 81.62,68.28 81.62,68.87 82.51,68.87 82.51,68.25 82.2,67.94 82.2,67.38 82.14,67.32 80.53,67.32 80.35,67.14 80.35,66.43 80.36,66.42 80.36,65.53 80.62,65.27 80.62,64.77 80.55,64.7 79.54,64.7 78.75,63.91 77.45,63.91 77.3,64.07 77.3,64.96 77.48,65.13 79.27,65.13 79.43,65.3 79.43,65.81 79.61,65.98 79.61,67.88 79.22,68.27 79.22,68.77 79.16,68.83 78.96,68.83 78.84,68.96 78.84,69.21 78.96,69.34 79.22,69.34
GND on TOP (solid shape): 82.38,65.57 82.38,63.43 82.23,63.28 81.8,63.28 81.64,63.13 81.64,63.13 81.51,63 81.5,63 81.5,62.99 81.44,62.93 81.44,61.99 81.35,61.9 81.31,61.9 81.31,61.86 81.29,61.83 81.29,61.37 81,61.08 80.11,61.08 79.92,60.89 79.92,59.66 79.77,59.51 79.14,59.51 78.97,59.68 78.97,62.07 78.97,62.08 78.98,62.19 78.94,62.31 78.94,62.32 78.94,63.11 78.9,63.15 78.9,63.75 79.03,63.88 79.48,63.88 79.48,63.88 80.99,63.88 81.17,63.88 81.49,64.19 81.49,65.51 81.64,65.67 82.28,65.67
GND on TOP (solid shape): 17.51,24.9 17.51,21.98 15.4,19.87 4.7,19.87 4.7,22 4.79,22.21 5,22.3 13.5,22.3 14.2,22.9 13.7,23.67 13.7,23.95 15.09,23.95 15.43,24.29 15.43,25.97 15.68,26.22 16.19,26.22
GND on TOP (solid shape): 154.39,55.25 154.39,55.24 154.53,55.1 154.53,54.81 154.53,54.73 154.97,54.29 154.97,53.59 154.85,53.46 154.09,53.46 153.96,53.34 153.96,53.07 153.89,53.01 153.89,52.7 153.83,52.64 153.13,52.64 153.01,52.76 153.01,53.46 153.09,53.55 153.09,53.91 153.12,53.98 153.19,54.01 153.53,54.36 153.19,54.72 153.12,54.75 153.09,54.82 153.09,55.2 153.3,55.41 154.24,55.41
GND on TOP (solid shape): 96.94,138.57 97.01,138.53 97.04,138.45 97.04,138.38 97.07,138.3 97.37,138.07 97.62,138.36 97.62,138.38 97.81,138.57 98.18,138.57 98.23,138.51 98.23,137.88 98.31,137.8 98.9,137.8 99.02,137.69 99.02,136.19 98.78,135.95 95.54,135.95 95.28,136.2 95.28,136.89 95.08,137.09 94.18,137.09 94.17,137.1 94.01,137.13 93.86,137.1 93.85,137.09 93.46,137.09 93.38,137.17 93.38,137.78 93.46,137.85 94.04,137.85 94.19,138.01 94.19,138.23 94.29,138.34 95.79,138.34 96.02,138.56 96.72,138.56 96.72,138.57
GND on TOP (solid shape): 16.42,49.97 16.42,46.35 13.05,42.98 13.05,38.16 13.43,37.78 14.77,37.78 15.15,37.4 15.15,34.98 14.71,34.55 13.7,34.55 13.7,34.83 14.2,35.6 13.5,36.2 5,36.2 4.79,36.29 4.7,36.5 4.7,45.9 4.79,46.11 5,46.2 13.5,46.2 14.03,46.44 14.2,46.99 15.4,48.19 15.4,49.97 15.59,50.16 16.23,50.16
GND on TOP (solid shape): 90.39,71.74 90.6,71.74 90.71,71.63 90.71,70.56 90.66,70.47 90.56,70.47 90.05,70.22 90.5,69.88 90.59,69.87 90.64,69.78 90.64,69.17 90.69,69.12 91.27,69.12 91.4,68.99 91.4,68.28 91.25,68.13 90.61,68.13 89.72,67.24 89.47,67.24 89.26,67.04 89.26,66.38 89.11,66.23 88.88,66.23 88.73,66.07 88.73,65.67 88.86,65.54 89.57,65.54 90.03,65.08 90.03,64.83 89.92,64.73 89.67,64.73 89.54,64.85 89.54,65.08 89.32,65.31 88.91,65.31 88.76,65.16 88.76,64.45 87.99,63.69 87.38,63.69 87.38,64.22 87.66,64.5 87.66,65.65 87.73,65.72 88.24,65.72 88.4,65.88 88.4,66.12 88.81,66.53 88.81,67.94 88.87,68 89.19,68 89.39,68.21 89.39,69.61 89.76,69.98 89.76,71.62 89.87,71.74 90.35,71.74
GND on TOP (solid shape): 5.4,66.25 5.6,65.75 6.1,65.55 6.9,65.55 7.4,65.75 7.6,66.25 7.6,66.75 11.07,66.75 15.27,62.54 15.27,58.83 14.89,58.45 14.17,58.45 14.17,58.45 13.7,58.45 13.7,58.73 14.2,59.5 13.5,60.1 5,60.1 4.79,60.19 4.7,60.4 4.7,64.2 4.5,64.7 4,64.9 0.6,64.9 0.39,64.99 0.3,65.2 0.3,66.45 0.39,66.66 0.6,66.75 5.4,66.75
GND on TOP (solid shape): 11.79,90.42 13.37,90.42 13.88,89.91 13.88,88.83 11.78,86.74 11.78,82.29 13.12,80.96 13.12,80.64 12.92,80.45 12.2,80.45 12.2,80.85 12,81.35 11.5,81.55 7.6,81.55 7.6,82.05 7.4,82.55 6.9,82.75 6.1,82.75 5.6,82.55 5.4,82.05 5.4,81.55 0.6,81.55 0.39,81.64 0.3,81.85 0.3,83.35 0.39,83.56 0.6,83.65 2,83.65 2.5,83.85 2.7,84.35 2.7,88.6 2.79,88.81 3,88.9 10.05,88.9 10.75,89.5 10.25,90.27 10.25,91.32 10.89,91.32
GND on TOP (solid shape): outline of 133 points within 81.44,119.66 84.36,125.79
GND on TOP (solid shape): outline of 184 points within 199.61,78.16 208.63,82.23
GND on TOP (solid shape): outline of 199 points within 32.36,44.25 42.26,47.3
GND on TOP (solid shape): outline of 183 points within 101.44,55.56 104.17,61.84
GND on TOP (solid shape): outline of 224 points within 80.4,75.07 89.89,83.71
GND on TOP (solid shape): outline of 594 points within 52.29,81.34 78.52,91.88
GND on TOP (solid shape): outline of 1294 points within 0.2,0.2 228.2,154.4
GND on BOTTOM (solid shape): 101.95,34.86 101.95,33.65 101.76,33.46 99.92,33.46 99.92,35.05 101.76,35.05
GND on BOTTOM (solid shape): 81.44,111.95 81.44,110.1 81.31,109.98 80.23,109.98 80.23,112.14 80.36,112.26 81.12,112.26
GND on BOTTOM (solid shape): 92.79,65.08 92.79,64.73 92.29,64.22 92.06,64.22 91.52,64.75 91.52,65.06 92.01,65.54 92.34,65.54
GND on BOTTOM (solid shape): 148.69,56.51 148.69,54.16 148.62,54.1 147.48,54.1 147.35,54.22 147.35,56.51 147.48,56.64 148.56,56.64
GND on BOTTOM (solid shape): 167.26,48.67 167.26,47.72 167.13,47.59 162.94,47.59 162.75,47.78 162.75,48.6 162.94,48.8 167.13,48.8
GND on BOTTOM (solid shape): 192.95,62.42 192.95,60.38 192.69,60.13 191.36,60.13 191.17,60.32 191.17,61.65 191.99,62.48 192.88,62.48
GND on BOTTOM (solid shape): 223.81,83.37 223.81,82.1 223.74,82.04 218.66,82.04 218.54,82.16 218.54,83.31 218.73,83.5 223.68,83.5
GND on BOTTOM (solid shape): 54.58,36.51 54.58,35.49 54.52,35.43 52.61,35.43 52.55,35.49 52.55,36.44 52.68,36.57 54.52,36.57
GND on BOTTOM (solid shape): 60.3,36.38 60.3,35.75 60.17,35.62 57.82,35.62 57.76,35.68 57.76,36.44 57.82,36.51 60.17,36.51
GND on BOTTOM (solid shape): 90.71,86.93 90.08,86.29 89.63,86.29 88.87,85.53 88.62,85.53 87.98,86.16 87.98,87.63 90.71,87.63
GND on BOTTOM (solid shape): 155.55,63.37 155.55,62.29 155.29,62.03 152.18,62.03 151.99,62.23 149.51,62.23 149.39,62.35 149.39,63.5 149.58,63.69 155.23,63.69
GND on BOTTOM (solid shape): 211.17,56.45 211.17,55.94 211.11,55.88 210.73,55.88 210.22,55.37 209.33,55.37 209.14,55.56 209.14,56.51 209.27,56.64 210.98,56.64
GND on BOTTOM (solid shape): 28.16,62.1 28.16,53.53 28.04,53.4 23.97,53.4 23.85,53.53 23.85,62.16 24.04,62.35 27.91,62.35
GND on BOTTOM (solid shape): 79.92,141.85 79.92,140.01 79.79,139.89 77.76,139.89 77.63,140.01 77.31,140.01 77.19,139.89 76.74,139.89 76.62,140.01 76.62,141.92 76.74,142.04 79.73,142.04
GND on BOTTOM (solid shape): 90.59,110.17 90.59,109.22 90.52,109.15 89.38,109.15 89.25,109.28 89.25,110.23 89.32,110.29 90.46,110.29
GND on BOTTOM (solid shape): 112.3,107.12 112.3,99.69 112.18,99.56 109.64,99.56 109,100.2 107.98,100.2 107.46,100.72 107.46,106.99 107.78,107.31 112.11,107.31
GND on BOTTOM (solid shape): 121.45,28.57 129.32,28.57 129.51,28.38 129.51,26.54 129.32,26.35 113.83,26.35 113.64,26.54 113.64,28.38 113.83,28.57 120.62,28.57 120.87,28.82 121.19,28.82
GND on BOTTOM (solid shape): 171.1,78.62 168.08,75.6 168.08,70.37 167.14,69.43 162.11,69.43 162.04,69.5 162.04,69.86 162.19,70.01 162.19,78.47 162.39,78.67 171.05,78.67
GND on BOTTOM (solid shape): 173.77,42.6 173.77,37.97 173.57,37.77 166.7,37.77 166.47,38 166.47,41.02 166.09,41.4 164.82,41.4 164.56,41.65 164.56,43.05 173.33,43.05
GND on BOTTOM (solid shape): 200.5,41.02 200.5,39.94 200.23,39.66 198.57,39.66 198.21,40.02 198.21,41.67 198.31,41.78 199.74,41.78
GND on BOTTOM (solid shape): 23.34,58.8 23.34,54.86 22.13,53.65 19.85,53.65 19.66,53.84 19.66,58.35 20.48,59.18 22.96,59.18
GND on BOTTOM (solid shape): 95.09,83.48 95.09,82.9 94.97,82.78 94.42,82.78 94.38,82.73 94.21,82.73 94.12,82.82 94.12,83.07 94.32,83.26 94.32,83.74 94.4,83.83 94.75,83.83
GND on BOTTOM (solid shape): 165.07,50.48 165.07,49.08 165.01,49.02 161.79,49.02 161.72,49.04 161.65,49.04 161.36,49.04 161.26,49.14 161.26,50.48 161.39,50.6 164.94,50.6
GND on BOTTOM (solid shape): 50.07,113.28 50.07,109.41 50.01,109.34 49.43,109.34 45.43,109.34 45.3,109.47 45.3,113.15 45.75,113.6 49.76,113.6
GND on BOTTOM (solid shape): 79.79,120.96 79.79,119.12 79.28,118.61 77,118.61 76.81,118.8 76.81,121.03 76.87,121.09 79.66,121.09
GND on BOTTOM (solid shape): 83.24,129.88 83.24,129.01 83.19,128.96 82.38,128.96 82.3,128.89 82.3,128.25 82.12,128.07 81.01,128.07 80.88,128.2 80.88,129.55 80.98,129.65 82.1,129.65 82.41,129.95 83.17,129.95
GND on BOTTOM (solid shape): 26.83,103.37 26.83,102.61 27.21,102.23 27.21,100.64 26.89,100.33 23.28,100.33 23.15,100.45 23.15,101.85 23.66,102.36 24.04,102.36 24.29,102.61 24.29,103.31 24.48,103.5 26.7,103.5
GND on BOTTOM (solid shape): 41.12,34.86 41.12,31.87 40.99,31.75 39.21,31.75 38.72,32.24 38.72,34.73 38.82,34.83 38.82,35.16 39.02,35.36 40.61,35.36
GND on BOTTOM (solid shape): 53.37,28.38 53.37,27.24 53.25,27.11 52.55,27.11 52.42,26.98 52.42,26.41 52.29,26.28 51.15,26.28 50.96,26.47 50.96,28.38 51.09,28.51 53.25,28.51
GND on BOTTOM (solid shape): 90.09,84.04 90.09,83.85 89.62,83.37 89.62,82.9 89.49,82.77 89.43,82.78 89.21,83 89.21,83.52 89.25,83.56 89.25,83.57 89.25,83.69 89.36,83.8 89.36,83.89 89.67,84.2 89.93,84.2
GND on BOTTOM (solid shape): 101.49,81.59 101.49,78.66 101.3,78.47 100.8,78.47 100.78,78.45 100.56,78.45 100.55,78.46 99.63,78.46 99.54,78.54 99.54,80.51 99.6,80.58 100.24,80.58 100.34,80.68 100.34,80.92 101.08,81.67 101.41,81.67
GND on BOTTOM (solid shape): 201.74,86.14 198.64,83.04 198.64,78.8 197.81,77.97 181.77,77.97 181.26,78.48 181.26,78.54 182.09,79.37 182.09,82.55 182.36,82.81 187.71,82.81 188.2,83.29 188.2,85.96 188.45,86.22 201.66,86.22
GND on BOTTOM (solid shape): 113.7,64.5 113.7,63.61 113.65,63.56 112.97,63.56 112.88,63.64 112.88,63.91 112.66,64.13 112.65,64.13 111.98,64.13 111.73,64.38 111.72,64.38 111.29,64.38 111.03,64.64 111.03,65.01 111.34,65.31 112.88,65.31
GND on BOTTOM (solid shape): 48.29,35.24 48.29,34.22 48.17,34.09 47.6,34.09 47.02,33.52 47.02,31.24 45.37,31.24 45.37,33.71 45.88,34.22 46.96,34.22 47.28,34.54 47.28,35.17 47.41,35.3 48.23,35.3
GND on BOTTOM (solid shape): 96.55,65.97 96.55,65.59 96.45,65.49 94.52,65.49 94.46,65.55 94.46,65.84 94.59,65.97 94.86,65.97 94.87,65.96 94.99,65.93 95.11,65.96 95.12,65.97 95.16,65.97 95.35,66.16 96.36,66.16
GND on BOTTOM (solid shape): 72.92,77.64 72.96,77.63 73.04,77.59 73.05,77.5 73.04,77.42 72.81,77.42 72.7,77.32 72.32,77.32 71.95,76.95 71.82,76.95 71.6,77.17 71.6,77.25 72.01,77.66 72.86,77.66
GND on BOTTOM (solid shape): 115.76,41.69 115.76,41.06 115.71,41.01 115.15,41.01 115,40.85 115,39.86 114.92,39.78 114.25,39.78 114.25,39.78 114.13,39.66 113.77,39.66 113.54,39.43 112.11,39.43 111.94,39.6 111.94,39.77 111.95,39.78 111.95,40.82 112.08,40.95 113.34,40.95 113.53,40.75 114.21,40.75 115.14,41.68 115.14,41.73 115.73,41.73
GND on BOTTOM (solid shape): 84.24,125.66 84.24,122.87 83.79,122.87 83.61,122.69 83.61,121.77 83.63,121.75 83.63,121.69 83.76,121.57 84.39,121.57 84.58,121.38 84.58,119.92 84.46,119.79 83.66,119.79 83.5,119.95 81.76,119.95 81.63,120.07 81.63,122.68 81.82,122.87 82.84,122.87 82.97,122.99 82.97,125.37 82.99,125.44 83,125.51 83.28,125.79 84.11,125.79
GND on BOTTOM (solid shape): 96.55,130.49 96.55,124.9 96.11,124.46 95.22,124.46 95.09,124.33 95.09,124.13 95.09,124.13 95.09,123.18 94.65,122.74 91.6,122.74 91.35,122.99 91.35,123.81 91.6,124.06 91.86,124.06 92.62,124.82 92.83,124.82 92.83,125.59 92.64,125.59 92.64,125.74 92.83,125.74 92.83,126.5 92.36,126.5 92.22,126.64 92.22,127.68 92.43,127.88 92.87,127.88 93.25,128.27 93.25,130.74 93.38,130.87 96.17,130.87
GND on BOTTOM (solid shape): 174.66,59.75 174.66,58.48 174.41,58.22 173.53,58.22 173.26,57.95 171.04,57.95 170.77,58.22 168.82,58.22 168.31,57.72 167.17,57.72 166.66,58.22 165.58,58.22 165.52,58.16 165.13,58.16 165.01,58.29 165.01,58.61 165.07,58.67 165.45,58.67 165.64,58.48 166.79,58.48 167.23,58.92 170.09,58.92 170.53,59.37 170.91,59.37 171.42,59.88 174.53,59.88
GND on BOTTOM (solid shape): 188.65,53.09 188.65,51.62 188.91,51.37 189.19,51.37 189.24,51.32 189.24,47.4 188.88,47.05 185,47.05 184.95,47.1 184.95,48.76 185.07,48.89 185.72,48.89 187.22,48.89 187.23,48.89 187.42,49.08 187.42,50.54 187.49,50.6 187.79,50.6 187.87,50.6 187.99,50.73 187.99,51.94 187.87,52.07 187.42,52.07 187.36,52.13 187.36,53.08 187.42,53.14 188.6,53.14
GND on BOTTOM (solid shape): 179.74,41.84 179.74,39.75 180.08,39.4 180.42,39.01 180.79,39.37 181.52,39.37 181.64,39.24 181.64,36 181.52,35.87 180.63,35.87 179.1,37.4 179.1,41.91 179.17,41.97 179.61,41.97
GND on BOTTOM (solid shape): 95.39,60.23 95.46,60.2 95.49,60.12 95.64,59.83 95.97,59.81 96.07,59.81 96.12,59.72 96.12,59.24 95.89,59.01 94.58,59.01 94.39,59.2 94.39,59.44 95.18,60.23
GND on BOTTOM (solid shape): 178.75,70.14 178.75,70.13 178.84,69.97 178.99,69.88 179.01,69.88 179.04,69.85 179.04,68.13 178.98,68.07 176.25,68.07 176.18,68.13 176.18,69.81 176.26,69.89 176.32,69.91 176.36,69.93 176.85,69.93 176.86,69.93 177.01,69.9 177.16,69.93 177.17,69.93 177.28,69.93 177.45,70.11 177.45,70.29 177.52,70.35 178.53,70.35
GND on BOTTOM (solid shape): 37.79,71.47 37.89,71.41 37.87,71.3 37.66,71.09 37.66,70.86 37.5,70.59 37.62,70.3 37.66,70.23 37.63,70.15 36.75,69.28 36.7,69.33 36.7,69.4 36.7,69.46 36.87,69.63 36.87,70.76 37.58,71.47
GND on BOTTOM (solid shape): 201.48,81.08 201.6,80.92 201.79,80.86 202.04,80.6 202.04,80.23 202.14,80.13 202.41,80.13 202.85,79.69 204.38,79.69 204.95,80.26 206.22,80.26 206.35,80.13 206.35,79.75 206.41,79.69 207.43,79.69 207.49,79.75 208.5,79.75 208.63,79.62 208.63,79.31 208.57,79.24 207.68,79.24 207.49,79.43 206.6,79.43 205.96,78.8 204.63,78.8 204.44,78.99 202.98,78.99 202.79,78.8 202.79,78.29 202.65,78.15 199.75,78.15 199.68,78.22 199.68,79.95 199.78,80.2 199.68,80.45 199.68,80.81 199.95,81.08
GND on BOTTOM (solid shape): 17.51,24.9 17.51,20.46 16.93,19.87 4.7,19.87 4.7,22 4.79,22.21 5,22.3 13.5,22.3 14.2,22.9 13.7,23.67 13.7,23.95 15.09,23.95 15.43,24.29 15.43,25.97 15.68,26.22 16.19,26.22
GND on BOTTOM (solid shape): 211.45,67.71 211.45,63.85 207.45,59.85 203.45,63.85 203.45,72.84 211.45,72.84
GND on BOTTOM (solid shape): 91.36,60.31 91.4,60.23 91.45,60.09 91.56,60 91.58,60 91.63,59.89 91.58,59.86 91.4,59.63 91.55,59.39 91.58,59.37 91.58,58.17 91.45,58.05 91.17,58.05 91.07,58.15 91.07,58.77 91.1,58.8 91.1,59.34 91.19,59.47 91.19,59.7 91.2,59.76 91.19,59.77 91.19,59.79 91.15,59.83 91.02,60.01 90.98,60.12 91,60.18 91.01,60.22 91.04,60.29 91.12,60.31 91.19,60.31 91.27,60.32
GND on BOTTOM (solid shape): 16.42,49.97 16.42,46.1 15.15,44.83 15.15,34.98 14.71,34.55 13.7,34.55 13.7,34.83 14.2,35.6 13.5,36.2 5,36.2 4.79,36.29 4.7,36.5 4.7,45.9 4.79,46.11 5,46.2 13.5,46.2 14.2,46.8 13.7,47.57 13.7,47.85 14.59,47.85 14.59,47.85 15.06,47.85 15.4,48.19 15.4,49.97 15.59,50.16 16.23,50.16
GND on BOTTOM (solid shape): 92.53,76.93 92.6,76.9 92.63,76.84 92.67,76.72 92.77,76.63 92.82,76.57 92.81,76.49 92.77,76.37 92.78,76.25 92.79,76.22 92.73,76.16 92.73,76.12 92.65,76.01 92.63,75.87 92.6,75.79 92.52,75.76 92.41,75.75 92.31,75.71 92.27,75.68 92.23,75.64 92.15,75.6 92.07,75.63 91.96,75.73 91.82,75.76 91.81,75.76 91.74,75.8 91.71,75.87 91.71,75.9 91.87,76.06 91.89,76.06 92.18,76.23 92.17,76.56 92.2,76.6 92.24,76.62 92.38,76.72 92.42,76.88 92.42,76.91 92.46,76.95
GND on BOTTOM (solid shape): 5.4,66.25 5.6,65.75 6.1,65.55 6.9,65.55 7.4,65.75 7.6,66.25 7.6,66.75 11.04,66.75 15.27,62.52 15.27,58.83 14.89,58.45 14.17,58.45 14.17,58.45 13.7,58.45 13.7,58.73 14.2,59.5 13.5,60.1 5,60.1 4.79,60.19 4.7,60.4 4.7,64.2 4.5,64.7 4,64.9 0.6,64.9 0.39,64.99 0.3,65.2 0.3,66.45 0.39,66.66 0.6,66.75 5.4,66.75
GND on BOTTOM (solid shape): 74.45,82.98 74.45,82.76 74.42,82.69 74.34,82.66 74.22,82.65 74.12,82.58 74.05,82.55 73.97,82.58 73.95,82.6 73.91,82.67 73.94,82.75 73.7,83.21 73.55,82.72 73.59,82.65 73.56,82.57 73.49,82.4 73.55,82.22 73.56,82.15 73.53,82.08 73.52,82.07 73.45,82.05 73.39,82.07 73.31,82.11 73.21,82.12 73.19,82.12 72.92,82.39 72.93,82.42 72.86,82.73 72.54,82.77 72.44,82.77 72.39,82.86 72.39,83.47 72.5,83.57 73.86,83.57
GND on BOTTOM (solid shape): 11.79,90.42 13.69,90.42 13.94,90.17 13.94,86.67 13.62,86.36 13.62,80.64 13.43,80.45 12.2,80.45 12.2,80.85 12,81.35 11.5,81.55 7.6,81.55 7.6,82.05 7.4,82.55 6.9,82.75 6.1,82.75 5.6,82.55 5.4,82.05 5.4,81.55 0.6,81.55 0.39,81.64 0.3,81.85 0.3,83.35 0.39,83.56 0.6,83.65 2,83.65 2.5,83.85 2.7,84.35 2.7,88.6 2.79,88.81 3,88.9 10.05,88.9 10.75,89.5 10.25,90.27 10.25,91.32 10.89,91.32
GND on BOTTOM (solid shape): 78.88,82.45 79.03,82.39 79.17,82.44 79.23,82.47 79.26,82.38 79.26,82.37 79.26,82.26 79.31,82.16 79.33,82.07 79.26,82 79.05,81.8 79.08,81.51 79.09,81.47 79.07,81.44 78.99,81.36 78.95,81.26 78.9,81.22 78.85,81.22 78.82,81.22 78.57,81.14 78.46,80.9 78.46,80.84 78.39,80.77 78.17,80.77 78.12,80.8 78.1,80.86 77.97,81.13 77.68,81.18 77.59,81.19 77.55,81.26 77.45,81.43 77.18,81.49 77.14,81.56 77.13,81.59 77.12,81.63 77.13,81.73 77.22,81.77 77.39,81.84 77.46,82 77.5,82.09 77.59,82.1 77.68,82.08 77.76,82.1 77.86,82.09 77.9,82 78.13,81.77 78.36,82 78.4,82.09 78.5,82.1 78.74,82.15 78.8,82.39 78.79,82.42 78.85,82.48
GND on BOTTOM (solid shape): 75.2,82.57 75.35,82.41 75.56,82.44 75.62,82.47 75.66,82.38 75.65,82.37 75.76,82.12 76.03,82.14 76.06,82.17 76.12,82.11 76.11,82.08 76.29,81.77 76.55,82.01 76.6,82.09 76.69,82.1 76.78,82.08 76.86,82.1 76.95,82.09 77,82.01 77,81.98 77,81.94 76.98,81.86 76.89,81.83 76.49,81.54 76.81,81.17 76.83,81.17 77.05,80.96 77.05,80.78 76.89,80.63 76.69,80.63 76.56,80.75 76.42,80.75 76.33,80.76 76.25,80.75 76.18,80.76 76.13,80.82 76.1,80.9 76.06,80.97 76.05,81.03 76.08,81.09 76.15,81.51 75.75,81.66 75.74,81.65 75.41,81.65 75.14,81.93 74.62,81.93 74.56,81.87 74.52,81.91 74.49,81.96 74.45,82 74.41,82.09 74.45,82.17 74.49,82.19 74.51,82.22 74.59,82.26 74.67,82.22 75.02,82.18 75.08,82.52 75.07,82.54 75.08,82.59 75.12,82.61 75.19,82.61
GND on BOTTOM (solid shape): outline of 82 points within 93.12,76.06 94.54,79.46
GND on BOTTOM (solid shape): outline of 141 points within 2.55,0.2 228.2,65.02
GND on BOTTOM (solid shape): outline of 693 points within 88.76,72.26 94.78,76.08
GND on BOTTOM (solid shape): outline of 214 points within 73.15,74 77.99,80.23
GND on BOTTOM (solid shape): outline of 821 points within 56.83,57.72 76.36,94.99
GND on BOTTOM (solid shape): outline of 1331 points within 0.2,0.2 228.2,154.2
GND on BOTTOM (solid shape): outline of 1200 points within 83.01,66.39 96.02,71.74
GND on BOTTOM (solid shape): outline of 3366 points within 74.21,74 92.29,82.41
GND on BOTTOM (solid shape): outline of 7874 points within 68.61,58.22 91.99,74.43
GND on BOTTOM (solid shape): outline of 9653 points within 28.81,45.14 44.16,110.99
GND on IN1 (solid shape): 58.58,141.16 46.39,128.96 44.67,128.96 42.83,130.81 36.17,130.81 35.34,129.98 35.09,129.98 35.09,133.35 35.53,133.79 44.48,133.79 45.31,134.62 45.31,136.71 45.82,137.22 50.45,137.22 51.28,138.04 51.28,141.09 51.72,141.54 58.2,141.54 58.2,141.6 58.58,141.6
GND on IN1 (solid shape): 17.51,24.9 17.51,20.46 16.93,19.87 4.7,19.87 4.7,22 4.79,22.21 5,22.3 13.5,22.3 14.2,22.9 13.7,23.67 13.7,23.95 14.16,23.95 14.16,23.95 15.09,23.95 15.43,24.29 15.43,25.97 15.68,26.22 16.19,26.22
GND on IN1 (solid shape): 16.57,50.01 16.57,46.25 15.15,44.83 15.15,34.98 14.71,34.55 13.7,34.55 13.7,34.83 14.2,35.6 13.5,36.2 5,36.2 4.79,36.29 4.7,36.5 4.7,45.9 4.79,46.11 5,46.2 13.5,46.2 14.2,46.8 13.7,47.57 13.7,47.85 14.59,47.85 14.59,47.85 15.06,47.85 15.4,48.19 15.4,49.97 15.59,50.16 16.42,50.16
GND on IN1 (solid shape): 5.4,66.25 5.6,65.75 6.1,65.55 6.9,65.55 7.4,65.75 7.6,66.25 7.6,66.75 11.11,66.75 11.11,66.71 11.13,66.69 11.14,66.69 16.72,61.11 16.72,59.75 17.28,59.19 18.7,59.19 18.83,59.06 18.83,58.54 18.64,58.35 16.65,58.35 16.54,58.45 14.17,58.45 14.17,58.45 13.7,58.45 13.7,58.73 14.2,59.5 13.5,60.1 5,60.1 4.79,60.19 4.7,60.4 4.7,64.2 4.5,64.7 4,64.9 0.6,64.9 0.39,64.99 0.3,65.2 0.3,66.45 0.39,66.66 0.6,66.75 5.4,66.75
GND on IN1 (solid shape): 13.94,91.31 14.7,90.55 14.7,85.72 15.85,84.58 15.85,84.01 15.72,83.88 15.72,80.83 15.34,80.45 13.54,80.45 13.54,80.45 12.2,80.45 12.2,80.85 12,81.35 11.5,81.55 7.6,81.55 7.6,82.05 7.4,82.55 6.9,82.75 6.1,82.75 5.6,82.55 5.4,82.05 5.4,81.55 0.6,81.55 0.39,81.64 0.3,81.85 0.3,83.35 0.39,83.56 0.6,83.65 2,83.65 2.5,83.85 2.7,84.35 2.7,88.6 2.79,88.81 3,88.9 10.05,88.9 10.74,89.48 10.29,90.26 10.25,90.27 10.25,91.32 10.9,91.32 10.9,91.32 13.94,91.32
GND on IN1 (solid shape): outline of 114 points within 2.55,0.2 228.2,64.96
GND on IN1 (solid shape): outline of 1418 points within 0.2,0.2 228.2,154.2
GND on IN2 (solid shape): 17.51,24.9 17.51,20.46 16.93,19.87 4.7,19.87 4.7,22 4.79,22.21 5,22.3 13.5,22.3 14.2,22.9 13.7,23.67 13.7,23.95 15.09,23.95 15.43,24.29 15.43,25.97 15.68,26.22 16.19,26.22
GND on IN2 (solid shape): 16.42,49.97 16.42,46.1 15.15,44.83 15.15,34.98 14.71,34.55 13.7,34.55 13.7,34.83 14.2,35.6 13.5,36.2 5,36.2 4.79,36.29 4.7,36.5 4.7,45.9 4.79,46.11 5,46.2 13.5,46.2 14.2,46.8 13.7,47.57 13.7,47.85 14.59,47.85 14.59,47.85 15.06,47.85 15.4,48.19 15.4,49.97 15.59,50.16 16.23,50.16
GND on IN2 (solid shape): 5.4,66.25 5.6,65.75 6.1,65.55 6.9,65.55 7.4,65.75 7.6,66.25 7.6,66.75 11.04,66.75 16.55,61.24 16.55,61.2 16.7,61.06 16.7,59.8 17.28,59.22 18.64,59.22 18.75,59.1 18.75,58.48 18.63,58.35 17.31,58.35 17.2,58.45 14.17,58.45 14.17,58.45 13.7,58.45 13.7,58.73 14.2,59.5 13.5,60.1 5,60.1 4.79,60.19 4.7,60.4 4.7,64.2 4.5,64.7 4,64.9 0.6,64.9 0.39,64.99 0.3,65.2 0.3,66.45 0.39,66.66 0.6,66.75 5.4,66.75
GND on IN2 (solid shape): 11.79,90.42 13.75,90.42 14,90.17 14,87.37 13.43,86.8 13.43,80.71 13.18,80.45 12.2,80.45 12.2,80.85 12,81.35 11.5,81.55 7.6,81.55 7.6,82.05 7.4,82.55 6.9,82.75 6.1,82.75 5.6,82.55 5.4,82.05 5.4,81.55 0.6,81.55 0.39,81.64 0.3,81.85 0.3,83.35 0.39,83.56 0.6,83.65 2,83.65 2.5,83.85 2.7,84.35 2.7,88.6 2.79,88.81 3,88.9 10.05,88.9 10.75,89.5 10.25,90.27 10.25,91.32 10.89,91.32
GND on IN2 (solid shape): outline of 114 points within 2.55,0.2 228.2,64.96
GND on IN2 (solid shape): outline of 633 points within 29.23,42.81 30.48,85.84
GND on IN2 (solid shape): outline of 292 points within 0.2,0.2 228.2,154.2
GND on VCC: outline of 200 points within 0.2,40.7 118.33,154.2
GND on VCC: 90.56,116.14 90.33,116.37 90.33,120.86 91.07,121.6 93.15,121.6 93.51,121.24 93.51,116.62 93.02,116.14
GND on VCC: 143.14,59.75 142.91,59.98 142.91,63.2 143.78,64.07 147.76,64.07 148.12,63.71 148.12,60.11 147.76,59.75
GND on VCC: outline of 129 points within 0.3,0.2 41.35,66.75
GND on VCC: 62.38,37.71 61.96,38.14 61.96,40.09 62.01,40.14 62.7,40.14 63,40.44 63,41 63.92,41.91 63.92,42.58 63.79,42.71 63.79,43.31 63.89,43.42 64.76,43.42 65.53,44.19 65.59,44.13 65.99,44.13 66.15,43.97 66.15,38.04 65.83,37.71
GND on VCC: 181.18,47.24 181.01,47.41 181.01,51.01 181.11,51.11 183.51,51.11 183.87,50.75 183.87,47.34 183.76,47.24
GND on VCC: 162.65,72.45 162.63,72.47 162.2,72.47 162,72.67 162,78.6 162.09,78.81 162.3,78.9 181.3,78.9 181.8,79.1 182,79.6 182,82.6 182.09,82.81 182.3,82.9 187.3,82.9 187.8,83.1 188,83.6 188,86.1 188.09,86.31 188.3,86.4 228.2,86.4 228.2,78.93 218.24,78.93 217.33,78.02 217.33,72.87 216.91,72.45
GND on VCC: 212.61,42.86 212.38,43.09 212.38,46.18 212.99,46.79 215.32,46.79 216.7,45.42 216.7,43.47 216.08,42.86
GND on VCC: 49.22,32.63 49.12,32.74 49.12,34.43 49.29,34.6 51.62,34.6 51.66,34.56 51.66,32.99 51.3,32.63
GND on VCC: 83.01,116.58 82.71,116.88 82.71,119.08 82.94,119.31 86.67,119.31 86.78,119.21 86.78,116.75 86.61,116.58
GND on VCC: 163.33,56.45 163.23,56.55 163.23,60.53 163.33,60.64 174.17,60.64 174.41,60.41 174.41,58.08 174.3,57.97 168.08,57.97 166.55,56.45
GND on GND: outline of 311 points within 0.2,0.2 228.2,154.2
GNDA on TOP (solid shape): 21.93,15.53 21.4,15.53 21.22,15.71 20.86,15.71 20.68,15.53 20.18,15.53 20.18,17 21.93,17
GNDA on TOP (solid shape): 29.94,10.85 29.94,10.09 29.43,9.58 29.12,9.58 28.99,9.46 28.99,7.96 28.91,7.88 27.82,7.88 27.68,7.74 26.64,7.74 26.58,7.81 26.58,8.69 26.89,9.01 27.4,9.01 27.78,9.39 28.48,9.39 29.75,10.66 29.75,10.85 29.82,10.92 29.88,10.92
GNDA on TOP (solid shape): 26.07,20.19 26.07,19.55 26.39,19.24 27.15,19.24 27.21,19.17 27.21,17.65 26.96,17.39 26.7,17.39 26.58,17.27 26.58,16.44 26.89,16.12 26.89,14.35 26.64,14.09 25.75,14.09 25.69,14.16 25.69,14.85 25.12,15.43 25.12,16.82 23.21,18.73 23.21,19.49 23.28,19.55 24.67,19.55 25.37,20.25 26.01,20.25
GNDA on VCC: 10.35,5.21 10.2,5.27 10,5.3 2.85,5.3 2.64,5.39 2.55,5.6 2.55,8.25 2.64,8.46 2.85,8.55 13.55,8.55 14.25,9.17 13.75,9.92 13.75,15.38 14.25,16.13 13.55,16.75 2.85,16.75 2.64,16.84 2.55,17.05 2.55,18.45 2.64,18.66 2.85,18.75 4,18.75 4.48,18.94 4.7,19.36 14.79,19.36 15.93,18.22 17.54,18.22 18.49,19.17 22.81,19.17 23.32,19.68 24.78,19.68 25.29,20.19 26.11,20.19 26.56,20.63 33.77,20.63 33.94,20.46 33.94,15.66 33.63,15.34 33.63,15.16 33.57,15.11 29.83,15.11 29.56,14.84 29.56,12.81 29.51,12.76 25.95,12.76 25.51,12.31 24,12.31 23.34,11.66 23.34,9.42 23.74,9.01 27.38,9.01 27.76,9.39 28.46,9.39 29.94,10.88 29.94,10.92 30.72,10.92 30.77,10.86 30.77,9.89 30.26,9.38 30.26,8.17 30.13,8.04 30.13,7.97 29.46,7.3 27.83,7.3 27.32,7.81 23.38,7.81 22.24,8.95 17.07,8.95 14.34,6.22 11.36,6.22
GNDA on GND: 10.35,5.21 10.18,5.28 10,5.3 2.85,5.3 2.64,5.39 2.55,5.6 2.55,8.25 2.64,8.46 2.85,8.55 13.55,8.55 14.25,9.15 13.75,9.92 13.75,15.38 14.25,16.15 13.55,16.75 2.85,16.75 2.64,16.84 2.55,17.05 2.55,18.45 2.64,18.66 2.85,18.75 4,18.75 4.47,18.92 4.7,19.36 14.79,19.36 15.93,18.22 17.54,18.22 18.49,19.17 22.81,19.17 23.32,19.68 24.78,19.68 25.29,20.19 26.11,20.19 26.56,20.63 33.77,20.63 33.94,20.46 33.94,15.66 33.63,15.34 33.63,15.16 33.57,15.11 29.83,15.11 29.56,14.84 29.56,12.81 29.51,12.76 25.95,12.76 25.51,12.31 24,12.31 23.34,11.66 23.34,9.42 23.74,9.01 27.38,9.01 27.76,9.39 28.46,9.39 29.94,10.88 29.94,10.92 30.72,10.92 30.77,10.86 30.77,9.89 30.26,9.38 30.26,8.17 30.13,8.04 30.13,7.97 29.46,7.3 27.83,7.3 27.32,7.81 23.38,7.81 22.24,8.95 17.07,8.95 14.34,6.22 11.36,6.22
VBAT on BOTTOM (solid shape): 198.1,48.65 199.22,48.65 199.32,48.55 199.32,47.02 199.25,46.95 198.13,46.95 198.01,47.06 198.01,48.41 197.91,48.52 197.9,48.53 197.85,48.6 197.77,48.66 197.76,48.66 197.7,48.73 196.93,48.73 196.91,48.75 196.91,48.93 196.93,48.95 197.8,48.95
VCCGI_N18 on BOTTOM (solid shape): 96.38,135.64 96.38,134.76 95.86,134.23 95,134.23 94.8,134.03 94.8,133.51 94.75,133.46 92.19,133.46 92.01,133.64 92.01,134.53 92.15,134.67 92.15,134.67 93.82,134.67 93.82,134.68 95.67,134.68 95.69,134.65 95.97,134.65 96.15,134.83 96.15,135.64 96.2,135.69 96.33,135.69
VDD_1.2V on TOP (solid shape): 22.32,120.45 22.32,118.77 23.01,118.08 23.74,118.08 23.82,118 23.82,117.85 23.74,117.78 22.55,117.78 22.28,118.04 21.18,118.04 21.05,118.17 21.05,120.58 21.18,120.71 22.07,120.71
VDD_CHG on TOP (solid shape): 194.93,55.05 194.93,53.5 194.22,52.79 193.66,52.79 193.58,52.87 193.58,53.22 193.68,53.32 194.06,53.32 194.17,53.42 194.17,54.21 194.17,54.34 194.06,54.44 193.51,54.44 193.43,54.52 193.43,54.61 193.44,54.62 193.48,54.8 193.44,54.97 193.43,54.98 193.43,55.15 193.48,55.2 194.78,55.2
VDD_CHG on BOTTOM (solid shape): 194.19,54.13 194.19,53.17 194.39,52.97 194.39,51.52 194.34,51.47 194.27,51.47 194.22,51.52 194.22,52.64 194.09,52.76 192.95,52.76 192.69,53.02 192.69,53.72 192.76,53.78 193.35,53.78 193.46,53.88 193.46,54.07 193.55,54.17 194.16,54.17
VDDP_1.2V on TOP (solid shape): 22.53,117.6 23.77,117.6 23.82,117.55 23.82,117.42 23.77,117.37 22.35,117.37 22.26,117.28 22.2,117.28 22.07,117.15 21.24,117.15 21.12,117.28 21.12,117.79 21.18,117.85 22.27,117.85
VDDP_CHG on BOTTOM (solid shape): 194.03,48.13 194.03,47.43 193.52,46.92 192.44,46.92 191.55,46.03 191.55,45.08 191.49,45.02 190.03,45.02 189.96,45.08 189.96,45.72 191.11,46.86 191.61,46.86 191.99,47.24 193.39,47.24 193.77,47.62 193.77,48.13 193.84,48.19 193.96,48.19
VDDREG on TOP (solid shape): 19.85,89.28 19.85,88.26 20.23,87.88 20.42,87.88 21.3,87 21.3,86.43 21.29,86.42 21.29,85.66 21.24,85.61 21.14,85.61 21.09,85.66 21.09,86.47 20.7,86.86 19.78,86.86 19.02,87.63 19.02,89.21 19.15,89.34 19.78,89.34
+DCBAT_LCD on TOP (solid shape): 210.54,58.8 210.54,57.59 210.41,57.46 208.63,57.46 208.19,57.02 207.63,57.02 207.5,57.15 207.5,58.86 207.63,58.99 210.35,58.99
+DCBAT_LCD on BOTTOM (solid shape): 212.95,60.51 212.95,59.37 212.89,59.3 211.93,59.3 211.68,59.05 211.68,57.15 211.36,56.83 209.27,56.83 209.21,56.88 209.21,59.15 210.35,59.76 211.3,60.64 212.82,60.64
+EC_VCCA on BOTTOM (solid shape): 119.13,39.66 119.13,39.58 119.06,39.51 117.41,39.51 116.76,38.86 115.29,38.86 115.22,38.92 115.22,39.66 115.25,39.68 115.68,39.68 115.83,39.53 116.9,39.53 117.1,39.73 119.06,39.73
+FP_VCC on TOP (solid shape): 218.16,29.78 218.16,29.46 217.97,29.27 217.97,27.36 217.84,27.24 216.38,27.24 216.25,27.36 216.25,29.71 216.44,29.9 218.03,29.9
+FP_VCC on BOTTOM (solid shape): 218.06,31.2 218.06,30.42 218.16,30.32 218.16,29.46 218.03,29.33 217.14,29.33 217.08,29.4 217.08,31.24 217.14,31.3 217.96,31.3
+LAN_VDD33 on TOP (solid shape): 18.45,89.28 18.45,88.45 18.2,88.2 17.56,88.2 17.24,87.88 15.66,87.88 15.46,88.07 15.46,89.15 15.66,89.34 18.39,89.34
+LAN_VDD33 on TOP (solid shape): 20.51,82.6 20.51,82.39 19.47,81.34 19.46,81.34 19.38,81.28 19.32,81.19 19.31,81.19 19.21,81.08 19.21,77.72 19.08,77.59 18.2,77.59 18,77.78 18,81.34 18.07,81.4 18.77,81.4 18.98,81.62 19.06,81.62 19.06,81.7 19.15,81.78 19.15,82.04 19.77,82.66 20.46,82.66
+LAN_VDD33 on TOP (solid shape): 26.81,83.94 26.92,83.86 27.05,83.84 27.16,83.85 27.26,83.9 27.47,83.69 27.47,82.93 27.4,82.86 25.62,82.86 25.24,83.24 23.85,83.24 23.78,83.31 23.78,83.37 23.85,83.43 25.11,83.43 25.62,83.94
+LAN_VDD33 on BOTTOM (solid shape): outline of 113 points within 15.21,78.61 19.21,89.47
+LAN_VDD33 on IN2 (solid shape): 26.61,83.85 26.61,83.24 26.39,83.02 25.55,83.02 25.01,82.48 24.79,82.48 24.37,82.9 24.37,83.29 25.05,83.97 26.48,83.97
+LAN_VDD33 on IN2 (solid shape): 19.4,82.16 19.4,81.4 19.26,81.26 19.26,79.75 19.2,79.69 18.82,79.69 18.56,79.94 18.56,82.1 18.75,82.29 19.27,82.29
+LCDVDD on TOP (solid shape): 219.36,56.95 219.36,55.75 218.66,55.05 217.01,55.05 216.89,55.18 216.89,57.02 217.01,57.15 219.17,57.15
+LCDVDD_LCD on TOP (solid shape): 216.44,57.97 216.44,55.24 216.32,55.11 215.36,55.11 213.39,57.08 213.39,58.03 213.52,58.16 216.25,58.16
+LCDVDD_LCD on BOTTOM (solid shape): 215.24,57.59 215.24,56.45 215.11,56.32 213.39,56.32 212.95,56.76 211.93,56.76 211.81,56.89 211.81,57.53 211.87,57.59 212.95,57.59 213.14,57.78 215.05,57.78
+MIC2-VREFO on TOP (solid shape): 20.68,14.23 20.68,13.72 20.04,13.08 19.27,13.08 19.08,13.27 19.08,14.22 19.15,14.28 20.63,14.28
+RTC_CELL on IN1 (solid shape): outline of 407 points within 88.83,65.22 95.05,66.58
+TP_VDD on BOTTOM (solid shape): 116.82,32.68 117.83,32.68 117.98,32.54 117.98,31.89 118.38,31.49 118.38,29.98 118.19,29.79 117.77,29.79 117.58,29.99 117.58,30.93 116.97,31.54 115.53,31.54 114.17,30.18 114.17,29.11 114.13,29.07 113.51,29.07 113.45,29.13 113.45,31.65 113.16,31.94 113.16,32.84 113.53,33.21 116.29,33.21
+TPAN_VDD on TOP (solid shape): 222.93,43.56 222.93,41.79 222.7,41.56 221.71,41.56 221.45,41.82 221.45,43.39 221.68,43.62 222.87,43.62
+TPAN_VDD on TOP (solid shape): 213.46,40.55 213.46,39.49 213.35,39.38 211.4,39.38 211.04,39.74 211.04,40.6 211.14,40.7 213.3,40.7
+TPAN_VDD on BOTTOM (solid shape): 213.18,40.76 213.18,40 213.05,39.87 211.16,39.87 211.06,39.96 211.06,40.96 211.21,41.11 212.84,41.11
+TPAN_VDD on BOTTOM (solid shape): 222.35,42.57 222.35,40.99 221.7,40.33 221.45,40.33 220.88,40.9 220.88,41.02 221.28,41.42 221.28,42.35 221.63,42.7 222.22,42.7
+TPAN_VDD_OUT on TOP (solid shape): 223.21,46.11 223.21,44.48 223.02,44.29 221.68,44.29 221.36,44.61 221.36,46.26 221.58,46.48 222.83,46.48
+VNN on TOP (solid shape): 84.68,75.37 84.68,74.62 84.55,74.49 84.07,74.49 83.9,74.33 83.5,74.33 83.4,74.43 83.4,75.42 83.5,75.52 84.53,75.52
+VNN on TOP (solid shape): 89.12,111.95 89.12,109.15 88.93,108.96 81.82,108.96 81.63,109.15 81.63,112.39 81.82,112.58 88.49,112.58
+VNN on TOP (solid shape): 84.02,70.67 84.03,70.65 84.11,70.51 84.26,70.42 84.27,70.42 84.32,70.37 84.32,69.65 84.17,69.5 83.3,69.5 83.19,69.6 81.44,69.6 81.21,69.83 81.21,70.06 81.18,70.1 80.49,70.1 80.43,70.16 80.43,70.9 80.55,71.03 83.66,71.03
+VNN on TOP (solid shape): outline of 333 points within 77.57,78.65 85.19,99.12
+VNN on BOTTOM (solid shape): 82.2,114.17 85,114.17 85.06,114.1 85.06,113.15 85.12,113.09 85.89,113.09 85.95,113.15 85.95,114.04 86.08,114.17 88.74,114.17 89.12,113.79 89.12,109.15 89,109.02 81.89,109.02 81.63,109.28 81.63,113.91 82.01,114.3 82.08,114.3
+VNN on BOTTOM (solid shape): 83.74,75.5 83.86,75.3 83.76,75.11 83.7,75.07 83.7,75.02 83.7,75.02 83.7,74.8 84.19,74.31 84.19,74.27 84.21,74.25 84.21,74.1 84.13,74.04 84.1,74 83.92,74 83.08,74.84 83.08,75.07 83.55,75.54 83.65,75.54
+VNN on BOTTOM (solid shape): 82.25,80.7 82.33,80.66 82.35,80.58 82.54,80.26 82.84,80.47 82.88,80.54 82.96,80.55 82.99,80.55 83.02,80.53 83.66,79.88 83.66,79.05 83.54,78.93 82.42,78.93 82.3,79.03 82.15,79.06 82.13,79.06 81.44,79.75 81.44,80.58 81.57,80.7
+VNN on BOTTOM (solid shape): 81.35,71.11 81.57,71.11 81.63,71.17 81.68,71.2 81.71,71.22 81.74,71.24 81.76,71.27 81.81,71.3 81.86,71.3 82.03,71.13 82.33,71.13 82.49,71.29 82.55,71.31 82.62,71.28 82.75,71.14 83.04,71.14 83.19,71.29 83.33,71.29 83.43,71.2 83.52,71.16 83.53,71.16 83.87,70.82 83.87,70.64 83.78,70.57 83.74,70.52 83.38,70.16 83.21,70.16 83.16,70.22 83.09,70.28 83.02,70.31 82.77,70.31 82.58,70.15 82.58,70.14 82.45,70.01 81.08,70.01 80.81,70.28 80.81,71.18 80.99,71.36 81.1,71.36
+VNN on IN1 (solid shape): outline of 2880 points within 80.99,69.59 89.55,103.68
+VNN on IN2 (solid shape): 83.98,75.43 83.98,70.04 83.66,69.72 81.67,69.72 81.25,70.13 81.25,71.15 81.3,71.18 81.36,71.17 81.58,71.16 81.76,71.27 81.84,71.3 81.92,71.26 82.31,71.16 82.55,71.5 82.54,71.52 82.95,71.92 82.96,71.92 83.26,72.21 83.09,72.58 83.09,72.71 83.28,73.03 83.09,73.34 83.09,73.5 83.26,73.8 83.09,74.11 83.09,74.25 83.25,74.55 83.09,74.85 83.09,75.43 83.28,75.62 83.79,75.62
+VNN on VCC: 77.56,68.26 77.31,68.5 77.31,71.38 78.65,72.71 78.65,73.73 79.09,74.17 79.09,75.95 79.27,76.13 81.43,76.13 82.08,76.78 82.08,82.85 79.79,85.14 79.79,87.46 79.92,87.58 79.92,87.79 76.55,91.16 76.55,93.51 74.46,95.6 74.46,99.59 74.96,100.09 74.96,102.91 74.46,103.42 74.46,115.52 75.01,116.07 86.61,116.07 86.78,115.9 86.78,115.51 88.87,113.42 88.87,110.08 86.97,108.18 86.97,82.44 87.09,82.31 87.09,78.92 83.98,75.8 83.98,74.53 83.74,74.29 81.32,74.29 81,73.96 81,71.7 81.32,71.37 83.93,71.37 84.17,71.13 84.17,68.44 83.99,68.26
ACIN_CHG on TOP (solid shape): 192.08,52.69 192.08,52.21 192.21,52.08 192.77,52.08 192.87,51.98 192.87,51.54 192.74,51.42 192.08,51.42 191.96,51.29 191.96,49.67 191.27,48.98 190.2,48.98 190,49.18 190,49.92 190.18,50.1 190.69,50.1 191.06,50.46 191.06,51.12 191.3,51.36 191.3,52.81 191.37,52.89 191.88,52.89
ACIN_CHG on BOTTOM (solid shape): 193.51,51.34 193.63,51.34 193.68,51.29 193.68,51.19 193.63,51.14 192.8,51.14 192.36,51.58 192.36,51.93 192.44,52 192.85,52
ASGATE on BOTTOM (solid shape): 194.41,48.13 194.41,47.24 193.39,46.22 192.82,46.22 192.44,45.84 192.44,45.08 192.31,44.95 191.8,44.95 191.74,45.02 191.74,45.91 192.63,46.79 193.58,46.79 194.22,47.43 194.22,48.13 194.28,48.19 194.34,48.19
AUD_SPK_L+ on TOP (solid shape): 29.56,5.9 29.56,5.39 29.43,5.27 27.85,5.27 27.85,6.03 29.43,6.03
AUD_SPK_L+ on TOP (solid shape): 31.56,10.85 31.56,10.04 31.61,9.99 31.61,9.38 31.43,9.2 31.43,8.31 31.35,8.24 31.02,8.24 30.95,8.31 30.95,9.18 31.35,9.58 31.35,10.85 31.4,10.9 31.5,10.9
AUD_SPK_L+ on BOTTOM (solid shape): 31.4,9.2 31.4,8.5 31.66,8.25 31.66,7.02 29.78,5.14 28.61,5.14 28.48,5.27 28.48,5.9 28.61,6.03 29.22,6.03 29.56,6.37 29.56,6.54 30.7,7.68 30.7,8 30.64,8.06 30.64,9.2 30.77,9.33 31.28,9.33
AUD_SPK_L+_C on TOP (solid shape): 27.28,6.03 27.59,6.03 27.59,5.27 26.2,5.27 26.13,5.33 26.13,5.77 25.43,6.47 22.64,6.47 22.39,6.22 17.69,6.22 17.43,5.96 17.12,5.96 14.96,3.81 14.26,3.81 14.13,3.93 14.13,4.76 14.32,4.95 14.7,4.95 16.67,6.92 17.43,6.92 17.88,7.36 25.94,7.36
AUD_SPK_L+_C on BOTTOM (solid shape): 14.7,6.54 14.7,3.93 14.58,3.81 14.19,3.81 14.07,3.93 14.07,6.54 14.19,6.66 14.58,6.66
AUD_SPK_L- on TOP (solid shape): 29.56,4.63 29.56,4.12 29.43,4 27.85,4 27.85,4.76 29.43,4.76
AUD_SPK_L- on TOP (solid shape): 31.96,10.85 31.96,10.02 32.01,9.96 32.01,9.25 32.06,9.2 32.06,8.69 32.17,8.59 32.17,8.31 32.09,8.24 31.66,8.24 31.58,8.31 31.58,9.15 31.73,9.3 31.73,9.99 31.76,10.02 31.76,10.85 31.81,10.9 31.91,10.9
AUD_SPK_L- on IN2 (solid shape): 32.09,9.25 32.09,8.77 32.29,8.57 32.29,5.8 30.49,4 28.61,4 28.48,4.12 28.48,4.69 28.61,4.82 29.89,4.82 31.51,6.44 31.51,8.14 31.56,8.19 31.56,9.23 31.66,9.33 32.01,9.33
AUD_SPK_L-_C on TOP (solid shape): 22.64,5.08 27.34,5.08 27.59,4.82 27.59,4 27.02,4 26.83,4.19 21.31,4.19 20.54,4.95 18.83,4.95 18.51,5.27 18.2,5.27 14.7,1.77 14.26,1.77 14.13,1.9 14.13,2.85 14.19,2.92 14.45,2.92 17.24,5.71 17.56,5.71 17.75,5.9 21.81,5.9
AUD_SPK_L-_C on BOTTOM (solid shape): 13.75,6.47 13.75,3.55 14.39,2.92 14.51,2.92 14.64,2.79 14.64,1.9 14.51,1.77 14.19,1.77 12.86,3.11 12.86,6.41 13.12,6.66 13.56,6.66
AUD_SPK_R+ on TOP (solid shape): 25.37,1.96 25.37,1.33 25.24,1.2 23.72,1.2 23.66,1.27 23.66,2.03 23.72,2.09 25.24,2.09
AUD_SPK_R+ on TOP (solid shape): 32.77,10.85 32.77,9.91 33.56,9.13 33.56,8.62 33.46,8.52 33.13,8.52 33.05,8.59 33.05,8.95 32.83,9.18 32.83,9.41 32.52,9.71 32.52,9.99 32.55,10.02 32.55,10.85 32.6,10.9 32.72,10.9
AUD_SPK_R+ on IN2 (solid shape): 34.9,9.19 34.9,6.54 33.64,5.28 33.64,4.5 30.31,1.18 24.45,1.18 24.32,1.3 24.32,2.06 24.45,2.19 29.93,2.19 32.62,4.88 32.62,6.36 33.88,7.62 33.88,8.25 33.69,8.44 33.18,8.44 33.1,8.52 33.1,8.9 32.83,9.18 32.83,9.41 32.93,9.51 34.58,9.51
AUD_SPK_R+_C on TOP (solid shape): 20.54,2.15 23.37,2.15 23.41,2.11 23.41,1.25 23.36,1.2 18.89,1.2 18.45,1.65 18.45,2.92 18.64,3.11 19.59,3.11
AUD_SPK_R+_C on BOTTOM (solid shape): 19.78,6.09 19.78,2.73 19.66,2.6 18.83,2.6 18.7,2.73 18.7,5.08 18.51,5.27 18.07,5.27 17.88,5.08 16.35,5.08 16.1,5.33 16.1,6.47 16.61,6.98 18.89,6.98
AUD_SPK_R- on TOP (solid shape): 27.45,2.98 27.45,2.41 27.33,2.28 25.8,2.28 25.74,2.34 25.74,3.16 25.77,3.18 27.25,3.18
AUD_SPK_R- on TOP (solid shape): 32.37,10.85 32.37,10.02 32.39,9.99 32.39,9.63 32.7,9.33 32.7,9.1 32.93,8.87 32.93,8.42 32.83,8.31 32.47,8.31 32.39,8.39 32.39,8.64 32.24,8.8 32.24,9.28 32.14,9.38 32.14,10.85 32.19,10.9 32.32,10.9
AUD_SPK_R- on BOTTOM (solid shape): 32.7,9.23 32.7,9.1 32.95,8.85 32.95,8.59 33.08,8.47 33.08,6.61 31.35,4.88 31.35,4.05 29.5,2.19 26.6,2.19 26.4,2.39 26.4,3.05 26.51,3.16 29.04,3.16 30.34,4.45 30.34,5.29 32.1,7.06 32.1,8.01 32.34,8.25 32.34,8.69 32.22,8.82 32.22,9.23 32.32,9.33 32.6,9.33
AUD_SPK_R-_C on TOP (solid shape): 20.93,3.93 24.8,3.93 25.5,3.23 25.5,2.49 25.44,2.43 23.19,2.43 23.15,2.47 23.15,3.04 23.02,3.17 20.04,3.17 19.85,3.36 18.07,3.36 17.94,3.49 17.94,4.38 18.07,4.5 20.35,4.5
AUD_SPK_R-_C on BOTTOM (solid shape): 15.72,6.54 15.72,5.14 16.35,4.5 18.39,4.5 18.45,4.44 18.45,3.42 18.32,3.3 16.16,3.3 15.08,4.38 15.08,6.54 15.21,6.66 15.59,6.66
BST_1.2V on TOP (solid shape): 25.04,115.95 25.04,115.08 25.07,115.06 25.07,114.3 25.18,114.18 25.18,113.22 24.93,112.96 23.4,112.96 23.34,113.03 23.34,113.66 23.4,113.72 24.52,113.72 24.76,113.96 24.76,115.06 24.81,115.11 24.81,115.95 24.86,116 24.99,116
BST_1.2V_R on TOP (solid shape): 23.28,112.64 24.35,112.64 24.46,112.54 24.46,111.69 24.39,111.62 22.86,111.62 22.45,112.03 22.45,112.83 22.51,112.9 23.02,112.9
BST_1.05V on BOTTOM (solid shape): 148.62,61.34 148.62,60.96 148.33,60.66 148.33,60.29 147.74,59.7 146.47,59.7 146.39,59.77 146.39,60.38 146.48,60.47 147.14,60.47 147.28,60.61 147.28,61.08 147.6,61.4 148.56,61.4
BST_1.05V_R on BOTTOM (solid shape): 147.2,62.06 147.2,61.48 147.1,61.37 147.1,60.71 147.02,60.64 146.49,60.64 146.44,60.69 146.44,62.03 146.49,62.09 147.18,62.09
BST_3V on BOTTOM (solid shape): 167.23,62.03 167.23,61.02 167.04,60.83 167.04,59.56 166.98,59.49 166.85,59.49 166.79,59.56 166.79,60.51 166.47,60.83 166.47,62.03 166.53,62.1 167.17,62.1
BST_3V_R on BOTTOM (solid shape): 165.82,62.37 165.82,61.08 165.13,61.08 165.07,61.15 165.07,61.65 164.94,61.78 164.25,61.78 164.12,61.91 164.12,62.42 164.25,62.54 165.64,62.54
BST_5V on BOTTOM (solid shape): 206.51,78.37 206.51,77.63 207.2,76.94 207.2,76.36 207.12,76.28 206.23,76.28 206.18,76.34 206.18,77.05 206.23,77.1 206.23,78.37 206.28,78.42 206.46,78.42
BST_5V_R on BOTTOM (solid shape): 208.12,74.99 208.03,74.89 206.25,74.89 206.19,74.96 206.19,75.52 206.23,75.57 207.07,75.57 207.5,76 208.12,76
BST_CHG on BOTTOM (solid shape): 190.15,49.27 190.15,47.18 190.03,47.05 189.45,47.05 189.39,47.11 189.39,49.27 189.45,49.33 190.09,49.33
BST_CHG_R on BOTTOM (solid shape): 193.66,49.69 193.66,49.59 193.61,49.54 192.16,49.54 191.55,48.93 191.55,48.42 191.5,48.37 190.89,48.37 190.84,48.42 190.84,49.36 190.92,49.44 191.65,49.44 191.98,49.77 193.58,49.77
BST_VCCGI on BOTTOM (solid shape): 98.76,135.26 100.24,135.26 101.2,134.3 101.2,132.01 100.56,132.01 100.56,134.04 100.05,134.55 98.46,134.55 98.15,134.86 98.15,135.64 98.21,135.69 98.33,135.69
BST_VCCGI_R on BOTTOM (solid shape): 99.78,132.01 98.38,132.01 98.28,132.11 98.28,132.75 98.43,132.9 99.78,132.9
BST_VNN on BOTTOM (solid shape): 88.19,130.15 88.52,130.15 88.69,129.98 88.69,129.32 88.58,129.21 87.8,129.21 87.78,129.23 87.78,129.87 87.41,130.23 87.09,130.23 86.79,130.54 86.79,131.33 86.84,131.38 86.97,131.38
BST_VNN_R on BOTTOM (solid shape): 88.74,128.52 88.74,127.88 88.68,127.82 87.01,127.82 86.91,127.92 86.91,128.56 87.06,128.71 88.55,128.71
DCIN_CHG on BOTTOM (solid shape): 190.61,55.16 190.61,54.82 190.79,54.64 192.34,54.64 192.44,54.54 192.44,53.08 192.95,52.57 193.77,52.57 193.99,52.36 193.99,51.54 193.94,51.49 193.84,51.49 193.18,52.15 192.72,52.15 191.14,53.73 190.58,53.73 190.58,53.72 190.32,53.72 190.3,53.73 189.75,53.73 189.71,53.78 189.71,55.18 189.77,55.24 190.53,55.24
ECAGND on BOTTOM (solid shape): 116.73,40.52 119.11,40.52 119.16,40.47 119.16,40.38 119.1,40.32 117.32,40.32 117.06,40.06 117.06,39.94 116.87,39.75 115.99,39.75 115.67,40.06 115.22,40.06 115.22,40.83 116.43,40.83
HPOUT_L on TOP (solid shape): 14.26,7.49 14.26,7.42 13.94,7.11 11.97,7.11 11.72,7.36 11.72,8.24 11.92,8.44 13.31,8.44
JACK_PLUG on IN2 (solid shape): 13.57,18.17 13.57,17.08 13.39,16.9 11.92,16.9 11.77,17.05 11.77,18.14 11.9,18.27 13.47,18.27
JACK_PLUG_DET on TOP (solid shape): 10.91,18.22 10.91,17.05 10.75,16.9 9.2,16.9 9.05,17.05 9.05,18.07 9.25,18.27 10.85,18.27
LG_1.2V on BOTTOM (solid shape): 24.16,103.31 24.16,102.74 23.97,102.55 23.66,102.55 23.4,102.29 23.21,102.29 23.02,102.48 23.02,103.37 23.08,103.44 24.04,103.44
LG_1.2V on IN2 (solid shape): 23.59,103.25 23.59,102.48 23.4,102.29 22.32,102.29 21.88,102.74 21.88,103.18 22.2,103.5 23.34,103.5
LG_1.2V on IN2 (solid shape): 23.66,116.14 23.66,115.72 23.55,115.62 22.65,115.62 22.58,115.69 22.2,115.69 21.88,115.37 21.37,115.37 21.24,115.5 21.24,116.01 21.5,116.26 23.53,116.26
LG_CHG on BOTTOM (solid shape): 187.17,46.73 187.17,46.35 187.04,46.22 185.07,46.22 184.95,46.35 184.95,46.79 185.01,46.86 187.04,46.86
LG_CHG on IN2 (solid shape): 193.63,48.12 193.63,47.23 193.48,47.07 192.67,47.07 192.52,47.23 192.52,48.19 192.59,48.27 193.48,48.27
LG_CHG on IN2 (solid shape): 187.56,46.74 187.56,46.21 187.51,46.16 186.22,46.16 186.09,46.29 186.09,46.72 186.22,46.85 187.46,46.85
LG_VCCGI on BOTTOM (solid shape): 96.62,124.07 96.62,122.99 96.43,122.8 95.41,122.8 95.22,122.99 95.22,124.07 95.41,124.26 96.43,124.26
LG_VCCGI on BOTTOM (solid shape): 97.16,135.64 97.16,134.78 97.21,134.73 97.21,133.26 97.14,133.18 96.81,133.18 96.73,133.26 96.73,134.25 96.94,134.45 96.94,134.76 96.96,134.78 96.96,135.64 97.01,135.69 97.11,135.69
LG_VCCGI on IN2 (solid shape): 97.2,124.95 97.2,123.03 97,122.83 95.99,122.83 95.91,122.9 95.91,124.96 96.27,125.32 96.83,125.32
LG_VCCGI on IN2 (solid shape): 97.25,134.13 97.25,131.88 97,131.63 96.05,131.63 95.67,132.01 95.67,132.72 95.67,132.75 95.68,132.81 95.67,132.87 95.67,132.91 95.67,133 95.92,133 95.92,132.95 95.93,132.9 95.94,132.85 95.97,132.8 96,132.75 96.03,132.72 96.07,132.68 96.12,132.66 96.17,132.64 96.22,132.62 96.27,132.62 96.33,132.62 96.38,132.64 96.43,132.66 96.48,132.68 96.52,132.72 96.55,132.75 96.58,132.8 96.61,132.85 96.62,132.9 96.63,132.95 96.63,133 96.62,133.06 96.61,133.11 96.58,133.16 96.55,133.2 96.52,133.24 96.48,133.27 96.43,133.3 96.38,133.32 96.33,133.33 96.27,133.33 96.22,133.33 96.17,133.32 96.12,133.3 96.07,133.27 96.03,133.24 96,133.2 95.97,133.16 95.94,133.11 95.93,133.06 95.92,133 95.67,133 95.67,134.07 95.83,134.24 96.08,134.24 96.09,134.24 97.14,134.24
LG_VNN on BOTTOM (solid shape): 84.78,122.61 84.78,122.41 84.58,122.21 84.58,121.88 84.43,121.72 83.84,121.72 83.74,121.83 83.74,122.64 83.84,122.74 84.65,122.74
